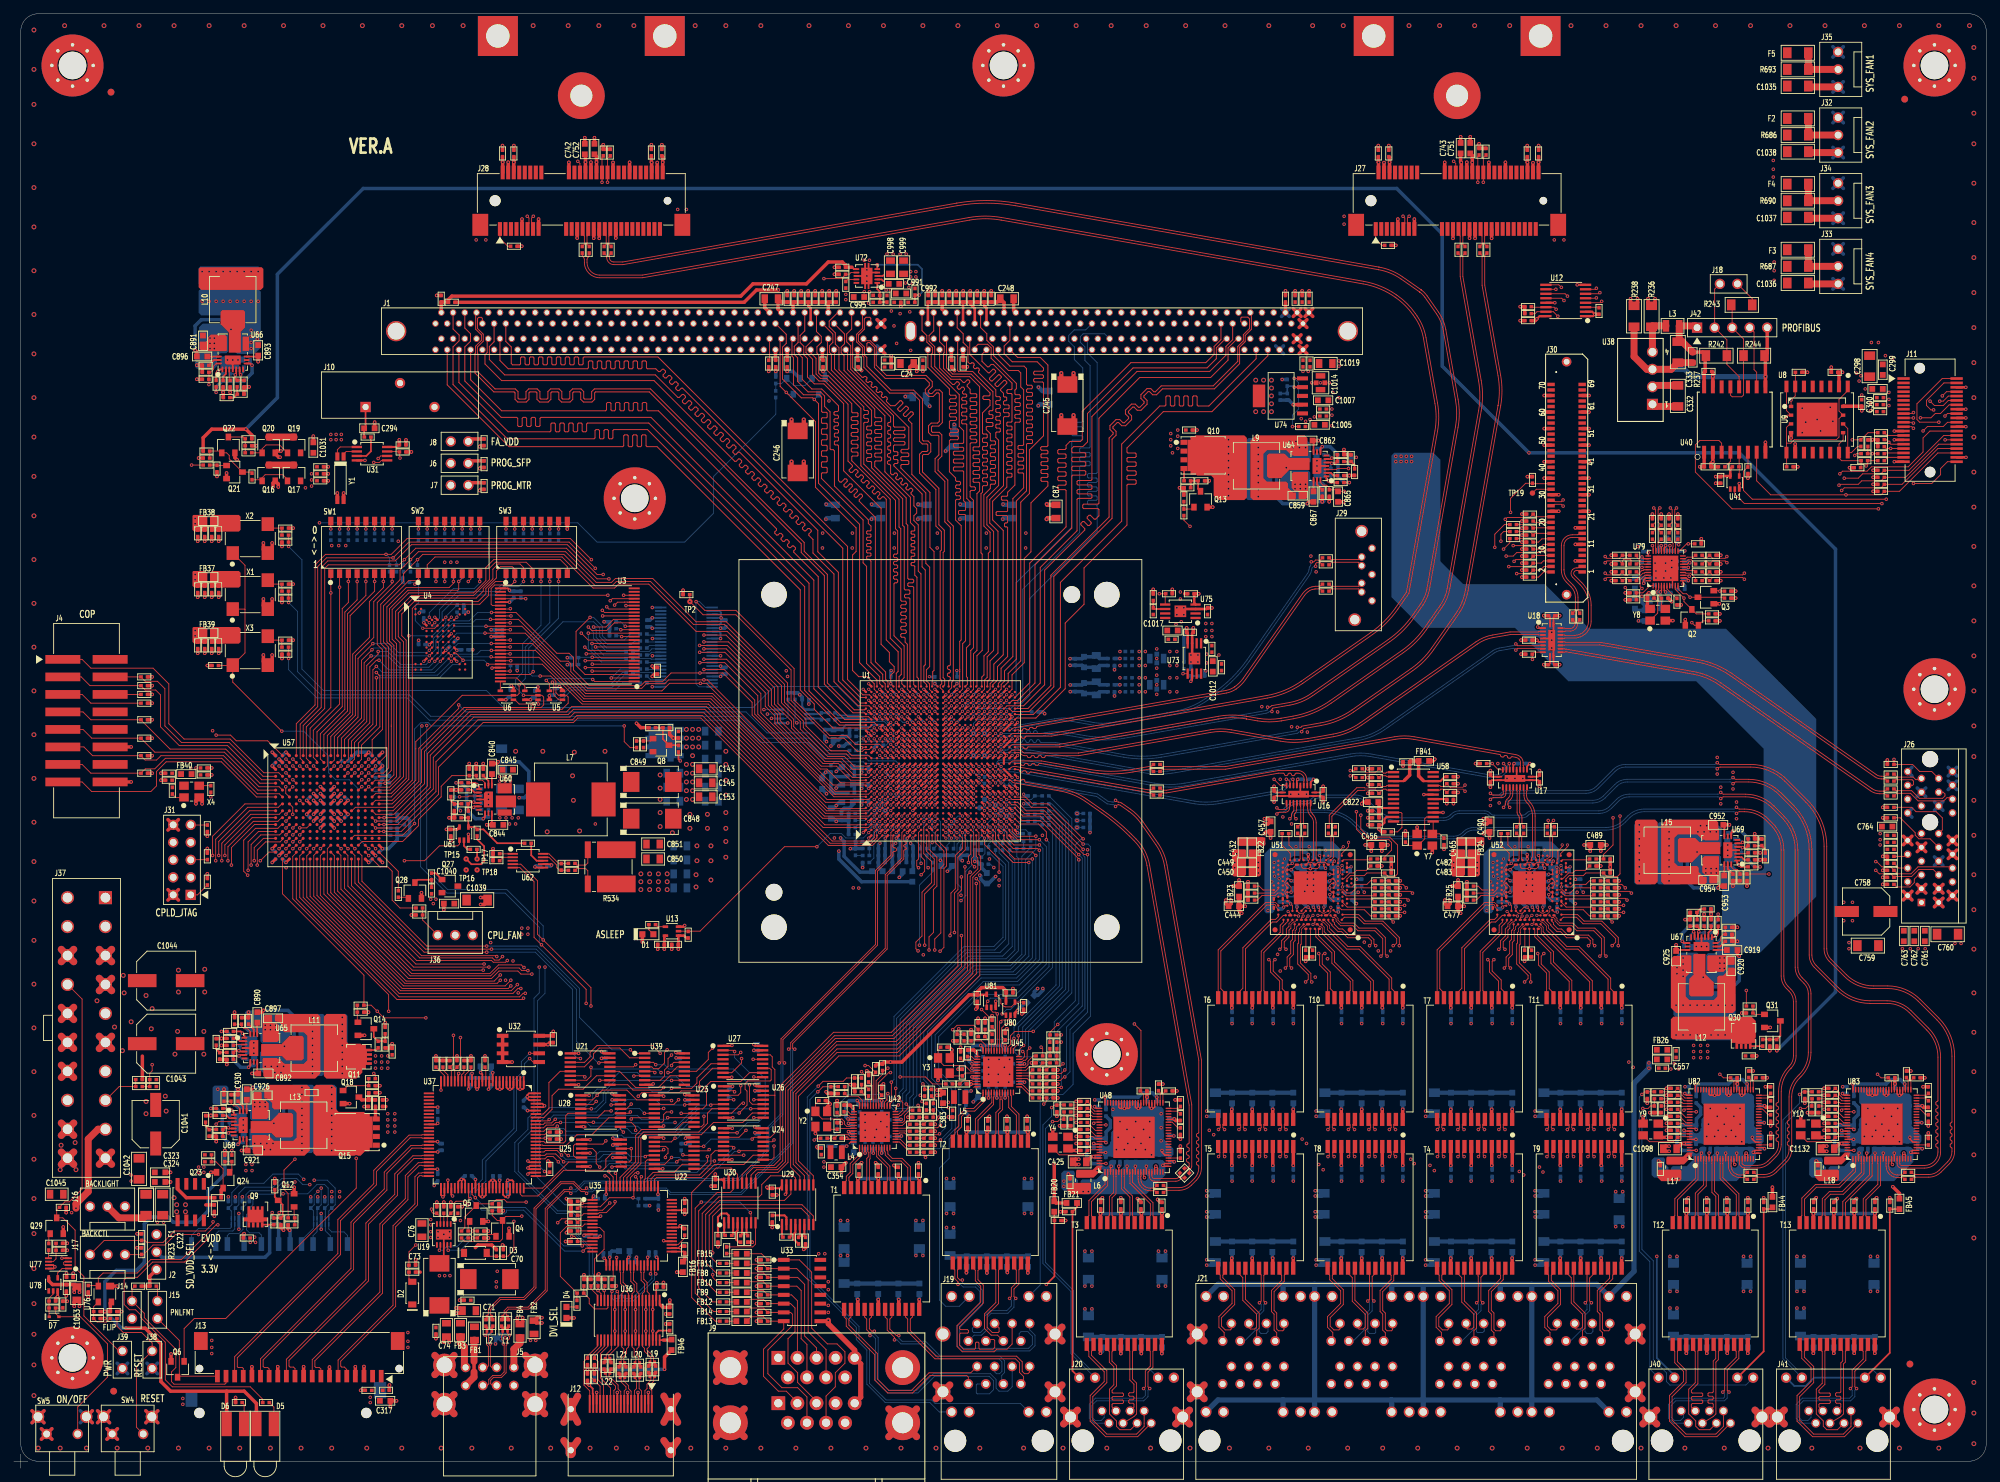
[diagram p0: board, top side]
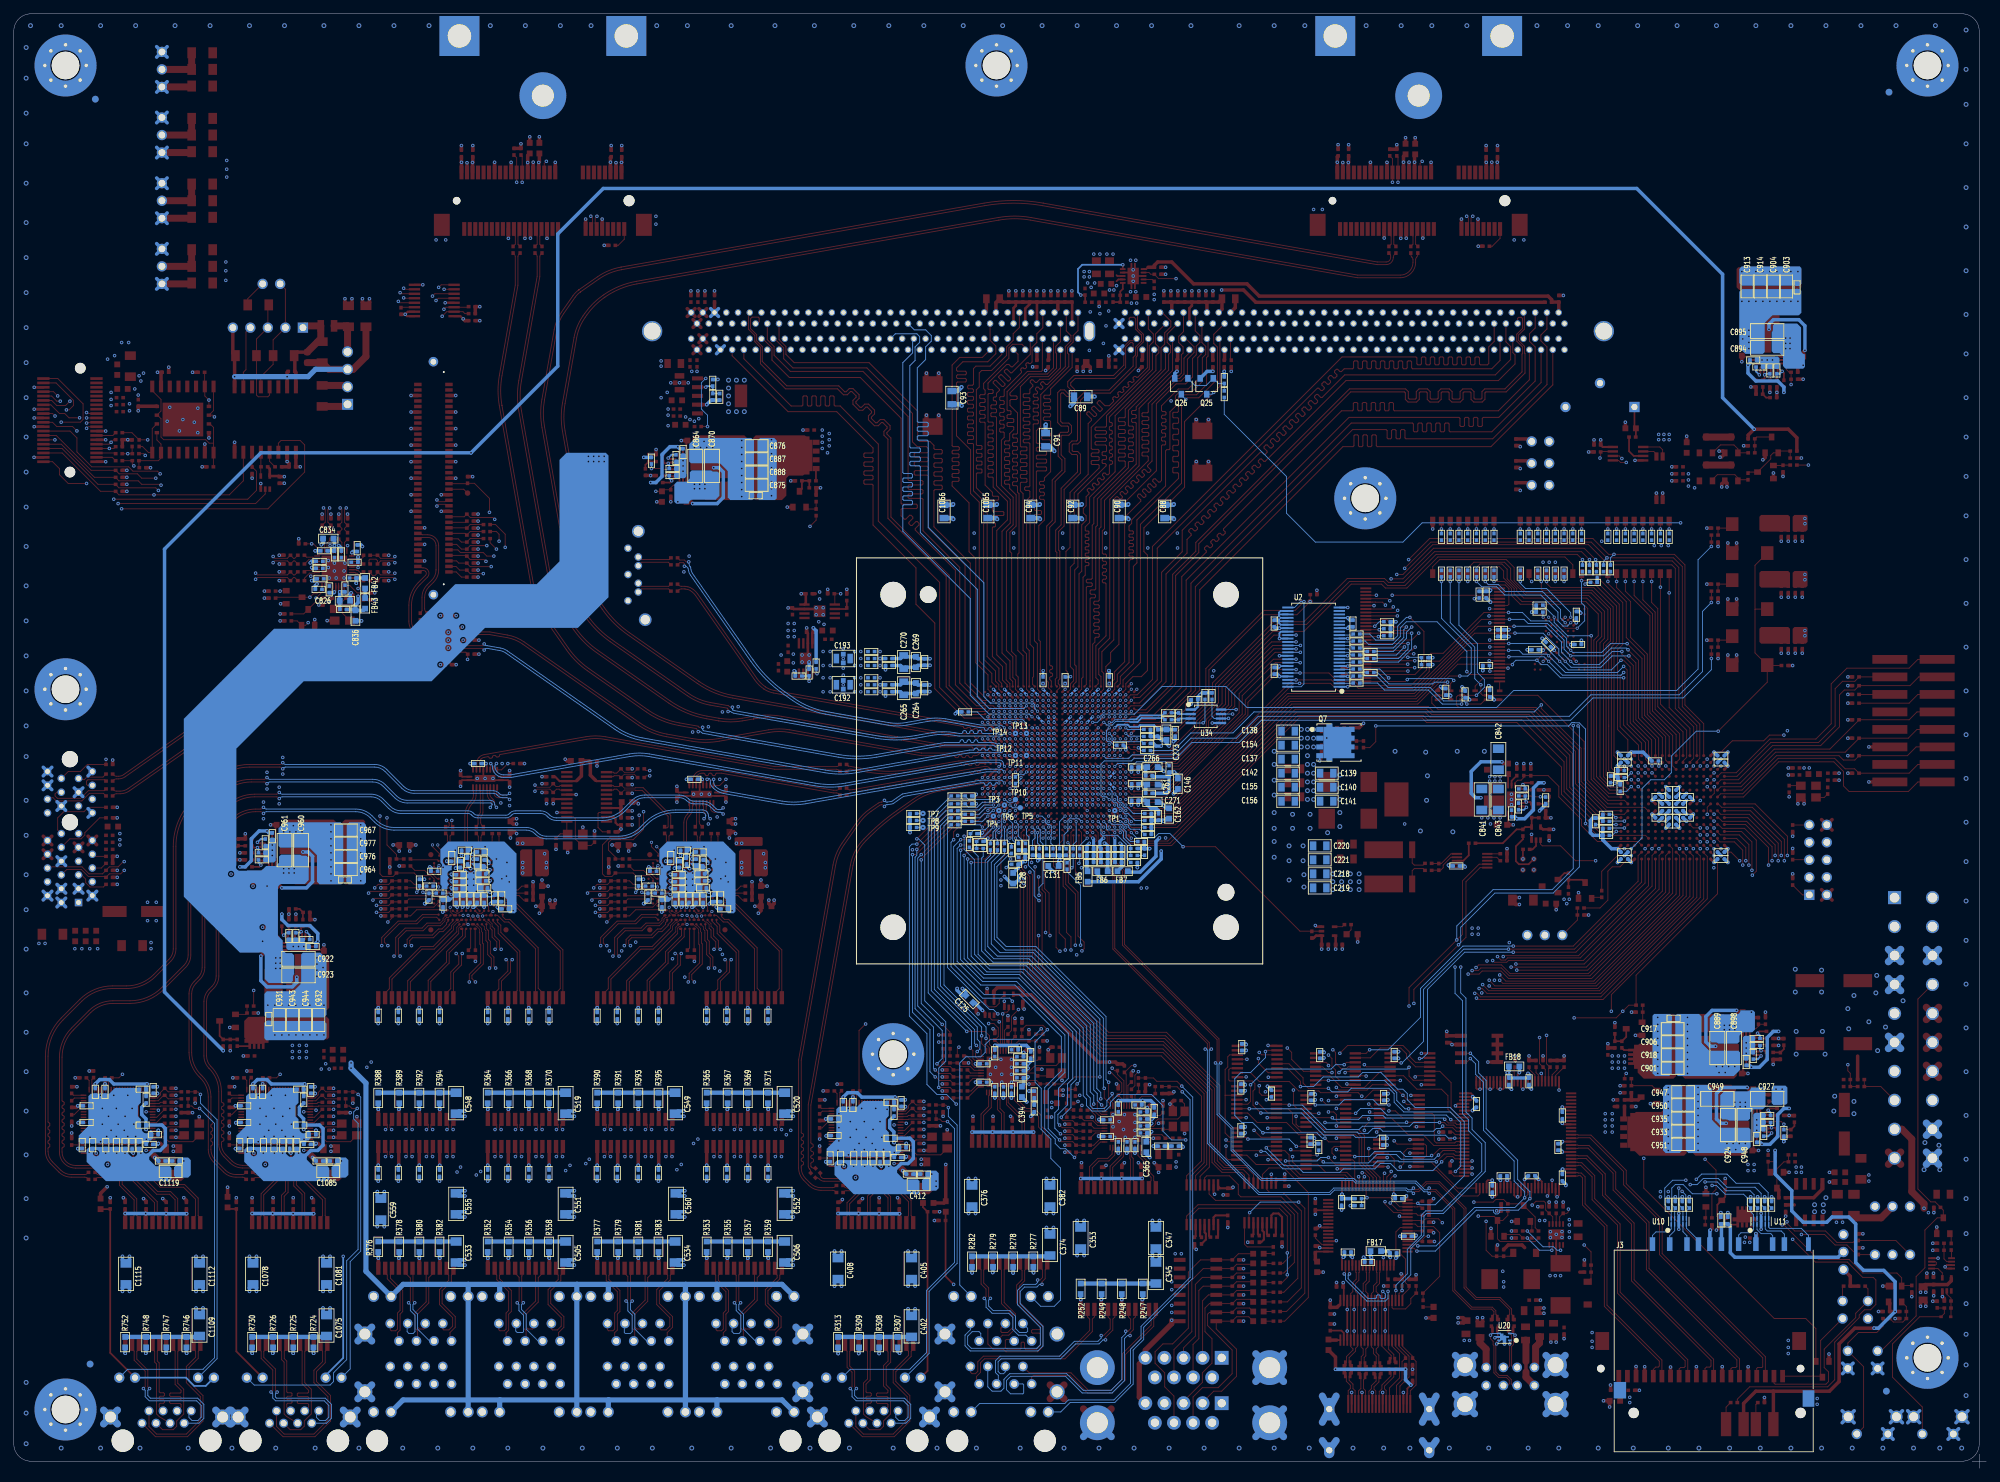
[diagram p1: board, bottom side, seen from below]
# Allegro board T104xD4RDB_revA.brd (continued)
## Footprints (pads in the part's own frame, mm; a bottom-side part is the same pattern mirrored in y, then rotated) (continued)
SO_16L
  rect 1.7x0.6 smd: 1(-4.8,4.445) 2(-4.8,3.175) 3(-4.8,1.905) 4(-4.8,0.635) 5(-4.8,-0.635) 6(-4.8,-1.905) 7(-4.8,-3.175) 8(-4.8,-4.445) 9(4.8,-4.445) 10(4.8,-3.175) 11(4.8,-1.905) 12(4.8,-0.635) 13(4.8,0.635) 14(4.8,1.905) 15(4.8,3.175) 16(4.8,4.445)
SOD123
  rect 0.9x1.2 smd: 1(-1.65,0) 2(1.65,0)
SOD523
  rect 0.5x0.4 smd: 1(-0.7,0) 2(0.7,0)
SOIC16_1P27_7P6X10P5
  rect 1.88x0.584 smd: 1(-4.738,4.445) 2(-4.738,3.175) 3(-4.738,1.905) 4(-4.738,0.635) 5(-4.738,-0.635) 6(-4.738,-1.905) 7(-4.738,-3.175) 8(-4.738,-4.445) 9(4.738,-4.445) 10(4.738,-3.175) 11(4.738,-1.905) 12(4.738,-0.635) 13(4.738,0.635) 14(4.738,1.905) 15(4.738,3.175) 16(4.738,4.445)
SOT23
  rect 0.8x1 smd: 1(-0.95,-1.15) 2(0.95,-1.15) 3(0,1.15)
SOT143
  rect 1.2x1 smd: 1(-0.75,-1.15)
  rect 0.8x1 smd: 2(0.95,-1.15) 3(0.95,1.15) 4(-0.95,1.15)
SOT223_5
  rect 0.6x1.6 smd: 1(-2.54,-3.1) 2(-1.27,-3.1) 3(0,-3.1) 4(1.27,-3.1) 5(2.54,-3.1)
  rect 3.3x1.8 smd: 6(0,3.2)
TP
  round 0.8 smd: 1(0,0)
TSOP1_56
  rect 1.6x0.28 smd: 1(-9.7,6.75) 2(-9.7,6.25) 3(-9.7,5.75) 4(-9.7,5.25) 5(-9.7,4.75) 6(-9.7,4.25) 7(-9.7,3.75) 8(-9.7,3.25) 9(-9.7,2.75) 10(-9.7,2.25) 11(-9.7,1.75) 12(-9.7,1.25) 13(-9.7,0.75) 14(-9.7,0.25) 15(-9.7,-0.25) 16(-9.7,-0.75) 17(-9.7,-1.25) 18(-9.7,-1.75) 19(-9.7,-2.25) 20(-9.7,-2.75) 21(-9.7,-3.25) 22(-9.7,-3.75) 23(-9.7,-4.25) 24(-9.7,-4.75) 25(-9.7,-5.25) 26(-9.7,-5.75) 27(-9.7,-6.25) 28(-9.7,-6.75) 29(9.7,-6.75) 30(9.7,-6.25) 31(9.7,-5.75) 32(9.7,-5.25) 33(9.7,-4.75) 34(9.7,-4.25) 35(9.7,-3.75) 36(9.7,-3.25) 37(9.7,-2.75) 38(9.7,-2.25) 39(9.7,-1.75) 40(9.7,-1.25) 41(9.7,-0.75) 42(9.7,-0.25) 43(9.7,0.25) 44(9.7,0.75) 45(9.7,1.25) 46(9.7,1.75) 47(9.7,2.25) 48(9.7,2.75) 49(9.7,3.25) 50(9.7,3.75) 51(9.7,4.25) 52(9.7,4.75) 53(9.7,5.25) 54(9.7,5.75) 55(9.7,6.25) 56(9.7,6.75)
TSSOP_14
  rect 1.65x0.35 smd: 1(-2.875,1.95) 2(-2.875,1.3) 3(-2.875,0.65) 4(-2.875,0) 5(-2.875,-0.65) 6(-2.875,-1.3) 7(-2.875,-1.95) 8(2.875,-1.95) 9(2.875,-1.3) 10(2.875,-0.65) 11(2.875,0) 12(2.875,0.65) 13(2.875,1.3) 14(2.875,1.95)
TSSOP_16
  rect 1.65x0.35 smd: 1(-2.875,2.275) 2(-2.875,1.625) 3(-2.875,0.975) 4(-2.875,0.325) 5(-2.875,-0.325) 6(-2.875,-0.975) 7(-2.875,-1.625) 8(-2.875,-2.275) 9(2.875,-2.275) 10(2.875,-1.625) 11(2.875,-0.975) 12(2.875,-0.325) 13(2.875,0.325) 14(2.875,0.975) 15(2.875,1.625) 16(2.875,2.275)
TSSOP_24
  rect 1.65x0.35 smd: 1(-2.875,3.575) 2(-2.875,2.925) 3(-2.875,2.275) 4(-2.875,1.625) 5(-2.875,0.975) 6(-2.875,0.325) 7(-2.875,-0.325) 8(-2.875,-0.975) 9(-2.875,-1.625) 10(-2.875,-2.275) 11(-2.875,-2.925) 12(-2.875,-3.575) 13(2.875,-3.575) 14(2.875,-2.925) 15(2.875,-2.275) 16(2.875,-1.625) 17(2.875,-0.975) 18(2.875,-0.325) 19(2.875,0.325) 20(2.875,0.975) 21(2.875,1.625) 22(2.875,2.275) 23(2.875,2.925) 24(2.875,3.575)
TSSOP_38
  rect 1.65x0.28 smd: 1(-2.875,4.5) 2(-2.875,4) 3(-2.875,3.5) 4(-2.875,3) 5(-2.875,2.5) 6(-2.875,2) 7(-2.875,1.5) 8(-2.875,1) 9(-2.875,0.5) 10(-2.875,0) 11(-2.875,-0.5) 12(-2.875,-1) 13(-2.875,-1.5) 14(-2.875,-2) 15(-2.875,-2.5) 16(-2.875,-3) 17(-2.875,-3.5) 18(-2.875,-4) 19(-2.875,-4.5) 20(2.875,-4.5) 21(2.875,-4) 22(2.875,-3.5) 23(2.875,-3) 24(2.875,-2.5) 25(2.875,-2) 26(2.875,-1.5) 27(2.875,-1) 28(2.875,-0.5) 29(2.875,0) 30(2.875,0.5) 31(2.875,1) 32(2.875,1.5) 33(2.875,2) 34(2.875,2.5) 35(2.875,3) 36(2.875,3.5) 37(2.875,4) 38(2.875,4.5)
TSSOP_48W
  rect 1.65x0.28 smd: 1(-3.725,5.75) 2(-3.725,5.25) 3(-3.725,4.75) 4(-3.725,4.25) 5(-3.725,3.75) 6(-3.725,3.25) 7(-3.725,2.75) 8(-3.725,2.25) 9(-3.725,1.75) 10(-3.725,1.25) 11(-3.725,0.75) 12(-3.725,0.25) 13(-3.725,-0.25) 14(-3.725,-0.75) 15(-3.725,-1.25) 16(-3.725,-1.75) 17(-3.725,-2.25) 18(-3.725,-2.75) 19(-3.725,-3.25) 20(-3.725,-3.75) 21(-3.725,-4.25) 22(-3.725,-4.75) 23(-3.725,-5.25) 24(-3.725,-5.75) 25(3.725,-5.75) 26(3.725,-5.25) 27(3.725,-4.75) 28(3.725,-4.25) 29(3.725,-3.75) 30(3.725,-3.25) 31(3.725,-2.75) 32(3.725,-2.25) 33(3.725,-1.75) 34(3.725,-1.25) 35(3.725,-0.75) 36(3.725,-0.25) 37(3.725,0.25) 38(3.725,0.75) 39(3.725,1.25) 40(3.725,1.75) 41(3.725,2.25) 42(3.725,2.75) 43(3.725,3.25) 44(3.725,3.75) 45(3.725,4.25) 46(3.725,4.75) 47(3.725,5.25) 48(3.725,5.75)
TVS_LLP75_6L
  rect 0.55x0.25 smd: 1(-0.775,0.5) 3(-0.775,-0.5) 4(0.775,-0.5) 5(0.775,0) 6(0.775,0.5)
  custom 0.25x0.25 smd: 2(0,0)
TVS_SLP2710P8
  rect 0.2x0.675 smd: 1(-1.1,-0.438) 2(-0.6,-0.438) 3(0.6,-0.438) 4(1.1,-0.438) 5(1.1,0.438) 6(0.6,0.438) 7(-0.6,0.438) 8(-1.1,0.438)
  rect 0.4x1.55 smd: 9(0,0)
U8
  rect 1x0.28 smd: 1(-1.45,0.75) 2(-1.45,0.25) 3(-1.45,-0.25) 4(-1.45,-0.75) 5(1.45,-0.75) 6(1.45,-0.25) 7(1.45,0.25) 8(1.45,0.75)
U8_FL
  rect 0.4x0.76 smd: 1(-0.975,-1.52) 2(-0.325,-1.52) 3(0.325,-1.52) 4(0.975,-1.52)
  custom 0.588x0.588 smd: 5(0,0)
unnamed
  round 3.71 hole 3.71 unplated: (-24.13,24.13) (-24.13,-24.13) (24.13,24.13) (24.13,-24.13)
  round 2.44 hole 2.44 unplated: (-19.05,24.13) (24.13,-19.05)
WSON_8
  rect 0.65x0.5 smd: 1(-3.775,1.905) 2(-3.775,0.635) 3(-3.775,-0.635) 4(-3.775,-1.905) 5(3.775,-1.905) 6(3.775,-0.635) 7(3.775,0.635) 8(3.775,1.905)
  rect 5.9x4.9 smd: 9(0,0)

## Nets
1V0: C449.1 C450.1 C451.1 C452.1 C453.1 C454.1 C455.1 C482.1 C483.1 C484.1 C485.1 C486.1 C487.1 C488.1 C964.1 C966.1 C967.1 C968.1 C976.1 C977.1 FB22.1 FB24.1 L15.2 R619.2 U51.E5(VDD1#E5) U51.E7(VDD1#E7) U51.E10(VDD1#E10) U51.E13(VDD1#E13) U51.E15(VDD1#E15) U51.E17(VDD1#E17) U51.E19(VDD1#E19) U51.E21(VDD1#E21) U51.E23(VDD1#E23) U51.E25(VDD1#E25) U52.E5(VDD1#E5) U52.E7(VDD1#E7) U52.E10(VDD1#E10) U52.E13(VDD1#E13) U52.E15(VDD1#E15) U52.E17(VDD1#E17) U52.E19(VDD1#E19) U52.E21(VDD1#E21) U52.E23(VDD1#E23) U52.E25(VDD1#E25)
1V0_FA_VL: C174.1 J8.1 R173.2 U1.G18(FA_VL)
1V0_USB_SVDD: C95.1 C96.1 C97.1 C98.1 C1138.1 FB5.1 U1.K9(USB_SVDD1) U1.K10(USB_SVDD2)
1V0A_QSG1: C432.1 C433.1 C435.1 C436.1 C437.1 C438.1 C439.1 C440.1 C441.1 FB22.2 U51.E1(VDD1A#E1) U51.E11(VDD1A#E11) U51.E14(VDD1A#E14) U51.E16(VDD1A#E16) U51.E28(VDD1A#E28) U51.E30(VDD1A#E30) U51.E32(VDD1A#E32) U51.E34(VDD1A#E34) U51.E36(VDD1A#E36)
1V0A_QSG2: C465.1 C466.1 C467.1 C468.1 C469.1 C471.1 C472.1 C473.1 C474.1 FB24.2 U52.E1(VDD1A#E1) U52.E11(VDD1A#E11) U52.E14(VDD1A#E14) U52.E16(VDD1A#E16) U52.E28(VDD1A#E28) U52.E30(VDD1A#E30) U52.E32(VDD1A#E32) U52.E34(VDD1A#E34) U52.E36(VDD1A#E36)
1V0S: C192.2 C1012.1 C1013.1 R643.2 U73.7(OUT#7) U73.8(OUT#8)
1V2: C1.1 C2.1 C5.1 C6.1 C7.1 C8.1 C9.1 C10.1 C14.1 C15.1 C17.1 C18.1 C87.1 C88.1 C89.1 C90.1 C91.1 C92.1 C93.1 C94.1 C99.1 C100.1 C101.1 C102.1 C103.1 C104.1 C109.1 C110.1 C111.1 C112.1 C113.1 C114.1 C115.1 C116.1 C117.1 C119.1 C1065.1 C1066.1 Q10.1 Q10.2 Q10.3 R1.1 R3.1 R653.2 U1.AA27(G1VDD17) U1.AD27(G1VDD18) U1.AF27(G1VDD19) U1.D27(G1VDD01) U1.F27(G1VDD02) U1.H27(G1VDD03) U1.K21(G1VDD04) U1.K27(G1VDD05) U1.L21(G1VDD06) U1.M21(G1VDD07) U1.M27(G1VDD08) U1.N21(G1VDD09) U1.P21(G1VDD10) U1.P27(G1VDD11) U1.R21(G1VDD12) U1.T21(G1VDD13) U1.U21(G1VDD14) U1.U27(G1VDD15) U1.W27(G1VDD16)
1V2_SLP: C1.2 C2.2 C5.2 C6.2 C7.2 C8.2 C9.2 C10.2 C14.2 C15.2 C17.2 C18.2 C21.1 C245.1 C246.1 C247.1 C248.1 C249.1 C250.1 C251.1 C252.1 C253.1 C254.1 C255.1 C256.1 C257.1 C258.1 C259.1 C260.1 C871.1 C875.1 C876.1 C878.1 C887.1 C888.1 C991.1 C992.1 J1.59(VDD0) J1.61(VDD1) J1.64(VDD2) J1.67(VDD3) J1.70(VDD4) J1.73(VDD5) J1.76(VDD6) J1.80(VDD7) J1.83(VDD8) J1.85(VDD9) J1.88(VDD10) J1.90(VDD11) J1.92(VDD12) J1.204(VDD13) J1.206(VDD25) J1.209(VDD14) J1.212(VDD15) J1.215(VDD16) J1.217(VDD17) J1.220(VDD18) J1.223(VDD19) J1.226(VDD20) J1.229(VDD21) J1.231(VDD22) J1.233(VDD23) J1.236(VDD24) L9.2 Q10.5 R5.1 R567.2 R636.2 U72.2(VLDOIN)
1V5: C751.1 C752.1 C753.1 C754.1 C755.1 C756.1 C902.1 C903.1 C904.1 C905.1 C913.1 C914.1 J27.6(1.5V#6) J27.28(1.5V#28) J27.48(1.5V#48) J28.6(1.5V#6) J28.28(1.5V#28) J28.48(1.5V#48) L10.2 R582.2
1V05_EC1_AVDD: C354.1 C355.1 C362.1 C363.1 C364.1 L4.2 R267.2 U42.3(AVDD10#3) U42.9(AVDD10#9) U42.40(AVDD10#40)
1V05_EC1_DVDD: C358.1 C359.1 R267.1 U42.28(DVDD10#28) U42.36(DVDD10#36)
1V05_EC2_AVDD: C383.1 C384.1 C391.1 C392.1 C393.1 L5.2 R297.2 U45.3(AVDD10#3) U45.9(AVDD10#9) U45.40(AVDD10#40)
1V05_EC2_DVDD: C387.1 C388.1 R297.1 U45.28(DVDD10#28) U45.36(DVDD10#36)
1V05_SG1_AVDD: C1085.1 C1086.1 C1092.1 C1093.1 C1094.1 C1095.1 C1096.1 C1097.1 L17.2 R745.2 U82.3(AVDD10#3) U82.9(AVDD10#9) U82.12(AVDD10#12) U82.16(AVDD10#16) U82.23(AVDD10#23) U82.24(REGV15) U82.79(AVDD10#79)
1V05_SG1_DVDD: C1087.1 C1088.1 R745.1 U82.47(DVDD10#47) U82.66(DVDD10#66)
1V05_SG2_AVDD: C1119.1 C1120.1 C1126.1 C1127.1 C1128.1 C1129.1 C1130.1 C1131.1 L18.2 R767.2 U83.3(AVDD10#3) U83.9(AVDD10#9) U83.12(AVDD10#12) U83.16(AVDD10#16) U83.23(AVDD10#23) U83.24(REGV15) U83.79(AVDD10#79)
1V05_SG2_DVDD: C1121.1 C1122.1 R767.1 U83.47(DVDD10#47) U83.66(DVDD10#66)
1V05_SG_AVDD: C412.1 C413.1 C419.1 C420.1 C421.1 C422.1 C423.1 C424.1 L6.2 R329.2 U48.3(AVDD10#3) U48.9(AVDD10#9) U48.12(AVDD10#12) U48.16(AVDD10#16) U48.23(AVDD10#23) U48.24(REGV15) U48.79(AVDD10#79)
1V05_SG_DVDD: C414.1 C415.1 R329.1 U48.47(DVDD10#47) U48.66(DVDD10#66)
1V8: C29.1 C30.1 C31.1 C32.1 C33.1 C34.1 C35.1 C36.1 C38.1 C39.1 C40.1 C43.1 C146.1 C147.1 C148.1 C149.1 C150.1 C151.1 C152.1 C183.1 C803.1 C804.1 FB38.1 Q11.1 Q11.2 Q11.3 Q16.2(S) R6.1 R7.1 R8.1 R9.2 R10.2 R11.2 R12.2 R13.1 R14.2 R15.2 R16.1 R17.2 R18.2 R19.2 R20.2 R50.2 R51.2 R52.2 R53.2 R54.2 R55.2 R56.2 R91.2 R111.2 R174.1 R177.1 R181.1 R476.1 R478.1 R480.1 R482.1 R654.2 U1.G9(TH_VDD) U1.J14(OVDD1) U1.J15(OVDD2) U1.J16(OVDD3) U1.J17(OVDD4) U1.J18(OVDD5) U1.J19(OVDD6) U2.7(VCC#7) U2.18(VCC#18) U2.31(VCC#31) U2.42(VCC#42) U3.29(VIO) U4.D3(VCC#D3) U4.G4(VCC#G4) U4.H8(VCC#H8) U4.J6(VCC#J6) U5.5(VCC) U6.5(VCC) U7.5(VCC)
1V8_0641_VDD: C836.1 C837.1 C838.1 FB43.2 R532.1 R533.1 U79.16(VDD1.8#16) U79.31(VDD1.8#31)
1V8_0641_VDDA: C834.1 C835.1 R533.2 U79.26(VDDA1.8)
1V8_0641_VDDIO: C828.1 C829.1 C830.1 C831.1 C832.1 C833.1 FB42.1 U79.5(VDDREF1.8) U79.12(VDDIO#12) U79.17(VDDIO#17) U79.27(VDDIO#27) U79.32(VDDIO#32) U79.39(VDDIO#39)
1V8_0641_VDDXTAL: C826.1 C827.1 R532.2 U79.4(VDDXTAL1.8)
1V8_MTR: C161.1 J7.1 R172.2 U1.F11(PROG_MTR)
1V8_OSC_DDR: C805.1 C806.1 FB38.2 X2.4(VDD)
1V8_OSC_SYS: C800.1 C801.1 FB37.2 X1.4(VDD)
1V8_OSC_USB: C810.1 C811.1 FB39.2 X3.4(VDD)
1V8_SFP: C144.1 J6.1 R171.2 U1.F12(PROG_SFP)
1V8_SLP: C49.1 C162.1 C163.1 C164.1 C170.1 C777.1 C778.1 C779.1 C780.1 C789.1 C790.1 C791.1 C792.1 C793.1 C794.1 C795.1 C796.1 C798.1 C799.1 C808.1 C809.1 C839.1 C901.1 C906.1 C907.1 C908.1 C917.1 C918.1 C1009.1 C1015.1 FB7.2 FB37.1 FB39.1 FB42.2 FB43.1 J6.2 J7.2 L11.2 Q11.5 R78.2 R79.2 R80.2 R81.2 R82.2 R83.2 R90.2 R92.2 R93.2 R94.2 R95.2 R104.1 R105.1 R106.1 R110.2 R180.1 R508.1 R523.1 R525.1 R586.2 U1.J11(O1VDD1) U1.J12(O1VDD2) U1.J13(O1VDD3) U13.1(VCC1) U57.A3(VCCIO2#A3) U57.A14(VCCIO2#A14) U57.C16(VCCIO2#C16) U57.F8(VCCIO2#F8) U57.F9(VCCIO2#F9) U57.H8(VCCINT#H8) U57.H10(VCCINT#H10) U57.H11(VCCIO2#H11) U57.J7(VCCINT#J7) U57.J9(VCCINT#J9) U57.J11(VCCIO2#J11) U57.P16(VCCIO2#P16) U73.1(IN#1) U73.2(IN#2) U75.1(IN#1) U75.2(IN#2) U79.11(VDDDIG1.8)
1V8_USB_OVDD: C120.1 C121.1 C122.1 C123.1 C124.1 FB7.1 U1.J9(USB_OVDD1) U1.J10(USB_OVDD2)
1V35X: C193.1 C1017.1 C1018.1 R175.2 R178.2 R649.2 U75.7(OUT#7) U75.8(OUT#8)
2V5: C125.1 C126.1 C127.1 C385.1 C386.1 C429.1 C430.1 C456.1 C457.1 C458.1 C459.1 C460.1 C461.1 C462.1 C489.1 C490.1 C491.1 C492.1 C493.1 C494.1 C495.1 C556.1 C1102.1 C1103.1 C1136.1 C1137.1 FB23.2 FB25.2 FB26.1 Q30.1 Q30.2 Q30.3 R300.2 R301.2 R302.2 R303.2 R311.1 R312.1 R314.1 R330.2 R333.2 R334.2 R335.2 R336.1 R341.2 R344.2 R345.2 R346.2 R347.1 R718.2 R719.2 R728.1 R729.1 R731.1 R750.1 R751.1 R753.1 U1.V8(LVDD1) U1.W8(LVDD2) U45.15(DVDD33#15) U45.21(DVDD33#21) U48.34(DVDD33#34) U48.40(DVDD33#40) U51.E3(VDD25#E3) U51.E4(VDD25#E4) U51.E6(VDD25#E6) U51.E8(VDD25#E8) U51.E9(VDDMDIO) U51.E12(VDD25#E12) U51.E18(VDD25#E18) U51.E20(VDD25#E20) U51.E22(VDD25#E22) U51.E24(VDD25#E24) U51.E26(VDD25#E26) U52.E3(VDD25#E3) U52.E4(VDD25#E4) U52.E6(VDD25#E6) U52.E8(VDD25#E8) U52.E9(VDDMDIO) U52.E12(VDD25#E12) U52.E18(VDD25#E18) U52.E20(VDD25#E20) U52.E22(VDD25#E22) U52.E24(VDD25#E24) U52.E26(VDD25#E26) U82.34(DVDD33#34) U82.40(DVDD33#40) U83.34(DVDD33#34) U83.40(DVDD33#40)
2V5_LED: C557.1 C558.1 FB26.2 J21.A9 J21.A11 J21.B9 J21.B11 J21.C9 J21.C11 J21.D9 J21.D11 J21.E9 J21.E11 J21.F9 J21.F11 J21.G9 J21.G11 J21.H9(G9) J21.H11(G11)
2V5_SLP: C128.1 C129.1 C130.1 C356.1 C357.1 C931.1 C932.1 C934.1 C937.1 C943.1 C944.1 C1067.1 C1068.1 L12.2 Q30.5 R84.2 R85.2 R86.2 R87.2 R139.1 R140.1 R270.2 R271.2 R272.2 R273.2 R602.2 U1.T8(L1VDD1) U1.U8(L1VDD2) U42.15(DVDD33#15) U42.21(DVDD33#21) U80.5(VCC) U81.5(VCC)
2V5_VPP: C1007.1 C1008.1 C1011.2 C1014.1 R644.2 U74.2(OUT)
2V5A_QSG1: C444.1 C445.1 C446.1 C447.1 C448.1 FB23.1 U51.E27(VDD25A#E27) U51.E29(VDD25A#E29) U51.E31(VDD25A#E31) U51.E33(VDD25A#E33) U51.E35(VDD25A#E35) U51.E37(VDD25A#E37)
2V5A_QSG2: C477.1 C478.1 C479.1 C480.1 C481.1 FB25.1 U52.E27(VDD25A#E27) U52.E29(VDD25A#E29) U52.E31(VDD25A#E31) U52.E33(VDD25A#E33) U52.E35(VDD25A#E35) U52.E37(VDD25A#E37)
3V3: C41.1 C42.1 C44.1 C45.1 C48.1 C61.1 C62.1 C63.1 C64.1 C65.1 C66.1 C67.1 C68.1 C69.1 C79.1 C80.1 C81.1 C82.1 C83.1 C84.1 C85.1 C86.1 C131.1 C132.1 C133.1 C134.1 C135.1 C276.1 C285.1 C293.1 C300.1 C301.1 C302.1 C303.1 C307.1 C309.1 C310.1 C311.1 C312.1 C313.1 C314.1 C317.1 C318.1 C319.1 C325.1 C326.1 C327.1 C328.1 C329.1 C330.1 C331.1 C336.1 C337.1 C338.1 C389.1 C390.1 C394.1 C395.1 C396.1 C416.1 C417.1 C418.1 C425.1 C426.1 C427.1 C428.1 C742.1 C743.1 C744.1 C745.1 C746.1 C747.1 C764.1 C765.1 C766.1 C767.1 C818.1 C819.1 C1089.1 C1090.1 C1091.1 C1098.1 C1099.1 C1100.1 C1101.1 C1123.1 C1124.1 C1125.1 C1132.1 C1133.1 C1134.1 C1135.1 FB16.1 FB17.1 FB18.1 FB20.1 FB21.1 FB41.1 FB44.1 FB45.1 J2.1 J11.10 J11.12 J11.14 J11.16 J13.1 J13.2 J26.A9(+3V3#A9) J26.A10(+3V3#A10) J26.B8(+3V3#B8) J26.B10(+3V3AUX) J27.2(3.3V#2) J27.24(3.3VAUX) J27.52(3.3V#52) J28.2(3.3V#2) J28.24(3.3VAUX) J28.52(3.3V#52) Q2.1(G) Q3.1(G) Q15.1 Q15.2 Q15.3 Q20.2(S) R57.2 R58.2 R59.2 R60.2 R62.2 R63.2 R74.2 R75.2 R88.2 R89.2 R98.2 R99.2 R100.2 R101.1 R102.2 R103.1 R107.1 R108.1 R109.1 R196.1 R197.1 R198.1 R199.1 R205.2 R206.2 R207.2 R208.2 R214.1 R216.1 R217.1 R221.2 R222.2 R224.1 R226.1 R227.2 R228.1 R229.1 R230.1 R231.1 R232.1 R241.2 R246.2 R293.1 R295.1 R304.2 R306.2 R318.2 R321.1 R324.1 R325.1 R442.2 R443.2 R445.2 R446.2 R448.2 R449.2 R450.2 R451.2 R452.2 R453.2 R454.2 R455.2 R493.1 R498.1 R667.2 R735.2 R736.1 R740.1 R741.1 R757.2 R758.1 R760.1 R762.1 R763.1 U1.M8(CVDD1) U1.N8(DVDD1) U1.P8(DVDD2) U1.R8(DVDD3) U3.43(VCC) U8.2(VCC) U9.8(VCC) U12.1(A0) U12.2(A1) U12.13(A2) U12.16(VDD) U16.1(VDD#1) U16.6(VDD#6) U16.10(VDD#10) U17.1(VDD#1) U17.6(VDD#6) U17.10(VDD#10) U18.1(VDD#1) U18.6(VDD#6) U18.10(VDD#10) U21.16(VCC) U22.16(VCC) U23.16(VCC) U24.16(VCC) U25.14(VCC) U26.16(VCC) U27.16(VCC) U28.16(VCC) U29.16(VCC) U30.16(VCC) U32.8(VCC) U35.1(DVDD#1) U35.12(DVDD#12) U35.23(TVDD#23) U35.29(TVDD#29) U35.45(DVDDV) U35.49(DVDD#49) U36.2(LV_SUPPLY) U37.13(PLLSEL) U37.30(LVDSVCC#30) U37.40(LVDSVCC#40) U37.48(LVDSVCC#48) U37.53(VCC) U37.61(I2CSEL) U37.68(I2CVCC) U37.70(VCC3V#70) U37.72(TST1) U37.78(VREF) U37.79(VCC3V#79) U37.95(VCC3V#95) U39.16(VCC) U40.1(VCC1) U41.5(VCC) U45.6(AVDD33#6) U45.37(DVDD33#37) U45.41(AVDD33#41) U45.44(VDDREG#44) U45.45(VDDREG#45) U48.6(AVDD33#6) U48.25(AVDD33#25) U48.51(DVDD33#51) U48.67(DVDD33#67) U48.80(AVDD33#80) U48.84(VDDREG#84) U48.85(VDDREG#85) U58.11(VCC#11) U58.18(VCC#18) U82.6(AVDD33#6) U82.25(AVDD33#25) U82.51(DVDD33#51) U82.67(DVDD33#67) U82.80(AVDD33#80) U82.84(VDDREG#84) U82.85(VDDREG#85) U83.6(AVDD33#6) U83.25(AVDD33#25) U83.51(DVDD33#51) U83.67(DVDD33#67) U83.80(AVDD33#80) U83.84(VDDREG#84) U83.85(VDDREG#85)
3V3_DFP_PLLVCC: C320.1 C321.1 FB18.2 U37.10(PLLVCC#10) U37.16(PLLVCC#16)
3V3_DVI_AVDD: C316.1 FB17.2 U35.18(AVDD)
3V3_DVI_VDD: C315.1 FB16.2 U35.33(VDD)
3V3_OSC_CPLD: C814.1 C815.1 FB40.2 R491.1 X4.4(VDD)
3V3_PGOOD: R604.2 U57.L1(IO_B1_L1) U68.3(PGOOD)
3V3_SLP: C23.1 C50.1 C295.1 C297.1 C360.1 C361.1 C365.1 C366.1 C367.1 C781.1 C782.1 C783.1 C784.1 C785.1 C786.1 C787.1 C788.1 C812.1 C813.1 C856.1 C858.1 C933.1 C935.1 C936.1 C938.1 C947.1 C950.1 C951.1 C995.1 C1005.1 C1006.1 C1010.1 C1016.1 C1047.1 D5.2 D6.2 FB6.2 FB40.1 J1.139(SA0) J1.284(VDDSPD) J31.4 L13.2 Q15.5 R96.2 R97.2 R116.2 R117.2 R118.1 R119.1 R120.1 R121.1 R122.1 R123.1 R149.2 R150.2 R152.2 R153.2 R190.2 R192.2 R195.2 R263.1 R265.1 R276.2 R456.2 R457.2 R458.2 R459.2 R460.2 R461.2 R462.2 R463.2 R464.2 R465.2 R466.2 R471.1 R472.1 R538.1 R539.1 R565.1 R568.1 R600.2 R604.1 R641.2 R642.2 R645.2 R648.2 R650.2 R682.1 R695.2 R697.2 U13.5(VCC) U31.8(VCC) U34.1(VDD) U42.6(AVDD33#6) U42.37(DVDD33#37) U42.41(AVDD33#41) U42.44(VDDREG#44) U42.45(VDDREG#45) U57.C1(VCCIO1#C1) U57.H6(VCCIO1#H6) U57.J6(VCCIO1#J6) U57.L8(VCCIO1#L8) U57.L9(VCCIO1#L9) U57.P1(VCCIO1#P1) U57.T3(VCCIO1#T3) U57.T14(VCCIO1#T14) U61.5(VCC) U62.6(VS) U72.10(VIN) U73.4(BIAS) U74.1(IN) U75.4(BIAS) U76.4(VCC)
3V3_USB_HVDD: C105.1 C106.1 C107.1 C108.1 C118.1 FB6.1 U1.J8(USB_HVDD1) U1.K8(USB_HVDD2)
3V3A_843004: C822.1 C823.1 R498.2 U58.9(VCCA)
3V3O_843004: C820.1 C821.1 FB41.2 U58.3(VCCO#3) U58.22(VCCO#22)
5V0: C308.1 C332.1 Q9.1 Q9.2 Q9.3 R236.1 R652.2 U36.1(5V_SUPPLY) U38.2(+VIN)
5V0_HDMI: C305.1 FB46.2 J12.18(+5V) R203.2 R204.2
5V0_SB: C1051.1 C1052.1 C1053.1 J37.9(+5VSB) R702.2 R703.2 R707.1 U77.7(P\R\E\) U77.8(VCC) U78.5(VCC)
5V0_SLP: C76.1 C77.1 C841.1 C842.1 C843.1 C844.1 C845.1 C859.2 C862.2 C864.1 C870.1 C889.1 C891.2 C892.2 C893.2 C894.1 C895.1 C897.2 C898.1 C920.2 C921.2 C922.1 C923.1 C924.1 C925.2 C926.2 C927.1 C948.1 C949.1 C952.2 C954.2 C960.1 C961.1 C1043.1 C1044.1 C1045.1 J37.4(+5VDC#4) J37.6(+5VDC#6) J37.19(+5VDC#19) J37.20(+5VDC#20) Q9.5 R535.1 R558.1 R575.1 R576.1 R579.1 R581.1 R583.1 R585.1 R593.1 R594.1 R596.1 R598.1 R601.1 R611.1 R615.1 R618.1 R698.2 U19.1(INA) U19.5(INB) U20.5 U60.10(VCC) U60.13(VIN) U64.10(VCC) U64.13(VIN) U65.10(VCC) U65.13(VIN) U66.10(VCC) U66.13(VIN) U67.10(VCC) U67.13(VIN) U68.10(VCC) U68.13(VIN) U69.10(VCC) U69.13(VIN)
5V0_USB1: C70.1 C71.1 C72.1 D3.1 FB1.2 R158.2 U19.10(OUTA)
5V0_USB2: C73.1 C74.1 C75.1 D2.1 FB3.2 R154.2 U19.6(OUTB)
12V: C298.1 C299.1 C322.1 C323.1 C324.1 C758.1 C759.1 C760.1 C761.1 C762.1 C763.1 C1035.1 C1036.1 C1037.1 C1038.1 F1.1 F2.1 F3.1 F4.1 F5.1 J11.2 J11.4 J11.6 J26.A2(+12V#A2) J26.A3(+12V#A3) J26.B1(+12V#B1) J26.B2(+12V#B2) J26.B3(+12V#B3) Q23.5 Q23.6 Q23.7 Q23.8 R233.1 R679.2 R686.1 R687.1 R690.1 R693.1
12V_SLP: C1034.1 C1041.1 C1042.1 J37.10(+12VDC) Q23.1 Q23.2 Q23.3 Q27.2(S) R549.2 R658.1 R659.1 R660.1 R669.1 R675.1 R676.2 R681.1 R691.2 R721.1
-5VDC: J37.18(-5VDC)
-12VDC: J37.12(-12VDC)
AGND_SD1_PLL1: C263.2 C264.2 C265.2 R176.1 U1.AA16(AGND_SD1_PLL1)
AGND_SD1_PLL2: C268.2 C269.2 C270.2 R179.1 U1.AA20(AGND_SD1_PLL2)
AVDD_CGA1: C261.1 C262.1 R174.2 U1.G11(AVDD_CGA1)
AVDD_CGA2: C266.1 C267.1 R177.2 U1.G12(AVDD_CGA2)
AVDD_DDR1: C273.1 C274.1 R181.2 U1.E20(AVDD_D1)
AVDD_PLAT: C271.1 C272.1 R180.2 U1.G10(AVDD_PLAT)
AVDD_SD1_PLL1: C263.1 C264.1 C265.1 R175.1 U1.AB16(AVDD_SD1_PLL1)
AVDD_SD1_PLL2: C268.1 C269.1 C270.1 R178.1 U1.AB20(AVDD_SD1_PLL2)
GND: C22.2 C23.2 C24.2 C25.2 C26.2 C27.2 C28.2 C29.2 C30.2 C31.2 C32.2 C33.2 C34.2 C35.2 C36.2 C38.2 C39.2 C40.2 C41.2 C42.2 C43.2 C44.2 C45.2 C46.2 C47.2 C48.2 C49.2 C50.2 C51.1 C52.2 C61.2 C62.2 C63.2 C64.2 C65.2 C66.2 C67.2 C68.2 C69.2 C70.2 C71.2 C72.2 C73.2 C74.2 C75.2 C76.2 C77.2 C79.2 C80.2 C81.2 C82.2 C83.2 C84.2 C85.2 C86.2 C87.2 C88.2 C89.2 C90.2 C91.2 C92.2 C93.2 C94.2 C95.2 C96.2 C97.2 C98.2 C99.2 C100.2 C101.2 C102.2 C103.2 C104.2 C105.2 C106.2 C107.2 C108.2 C109.2 C110.2 C111.2 C112.2 C113.2 C114.2 C115.2 C116.2 C117.2 C118.2 C119.2 C120.2 C121.2 C122.2 C123.2 C124.2 C125.2 C126.2 C127.2 C128.2 C129.2 C130.2 C131.2 C132.2 C133.2 C134.2 C135.2 C136.2 C137.2 C138.2 C139.2 C140.2 C141.2 C142.2 C143.2 C144.2 C145.2 C146.2 C147.2 C148.2 C149.2 C150.2 C151.2 C152.2 C153.2 C154.2 C155.2 C156.2 C161.2 C162.2 C163.2 C164.2 C165.2 C166.2 C167.2 C168.2 C169.2 C170.2 C171.2 C172.2 C173.2 C174.2 C175.2 C176.2 C177.2 C178.2 C179.2 C180.2 C181.2 C182.2 C183.2 C184.2 C185.2 C186.2 C187.2 C188.2 C189.2 C190.2 C191.2 C192.3 C192.4 C193.3 C193.4 C194.2 C195.2 C196.2 C197.2 C198.2 C199.2 C200.2 C201.2 C202.2 C203.2 C204.2 C205.2 C206.2 C207.2 C208.2 C210.2 C211.2 C212.2 C213.2 C214.2 C215.2 C216.2 C217.2 C218.2 C219.2 C220.2 C221.2 C226.2 C227.2 C228.2 C229.2 C230.2 C231.2 C232.2 C233.2 C234.2 C237.2 C238.2 C239.2 C240.2 C241.2 C242.2 C243.2 C244.2 C245.2 C246.2 C247.2 C248.2 C249.2 C250.2 C251.2 C252.2 C253.2 C254.2 C255.2 C256.2 C257.2 C258.2 C259.2 C260.2 C261.2 C262.2 C266.2 C267.2 C271.2 C272.2 C273.2 C274.2 C276.2 C277.2 C279.2 C280.2 C281.2 C282.2 C283.2 C285.2 C287.2 C288.2 C289.2 C290.2 C291.2 C292.2 C293.2 C294.2 C295.2 C297.2 C298.2 C299.2 C300.2 C301.2 C302.2 C303.2 C304.2 C305.2 C306.1 C307.2 C308.2 C309.2 C310.2 C311.2 C312.2 C313.2 C314.2 C315.2 C316.2 C317.2 C318.2 C319.2 C320.2 C321.2 C322.2 C323.2 C324.2 C325.2 C326.2 C327.2 C328.2 C329.2 C330.2 C331.2 C332.2 C336.2 C337.2 C338.2 C339.1 C341.1 C342.1 C343.1 C344.1 C346.2 C347.1 C348.2 C349.2 C350.2 C351.2 C352.2 C353.1 C354.2 C355.2 C356.2 C357.2 C358.2 C359.2 C360.2 C361.2 C362.2 C363.2 C364.2 C365.2 C366.2 C367.2 C368.1 C369.2 C370.1 C371.1 C372.1 C373.1 C375.2 C376.1 C377.2 C378.2 C379.2 C380.2 C381.2 C382.1 C383.2 C384.2 C385.2 C386.2 C387.2 C388.2 C389.2 C390.2 C391.2 C392.2 C393.2 C394.2 C395.2 C396.2 C397.1 C398.2 C399.1 C400.1 C401.1 C405.1 C406.2 C407.2 C408.1 C409.2 C410.2 C411.2 C412.2 C413.2 C414.2 C415.2 C416.2 C417.2 C418.2 C419.2 C420.2 C421.2 C422.2 C423.2 C424.2 C425.2 C426.2 C427.2 C428.2 C429.2 C430.2 C432.2 C433.2 C435.2 C436.2 C437.2 C438.2 C439.2 C440.2 C441.2 C444.2 C445.2 C446.2 C447.2 C448.2 C449.2 C450.2 C451.2 C452.2 C453.2 C454.2 C455.2 C456.2 C457.2 C458.2 C459.2 C460.2 C461.2 C462.2 C463.2 C465.2 C466.2 C467.2 C468.2 C469.2 C471.2 C472.2 C473.2 C474.2 C477.2 C478.2 C479.2 C480.2 C481.2 C482.2 C483.2 C484.2 C485.2 C486.2 C487.2 C488.2 C489.2 C490.2 C491.2 C492.2 C493.2 C494.2 C495.2 C496.2 C497.1 C498.1 C499.1 C500.1 C501.1 C502.1 C503.1 C504.1 C507.1 C508.1 C509.1 C510.1 C511.1 C512.1 C513.1 C514.1 C515.1 C516.1 C517.1 C518.1 C521.1 C522.1 C523.1 C524.1 C525.1 C526.1 C527.1 C528.1 C529.1 C530.1 C531.1 C532.1 C535.1 C536.1 C537.1 C538.1 C539.1 C540.1 C541.1 C542.1 C543.1 C544.1 C545.1 C546.1 C547.1 C550.1 C551.1 C552.1 C553.1 C554.1 C555.1 C556.2 C557.2 C558.2 C559.1 C560.1 C742.2 C743.2 C744.2 C745.2 C746.2 C747.2 C751.2 C752.2 C753.2 C754.2 C755.2 C756.2 C758.2 C759.2 C760.2 C761.2 C762.2 C763.2 C764.2 C765.2 C766.2 C767.2 C777.2 C778.2 C779.2 C780.2 C781.2 C782.2 C783.2 C784.2 C785.2 C786.2 C787.2 C788.2 C789.2 C790.2 C791.2 C792.2 C793.2 C794.2 C795.2 C796.2 C797.2 C798.2 C799.2 C800.2 C801.2 C802.2 C803.2 C804.2 C805.2 C806.2 C807.2 C808.2 C809.2 C810.2 C811.2 C812.2 C813.2 C814.2 C815.2 C816.2 C817.2 C818.2 C819.2 C820.2 C821.2 C822.2 C823.2 C824.2 C825.2 C826.2 C827.2 C828.2 C829.2 C830.2 C831.2 C832.2 C833.2 C834.2 C835.2 C836.2 C837.2 C838.2 C839.2 C841.2 C842.2 C843.2 C844.2 C845.2 C846.1 C848.2 C849.2 C850.2 C851.2 C854.2 C855.2 C856.2 C857.2 C858.2 C859.1 C862.1 C864.2 C865.1 C870.2 C871.2 C875.2 C876.2 C885.2 C886.2 C887.2 C888.2 C889.2 C891.1 C892.1 C893.1 C894.2 C895.2 C897.1 C898.2 C899.1 C900.1 C901.2 C903.2 C904.2 C905.2 C906.2 C907.2 C911.2 C912.2 C913.2 C914.2 C915.2 C916.2 C917.2 C918.2 C920.1 C921.1 C922.2 C923.2 C924.2 C925.1 C926.1 C927.2 C928.1 C929.1 C931.2 C932.2 C933.2 C934.2 C935.2 C936.2 C941.2 C942.2 C943.2 C944.2 C945.2 C946.2 C947.2 C948.2 C949.2 C950.2 C951.2 C952.1 C954.1 C957.1 C960.2 C961.2 C964.2 C967.2 C968.2 C974.2 C975.2 C976.2 C977.2 C991.2 C992.2 C995.2 C996.2 C997.2 C998.2 C999.2 C1004.2 C1005.2 C1006.2 C1007.2 C1008.2 C1009.2 C1010.2 C1012.2 C1013.2 C1014.3 C1014.4 C1015.2 C1016.2 C1017.2 C1018.2 C1019.2 C1020.2 C1021.2 C1022.2 C1023.2 C1024.2 C1025.1 C1026.1 C1027.1 C1028.1 C1029.1 C1030.2 C1031.2 C1032.2 C1033.2 C1035.2 C1036.2 C1037.2 C1038.2 C1039.2 C1040.2 C1041.2 C1042.2 C1043.2 C1044.2 C1045.2 C1046.2 C1047.2 C1048.2 C1049.2 C1050.2 C1051.2 C1052.2 C1053.2 C1065.2 C1066.2 C1067.2 C1068.2 C1069.1 C1070.1 C1071.2 C1072.1 C1073.1 C1074.1 C1078.1 C1079.2 C1080.2 C1081.1 C1082.2 C1083.2 C1084.2 C1085.2 C1086.2 C1087.2 C1088.2 C1089.2 C1090.2 C1091.2 C1092.2 C1093.2 C1094.2 C1095.2 C1096.2 C1097.2 C1098.2 C1099.2 C1100.2 C1101.2 C1102.2 C1103.2 C1104.1 C1105.2 C1106.1 C1107.1 C1108.1 C1112.1 C1113.2 C1114.2 C1115.1 C1116.2 C1117.2 C1118.2 C1119.2 C1120.2 C1121.2 C1122.2 C1123.2 C1124.2 C1125.2 C1126.2 C1127.2 C1128.2 C1129.2 C1130.2 C1131.2 C1132.2 C1133.2 C1134.2 C1135.2 C1136.2 C1137.2 C1138.2 D1.1 D4.1 FB2.2 FB4.2 J1.2(GND1) J1.4(GND2) J1.6(GND3) J1.9(GND4) J1.11(GND5) J1.13(GND6) J1.15(GND7) J1.17(GND8) J1.20(GND9) J1.22(GND10) J1.24(GND11) J1.26(GND12) J1.28(GND13) J1.31(GND14) J1.33(GND15) J1.35(GND16) J1.37(GND17) J1.39(GND18) J1.42(GND19) J1.44(GND20) J1.46(GND21) J1.48(GND22) J1.50(GND23) J1.53(GND24) J1.55(GND25) J1.57(GND26) J1.94(GND27) J1.96(GND0) J1.98(GND28) J1.101(GND29) J1.103(GND30) J1.105(GND31) J1.107(GND32) J1.109(GND33) J1.112(GND34) J1.114(GND35) J1.116(GND36) J1.118(GND37) J1.120(GND38) J1.123(GND39) J1.125(GND40) J1.127(GND41) J1.129(GND42) J1.131(GND43) J1.134(GND44) J1.136(GND45) J1.138(GND46) J1.140(SA1) J1.147(GND47) J1.149(GND48) J1.151(GND49) J1.154(GND50) J1.156(GND51) J1.158(GND52) J1.160(GND53) J1.162(GND54) J1.165(GND55) J1.167(GND56) J1.169(GND57) J1.171(GND58) J1.173(GND59) J1.176(GND60) J1.178(GND61) J1.180(GND62) J1.182(GND63) J1.184(GND64) J1.187(GND65) J1.189(GND66) J1.191(GND67) J1.193(GND68) J1.195(GND69) J1.198(GND70) J1.200(GND71) J1.202(GND72) J1.238(SA2) J1.239(GND73) J1.241(GND74) J1.243(GND75) J1.246(GND76) J1.248(GND77) J1.250(GND78) J1.252(GND79) J1.254(GND80) J1.257(GND81) J1.259(GND82) J1.261(GND83) J1.263(GND84) J1.265(GND85) J1.268(GND86) J1.270(GND87) J1.272(GND88) J1.274(GND89) J1.276(GND90) J1.279(GND91) J1.281(GND92) J1.283(GND93) J3.3(VSS#3) J3.6(VSS#6) J3.12(COM1) J3.13(COM2) J4.12 J4.16 J9.5 J9.15 J10.2 J11.5 J11.15 J11.19 J11.23 J11.26 J11.30 J11.37 J11.40 J12.2(D2 SHIELD) J12.5(D1 SHIELD) J12.8(D0 SHIELD) J12.11(CK SHIELD) J12.17(GND) J13.3 J13.4 J13.7 J13.10 J13.13 J13.16 J13.21 J13.22 J14.2 J16.1 J16.3 J17.2 J19.A12 J19.B10 J19.B12 J20.12 J26.A1(P\R\S\N\T\1\) J26.A4(GND#A4) J26.A12(GND#A12) J26.A15(GND#A15) J26.A18(GND#A18) J26.B4(GND#B4) J26.B7(GND#B7) J26.B13(GND#B13) J26.B16(GND#B16) J26.B18(GND#B18) J27.4(GND#4) J27.9(GND#9) J27.15(GND#15) J27.18(GND#18) J27.21(GND#21) J27.26(GND#26) J27.27(GND#27) J27.29(GND#29) J27.34(GND#34) J27.35(GND#35) J27.40(GND#40) J27.50(GND#50) J27.53(MS1) J27.54(MS2) J28.4(GND#4) J28.9(GND#9) J28.15(GND#15) J28.18(GND#18) J28.21(GND#21) J28.26(GND#26) J28.27(GND#27) J28.29(GND#29) J28.34(GND#34) J28.35(GND#35) J28.40(GND#40) J28.50(GND#50) J28.53(MS1) J28.54(MS2) J29.1(GND#1) J29.4(GND#4) J29.7(GND#7) J29.8(MH1) J29.9(MH2) J30.5(GND1) J30.11(GND2) J30.17(GND3) J30.23(GND4) J30.24(GND5) J30.29(GND6) J30.30(GND7) J30.35(GND8) J30.36(GND9) J30.41(GND10) J30.42(GND11) J30.47(GND12) J30.48(GND13) J30.53(GND14) J30.54(GND15) J30.59(GND16) J30.60(GND17) J30.65(GND18) J30.66(GND19) J30.G1(GND20) J30.G2(GND21) J31.2 J31.10 J32.1 J32.3 J33.1 J33.3 J34.1 J34.3 J35.1 J35.3 J36.3 J37.3(COM#3) J37.5(COM#5) J37.7(COM#7) J37.13(COM#13) J37.15(COM#15) J37.16(COM#16) J37.17(COM#17) J38.2 J39.2 J40.10 M2.1 M3.1 M4.1 M5.1 Q4.2(S) Q5.2(S) Q6.2(S) Q8.2(S) Q12.2(S) Q13.2(S) Q14.2(S) Q18.2(S) Q21.2(S) Q22.2(S) Q24.2(S) Q25.2(S) Q26.2(S) Q28.2(S) Q29.2(E) Q31.2(S) R2.1 R4.1 R22.1 R31.2 R33.2 R35.2 R37.2 R38.2 R39.2 R40.2 R41.2 R42.2 R43.2 R44.2 R45.2 R46.2 R47.2 R48.2 R49.2 R113.1 R114.1 R115.1 R131.1 R134.2 R142.1 R143.1 R144.1 R147.1 R148.1 R156.1 R157.1 R159.1 R160.1 R161.1 R166.1 R167.1 R168.1 R169.1 R171.1 R172.1 R173.1 R176.2 R179.2 R209.1 R211.1 R212.2 R213.2 R215.1 R218.1 R219.1 R223.1 R225.1 R234.1 R235.1 R238.1 R239.1 R240.1 R245.1 R268.1 R269.2 R274.2 R275.2 R298.1 R299.2 R305.2 R310.1 R315.1 R319.1 R320.2 R327.1 R328.1 R337.1 R339.1 R340.1 R348.1 R350.1 R351.1 R444.2 R447.2 R470.1 R473.2 R474.2 R475.2 R477.2 R479.2 R481.2 R483.2 R485.1 R486.1 R488.1 R490.1 R494.1 R495.1 R496.1 R497.1 R499.2 R502.2 R503.1 R505.2 R509.1 R512.1 R513.2 R516.2 R517.1 R520.2 R521.1 R527.1 R528.1 R540.1 R545.1 R546.1 R553.1 R554.1 R555.1 R572.1 R574.1 R589.1 R590.1 R591.1 R592.1 R607.1 R608.1 R609.1 R610.1 R625.1 R627.1 R640.1 R646.1 R647.1 R651.1 R652.1 R653.1 R654.1 R664.1 R665.1 R666.1 R667.1 R671.1 R672.1 R678.1 R679.1 R685.1 R689.1 R700.1 R704.1 R708.1 R709.1 R719.1 R723.1 R727.1 R732.1 R737.2 R738.1 R743.1 R744.1 R749.1 R754.1 R759.2 R765.1 R766.1 SW3.9 SW4.1 SW4.3 SW4.4 SW5.1 SW5.3 SW5.4 U1.A2(GND001) U1.A20(GND002) U1.A27(GND003) U1.AA11(GND148) U1.AA13(S1GND05) U1.AA15(S1GND06) U1.AA17(S1GND07) U1.AA19(S1GND08) U1.AA21(S1GND09) U1.AA24(GND149) U1.AB2(GND150) U1.AB5(GND151) U1.AB7(GND152) U1.AB13(S1GND10) U1.AB17(S1GND11) U1.AB21(S1GND12) U1.AB22(GND153) U1.AB26(GND154) U1.AC1(EC1_COL) U1.AC2(EC1_RX_ER) U1.AC10(X1GND01) U1.AC11(X1GND02) U1.AC13(X1GND03) U1.AC14(X1GND04) U1.AC16(X1GND05) U1.AC17(X1GND06) U1.AC19(X1GND07) U1.AC20(X1GND08) U1.AC24(GND155) U1.AC26(GND156) U1.AD4(GND157) U1.AD6(GND158) U1.AD9(X1GND09) U1.AD12(X1GND10) U1.AD15(X1GND11) U1.AD18(X1GND12) U1.AD21(X1GND13) U1.AD22(GND159) U1.AE2(GND160) U1.AE9(X1GND14) U1.AE12(X1GND15) U1.AE15(X1GND16) U1.AE18(X1GND17) U1.AE21(X1GND18) U1.AE24(GND161) U1.AE26(GND162) U1.AF9(GND163) U1.AF10(S1GND13) U1.AF11(S1GND14) U1.AF12(S1GND15) U1.AF13(S1GND16) U1.AF14(S1GND17) U1.AF15(S1GND18) U1.AF16(S1GND19) U1.AF17(S1GND20) U1.AF18(S1GND21) U1.AF19(S1GND22) U1.AF20(S1GND23) U1.AF21(GND164) U1.AG1(GND165) U1.AG4(GND166) U1.AG6(GND167) U1.AG9(S1GND24) U1.AG10(SD1_RX0_N) U1.AG12(S1GND25) U1.AG15(S1GND26) U1.AG18(S1GND27) U1.AG21(S1GND28) U1.AG22(GND168) U1.AG23(GND169) U1.AG26(GND170) U1.AH2(GND171) U1.AH9(S1GND29) U1.AH10(SD1_RX0_P) U1.AH12(S1GND30) U1.AH15(S1GND31) U1.AH18(S1GND32) U1.AH21(S1GND33) U1.B1(GND004) U1.B4(GND005) U1.B7(GND006) U1.B10(GND007) U1.B13(GND008) U1.B16(GND009) U1.B19(GND010) U1.B23(GND011) U1.B25(GND012) U1.B28(GND013) U1.C22(GND014) U1.C26(GND015) U1.D2(GND016) U1.D20(GND017) U1.D21(GND018) U1.D24(GND019) U1.E1(USB_AGND01) U1.E2(USB_AGND02) U1.E3(USB_AGND03) U1.E5(GND020) U1.E7(GND021) U1.E10(GND022) U1.E13(GND023) U1.E16(GND024) U1.E19(GND025) U1.E22(GND026) U1.E26(GND027) U1.F3(USB_AGND04) U1.F15(GND028) U1.F24(GND029) U1.G1(USB_AGND05) U1.G2(USB_AGND06) U1.G3(USB_AGND07) U1.G5(USB_AGND08) U1.G7(GND030) U1.G13(GND031) U1.G16(GND032) U1.G22(GND033) U1.G26(GND034) U1.H3(USB_AGND09) U1.H7(GND035) U1.H8(GND036) U1.H9(GND037) U1.H10(GND038) U1.H11(GND039) U1.H12(GND040) U1.H13(GND041) U1.H14(GND042) U1.H15(GND043) U1.H16(GND044) U1.H17(GND045) U1.H18(GND046) U1.H19(GND047) U1.H20(GND048) U1.H24(GND049) U1.J1(USB_AGND10) U1.J2(USB_AGND11) U1.J3(USB_AGND12) U1.J7(GND050) U1.J22(GND051) U1.J26(GND052) U1.K2(GND053) U1.K5(GND054) U1.K6(GND055) U1.K7(GND056) U1.K12(GND057) U1.K14(GND058) U1.K16(GND059) U1.K18(GND060) U1.K20(GND061) U1.K24(GND062) U1.L7(GND063) U1.L9(GND064) U1.L11(GND065) U1.L13(GND066) U1.L15(GND067) U1.L17(GND068) U1.L19(GND069) U1.L22(GND070) U1.L26(GND071) U1.M7(GND072) U1.M10(GND073) U1.M12(GND074) U1.M14(GND075) U1.M16(GND076) U1.M18(GND077) U1.M20(GND078) U1.M24(GND079) U1.N2(GND080) U1.N5(GND081) U1.N7(GND082) U1.N9(GND083) U1.N11(GND084) U1.N13(GND085) U1.N15(GND086) U1.N17(GND087) U1.N19(GND088) U1.N22(GND089) U1.N26(GND090) U1.P7(GND091) U1.P10(GND092) U1.P12(GND093) U1.P14(GND094) U1.P16(GND095) U1.P18(GND096) U1.P20(GND097) U1.P24(GND098) U1.R7(GND099) U1.R9(GND100) U1.R11(GND101) U1.R13(GND102) U1.R15(GND103) U1.R17(GND104) U1.R19(GND105) U1.R22(GND106) U1.R26(GND107) U1.T2(GND108) U1.T5(GND109) U1.T7(GND110) U1.T10(GND111) U1.T12(GND112) U1.T14(GND113) U1.T16(GND114) U1.T18(GND115) U1.T20(GND116) U1.T22(GND117) U1.T26(GND118) U1.U7(GND119) U1.U9(GND120) U1.U11(GND121) U1.U13(GND122) U1.U15(GND123) U1.U17(GND124) U1.U19(GND125) U1.U24(GND126) U1.V7(GND127) U1.V10(GND128) U1.V12(GND129) U1.V14(GND130) U1.V16(GND131) U1.V18(GND132) U1.V20(GND133) U1.V22(GND134) U1.V26(GND135) U1.W2(GND136) U1.W5(GND137) U1.W7(GND138) U1.W9(GND139) U1.W11(GND140) U1.W13(GND141) U1.W24(GND142) U1.Y7(GND143) U1.Y10(GND144) U1.Y12(GND145) U1.Y14(S1GND01) U1.Y16(S1GND02) U1.Y17(S1GND03) U1.Y18(S1GND04) U1.Y22(GND146) U1.Y26(GND147) U2.1(O\E\1\) U2.4(GND#4) U2.10(GND#10) U2.15(GND#15) U2.21(GND#21) U2.24(O\E\2\) U2.26(2D8) U2.27(2D7) U2.28(GND#28) U2.29(2D6) U2.30(2D5) U2.32(2D4) U2.34(GND#34) U2.39(GND#39) U2.45(GND#45) U3.33(GND#33) U3.52(GND#52) U4.C5(VSS#C5) U4.F7(VSS#F7) U4.K3(VSS#K3) U4.K8(VSS#K8) U5.3(GND) U6.3(GND) U7.3(GND) U8.10(GND) U9.4(GND) U9.9(EPAD) U10.9 U11.9 U12.8(VSS) U13.3(GND) U16.2(PD) U16.5(GND#5) U16.11(GND#11) U16.20(GND#20) U16.21(EPAD) U17.2(PD) U17.5(GND#5) U17.11(GND#11) U17.20(GND#20) U17.21(EPAD) U18.2(PD) U18.5(GND#5) U18.11(GND#11) U18.20(GND#20) U18.21(EPAD) U19.8(GND) U19.11(EPAD) U20.2 U21.1(1O\E\) U21.8(GND) U21.15(2O\E\) U22.1(1O\E\) U22.8(GND) U22.15(2O\E\) U23.1(1O\E\) U23.8(GND) U23.15(2O\E\) U24.1(1O\E\) U24.8(GND) U24.15(2O\E\) U25.1(1\O\E\) U25.4(2\O\E\) U25.7(GND) U25.10(3\O\E\) U25.13(4\O\E\) U26.1(1O\E\) U26.8(GND) U26.15(2O\E\) U27.1(1O\E\) U27.8(GND) U27.15(2O\E\) U28.1(1O\E\) U28.8(GND) U28.15(2O\E\) U29.15(GND) U30.15(GND) U31.4(GND) U32.1(A0) U32.2(A1) U32.3(A2) U32.4(GND) U32.7(WP) U33.9 U33.10 U33.11 U33.12 U33.13 U33.14 U33.15 U33.16 U34.5(GND) U35.6(DGND#6) U35.11(DGND#11) U35.17(AGND) U35.20(TGND#20) U35.26(TGND#26) U35.32(TGND#32) U35.34(GND#34) U35.36(TEST) U35.40(GND#40) U35.64(DGND#64) U36.3(GND#3) U36.5(TMDS_GND#5) U36.8(TMDS_GND#8) U36.11(TMDS_GND#11) U36.14(TMDS_GND#14) U36.25(TMDS_GND#25) U36.28(TMDS_GND#28) U36.31(TMDS_GND#31) U36.34(TMDS_GND#34) U36.36(GND#36) U37.1(D19) U37.2(D18) U37.3(D17) U37.4(D16) U37.5(D15) U37.6(D14) U37.7(D13) U37.8(D12) U37.9(GND#9) U37.11(GND#11) U37.14(PLLGND#14) U37.15(PLLGND#15) U37.17(PLLGND#17) U37.20(RSVD1) U37.25(LVDSGND#25) U37.35(LVDSGND#35) U37.43(LVDSGND#43) U37.51(LVDSGND#51) U37.52(GND#52) U37.54(RSVD2) U37.56(RSVD4) U37.57(RSVD5) U37.58(RSVD6) U37.62(RSVD7) U37.63(A0) U37.64(A1) U37.65(A2) U37.66(RSVD8) U37.67(RSVD9) U37.69(SGND) U37.71(GND3V#71) U37.77(GND#77) U37.80(GND3V#80) U37.96(GND3V#96) U37.97(D23) U37.98(D22) U37.99(D21) U37.100(D20) U38.1(-VIN) U39.8(GND) U39.15(O\E\) U40.2(GND1_1) U40.8(GND1_2) U41.3(GND) U42.47(GND) U42.49(EPAD) U45.47(GND) U45.49(EPAD) U48.15(AGND#15) U48.19(AGND#19) U48.20(AGND#20) U48.27(AGND#27) U48.48(GTX_CLK) U48.49(TXEN/TXCTL) U48.50(TXD0) U48.53(TXD1) U48.54(TXD2) U48.55(TXD3) U48.57(TXD4) U48.58(TXD5) U48.59(TXD6) U48.60(TXD7) U48.61(TXER) U48.83(GND#83) U48.87(GND#87) U48.89(EPAD) U51.139(VSS_CASE) U51.B7(REFCLK_SEL1) U51.B8(REFCLK_SEL0) U51.D9(VSS/EFUSE) U52.139(VSS_CASE) U52.B7(REFCLK_SEL1) U52.B8(REFCLK_SEL0) U52.D9(VSS/EFUSE) U57.A1(GNDIO#A1) U57.A16(GNDIO#A16) U57.B2(GNDIO#B2) U57.B15(GNDIO#B15) U57.G7(GNDIO#G7) U57.G8(GNDIO#G8) U57.G9(GNDIO#G9) U57.G10(GNDIO#G10) U57.H7(GNDINT#H7) U57.H9(GNDINT#H9) U57.J8(GNDINT#J8) U57.J10(GNDINT#J10) U57.K7(GNDIO#K7) U57.K8(GNDIO#K8) U57.K9(GNDIO#K9) U57.K10(GNDIO#K10) U57.R2(GNDIO#R2) U57.R15(GNDIO#R15) U57.T1(GNDIO#T1) U57.T16(GNDIO#T16) U58.15(GND#15) U58.19(GND#19) U60.4(GND#4) U60.11(PGND) U60.17(GND#17) U61.3(GND) U62.7(GND) U64.4(GND#4) U64.11(PGND) U64.17(GND#17) U65.4(GND#4) U65.11(PGND) U65.17(GND#17) U66.4(GND#4) U66.11(PGND) U66.17(GND#17) U67.4(GND#4) U67.11(PGND) U67.17(GND#17) U68.4(GND#4) U68.11(PGND) U68.17(GND#17) U69.4(GND#4) U69.11(PGND) U69.17(GND#17) U72.4(PGND) U72.8(GND) U72.11(PAD) U73.3(GND) U73.9(EPAD) U74.3(GND) U74.6(GND(TAB)) U75.3(GND) U75.9(EPAD) U76.1(GND) U77.4(GND) U78.3(GND) U79.8(GNDDIG) U79.41(EPAD) U80.3(GND) U81.3(GND) U82.15(AGND#15) U82.19(AGND#19) U82.20(AGND#20) U82.27(AGND#27) U82.48(GTX_CLK) U82.49(TXEN/TXCTL) U82.50(TXD0) U82.53(TXD1) U82.54(TXD2) U82.55(TXD3) U82.57(TXD4) U82.58(TXD5) U82.59(TXD6) U82.60(TXD7) U82.61(TXER) U82.83(GND#83) U82.87(GND#87) U82.89(EPAD) U83.15(AGND#15) U83.19(AGND#19) U83.20(AGND#20) U83.27(AGND#27) U83.48(GTX_CLK) U83.49(TXEN/TXCTL) U83.50(TXD0) U83.53(TXD1) U83.54(TXD2) U83.55(TXD3) U83.57(TXD4) U83.58(TXD5) U83.59(TXD6) U83.60(TXD7) U83.61(TXER) U83.83(GND#83) U83.87(GND#87) U83.89(EPAD) X1.2(GND) X2.2(GND) X3.2(GND) X4.2(GND) Y1.2 Y1.3 Y2.2 Y2.4 Y3.2 Y3.4 Y4.2 Y4.4 Y7.2 Y7.4 Y8.2 Y8.4 Y9.2 Y9.4 Y10.2 Y10.4 Z9.1 Z9.2 Z9.3 Z9.4 Z9.5 Z9.6 Z9.7 Z9.8 Z10.1 Z10.2 Z10.3 Z10.4 Z10.5 Z10.6 Z10.7 Z10.8 Z11.1 Z11.2 Z11.3 Z11.4 Z11.5 Z11.6 Z11.7 Z11.8 Z12.1 Z12.2 Z12.3 Z12.4 Z12.5 Z12.6 Z12.7 Z12.8 Z13.1 Z13.2 Z13.3 Z13.4 Z13.5 Z13.6 Z13.7 Z13.8 Z14.1 Z14.2 Z14.3 Z14.4 Z14.5 Z14.6 Z14.7 Z14.8 Z15.1 Z15.2 Z15.3 Z15.4 Z15.5 Z15.6 Z15.7 Z15.8 Z17.1 Z18.1
GND_PROFI: C333.2 C334.2 J42.5 R237.1 R238.2 R244.1 U38.3(-VOUT) U40.9(GND2_1) U40.15(GND2_2)
SVDD: C192.1 C210.1 C211.1 C212.1 C213.1 C214.1 C215.1 C216.1 C217.1 R145.1 U1.W15(S1VDD1) U1.W16(S1VDD2) U1.W17(S1VDD3) U1.W18(S1VDD4) U1.W19(S1VDD5) U1.W20(S1VDD6) U1.Y13(S1VDD7)
SVDD_EN: R645.1 U57.T12(IO_B1_T12) U73.5(EN)
VCC_PROFI: C333.1 C334.1 J42.1 L3.2 R237.2 R242.2 U40.16(VCC2)
VDD_EN_N: R552.1 U57.N12(IO_B1_N12)
VDD_LP: U1.P6(VDD_LP)
VDD_SD: C46.1 C47.1 J2.2 J3.4(VDD)
ASLEEP: R110.1 U1.B2(ASLEEP) U13.2(A)
AURORA_CLKOUT: J30.20(I/O_3) R462.1
AURORA_EVTI_N: R468.1 U57.R8(IO_B1_R8)
AURORA_EVTO_N: R469.1 U57.T8(IO_B1_T8)
AURORA_HALT_N: R467.1 U57.T7(IO_B1_T7)
AURORA_HRST_N: J30.34(I/O_5) R461.1 U57.P9(IO_B1_P9)
AURORA_PORST_N: J30.22(RESET) R460.1 U57.T9(IO_B1_T9)
AURORA_RDY_N: J30.32(I/O_4) TP19.1(TP)
AURORA_REFCLK_N: J30.28(CLK_N) R504.2 R512.2
AURORA_REFCLK_P: J30.26(CLK_P) R503.2 R511.2
AURORA_RX_N: C776.2 U18.19(B0+)
AURORA_RX_P: C775.2 U18.18(B0-)
AURORA_TCK: J30.4(TCK) R459.1 U57.R5(IO_B1_R5)
AURORA_TDI: J30.8(TDI) R457.1 U57.T5(IO_B1_T5)
AURORA_TDO: J30.10(TDO) U57.R7(IO_B1_R7)
AURORA_TMS: J30.6(TMS) R458.1 U57.T6(IO_B1_T6)
AURORA_TRST_N: J30.12(TRST) R456.1 U57.R6(IO_B1_R6)
AURORA_TX_N: J30.3(TX0_N) U18.17(B1+)
AURORA_TX_P: J30.1(TX0_P) U18.16(B1-)
BOOT_FLASH_SEL: R476.2 SW3.4 U57.F15(IO_B2_F15)
CFG_VBANK0: R478.2 SW3.5 U7.2(I1) U57.J16(IO_B2_J16)
CFG_VBANK1: R480.2 SW3.6 U6.2(I1) U57.H16(IO_B2_H16)
CFG_VBANK2: R482.2 SW3.7 U5.2(I1) U57.J15(IO_B2_J15)
CK_N: J12.12(CK-) L22.2 R775.2
CK_P: J12.10(CK+) L22.3 R774.2
CKE_ISO_EN: R684.1 U57.G3(IO_B1_G3)
CKSTP_OUT_N: R111.1 U1.F18(CKSTP_OUT_B) U57.C9(IO_B2_C9)
COP_CKSTP_OUT_N: J4.15 U57.G1(IO_B1_G1)
COP_HRESET_N: J4.13 R123.2 U57.G2(IO_B1_G2)
COP_SRESET_N: J4.11 R122.2 U57.F1(IO_B1_F1)
COP_TCK: J4.7 R120.2 U57.E1(IO_B1_E1)
COP_TDI: J4.3 R118.2 U57.E2(IO_B1_E2)
COP_TDO: J4.1 U57.D2(IO_B1_D2)
COP_TMS: J4.9 R121.2 U57.F2(IO_B1_F2)
COP_TRST_N: J4.4 R117.1 U57.D1(IO_B1_D1)
CPLD_INT1_N: R78.1 U1.F7(IRQ00) U57.C15(IO_B2_C15)
CPLD_INT2_N: R79.1 U1.D3(IRQ01) U57.D14(IO_B2_D14)
CPLD_REFCLK: R492.2 U57.H5(GCLK0P)
CPLD_TCK: J31.1 R470.2 U57.P3(TCK)
CPLD_TDI: J31.9 R472.2 U57.L6(TDI)
CPLD_TDO: J31.3 U57.M5(TDO)
CPLD_TMS: J31.5 R471.2 U57.N4(TMS)
D0_N: J12.9(D0-) L21.2 R773.2
D0_P: J12.7(D0+) L21.3 R772.2
D1_N: J12.6(D1-) L20.2 R771.2
D1_P: J12.4(D1+) L20.3 R770.2
D2_N: J12.3(D2-) L19.2 R769.2
D2_P: J12.1(D2+) L19.3 R768.2
DDR_DQ0: J1.5(DQ0) U1.C21(D1_MDQ00)
DDR_DQ1: J1.150(DQ1) U1.A22(D1_MDQ01)
DDR_DQ2: J1.12(DQ2) U1.A26(D1_MDQ02)
DDR_DQ3: J1.157(DQ3) U1.B26(D1_MDQ03)
DDR_DQ4: J1.3(DQ4) U1.B21(D1_MDQ04)
DDR_DQ5: J1.148(DQ5) U1.A21(D1_MDQ05)
DDR_DQ6: J1.10(DQ6) U1.B24(D1_MDQ06)
DDR_DQ7: J1.155(DQ7) U1.A25(D1_MDQ07)
DDR_DQ8: J1.16(DQ8) U1.C23(D1_MDQ08)
DDR_DQ9: J1.161(DQ9) U1.C24(D1_MDQ09)
DDR_DQ10: J1.23(DQ10) U1.F25(D1_MDQ10)
DDR_DQ11: J1.168(DQ11) U1.F26(D1_MDQ11)
DDR_DQ12: J1.14(DQ12) U1.D22(D1_MDQ12)
DDR_DQ13: J1.159(DQ13) U1.D23(D1_MDQ13)
DDR_DQ14: J1.21(DQ14) U1.B27(D1_MDQ14)
DDR_DQ15: J1.166(DQ15) U1.E25(D1_MDQ15)
DDR_DQ16: J1.27(DQ16) U1.E23(D1_MDQ16)
DDR_DQ17: J1.172(DQ17) U1.E24(D1_MDQ17)
DDR_DQ18: J1.34(DQ18) U1.J23(D1_MDQ18)
DDR_DQ19: J1.179(DQ19) U1.K23(D1_MDQ19)
DDR_DQ20: J1.25(DQ20) U1.F22(D1_MDQ20)
DDR_DQ21: J1.170(DQ21) U1.H22(D1_MDQ21)
DDR_DQ22: J1.32(DQ22) U1.H23(D1_MDQ22)
DDR_DQ23: J1.177(DQ23) U1.J24(D1_MDQ23)
DDR_DQ24: J1.38(DQ24) U1.H26(D1_MDQ24)
DDR_DQ25: J1.183(DQ25) U1.J25(D1_MDQ25)
DDR_DQ26: J1.45(DQ26) U1.P26(D1_MDQ26)
DDR_DQ27: J1.190(DQ27) U1.N25(D1_MDQ27)
DDR_DQ28: J1.36(DQ28) U1.G25(D1_MDQ28)
DDR_DQ29: J1.181(DQ29) U1.H25(D1_MDQ29)
DDR_DQ30: J1.43(DQ30) U1.M26(D1_MDQ30)
DDR_DQ31: J1.188(DQ31) U1.M25(D1_MDQ31)
DDR_DQ32: J1.97(DQ32) U1.T25(D1_MDQ32)
DDR_DQ33: J1.242(DQ33) U1.U25(D1_MDQ33)
DDR_DQ34: J1.104(DQ34) U1.AA26(D1_MDQ34)
DDR_DQ35: J1.249(DQ35) U1.AA25(D1_MDQ35)
DDR_DQ36: J1.95(DQ36) U1.P25(D1_MDQ36)
DDR_DQ37: J1.240(DQ37) U1.R25(D1_MDQ37)
DDR_DQ38: J1.102(DQ38) U1.W26(D1_MDQ38)
DDR_DQ39: J1.247(DQ39) U1.Y25(D1_MDQ39)
DDR_DQ40: J1.108(DQ40) U1.V24(D1_MDQ40)
DDR_DQ41: J1.253(DQ41) U1.W23(D1_MDQ41)
DDR_DQ42: J1.115(DQ42) U1.AA22(D1_MDQ42)
DDR_DQ43: J1.260(DQ43) U1.AC22(D1_MDQ43)
DDR_DQ44: J1.106(DQ44) U1.W22(D1_MDQ44)
DDR_DQ45: J1.251(DQ45) U1.V23(D1_MDQ45)
DDR_DQ46: J1.113(DQ46) U1.AB24(D1_MDQ46)
DDR_DQ47: J1.258(DQ47) U1.AB23(D1_MDQ47)
DDR_DQ48: J1.119(DQ48) U1.AD26(D1_MDQ48)
DDR_DQ49: J1.264(DQ49) U1.AD25(D1_MDQ49)
DDR_DQ50: J1.126(DQ50) U1.AD23(D1_MDQ50)
DDR_DQ51: J1.271(DQ51) U1.AE22(D1_MDQ51)
DDR_DQ52: J1.117(DQ52) U1.AB25(D1_MDQ52)
DDR_DQ53: J1.262(DQ53) U1.AC25(D1_MDQ53)
DDR_DQ54: J1.124(DQ54) U1.AC23(D1_MDQ54)
DDR_DQ55: J1.269(DQ55) U1.AE23(D1_MDQ55)
DDR_DQ56: J1.130(DQ56) U1.AG25(D1_MDQ56)
DDR_DQ57: J1.275(DQ57) U1.AH25(D1_MDQ57)
DDR_DQ58: J1.137(DQ58) U1.AH22(D1_MDQ58)
DDR_DQ59: J1.282(DQ59) U1.AF22(D1_MDQ59)
DDR_DQ60: J1.128(DQ60) U1.AF26(D1_MDQ60)
DDR_DQ61: J1.273(DQ61) U1.AH26(D1_MDQ61)
DDR_DQ62: J1.135(DQ62) U1.AH23(D1_MDQ62)
DDR_DQ63: J1.280(DQ63) U1.AF23(D1_MDQ63)
DDR_ECC0: J1.49(CB0) U1.L24(D1_MECC0)
DDR_ECC1: J1.194(CB1/NC15) U1.N23(D1_MECC1)
DDR_ECC2: J1.56(CB2) U1.T23(D1_MECC2)
DDR_ECC3: J1.201(CB3/NC17) U1.U23(D1_MECC3)
DDR_ECC4: J1.47(CB4) U1.L23(D1_MECC4)
DDR_ECC5: J1.192(CB5/NC14) U1.M23(D1_MECC5)
DDR_ECC6: J1.54(CB6) U1.R24(D1_MECC6)
DDR_ECC7: J1.199(CB7/NC16) U1.T24(D1_MECC7)
DDR_MA0: J1.79(A0) U1.V28(D1_MA00)
DDR_MA1: J1.72(A1) U1.N28(D1_MA01)
DDR_MA2: J1.216(A2) U1.N27(D1_MA02)
DDR_MA3: J1.71(A3) U1.M28(D1_MA03)
DDR_MA4: J1.214(A4) U1.L27(D1_MA04)
DDR_MA5: J1.213(A5) U1.L28(D1_MA05)
DDR_MA6: J1.69(A6) U1.K28(D1_MA06)
DDR_MA7: J1.211(A7) U1.J28(D1_MA07)
DDR_MA8: J1.68(A8) U1.J27(D1_MA08)
DDR_MA9: J1.66(A9) U1.G27(D1_MA09)
DDR_MA10: J1.225(A10/AP) U1.Y27(D1_MA10)
DDR_MA11: J1.210(A11) U1.H28(D1_MA11)
DDR_MA12: J1.65(A12/B\C\) U1.G28(D1_MA12)
DDR_MA13: J1.232(A13) U1.AE28(D1_MA13)
DDR_MA14: J1.207(BG1) U1.E27(D1_MA14)
DDR_MA15: J1.62(A\C\T\) U1.D28(D1_MA15)
DDR_MAPAR_ERR: J1.208(A\L\E\R\T\) R3.2 U1.F28(D1_MAPAR_ERR_B)
DDR_MAPAR_OUT: J1.222(PARITY) U1.V27(D1_MAPAR_OUT)
DDR_MBA0: J1.81(BA0) U1.Y28(D1_MBA0)
DDR_MBA1: J1.224(BA1) U1.W28(D1_MBA1)
DDR_MBA2: J1.63(BG0) U1.E28(D1_MBA2)
DDR_MCAS_N: J1.86(C\A\S\/A15) U1.AC28(D1_MCAS_B)
DDR_MCK0_N: J1.75(CK0_N) U1.T28(D1_MCK0_B)
DDR_MCK0_P: J1.74(CK0_P) U1.T27(D1_MCK0)
DDR_MCK1_N: J1.219(CK1_N) U1.R28(D1_MCK1_B)
DDR_MCK1_P: J1.218(CK1_P) U1.R27(D1_MCK1)
DDR_MCKE0: J1.60(CKE0) Q25.3(D) U1.C27(D1_MCKE0)
DDR_MCKE1: J1.203(CKE1/NC18) Q26.3(D) U1.C28(D1_MCKE1)
DDR_MCS0_N: J1.84(S\0\) U1.AB28(D1_MCS0_B)
DDR_MCS1_N: J1.89(C\S\1\/NC7) U1.AC27(D1_MCS1_B)
DDR_MCS2_N: J1.93(C\S\2\/NC8) U1.AG27(D1_MCS2_B)
DDR_MCS3_N: J1.237(C\S\3\/C1/NC22) U1.AF28(D1_MCS3_B)
DDR_MDM0: J1.7(DQS9_P/DM0) U1.B22(D1_MDM0)
DDR_MDM1: J1.18(DQS10_P/DM1) U1.C25(D1_MDM1)
DDR_MDM2: J1.29(DQS11_P/DM2) U1.F23(D1_MDM2)
DDR_MDM3: J1.40(DQS12_P/DM3) U1.K26(D1_MDM3)
DDR_MDM4: J1.99(DQS13_P/DM4) U1.U26(D1_MDM4)
DDR_MDM5: J1.110(DQS14_P/DM5) U1.Y24(D1_MDM5)
DDR_MDM6: J1.121(DQS15_P/DM6) U1.AD24(D1_MDM6)
DDR_MDM7: J1.132(DQS16_P/DM7) U1.AF24(D1_MDM7)
DDR_MDM8: J1.51(DQS17_P/DM8) U1.N24(D1_MDM8)
DDR_MDQS0_N: J1.152(DQS0_N) U1.A23(D1_MDQS0_B)
DDR_MDQS0_P: J1.153(DQS0_P) U1.A24(D1_MDQS0)
DDR_MDQS1_N: J1.163(DQS1_N) U1.D25(D1_MDQS1_B)
DDR_MDQS1_P: J1.164(DQS1_P) U1.D26(D1_MDQS1)
DDR_MDQS2_N: J1.174(DQS2_N) U1.G23(D1_MDQS2_B)
DDR_MDQS2_P: J1.175(DQS2_P) U1.G24(D1_MDQS2)
DDR_MDQS3_N: J1.185(DQS3_N) U1.K25(D1_MDQS3_B)
DDR_MDQS3_P: J1.186(DQS3_P) U1.L25(D1_MDQS3)
DDR_MDQS4_N: J1.244(DQS4_N) U1.V25(D1_MDQS4_B)
DDR_MDQS4_P: J1.245(DQS4_P) U1.W25(D1_MDQS4)
DDR_MDQS5_N: J1.255(DQS5_N) U1.Y23(D1_MDQS5_B)
DDR_MDQS5_P: J1.256(DQS5_P) U1.AA23(D1_MDQS5)
DDR_MDQS6_N: J1.266(DQS6_N) U1.AF25(D1_MDQS6_B)
DDR_MDQS6_P: J1.267(DQS6_P) U1.AE25(D1_MDQS6)
DDR_MDQS7_N: J1.277(DQS7_N) U1.AH24(D1_MDQS7_B)
DDR_MDQS7_P: J1.278(DQS7_P) U1.AG24(D1_MDQS7)
DDR_MDQS8_N: J1.196(DQS8_N) U1.P23(D1_MDQS8_B)
DDR_MDQS8_P: J1.197(DQS8_P) U1.R23(D1_MDQS8)
DDR_MODT0: J1.87(ODT0) U1.AD28(D1_MODT0)
DDR_MODT1: J1.91(ODT1) U1.AE27(D1_MODT1)
DDR_MRAS_N: J1.82(R\A\S\/A16) U1.AA28(D1_MRAS_B)
DDR_MWE_N: J1.228(W\E\/A14) U1.AB27(D1_MWE_B)
DDR_PGOOD: R568.2 U57.T10(IO_B1_T10) U64.3(PGOOD)
DDR_REFCLK: R487.2 R488.2 U1.J21(DDRCLK)
DDR_RST_N: J1.58(R\E\S\E\T\) R5.2 U57.A2(IO_B2_A2)
DDRPWR_EN: C865.2 R565.2 U57.R9(IO_B1_R9) U64.16(EN)
DFP_BACKLIGHT: J17.1 R235.2 U57.J1(IO_B1_J1)
DFP_BL_PWM: J17.3 R234.2 U57.K1(IO_B1_K1)
DFP_D0: U21.5(1B2) U37.94(D0)
DFP_D1: U21.11(2B2) U37.93(D1)
DFP_D2: U23.5(1B2) U37.92(D2)
DFP_D3: U23.11(2B2) U37.91(D3)
DFP_D4: U26.5(1B2) U37.90(D4)
DFP_D5: U26.11(2B2) U37.89(D5)
DFP_D6: U28.5(1B2) U37.86(D6)
DFP_D7: U28.11(2B2) U37.85(D7)
DFP_D8: U22.5(1B2) U37.84(D8)
DFP_D9: U22.11(2B2) U37.83(D9)
DFP_D10: U24.5(1B2) U37.82(D10)
DFP_D11: U24.11(2B2) U37.81(D11)
DFP_DCLK: R225.2 U27.11(2B2) U37.87(CLKIN_P)
DFP_DE: R223.2 U27.5(1B2) U37.76(DE)
DFP_HSYNC: U25.6(2Y) U37.75(HSYNC)
DFP_INT_N: R221.1 U37.21(MSEN) U57.P6(IO_B1_P6)
DFP_MODE: Q6.1(G) U57.R4(IO_B1_R4)
DFP_RST_N: R222.1 U37.22(P\D\) U57.N5(IO_B1_N5)
DFP_VSYNC: U25.11(4Y) U37.74(VSYNC)
DIU_HSYNC: U1.AA3(IIC4_SCL) U25.2(1A) U25.5(2A)
DIU_VSYNC: U1.AB3(IIC4_SDA) U25.9(3A) U25.12(4A)
DVI_D0: U21.6(1B1) U35.63(D0)
DVI_D1: U21.10(2B1) U35.62(D1)
DVI_D2: U23.6(1B1) U35.61(D2)
DVI_D3: U23.10(2B1) U35.60(D3)
DVI_D4: U26.6(1B1) U35.59(D4)
DVI_D5: U26.10(2B1) U35.58(D5)
DVI_D6: U28.6(1B1) U35.55(D6)
DVI_D7: U28.10(2B1) U35.54(D7)
DVI_D8: U22.6(1B1) U35.53(D8)
DVI_D9: U22.10(2B1) U35.52(D9)
DVI_D10: U24.6(1B1) U35.51(D10)
DVI_D11: U24.10(2B1) U35.50(D11)
DVI_DCLK: U27.10(2B1) U35.57(XCLK+)
DVI_DE: R209.2 U27.6(1B1) U35.2(DE)
DVI_HSYNC: U25.3(1Y) U35.4(H)
DVI_INT_N: R216.2 U35.7(GPIO1/HPINT) U57.L2(IO_B1_L2)
DVI_RST_N: R217.2 U35.13(R\E\S\E\T\) U57.M1(IO_B1_M1)
DVI_TDC0_N: L21.1 R773.1 U35.21(TDC0-) U36.12(TMDS_D0-) U36.27(TMDSO_D0-)
DVI_TDC0_P: L21.4 R772.1 U35.22(TDC0+) U36.10(TMDS_D0+) U36.29(TMDSO_D0+)
DVI_TDC1_N: L20.1 R771.1 U35.24(TDC1-) U36.9(TMDS_D1-) U36.30(TMDSO_D1-)
DVI_TDC1_P: L20.4 R770.1 U35.25(TDC1+) U36.7(TMDS_D1+) U36.32(TMDSO_D1+)
DVI_TDC2_N: L19.1 R769.1 U35.27(TDC2-) U36.6(TMDS_D2-) U36.33(TMDSO_D2-)
DVI_TDC2_P: L19.4 R768.1 U35.28(TDC2+) U36.4(TMDS_D2+) U36.35(TMDSO_D2+)
DVI_TLC_N: L22.1 R775.1 U35.31(TLC-) U36.15(TMDS_CK-) U36.24(TMDSO_CK-)
DVI_TLC_P: L22.4 R774.1 U35.30(TLC+) U36.13(TMDS_CK+) U36.26(TMDSO_CK+)
DVI_VSYNC: R211.2 U25.8(3Y) U35.5(V)
EARTH: C345.2 C347.2 C353.2 C374.2 C376.2 C382.2 C402.2 C405.2 C408.2 C505.1 C506.1 C519.1 C520.1 C533.1 C534.1 C548.1 C549.1 C551.2 C552.2 C555.2 C559.2 C560.2 C1075.2 C1078.2 C1081.2 C1109.2 C1112.2 C1115.2 J5.9 J5.10 J5.11 J5.12 J9.10 J9.20 J9.21 J9.22 J12.20(MH1) J12.21(MH2) J12.22(MH3) J12.23(MH4) J19.25 J19.26 J19.27 J19.28 J20.13 J20.14 J21.97 J21.98 J21.99 J21.100 J40.13 J40.14 J41.13 J41.14 Z16.1 Z16.2 Z16.3 Z16.4 Z16.5 Z16.6 Z16.7 Z16.8
EC1_GTXCLK: R132.1 U42.22(TXC)
EC1_INT_N: R84.1 R262.2 U1.AB4(IRQ06)
EC1_LED0: R259.1 R274.1 U42.34(LED0/PHY_AD0)
EC1_LED1: R260.1 R275.1 U42.35(LED1/PHY_AD1)
EC1_MDI0_N: T1.11 U42.2(MDI-[0])
EC1_MDI0_P: T1.12 U42.1(MDI+[0])
EC1_MDI1_N: T1.8 U42.5(MDI-[1])
EC1_MDI1_P: T1.9 U42.4(MDI+[1])
EC1_MDI2_N: T1.5 U42.8(MDI-[2])
EC1_MDI2_P: T1.6 U42.7(MDI+[2])
EC1_MDI3_N: T1.2 U42.11(MDI-[3])
EC1_MDI3_P: T1.3 U42.10(MDI+[3])
EC1_MDX0_N: J19.B2 T1.14
EC1_MDX0_P: J19.B1 T1.13
EC1_MDX1_N: J19.B6 T1.17
EC1_MDX1_P: J19.B3 T1.16
EC1_MDX2_N: J19.B5 T1.20
EC1_MDX2_P: J19.B4 T1.19
EC1_MDX3_N: J19.B8 T1.23
EC1_MDX3_P: J19.B7 T1.22
EC1_PME_N: R85.1 R264.2 U1.AD5(IRQ07)
EC1_REFCLK: R258.2 U1.AG3(EC1_GTX_CLK125)
EC1_RST_N: R265.2 U42.29(P\H\Y\R\S\T\) U57.M2(IO_B1_M2)
EC1_RXCLK: R250.1 R710.1 R714.1
EC1_RXCTL: R256.1 R273.1 U1.AG2(EC1_RX_CTL)
EC1_RXD0: R251.1 R269.1 U1.AF2(EC1_RXD0)
EC1_RXD1: R253.1 R270.1 U1.AF1(EC1_RXD1)
EC1_RXD2: R254.1 R271.1 U1.AE1(EC1_RXD2)
EC1_RXD3: R255.1 R272.1 U1.AD2(EC1_RXD3)
EC1_RXDLY: R276.1 U42.32(LED2/RXDLY)
EC1_TXCTL: R135.1 U42.27(TXCTL)
EC1_TXD0: R133.1 U42.23(TXD0)
EC1_TXD1: R125.1 U42.24(TXD1)
EC1_TXD2: R127.1 U42.25(TXD2)
EC1_TXD3: R129.1 U42.26(TXD3)
EC2_GTXCLK: R137.2 U45.22(TXC)
EC2_INT_N: R82.1 R292.2 U1.D4(IRQ04)
EC2_LED0: R289.1 R304.1 U45.34(LED0/PHY_AD0)
EC2_LED1: R290.1 R305.1 U45.35(LED1/PHY_AD1)
EC2_MDI0_N: T2.11 U45.2(MDI-[0])
EC2_MDI0_P: T2.12 U45.1(MDI+[0])
EC2_MDI1_N: T2.8 U45.5(MDI-[1])
EC2_MDI1_P: T2.9 U45.4(MDI+[1])
EC2_MDI2_N: T2.5 U45.8(MDI-[2])
EC2_MDI2_P: T2.6 U45.7(MDI+[2])
EC2_MDI3_N: T2.2 U45.11(MDI-[3])
EC2_MDI3_P: T2.3 U45.10(MDI+[3])
EC2_MDX0_N: J19.A2 T2.14
EC2_MDX0_P: J19.A1 T2.13
EC2_MDX1_N: J19.A6 T2.17
EC2_MDX1_P: J19.A3 T2.16
EC2_MDX2_N: J19.A5 T2.20
EC2_MDX2_P: J19.A4 T2.19
EC2_MDX3_N: J19.A8 T2.23
EC2_MDX3_P: J19.A7 T2.22
EC2_PME_N: R83.1 R294.2 U1.D5(IRQ05)
EC2_REFCLK: R288.2 U1.AC6(EC2_GTX_CLK125)
EC2_RST_N: R295.2 U45.29(P\H\Y\R\S\T\) U57.N1(IO_B1_N1)
EC2_RXCLK: R281.1 R713.2 R717.2
EC2_RXCTL: R286.1 R303.1 U1.AG8(EC2_RX_CTL)
EC2_RXD0: R280.1 R299.1 U1.AH8(EC2_RXD0)
EC2_RXD1: R283.1 R300.1 U1.AG7(EC2_RXD1)
EC2_RXD2: R284.1 R301.1 U1.AH7(EC2_RXD2)
EC2_RXD3: R285.1 R302.1 U1.AH6(EC2_RXD3)
EC2_RXDLY: R306.1 U45.32(LED2/RXDLY)
EC2_TXCTL: R136.2 U45.27(TXCTL)
EC2_TXD0: R124.2 U45.23(TXD0)
EC2_TXD1: R126.2 U45.24(TXD1)
EC2_TXD2: R128.2 U45.25(TXD2)
EC2_TXD3: R130.2 U45.26(TXD3)
EMI1_MDC: U45.30(MDC) U48.72(MDC) U51.C11(MDC) U52.C11(MDC) U80.2(B) U82.72(MDC) U83.72(MDC)
EMI1_MDC_SLP: R138.1 R140.2 U42.30(MDC) U80.1(A)
EMI1_MDIO: U45.31(MDIO) U48.73(MDIO) U51.D10(MDIO) U52.D10(MDIO) U81.2(B) U82.73(MDIO) U83.73(MDIO)
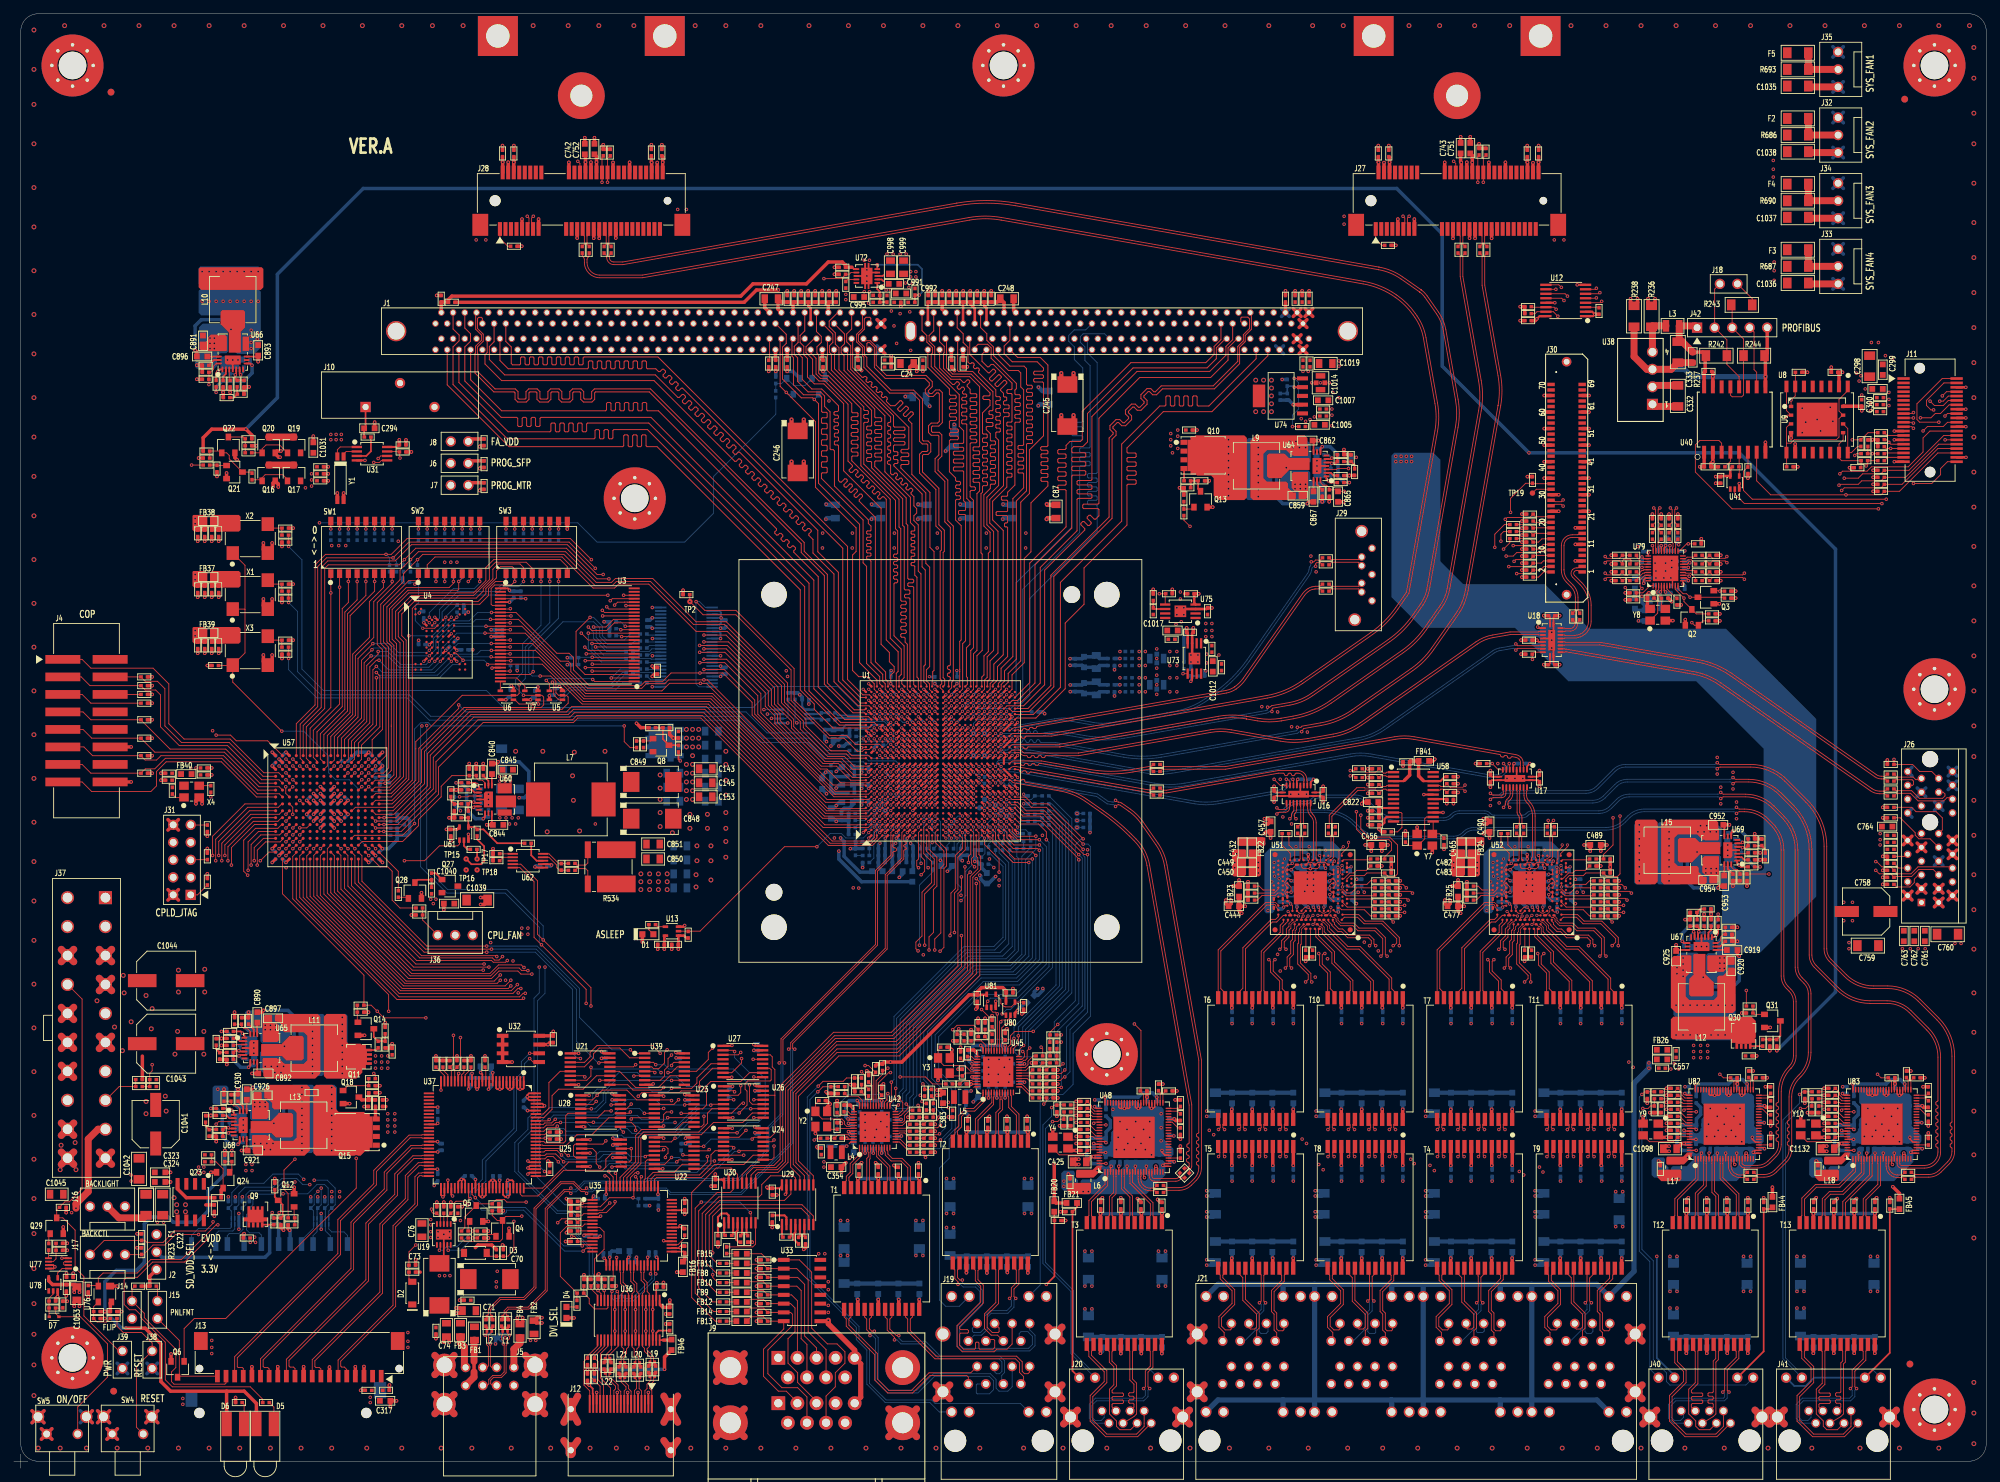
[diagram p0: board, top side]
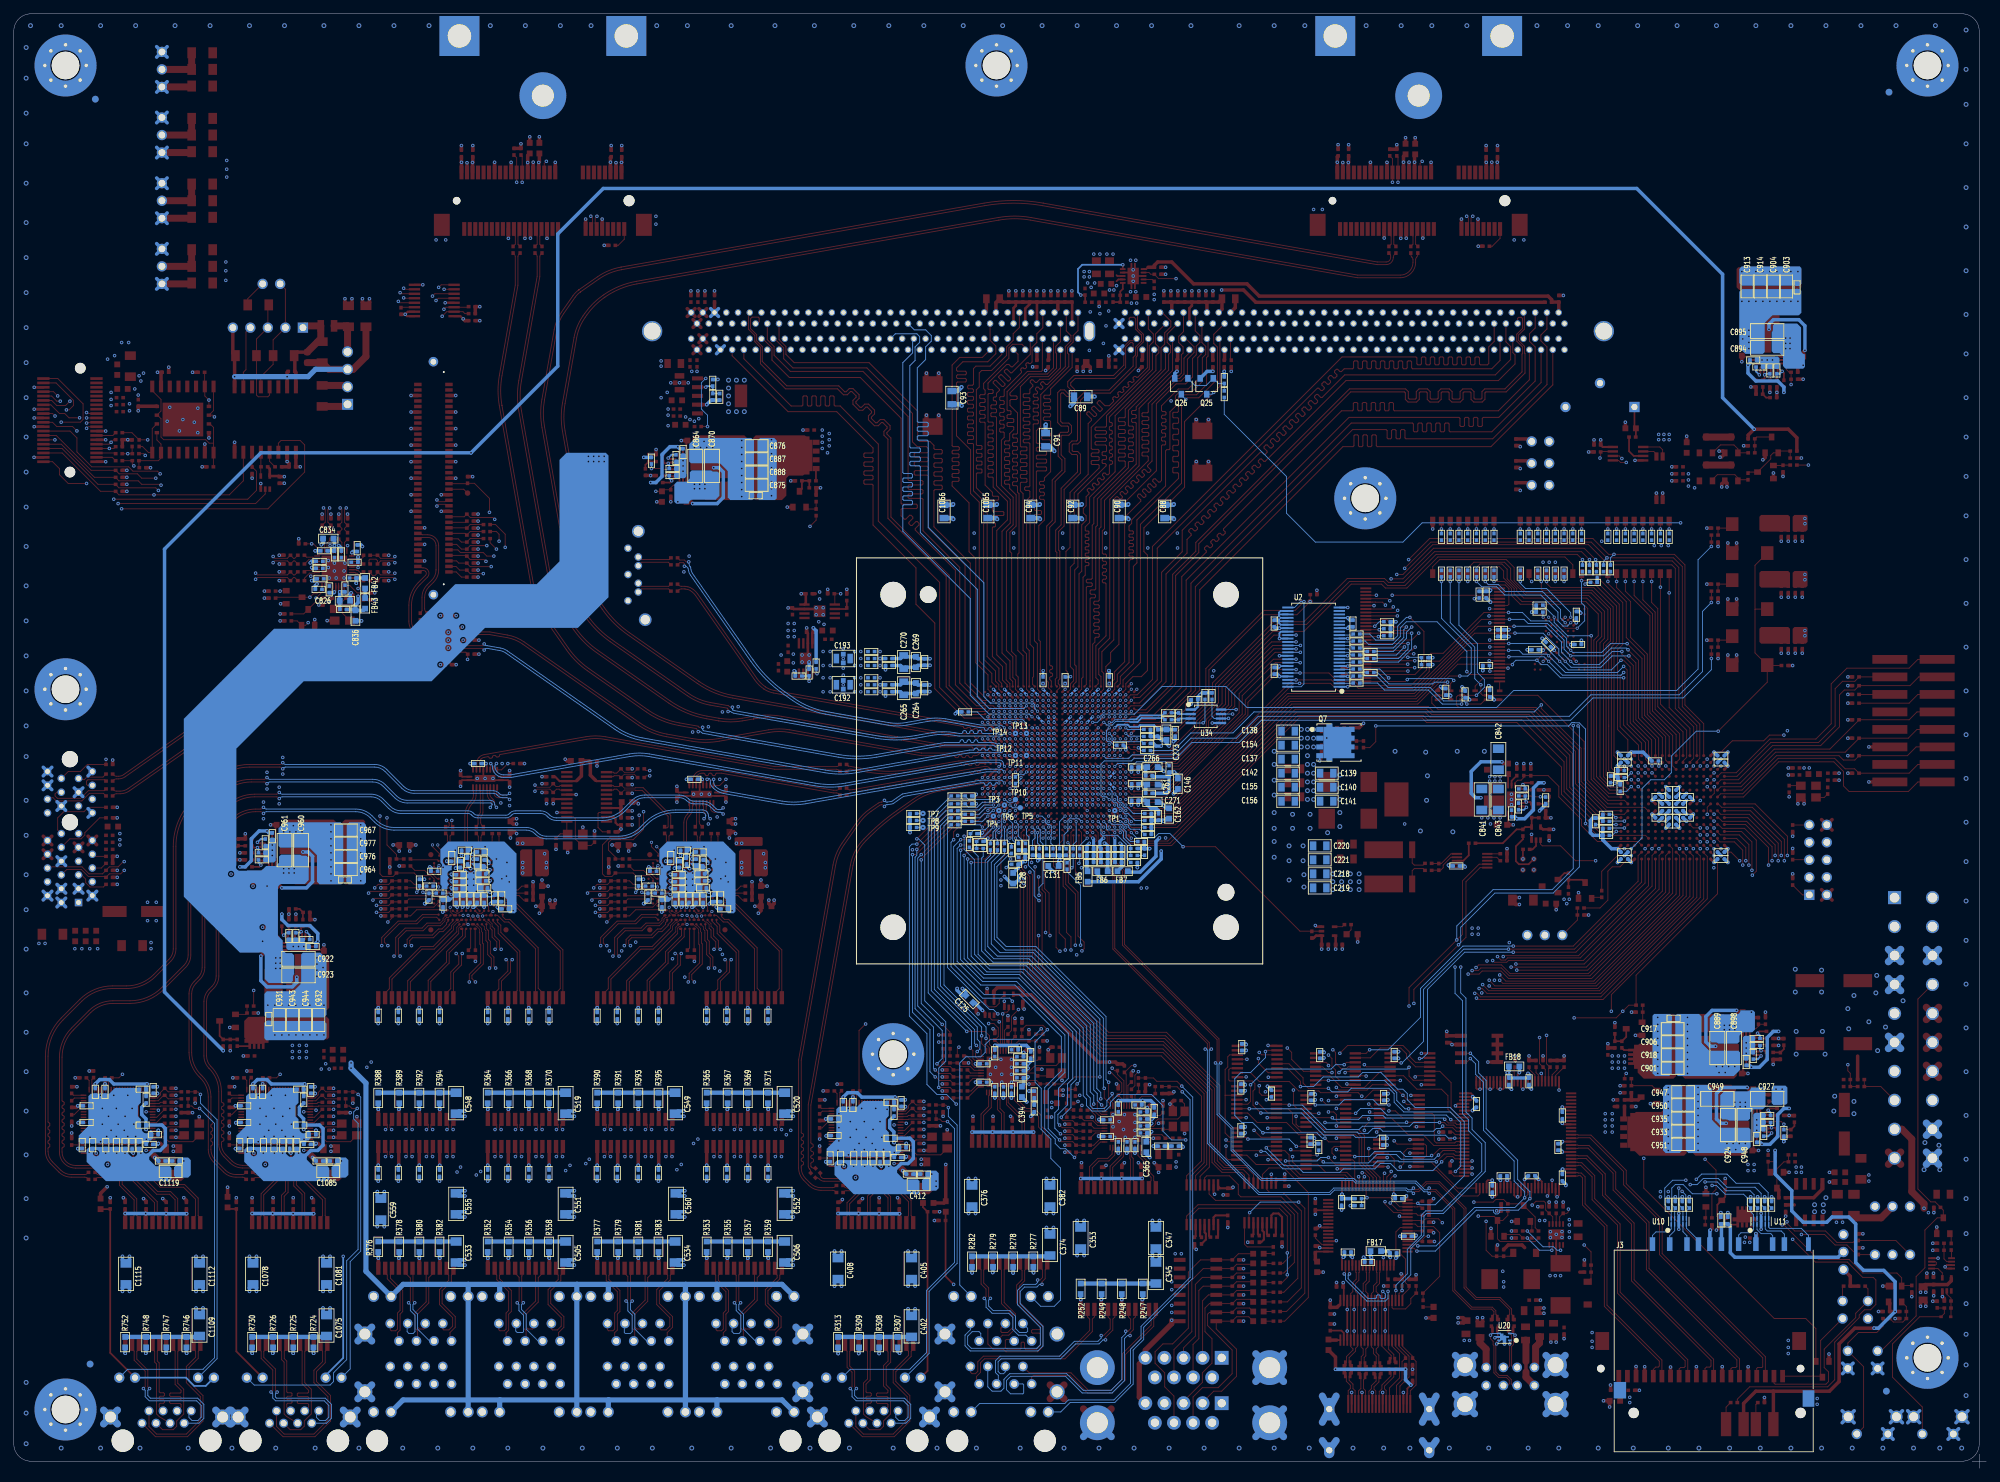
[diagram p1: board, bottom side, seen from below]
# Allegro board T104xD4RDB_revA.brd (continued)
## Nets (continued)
EMI1_MDIO_SLP: R139.2 U1.AH4(EMI1_MDIO) U42.31(MDIO) U81.1(A)
EVDD: C136.1 C1031.1 C1032.1 C1033.1 J2.3 Q17.2(S) Q19.2(S) R68.2 R69.2 R70.2 R71.2 R72.2 R73.2 R672.2 U1.L8(EVDD1)
EVDD_SEL: R677.1 U57.C2(IO_B1_C2)
EVT0_N: U1.D6(EVT0_B) U57.E13(IO_B2_E13)
EVT1_N: U1.C4(EVT1_B) U57.F13(IO_B2_F13)
EVT4_N: U1.C3(EVT4_B) U57.B14(IO_B2_B14)
EVT_BRD_ISO: R90.1 U1.A3(IRQ_OUT_B) U57.K16(IO_B2_K16)
EVT_PWR_EN: R94.1 U1.C1(EVT2_B) U57.L15(IO_B2_L15)
EVT_PWR_OK: R95.1 U1.C2(EVT3_B) U57.L16(IO_B2_L16)
FAN_PWM: R694.1 U57.R16(IO_B1_R16)
FAN_TACH: R696.1 U57.T15(IO_B1_T15)
GPIO_CKE_ISO: R87.1 U1.AC5(IRQ09) U57.P7(IO_B1_P7)
GVDD_EN_N: R662.1 U57.T11(IO_B1_T11)
HRESET_N: R105.2 U1.E8(HRESET_B) U57.F14(IO_B2_F14)
I2C1_SCL: Q2.2(S) R99.1 U1.W1(IIC1_SCL) U32.6(SCL) U35.15(SPC) U37.59(I2CCLK/DDREN)
I2C1_SCL_SLP: J1.141(SCL) Q2.3(D) R97.1 U31.6(SCL) U34.8(SCLK) U62.5(SCL) U79.9(SCLK_3.3)
I2C1_SDA: Q3.2(S) R98.1 U1.V1(IIC1_SDA) U32.5(SDA) U35.14(SPD) U37.60(I2CDAT/DSEL)
I2C1_SDA_SLP: J1.285(SDA) Q3.3(D) R96.1 U31.5(SDA) U34.7(SDATA) U62.4(SDA) U79.10(SDATA_3.3)
I2C2_HDMI_SCL: R205.1 U12.10(SC2) U36.17(DDC_CLK_IN)
I2C2_HDMI_SDA: R208.1 U12.9(SD2) U36.18(DDC_DAT_IN)
I2C2_MPEX1_SCL: J27.30(SMB_CLK) R442.1 U12.5(SC0)
I2C2_MPEX1_SDA: J27.32(SMB_DATA) R443.1 U12.4(SD0)
I2C2_MPEX2_SCL: J28.30(SMB_CLK) R453.1 U12.7(SC1)
I2C2_MPEX2_SDA: J28.32(SMB_DATA) R454.1 U12.6(SD1)
I2C2_PEX_SCL: J26.B5(SMCLK) R450.1 U12.12(SC3)
I2C2_PEX_SDA: J26.B6(SMDAT) R451.1 U12.11(SD3)
IFC_A5: R23.2 U7.1(I0)
IFC_A6: R24.2 U6.1(I0)
IFC_A7: R25.2 U5.1(I0)
IFC_A8: R26.2 U3.2(A22)
IFC_A9: R27.2 U3.15(A21)
IFC_A10: R28.2 U3.12(A20)
IFC_A11: R29.2 U3.11(A19)
IFC_A12: R30.2 U3.18(A18)
IFC_A13: R32.2 U3.19(A17)
IFC_A14: R34.2 U3.54(A16)
IFC_A15: R36.2 U3.3(A15)
IFC_A16: R6.2 SW2.5 U1.C5(IFC_A16) U3.4(A14) U57.D16(IO_B2_D16)
IFC_A17: R7.2 SW2.6 U1.C6(IFC_A17) U3.5(A13) U57.E15(IO_B2_E15)
IFC_A18: R8.2 SW2.3 U1.D7(IFC_A18) U3.6(A12)
IFC_A19: R13.2 SW2.4 U1.C7(IFC_A19) U3.7(A11)
IFC_A20: R16.2 R22.2 U1.D8(IFC_A20) U3.8(A10)
IFC_A21: SW2.7 U1.C8(IFC_A21) U3.9(A9)
IFC_A22: U1.D9(IFC_A22) U3.10(A8)
IFC_A23: U1.C9(IFC_A23) U3.20(A7)
IFC_A24: U1.D10(IFC_A24) U3.21(A6)
IFC_A25: U1.C10(IFC_A25) U3.22(A5)
IFC_A26: U1.E11(IFC_A26) U3.23(A4)
IFC_A27: U1.C11(IFC_A27) U3.24(A3) U57.C13(IO_B2_C13)
IFC_A28: U1.D11(IFC_A28) U3.25(A2) U57.C12(IO_B2_C12)
IFC_A29: U1.C12(IFC_A29) U3.26(A1) U57.C11(IO_B2_C11)
IFC_A30: U1.D12(IFC_A30) U3.31(A0) U57.D12(IO_B2_D12)
IFC_A31: U1.E12(IFC_A31) U57.A5(IO_B2_A5)
IFC_AD0: U1.A4(IFC_AD00) U3.51(DQ15/A-1) U4.J8(I/O7) U57.A13(IO_B2_A13)
IFC_AD1: U1.B5(IFC_AD01) U3.49(DQ14) U4.K7(I/O6) U57.B13(IO_B2_B13)
IFC_AD2: U1.A5(IFC_AD02) U3.47(DQ13) U4.J7(I/O5) U57.B12(IO_B2_B12)
IFC_AD3: U1.B6(IFC_AD03) U3.45(DQ12) U4.K6(I/O4) U57.A12(IO_B2_A12)
IFC_AD4: U1.A6(IFC_AD04) U3.42(DQ11) U4.K5(I/O3) U57.A11(IO_B2_A11)
IFC_AD5: U1.A7(IFC_AD05) U2.47(1D1) U3.40(DQ10) U4.K4(I/O2) U57.B11(IO_B2_B11)
IFC_AD6: U1.B8(IFC_AD06) U2.46(1D2) U3.38(DQ9) U4.J4(I/O1) U57.B10(IO_B2_B10)
IFC_AD7: U1.A8(IFC_AD07) U2.44(1D3) U3.36(DQ8) U4.H4(I/O0) U57.A10(IO_B2_A10)
IFC_AD8: SW1.1 U1.B9(IFC_AD08) U2.43(1D4) U3.50(DQ7) U57.A6(IO_B2_A6)
IFC_AD9: SW1.2 U1.A9(IFC_AD09) U2.41(1D5) U3.48(DQ6) U57.B7(IO_B2_B7)
IFC_AD10: SW1.3 U1.A10(IFC_AD10) U2.40(1D6) U3.46(DQ5) U57.A7(IO_B2_A7)
IFC_AD11: SW1.4 U1.B11(IFC_AD11) U2.38(1D7) U3.44(DQ4) U57.B8(IO_B2_B8)
IFC_AD12: SW1.5 U1.A11(IFC_AD12) U2.37(1D8) U3.41(DQ3) U57.A8(IO_B2_A8)
IFC_AD13: SW1.6 U1.B12(IFC_AD13) U2.36(2D1) U3.39(DQ2) U57.C8(IO_B2_C8)
IFC_AD14: SW1.7 U1.A12(IFC_AD14) U2.35(2D2) U3.37(DQ1) U57.A9(IO_B2_A9)
IFC_AD15: SW1.8 U1.A13(IFC_AD15) U2.33(2D3) U3.35(DQ0) U57.B9(IO_B2_B9)
IFC_AVD: R17.1 SW2.8 U1.D17(IFC_AVD) U2.25(LE2) U2.48(LE1) U4.C4(ALE)
IFC_CLE: SW2.1 U1.F16(IFC_CLE) U4.D5(CLE) U57.D15(IO_B2_D15)
IFC_CLK: R21.2 U57.J12(GCLK2P)
IFC_CS0_N: R12.1 U1.C13(IFC_CS0_B) U57.B6(IO_B2_B6)
IFC_CS1_N: R15.1 U1.E15(IFC_CS1_B) U57.B5(IO_B2_B5)
IFC_CS2_N: R11.1 U1.D16(IFC_CS2_B) U57.A4(IO_B2_A4)
IFC_NDWE_N: U1.D14(IFC_NDDDR_CLK) U4.C7(W\E\)
IFC_OE_N: R19.1 SW3.2 U1.D15(IFC_OE_B) U3.34(O\E\) U4.D4(R\E\) U57.G15(IO_B2_G15)
IFC_RB0_N: R10.1 U1.B15(IFC_RB0_B) U57.A15(IO_B2_A15)
IFC_RB1_N: R9.1 U1.A15(IFC_RB1_B) U57.B16(IO_B2_B16)
IFC_TE: SW2.2 U1.B14(IFC_TE)
IFC_VA5: U3.55(A25) U7.4(O)
IFC_VA6: U3.56(A24) U6.4(O)
IFC_VA7: U3.1(A23) U5.4(O)
IFC_WE_N: R20.1 SW3.1 U1.D13(IFC_WE0_B) U3.13(W\E\) U57.H15(IO_B2_H15)
IFC_WP_N: R18.1 SW3.3 U1.F17(IFC_WP0_B) U4.C3(W\P\) U57.F16(IO_B2_F16)
INA_VCORE_N: C853.2 R542.1 U62.9(VIN-)
INA_VCORE_P: C853.1 R541.1 U62.10(VIN+)
IO_B1: U57.B1(IO_B2_B1)
IO_B3: U57.B3(IO_B2_B3)
IO_D4: U57.D4(IO_B2_D4)
IO_D5: U57.D5(IO_B2_D5)
IO_G14: U57.G14(IO_B2_G14)
IO_H14: U57.H14(IO_B2_H14)
IO_J14: U57.J14(IO_B2_J14)
IO_K14: U57.K14(IO_B2_K14)
IO_L13: U57.L13(IO_B2_L13)
IO_L14: U57.L14(IO_B2_L14)
IO_M13: U57.M13(IO_B2_M13)
IO_M14: U57.M14(IO_B2_M14)
IO_M15: U57.M15(IO_B2_M15)
IO_N13: U57.N13(IO_B2_N13)
IO_N14: U57.N14(IO_B2_N14)
IO_N15: U57.N15(IO_B2_N15)
IO_N16: U57.N16(IO_B2_N16)
IOPWR_EN: C899.2 C957.2 R579.2 R615.2 R683.1 U57.K2(IO_B1_K2) U66.16(EN) U69.16(EN)
IOPWR_EN_N: R661.1 R663.1 R670.1 R722.1 U57.T2(IO_B1_T2)
ISO_DE: J42.4 U40.10(ISODE)
ISO_RXD_TXD_N: J42.3 R243.1 R244.2 U40.13(B)
ISO_RXD_TXD_P: J18.2 J42.2 R242.1 U40.12(A)
JTAG_TCK: U1.E18(TCK) U57.B4(IO_B2_B4)
JTAG_TDI: U1.A18(TDI) U57.C4(IO_B2_C4)
JTAG_TDO: U1.C18(TDO) U57.C6(IO_B2_C6)
JTAG_TMS: U1.B18(TMS) U57.C5(IO_B2_C5)
JTAG_TRST_N: U1.D19(TRST_B) U57.C7(IO_B2_C7)
LED_STATUS: R688.1 U57.H2(IO_B1_H2)
LVDS0_N: J13.5 U37.50(A0M)
LVDS0_P: J13.6 U37.49(A0P)
LVDS1_N: J13.8 U37.47(A1M)
LVDS1_P: J13.9 U37.46(A1P)
LVDS2_N: J13.11 U37.45(A2M)
LVDS2_P: J13.12 U37.44(A2P)
LVDS3_N: J13.17 U37.39(A3M)
LVDS3_P: J13.18 U37.38(A3P)
LVDS_CLK_N: J13.14 U37.42(CLK1M)
LVDS_CLK_P: J13.15 U37.41(CLK1P)
MPEX1_REFCLK_N: J27.13(REFCLK+) R507.2 R513.1
MPEX1_REFCLK_P: J27.11(REFCLK-) R505.1 R506.2
MPEX1_RST_N: J27.22(P\E\R\S\T\) U57.E4(IO_B1_E4)
MPEX1_RX_N: C738.2 U1.AG17(SD1_RX5_N)
MPEX1_RX_P: C737.2 U1.AH17(SD1_RX5_P)
MPEX1_TX_N: C740.2 U1.AE17(SD1_TX5_N)
MPEX1_TX_P: C739.2 U1.AD17(SD1_TX5_P)
MPEX2_REFCLK_N: J28.13(REFCLK+) R515.2 R517.2
MPEX2_REFCLK_P: J28.11(REFCLK-) R509.2 R514.2
MPEX2_RST_N: J28.22(P\E\R\S\T\) U57.E3(IO_B1_E3)
MPEX2_RX_N: C768.2 U1.AG19(SD1_RX6_N)
MPEX2_RX_P: C757.2 U1.AH19(SD1_RX6_P)
MPEX2_TX_N: C770.2 U1.AE19(SD1_TX6_N)
MPEX2_TX_P: C769.2 U1.AD19(SD1_TX6_P)
MVREF: C21.2 C22.1 C996.1 J1.146(VREFCA) U72.6(REFOUT)
NAND_CS_N: R53.1 U4.C6(C\E\) U57.G16(IO_B2_G16)
NAND_RB_N: R56.1 U4.C8(R/B\) U57.D11(IO_B2_D11)
NC1_12V: J1.1(NC1_12V)
NC13_12V: J1.145(NC13_12V)
NOR_CS_N: R50.1 U3.32(C\E\) U57.D13(IO_B2_D13)
NOR_RB_N: R54.1 U3.17(RDY/B\U\S\Y\) U57.E14(IO_B2_E14)
NOR_RST_N: R55.1 U3.14(R\E\S\E\T\) U57.C14(IO_B2_C14)
PEX_PRS_N: J26.B17(P\R\S\N\T\2\_X1) R449.1 U57.P5(IO_B1_P5)
PEX_REFCLK_N: J26.A14(REFCLK-) R501.2 R502.1
PEX_REFCLK_P: J26.A13(REFCLK+) R499.1 R500.2
PEX_RST_N: J26.A11(P\E\R\S\T\) U57.M4(IO_B1_M4)
PEX_RX_N: C748.2 U18.15(C0+)
PEX_RX_P: C741.2 U18.14(C0-)
PEX_SEL: R148.2 U18.9(SEL) U57.T4(IO_B1_T4)
PEX_TX_N: C750.2 U18.13(C1+)
PEX_TX_P: C749.2 U18.12(C1-)
PORESET_N: R104.2 U1.F13(PORESET_B) U57.C10(IO_B2_C10)
PROFI_MUX_CFG: U39.1(S) U57.R13(IO_B1_R13)
PROFI_PWR_OUT: L3.1 R236.2 U38.4(+VOUT)
PWR_EN_N: J37.14(P\S\_\O\N\) J39.1 Q29.3(C) R702.1
PWR_GOOD: C1048.1 R701.1 R704.2 U57.H1(IO_B1_H1)
PWR_RST_N: R700.2 U57.J2(IO_B1_J2) U76.2(R\E\S\E\T\)
QE_MUX_CFG0: U21.14(S0) U22.14(S0) U23.14(S0) U24.14(S0) U26.14(S0) U27.14(S0) U28.14(S0) U57.T13(IO_B1_T13)
QE_MUX_CFG1: U21.2(S1) U22.2(S1) U23.2(S1) U24.2(S1) U26.2(S1) U27.2(S1) U28.2(S1) U57.R12(IO_B1_R12)
QED_D0: U1.U2(TDMA_RXD) U21.7(1A)
QED_D1: U1.U1(TDMA_RSYNC) U21.9(2A)
QED_D2: U1.T1(TDMA_TXD) U23.7(1A)
QED_D3: U1.R1(TDMA_TSYNC) U23.9(2A)
QED_D4: U1.R2(TDMA_RQ) U26.7(1A)
QED_D5: U1.U4(TDMB_RXD) U26.9(2A)
QED_D6: U1.T3(TDMB_RSYNC) U28.7(1A)
QED_D7: U1.T4(TDMB_TXD) U28.9(2A)
QED_D8: U1.R3(TDMB_TSYNC) U22.7(1A)
QED_D9: U1.R4(TDMB_RQ) U22.9(2A)
QED_D10: U1.P4(CLK09) U24.7(1A)
QED_D11: U1.P3(CLK10) U24.9(2A)
QED_D12: U1.N4(CLK11) U27.7(1A)
QED_D13: R170.2 U27.9(2A)
QSG1_INT_N: R330.1 R331.2 U57.K3(IO_B1_K3)
QSG1_LED0: R361.1 U51.C3(LED0_PHY1)
QSG1_LED1: R363.1 U51.B2(LED1_PHY1)
QSG1_MDI0_N: T5.3 U51.B17(P1_D0N)
QSG1_MDI0_P: T5.2 U51.B18(P1_D0P)
QSG1_MDI1_N: T5.6 U51.C28(P1_D1N)
QSG1_MDI1_P: T5.5 U51.C29(P1_D1P)
QSG1_MDI2_N: T5.9 U51.B15(P1_D2N)
QSG1_MDI2_P: T5.8 U51.B16(P1_D2P)
QSG1_MDI3_N: T5.12 U51.C26(P1_D3N)
QSG1_MDI3_P: T5.11 U51.C27(P1_D3P)
QSG1_MDX0_N: J21.A2 T5.22
QSG1_MDX0_P: J21.A1 T5.23
QSG1_MDX1_N: J21.A6 T5.19
QSG1_MDX1_P: J21.A3 T5.20
QSG1_MDX2_N: J21.A5 T5.16
QSG1_MDX2_P: J21.A4 T5.17
QSG1_MDX3_N: J21.A8 T5.13
QSG1_MDX3_P: J21.A7 T5.14
QSG1_REFCLK_N: C443.1 R497.2 U58.4(Q0)
QSG1_REFCLK_P: C442.1 R496.2 U58.5(Q\0\)
QSG1_RST_N: R336.2 U51.B5(R\E\S\E\T\) U57.R1(IO_B1_R1)
QSG2_INT_N: R341.1 R342.2 U57.L3(IO_B1_L3)
QSG2_LED0: R373.1 U51.E2(LED0_PHY0)
QSG2_LED1: R375.1 U51.D1(LED1_PHY0)
QSG2_MDI0_N: T6.3 U51.D30(P0_D0N)
QSG2_MDI0_P: T6.2 U51.D31(P0_D0P)
QSG2_MDI1_N: T6.6 U51.C24(P0_D1N)
QSG2_MDI1_P: T6.5 U51.C25(P0_D1P)
QSG2_MDI2_N: T6.9 U51.C23(P0_D2N)
QSG2_MDI2_P: T6.8 U51.D29(P0_D2P)
QSG2_MDI3_N: T6.12 U51.C21(P0_D3N)
QSG2_MDI3_P: T6.11 U51.C22(P0_D3P)
QSG2_MDX0_N: J21.B2 T6.22
QSG2_MDX0_P: J21.B1 T6.23
QSG2_MDX1_N: J21.B6 T6.19
QSG2_MDX1_P: J21.B3 T6.20
QSG2_MDX2_N: J21.B5 T6.16
QSG2_MDX2_P: J21.B4 T6.17
QSG2_MDX3_N: J21.B8 T6.13
QSG2_MDX3_P: J21.B7 T6.14
QSG2_REFCLK_N: C476.1 R709.2 U58.21(Q3)
QSG2_REFCLK_P: C475.1 R708.2 U58.20(Q\3\)
QSG2_RST_N: R347.2 U52.B5(R\E\S\E\T\) U57.M3(IO_B1_M3)
QSG3_LED0: R385.1 U51.B4(LED0_PHY3)
QSG3_LED1: R387.1 U51.C6(LED1_PHY3)
QSG3_MDI0_N: T8.3 U51.C36(P3_D0N)
QSG3_MDI0_P: T8.2 U51.C1(P3_D0P)
QSG3_MDI1_N: T8.6 U51.D34(P3_D1N)
QSG3_MDI1_P: T8.5 U51.D35(P3_D1P)
QSG3_MDI2_N: T8.9 U51.C34(P3_D2N)
QSG3_MDI2_P: T8.8 U51.C35(P3_D2P)
QSG3_MDI3_N: T8.12 U51.D32(P3_D3N)
QSG3_MDI3_P: T8.11 U51.D33(P3_D3P)
QSG3_MDX0_N: J21.C2 T8.22
QSG3_MDX0_P: J21.C1 T8.23
QSG3_MDX1_N: J21.C6 T8.19
QSG3_MDX1_P: J21.C3 T8.20
QSG3_MDX2_N: J21.C5 T8.16
QSG3_MDX2_P: J21.C4 T8.17
QSG3_MDX3_N: J21.C8 T8.13
QSG3_MDX3_P: J21.C7 T8.14
QSG4_LED0: R396.1 U51.C5(LED0_PHY2)
QSG4_LED1: R397.1 U51.D5(LED1_PHY2)
QSG4_MDI0_N: T10.3 U51.C32(P2_D0N)
QSG4_MDI0_P: T10.2 U51.C33(P2_D0P)
QSG4_MDI1_N: T10.6 U51.B19(P2_D1N)
QSG4_MDI1_P: T10.5 U51.B20(P2_D1P)
QSG4_MDI2_N: T10.9 U51.A9(P2_D2N)
QSG4_MDI2_P: T10.8 U51.A10(P2_D2P)
QSG4_MDI3_N: T10.12 U51.C30(P2_D3N)
QSG4_MDI3_P: T10.11 U51.C31(P2_D3P)
QSG4_MDX0_N: J21.D2 T10.22
QSG4_MDX0_P: J21.D1 T10.23
QSG4_MDX1_N: J21.D6 T10.19
QSG4_MDX1_P: J21.D3 T10.20
QSG4_MDX2_N: J21.D5 T10.16
QSG4_MDX2_P: J21.D4 T10.17
QSG4_MDX3_N: J21.D8 T10.13
QSG4_MDX3_P: J21.D7 T10.14
QSG5_LED0: R360.1 U52.C3(LED0_PHY1)
QSG5_LED1: R362.1 U52.B2(LED1_PHY1)
QSG5_MDI0_N: T4.3 U52.B17(P1_D0N)
QSG5_MDI0_P: T4.2 U52.B18(P1_D0P)
QSG5_MDI1_N: T4.6 U52.C28(P1_D1N)
QSG5_MDI1_P: T4.5 U52.C29(P1_D1P)
QSG5_MDI2_N: T4.9 U52.B15(P1_D2N)
QSG5_MDI2_P: T4.8 U52.B16(P1_D2P)
QSG5_MDI3_N: T4.12 U52.C26(P1_D3N)
QSG5_MDI3_P: T4.11 U52.C27(P1_D3P)
QSG5_MDX0_N: J21.E2 T4.22
QSG5_MDX0_P: J21.E1 T4.23
QSG5_MDX1_N: J21.E6 T4.19
QSG5_MDX1_P: J21.E3 T4.20
QSG5_MDX2_N: J21.E5 T4.16
QSG5_MDX2_P: J21.E4 T4.17
QSG5_MDX3_N: J21.E8 T4.13
QSG5_MDX3_P: J21.E7 T4.14
QSG6_LED0: R372.1 U52.E2(LED0_PHY0)
QSG6_LED1: R374.1 U52.D1(LED1_PHY0)
QSG6_MDI0_N: T7.3 U52.D30(P0_D0N)
QSG6_MDI0_P: T7.2 U52.D31(P0_D0P)
QSG6_MDI1_N: T7.6 U52.C24(P0_D1N)
QSG6_MDI1_P: T7.5 U52.C25(P0_D1P)
QSG6_MDI2_N: T7.9 U52.C23(P0_D2N)
QSG6_MDI2_P: T7.8 U52.D29(P0_D2P)
QSG6_MDI3_N: T7.12 U52.C21(P0_D3N)
QSG6_MDI3_P: T7.11 U52.C22(P0_D3P)
QSG6_MDX0_N: J21.F2 T7.22
QSG6_MDX0_P: J21.F1 T7.23
QSG6_MDX1_N: J21.F6 T7.19
QSG6_MDX1_P: J21.F3 T7.20
QSG6_MDX2_N: J21.F5 T7.16
QSG6_MDX2_P: J21.F4 T7.17
QSG6_MDX3_N: J21.F8 T7.13
QSG6_MDX3_P: J21.F7 T7.14
QSG7_LED0: R384.1 U52.B4(LED0_PHY3)
QSG7_LED1: R386.1 U52.C6(LED1_PHY3)
QSG7_MDI0_N: T9.3 U52.C36(P3_D0N)
QSG7_MDI0_P: T9.2 U52.C1(P3_D0P)
QSG7_MDI1_N: T9.6 U52.D34(P3_D1N)
QSG7_MDI1_P: T9.5 U52.D35(P3_D1P)
QSG7_MDI2_N: T9.9 U52.C34(P3_D2N)
QSG7_MDI2_P: T9.8 U52.C35(P3_D2P)
QSG7_MDI3_N: T9.12 U52.D32(P3_D3N)
QSG7_MDI3_P: T9.11 U52.D33(P3_D3P)
QSG7_MDX0_N: J21.G2 T9.22
QSG7_MDX0_P: J21.G1 T9.23
QSG7_MDX1_N: J21.G6 T9.19
QSG7_MDX1_P: J21.G3 T9.20
QSG7_MDX2_N: J21.G5 T9.16
QSG7_MDX2_P: J21.G4 T9.17
QSG7_MDX3_N: J21.G8 T9.13
QSG7_MDX3_P: J21.G7 T9.14
QSG8_LED0: R398.1 U52.C5(LED0_PHY2)
QSG8_LED1: R399.1 U52.D5(LED1_PHY2)
QSG8_MDI0_N: T11.3 U52.C32(P2_D0N)
QSG8_MDI0_P: T11.2 U52.C33(P2_D0P)
QSG8_MDI1_N: T11.6 U52.B19(P2_D1N)
QSG8_MDI1_P: T11.5 U52.B20(P2_D1P)
QSG8_MDI2_N: T11.9 U52.A9(P2_D2N)
QSG8_MDI2_P: T11.8 U52.A10(P2_D2P)
QSG8_MDI3_N: T11.12 U52.C30(P2_D3N)
QSG8_MDI3_P: T11.11 U52.C31(P2_D3P)
QSG8_MDX0_N: J21.H2(G2) T11.22
QSG8_MDX0_P: J21.H1(G1) T11.23
QSG8_MDX1_N: J21.H6(G6) T11.19
QSG8_MDX1_P: J21.H3(G3) T11.20
QSG8_MDX2_N: J21.H5(G5) T11.16
QSG8_MDX2_P: J21.H4(G4) T11.17
QSG8_MDX3_N: J21.H8(G8) T11.13
QSG8_MDX3_P: J21.H7(G7) T11.14
QSG_SEL_N: R147.2 U16.9(SEL) U17.9(SEL) U57.L4(IO_B1_L4)
QSGMII1_RX_N: U16.19(B0+) U51.D13(QSGMII0_RXN)
QSGMII1_RX_P: U16.18(B0-) U51.D14(QSGMII0_RXP)
QSGMII1_TX_N: C434.1 U16.17(B1+)
QSGMII1_TX_P: C431.1 U16.16(B1-)
QSGMII2_RX_N: U17.19(B0+) U52.D13(QSGMII0_RXN)
QSGMII2_RX_P: U17.18(B0-) U52.D14(QSGMII0_RXP)
QSGMII2_TX_N: C470.1 U17.17(B1+)
QSGMII2_TX_P: C464.1 U17.16(B1-)
RESET_REQ_N: R106.2 U1.B3(RESET_REQ_B) U57.K15(IO_B2_K15)
RS232_CTS1: C280.1 FB11.2 J9.8 U33.2
RS232_CTS2: C289.1 FB15.2 J9.18 U33.1
RS232_RTS1: C281.1 FB10.2 J9.7 U33.4
RS232_RTS2: C290.1 FB14.2 J9.17 U33.7
RS232_RXD1: C282.1 FB9.2 J9.2 U33.5
RS232_RXD2: C291.1 FB13.2 J9.12 U33.8
RS232_TXD1: C283.1 FB8.2 J9.3 U33.3
RS232_TXD2: C292.1 FB12.2 J9.13 U33.6
RTC_INT_N: R80.1 R190.1 U1.E9(IRQ02) U31.7(SQW\I\N\T\)
SATA_RX_N: C773.1 U1.AG20(SD1_RX7_N)
SATA_RX_P: C774.1 U1.AH20(SD1_RX7_P)
SATA_TX_N: C772.1 U1.AE20(SD1_TX7_N)
SATA_TX_P: C771.1 U1.AD20(SD1_TX7_P)
SD_REFCLK1_N: R519.2 R520.1 U1.AA14(SD1_REF_CLK1_N)
SD_REFCLK1_P: R516.1 R518.2 U1.AB14(SD1_REF_CLK1_P)
SD_REFCLK2_N: C1055.2 R494.2 U58.1(Q\1\)
SD_REFCLK2_P: C1054.2 R495.2 U58.2(Q1)
SD_REFCLK_EN_N: R508.2 U57.P15(IO_B2_P15) U79.13(O\E\0\) U79.21(O\E\1\) U79.24(O\E\2\) U79.30(O\E\3\) U79.35(O\E\4\)
SD_RX2_N: C55.1 U16.3(A0+)
SD_RX2_P: C58.1 U16.4(A0-)
SD_RX3_N: C60.1 U17.3(A0+)
SD_RX3_P: C59.1 U17.4(A0-)
SD_RX4_N: U1.AG16(SD1_RX4_N) U18.3(A0+)
SD_RX4_P: U1.AH16(SD1_RX4_P) U18.4(A0-)
SD_TX2_N: U1.AE13(SD1_TX2_N) U16.7(A1+)
SD_TX2_P: U1.AD13(SD1_TX2_P) U16.8(A1-)
SD_TX3_N: U1.AE14(SD1_TX3_N) U17.7(A1+)
SD_TX3_P: U1.AD14(SD1_TX3_P) U17.8(A1-)
SD_TX4_N: U1.AE16(SD1_TX4_N) U18.7(A1+)
SD_TX4_P: U1.AD16(SD1_TX4_P) U18.8(A1-)
SDHC_CD_N: J3.10(I\N\S\E\R\T\) R74.1 U1.L5(SDHC_CD_B) U10.4 U10.5
SDHC_CLK: J3.5(CLK/SCLK) R67.2 R72.1 U11.1 U11.8
SDHC_CMD: J3.2(CMD/DIN) R73.1 U1.K3(SDHC_CMD) U10.3 U10.6
SDHC_DAT0: J3.7(D0/DOUT) R69.1 U1.L2(SDHC_DAT0) U11.2 U11.7
SDHC_DAT1: J3.8(D1/RSV) R68.1 U1.K4(SDHC_DAT1) U11.3 U11.6
SDHC_DAT2: J3.9(D2/RSV) R70.1 U1.L3(SDHC_DAT2) U10.1 U10.8
SDHC_DAT3: J3.1(D3/C\S\) R71.1 U1.L1(SDHC_DAT3) U10.2 U10.7
SDHC_VS: R81.1 U1.D1(IRQ03) U57.M16(IO_B2_M16)
SDHC_WP: J3.11(P\R\O\T\E\C\T\) R75.1 U1.M5(SDHC_WP) U11.4 U11.5
SENSEGND: TP18.1(TP) U1.G20(SENSEGND)
SENSEGNDC: TP16.1(TP) U1.AB10(SENSEGNDC)
SENSEVDD: R551.1 TP17.1(TP) U1.G19(SENSEVDD)
SENSEVDD_EN_N: U57.H3(IO_B1_H3) U61.1(O\E\)
SENSEVDDC: R550.1 TP15.1(TP) U1.AB9(SENSEVDDC)
SG1_INT_N: R739.2 U57.P2(IO_B1_P2)
SG1_LED0: R733.1 R738.2 U82.68(LED0/PHY_AD0)
SG1_LED1: R734.1 R736.2 U82.69(LED1/PHY_AD1)
SG1_MDI0_N: T12.11 U82.2(MDIN0)
SG1_MDI0_P: T12.12 U82.1(MDIP0)
SG1_MDI1_N: T12.8 U82.5(MDIN1)
SG1_MDI1_P: T12.9 U82.4(MDIP1)
SG1_MDI2_N: T12.5 U82.8(MDIN2)
SG1_MDI2_P: T12.6 U82.7(MDIP2)
SG1_MDI3_N: T12.2 U82.11(MDIN3)
SG1_MDI3_P: T12.3 U82.10(MDIP3)
SG1_MDX0_N: J40.2 T12.14
SG1_MDX0_P: J40.1 T12.13
SG1_MDX1_N: J40.6 T12.17
SG1_MDX1_P: J40.3 T12.16
SG1_MDX2_N: J40.5 T12.20
SG1_MDX2_P: J40.4 T12.19
SG1_MDX3_N: J40.8 T12.23
SG1_MDX3_P: J40.7 T12.22
SG1_RST_N: R740.2 U57.R3(IO_B1_R3) U82.52(P\H\Y\R\S\T\)
SG2_INT_N: R761.2 U57.N3(IO_B1_N3)
SG2_LED0: R755.1 R760.2 U83.68(LED0/PHY_AD0)
SG2_LED1: R756.1 R758.2 U83.69(LED1/PHY_AD1)
SG2_MDI0_N: T13.11 U83.2(MDIN0)
SG2_MDI0_P: T13.12 U83.1(MDIP0)
SG2_MDI1_N: T13.8 U83.5(MDIN1)
SG2_MDI1_P: T13.9 U83.4(MDIP1)
SG2_MDI2_N: T13.5 U83.8(MDIN2)
SG2_MDI2_P: T13.6 U83.7(MDIP2)
SG2_MDI3_N: T13.2 U83.11(MDIN3)
SG2_MDI3_P: T13.3 U83.10(MDIP3)
SG2_MDX0_N: J41.2 T13.14
SG2_MDX0_P: J41.1 T13.13
SG2_MDX1_N: J41.6 T13.17
SG2_MDX1_P: J41.3 T13.16
SG2_MDX2_N: J41.5 T13.20
SG2_MDX2_P: J41.4 T13.19
SG2_MDX3_N: J41.8 T13.23
SG2_MDX3_P: J41.7 T13.22
SG2_RST_N: R763.2 U57.P4(IO_B1_P4) U83.52(P\H\Y\R\S\T\)
SG_INT_N: R86.1 R323.2 U1.AB1(IRQ08)
SG_LED0: R316.1 R321.2 U48.68(LED0/PHY_AD0)
SG_LED1: R317.1 R319.2 U48.69(LED1/PHY_AD1)
SG_MDI0_N: T3.11 U48.2(MDIN0)
SG_MDI0_P: T3.12 U48.1(MDIP0)
SG_MDI1_N: T3.8 U48.5(MDIN1)
SG_MDI1_P: T3.9 U48.4(MDIP1)
SG_MDI2_N: T3.5 U48.8(MDIN2)
SG_MDI2_P: T3.6 U48.7(MDIP2)
SG_MDI3_N: T3.2 U48.11(MDIN3)
SG_MDI3_P: T3.3 U48.10(MDIP3)
SG_MDX0_N: J20.2 T3.14
SG_MDX0_P: J20.1 T3.13
SG_MDX1_N: J20.6 T3.17
SG_MDX1_P: J20.3 T3.16
SG_MDX2_N: J20.5 T3.20
SG_MDX2_P: J20.4 T3.19
SG_MDX3_N: J20.8 T3.23
SG_MDX3_P: J20.7 T3.22
SG_RST_N: R325.2 U48.52(P\H\Y\R\S\T\) U57.N2(IO_B1_N2)
SGMII1_RX_N: U16.15(C0+) U82.18(HSON)
SGMII1_RX_P: U16.14(C0-) U82.17(HSOP)
SGMII1_TX_N: C1077.2 U16.13(C1+)
SGMII1_TX_P: C1076.2 U16.12(C1-)
SGMII2_RX_N: U17.15(C0+) U83.18(HSON)
SGMII2_RX_P: U17.14(C0-) U83.17(HSOP)
SGMII2_TX_N: C1111.2 U17.13(C1+)
SGMII2_TX_P: C1110.2 U17.12(C1-)
SGMII_RX_N: C57.1 U48.18(HSON)
SGMII_RX_P: C56.1 U48.17(HSOP)
SGMII_TX_N: C404.2 U1.AE11(SD1_TX1_N)
SGMII_TX_P: C403.2 U1.AD11(SD1_TX1_P)
SINGLE_CLK_EN_N: R485.2 U57.P14(IO_B2_P14) U79.38(O\E\5\) X1.1(OE) X2.1(OE) X3.1(OE)
SPI_CLK: R65.2 R66.1 R200.2
SPI_CS0_N: R60.1 U1.M1(SPI_CS0_B) U8.7(C\S\) U9.1(C\S\)
SPI_MISO: R58.1 R61.1 R201.2 U1.P1(SPI_MISO)
SPI_MOSI: R64.1 R202.2 U1.P2(SPI_MOSI)
SYS_REFCLK: R484.2 R486.2 U1.G15(SYSCLK)
SYS_REFCLK_N: R524.2 R527.2 U1.F14(DIFF_SYSCLK_B)
SYS_REFCLK_P: R521.2 R522.2 U1.G14(DIFF_SYSCLK)
TDMA_RCK_CLK8_12: J11.21 U27.13(2B4)
TDMA_RQ: J11.3 U26.3(1B4)
TDMA_RSYNC: J11.11 U21.13(2B4)
TDMA_RXD: J11.13 U21.3(1B4)
TDMA_TCK_CLK9: J11.17 U24.3(1B4)
TDMA_TSYNC: J11.9 U23.13(2B4)
TDMA_TXD: J11.7 U23.3(1B4)
TDMB_RCK_CLK10: J11.29 U24.13(2B4)
TDMB_RQ: J11.24 U22.13(2B4)
TDMB_RSYNC: J11.18 U28.3(1B4)
TDMB_RXD: J11.1 U26.13(2B4)
TDMB_TCK_CLK11: J11.39 U27.3(1B4)
TDMB_TSYNC: J11.22 U22.3(1B4)
TDMB_TXD: J11.20 U28.13(2B4)
TDMR1_INT_N: J11.31 R197.2 U57.P11(IO_B1_P11)
TDMR2_INT_N: J11.33 R198.2 U57.P10(IO_B1_P10)
TDMR_PRS_N: J11.27 R196.2 U57.P12(IO_B1_P12)
TDMR_RST_N: J11.35 R199.2 U40.7(PV) U57.P8(IO_B1_P8)
TDMR_SLP_N: J11.25 U57.R14(IO_B1_R14)
TDMR_SPI_CS0_N: J11.32 R63.1 U1.M2(SPI_CS1_B)
TDMR_SPI_CS1_N: J11.34 R62.1 U1.M3(SPI_CS2_B)
TEMP_DIODE_N: R194.1 U1.G21(TD1_CATHODE)
TEMP_DIODE_P: R193.1 U1.E21(TD1_ANODE)
TEST_SEL_N: R92.1 SW3.8 U1.G8(TEST_SEL_B) U57.E16(IO_B2_E16)
THERM_ALERT_N: R192.1 U34.6(A\L\E\R\T\/T\H\E\R\M\2\) U57.C3(IO_B1_C3)
THERM_FAULT_N: R195.1 U34.4(T\H\E\R\M\) U57.F3(IO_B1_F3)
UART1_CTS_N: U1.Y2(UART1_CTS_B) U29.9(R2-OUT)
UART1_RTS_N: U1.Y1(UART1_RTS_B) U29.10(T2-IN)
UART1_RXD: U1.AA1(UART1_SIN) U29.12(R1-OUT)
UART1_TXD: U1.AA2(UART1_SOUT) U29.11(T1-IN)
UART2_CTS_N: U1.Y4(UART2_CTS_B) U30.9(R2-OUT)
UART2_RTS_N: U1.V4(UART2_RTS_B) U30.10(T2-IN)
UART2_RXD: U1.W4(UART2_SIN) U30.12(R1-OUT)
UART2_TXD: U1.AA4(UART2_SOUT) U30.11(T1-IN)
UC1_CDBRXER: R240.2 U26.4(1B3)
UC1_CTS_N: U21.12(2B3) U39.11(3B1)
UC1_RTS_N: U23.12(2B3) U39.14(4B1)
UC1_RXD: U21.4(1B3) U39.2(1B1)
UC1_TXD: U23.4(1B3) U39.5(2B1)
UC3_CDBRXER: R239.2 U22.12(2B3)
UC3_CTS_N: U28.4(1B3) U39.10(3B2)
UC3_RTS_N: U22.4(1B3) U39.13(4B2)
UC3_RXD: U26.12(2B3) U39.3(1B2)
UC3_TXD: U28.12(2B3) U39.6(2B2)
USB1_DM: J5.6 L1.2 R163.2 U20.6
USB1_DP: J5.7 L1.3 R162.2 U20.4
USB1_FLG_N: Q4.1(G) R151.2 R153.1 U19.9(F\L\T\A\)
USB1_PWREN: R157.2 U1.F6(USB1_DRVVBUS) U19.2(ONA)
USB1_VBUS: FB1.1 J5.5
USB1_VBUSCLMP: D3.2 R158.1 R161.2 U1.E4(USB1_VBUSCLMP)
USB2_DM: J5.2 L2.2 R165.2 U20.3
USB2_DP: J5.3 L2.3 R164.2 U20.1
USB2_FLG_N: Q5.1(G) R152.1 R155.2 U19.7(F\L\T\B\)
USB2_PWREN: R156.2 U1.J5(USB2_DRVVBUS) U19.4(ONB)
USB2_VBUS: FB3.1 J5.1
USB2_VBUSCLMP: D2.2 R154.1 R160.2 U1.J4(USB2_VBUSCLMP)
USB_REFCLK: R489.2 R490.2 U1.F8(USBCLK)
VCORE: C137.1 C138.1 C139.1 C140.1 C141.1 C142.1 C143.1 C145.1 C153.1 C154.1 C155.1 C156.1 C165.1 C166.1 C167.1 C168.1 C169.1 C171.1 C172.1 C173.1 C175.1 C176.1 C177.1 C178.1 C179.1 C180.1 C181.1 C182.1 C184.1 C185.1 C186.1 C187.1 C188.1 C189.1 C190.1 C191.1 C194.1 C195.1 C196.1 C197.1 C198.1 C199.1 C200.1 C201.1 C202.1 C203.1 C204.1 C205.1 C206.1 C207.1 C208.1 J8.2 Q7.1 Q7.2 Q7.3 R540.2 U1.K15(VDD01) U1.K17(VDD02) U1.K19(VDD03) U1.L12(VDD04) U1.L14(VDD05) U1.L16(VDD06) U1.L18(VDD07) U1.L20(VDD08) U1.M9(VDD09) U1.M13(VDD10) U1.M15(VDD11) U1.M17(VDD12) U1.M19(VDD13) U1.N12(VDD14) U1.N14(VDD15) U1.N16(VDD16) U1.N18(VDD17) U1.N20(VDD18) U1.P9(VDD19) U1.P11(VDD20) U1.P13(VDD21) U1.P15(VDD22) U1.P17(VDD23) U1.P19(VDD24) U1.R12(VDD25) U1.R14(VDD26) U1.R16(VDD27) U1.R18(VDD28) U1.R20(VDD29) U1.T9(VDD30) U1.T13(VDD31) U1.T15(VDD32) U1.T17(VDD33) U1.T19(VDD34) U1.U14(VDD35) U1.U16(VDD36) U1.U18(VDD37) U1.U20(VDD38) U1.V9(VDD39) U1.V13(VDD40) U1.V15(VDD41) U1.V17(VDD42) U1.V19(VDD43) U1.W14(VDD44) U1.Y8(VDD45) U1.Y9(VDD46) U1.Y11(VDD47)
VCORE_EN: C846.2 R538.2 U57.P13(IO_B1_P13) U60.16(EN)
VCORE_PGOOD: R539.2 U57.J3(IO_B1_J3) U60.3(PGOOD)
VCORE_SLP: C218.1 C219.1 C220.1 C221.1 C226.1 C227.1 C228.1 C229.1 C230.1 C231.1 C232.1 C233.1 C234.1 FB5.2 Q7.5 R534.4 U1.K11(VDDC01) U1.K13(VDDC02) U1.L10(VDDC03) U1.M11(VDDC04) U1.N10(VDDC05) U1.R10(VDDC06) U1.T11(VDDC07) U1.U10(VDDC08) U1.U12(VDDC09) U1.V11(VDDC10) U1.W10(VDDC11) U1.W12(VDDC12)
VPP: C1014.2 C1019.1 C1020.1 C1021.1 C1022.1 C1023.1 C1024.1 J1.142(VPP1) J1.143(VPP2) J1.286(VPP3) J1.287(VPP4) J1.288(VPP5)
VPP_EN: R648.1 U57.R10(IO_B1_R10) U74.5(EN)
VTT: C24.1 C25.1 C26.1 C27.1 C28.1 C998.1 C999.1 J1.77(VTT1) J1.221(VTT2) R631.2 U72.3(VO)
VTT_EN: R642.1 U57.D3(IO_B1_D3) U72.7(EN)
XVDD: C193.2 C237.1 C238.1 C239.1 C240.1 C241.1 C242.1 C243.1 C244.1 R146.1 U1.AC9(X1VDD1) U1.AC12(X1VDD2) U1.AC15(X1VDD3) U1.AC18(X1VDD4) U1.AC21(X1VDD5)
XVDD_EN: R650.1 U57.R11(IO_B1_R11) U75.5(EN)
N16747459: R1.2 U1.U28(D1_MDIC1)
N16747463: R2.2 U1.P28(D1_MDIC0)
N16770065: R4.2 U1.F20(D1_MVREF)
N16800565: R52.1 U3.53(B\Y\T\E\)
N16800570: R51.1 U3.16(W\P\/ACC)
N16821274: R21.1 U1.A17(IFC_CLK0)
N16821816: R14.1 U1.E14(IFC_PERR_B)
N16870296: C345.1 R247.2 R248.2 R249.2 R252.2
N16870380: C339.2 C341.2 C342.2 C344.2 T1.1 T1.4 T1.7 T1.10
N16870836: C349.1 J19.B9 R259.2
N16870842: C348.1 J19.B11 R260.2
N16891950: R307.1 T3.15
N16891952: C402.1 R307.2 R308.2 R309.2 R313.2
N16891962: R308.1 T3.18
N16891966: R309.1 T3.21
N16891978: R313.1 T3.24
N16892036: C397.2 C399.2 C400.2 C401.2 T3.1 T3.4 T3.7 T3.10
N16892171: C398.1 FB21.2 J20.9
N16892215: C407.1 J20.10 R316.2
N16892219: C406.1 J20.11 R317.2
N16892768: R311.2 U48.43(RXD7/AN0)
N16892846: R312.2 U48.44(RXER/AN1)
N16894213: R314.2 U48.46(CRS/MII1)
N16894217: R315.2 U48.45(COL/MII0)
N16894418: R323.1 U48.75(I\N\T\)
N16899326: C403.1 U48.13(HSIP)
N16899338: C404.1 U48.14(HSIN)
N16900249: R318.1 U48.70(LED2/MDI0)
N16900569: R320.1 U48.71(LED3/MDI1)
N16900702: C409.1 U48.81(CKXTAL1) Y4.1
N16900720: C410.1 U48.82(CKXTAL2) Y4.3
N16902304: R324.2 U48.77(ENSWREG)
N16902556: R328.2 U48.26(REXT)
N16903120: R327.2 U48.78(RSET)
N16909680: L6.1 R326.1 U48.88(REG_OUT)
N16909742: C411.1 R326.2
N16927443: R310.2 U48.39(RXD4/SELRGV)
N16974225: R277.1 T2.15
N16974227: C374.1 R277.2 R278.2 R279.2 R282.2
N16974244: R278.1 T2.18
N16974248: R279.1 T2.21
N16974260: R282.1 T2.24
N16974504: C369.1 FB20.2 J19.A9
N16974534: C378.1 J19.A10 R289.2
N16974536: C377.1 J19.A11 R290.2
N16984231: C739.1 J27.33(PETP0)
N16984233: C740.1 J27.31(PETN0)
N16984263: C737.1 J27.25(PERP0)
N16984265: C738.1 J27.23(PERN0)
N16985354: C769.1 J28.33(PETP0)
N16985356: C770.1 J28.31(PETN0)
N16985386: C757.1 J28.25(PERP0)
N16985388: C768.1 J28.23(PERN0)
N17055310: C277.1 U29.2(V+)
N17055339: C279.1 U29.6(V-)
N17055373: C275.2 U29.1(C1+)
N17055376: C275.1 U29.3(C1-)
N17055394: C278.2 U29.4(C2+)
N17055396: C278.1 U29.5(C2-)
N17055419: R182.1 U29.14(T1-OUT)
N17055422: R183.1 U29.13(R1-IN)
N17055459: R185.1 U29.8(R2-IN)
N17055461: R184.1 U29.7(T2-OUT)
N17055495: FB8.1 R182.2
N17055507: FB9.1 R183.2
N17055527: FB10.1 R184.2
N17055529: FB11.1 R185.2
N17056698: C287.1 U30.2(V+)
N17056714: C288.1 U30.6(V-)
N17056740: C284.2 U30.1(C1+)
N17056750: C284.1 U30.3(C1-)
N17056764: C286.2 U30.4(C2+)
N17056766: C286.1 U30.5(C2-)
N17056776: R186.1 U30.14(T1-OUT)
N17056778: R187.1 U30.13(R1-IN)
N17056796: R189.1 U30.8(R2-IN)
N17056798: R188.1 U30.7(T2-OUT)
N17056816: FB12.1 R186.2
N17056834: FB13.1 R187.2
N17056844: FB14.1 R188.2
N17056846: FB15.1 R189.2
N17059126: R124.1 U1.AE7(EC2_TXD0)
N17059132: R126.1 U1.AF7(EC2_TXD1)
N17059135: R128.1 U1.AF6(EC2_TXD2)
N17059138: R130.1 U1.AG5(EC2_TXD3)
N17059149: R134.1 R136.1 U1.AF8(EC2_TX_CTL)
N17059152: C52.1 R137.1 U1.AE8(EC2_GTX_CLK)
N17059732: R129.2 U1.AC3(EC1_TXD3)
N17059733: R125.2 U1.AE4(EC1_TXD1)
N17059734: R127.2 U1.AD3(EC1_TXD2)
N17059735: R133.2 U1.AE3(EC1_TXD0)
N17059985: R131.2 R135.2 U1.AF4(EC1_TX_CTL)
N17060054: C51.2 R132.2 U1.AF3(EC1_GTX_CLK)
N17060498: R138.2 U1.AH3(EMI1_MDC)
N17072443: R115.2 TP2.1(TP) U1.B17(RTC)
N17081955: C56.2 U1.AH11(SD1_RX1_P)
N17081957: C57.2 U1.AG11(SD1_RX1_N)
N17082045: C55.2 U1.AG13(SD1_RX2_N)
N17082047: C58.2 U1.AH13(SD1_RX2_P)
N17082121: C59.2 U1.AH14(SD1_RX3_P)
N17082123: C60.2 U1.AG14(SD1_RX3_N)
N17082287: C1054.1 U1.AB18(SD1_REF_CLK2_P)
N17082300: C1055.1 U1.AA18(SD1_REF_CLK2_N)
N17082319: R146.2 U1.Y20(SD1_IMP_CAL_TX)
N17082346: R145.2 U1.AA12(SD1_IMP_CAL_RX)
N17093364: R144.2 TP9.1(TP) U1.AE5(TSEC_1588_TRIG_IN2)
N17093369: R143.2 TP8.1(TP) U1.AB6(TSEC_1588_TRIG_IN1)
N17093378: R142.2 TP7.1(TP) U1.AC8(TSEC_1588_CLK_IN)
N17111815: J27.1(W\A\K\E\) R446.1
N17112169: J28.1(W\A\K\E\) R455.1
N17113140: R100.1 U1.V2(IIC3_SCL)
N17113141: R102.1 U1.W3(IIC3_SDA)
N17113153: R101.2 U1.V3(IIC2_SCL) U12.14(SCL)
N17113154: R103.2 U1.Y3(IIC2_SDA) U12.15(SDA)
N17113208: R107.2 U12.3(R\E\S\E\T\)
N17113211: R113.2 U1.C20(FA_ANALOG_G_V)
N17113215: R114.2 U1.B20(FA_ANALOG_PIN)
N17113217: R93.1 U1.F9(SCAN_MODE_B)
N17170143: C797.1 R484.1 X1.3(OUT)
N17200088: R59.1 U8.1(H\O\L\D\) U8.9(W\P\) U9.3(W\P\) U9.7(H\O\L\D\)
N17200106: R66.2 U8.16(SCK) U9.6(SCK)
N17200115: R61.2 U8.8(SO) U9.2(SO)
N17200136: R65.1 U1.N1(SPI_CLK)
N17200150: R67.1 U1.K1(SDHC_CLK)
N17200329: R57.1 R64.2 U8.15(SI) U9.5(SI)
N17208058: R108.2 U1.P5(DMA1_DREQ0_B)
N17208122: R109.2 U1.V5(DMA2_DREQ0_B)
N17232338: C802.1 R487.1 X2.3(OUT)
N17246054: Q4.3(D) R150.1 R151.1 U1.F5(USB1_PWRFAULT)
N17246089: Q5.3(D) R149.1 R155.1 U1.H5(USB2_PWRFAULT)
N17246488: R159.2 U19.3(ISET)
N17246514: L1.4 R162.1 U1.F1(USB1_UDP)
N17246518: L1.1 R163.1 U1.F2(USB1_UDM)
N17246522: L2.4 R164.1 U1.H1(USB2_UDP)
N17246524: L2.1 R165.1 U1.H2(USB2_UDM)
N17246685: R168.2 U1.F4(USB1_UID)
N17246689: R167.2 U1.H4(USB2_UID)
N17246719: C78.1 R166.2 U1.G4(USB_IBIAS_REXT)
N17246771: C78.2 R169.2
N17246861: FB4.1 J5.4
N17246863: FB2.1 J5.8
N17249127: C748.1 J26.A17(PERN0)
N17249129: C741.1 J26.A16(PERP0)
N17249144: J26.B11(W\A\K\E\) R452.1
N17249162: J26.A8(JTAG5_TMS) R445.1
N17249180: J26.B9(JTAG1_T\R\S\T\) R444.1
N17249182: J26.A5(JTAG2_TCK) R447.1
N17249192: J26.A6(JTAG3_TDI) R448.1
N17249250: C750.1 J26.B15(PETN0)
N17249252: C749.1 J26.B14(PETP0)
N17251651: C867.2 L9.1 R564.2 R566.1 U64.12(PHASE)
N17251653: C878.2 C880.2 R566.2
N17251663: C880.1 R567.1 R574.2 U64.5(FB)
N17251677: C885.1 R570.1 U64.8(3VCBP)
N17251680: R570.2 R572.2 U64.1(FCCM)
N17251691: C886.1 U64.6(SS)
N17251709: R558.2 U64.15(FF)
N17251715: C867.1 U64.14(BOOT)
N17251719: R564.1 U64.2(ISET)
N17251739: C890.2 L11.1 R578.2 R584.1 U65.12(PHASE)
N17251740: C908.2 C910.2 R584.2
N17251749: C910.1 R586.1 R592.2 U65.5(FB)
N17251753: R578.1 U65.2(ISET)
N17251755: R585.2 U65.3(PGOOD)
N17251758: C900.2 R583.2 U65.16(EN)
N17251765: C915.1 R588.1 U65.8(3VCBP)
N17251768: R588.2 R590.2 U65.1(FCCM)
N17251782: C916.1 U65.6(SS)
N17251797: R576.2 U65.15(FF)
N17251803: C890.1 U65.14(BOOT)
N17251826: C930.2 L13.1 R599.1 R603.2 U68.12(PHASE)
N17251827: C938.2 C940.2 R599.2
N17251836: C940.1 R600.1 R610.2 U68.5(FB)
N17251840: R603.1 U68.2(ISET)
N17251850: C929.2 R598.2 U68.16(EN)
N17251857: C945.1 R606.1 U68.8(3VCBP)
N17251860: R606.2 R608.2 U68.1(FCCM)
N17251871: C946.1 U68.6(SS)
N17251886: R594.2 U68.15(FF)
N17251892: C930.1 U68.14(BOOT)
N17251915: C919.2 L12.1 R595.2 R597.1 U67.12(PHASE)
N17251916: C937.2 C939.2 R597.2
N17251925: C939.1 R602.1 R609.2 U67.5(FB)
N17251929: R595.1 U67.2(ISET)
N17251934: R601.2 U67.3(PGOOD)
N17251937: C928.2 R596.2 U67.16(EN)
N17251944: C941.1 R605.1 U67.8(3VCBP)
N17251947: R605.2 R607.2 U67.1(FCCM)
N17251958: C942.1 U67.6(SS)
N17251973: R593.2 U67.15(FF)
N17251979: C919.1 U67.14(BOOT)
N17252002: C896.2 L10.1 R577.2 R580.1 U66.12(PHASE)
N17252003: C902.2 C909.2 R580.2
N17252012: C909.1 R582.1 R591.2 U66.5(FB)
N17252016: R577.1 U66.2(ISET)
N17252018: R581.2 U66.3(PGOOD)
N17252028: C911.1 R587.1 U66.8(3VCBP)
N17252031: R587.2 R589.2 U66.1(FCCM)
N17252042: C912.1 U66.6(SS)
N17252057: R575.2 U66.15(FF)
N17252063: C896.1 U66.14(BOOT)
N17271621: R88.1 U1.L4(IRQ10)
N17271626: R89.1 U1.U3(IRQ11)
N17271631: R91.1 U1.F19(TMP_DETECT_B)
N17321001: R112.1 U13.4(O)
N17321019: D1.2 R112.2
N17399246: C1046.1 R697.1 R699.2 U76.3(M\R\)
N17399288: J38.1 R699.1 SW4.2
N17400346: D7.2 R703.1 R706.1 SW5.2
N17401317: U77.1(CLK) U78.4(O)
N17401544: C1049.1 D7.1 R706.2 U78.2(I)
N17423481: J4.5 R119.2
N17423546: J4.6 R116.1
N17424508: C294.1 J10.1 R191.1
N17424523: R191.2 U31.3(VBACKUP)
N17424557: U31.2(X2) Y1.4
N17424571: U31.1(X1) Y1.1
N17424740: C296.2 R193.2 U34.2(D+)
N17424742: C296.1 R194.2 U34.3(D-)
N17433404: R226.2 U37.88(CLKIN_N)
N17437095: R210.1 R220.1 U35.8(GPIO0)
N17437909: D4.2 R220.2
N17484067: J12.13(CE REMOTE) U36.23(CE_REMOTE_OUT)
N17484070: J12.15(DDC CLK) R204.1 U36.22(DDC_CLK_OUT)
N17484079: J12.16(DDC DATA) R203.1 U36.21(DDC_DAT_OUT)
N17484088: J12.19(HP DET) R215.2 U36.20(HOTPLUG_DET_OUT)
N17484885: C304.1 U36.37(ESD_BYP)
N17497489: R207.1 R210.2 U36.16(CE_REMOTE_IN)
N17497523: R206.1 U35.9(HPDET) U36.19(HOTPLUG_DET_IN)
N17498064: R212.1 U35.35(ISET)
N17498075: R213.1 U35.19(VSWING)
N17500984: R219.2 U35.10(AS)
N17501134: C306.2 R214.2 R218.2 U35.3(VREF) U35.56(XCLK-)
N17523688: U77.2(D) U77.3(Q\)
N17523697: R705.1 U77.5(Q)
N17523706: C1050.1 R707.2 U77.6(C\L\R\)
N17525004: Q28.3(D) R691.1 R692.1
N17526494: R535.2 U60.15(FF)
N17526498: C854.1 R543.1 U60.8(3VCBP)
N17526502: R543.2 R545.2 U60.1(FCCM)
N17526505: C840.2 L7.1 R536.2 R537.1 U60.12(PHASE)
N17526509: C847.1 C852.1 R537.2
N17526513: C847.2 C848.1 C849.1 C850.1 C851.1 L7.2 R534.1 R548.2
N17526517: C852.2 R546.2 R547.2 U60.5(FB)
N17526563: C855.1 U60.6(SS)
N17526565: C840.1 U60.14(BOOT)
N17526568: R536.1 U60.2(ISET)
N17526574: R551.2 U61.2(A)
N17526575: R547.1 R548.1 R550.2 R556.2 U61.4(B)
N17551792: J18.1 R243.2
N17554945: U39.4(1A) U40.3(R)
N17554954: R241.1 U39.7(2A) U40.6(D)
N17555031: R245.2 U40.4(R\E\)
N17555276: U39.12(4A) U41.2(I)
N17555960: R246.1 U40.5(DE) U41.4(O)
N17557626: C775.1 J30.13(RX0_P)
N17557628: C776.1 J30.15(RX0_N)
N17558733: J30.14(I/O_0) R465.1 R467.2
N17558754: J30.16(I/O_1) R464.1 R468.2
N17558775: J30.18(I/O_2) R463.1 R469.2
N17559329: J30.2(VIO) R466.1
N17582904: R353.1 T5.24
N17582906: C506.2 R353.2 R355.2 R357.2 R359.2
N17582916: R355.1 T5.21
N17582920: R357.1 T5.18
N17582932: R359.1 T5.15
N17584782: C498.2 T5.1
N17584786: C500.2 T5.4
N17584789: C502.2 T5.7
N17584792: C504.2 T5.10
N17584836: C512.2 T6.1
N17584840: C514.2 T6.4
N17584844: C516.2 T6.7
N17584847: C518.2 T6.10
N17584869: R331.1 U51.C10(MDINT)
N17584889: C528.2 T8.4
N17584893: C526.2 T8.1
N17584896: C530.2 T8.7
N17584902: C532.2 T8.10
N17584942: C542.2 T10.4
N17584944: C541.2 T10.1
N17584949: C544.2 T10.7
N17584952: C546.2 T10.10
N17584987: C508.2 J21.A12 R363.2
N17584990: C510.2 J21.A10 R361.2
N17585015: C522.2 J21.B12 R375.2
N17585018: C524.2 J21.B10 R373.2
N17585035: C536.2 J21.C12 R387.2
N17585038: C538.2 J21.C10 R385.2
N17585055: C547.2 J21.D12 R397.2
N17585058: C550.2 J21.D10 R396.2
N17585063: C553.2 J21.H12(G12) R399.2
N17585067: C554.2 J21.H10(G10) R398.2
N17585093: C497.2 T4.1
N17585097: C499.2 T4.4
N17585100: C501.2 T4.7
N17585103: C503.2 T4.10
N17585145: C511.2 T7.1
N17585149: C513.2 T7.4
N17585152: C515.2 T7.7
N17585155: C517.2 T7.10
N17585198: C527.2 T9.4
N17585202: C525.2 T9.1
N17585205: C529.2 T9.7
N17585209: C531.2 T9.10
N17585248: C540.2 T11.4
N17585251: C539.2 T11.1
N17585256: C543.2 T11.7
N17585259: C545.2 T11.10
N17585292: C507.2 J21.E12 R362.2
N17585295: C509.2 J21.E10 R360.2
N17585312: C521.2 J21.F12 R374.2
N17585315: C523.2 J21.F10 R372.2
N17585332: C535.2 J21.G12 R386.2
N17585335: C537.2 J21.G10 R384.2
N17588753: C343.2 R250.2 U42.19(RXC)
N17588764: R251.2 U42.14(RXD0/SELRGV)
N17588767: R253.2 U42.16(RXD1/TXDLY)
N17588769: R254.2 U42.17(RXD2/AN0)
N17588771: R255.2 U42.18(RXD3/AN1)
N17588772: R256.2 U42.13(RXCTL/PHY_AD2)
N17588858: R262.1 U42.20(I\N\T\)
N17588875: C350.1 U42.42(CKXTAL1) Y2.1
N17588878: C351.1 U42.43(CKXTAL2) Y2.3
N17588897: C346.1 R258.1 U42.46(CLK125)
N17588905: R264.1 U42.33(P\M\E\)
N17588927: L4.1 R266.1 U42.48(REG_OUT)
N17588950: C352.1 R266.2
N17589014: R268.2 U42.39(RSET)
N17590523: L5.1 R296.1 U45.48(REG_OUT)
N17590546: C381.1 R296.2
N17590598: C372.2 R281.2 U45.19(RXC)
N17590603: R280.2 U45.14(RXD0/SELRGV)
N17590606: R283.2 U45.16(RXD1/TXDLY)
N17590608: R284.2 U45.17(RXD2/AN0)
N17590610: R285.2 U45.18(RXD3/AN1)
N17590611: R286.2 U45.13(RXCTL/PHY_AD2)
N17590657: C368.2 C370.2 C371.2 C373.2 T2.1 T2.4 T2.7 T2.10
N17590707: R292.1 U45.20(I\N\T\)
N17590732: C379.1 U45.42(CKXTAL1) Y3.1
N17590735: C380.1 U45.43(CKXTAL2) Y3.3
N17590767: C375.1 R288.1 U45.46(CLK125)
N17590774: R294.1 U45.33(P\M\E\)
N17590779: R298.2 U45.39(RSET)
N17593781: R247.1 T1.15
N17593783: R248.1 T1.18
N17593791: R249.1 T1.21
N17593793: R252.1 T1.24
N17596169: Q27.1(G) R692.2
N17596715: C1039.1 C1040.1 J36.2 Q27.3(D)
N17597092: J36.1 R695.1 R696.2
N17598342: Q28.1(G) R694.2
N17604579: R339.2 U51.C7(J\T\A\G\_\T\R\S\T\)
N17609926: R643.1 R646.2 U73.6(FB/ADJ)
N17609966: C1004.1 R636.1 R640.2 U72.1(REFIN)
N17609980: C997.1 R631.1 U72.5(VOSNS)
N17610004: R641.1 U72.9(PGOOD)
N17612202: R649.1 R651.2 U75.6(FB/ADJ)
N17629033: R334.1 U51.B12(PHYADD3)
N17629034: R335.1 U51.D26(PHYADD4)
N17629035: R333.1 U51.C19(PHYADD2)
N17629454: R337.2 U51.D8(COMA_MODE)
N17629729: C463.1 U51.A7(REF_FILT)
N17629871: R340.2 U51.A8(REF_REXT)
N17632317: R365.1 T6.24
N17632319: C520.2 R365.2 R367.2 R369.2 R371.2
N17632321: R367.1 T6.21
N17632325: R369.1 T6.18
N17632337: R371.1 T6.15
N17632726: C534.2 R377.2 R379.2 R381.2 R383.2
N17632728: R377.1 T8.24
N17632740: R381.1 T8.18
N17632744: R379.1 T8.21
N17632760: R383.1 T8.15
N17633242: R390.1 T10.24
N17633244: C549.2 R390.2 R391.2 R393.2 R395.2
N17633254: R391.1 T10.21
N17633258: R393.1 T10.18
N17633270: R395.1 T10.15
N17639917: C496.1 U52.A7(REF_FILT)
N17639934: R351.2 U52.A8(REF_REXT)
N17639958: R349.2 U52.D18(SEDES_REXT_1)
N17639964: R349.1 U52.D17(SEDES_REXT_0)
N17639984: R350.2 U52.C7(J\T\A\G\_\T\R\S\T\)
N17640717: R342.1 U52.C10(MDINT)
N17650951: R345.1 U52.B12(PHYADD3)
N17650952: R346.1 U52.D26(PHYADD4)
N17650953: R344.1 U52.C19(PHYADD2)
N17650962: R348.2 U52.D8(COMA_MODE)
N17692970: C816.1 U58.14(XTAL_IN) Y7.1
N17692982: C817.1 U58.13(XTAL_OUT) Y7.3
N17693054: R493.2 U58.10(F_SEL0)
N17696036: Q12.1(G) R661.2 R664.2
N17696038: C1025.2 Q12.3(D) R655.2 R658.2
N17696060: Q9.4 R655.1
N17697384: C807.1 R489.1 X3.3(OUT)
N17708927: R492.1 X4.3(OUT)
N17708947: R491.2 X4.1(OE)
N17736577: R31.1 SW1.16
N17736598: R33.1 SW1.15
N17736619: R35.1 SW1.14
N17736629: R37.1 SW1.13
N17736659: R38.1 SW1.12
N17736669: R39.1 SW1.11
N17736681: R40.1 SW1.10
N17736695: R41.1 SW1.9
N17736739: R42.1 SW2.16
N17736751: R43.1 SW2.15
N17736763: R44.1 SW2.14
N17736781: R45.1 SW2.13
N17736801: R48.1 SW2.11
N17736803: R46.1 SW2.12
N17736817: R47.1 SW2.10
N17736835: R49.1 SW2.9
N17742094: C1034.2 Q24.3(D) R680.2 R681.2
N17743915: C1011.1 R644.1 R647.2 U74.4(NR/FB)
N17748293: J13.19 J14.1 R224.2
N17749501: J15.1 R227.1
N17749602: J13.20 J15.2 Q6.3(D)
N17792541: C505.2 R352.2 R354.2 R356.2 R358.2
N17792543: C519.2 R364.2 R366.2 R368.2 R370.2
N17792545: C533.2 R376.2 R378.2 R380.2 R382.2
N17792547: C548.2 R388.2 R389.2 R392.2 R394.2
N17792549: R352.1 T4.24
N17792551: R354.1 T4.21
N17792553: R356.1 T4.18
N17792555: R358.1 T4.15
N17792589: R364.1 T7.24
N17792591: R366.1 T7.21
N17792593: R368.1 T7.18
N17792595: R370.1 T7.15
N17792630: R378.1 T9.21
N17792632: R376.1 T9.24
N17792634: R382.1 T9.15
N17792636: R380.1 T9.18
N17792669: R388.1 T11.24
N17792671: R389.1 T11.21
N17792673: R392.1 T11.18
N17792675: R394.1 T11.15
N17823659: C443.2 U51.D12(REFCLK_N)
N17823662: C442.2 U51.D11(REFCLK_P)
N17824163: C476.2 U52.D12(REFCLK_N)
N17824166: C475.2 U52.D11(REFCLK_P)
N17947254: R525.2 U79.6(SADR/REF1.8)
N17947282: R523.2 R528.2 U79.1(SS_EN_TRI)
N17947998: C824.1 U79.2(X1_25) Y8.1
N17948004: C825.1 U79.3(X2) Y8.3
N17952438: R500.1 U79.14(DIF0)
N17952440: R501.1 U79.15(D\I\F\0\)
N17952563: R506.1 U79.22(DIF2)
N17952565: R507.1 U79.23(D\I\F\2\)
N17952567: R514.1 U79.28(DIF3)
N17952569: R515.1 U79.29(D\I\F\3\)
N17952583: R518.1 U79.33(DIF4)
N17952585: R519.1 U79.34(D\I\F\4\)
N17952595: R524.1 U79.37(D\I\F\5\)
N17952601: R522.1 U79.36(DIF5)
N17952605: R504.1 U79.19(D\I\F\1\)
N17952607: R511.1 U79.18(DIF1)
N17979212: R711.2 R715.2 U1.AD1(EC1_RX_CLK)
N17979230: R714.2 R715.1
N17979244: R710.2 R711.1
N17979345: R716.2 R717.1
N17979374: R712.1 R716.1 U1.AH5(EC2_RX_CLK)
N17979380: R712.2 R713.1
N18177051: C1069.2 Q31.3(D) R720.2 R721.2
N18177053: Q31.1(G) R722.2 R723.2
N18177080: Q30.4 R720.1
N18178202: R718.1 U80.4(C) U81.4(C)
N18200115: R724.1 T12.15
N18200130: R726.1 T12.21
N18200132: C1075.1 R724.2 R725.2 R726.2 R730.2
N18200134: R725.1 T12.18
N18200140: R730.1 T12.24
N18200177: C1070.2 C1072.2 C1073.2 C1074.2 T12.1 T12.4 T12.7 T12.10
N18200226: C1071.1 FB44.2 J40.11
N18200230: C1079.1 J40.12 R734.2
N18200232: C1080.1 J40.9 R733.2
N18200292: R728.2 U82.43(RXD7/AN0)
N18200294: R729.2 U82.44(RXER/AN1)
N18200344: R732.2 U82.45(COL/MII0)
N18200346: R731.2 U82.46(CRS/MII1)
N18200354: R739.1 U82.75(I\N\T\)
N18200448: L17.1 R742.1 U82.88(REG_OUT)
N18200458: C1084.1 R742.2
N18200620: C1076.1 U82.13(HSIP)
N18200622: C1077.1 U82.14(HSIN)
N18200686: R735.1 U82.70(LED2/MDI0)
N18200704: R737.1 U82.71(LED3/MDI1)
N18200722: C1082.1 U82.81(CKXTAL1) Y9.1
N18200732: C1083.1 U82.82(CKXTAL2) Y9.3
N18200786: R727.2 U82.39(RXD4/SELRGV)
N18200821: R741.2 U82.77(ENSWREG)
N18200841: R744.2 U82.26(REXT)
N18201157: R743.2 U82.78(RSET)
N18205066: R746.1 T13.15
N18205081: R748.1 T13.21
N18205083: C1109.1 R746.2 R747.2 R748.2 R752.2
N18205085: R747.1 T13.18
N18205091: R752.1 T13.24
N18205128: C1104.2 C1106.2 C1107.2 C1108.2 T13.1 T13.4 T13.7 T13.10
N18205177: C1105.1 FB45.2 J41.9 J41.11
N18205181: C1113.1 J41.12 R756.2
N18205183: C1114.1 J41.10 R755.2
N18205243: R750.2 U83.43(RXD7/AN0)
N18205245: R751.2 U83.44(RXER/AN1)
N18205295: R754.2 U83.45(COL/MII0)
N18205297: R753.2 U83.46(CRS/MII1)
N18205305: R761.1 U83.75(I\N\T\)
N18205399: L18.1 R764.1 U83.88(REG_OUT)
N18205409: C1118.1 R764.2
N18205571: C1110.1 U83.13(HSIP)
N18205573: C1111.1 U83.14(HSIN)
N18205637: R757.1 U83.70(LED2/MDI0)
N18205655: R759.1 U83.71(LED3/MDI1)
N18205673: C1116.1 U83.81(CKXTAL1) Y10.1
N18205683: C1117.1 U83.82(CKXTAL2) Y10.3
N18205737: R749.2 U83.39(RXD4/SELRGV)
N18205772: R762.2 U83.77(ENSWREG)
N18205792: R766.2 U83.26(REXT)
N18206108: R765.2 U83.78(RSET)
N18257321: FB46.1 U36.38(5V_OUT)
N18275528: Q14.1(G) R663.2 R666.2
N18275529: C1027.2 Q14.3(D) R657.2 R660.2
N18275540: Q11.4 R657.1
N18275558: Q18.1(G) R670.2 R671.2
N18275559: C1028.2 Q18.3(D) R668.2 R669.2
N18275570: Q15.4 R668.1
N18275588: Q24.1(G) R682.2 R683.2
N18275595: Q23.4 R680.1
N18280039: C966.2 C972.2 R616.2
N18280045: C953.2 L15.1 R613.2 R616.1 U69.12(PHASE)
N18280055: R618.2 U69.3(PGOOD)
N18280059: R613.1 U69.2(ISET)
N18280061: C972.1 R619.1 R627.2 U69.5(FB)
N18280085: C974.1 R623.1 U69.8(3VCBP)
N18280087: R623.2 R625.2 U69.1(FCCM)
N18280133: C975.1 U69.6(SS)
N18280157: C953.1 U69.14(BOOT)
N18280169: R611.2 U69.15(FF)
N18382428: R473.1 SW3.16
N18394326: R474.1 SW3.15
N18394329: R475.1 SW3.14
N18394330: R477.1 SW3.13
N18394334: R481.1 SW3.11
N18394336: R483.1 SW3.10
N18551266: R263.2 U42.38(ENSWREG)
N18552106: R293.2 U45.38(ENSWREG)
N18569886: Q29.1(B) R705.2
N18569887: J37.8(PWR_OK) R698.1 R701.2
N18629376: C434.2 U51.D15(QSGMII0_TXN)
N18629379: C431.2 U51.D16(QSGMII0_TXP)
N18629428: C470.2 U52.D15(QSGMII0_TXN)
N18629431: C464.2 U52.D16(QSGMII0_TXP)
N18629823: C772.2 J29.3(TX_N)
N18629826: C771.2 J29.2(TX_P)
N18629885: C773.2 J29.5(RX_N)
N18629888: C774.2 J29.6(RX_P)
N18720737: R170.1 U1.M4(CLK12)
N18753359: R229.2 U37.18(R_FB)
N18753377: R230.2 U37.19(R_FDE)
N18753428: R232.2 U37.24(BAL)
N18753501: R231.2 U37.23(DUAL)
N18753516: R228.2 U37.12(PRE)
N19119205: F1.2 J16.2 R233.2
N19126530: R479.1 SW3.12
N19623883: C1026.2 Q13.3(D) R656.2 R659.2
N19623885: Q13.1(G) R662.2 R665.2
N19623968: Q10.4 R656.1
N19675149: R338.2 U51.D18(SEDES_REXT_1)
N19675151: R338.1 U51.D17(SEDES_REXT_0)
N20516568: TP1.1(TP) U1.E6(CLK_OUT)
N20517420: TP3.1(TP) U1.AD7(TSEC_1588_CLK_OUT)
N20517422: TP4.1(TP) U1.AF5(TSEC_1588_ALARM_OUT1)
N20517434: TP5.1(TP) U1.AC7(TSEC_1588_ALARM_OUT2)
N20517436: TP6.1(TP) U1.AE6(TSEC_1588_PULSE_OUT1)
N20517448: TP10.1(TP) U1.AD8(TSEC_1588_PULSE_OUT2)
N20553507: Q25.1(G) Q26.1(G) R684.2 R685.2
N20559490: Q21.1(G) R677.2 R678.2
N20559492: C1029.2 Q21.3(D) Q22.1(G) R673.2 R675.2
N20559589: Q16.1(G) Q17.1(G) R673.1
N20559634: Q16.3(D) Q17.3(D)
N20559669: C1030.1 Q22.3(D) R674.1 R676.1
N20559724: Q19.1(G) Q20.1(G) R674.2
N20562248: TP11.1(TP) U1.Y15(SD1_PLL1_TPA)
N20562257: TP12.1(TP) U1.AB15(SD1_PLL1_TPD)
N20562271: TP13.1(TP) U1.Y19(SD1_PLL2_TPA)
N20562273: TP14.1(TP) U1.AB19(SD1_PLL2_TPD)
N21227087: J37.1(+3.3VDC#1)
N21227093: J37.2(+3.3VDC#2)
N21227121: J37.11(+3.3VDC#11)
N21754633: J11.28 R200.1
N21754692: J11.36 R201.1
N21754708: J11.38 R202.1
N22257590: R23.1 U2.2(1Q1)
N22257592: R24.1 U2.3(1Q2)
N22257594: R25.1 U2.5(1Q3)
N22258098: R27.1 U2.8(1Q5)
N22258100: R28.1 U2.9(1Q6)
N22258102: R29.1 U2.11(1Q7)
N22258104: R30.1 U2.12(1Q8)
N22258216: R26.1 U2.6(1Q4)
N22258634: R32.1 U2.13(2Q1)
N22258636: R34.1 U2.14(2Q2)
N22258638: R36.1 U2.16(2Q3)
N22360230: F2.2 J32.2 R686.2
N22360382: F3.2 J33.2 R687.2
N22360534: F4.2 J34.2 R690.2
N22361017: F5.2 J35.2 R693.2
N22361656: D5.1 R688.2
N22361689: D6.1 R689.2
N22440478: Q19.3(D) Q20.3(D)
N23926306: Q7.4 R544.2
N23926329: C857.1 Q8.3(D) R544.1 R549.1
N23926341: Q8.1(G) R552.2 R553.2
N23927707: R534.2 R541.2
N23927714: R534.3 R542.2
N23928633: R554.2 U62.2(A0)
N23928636: R555.2 U62.1(A1)
N23929117: R556.1 U62.8(VBUS)

Pads without a net: J1 8 19 30 41 52 78 100 111 122 133 144 205 227 230 234 235; J4 2 8 10 14; J9 1 4 6 9 11 14 16 19; J11 8; J12 14; J26 A7 B12; J27 3 5 7 8 10 12 14 16 17 19 20 36 37 38 39 41 42 43 44 45 46 47 49 51; J28 3 5 7 8 10 12 14 16 17 19 20 36 37 38 39 41 42 43 44 45 46 47 49 51; J30 7 9 19 21 25 27 31 33 37 38 39 40 43 44 45 46 49 50 51 52 55 56 57 58 61 62 63 64 67 68 69 70; J31 6 7 8; U1 A14 A16 A19 AA5 AA6 AA7 AA8 AA9 AA10 AB8 AB11 AB12 AC4 AD10 AE10 AG28 AH27 C14 C15 C16 C17 C19 D18 E17 F10 F21 G6 G17 H6 H21 J6 J20 K22 L6 M6 M22 N3 N6 P22 R5 R6 T6 U5 U6 U22 V6 V21 W6 W21 Y5 Y6 Y21; U2 17 19 20 22 23; U3 27 28 30; U4 A1 A2 A9 A10 B1 B9 B10 D6 D7 D8 E3 E4 E5 E6 E7 E8 F3 F4 F5 F6 F8 G3 G5 G6 G7 G8 H3 H5 H6 H7 J3 J5 L1 L2 L9 L10 M1 M2 M9 M10; U8 3 4 5 6 11 12 13 14; U24 4 12; U27 4 12; U35 16 37 38 39 41 42 43 44 46 47 48; U37 26 27 28 29 31 32 33 34 36 37 55 73; U39 9; U40 11 14; U41 1; U42 12; U45 12; U48 21 22 28 29 30 31 32 33 35 36 37 38 41 42 56 62 63 64 65 74 76 86; U51 A1 A2 A3 A4 A5 A6 B1 B3 B6 B9 B10 B11 B13 B14 C2 C4 C8 C9 C12 C13 C14 C15 C16 C17 C18 C20 D2 D3 D4 D6 D7 D19 D20 D21 D22 D23 D24 D25 D27 D28; U52 A1 A2 A3 A4 A5 A6 B1 B3 B6 B9 B10 B11 B13 B14 C2 C4 C8 C9 C12 C13 C14 C15 C16 C17 C18 C20 D2 D3 D4 D6 D7 D19 D20 D21 D22 D23 D24 D25 D27 D28; U57 D6 D7 D8 D9 D10 E5 E6 E7 E8 E9 E10 E11 E12 F4 F5 F6 F7 F10 F11 F12 G4 G5 G6 G11 G12 G13 H4 H12 H13 J4 J5 J13 K4 K5 K6 K11 K12 K13 L5 L7 L10 L11 L12 M6 M7 M8 M9 M10 M11 M12 N6 N7 N8 N9 N10 N11; U58 6 7 8 12 16 17 23 24; U60 7 9; U62 3; U64 7 9; U65 7 9; U66 7 9; U67 7 9; U68 7 9; U69 7 9; U78 1; U79 7 20 25 40; U82 21 22 28 29 30 31 32 33 35 36 37 38 41 42 56 62 63 64 65 74 76 86; U83 21 22 28 29 30 31 32 33 35 36 37 38 41 42 56 62 63 64 65 74 76 86; Z1 1; Z2 1; Z3 1; Z4 1; Z5 1; Z6 1; Z7 1; Z8 1

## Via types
v1: diameter 0.508, hole 0.254, TOP to BOTTOM, 2835 vias
v2: diameter 0.457, hole 0.254, TOP to BOTTOM, 726 vias
v3: diameter 0.711, hole 0.406, TOP to BOTTOM, 278 vias

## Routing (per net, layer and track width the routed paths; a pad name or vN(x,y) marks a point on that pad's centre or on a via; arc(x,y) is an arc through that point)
1V0: length 51
  TOP w0.102: U52.E21 216.11,86.61 216.09,86.69 216.08,86.79 216.1,87.1 U52.E19 ; U51.E19 184.35,87.1 184.33,86.79 184.34,86.69 184.36,86.61 U51.E21
  TOP w0.127: v1(219.76,87) 220.8,87 221.07,87.26 U52.E13 ; v1(219.76,87) 219.77,87 U52.E15 ; v1(219.76,87) 218.72,87 218.47,87.25 U52.E17 ; v2(217.14,87.76) 216.96,87.57 U52.E19 ; U51.E10 191.27,87.86 v2(191.49,88.09) ; v2(190.83,85.22) 191.13,85.52 U51.E7 191.71,85.03 191.71,84.7 U51.E5 ; v2(185.39,87.76) 185.21,87.57 U51.E19 ; U51.E13 189.32,87.26 189.05,87 v1(188.01,87) ; v2(223.24,88.09) 223.02,87.86 U52.E10 ; v2(222.58,85.22) 222.88,85.52 U52.E7 223.46,85.03 223.46,84.7 U52.E5 ; U51.E15 188.02,87 v1(188.01,87) ; U52.E23 216.97,84.31 v2(216.97,83.57) U52.E25 ; U51.E25 v2(185.22,83.57) 185.22,84.31 U51.E23 ; v1(188.01,87) 186.97,87 186.72,87.25 U51.E17
  TOP w0.508: v1(252.44,92.04) R619.2 253.47,91.31 C966.1
  L3SIG w0.508: v1(235.7,93.34) 236.47,94.11 240.92,94.11 243.59,91.44 249.68,91.44 250.28,92.04 v1(252.44,92.04)
  BOTTOM w0.508: v2(222.58,85.22) 222.45,85.09 C484.1 ; v2(185.39,87.76) 185.39,87.94 185.7,88.24 C452.1 ; v2(217.14,87.76) 217.14,87.94 217.45,88.24 C485.1 ; C488.1 220.22,87.45 v1(219.76,87) ; C486.1 217.32,83.92 v2(216.97,83.57) ; C455.1 191.44,88.04 v2(191.49,88.09) ; v2(185.22,83.57) 185.57,83.92 C454.1 ; v2(190.83,85.22) 190.7,85.09 C451.1 ; C487.1 223.19,88.04 v2(223.24,88.09) ; v1(188.01,87) 188.47,87.45 C453.1
  vias: v1(180.47,87.88) v1(180.47,87.12) v1(180.47,86.36) v1(212.22,87.88) v1(212.22,87.12) v1(212.22,86.36) v1(235.7,92.33) v1(235.7,91.31) v1(235.7,90.3) v1(235.7,89.28) v1(235.7,88.27) v1(235.7,87.25) v1(235.7,86.23) v1(235.7,85.22)
1V0_FA_VL: length 84.4
  TOP w0.305: U1.G18 v2(127.97,105.02)
  TOP w0.508: J8.1 66.27,149.33 R173.2
  L3SIG w0.508: J8.1 74.04,148.97 87.5,135.51 95,135.51 107.95,122.56 110.24,122.56 115.82,116.97 115.82,114.81 122.56,108.08 122.56,105.6 122.92,105.23 126.51,105.23
1V0_USB_SVDD: length 5.4
  TOP w0.305: U1.K9 v2(130.37,97.82) ; U1.K10 v2(130.37,98.62)
  BOTTOM w0.457: C1138.1 130.4,90.32 v2(130.05,90.68)
  BOTTOM w0.508: C1138.1 C97.1 C98.1 130.4,86.72 FB5.1
1V0A_QSG1: length 16.6
  TOP w0.127: v2(189.36,88.9) 189.48,88.77 189.48,87.91 ; 189.48,87.91 189.15,87.91 U51.E14 188.19,87.91 187.71,87.91 ; 189.48,87.91 190.14,87.91 U51.E11 ; v2(187.71,88.39) 187.71,87.91 ; 187.71,87.91 187.37,87.57 U51.E16 ; U51.E28 184.36,81.62 v2(184.15,81.41) ; U51.E36 189.97,81.38 v2(189.97,81.41) ; U51.E32 187.02,80.52 186.41,80.52 U51.E30 v2(186.07,81.42) ; v2(192.07,80.7) 191.64,80.7 U51.E1 ; v2(188.44,81.41) 188.67,81.18 U51.E34
  TOP w0.381: v2(187.71,88.39) v2(187.71,89.03)
  BOTTOM w0.508: v2(187.71,89.03) 187.33,89.41 C433.1 ; C435.1 188.44,81.71 v2(188.44,81.41) ; v2(187.71,88.39) 187.68,88.37 C437.1 ; C438.1 190.12,81.56 v2(189.97,81.41) ; C436.1 192.02,80.75 v2(192.07,80.7) ; v2(184.15,81.41) 183.9,81.15 C439.1 ; C440.1 189.33,88.93 v2(189.36,88.9) ; C441.1 186.06,81.43 v2(186.07,81.42)
  vias: v1(180.47,90.68) v1(181.23,90.68)
1V0A_QSG2: length 16.6
  TOP w0.127: 221.23,87.91 221.89,87.91 U52.E11 ; 221.23,87.91 221.23,88.77 v2(221.11,88.9) ; 221.23,87.91 220.9,87.91 U52.E14 219.94,87.91 219.46,87.91 ; U52.E34 220.42,81.18 v2(220.19,81.41) ; U52.E28 216.11,81.62 v2(215.9,81.41) ; U52.E32 218.77,80.52 218.16,80.52 U52.E30 v2(217.82,81.42) ; v2(221.72,81.41) 221.72,81.38 U52.E36 ; U52.E16 219.12,87.57 219.46,87.91 ; 219.46,87.91 v2(219.46,88.39) ; v2(223.82,80.7) 223.39,80.7 U52.E1
  TOP w0.381: v2(219.46,88.39) v2(219.46,89.03)
  BOTTOM w0.508: C472.1 221.87,81.56 v2(221.72,81.41) ; C466.1 219.08,89.41 v2(219.46,89.03) ; v2(219.46,88.39) 219.43,88.37 C469.1 ; C471.1 217.81,81.43 v2(217.82,81.42) ; C473.1 220.19,81.71 v2(220.19,81.41) ; C468.1 221.08,88.93 v2(221.11,88.9) ; C474.1 223.77,80.75 v2(223.82,80.7) ; v2(215.9,81.41) 215.65,81.15 C467.1
  vias: v1(212.22,90.68) v1(212.98,90.68)
1V0S: length 0.8
  BOTTOM w0.508: R643.2 172.69,115.54 v1(172.85,115.7)
  vias: v1(167.64,114.68) v1(167.64,112.65) v1(168.66,114.68) v1(168.66,112.65)
1V2: length 39.1
  TOP w0.305: U1.U21 v2(136.77,108.22) ; U1.AA27 v2(139.97,113.02) ; U1.AD27 v2(142.37,113.02) ; U1.AF27 v2(143.97,113.02) ; U1.L21 v2(131.17,108.22) ; U1.P21 v2(133.57,108.22) ; U1.W27 v2(138.37,113.02) ; U1.F27 v2(127.17,113.02) ; U1.P27 v2(133.57,113.02) ; U1.H27 v2(128.77,113.02) ; U1.D27 v2(125.57,113.02) ; U1.N21 v2(132.77,108.22) ; U1.U27 v2(136.77,113.02) ; U1.K21 v2(130.37,108.22) ; U1.K27 v2(130.37,113.02) ; U1.M27 v2(131.97,113.02) ; U1.T21 v2(135.97,108.22) ; U1.M21 v2(131.97,108.22) ; U1.R21 v2(135.17,108.22)
  TOP w0.508: C14.1 v1(119.25,170.81) ; C18.1 v1(139.7,170.81) ; C6.1 v1(136.65,170.81) ; C9.1 v1(113.16,170.81) ; C7.1 v1(141.73,170.81) ; C2.1 v1(135.64,170.81) ; C5.1 v1(137.67,170.81) ; C15.1 v1(117.22,170.81) ; C17.1 v1(112.14,170.81) ; C8.1 v1(133.6,170.81) ; C10.1 v1(114.17,170.81) ; C1.1 v1(116.21,170.81)
  TOP w0.635: C87.1 149.92,137.85 v1(149.78,137.7)
  BOTTOM w0.305: C119.1 138.16,112.81 v2(138.37,113.02) ; v2(128.77,113.02) 128.97,112.81 C102.1 ; v2(136.77,113.02) 136.56,112.81 C115.1 ; C112.1 127.37,112.81 v2(127.17,113.02) ; C103.1 v2(143.97,113.02) ; v2(130.37,113.02) 130.57,112.81 C111.1 ; v2(130.37,108.22) 130.15,108.43 C104.1 ; v2(139.97,113.02) 139.76,112.81 C110.1 ; v2(131.97,113.02) 132.17,112.81 C99.1 ; v2(135.97,108.22) 135.97,108.22 C116.1 ; C113.1 136.98,108.43 v2(136.77,108.22) ; C101.1 133.36,108.43 v2(133.57,108.22) ; v2(131.97,108.22) 131.75,108.43 C117.1 ; C109.1 142.16,112.81 v2(142.37,113.02) ; C114.1 v2(135.17,108.22) ; C100.1 v2(125.57,113.02)
  BOTTOM w0.381: R1.1 136.77,115.71 v2(136.74,115.73)
  BOTTOM w0.508: v2(127.22,115.73) 127.16,115.67 R3.1
  BOTTOM w0.635: v1(143.43,137.7) 143.57,137.85 C1065.1 ; C93.1 148.76,154.36 v1(148.56,154.15) ; C91.1 136.4,151.39 v1(136.36,151.42) ; v1(149.78,137.7) 149.92,137.85 C87.1 ; v1(132.81,154.09) 132.28,154.61 C89.1 ; v1(131.11,137.7) 131.25,137.85 C92.1 ; C90.1 124.52,137.85 v1(124.38,137.7) ; C88.1 117.91,137.85 v1(117.77,137.7) ; C94.1 137.34,137.85 v1(137.2,137.7)
  vias: v1(167.77,150.11) v1(167.77,149.22) v1(167.77,148.34) v1(168.02,147.32) v1(168.78,150.62) v1(168.78,149.73) v1(168.78,148.84) v1(168.78,147.95)
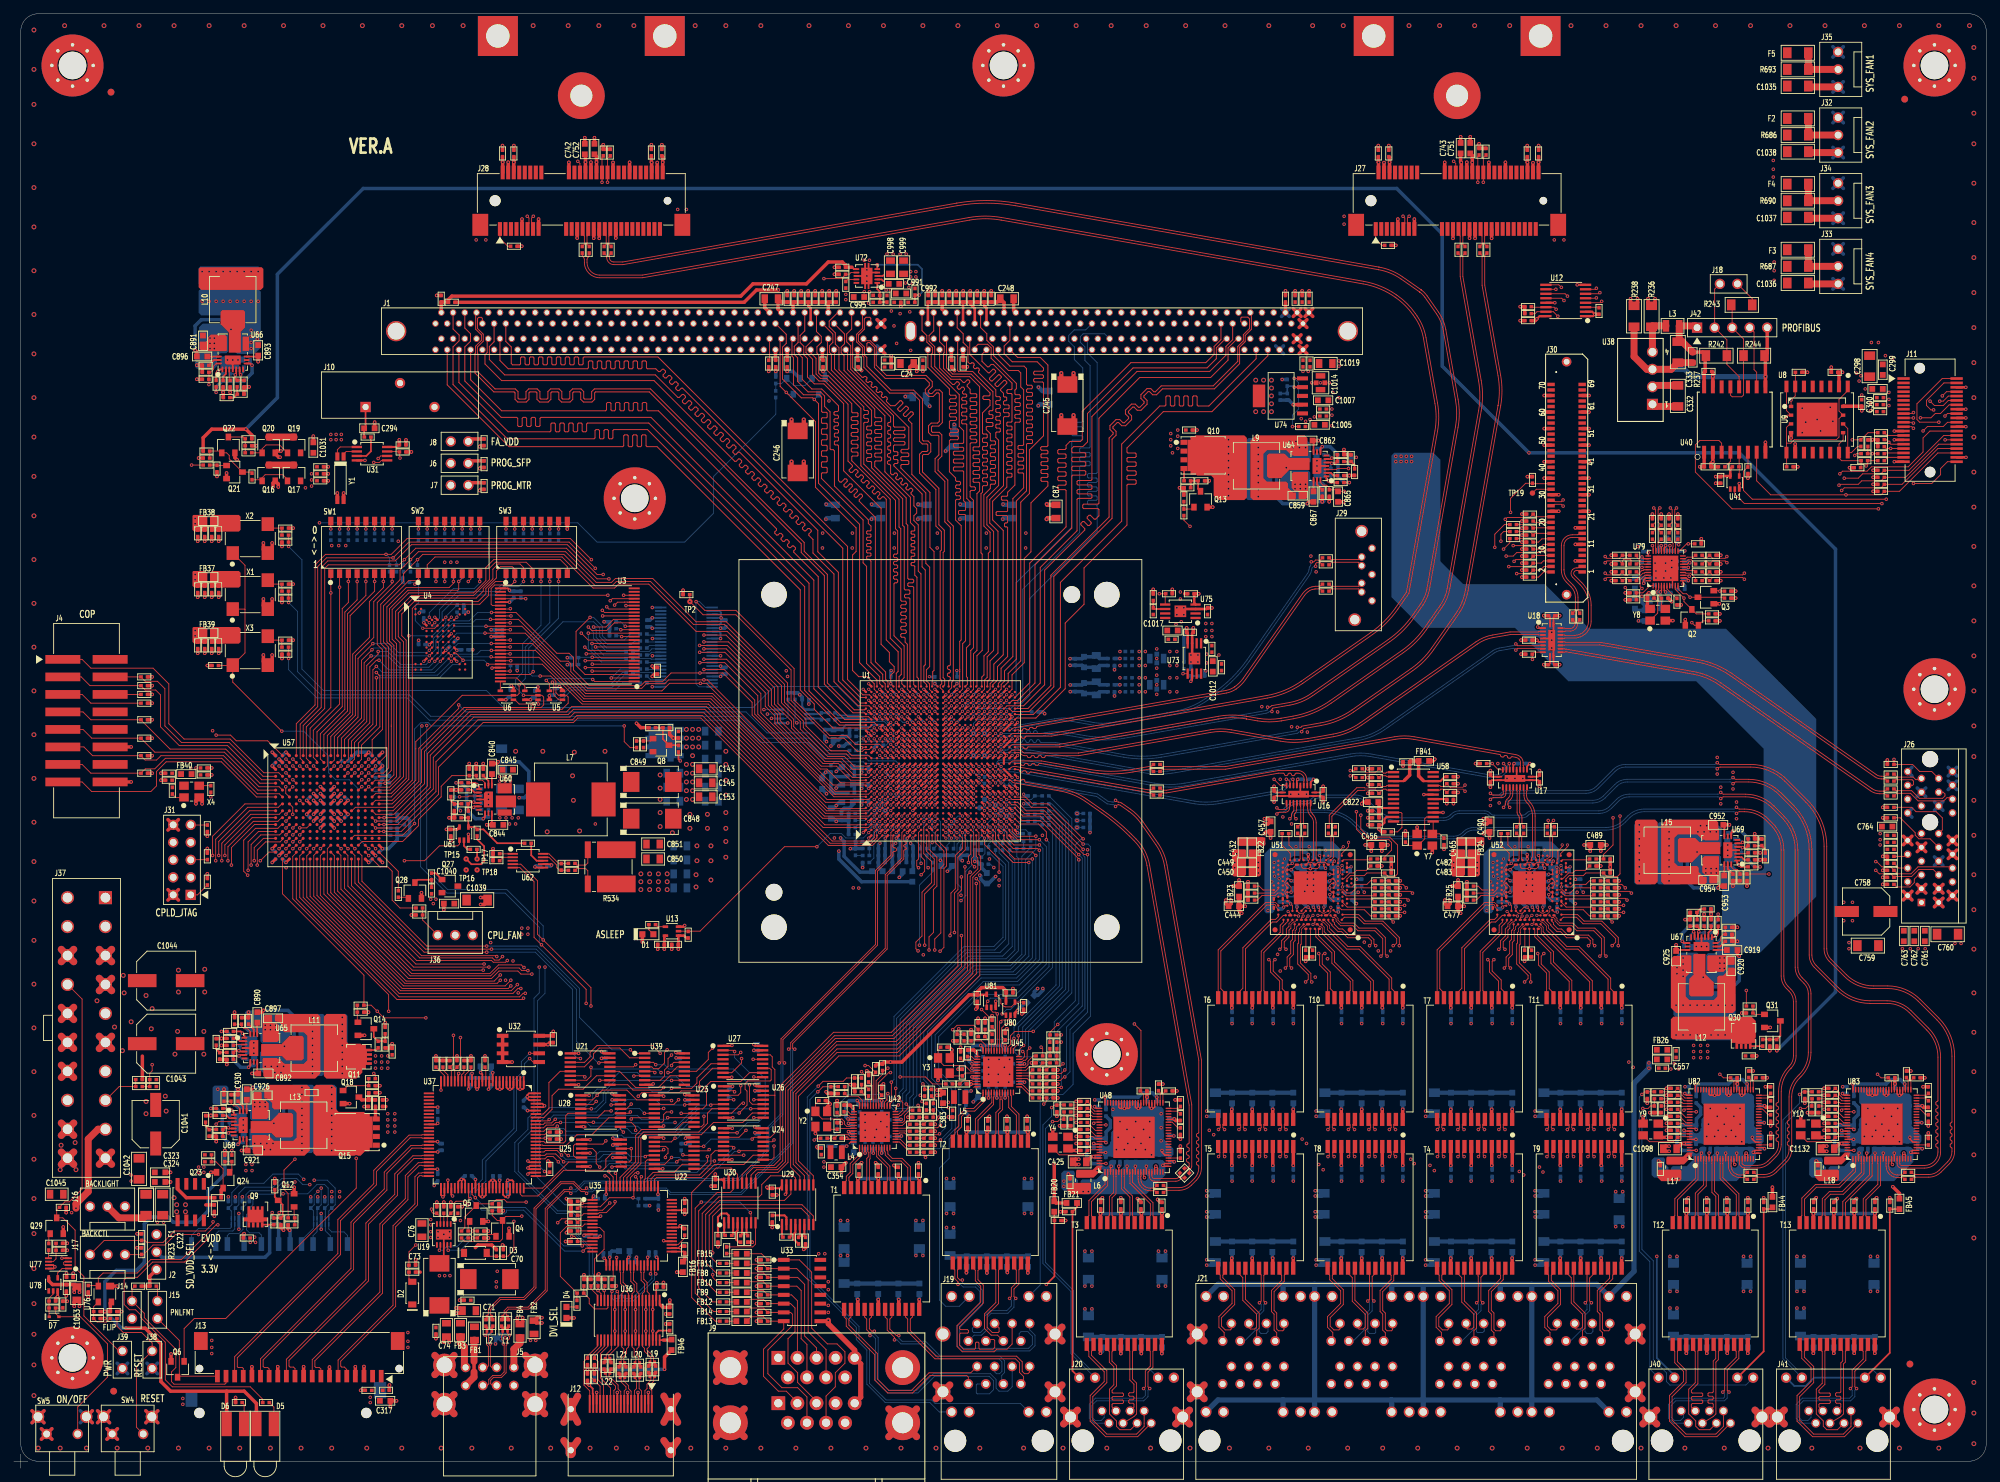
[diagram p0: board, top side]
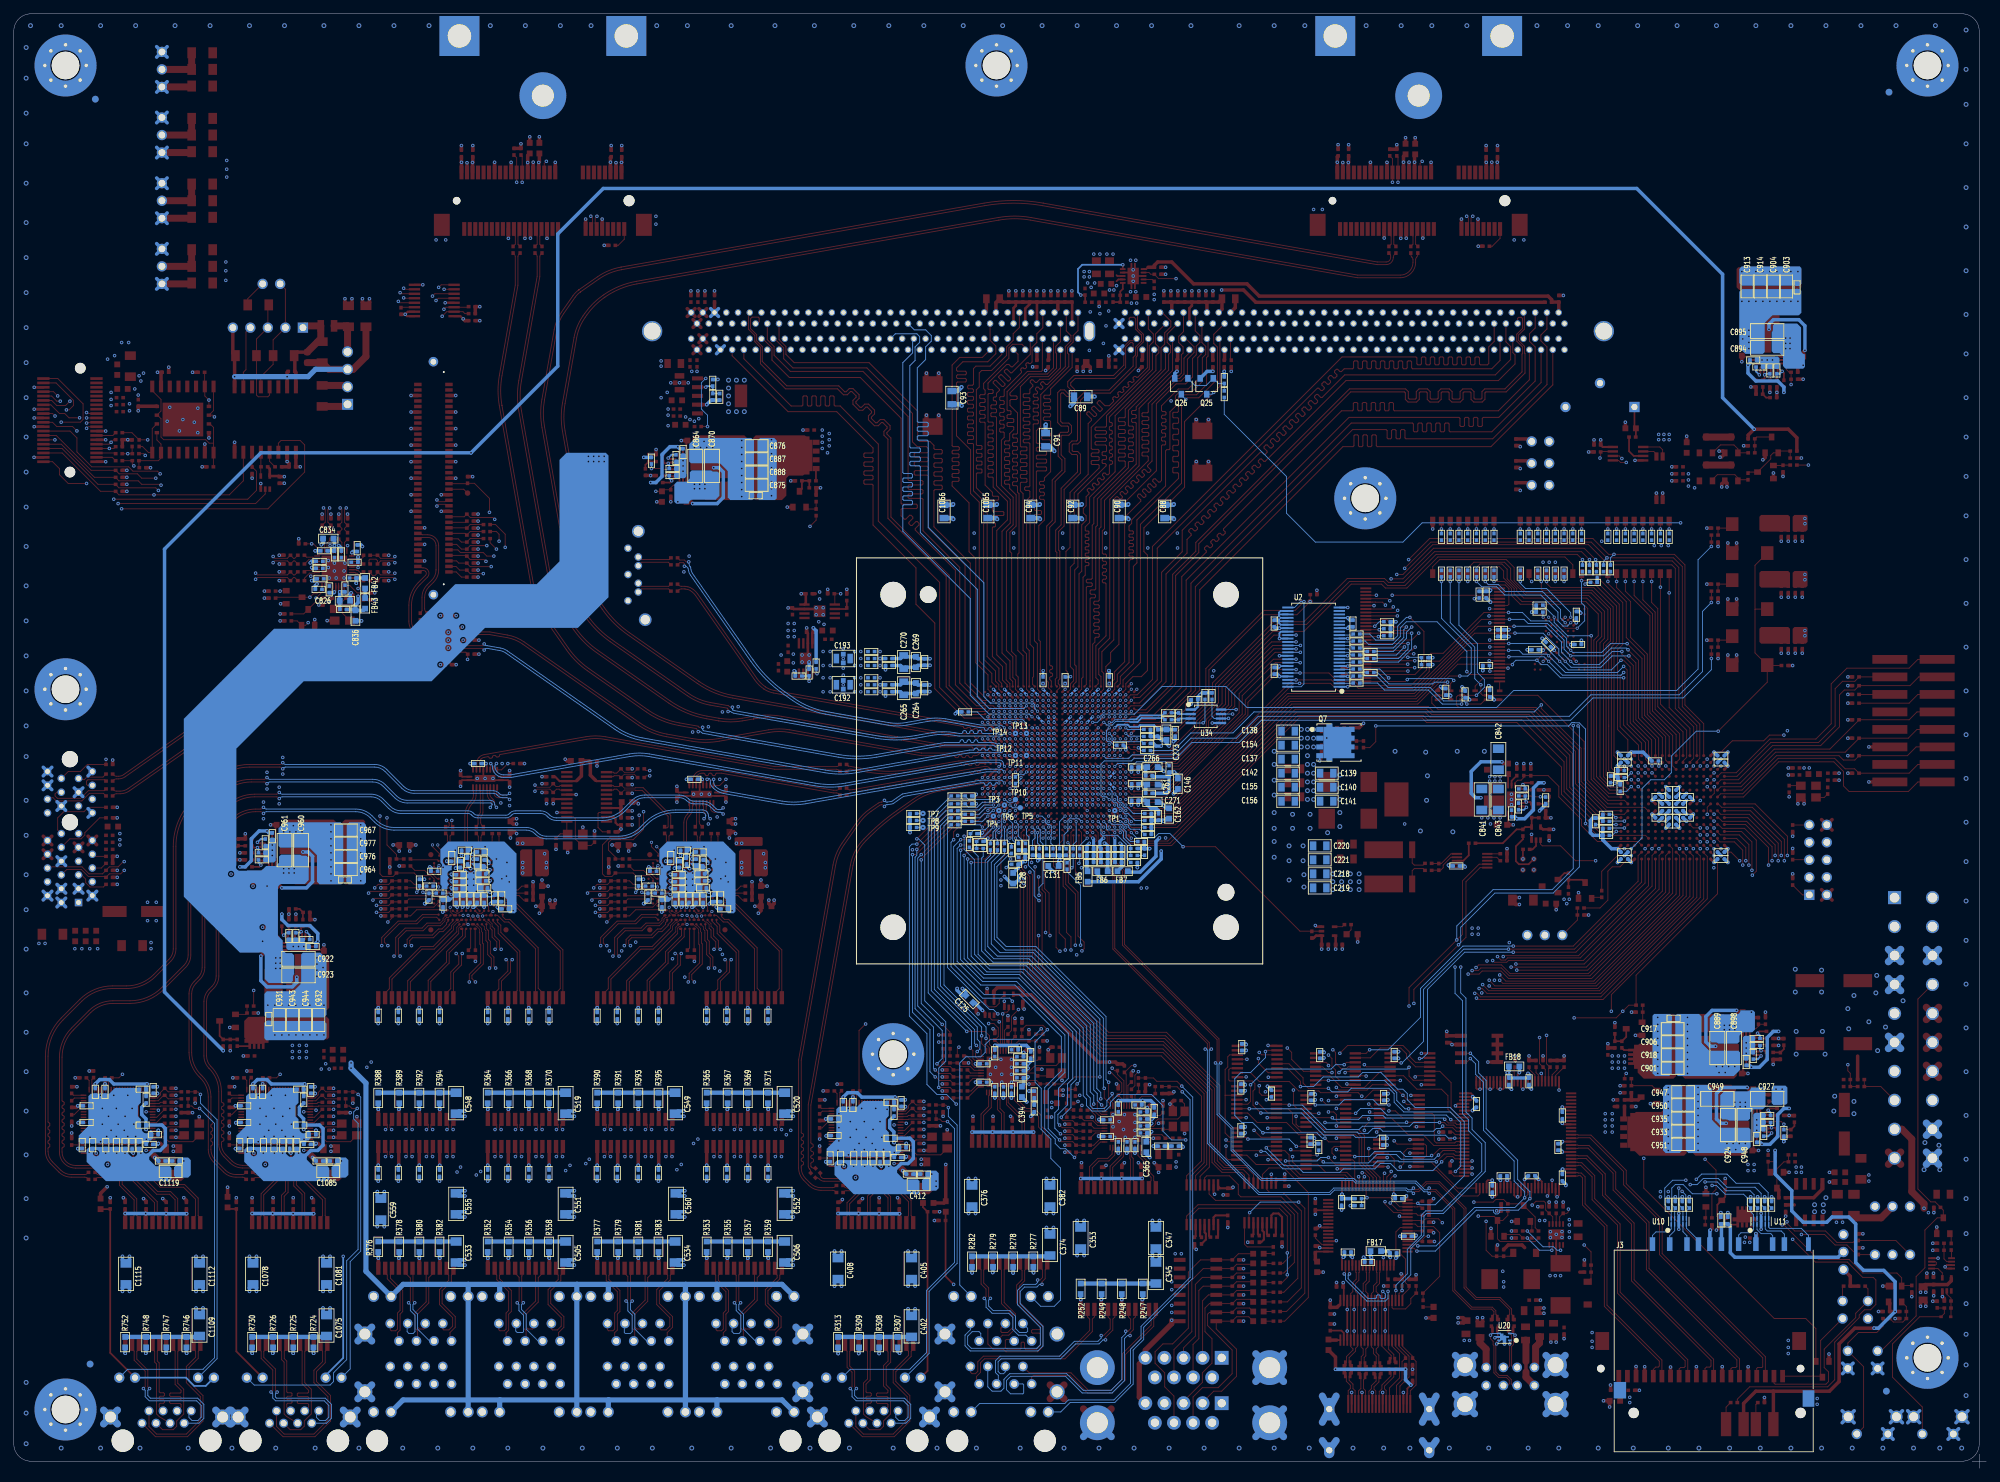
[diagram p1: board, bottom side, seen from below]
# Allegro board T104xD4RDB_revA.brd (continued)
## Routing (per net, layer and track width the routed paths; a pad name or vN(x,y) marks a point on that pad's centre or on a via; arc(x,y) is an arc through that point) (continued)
1V2_SLP: length 215.6
  TOP w0.254: U72.2 125.85,172.47 126.11,172.21
  TOP w0.381: J1.231 139.35,168.25 138.68,168.91 C256.1 ; C253.1 132.55,169.15 J1.223 ; C258.1 115.19,168.66 115.55,168.3 J1.209 ; J1.229 137.65,169.17 C5.2 ; J1.233 141.05,168.32 140.72,168.66 C254.1
  TOP w0.508: C249.1 C2.2 C6.2 C5.2 C256.1 C18.2 C254.1 C7.2 142.57,169.19 C248.1 143.6,169.13 J1.236 ; C249.1 134.62,168.15 J1.226 ; C249.1 C8.2 C253.1 ; R5.1 v1(109.47,159.13) ; C255.1 135.95,160.83 J1.83 ; C257.1 137.65,160.78 J1.85 ; C878.1 193.9,147.07 R567.2 v1(192.88,147.8) ; J1.206 113,169.03 C9.2 ; J1.61 112.15,160.76 C250.1 ; C252.1 C15.2 C1.2 C258.1 C10.2 C9.2 ; C252.1 118.1,169.05 J1.212 ; C252.1 C14.2 ; C21.1 105.92,169.16 107.7,170.94 v1(110.87,170.94) ; J1.59 110.45,160.8 C259.1 ; J1.204 110.82,168.15 C247.1 111.3,169.19 C17.2 C9.2 ; J1.73 122.35,160.84 C260.1 ; C251.1 117.25,160.86 J1.67
  TOP w0.635: v1(151.89,158.88) 151.89,157.86 152.53,157.23 C245.1 153.04,157.23 153.67,157.86 v1(153.67,158.88) ; v1(112.78,152.15) 112.78,151.13 113.41,150.5 C246.1 113.92,150.5 114.55,151.13 v1(114.55,152.15)
  L3SIG w0.508: v1(192.88,147.8) 190.98,147.8 190.37,147.19 184.15,147.19 181.36,149.99 176.9,149.99 v1(176.14,149.22)
  L4PWR w0.508: J1.76 125.46,164.44 ; J1.76 124.33,163.31 ; J1.76 125.46,163.31 ; J1.76 124.33,164.44 ; J1.70 120.36,164.44 ; J1.70 119.23,163.31 ; J1.70 119.23,164.44 ; J1.70 120.36,163.31 ; J1.223 133.11,165.51 ; J1.223 131.98,166.64 ; J1.223 131.98,165.51 ; J1.223 133.11,166.64 ; J1.233 141.61,165.51 ; J1.233 141.61,166.64 ; J1.233 140.48,166.64 ; J1.233 140.48,165.51 ; J1.88 140.76,163.31 ; J1.88 139.63,164.44 ; J1.88 140.76,164.44 ; J1.88 139.63,163.31 ; 143.03,167.11 J1.236 ; J1.236 144.16,167.11 ; J1.236 143.03,168.24 ; J1.236 144.16,168.24 ; 124.33,168.24 J1.220 ; J1.220 125.46,168.24 ; J1.220 125.46,167.11 ; J1.220 124.33,167.11 ; 114.98,166.64 J1.209 ; J1.209 114.98,165.51 ; J1.209 116.11,166.64 ; J1.209 116.11,165.51 ; 137.08,162.84 J1.85 ; J1.85 138.21,161.71 ; J1.85 137.08,161.71 ; J1.85 138.21,162.84 ; 141.33,163.31 J1.90 ; J1.90 142.46,164.44 ; J1.90 142.46,163.31 ; J1.90 141.33,164.44 ; 121.78,166.64 J1.217 ; J1.217 122.91,165.51 ; J1.217 121.78,165.51 ; J1.217 122.91,166.64 ; J1.229 138.21,165.51 ; J1.229 137.08,166.64 ; J1.229 138.21,166.64 ; J1.229 137.08,165.51 ; J1.206 113.56,168.24 ; J1.206 112.43,167.11 ; J1.206 112.43,168.24 ; J1.206 113.56,167.11 ; J1.215 121.21,165.51 ; J1.215 120.08,165.51 ; J1.215 120.08,166.64 ; J1.215 121.21,166.64 ; 132.83,164.44 J1.80 ; J1.80 133.96,163.31 ; J1.80 132.83,163.31 ; J1.80 133.96,164.44 ; J1.67 117.81,161.71 ; J1.67 116.68,161.71 ; J1.67 117.81,162.84 ; J1.67 116.68,162.84 ; 138.78,165.51 J1.231 ; J1.231 139.91,166.64 ; J1.231 138.78,166.64 ; J1.231 139.91,165.51 ; J1.61 112.71,162.84 ; J1.61 112.71,161.71 ; J1.61 111.58,162.84 ; J1.61 111.58,161.71 ; J1.204 111.86,167.11 ; J1.204 110.73,167.11 ; J1.204 111.86,168.24 ; J1.204 110.73,168.24 ; 114.13,164.44 J1.64 ; J1.64 115.26,164.44 ; J1.64 114.13,163.31 ; J1.64 115.26,163.31 ; 117.53,168.24 J1.212 ; J1.212 118.66,168.24 ; J1.212 118.66,167.11 ; J1.212 117.53,167.11 ; J1.73 122.91,162.84 ; J1.73 121.78,162.84 ; J1.73 121.78,161.71 ; J1.73 122.91,161.71 ; 143.03,163.31 J1.92 ; J1.92 143.03,164.44 ; J1.92 144.16,164.44 ; J1.92 144.16,163.31 ; J1.59 111.01,161.71 ; J1.59 109.88,161.71 ; J1.59 109.88,162.84 ; J1.59 111.01,162.84 ; J1.83 136.51,162.84 ; J1.83 135.38,162.84 ; J1.83 136.51,161.71 ; J1.83 135.38,161.71 ; J1.226 135.66,168.24 ; J1.226 134.53,168.24 ; J1.226 134.53,167.11 ; J1.226 135.66,167.11
  vias: v1(126.11,171.58) v1(126.49,170.94) v1(127.13,170.94) v1(176.14,148.21) v1(176.14,147.19) v1(176.14,146.18) v1(176.14,145.16) v1(176.14,144.15) v1(176.14,143.13) v1(176.14,142.11) v1(176.14,141.1)
1V5: length 35.2
  TOP w0.508: J27.6 v1(199.5,189.48) 199.5,190.17 C753.1 ; J27.48 v1(219.5,189.44) 219.46,189.48 C754.1 ; J27.28 v1(211.5,189.44) 211.5,190.46 C751.1 ; J28.28 v1(84.5,189.48) 84.5,190.33 C752.1 ; J28.48 v1(92.5,189.44) 92.46,189.48 C756.1 ; C902.1 33.38,156.85 R582.2 v1(34.13,156.88) ; C755.1 72.52,189.48 v1(72.5,189.46) J28.6
  L3SIG w0.508: v1(34.13,156.88) 34.13,159.04 33.53,159.64 33.53,165.74 36.32,168.53 36.32,172.73 v1(35.43,173.62)
  vias: v1(27.31,173.62) v1(28.32,173.62) v1(29.34,173.62) v1(30.35,173.62) v1(31.37,173.62) v1(32.39,173.62) v1(33.4,173.62) v1(34.42,173.62)
1V05_EC1_AVDD: length 5.4
  TOP w0.203: U42.3 v1(123.44,45.72) ; v1(120.97,50.67) 121.11,50.53 U42.40 ; U42.9 v1(125.84,45.74)
  BOTTOM w0.508: C363.1 123.44,45.73 v1(123.44,45.72) ; R267.2 120.65,50.99 v1(120.97,50.67) C362.1 ; C364.1 125.86,45.75 v1(125.84,45.74)
  vias: v1(117.48,44.45) v1(117.48,43.69)
1V05_EC1_DVDD: length 9
  TOP w0.203: U42.28 v1(125.84,53.32) ; v1(122.3,53.34) 122.64,53 U42.36
  BOTTOM w0.508: R267.1 120.65,52.83 121.16,53.34 v1(122.3,53.34) ; v1(122.3,53.34) 122.45,53.19 C358.1 ; v1(122.3,53.34) 125.82,53.34 v1(125.84,53.32) 125.86,53.31 C359.1
1V05_EC2_AVDD: length 5.4
  TOP w0.203: U45.3 v1(141.35,53.72) ; v1(138.94,58.67) 139.08,58.53 U45.40 ; U45.9 v1(143.75,53.74)
  BOTTOM w0.508: C393.1 141.35,53.73 v1(141.35,53.72) ; v1(143.75,53.74) 143.76,53.75 C392.1 ; R297.2 138.56,59.05 v1(138.94,58.67) C391.1
  vias: v1(135.51,53.09) v1(135.51,52.32)
1V05_EC2_DVDD: length 8.8
  TOP w0.203: U45.28 v1(143.75,61.32) ; U45.36 140.55,61 v1(140.21,61.34)
  BOTTOM w0.508: v1(140.21,61.34) 140.36,61.19 C388.1 ; v1(140.21,61.34) 143.73,61.34 v1(143.75,61.32) 143.76,61.31 C387.1 ; v1(140.21,61.34) 139.19,61.34 138.56,60.71 R297.1
1V05_SG1_AVDD: length 19
  TOP w0.203: v1(243.97,49.15) 243.8,49.31 U82.79 ; U82.12 v1(248.23,45.72) ; U82.23 252.36,45.71 v1(252.22,45.85) 252.49,46.11 U82.24 ; U82.3 244.63,45.62 v1(244.73,45.72) ; U82.9 v1(247.03,45.72) ; U82.16 v1(249.83,45.72)
  BOTTOM w0.508: C1095.1 241.68,49.78 241.17,49.28 241.17,46.86 241.94,46.1 242.95,46.1 243.71,45.34 ; C1095.1 243.99,49.17 v1(243.97,49.15) ; C1095.1 243.99,50.7 244.6,51.31 244.6,52.35 R745.2
  vias: v1(240.67,42.04) v1(241.43,42.04)
1V05_SG1_DVDD: length 12.3
  TOP w0.203: U82.66 v1(243.83,55.74) ; U82.47 251.43,55.65 v1(251.33,55.75)
  BOTTOM w0.508: R745.1 243.97,54.97 C1088.1 243.99,55.58 v1(243.83,55.74) 248.66,55.74 249.3,56.39 250.7,56.39 v1(251.33,55.75) C1087.1
1V05_SG2_AVDD: length 19
  TOP w0.203: U83.3 267.49,45.62 v1(267.59,45.72) ; U83.79 266.66,49.31 v1(266.83,49.15) ; U83.12 v1(271.09,45.72) ; U83.16 v1(272.69,45.72) ; U83.23 275.22,45.71 v1(275.08,45.85) 275.35,46.11 U83.24 ; U83.9 v1(269.89,45.72)
  BOTTOM w0.508: C1126.1 264.54,49.78 264.03,49.28 264.03,46.86 264.8,46.1 265.81,46.1 266.57,45.34 ; C1126.1 266.85,50.7 267.46,51.31 267.46,52.35 R767.2 ; C1126.1 266.85,49.17 v1(266.83,49.15)
  vias: v1(263.52,42.04) v1(264.29,42.04)
1V05_SG2_DVDD: length 12.3
  TOP w0.203: U83.66 v1(266.69,55.74) ; U83.47 274.29,55.65 v1(274.19,55.75)
  BOTTOM w0.508: C1121.1 v1(274.19,55.75) 273.56,56.39 272.16,56.39 271.52,55.74 v1(266.69,55.74) 266.85,55.58 C1122.1 266.83,54.97 R767.1
1V05_SG_AVDD: length 19
  TOP w0.203: v1(159.13,43.81) 159.03,43.72 U48.3 ; U48.79 158.21,47.41 v1(158.37,47.24) ; U48.9 v1(161.43,43.81) ; U48.24 166.89,44.21 v1(166.62,43.94) 166.76,43.81 U48.23 ; U48.12 v1(162.63,43.81) ; U48.16 v1(164.23,43.81)
  BOTTOM w0.508: v1(158.37,47.24) 158.39,47.27 C424.1 ; C424.1 158.39,48.79 159,49.4 159,50.44 R329.2 ; C424.1 156.08,47.88 155.58,47.37 155.58,44.96 156.34,44.2 157.35,44.2 158.12,43.43
  vias: v1(155.07,40.13) v1(155.83,40.13)
1V05_SG_DVDD: length 12.3
  TOP w0.203: U48.47 165.83,53.75 v1(165.74,53.85) ; U48.66 v1(158.23,53.84)
  BOTTOM w0.508: R329.1 158.37,53.06 C415.1 158.39,53.68 v1(158.23,53.84) 163.06,53.84 163.7,54.48 165.1,54.48 v1(165.74,53.85) C414.1
1V8: length 45.9
  TOP w0.254: U3.29 71.63,127.65 71.88,127.4 v1(71.88,127.38)
  TOP w0.305: U1.G9 v2(127.97,97.82) ; U4.G4 v2(60.25,119.47) ; U1.J18 v2(129.57,105.82) ; U1.J15 v2(129.57,103.42) ; U1.J19 v2(129.57,106.62) ; U1.J14 v2(129.57,101.82) ; U1.J16 v2(129.57,104.22) ; U4.J6 v2(62.65,118.67) ; U1.J17 v2(129.57,105.02) ; U4.H8 v2(64.25,118.67) ; U4.D3 v2(59.45,122.67)
  TOP w0.381: U5.5 v1(77.66,112.07) ; U6.5 v1(71.36,111.49) ; U7.5 v1(74.92,111.49)
  TOP w0.508: v1(92.58,116.38) 92.78,116.18 C29.1 ; v1(37.59,142.37) 37.59,142.93 Q16.2 38.35,142.8 v1(38.35,142.37)
  BOTTOM w0.254: U2.42 v1(102.49,116.38) ; U2.7 v1(92.58,116.38) ; U2.31 v1(102.49,121.88) ; U2.18 v1(92.58,121.88)
  BOTTOM w0.508: R53.2 R56.2 v1(65.91,124.21) ; 118.49,100.33 118.49,98.3 118.87,97.92 R174.1 ; 118.49,100.33 120.8,100.33 R177.1 ; 118.49,100.33 R14.2 v1(117.73,100.99) 117.22,100.48 C146.1 ; v1(119.63,104.78) 120.4,104.78 120.78,105.16 R91.2 ; v2(59.45,122.67) 59.44,122.68 C36.1 ; C35.1 63.15,119.17 v2(62.65,118.67) ; v1(117.86,105.41) 117.6,105.66 R181.1 ; R55.2 R51.2 R54.2 v1(85.6,122.81) ; C43.1 71.78,111.91 v1(71.36,111.49) ; C30.1 103.05,121.88 v1(102.49,121.88) ; R52.2 v1(73,115.72) ; C33.1 60.21,119.51 v2(60.25,119.47) ; C39.1 75.21,111.79 v1(74.92,111.49) ; R111.2 56.41,129.26 ; C40.1 77.75,112.17 v1(77.66,112.07) ; C31.1 102.69,116.18 v1(102.49,116.38) ; v2(64.25,118.67) 64.32,118.75 C34.1 ; R50.2 C38.1 72.03,127.23 v1(71.88,127.38) ; v1(92.58,121.88) 92.39,122.07 C32.1 ; R16.1 v1(80.26,117.6)
  vias: v1(26.29,137.8) v1(26.29,137.03) v1(52.45,59.82) v1(52.45,58.93) v1(52.45,58.04) v1(53.34,59.82) v1(53.34,58.93) v1(53.34,58.04) v1(54.23,59.82) v1(54.23,58.93) v1(54.23,58.04) v1(62.48,131.44) v1(63.37,131.44) v1(64.26,131.44) v1(119,91.44)
1V8_0641_VDD: length 8.7
  TOP w0.203: U79.16 242.75,130.76 v1(242.82,130.68) ; U79.31 237.02,132.77 236.98,132.81 v1(236.98,132.84)
  BOTTOM w0.508: C837.1 242.7,130.56 v1(242.82,130.68) ; FB43.2 235.33,124.46 C836.1 ; v1(236.09,126.49) 236.09,125.6 236.47,125.22 C836.1 ; v1(236.98,132.84) 236.83,132.99 C838.1 ; R532.1 236.6,124.59 C836.1 ; R533.1 v1(242.32,133.1)
1V8_0641_VDDA: length 3.8
  TOP w0.203: v1(239.52,133.86) 239.52,133.73 239.32,133.53 U79.26
  BOTTOM w0.508: R533.2 239.55,133.1 C835.1 v1(239.52,133.86) 239.52,134.75 C834.1
1V8_0641_VDDIO: length 12.7
  TOP w0.203: U79.39 236.6,129.16 236.35,128.91 v1(236.35,128.39) ; v1(243.03,131.36) 242.86,131.36 242.66,131.16 U79.17 ; v1(239.52,127.13) 239.32,127.33 U79.5 ; v1(238.89,133.86) 238.92,133.82 U79.27 ; v1(236.09,132.21) 236.34,131.96 U79.32 ; U79.12 242.53,129.16 242.82,128.86 v1(242.82,128.78)
  BOTTOM w0.508: v1(236.09,132.21) 236.12,132.18 C828.1 ; C833.1 242.32,129.03 242.57,128.78 v1(242.82,128.78) ; v1(243.03,131.36) 242.81,131.57 C832.1 ; v1(238.89,133.86) 238.51,133.48 C831.1 ; FB42.1 C830.1 236.37,128.42 v1(236.35,128.39) ; C829.1 239.62,127.03 v1(239.52,127.13)
1V8_0641_VDDXTAL: length 4.3
  TOP w0.203: v1(238.76,127.13) 238.92,127.29 U79.4
  BOTTOM w0.508: R532.2 238.73,125.83 C826.1 v1(238.76,127.13) 238.73,127.15 C827.1
1V8_MTR: length 82.1
  TOP w0.305: U1.F11 v2(127.17,99.42)
  TOP w0.508: J7.1 66.27,142.98 R172.2
  L3SIG w0.508: J7.1 76.84,142.62 86.49,132.97 94.11,132.97 106.81,120.27 108.65,120.27 113.16,115.76 113.16,114.05 120.27,106.93 120.27,104.14 122.3,102.11 122.3,100.58 123.19,99.69 123.44,99.69
  BOTTOM w0.305: v2(127.17,99.42) 126.95,99.2 C161.1
1V8_SFP: length 82.2
  TOP w0.305: U1.F12 v2(127.17,100.22)
  TOP w0.508: R171.2 66.27,146.15 J6.1
  L3SIG w0.508: J6.1 74.93,145.8 86.87,133.86 94.36,133.86 107.19,121.03 109.16,121.03 114.05,116.14 114.05,114.3 121.03,107.31 121.03,104.39 123.57,101.85 123.57,101.6
  BOTTOM w0.305: v2(127.17,100.22) 126.96,100.42 C144.1
1V8_SLP: length 88
  TOP w0.203: U79.11 242.02,128.31 v1(242.06,128.27)
  TOP w0.305: U1.J11 v2(129.57,99.42) ; U1.J13 v2(129.57,101.02) ; U1.J12 v2(129.57,100.22)
  TOP w0.381: U57.F9 v1(46.47,98.88) ; U57.A3 v1(39.47,103.88) ; U57.C16 v1(53.47,101.88) ; C49.1 96.37,77.24 U13.1 97.17,77.26 97.51,76.92 R110.2 ; U57.A14 v1(51.47,103.88) ; U57.H8 v1(44.47,96.88) ; U57.P16 v1(53.47,89.89) ; U57.H10 v1(47.47,96.88) ; U57.J11 v1(48.47,94.89) ; U57.H11 v1(48.47,96.88) ; U57.J7 v1(43.47,94.89) ; U57.J9 v1(46.47,94.89) ; U57.F8 v1(44.47,98.88)
  TOP w0.508: R508.1 v1(244.7,134.85) ; C49.1 v1(96.37,75.31) ; R525.1 v1(241.78,125.25) ; R523.1 v1(233.68,127) ; C908.1 29.87,59.31 R586.2 v1(30.89,58.58)
  L3SIG w0.508: 63.37,142.62 64.13,143.38 ; 63.37,142.62 64.13,141.86 ; 63.37,142.62 62.61,143.38 ; 63.37,142.62 62.61,141.86 ; 62.61,145.03 63.37,145.8 ; 63.37,145.8 64.13,146.56 ; 63.37,145.8 64.13,145.03 ; 63.37,145.8 62.61,146.56 ; v1(30.89,58.58) 32.93,58.58 33.4,59.05 39.5,59.05 42.04,56.52 46.87,56.52 v1(47.63,57.28)
  BOTTOM w0.508: v1(48.47,94.89) 47.97,94.39 C780.1 ; C794.1 51.96,103.39 v1(51.47,103.88) 49.76,103.88 R104.1 ; C795.1 47.97,97.38 v1(48.47,96.88) ; U57.F9 45.97,98.39 v1(46.47,98.88) ; C792.1 38.97,103.39 v1(39.47,103.88) ; U57.F8 44.96,98.39 v1(44.47,98.88) ; R92.2 53.67,100.43 R79.2 ; R105.1 53.09,99.57 53.44,99.92 R79.2 ; C793.1 52.97,102.38 v1(53.47,101.88) 53.44,101.86 R78.2 R79.2 ; v1(242.06,128.27) 242.29,128.04 C839.1 ; FB42.2 FB43.1 ; 55.6,94.36 55.63,94.34 R95.2 57.05,94.34 57.41,93.98 57.41,92.21 57.02,91.82 R81.2 ; 55.6,94.36 R90.2 ; 55.6,94.36 R106.1 ; R81.2 R94.2 ; R81.2 55.6,91.16 54.33,89.89 v1(53.47,89.89) 52.97,89.39 C791.1 ; R82.2 R83.2 R93.2 ; R93.2 R80.2 ; R93.2 120.04,93.98 R180.1 119.41,94.01 v1(119.25,93.85) 118.87,94.23 C162.1 ; U57.J7 v1(43.47,94.89) ; U57.J9 v1(46.47,94.89) ; U57.H10 v1(47.47,96.88) ; FB7.2 124.33,86.49 122.68,86.49 120.4,88.77 120.4,90.93 v1(119.89,91.44) ; U57.H8 v1(44.47,96.88)
  vias: v1(26.29,129.67) v1(26.29,128.91) v1(26.29,121.54) v1(26.29,120.78) v1(47.63,65.41) v1(47.63,64.39) v1(47.63,63.37) v1(47.63,62.36) v1(47.63,61.34) v1(47.63,60.33) v1(47.63,59.31) v1(47.63,58.29) v1(172.85,122.56) v1(172.85,121.54) v1(172.85,120.65) v1(173.74,122.56) v1(173.74,121.54) v1(173.74,120.65) v1(233.68,127.76)
1V8_USB_OVDD: length 5.5
  TOP w0.305: U1.J9 v2(129.57,97.82) ; U1.J10 v2(129.57,98.62)
  BOTTOM w0.457: v2(125.6,90.68) 125.37,90.45 C122.1
  BOTTOM w0.508: FB7.1 125.37,87.22 C124.1 C123.1 C122.1
1V35X: length 1.2
  BOTTOM w0.508: R178.2 v1(159.61,115.85) ; R175.2 v1(159.61,112.04)
  vias: v1(167.64,118.49) v1(167.64,116.46) v1(168.66,118.49) v1(168.66,116.46)
2V5: length 75
  TOP w0.127: U52.E12 221.72,87.3 v2(221.97,87.05) ; U51.E26 184.33,83.43 184.33,83.71 U51.E24 184.33,84.73 184.33,85.01 U51.E22 184.94,85.52 v2(185.22,85.24) ; v2(190.22,87.05) 189.97,87.3 U51.E12 ; U52.E26 216.08,83.43 216.08,83.71 U52.E24 216.08,84.73 216.08,85.01 U52.E22 216.69,85.52 v2(216.97,85.24) ; U51.E20 185.22,86.82 v1(185.22,86.82) 185.97,87.57 U51.E18 ; U52.E18 217.72,87.57 v1(216.97,86.82) 216.97,86.82 U52.E20 ; U51.E9 U51.E8 190.85,86.17 v2(190.83,86.18) ; U52.E6 222.86,84.87 222.58,84.58 v2(222.58,84.2) 222.58,83.85 222.86,83.57 U52.E4 U52.E3 ; v2(222.58,86.18) 222.6,86.17 U52.E8 U52.E9 ; U51.E6 191.11,84.87 190.83,84.58 v2(190.83,84.2) 190.83,83.85 191.11,83.57 U51.E4 U51.E3
  TOP w0.203: U45.21 146.41,58.53 v1(146.56,58.67) ; v1(253.87,52.58) 253.81,52.51 U82.40 ; v1(168.28,50.67) 168.21,50.61 U48.40 ; U83.34 v1(276.68,50.11) ; U45.15 146.43,56.13 v1(146.56,56.01) ; U83.40 276.67,52.51 v1(276.73,52.58) ; U48.34 v1(168.22,48.21) ; U82.34 v1(253.82,50.11)
  TOP w0.305: U1.W8 v2(138.37,97.02) ; U1.V8 v2(137.57,97.02)
  TOP w0.508: R312.1 v1(168.4,53.44) ; v1(182.25,91.44) C457.1 181.61,92.33 v1(181.36,92.08) ; R728.1 254.1,52.35 v1(253.87,52.58) ; v1(178.97,85.09) R334.2 R333.2 R335.2 ; R718.2 146.43,66.17 v1(146.18,65.91) ; R302.2 v1(151.38,57.78) ; v1(210.72,85.09) R345.2 R344.2 R346.2 ; R311.1 168.5,50.44 v1(168.28,50.67) ; R336.1 v1(199.75,87.22) R330.2 ; R731.1 v1(252.22,57.63) ; R314.1 v1(166.62,55.73) ; R729.1 v1(254,55.35) ; v1(276.73,52.58) 276.96,52.35 R750.1 ; R303.2 v1(151.38,53.72) ; v1(208.53,84.45) FB25.2 v1(209.42,85.34) ; v1(228.6,89.53) C489.1 v1(227.71,90.42) ; v1(214,91.44) C490.1 213.36,92.33 v1(213.11,92.08) ; R347.1 v1(231.5,87.22) R341.2 ; R753.1 v1(275.08,57.63) ; v1(195.96,90.42) C456.1 v1(196.85,89.53) ; R751.1 v1(276.86,55.35) ; v1(176.78,84.45) FB23.2 v1(177.67,85.34) ; R300.2 v1(151.38,55.75) ; R301.2 v1(151.38,56.77)
  BOTTOM w0.508: v1(168.22,48.21) 168.17,48.26 C430.1 ; v2(190.22,87.05) 190.12,87.15 C460.1 ; v2(190.83,86.18) 190.75,86.11 C458.1 ; v2(221.97,87.05) 221.87,87.15 C494.1 ; C462.1 185.24,85.22 v2(185.22,85.24) ; v2(190.83,84.2) 190.7,84.07 C461.1 ; v1(185.22,86.82) 185.81,86.23 C459.1 ; C1136.1 276.62,50.16 v1(276.68,50.11) ; C385.1 v1(146.56,56.01) ; C491.1 222.5,86.11 v2(222.58,86.18) ; C492.1 217.56,86.23 v1(216.97,86.82) ; C1137.1 v1(276.73,52.58) ; v2(216.97,85.24) 216.99,85.22 C493.1 ; C1102.1 v1(253.87,52.58) ; C495.1 222.45,84.07 v2(222.58,84.2) ; v1(148.46,69.6) 147.99,69.12 C125.1 148.49,68.61 149.23,69.34 v1(149.23,69.6) ; C1103.1 253.76,50.16 v1(253.82,50.11) ; C386.1 v1(146.56,58.67) ; C429.1 v1(168.28,50.67)
  vias: v1(243.59,61.34) v1(243.59,60.45) v1(243.59,59.56) v1(244.6,61.34) v1(244.6,60.45) v1(244.6,59.56) v1(245.62,61.34) v1(245.62,60.45) v1(245.62,59.56)
2V5_LED: length 222.3
  BOTTOM w0.762: J21.B9 174.62,9.91 184.02,9.91 ; J21.A9 174.62,26.67 184.02,26.67 ; J21.C11 199.81,26.63 199.77,26.67 ; 204.34,26.67 204.38,26.64 J21.E9 204.38,9.94 204.34,9.91 ; 204.34,26.67 215.52,26.67 ; 204.34,26.67 199.77,26.67 ; J21.D9 188.63,9.81 188.72,9.91 ; 188.6,26.67 199.77,26.67 ; 188.6,26.67 184.02,26.67 ; 188.6,26.67 188.63,26.64 J21.C9 188.63,10 188.72,9.91 ; 199.77,9.91 199.81,9.87 J21.D11 ; 199.77,9.91 188.72,9.91 ; 199.77,9.91 204.34,9.91 ; 220.09,26.67 220.13,26.63 J21.G9 220.13,9.94 220.09,9.91 ; 220.09,26.67 215.52,26.67 ; 220.09,26.67 229.56,26.67 J21.G11 234.95,28.57 234.95,55.88 v1(237.11,58.04) v1(237.11,58.8) ; 204.34,9.91 215.52,9.91 ; 204.34,9.91 204.38,9.87 J21.F9 ; 215.52,9.91 215.56,9.87 J21.F11 ; 215.52,9.91 220.09,9.91 ; 184.02,26.67 184.06,26.64 J21.A11 ; J21.H9 220.13,9.87 220.09,9.91 ; 188.72,9.91 184.02,9.91 ; 220.09,9.91 229.57,9.91 J21.H11 ; 184.02,9.91 184.06,9.87 J21.B11 ; 215.52,26.67 215.56,26.63 J21.E11
2V5_SLP: length 59.8
  TOP w0.203: v1(128.71,48.2) 128.65,48.13 U42.15 ; v1(128.65,50.61) 128.57,50.53 U42.21
  TOP w0.305: U1.U8 v2(136.77,97.02) ; U1.T8 v2(135.97,97.02)
  TOP w0.381: U81.5 141,68.68 C1068.1 ; C1067.1 143.88,68.92 U80.5
  TOP w0.508: R271.2 v1(133.6,48.9) ; R273.2 v1(133.6,45.85) ; R139.1 125.22,58.65 R140.1 126.26,58.93 v1(127.13,58.93) 128.78,58.93 138.53,68.68 C1068.1 139.7,69.09 140.34,69.72 143.41,69.72 143.92,69.22 C1067.1 ; v1(242.35,79.6) R602.2 243.08,80.62 C937.1 ; R272.2 v1(133.6,49.91) ; R270.2 v1(133.6,47.88)
  L3SIG w0.508: v1(241.05,62.86) 240.16,63.75 240.16,68.58 242.31,70.73 242.33,70.73 242.7,71.1 242.7,71.12 242.95,71.37 242.95,77.09 242.35,77.69 v1(242.35,79.6)
  BOTTOM w0.508: C356.1 128.59,50.55 v1(128.65,50.61) ; C128.1 140.36,87.1 R87.2 140.08,87.63 139.67,88.04 v1(139.34,88.04) R85.2 139.34,89.66 R84.2 R86.2 ; v1(128.71,48.2) 128.65,48.13 C357.1
  vias: v1(141.48,88.39) v1(242.06,62.86) v1(243.08,62.87) v1(244.09,62.87) v1(245.11,62.86) v1(246.13,62.86) v1(247.14,62.86) v1(248.16,62.86)
2V5_VPP: length 3.5
  TOP w0.508: U74.2 v1(185.55,154.31)
  BOTTOM w0.508: C1011.2 R644.2 184.89,154.97 v1(185.55,154.31)
2V5A_QSG1: length 12.6
  TOP w0.102: U51.E37 190.07,80.54 189.98,80.54 189.83,80.54 U51.E35
  TOP w0.127: v2(189.2,81.41) 189.32,81.3 U51.E35 ; U51.E33 188.02,81.07 v2(187.68,81.41) 187.26,81.41 U51.E31 ; U51.E27 184.76,82.27 v2(185.17,81.86) 185.42,81.61 U51.E29
  TOP w0.508: v1(178.05,80.52) 177.67,80.9 C444.1 v1(178.56,81.53)
  TOP w0.635: FB23.1 C444.1
  BOTTOM w0.508: C445.1 C448.1 184.84,82.19 v2(185.17,81.86) ; v2(187.68,81.41) 187.58,81.41 187.07,81.91 C447.1 ; v2(189.2,81.41) 189.1,81.51 C446.1
2V5A_QSG2: length 12.6
  TOP w0.102: U52.E37 221.82,80.54 221.73,80.54 221.58,80.54 U52.E35
  TOP w0.127: U52.E33 219.77,81.07 v2(219.43,81.41) 219.01,81.41 U52.E31 ; U52.E29 217.17,81.61 v2(216.92,81.86) 216.51,82.27 U52.E27 ; U52.E35 221.07,81.3 v2(220.95,81.41)
  TOP w0.508: v1(210.31,81.53) C477.1 209.42,80.9 v1(209.8,80.52)
  TOP w0.635: FB25.1 C477.1
  BOTTOM w0.508: C481.1 218.82,81.91 219.33,81.41 v2(219.43,81.41) ; C480.1 220.85,81.51 v2(220.95,81.41) ; v2(216.92,81.86) 216.59,82.19 C479.1 C478.1
3V3: length 277.5
  TOP w0.203: U83.85 265.25,46.91 v1(265.05,47.12) 265.24,47.31 U83.84 ; U82.67 242.56,54.11 v1(242.32,54.36) ; U45.41 139.03,58.13 v1(138.94,58.04) ; v1(164.34,53.85) 164.23,53.74 U48.51 ; U83.51 272.69,55.65 v1(272.8,55.75) ; U45.37 139.75,60.15 v1(139.57,60.33) ; U48.67 156.96,52.21 v1(156.72,52.45) ; U82.80 242.3,48.91 v1(242.19,49.02) ; v1(156.59,47.12) 156.7,47.01 U48.80 ; U48.6 v1(160.23,43.81) ; U48.25 168.12,44.61 v1(168.28,44.45) ; U82.6 v1(245.83,45.72) ; v1(253.87,46.35) 253.72,46.51 U82.25 ; U45.6 v1(142.55,53.72) ; U45.44 139.1,56.93 v1(138.94,56.77) 139.18,56.53 U45.45 ; v1(265.05,49.02) 265.16,48.91 U83.80 ; U83.6 v1(268.69,45.72) ; v1(265.18,54.36) 265.42,54.11 U83.67 ; U83.25 276.58,46.51 v1(276.73,46.35) ; U48.84 156.79,45.41 v1(156.59,45.21) 156.8,45.01 U48.85 ; U82.51 249.83,55.65 v1(249.94,55.75) ; U82.85 242.39,46.91 v1(242.19,47.12) 242.38,47.31 U82.84
  TOP w0.254: U18.1 222.76,123.47 C69.1 ; U35.1 83.91,39.33 v1(84.07,39.5) ; v1(217.55,102.23) 217.43,102.11 U17.6 ; U17.1 221,100.33 C65.1 ; U37.95 v1(74.49,51.89) ; U3.43 v1(69.22,120.65) ; U37.30 v1(61.47,52.39) ; U35.23 88.91,30.36 v1(89.15,30.61) ; U37.61 v1(66.95,41.89) ; U35.45 97.22,37.43 C312.1 ; C63.1 189.63,98.04 U16.1 ; U16.10 182.99,98.04 C62.1 ; U37.68 v1(70.45,41.78) ; U35.12 84.8,33.43 v1(85.03,33.66) ; U37.13 67.95,57.15 v1(67.69,57.4) ; U17.10 214.35,100.33 C66.1 ; v1(186.18,99.95) 186.06,99.83 U16.6 ; U37.78 74.72,43.39 v1(74.55,43.56) 74.87,43.89 U37.79 ; U37.53 v1(62.95,41.78) ; U35.49 v1(93.41,39.75) ; U37.70 71.45,41.6 v1(71.63,41.78) 72.26,41.78 72.45,41.6 U37.72 ; U37.48 v1(61.42,43.39) ; C67.1 222.76,116.82 U18.10 ; C307.1 93.15,26.2 U36.2 ; U37.40 v1(61.45,47.39) ; v1(220.85,120.14) 221.1,119.89 U18.6 ; U35.29 v1(91.91,30.61)
  TOP w0.305: U1.R8 v2(135.17,97.02) ; v1(97.41,47.88) 97.53,48 U22.16 ; C818.1 198.45,93.34 198.75,93.65 198.75,94.18 199.06,94.49 200.07,94.49 U58.11 ; U1.P8 v2(133.57,97.02) ; v1(220.85,166.75) 221.24,167.14 U12.16 ; v1(107.32,61.47) 107.5,61.28 U27.16 ; U39.16 96.15,60.19 v1(96.01,60.33) ; C819.1 207.74,97.08 U58.18 ; U12.2 228.88,167.79 v1(229.26,167.41) 228.99,167.14 U12.1 ; U28.16 87.01,54.09 v1(86.74,54.36) ; U26.16 107.66,55.41 v1(107.44,55.63) ; U21.16 85.48,60.19 v1(85.22,60.45) ; v1(107.44,49.53) 107.66,49.32 U24.16 ; U30.16 103.01,41.58 102.7,41.88 C285.1 ; U29.16 111.39,40.92 111.09,40.61 C276.1 ; U1.M8 v2(131.97,97.02) ; U12.13 v1(223.46,169.09) ; U1.N8 v2(132.77,97.02) ; U23.16 97.42,54.09 v1(97.28,54.23)
  TOP w0.381: C337.1 247.61,143.95 U41.5 248.91,144.99 R246.2 ; U25.14 87.08,47.67 v1(86.87,47.88)
  TOP w0.508: U32.8 78.21,62.74 C293.1 v1(78.23,63.37) ; C312.1 v1(97.28,36.83) ; v1(218.44,168.53) R101.1 R103.1 ; v1(164.34,53.85) 164.31,53.87 R325.1 ; 274.01,90.46 J26.A10 ; J26.A10 274.01,91.7 ; J26.A10 275.25,91.7 ; J26.A10 275.25,90.46 ; J27.24 v1(209.9,189.45) 209.8,189.54 C743.1 ; C425.1 156.29,45.21 v1(156.59,45.21) ; v1(84.84,28.19) 84.71,28.07 R208.2 R205.2 ; R450.2 v1(271.02,85.72) ; FB41.1 205.8,102.62 v1(206.06,102.87) ; 280.51,89.7 J26.B8 ; J26.B8 281.75,89.7 ; J26.B8 280.51,88.46 ; J26.B8 281.75,88.46 ; R455.2 v1(73.66,177.29) ; C65.1 v1(221.23,101.22) ; C67.1 v1(221.87,116.59) ; R446.2 v1(200.41,177.42) ; v1(272.8,55.75) 272.77,55.78 R763.1 ; C818.1 v1(197.97,92.74) 198.37,92.33 R493.1 ; R758.1 v1(262.51,54.1) ; C48.1 220.6,166.5 v1(220.85,166.75) ; R224.1 R227.2 19.71,27.84 J2.1 ; C68.1 v1(220.85,120.14) ; FB44.1 v1(255.02,40.77) ; R324.1 v1(154.05,49.15) ; C285.1 v1(101.73,42.67) ; R741.1 v1(239.65,51.05) ; R667.2 53.95,52.48 ; v1(82.68,28.07) R207.2 R206.2 ; v1(265.05,47.12) 264.74,47.12 C1132.1 ; C744.1 221.11,189.48 v1(221.1,189.47) J27.52 ; R306.2 v1(141.86,65.66) ; C276.1 109.37,40.61 v1(109.22,40.77) ; R221.2 v1(64.26,59.82) ; C337.1 v1(246.79,143.87) ; v1(66.29,59.82) R229.1 R230.1 ; J26.B10 281.75,90.46 ; J26.B10 280.51,91.7 ; J26.B10 281.75,91.7 ; J26.B10 280.51,90.46 ; J27.2 v1(197.9,189.45) 197.87,189.48 C745.1 ; v1(38.61,146.69) 38.41,146.69 37.91,147.19 Q20.2 38.17,147.57 v1(38.74,147.57) ; R57.2 v1(266.19,145.16) ; C69.1 v1(221.87,123.7) ; R448.2 R445.2 v1(271.02,88.77) ; R217.1 v1(80.01,32.89) ; R228.1 v1(68.33,59.82) ; R226.1 v1(79.38,48.77) ; J28.24 v1(82.9,189.48) 82.9,190.54 C742.1 ; J26.A9 277.25,89.46 ; J26.A9 277.25,90.7 ; J26.A9 276.01,90.7 ; J26.A9 276.01,89.46 ; v1(85.47,192.02) R453.2 R454.2 ; R762.1 v1(262.51,51.05) ; R107.1 v1(229.26,167.41) ; v1(139.57,60.33) 139.22,60.68 R293.1 ; R58.2 269.47,149.2 v1(269.49,149.22) R63.2 R62.2 ; C1098.1 241.88,47.12 v1(242.19,47.12) ; R449.2 v1(271.68,102.74) ; R321.1 v1(154.05,53.21) ; R222.2 R231.1 R232.1 v1(61.21,59.82) ; FB16.1 v1(96.14,28.45) ; J28.2 v1(70.9,189.48) 70.87,189.51 C746.1 ; R443.2 R442.2 v1(212.47,192.15) ; R99.2 v1(247.4,122.94) ; R740.1 249.91,55.78 v1(249.94,55.75) ; R736.1 v1(239.65,54.1) ; v1(150.88,44.07) FB20.1 151.13,38.48 FB21.1 ; R498.1 v1(196.34,94.36) ; R295.1 143.76,63.5 v1(144.02,63.75) ; C66.1 v1(214.12,101.22) ; R60.2 v1(260.1,159) ; U8.2 264.67,158.85 C45.1 v1(265.18,159) ; C63.1 v1(189.87,98.93) ; C747.1 94.1,190.28 v1(94.1,189.47) J28.52 ; C307.1 v1(93.24,26.92) ; v1(267.97,153.42) C44.1 265.29,154.08 U9.8 ; R241.2 v1(251.46,143.64) ; R760.1 v1(262.51,55.12) ; C62.1 v1(182.75,98.93) ; C819.1 v1(207.8,96.42) ; U40.1 245.11,145.31 C338.1 v1(244.48,145.29) ; R451.2 v1(271.02,86.74) ; R196.1 v1(269.62,144.78) ; R198.1 v1(269.62,142.75) ; FB45.1 273.43,39.88 v1(272.48,40.83) ; R216.1 v1(80.14,35.69) ; R197.1 v1(269.62,143.76) ; R318.2 v1(154.05,51.18) ; R98.2 v1(249.68,127.25) ; Q2.1 v1(242.38,123.13) ; R735.2 v1(239.65,53.09) ; Q3.1 v1(247.33,125.42) ; R304.2 v1(140.84,65.28) ; R757.2 v1(262.51,53.09) ; R452.2 v1(271.02,95.89) ; R199.1 v1(269.62,141.73) ; R59.2 v1(258.7,145.29)
  L4PWR w0.508: 19.94,29.59 J2.1 ; J2.1 21.46,28.07 ; J2.1 19.94,28.07 ; J2.1 21.46,29.59 ; 276.01,89.46 J26.A9 ; J26.A9 277.25,90.7 ; J26.A9 277.25,89.46 ; J26.A9 276.01,90.7 ; J26.B10 281.75,90.46 ; J26.B10 280.51,91.7 ; J26.B10 280.51,90.46 ; J26.B10 281.75,91.7 ; 274.01,90.46 J26.A10 ; J26.A10 275.25,91.7 ; J26.A10 275.25,90.46 ; J26.A10 274.01,91.7 ; 280.51,89.7 J26.B8 ; J26.B8 281.75,88.46 ; J26.B8 281.75,89.7 ; J26.B8 280.51,88.46
  BOTTOM w0.508: C61.1 v1(186.18,99.95) ; v1(156.72,52.45) 156.74,52.48 C426.1 ; C1124.1 276.71,46.38 v1(276.73,46.35) ; v1(156.59,47.12) 156.62,47.09 C416.1 ; C85.1 107.47,49.5 v1(107.44,49.53) ; v1(85.22,60.45) 85.24,60.43 C82.1 ; C336.1 97.38,54.33 v1(97.28,54.23) ; C80.1 107.42,61.57 v1(107.32,61.47) ; C1099.1 242.32,46.99 v1(242.19,47.12) ; R75.2 v1(31.12,39.37) ; C427.1 v1(164.34,53.85) ; R89.2 R109.1 R108.1 ; v1(96.01,60.33) 96.11,60.43 C81.1 ; v1(265.05,49.02) 265.07,49 C1133.1 ; v1(86.74,54.36) 86.77,54.33 C84.1 ; FB17.1 89.28,30.73 v1(89.15,30.61) 89.18,30.58 C311.1 ; v1(265.05,47.12) 265.18,46.99 C1134.1 ; R108.1 v1(134.37,88.2) 134.49,88.07 C131.1 ; R108.1 R88.2 ; C389.1 139.6,60.3 v1(139.57,60.33) ; R74.2 v1(43.05,39.37) ; v1(61.42,43.39) 61.47,43.34 C326.1 ; v1(265.18,54.36) 265.2,54.38 C1123.1 ; C428.1 156.72,45.09 v1(156.59,45.21) ; C1100.1 246,45.89 v1(245.83,45.72) ; C325.1 61.75,47.09 v1(61.45,47.39) ; C86.1 97.51,47.98 v1(97.41,47.88) ; v1(66.95,41.89) 66.42,42.42 C330.1 ; C328.1 70.46,41.8 v1(70.45,41.78) ; C418.1 168.25,44.48 v1(168.28,44.45) ; v1(137.54,88.14) 137.29,88.39 R100.2 R102.2 ; v1(91.91,30.61) 92.1,30.8 C310.1 ; v1(138.94,56.77) 139.07,56.64 C390.1 139.6,55.6 C394.1 ; v1(93.41,39.75) 93.47,39.69 C313.1 93.45,39.12 R214.1 ; v1(69.22,120.65) 69.24,120.68 C41.1 C42.1 ; C331.1 v1(71.63,41.78) ; C1089.1 242.21,49 v1(242.19,49.02) ; v1(253.87,46.35) 253.85,46.38 C1090.1 ; C329.1 74.03,52.35 v1(74.49,51.89) ; v1(86.87,47.88) 86.89,47.85 C83.1 ; C64.1 v1(217.55,102.23) ; v1(242.32,54.36) 242.34,54.38 C1101.1 ; C314.1 v1(85.03,33.66) ; v1(268.69,45.72) 268.86,45.89 C1135.1 ; C396.1 142.49,53.78 v1(142.55,53.72) ; v1(160.23,43.81) 160.4,43.98 C417.1 ; v1(138.94,58.04) 139.32,57.66 C395.1 ; C79.1 107.54,55.73 v1(107.44,55.63) ; C1091.1 v1(249.94,55.75) ; C327.1 v1(61.47,52.39) ; C309.1 84.46,39.12 v1(84.07,39.5) ; FB18.1 v1(67.69,57.4) ; C1125.1 v1(272.8,55.75)
  vias: v1(51.69,10.29) v1(51.69,9.53) v1(54.23,51.44) v1(54.23,50.55) v1(54.23,49.66) v1(54.23,48.77) v1(55.25,51.44) v1(55.25,50.55) v1(55.25,49.66) v1(55.25,48.77) v1(271.91,156.08) v1(271.91,155.07) v1(271.91,154.18)
3V3_DFP_PLLVCC: length 7.9
  TOP w0.254: U37.10 v1(69.45,57.38) ; U37.16 v1(66.44,57.28)
  BOTTOM w0.508: v1(66.44,57.28) 66.29,57.13 C320.1 C321.1 69.22,57.15 v1(69.45,57.38) 69.22,57.61 FB18.2
3V3_DVI_AVDD: length 3.2
  TOP w0.254: U35.18 v1(86.41,30.61)
  BOTTOM w0.508: v1(86.41,30.61) 86.46,30.66 C316.1 86.72,31.5 FB17.2
3V3_DVI_VDD: length 3.3
  TOP w0.254: C315.1 97.12,31.43 U35.33
  TOP w0.508: C315.1 97.28,30.23 FB16.2
3V3_PGOOD: length 55.1
  TOP w0.127: v1(31.56,87.5) 31.56,90.04 34.9,93.38 U57.L1 ; U68.3 29.71,50.28 v1(29.34,49.91)
  L3SIG w0.102: v1(31.56,87.5) 31.56,77.41 26.92,72.77 26.92,51.05 28.07,49.91 v1(29.34,49.91)
  BOTTOM w0.127: R604.2 v1(29.34,49.91)
3V3_SLP: length 183.9
  TOP w0.203: v1(121.67,52.32) 121.84,52.15 U42.37 ; U42.6 v1(124.64,45.72) ; U42.41 121.12,50.13 v1(121.03,50.04) ; U42.45 121.4,48.53 121.09,48.83 v1(121.03,48.83) 121.13,48.93 U42.44
  TOP w0.254: v1(75.57,87.25) 75.68,87.14 U62.6
  TOP w0.305: U31.8 55.61,148.17 C295.1
  TOP w0.381: U57.H6 v1(42.47,96.88) ; U57.L9 v1(46.47,92.89) ; U57.T3 v1(39.47,87.89) ; U57.C1 v1(37.47,101.88) ; U75.4 171.17,125.5 C1016.1 ; U57.P1 v1(37.47,89.89) ; U61.5 64.29,92.68 C856.1 ; C1010.1 170.22,121.14 U73.4 ; U13.5 94.34,77.11 C50.1 ; U57.L8 v1(44.47,92.89) ; U57.T14 v1(51.47,87.89) ; U57.J6 v1(42.47,94.89)
  TOP w0.508: R460.2 v1(218.69,138.43) ; R263.1 121.31,52.68 v1(121.67,52.32) ; C938.1 R604.1 R600.2 v1(29.36,47.4) ; R565.1 v1(190.75,140.22) ; R118.1 v1(20.07,113.54) ; R465.2 v1(218.69,134.37) ; R96.2 v1(249.68,126.24) ; U76.4 14,23.96 C1047.1 v1(13.21,22.73) R697.2 ; C50.1 v1(94.34,75.31) ; R97.2 v1(247.4,123.95) ; R149.2 R150.2 v1(70.99,37.34) ; R642.2 v1(119,173.23) ; D6.2 30.86,11.18 ; 30.86,11.18 33.4,11.18 35.18,9.4 D5.2 ; 30.86,11.18 22.73,11.18 21.34,12.57 21.34,18.03 19.05,20.32 v1(16.26,20.32) ; R123.1 v1(20.07,100.84) ; R117.2 v1(20.07,114.81) ; R461.2 v1(219.48,143.87) ; R458.2 v1(218.69,131.32) ; J1.284 184.4,167.68 C23.1 ; v1(123.7,57.66) 123.95,57.4 R276.2 ; R153.2 v1(68.83,33.4) ; C1010.1 v1(170.08,121.92) ; R122.1 v1(20.07,103.38) ; R190.2 v1(57.66,147.45) ; R464.2 v1(218.69,135.38) ; C856.1 v1(62.74,92.68) ; R471.1 v1(28.07,89.92) ; R538.1 v1(67.06,102.23) ; R466.2 v1(218.69,129.29) ; R120.1 v1(20.07,108.58) ; R462.2 v1(218.69,137.41) ; C295.1 v1(55.91,149.2) ; R116.2 v1(20.07,112.27) ; R456.2 v1(218.69,133.35) ; R695.2 v1(57.66,80.26) ; R152.2 v1(68.83,34.42) ; R650.2 v1(168,127.51) ; R682.1 v1(30.61,46.1) ; R265.1 125.86,55.5 v1(126.11,55.75) ; R472.1 v1(28.07,91.69) ; R119.1 v1(20.07,111) ; R463.2 v1(218.69,136.4) ; R459.2 v1(218.69,130.3) ; R457.2 v1(218.69,132.33) ; C1016.1 v1(171.83,126.87) ; R121.1 v1(20.07,105.92)
  L3SIG w0.508: v1(29.36,47.4) 31.39,47.4 32,48.01 38.86,48.01 41.53,45.34 45.34,45.34 v1(46.1,46.1)
  L4PWR w0.508: J31.4 23.88,86.49 ; J31.4 22.35,86.49 ; J31.4 23.88,84.96 ; J31.4 22.35,84.96
  BOTTOM w0.305: U34.1 114.72,110.07 114.33,110.46 C297.1
  BOTTOM w0.508: C361.1 121.41,49.66 v1(121.03,50.04) ; v1(170.08,121.92) 169.67,121.51 R645.2 ; v1(121.03,48.83) 121.22,48.64 C360.1 121.69,47.47 C365.1 ; J1.284 184.96,167.11 ; J1.284 183.83,167.11 ; J1.284 184.96,168.24 ; J1.284 183.83,168.24 ; v1(29.36,47.4) 29.34,47.42 R604.1 ; v1(37.47,101.88) 37.96,102.38 C787.1 ; v1(128.4,85.72) 128.91,86.23 FB6.2 ; v1(39.47,87.89) 38.97,88.38 C784.1 ; 182.98,162.84 J1.139 ; J1.139 184.11,162.84 ; J1.139 184.11,161.71 ; R192.2 R195.2 113.69,112.5 v1(113.98,112.2) 114.33,111.86 C297.1 ; v1(44.47,92.89) 44.96,93.38 U57.L8 ; v1(30.61,46.1) 30.61,42.67 28.19,40.26 28.19,37.34 26.54,35.69 23.11,35.69 22.35,36.45 19.94,36.45 18.92,35.43 18.92,29.84 17.78,28.7 14.86,28.7 13.21,27.05 v1(13.21,22.73) 15.62,20.32 v1(16.26,20.32) ; C366.1 121.69,52.3 v1(121.67,52.32) ; v1(46.47,92.89) 45.97,93.38 U57.L9 ; C786.1 51.96,88.38 v1(51.47,87.89) ; R568.1 v1(194.67,146.66) ; C858.1 75.69,87.38 v1(75.57,87.25) ; C367.1 124.59,45.77 v1(124.64,45.72) ; C783.1 42.96,94.39 v1(42.47,94.89) ; R539.1 63.88,96.27 v1(64.77,95.38) ; C785.1 37.96,89.39 v1(37.47,89.89) ; v1(42.47,96.88) 42.96,97.38 C782.1
  vias: v1(25.65,101.6) v1(26.42,101.6) v1(45.97,149.99) v1(45.97,149.22) v1(46.1,55.24) v1(46.1,54.23) v1(46.1,53.21) v1(46.1,52.2) v1(46.1,51.18) v1(46.1,50.16) v1(46.1,49.15) v1(46.1,48.13) v1(46.1,47.12) v1(46.74,149.99) v1(46.74,149.22) v1(47.5,149.99) v1(47.5,149.22) v1(120.65,170.31) v1(120.65,169.55) v1(186.69,152.27) v1(187.33,151.89) v1(187.96,152.15) v1(188.6,152.53)
3V3_USB_HVDD: length 5.5
  TOP w0.305: U1.J8 v2(129.57,97.02) ; U1.K8 v2(130.37,97.02)
  BOTTOM w0.457: v2(127.89,90.68) 127.76,90.68 127.41,90.32 C107.1
  BOTTOM w0.508: C107.1 C118.1 C108.1 127.41,86.64 FB6.1
3V3A_843004: length 4.4
  TOP w0.305: U58.9 197.99,95.78 197.97,95.76
  TOP w0.508: C822.1 197.97,96.55 C823.1 R498.2
3V3O_843004: length 12.8
  TOP w0.305: U58.3 201.54,99.68 201.68,99.82 ; 204.37,99.77 204.46,99.68 U58.22 206.87,99.68 207.52,100.33 C821.1
  TOP w0.508: 204.37,99.77 203.71,100.43 FB41.2 202.54,102.62 C820.1 202.41,100.56 201.68,99.82
5V0: length 14
  TOP w0.254: 93.85,23.62 93.65,23.82 U36.1
  TOP w0.508: v1(95.12,24.38) C308.1 94.13,23.34 93.85,23.62 ; v1(238,169.67) 238,169.16 R236.1 236.98,169.16 v1(236.98,169.67)
  TOP w1.016: U38.2 237.82,157.1 C332.1
  L3SIG w0.508: 236.82,156.1 U38.2 ; U38.2 238.41,156.1 ; U38.2 236.82,157.69 ; U38.2 238.41,157.69
  vias: v1(34.29,32.77) v1(34.93,33.53) v1(35.05,32.77)
5V0_HDMI: length 21
  TOP w0.254: v1(83.44,12.06) 83.95,11.56 83.95,10.79 84.02,10.73 J12.18
  TOP w0.508: v1(83.44,12.06) 83.19,12.32 C305.1 ; FB46.2 94.36,16.13 v1(94.36,14.35) ; R203.2 v1(84.2,14.35) R204.2
  BOTTOM w0.508: v1(83.44,12.06) 84.2,12.83 v1(84.2,14.35) v1(94.36,14.35)
5V0_SB: length 25.5
  TOP w0.254: U77.7 5.72,29.47 5.97,29.21 v1(5.97,29.21) 5.73,28.97 U77.8
  TOP w0.508: U78.5 5.07,27.19 5.61,26.64 C1051.1 8.86,26.64 C1053.1 ; R707.1 v1(7.75,31.62) ; R703.2 v1(7.75,24.23) ; C1053.1 8.76,25.98 v1(8.76,25.53) ; C1053.1 9.53,25.98 v1(9.53,25.53) ; R702.2 v1(7.59,37.08) ; C1052.1 v1(7.65,28.3)
  TOP w1.016: v1(9.02,37.72) 9.02,38.35 10.8,40.13 10.8,47.75 12.22,49.18 J37.9
  vias: v1(8.38,37.08)
5V0_SLP: length 107.7
  TOP w0.254: U69.10 248.04,93.2 C952.2 ; C893.2 35.29,161.28 U66.10 ; U64.10 188.48,148.96 C862.2 ; C844.1 69.33,93.49 U60.10 ; C892.2 35.3,57.42 U65.10 ; U68.10 33.77,46.24 C921.2 ; C925.2 241.19,75.19 U67.10
  TOP w0.508: R558.1 v1(189.73,140.21) ; R698.2 18.64,59.79 ; C893.2 v1(35.43,160.54) ; R615.1 R611.1 v1(249.29,84.45) ; R583.1 R576.1 v1(34.04,66.17) ; C925.2 v1(241.05,75.94) ; R585.1 v1(30.1,61.34) ; R601.1 v1(245.11,80.39) ; C892.2 v1(34.55,57.28) ; C844.1 v1(68.58,93.34) ; C862.2 v1(189.22,149.1) ; v1(32.51,54.99) R594.1 R598.1 ; R596.1 R593.1 v1(249.94,76.45) ; R618.1 v1(253.24,89.28) ; R581.1 v1(31.37,156.08) ; R535.1 v1(68.07,102.23) ; R579.1 R575.1 v1(26.54,160.03) ; C952.2 v1(248.79,93.34) ; C921.2 v1(33.02,46.1)
  TOP w1.016: 12.39,60.88 J37.6 ; J37.6 14.19,60.88 ; J37.6 12.39,62.68 ; J37.6 14.19,62.68 ; 12.39,71.08 J37.4 ; J37.4 12.39,69.28 ; J37.4 14.19,69.28 ; J37.4 14.19,71.08 ; 6.89,44.08 J37.20 ; J37.20 6.89,45.88 ; J37.20 8.69,44.08 ; J37.20 8.69,45.88 ; 6.89,50.08 J37.19 ; J37.19 6.89,48.28 ; J37.19 8.69,50.08 ; J37.19 8.69,48.28
  L5PWR w1.016: 12.39,71.08 J37.4 ; J37.4 14.19,71.08 ; J37.4 14.19,69.28 ; J37.4 12.39,69.28 ; J37.6 14.19,60.88 ; J37.6 14.19,62.68 ; J37.6 12.39,60.88 ; J37.6 12.39,62.68
  L6SIG w1.016: J37.6 14.19,60.88 ; J37.6 12.39,60.88 ; J37.6 14.19,62.68 ; J37.6 12.39,62.68 ; J37.20 8.69,45.88 ; J37.20 8.69,44.08 ; J37.20 6.89,44.08 ; J37.20 6.89,45.88 ; 6.89,48.28 J37.19 ; J37.19 8.69,48.28 ; J37.19 6.89,50.08 ; J37.19 8.69,50.08 ; J37.4 14.19,69.28 ; J37.4 12.39,69.28 ; J37.4 12.39,71.08 ; J37.4 14.19,71.08
  BOTTOM w0.254: U20.5 71.12,19.05 v1(71.25,18.92)
  BOTTOM w1.016: J37.20 8.69,45.88 ; J37.20 8.69,44.08 ; J37.20 6.89,44.08 ; J37.20 6.89,45.88 ; J37.19 8.69,50.08 ; J37.19 6.89,50.08 ; J37.19 8.69,48.28 ; J37.19 6.89,48.28 ; J37.6 14.19,62.68 ; J37.6 12.39,60.88 ; J37.6 14.19,60.88 ; J37.6 12.39,62.68 ; 12.39,69.28 J37.4 ; J37.4 14.19,69.28 ; J37.4 12.39,71.08 ; J37.4 14.19,71.08
  vias: v1(28.45,163.96) v1(28.45,163.2) v1(28.45,162.44) v1(29.08,163.96) v1(29.08,163.2) v1(29.08,162.44) v1(33.66,44.07) v1(33.66,43.18) v1(34.54,44.07) v1(34.54,43.18) v1(34.93,53.09) v1(34.93,52.45) v1(35.69,53.09) v1(35.69,52.45) v1(36.46,64.26) v1(36.46,63.63) v1(36.45,53.09) v1(36.45,52.45) v1(37.22,64.26) v1(37.22,63.63) v1(37.98,64.26) v1(37.98,63.63) v1(60.45,36.07) v1(60.45,35.31) v1(64.01,35.94) v1(64.77,35.94) v1(70.49,100.33) v1(70.49,99.69) v1(71.25,100.33) v1(71.25,99.69) v1(72.01,100.33) v1(72.01,99.69) v1(185.79,142.75) v1(185.79,142.11) v1(186.56,142.75) v1(186.56,142.11) v1(187.32,142.75) v1(187.32,142.11) v1(200.41,146.81) v1(200.41,146.05) v1(201.17,146.81) v1(201.17,146.05) v1(201.93,146.81) v1(201.93,146.05) v1(202.69,146.81) v1(202.69,146.05) v1(245.36,87) v1(245.36,86.36) v1(246.12,87) v1(246.12,86.36) v1(246.88,87) v1(246.88,86.36) v1(247.4,74.03) v1(247.4,73.27) v1(247.4,72.51) v1(248.03,74.03) v1(248.03,73.27) v1(248.03,72.51) v3(6.73,43.31) v3(6.86,46.86) v3(8.89,47.24) v3(9.02,43.31) v3(12.07,67.82) v3(14.61,64.01) v3(15.75,60.58) v3(15.88,71.5) v3(16,68.96) v3(17.02,64.77) v3(19.18,68.58) v3(19.94,63.75) v3(20.07,66.67)
5V0_USB1: length 3.5
  TOP w0.508: 66.93,32 67.31,32.39 69.32,32.39 R158.2
5V0_USB2: length 0.7
  TOP w0.508: R154.2 58.93,28.45
12V: length 36.3
  TOP w0.508: 274.01,82.46 J26.A2 ; J26.A2 274.01,83.7 ; J26.A2 275.25,83.7 ; J26.A2 275.25,82.46 ; 278.51,81.46 J26.B1 ; J26.B1 279.75,82.7 ; J26.B1 278.51,82.7 ; J26.B1 279.75,81.46 ; 280.51,82.46 J26.B2 ; J26.B2 281.75,82.46 ; J26.B2 280.51,83.7 ; J26.B2 281.75,83.7 ; J26.B3 279.75,83.46 ; J26.B3 278.51,83.46 ; J26.B3 278.51,84.7 ; J26.B3 279.75,84.7 ; J26.A3 277.25,84.7 ; J26.A3 276.01,83.46 ; J26.A3 277.25,83.46 ; J26.A3 276.01,84.7 ; R679.2 27.84,38.2
  BOTTOM w0.508: 280.51,83.7 J26.B2 ; J26.B2 281.75,83.7 ; J26.B2 281.75,82.46 ; J26.B2 280.51,82.46 ; 278.51,81.46 J26.B1 ; J26.B1 279.75,81.46 ; J26.B1 278.51,82.7 ; J26.B1 279.75,82.7 ; J26.A2 275.25,82.46 ; J26.A2 275.25,83.7 ; J26.A2 274.01,83.7 ; J26.A2 274.01,82.46 ; 278.51,83.46 J26.B3 ; J26.B3 279.75,84.7 ; J26.B3 278.51,84.7 ; J26.B3 279.75,83.46 ; J26.A3 277.25,84.7 ; J26.A3 277.25,83.46 ; J26.A3 276.01,83.46 ; J26.A3 276.01,84.7
  vias: v1(255.14,189.74) v1(255.14,188.47) v1(255.14,187.32) v1(255.27,175.01) v1(255.27,173.74) v1(255.27,172.34) v1(267.21,158.88) v1(267.59,157.73) v1(267.84,158.5) v3(23.24,39.24) v3(23.62,38.23) v3(23.62,37.21) v3(24.89,38.23) v3(24.89,37.21)
12V_SLP: length 599.7
  TOP w0.508: R676.2 34.52,149.89 v1(33.66,150.75) 28.7,150.75 27.46,149.5 R675.1 ; R658.1 v1(37.85,42.04) ; R669.1 v1(53.09,54.48) ; R659.1 v1(173.36,143.26) ; R721.1 v1(255.65,60.58) ; R660.1 v1(53.85,64.64) ; R549.2 90.93,107.44 v1(90.3,108.08)
  TOP w1.016: 12.39,44.08 J37.10 ; J37.10 14.19,44.08 ; J37.10 14.19,45.88 ; J37.10 12.39,45.88
  L3SIG w0.508: v1(173.36,143.26) 173.36,141.99 176.28,139.06 211.46,139.06 v1(219.71,147.32)
  L6SIG w0.508: 88.52,106.3 64.9,106.3 56.39,97.79 50.17,97.79 48.01,99.95 42.93,99.95 41.02,98.04 37.59,98.04 30.48,105.16 30.48,141.6 33.66,144.78 v1(33.66,150.75) ; 88.52,106.3 88.52,94.23 85.22,90.93 66.04,90.93 61.21,86.11 v1(61.21,82.55) ; 88.52,106.3 v1(90.3,108.08)
  BOTTOM w0.508: v1(33.66,150.75) 38.23,155.32 38.23,173.23 50.67,185.67 200.53,185.67 207.14,179.07 207.14,159.89 v1(219.71,147.32) 250.19,147.32 264.16,133.35 264.16,69.09 v1(255.65,60.58)
  vias: v1(26.8,43.69) v1(26.8,42.93) v1(27.56,43.69) v1(27.56,42.93) v1(60.45,82.55) v1(60.83,81.91)
AGND_SD1_PLL1: length 6.4
  TOP w0.305: U1.AA16 v2(139.97,104.22)
  BOTTOM w0.508: R176.1 157.43,113.66 C265.2 156.77,113.92 C264.2 154.91,113.64 C263.2 v1(153.19,113.64)
AGND_SD1_PLL2: length 6.4
  TOP w0.305: U1.AA20 v2(139.97,107.42)
  BOTTOM w0.508: v1(153.16,117.45) C268.2 154.91,117.45 155.19,117.73 156.77,117.73 C270.2 157.43,117.47 R179.1
AVDD_CGA1: length 4
  TOP w0.305: U1.G11 v2(127.97,99.42)
  BOTTOM w0.508: v2(122.96,98.61) C262.1 121.79,99.31 C261.1 121.89,98.96 R174.2
AVDD_CGA2: length 4
  TOP w0.305: U1.G12 v2(127.97,100.22)
  BOTTOM w0.508: v2(122.96,100.99) C267.1 121.67,101.73 121.89,101.5 R177.2
AVDD_DDR1: length 10.1
  TOP w0.305: U1.E20 v2(126.37,107.42)
  BOTTOM w0.254: C274.1 120.14,107.31 120.65,107.82 122.68,107.82 122.94,107.57 124.21,107.57 124.51,107.87 125.91,107.87 v2(126.37,107.42)
  BOTTOM w0.508: R181.2 118.85,107.16 C273.1 120.12,107.19 C274.1
AVDD_PLAT: length 5.5
  TOP w0.305: U1.G10 v2(127.97,98.62)
  BOTTOM w0.508: v2(122.96,96.22) C272.1 121.92,96.9 C271.1 121.67,96.27 121.16,95.76 120.4,95.76 120.02,95.38 R180.2
AVDD_SD1_PLL1: length 6.4
  TOP w0.305: U1.AB16 v2(140.77,104.22)
  BOTTOM w0.508: R175.1 157.43,112.65 C265.1 156.77,112.39 C264.1 154.91,112.67 C263.1 v1(153.19,112.67)
AVDD_SD1_PLL2: length 6.4
  TOP w0.305: U1.AB20 v2(140.77,107.42)
  BOTTOM w0.508: R178.1 157.43,116.46 C270.1 156.77,116.2 C269.1 154.91,116.48 C268.1 v1(153.16,116.48)
GND: length 2660.2
  TOP w0.127: U52.B8 U52.B7 225.57,87.14 v2(225.68,87.25) ; U52.D9 v2(223.77,87.18) ; U51.D9 v2(192.02,87.18) ; v2(193.93,87.25) 193.82,87.14 U51.B7 U51.B8
  TOP w0.203: v1(273.43,54.1) 273.69,54.1 273.89,54.31 U83.48 ; v1(273.43,54.1) 273.49,54.16 U83.49 ; v1(273.43,54.1) 273.29,54.1 273.09,54.31 U83.50 ; v1(249.56,44.07) 249.43,44.19 U82.15 ; v1(163.07,52.2) 163.29,52.2 163.43,52.34 U48.53 ; v1(163.07,52.2) 163.03,52.23 U48.54 ; v1(163.07,52.2) 162.81,52.2 162.63,52.38 U48.55 ; U48.57 161.83,52.36 161.67,52.2 161.42,52.2 ; v1(163.96,42.16) 163.83,42.29 U48.15 ; U48.20 165.83,43.59 v1(165.61,43.81) 165.43,43.64 U48.19 ; U79.41 240.52,129.56 U79.8 ; v1(166.5,46.1) 166.5,45.85 166.94,45.41 U48.27 ; 161.42,52.2 161.43,52.21 U48.58 ; 161.42,52.2 161.04,52.2 v1(161.03,52.2) ; v1(120.78,47.88) 120.93,47.73 U42.47 ; U82.53 249.03,54.25 248.89,54.1 v1(248.67,54.1) ; v1(271.53,54.1) 271.27,54.1 271.09,54.28 U83.55 ; v1(271.53,54.1) 271.75,54.1 271.89,54.25 U83.53 ; v1(271.53,54.1) 271.49,54.14 U83.54 ; U82.83 v1(243.93,47.71) ; U82.49 250.63,54.16 v1(250.57,54.1) ; 160.66,52.2 160.4,52.2 160.23,52.36 U48.61 ; 160.66,52.2 161.03,52.2 v1(161.03,52.2) ; 160.66,52.2 160.63,52.22 U48.60 ; 269.88,54.1 270.13,54.1 270.29,54.26 U83.57 ; 269.88,54.1 269.89,54.12 U83.58 ; 269.88,54.1 269.49,54.1 v1(269.49,54.11) ; U82.48 251.03,54.31 250.83,54.1 v1(250.57,54.1) ; U48.87 v1(158.37,44.21) ; U82.19 251.03,45.54 v1(251.21,45.72) 251.43,45.49 U82.20 ; 247.02,54.1 247.27,54.1 247.43,54.26 U82.57 ; 247.02,54.1 246.63,54.1 v1(246.63,54.11) ; 247.02,54.1 247.03,54.12 U82.58 ; U83.59 v1(269.49,54.11) ; v1(269.49,54.11) 269.49,54.1 269.11,54.1 ; U48.59 v1(161.03,52.2) ; 269.11,54.1 269.09,54.12 U83.60 ; 269.11,54.1 268.86,54.1 268.69,54.27 U83.61 ; v1(246.63,54.11) 246.63,54.1 246.25,54.1 ; v1(246.63,54.11) U82.59 ; v1(250.57,54.1) 250.43,54.1 250.23,54.31 U82.50 ; U83.15 272.29,44.19 v1(272.42,44.07) ; U82.87 v1(243.97,46.11) ; 246.25,54.1 246.23,54.12 U82.60 ; 246.25,54.1 246,54.1 245.83,54.27 U82.61 ; v1(248.67,54.1) 248.41,54.1 248.23,54.28 U82.55 ; v1(248.67,54.1) 248.63,54.14 U82.54 ; U48.50 164.63,52.4 164.84,52.2 v1(164.97,52.2) ; U83.87 v1(266.83,46.11) ; U83.19 273.89,45.54 v1(274.07,45.72) 274.29,45.49 U83.20 ; v1(252.1,48.01) 252.1,47.75 252.54,47.31 U82.27 ; v1(164.97,52.2) 165.23,52.2 165.43,52.4 U48.48 ; v1(164.97,52.2) 165.03,52.26 U48.49 ; U83.83 v1(266.79,47.71) ; U83.27 275.4,47.31 274.96,47.75 v1(274.96,48.01) ; U45.47 v1(138.81,55.73) ; U48.83 v1(158.33,45.81)
  TOP w0.254: v1(74.46,53.89) 74.46,54.14 74.71,54.39 U37.100 ; v1(74.46,53.89) U37.99 ; v1(74.46,53.89) 74.46,53.68 74.76,53.39 U37.98 ; v1(223.01,121.28) 223.26,121.53 U18.20 223.26,123.47 C69.2 ; v1(218.82,100.08) 219.07,99.83 U17.20 221,99.83 C65.2 ; U69.4 U69.17 ; v1(73.41,54.99) 73.45,55.03 U37.2 ; v1(73.41,54.99) 73.79,54.99 73.94,55.15 U37.1 ; v1(73.41,54.99) 73.15,54.99 72.94,55.2 U37.3 ; U36.25 v1(87.15,19.9) v1(87.15,23.03) U36.14 ; v1(219.84,102.23) 219.43,101.83 U17.2 ; U35.20 v1(87.41,30.57) ; U35.11 82.82,33.93 v1(82.68,33.78) ; U37.63 v1(67.95,39.37) ; v1(67.95,39.37) 67.7,39.37 67.44,39.62 U37.62 ; v1(67.95,39.37) 68.2,39.37 68.45,39.62 U37.64 ; U37.69 70.94,39.67 71.25,39.37 v1(71.63,39.37) 71.94,39.69 U37.71 ; U77.4 v1(6.99,30.47) ; U36.34 v1(91.65,19.9) v1(91.65,23.03) U36.5 ; v1(74.55,44.58) 74.74,44.39 U37.80 ; v1(64.9,41.91) 64.77,41.91 64.44,41.58 U37.56 ; v1(64.9,41.91) 65.28,41.91 65.44,41.74 U37.58 ; v1(64.9,41.91) 64.95,41.86 U37.57 ; U36.3 v1(92.65,23.03) v1(92.65,19.9) U36.36 ; U37.35 61.32,49.89 v1(61.47,50.04) ; U64.4 U64.17 ; U66.4 U66.17 ; U17.5 217.93,100.33 v1(217.68,100.08) ; v1(69.34,116.08) 69.42,116.15 U3.52 ; U37.25 v1(61.95,54.86) ; U68.4 U68.17 ; J12.2 v1(92.02,10.99) ; v1(63.63,39.5) 63.44,39.68 U37.54 ; U37.11 68.94,55.1 v1(68.83,54.99) ; v1(70.49,54.99) 70.45,55.03 U37.8 ; v1(70.49,54.99) 70.1,54.99 69.94,55.15 U37.9 ; v1(70.49,54.99) 70.77,54.99 70.94,55.17 U37.7 ; U37.14 67.44,55.25 v1(67.18,54.99) 66.95,55.23 U37.15 ; C66.2 214.35,99.83 U17.11 216.29,99.83 v1(216.54,100.08) ; U3.33 v1(71.88,125.65) ; U37.17 v1(65.95,55.02) ; v1(71.95,54.99) 71.7,54.99 71.45,55.24 U37.6 ; v1(71.95,54.99) 71.95,55.05 71.94,55.06 U37.5 ; v1(71.95,54.99) 72.19,54.99 72.45,55.24 U37.4 ; U37.51 61.95,39.65 v1(62.23,39.37) 62.44,39.58 U37.52 ; v1(94.23,33.02) 94.32,32.93 U35.36 ; v1(69.47,41.78) 69.72,41.78 69.94,41.56 U37.67 ; v1(69.47,41.78) 69.45,41.76 U37.66 ; v1(69.47,41.78) 69.2,41.78 68.94,41.53 U37.65 ; J12.5 v1(90.52,10.99) ; C67.2 223.26,116.82 U18.11 223.26,118.75 v1(223.01,119) ; v1(186.31,97.79) 186.56,98.04 U16.5 ; v1(220.98,122.05) 221.13,121.89 U18.2 ; U36.28 v1(88.65,19.9) v1(88.65,23.03) U36.11 ; U19.11 U19.8 62.36,30.36 C73.2 ; J12.11 v1(87.52,10.99) ; U72.4 124.2,173.47 v1(123.7,172.97) U72.8 ; U35.34 96.57,31.93 v1(96.65,32) ; U35.26 90.41,30.49 v1(90.3,30.61) ; U35.6 84.94,36.43 v1(85.09,36.58) ; U60.4 U60.17 ; U37.77 74.76,42.89 v1(74.55,42.67) ; v1(85.6,30.48) 85.91,30.17 U35.17 ; J12.17 v1(84.52,10.99) ; U37.43 v1(61.47,45.89) ; U37.97 76.65,52.89 v1(76.96,52.58) 76.77,52.39 U37.96 ; U35.64 v1(85.91,39.75) ; U37.20 64.44,57.21 v1(64.52,57.28) ; J12.8 v1(89.02,10.99) ; C62.2 182.99,97.54 U16.11 184.92,97.54 v1(185.17,97.79) ; v1(93.22,30.61) 93.41,30.41 U35.32 ; U36.8 v1(90.15,23.03) v1(90.15,19.9) U36.31 ; v1(77.98,87.5) 77.84,87.64 U62.7 ; U35.40 96.4,34.93 v1(96.65,35.18) ; v1(188.47,99.95) 188.06,99.54 U16.2 ; v1(187.45,97.79) 187.7,97.54 U16.20 189.63,97.54 C63.2 ; U18.5 222.76,120.39 v1(223.01,120.14) ; U65.4 U65.17 ; U67.4 U67.17
  TOP w0.305: U1.Y18 v2(139.17,105.82) ; U1.AC2 v2(141.57,92.22) ; U1.AH12 v2(145.57,100.22) ; U1.P10 v2(133.57,98.62) ; U1.AF11 v2(143.97,100.22) U1.AF12 ; U1.AB17 v2(140.77,105.02) ; U1.B1 v2(123.97,91.42) ; U1.AD12 v2(142.37,100.22) ; U1.U9 v2(136.77,97.82) ; U1.L13 v2(131.17,101.02) ; U1.G3 v2(127.97,93.02) ; U1.W7 v2(138.37,96.22) ; U1.Y17 v2(139.17,105.02) ; U1.C26 v2(124.77,112.22) ; U1.T7 v2(135.97,96.22) ; U1.H14 v2(128.77,101.82) ; U1.N15 v2(132.77,103.42) ; U1.H7 v2(128.77,96.22) ; U1.AG9 v2(144.77,97.82) ; U26.1 v1(104.23,55.41) ; U39.8 92.59,55.64 v1(92.71,55.75) ; U1.H20 v2(128.77,107.42) ; U1.H12 v2(128.77,100.22) ; U1.AC1 v2(141.57,91.42) ; U26.8 v1(104.27,50.86) ; U1.G1 v2(127.97,91.42) ; U1.E3 v2(126.37,93.02) ; U1.AE21 v2(143.17,108.22) ; U1.T12 v2(135.97,100.22) ; U1.AH10 v2(145.57,98.62) ; U1.M18 v2(131.97,105.82) ; U1.G22 v2(127.97,109.02) ; U1.K2 v2(130.37,92.22) ; U1.E26 v2(126.37,112.22) ; U1.J7 v2(129.57,96.22) ; U1.AE24 v2(143.17,110.62) ; U1.Y12 v2(138.37,101.02) U1.W13 ; U1.G5 v2(127.97,94.62) ; U1.AG15 v2(144.77,103.42) ; U1.H8 v2(128.77,97.02) ; U1.AB2 v2(140.77,92.22) ; U1.M16 v2(131.97,104.22) ; U1.AA13 v2(139.97,101.02) ; U1.AA24 v2(139.97,110.62) ; U1.M7 v2(131.97,96.22) ; U4.K3 v2(59.45,117.07) ; U1.AC14 v2(141.57,101.82) ; v1(94.23,47.88) 94.12,48 U22.1 ; U1.E16 v2(126.37,104.22) ; U1.AH15 v2(145.57,103.42) ; U1.B13 v2(123.97,101.02) ; U1.H15 v2(128.77,103.42) ; U1.N7 v2(132.77,96.22) ; U21.15 85.29,59.54 v1(85.22,59.46) ; U1.A20 v2(123.97,106.62) U1.B19 ; U1.K16 v2(130.37,104.22) ; U58.19 v1(204.47,97.73) ; U1.AF14 U1.AF15 v2(143.97,103.42) U1.AF16 ; U1.N9 v2(132.77,97.82) ; U1.G7 v2(127.97,96.22) ; U1.AF21 v2(143.97,108.22) ; U1.H19 v2(128.77,106.62) ; U1.R17 v2(135.17,105.02) ; U1.AF10 v2(143.97,98.62) ; U1.B4 v2(123.97,93.82) ; U1.V7 v2(137.57,96.22) ; U1.U17 v2(136.77,105.02) ; v1(97.41,47.12) 97.64,47.35 U22.15 ; U1.AC10 v2(141.57,98.62) ; U1.AF17 U1.AG18 v2(144.77,105.82) ; U1.AE2 v2(143.17,92.22) ; U1.E22 v2(126.37,109.02) ; U1.M24 v2(131.97,110.62) ; U1.AG23 v2(144.77,109.02) U1.AG22 ; U1.A27 v2(123.17,113.02) ; U1.K6 v2(130.37,95.42) ; U1.AA15 v2(139.97,103.42) ; U4.F7 v2(63.45,121.07) ; U1.D20 v2(125.57,107.42) U1.D21 ; U1.T18 v2(135.97,105.82) ; U1.V18 v2(137.57,105.82) ; U1.U15 v2(136.77,103.42) ; U1.V14 v2(137.57,101.82) ; v2(145.54,92.2) 145.17,92.58 U1.AH2 ; U1.AC26 v2(141.57,112.22) ; U1.AC16 v2(141.57,104.22) ; U1.Y22 v2(139.17,109.02) ; U1.AH9 v2(145.57,97.82) ; U1.W24 v2(138.37,110.62) ; U1.AF20 U1.AG21 v2(144.77,108.22) ; U1.V20 v2(137.57,107.42) ; U1.F15 v2(127.17,103.42) ; U1.N11 v2(132.77,99.42) ; U23.1 94.12,54.09 v1(94.23,53.98) ; U1.AF18 v2(143.97,105.82) U1.AF19 ; U1.E1 v2(126.37,91.42) ; U1.L22 v2(131.17,109.02) ; U1.Y14 v2(139.17,101.82) ; U1.H24 v2(128.77,110.62) ; U1.G16 v2(127.97,104.22) ; U1.AC11 v2(141.57,99.42) ; U1.R11 v2(135.17,99.42) ; U1.H18 v2(128.77,105.82) ; U1.U24 v2(136.77,110.62) ; U1.K5 v2(130.37,94.62) ; U1.AE18 v2(143.17,105.82) ; U1.AG6 v2(144.77,95.42) ; U1.L7 v2(131.17,96.22) ; U1.AA19 v2(139.97,106.62) ; U30.15 v1(103.66,42.65) ; U1.P14 v2(133.57,101.82) ; U1.Y7 v2(139.17,96.22) ; U1.P12 v2(133.57,100.22) ; U1.W11 v2(138.37,99.42) ; U1.AF13 U1.AG12 v2(144.77,100.22) ; U1.T26 v2(135.97,112.22) ; U1.AD9 v2(142.37,97.82) ; U1.K20 v2(130.37,107.42) ; U1.N19 v2(132.77,106.62) ; U1.K18 v2(130.37,105.82) ; U21.1 v1(81.9,60.19) ; U1.AD21 v2(142.37,108.22) ; U1.E7 v2(126.37,96.22) ; U28.15 v1(86.77,53.44) ; U1.P18 v2(133.57,105.82) ; U1.U13 v2(136.77,101.02) ; U1.J26 v2(129.57,112.22) ; U1.R22 v2(135.17,109.02) ; U1.P24 v2(133.57,110.62) ; U1.H3 v2(128.77,93.02) ; U1.AE26 v2(143.17,112.22) ; U1.AC13 v2(141.57,101.02) ; U1.AA11 v2(139.97,99.42) ; U1.H10 v2(128.77,98.62) ; U1.F3 v2(127.17,93.02) ; U1.N17 v2(132.77,105.02) ; U1.Y10 v2(139.17,98.62) ; U1.W9 v2(138.37,97.82) ; U1.B7 v2(123.97,96.22) ; U1.A2 v2(123.17,92.22) ; U1.AB26 v2(140.77,112.22) ; U58.15 v1(207.25,95.13) ; U1.AD15 v2(142.37,103.42) ; U1.E19 v2(126.37,106.62) ; U1.W5 v2(138.37,94.62) ; U1.L19 v2(131.17,106.62) ; U1.R9 v2(135.17,97.82) ; U1.U7 v2(136.77,96.22) ; U1.L26 v2(131.17,112.22) ; U1.G26 v2(127.97,112.22) ; U21.8 v1(81.9,55.64) ; U1.T22 v2(135.97,109.02) ; U1.U11 v2(136.77,99.42) ; U24.1 v1(104.18,49.32) ; U1.AG1 v2(144.77,91.42) ; U1.R15 v2(135.17,103.42) ; U1.E5 v2(126.37,94.62) ; U23.15 v1(97.31,53.44) ; U1.H11 v2(128.77,99.42) ; U1.AG26 v2(144.77,112.22) ; U1.AB7 v2(140.77,96.22) ; U27.1 104.08,61.28 v1(104.14,61.34) ; U22.8 v1(94.11,43.44) ; U4.C5 v2(61.05,123.47) ; U1.J22 v2(129.57,109.02) ; U1.V26 v2(137.57,112.22) ; U1.B28 v2(123.97,113.82) ; U1.L15 v2(131.17,103.42) ; U1.AH18 v2(145.57,105.82) ; U1.AC20 v2(141.57,107.42) ; U1.P16 v2(133.57,104.22) ; U1.T14 v2(135.97,101.82) ; U1.T5 v2(135.97,94.62) ; U1.L11 v2(131.17,99.42) ; U1.V22 v2(137.57,109.02) ; U1.P20 v2(133.57,107.42) ; U1.AA17 v2(139.97,105.02) ; U1.U19 v2(136.77,106.62) ; U1.L17 v2(131.17,105.02) ; U1.R13 v2(135.17,101.02) ; U1.M10 v2(131.97,98.62) ; U1.J1 v2(129.57,91.42) ; U1.J2 v2(129.57,92.22) ; U1.H16 v2(128.77,104.22) ; U1.R7 v2(135.17,96.22) ; U1.B25 v2(123.97,111.42) ; U28.1 v1(83.43,54.09) ; U27.15 v1(107.32,60.63) ; U1.B23 v2(123.97,109.82) ; U1.Y26 v2(139.17,112.22) ; U1.H17 v2(128.77,105.02) ; v1(94.23,49.66) 94.12,49.54 U23.8 ; v2(142.37,105.82) U1.AD18 ; U1.M20 v2(131.97,107.42) ; U1.AH21 v2(145.57,108.22) ; U1.V16 v2(137.57,104.22) ; U1.B16 v2(124.77,104.22) ; U26.15 v1(107.47,54.76) ; U1.T10 v2(135.97,98.62) ; U1.AB5 v2(140.77,94.62) ; U31.4 v1(50.93,146.22) ; U1.L9 v2(131.17,97.82) ; U1.K12 v2(130.37,100.22) ; U1.C22 v2(124.77,109.02) ; U1.D24 v2(125.57,110.62) ; U1.W2 v2(138.37,92.22) ; U1.G13 v2(127.97,101.02) ; U27.8 v1(104.1,56.73) ; U1.T16 v2(135.97,104.22) ; U24.8 v1(104.14,44.77) ; U1.AG4 v2(144.77,93.82) ; U1.AA21 v2(139.97,108.22) ; v1(111.89,39.75) 112.04,39.9 U29.15 ; U1.AB22 v2(140.77,109.02) ; U1.P7 v2(133.57,96.22) ; U1.F24 v2(127.17,110.62) ; U1.AB13 v2(140.77,101.02) ; U1.K24 v2(130.37,110.62) ; U1.G2 v2(127.97,92.22) ; U1.AC19 v2(141.57,106.62) ; U1.N13 v2(132.77,101.02) ; U1.AF9 v2(143.97,97.82) ; U1.M14 v2(131.97,101.82) ; U1.N22 v2(132.77,109.02) ; U1.J3 v2(129.57,93.02) ; U1.R26 v2(135.17,112.22) ; U1.E10 v2(126.37,98.62) ; U4.K8 v2(64.25,117.07) ; U1.E13 v2(126.37,101.02) ; U12.8 v1(226.71,171.69) ; U1.AB21 v2(140.77,108.22) ; U1.AE12 v2(143.17,100.22) ; U1.N2 v2(132.77,93.02) ; U1.Y16 v2(139.17,104.22) ; U1.AC17 v2(141.57,105.02) ; U1.H9 v2(128.77,97.82) ; U1.AD4 v2(142.37,93.82) ; U1.D2 v2(125.57,92.22) ; U1.T2 v2(135.97,92.22) ; U1.AD6 v2(142.37,95.42) ; U1.N5 v2(132.77,94.62) ; U1.N26 v2(132.77,112.22) ; U1.K7 v2(130.37,96.22) ; U1.R19 v2(135.17,106.62) ; U1.AC24 v2(141.57,110.62) ; U1.AE9 v2(143.17,97.82) ; U1.T20 v2(135.97,107.42) ; U39.15 v1(96.04,59.54) ; U1.E2 v2(126.37,92.22) ; U1.AG10 v2(144.77,98.62) ; U1.AE15 v2(143.17,103.42) ; U1.H13 v2(128.77,101.02) ; U24.15 v1(107.47,48.67) ; U1.M12 v2(131.97,100.22) ; U1.V12 v2(137.57,100.22) ; U1.B10 v2(123.97,98.62) ; U1.AD22 v2(142.37,109.02) ; U1.V10 v2(137.57,98.62) ; U1.K14 v2(130.37,101.82)
  TOP w0.381: U25.13 87,47.02 v1(86.87,46.89) ; U57.G9 v1(46.47,97.88) ; U25.1 v1(83.57,47.67) ; U57.K10 v1(47.47,93.89) ; U57.G10 v1(47.47,97.88) ; U57.J10 v1(47.47,94.89) ; U57.A16 v1(53.47,103.88) ; U57.J8 v1(44.47,94.89) ; U57.T1 v1(37.47,87.89) ; U5.3 79.56,112.97 v1(79.12,113.41) ; U73.9 170.87,117.8 U73.3 170.87,121.11 C1010.2 ; U57.K8 v1(44.47,93.89) ; U57.H7 v1(43.47,96.88) ; U57.H9 v1(46.47,96.88) ; U28.8 v1(82.61,49.54) ; U57.K9 v1(46.47,93.89) ; J11.5 v1(283.06,156.82) ; U57.R2 v1(38.47,88.89) ; U7.3 v1(76.01,113.35) ; v1(145.54,66.42) 145.18,66.05 U80.3 ; U25.4 v1(83.57,45.72) ; v1(6.35,24.89) 6.36,24.91 U78.3 ; U57.R15 v1(52.47,88.89) ; U57.K7 v1(43.47,93.89) ; U13.3 97.11,78.56 v1(97.28,78.74) ; U57.A1 v1(37.47,103.88) ; J11.19 v1(283.06,152.38) ; v1(72.14,113.54) 72.45,113.22 U6.3 ; U25.10 v1(86.87,45.07) ; J11.15 v1(283.06,153.65) ; U57.B15 v1(52.47,102.88) ; J11.23 v1(283.06,151.11) ; U25.7 v1(83.57,43.77) ; U57.T16 v1(53.47,87.89) ; J11.40 v1(272.69,146.03) ; C1015.2 172.94,124.66 U75.3 169.49,124.66 U75.9 ; U57.G7 v1(43.47,97.88) ; U61.3 v1(65.93,91.96) ; U41.3 v1(250.2,142.86) ; U57.B2 v1(38.47,102.88) ; U57.G8 v1(44.47,97.88) ; J11.37 v1(283.08,146.66) ; J11.26 v1(272.69,150.47) ; J11.30 v1(272.69,149.2) ; U81.3 v1(142.38,67.75)
  TOP w0.508: v1(67.56,148.21) 67.72,148.36 R173.1 ; R719.1 v1(252.73,59.82) ; v1(240.03,46.74) 239.57,46.74 C1098.2 239.57,45.97 v1(240.03,45.97) ; R298.1 v1(137.29,61.09) ; R156.1 v1(61.34,38.61) ; C1068.2 139.7,66.8 v1(139.51,66.61) ; SW5.3 4.38,6.6 ; SW5.3 2.65,6.6 ; SW5.3 2.65,8.33 ; SW5.3 4.38,8.33 ; R727.1 v1(254.76,49.66) ; Q22.2 32.06,146.62 v1(32.39,146.3) ; C282.2 v1(107.7,25.15) ; C1051.2 v1(7.62,25.02) ; v1(36.2,126.11) 36.2,125.15 36.7,124.65 X1.2 36.96,124.65 37.47,125.15 v1(37.47,126.11) ; C50.2 v1(93.37,75.31) ; C293.2 77.75,61.75 v1(77.47,61.47) U32.7 ; C547.1 v1(201.04,84.2) ; R666.1 v1(51.44,66.17) ; C350.2 117.86,53.34 v1(118.36,52.83) 117.94,52.41 Y2.4 ; R444.2 v1(271.02,94.36) ; v1(64.14,22.48) 64.69,22.48 C71.2 64.69,23.24 v1(64.14,23.24) ; C928.1 v1(249.94,78.48) ; SW5.1 5.53,5.73 ; SW5.1 5.53,4.2 ; SW5.1 4,4.2 ; SW5.1 4,5.73 ; C801.2 v1(29.72,126.36) ; 22.35,94.11 J31.10 ; J31.10 23.88,94.11 ; J31.10 23.88,92.58 ; J31.10 22.35,92.58 ; v1(267.21,39.12) 266.83,38.73 C1104.1 ; Y10.4 261.62,48.01 v1(262.51,48.01) C1117.2 ; R211.1 C306.1 R209.1 80.52,38.73 v1(80.14,39.12) ; C1016.2 169.8,126.87 ; C1107.1 260.99,38.86 v1(261.37,39.24) ; C846.1 v1(66.04,102.23) ; C752.2 v1(84.2,193.04) ; C755.2 v1(72.52,191.9) ; v1(175.77,82.42) 175.77,81.91 C444.2 176.53,81.91 v1(176.53,82.42) ; R672.1 v1(45.59,145.29) ; C900.1 v1(32.01,66.17) ; J31.2 23.88,82.42 ; J31.2 23.88,83.95 ; J31.2 22.35,83.95 ; J31.2 22.35,82.42 ; R215.1 v1(83.19,14.35) C305.2 ; v1(237.24,51.59) C1079.2 R737.2 ; v1(130.94,159.13) 130.94,159.84 C24.2 130.43,160.27 129.92,159.77 v1(129.92,159.13) ; R486.1 v1(38.89,125.6) ; v1(114.55,31.75) 114.81,32 C279.2 ; R652.1 33.3,33.94 v1(33.4,34.04) ; C821.2 v1(209.42,100.33) ; R521.1 v1(231.65,130.05) ; C319.2 v1(50.29,11.3) ; v1(67.56,141.86) 67.72,142.01 R172.1 ; J27.9 v1(200.7,181.23) ; U76.1 v1(14.99,26.42) ; J30.17 v1(226.44,136.44) ; C289.2 v1(107.7,30.23) ; C1023.2 v1(186.82,170.81) ; J28.35 v1(87.3,178.48) ; C62.2 v1(182.75,96.65) ; J30.30 v1(224.03,141.24) ; J30.47 v1(228.41,148.44) ; C1069.1 v1(254.64,60.58) ; R275.2 118.52,54.36 C348.2 118.02,54.38 v1(117.79,54.61) ; v1(219.08,73.53) C496.2 R351.1 ; C398.2 v1(151.77,37.21) ; Q28.2 v1(59.12,83.51) ; J27.4 v1(198.7,189.43) ; C341.1 122.56,43.94 v1(122.94,44.32) ; v1(262.89,45.97) 262.43,45.97 C1132.2 262.43,46.74 v1(262.89,46.74) ; C280.2 v1(107.7,28.96) ; C522.1 v1(201.04,80.14) ; C1106.1 269.88,38.99 v1(270.13,39.24) ; C253.2 v1(132.59,170.81) ; C807.2 v1(40.51,120.14) ; Q29.2 v1(7.17,34.99) ; C369.2 v1(152.53,35.94) ; J30.53 v1(228.41,150.84) ; J28.50 v1(93.3,189.43) ; C69.2 v1(224.16,123.7) ; C808.2 v1(27.69,118.24) ; R350.1 v1(230.12,87.38) ; R528.1 v1(233.68,125.98) ; SW3.9 v1(80.26,136.27) ; C66.2 v1(214.12,98.81) ; J30.36 v1(221.93,143.64) ; C410.2 v1(154.05,46.1) 153.16,46.1 Y4.4 ; R299.2 v1(151.38,54.74) ; Y9.4 238.76,48.01 v1(239.65,48.01) C1083.2 ; C1031.2 v1(43.43,149.73) ; C250.2 v1(112.14,159.13) ; v1(120.65,44.32) C354.2 v1(120.02,42.93) ; v1(37.47,117.98) 37.47,117.03 36.96,116.52 X3.2 36.7,116.52 36.2,117.03 v1(36.2,117.98) ; U9.4 v1(257.72,149.48) ; R147.1 v1(211.96,102.23) ; R749.1 v1(277.62,49.66) ; Q18.2 v1(48.7,52.9) ; 13.5,4.2 SW4.1 ; SW4.1 13.5,5.73 ; SW4.1 15.03,5.73 ; SW4.1 15.03,4.2 ; R212.2 97.05,34.77 v1(96.65,35.18) ; v1(238.51,44.58) 238.76,44.32 C1086.2 ; C816.2 v1(201.8,92.46) ; C27.2 v1(131.83,159.13) ; Q13.2 v1(173.86,139.44) ; R223.1 77.72,44.32 v1(77.47,44.58) ; v1(154.43,44.07) 153.97,44.07 C425.2 153.97,44.83 v1(154.43,44.83) ; C77.2 v1(65.02,37.95) ; R667.1 v1(54.08,53.44) ; Y9.2 v1(236.26,51.01) ; J13.7 v1(45.78,14.68) ; C899.1 v1(26.54,158) ; v1(141.48,51.05) 141.22,50.8 C368.1 ; Q21.2 v1(30.85,144.39) ; C29.2 92.92,115.21 v1(92.58,114.88) ; Y7.2 v1(205.7,89.32) ; R520.2 v1(231.65,131.19) ; R653.1 v1(171.58,150.62) ; J28.4 v1(71.7,189.48) ; C25.2 C28.2 v1(127.23,161.39) ; R494.1 v1(196.34,101.47) ; Q24.2 v1(28.58,42.93) ; v1(237.11,127) 236.88,126.77 C824.2 236.88,125.07 Y8.4 ; C307.2 v1(94.21,26.95) ; C339.1 125.35,43.94 v1(124.97,44.32) ; Y3.4 136.02,59.81 v1(136.02,60.71) 135.64,61.09 C379.2 ; J28.29 v1(84.9,178.44) ; C742.2 v1(82.8,193.04) ; v1(208.28,82.42) 208.28,81.91 C477.2 207.52,81.91 v1(207.52,82.42) ; C508.1 v1(201.04,82.17) ; J27.15 v1(203.1,181.23) ; C318.2 54.46,12.04 v1(54.48,12.06) ; v1(116.46,46.61) 116.61,46.46 C355.2 ; R505.2 v1(241.3,138.43) ; v1(8.76,23.5) 8.76,24.05 C1053.2 9.53,24.05 v1(9.53,23.5) ; C45.2 v1(263.55,159.74) ; v1(235.46,169.67) 235.46,169.16 R238.1 234.44,169.16 v1(234.44,169.67) ; C1105.2 v1(272.03,39.24) ; R499.2 v1(247.52,128.78) ; R738.1 v1(239.65,55.12) ; R268.1 v1(119.38,53.34) ; 12.15,8.33 SW4.3 ; SW4.3 13.88,6.6 ; SW4.3 12.15,6.6 ; SW4.3 13.88,8.33 ; C1020.2 v1(185.8,170.81) ; R503.1 v1(247.52,131.19) ; C372.1 v1(147.57,58.8) ; C803.2 v1(27.69,134.49) ; Y1.3 v1(47.82,141.48) ; C288.2 v1(107.09,32.79) ; C856.2 v1(63.37,91.06) ; C802.2 v1(40.51,136.4) ; D4.1 v1(81.24,21.81) ; R671.1 v1(53.09,55.5) ; C371.1 138.3,50.8 v1(138.56,51.05) ; C1030.2 v1(35.18,148.34) ; R709.1 v1(209.42,99.31) ; v1(80.14,34.16) 80.39,34.42 R219.1 ; C370.1 v1(146.94,51.05) ; v1(67.56,145.03) 67.72,145.19 R171.1 ; Q31.2 v1(254.7,63.95) ; Q6.2 v1(22.8,16.57) ; R766.1 v1(277.62,48.64) ; R213.2 v1(87.38,26.44) ; J30.24 v1(224.03,138.84) ; R490.1 v1(38.89,117.47) ; J4.12 v1(17.02,104.65) ; R509.1 v1(238.89,138.43) ; v1(261.37,44.58) 261.62,44.32 C1128.2 ; C375.2 138.79,55.75 v1(138.81,55.73) ; R319.1 v1(154.05,52.2) ; R328.1 v1(169.16,46.74) ; C258.2 v1(115.19,170.81) ; C554.1 v1(232.79,83.19) ; C1074.1 v1(245.49,39.24) ; C798.2 v1(27.69,126.36) ; C72.2 v1(64.64,24.38) ; v1(67.69,81.79) 68.2,81.79 68.71,82.3 C1039.2 68.33,82.8 v1(67.69,82.8) ; R327.1 v1(154.05,48.13) ; R310.1 v1(169.16,47.75) ; J27.29 v1(211.9,178.44) ; J28.18 v1(80.5,189.46) ; v1(231.01,90.42) C489.2 v1(230.12,89.53) ; Y8.2 v1(240.58,122.98) ; v1(122.94,159.26) 122.43,159.77 C260.2 ; J30.60 v1(221.93,153.24) ; C346.2 v1(120.78,47.88) ; C384.2 v1(135.53,50.95) ; v1(62.36,18.29) 62.36,18.72 C74.2 63.12,18.72 v1(63.12,18.29) ; R512.1 v1(247.52,132.46) ; C857.2 95.1,106.45 95.61,105.94 v1(95.63,105.94) R540.1 ; J30.11 v1(226.44,134.04) ; C814.2 v1(21.34,100.84) ; R160.1 v1(58.27,30.23) ; J30.35 v1(228.41,143.64) ; C65.2 v1(221.23,98.93) ; C277.2 v1(109.98,34.92) ; J28.34 v1(86.9,189.46) ; C996.2 v1(119,174.24) ; Q5.2 v1(68.83,35.81) ; v1(73.79,21.84) 73.79,21.29 FB4.2 73.03,21.29 v1(73.03,21.84) ; C553.1 v1(232.79,84.2) ; U32.1 U32.2 U32.3 U32.4 v1(72.26,58.93) ; C800.2 v1(28.7,126.36) ; v1(264.41,39.12) 263.91,38.61 C1108.1 ; C1010.2 v1(171.04,121.92) ; J30.54 v1(221.93,150.84) ; U40.8 v1(254,148.84) ; C818.2 v1(196.34,93.34) ; v1(240.41,125.73) 239.9,126.24 C825.2 ; v1(6.35,24.89) 6.07,24.61 C1049.2 ; R527.1 v1(231.65,128.78) ; v1(76.58,21.84) 75.87,21.84 FB2.2 75.77,21.08 v1(76.58,21.08) ; C1027.1 54.81,60.99 R654.1 v1(54.86,61.59) ; C315.2 96.88,32.23 v1(96.65,32) ; C63.2 v1(189.87,96.65) ; C743.2 v1(209.8,193.17) ; C822.2 195.71,96.65 v1(195.45,96.39) ; J28.40 v1(89.3,189.47) ; v1(133.86,54.1) 134.37,54.1 134.75,54.48 134.37,54.86 v1(133.86,54.86) ; C806.2 v1(29.72,134.49) ; R315.1 v1(168.66,54.74) ; C254.2 v1(140.72,170.81) ; Q14.2 v1(50.87,62.8) ; C323.2 v1(22.73,42.93) ; J27.50 v1(220.3,189.41) ; J28.9 v1(73.7,181.23) ; U40.2 v1(246.38,146.05) 246.1,145.77 C338.2 R245.1 ; v1(162.94,39.12) 163.45,38.61 C397.1 ; v1(181.36,93.47) 181.86,93.47 C457.2 181.86,94.23 v1(181.36,94.23) ; SW4.4 20.88,6.6 ; SW4.4 19.15,8.33 ; SW4.4 20.88,8.33 ; SW4.4 19.15,6.6 ; C256.2 v1(138.68,170.81) ; R651.1 v1(165.23,127.51) ; C747.2 v1(93.98,192.02) ; C1028.1 v1(50.8,52.48) ; R115.1 v1(97.05,127.38) ; C804.2 v1(26.67,134.49) ; R665.1 169.67,142.21 C1026.1 v1(169.04,142.24) ; C1050.2 v1(7.75,32.64) ; R159.1 v1(62.36,38.61) ; R447.2 v1(271.02,84.71) ; C68.2 v1(218.57,120.14) ; C337.2 v1(246.79,142.9) ; C324.2 v1(22.73,41.53) ; R732.1 v1(254.25,56.64) ; v1(127.64,43.94) 127.91,43.66 C344.1 ; C1015.2 v1(173.74,124.82) ; C510.1 v1(201.04,81.15) ; C1070.1 242.57,38.99 v1(242.82,39.24) ; C23.2 v1(184.4,170.81) ; J30.66 v1(221.93,155.64) ; v1(70.87,32.39) 70.99,32.26 R161.1 ; J30.65 v1(228.41,155.64) ; R470.1 v1(28.07,86.23) ; Q12.2 v1(40.65,40.76) ; C249.2 v1(134.62,170.81) ; C378.2 v1(139.83,65.28) ; C1114.2 v1(259.72,52.96) ; C754.2 v1(219.46,191.9) ; C1029.1 v1(26.8,146.56) ; v1(187.33,73.53) C463.2 R340.1 ; R320.2 C406.2 v1(151.64,49.68) ; v1(39.12,34.54) 38.74,34.92 C1025.1 ; R485.1 v1(28.07,116.46) ; C805.2 v1(28.7,134.49) ; C746.2 v1(70.87,191.9) ; R743.1 v1(239.65,50.04) ; J30.42 v1(221.93,146.04) ; J27.40 v1(216.3,189.47) ; C550.1 v1(201.04,83.19) ; Y7.4 v1(203.5,93.01) ; C312.2 v1(97.28,39.12) ; C377.2 v1(136.17,62) ; J4.16 v1(17.02,99.57) ; J13.16 v1(34.53,14.71) ; J1.238 144.98,167.99 C248.2 ; R225.1 v1(79.38,47.75) ; R148.1 v1(218.57,118.11) ; R234.1 v1(17.88,34.01) ; J1.202 108.89,168.38 C247.2 ; C1067.2 v1(144.88,69.6) ; R517.1 v1(237.62,138.43) ; R554.1 R555.1 v1(69.49,89.89) ; 11.38,6.6 SW5.4 11.38,8.33 ; J27.21 v1(208.7,178.44) ; C399.1 166.27,38.58 v1(165.86,38.99) ; C49.2 v1(95.4,75.31) ; C811.2 v1(29.72,118.24) ; C751.2 v1(211.2,193.17) ; J27.27 v1(211.1,178.46) ; R339.1 v1(198.37,87.38) ; v1(213.11,94.23) 213.61,94.23 C490.2 213.61,93.47 v1(213.11,93.47) ; R689.1 v1(32.16,10.26) ; C817.2 v1(207.39,89.79) ; R754.1 v1(277.11,56.64) ; Y3.2 v1(134.02,56.26) ; C1080.2 v1(236.86,52.96) ; Y1.2 v1(46.92,141.48) ; C401.1 v1(160.53,39.24) ; C291.2 v1(107.7,21.34) ; J27.26 v1(210.7,189.48) ; C257.2 v1(138.28,159.79) ; C292.2 v1(107.7,23.88) ; C537.1 v1(232.79,85.22) ; C295.2 v1(56.87,149.2) ; C1021.2 v1(187.83,170.81) ; J13.4 v1(49.53,14.73) ; v1(120.02,50.04) 119.91,50.14 C351.2 ; R488.1 v1(38.89,133.73) ; Q4.2 v1(71.82,34.8) ; R708.1 v1(209.42,98.04) ; Y2.2 v1(116.24,48.55) ; v1(40.01,34.54) 39.78,34.77 R664.1 ; C281.2 v1(107.7,26.42) ; C1071.2 v1(253.75,39.24) ; C521.1 v1(232.79,80.14) ; R700.1 v1(10.8,24.89) ; Y10.2 v1(259.12,51.01) ; v1(27.31,96.39) 27.31,96.9 X4.2 26.42,96.86 v1(26.42,96.39) ; C813.2 v1(28.7,100.58) ; C413.2 153.16,42.42 v1(152.91,42.67) ; C276.2 v1(110.64,39.65) ; v1(37.47,134.24) 37.47,133.28 36.96,132.77 X2.2 36.7,132.77 36.2,133.28 v1(36.2,134.24) ; C507.1 v1(232.79,82.17) ; R157.1 v1(63.37,38.61) ; v1(157.86,39.24) 157.61,38.99 C400.1 ; C285.2 v1(101.12,40.92) ; C815.2 v1(21.34,99.82) ; R269.2 v1(133.6,46.86) ; J30.23 v1(228.41,138.84) ; C409.2 v1(154.05,47.12) ; J27.34 v1(213.9,189.46) ; R497.1 v1(196.34,99.19) ; C809.2 v1(26.67,118.24) ; C255.2 136.02,159.64 v1(136.4,159.26) ; R235.1 v1(17.88,31.98) ; C865.1 v1(192.79,140.21) ; C1033.2 v1(45.59,144.27) ; C259.2 v1(110.49,159.13) ; J27.35 v1(214.3,178.44) ; C957.1 v1(251.33,84.45) ; J28.26 v1(83.7,189.48) ; J13.13 v1(38.28,14.73) ; v1(260.1,51.59) C1113.2 R759.2 ; J27.18 v1(207.5,189.46) ; C823.2 v1(196.34,95.38) ; C799.2 v1(26.67,126.36) ; C753.2 v1(199.39,191.9) ; C1116.2 v1(262.51,49.02) ; R495.1 v1(196.34,100.2) ; v1(54.61,8.89) C317.2 v1(55.5,9.78) ; C308.2 v1(94.51,22.38) ; 201.45,102.49 v1(201.45,101.88) ; J30.59 v1(228.41,153.24) ; C380.2 v1(136.93,57.89) ; C251.2 v1(117.35,159.13) ; J28.15 v1(76.1,181.23) ; v1(199.26,90.42) C456.2 v1(198.37,89.53) ; C48.2 v1(218.44,166.5) ; C1072.1 v1(251.46,39.24) ; v1(144.02,51.05) C373.1 ; C407.2 v1(151.26,51.05) ; R274.2 121.92,54.64 C349.2 v1(121.31,55.65) ; C1040.2 v1(62.36,81.03) ; R496.1 v1(196.34,97.92) ; C252.2 v1(118.24,170.81) ; C287.2 v1(102.11,32.13) ; R678.1 v1(29.46,143.89) ; R516.2 v1(231.65,132.46) ; C1073.1 v1(248.41,39.24) ; R765.1 v1(262.51,50.04) ; J30.48 v1(221.93,148.44) ; C1032.2 v1(45.59,143.26) ; R744.1 v1(254.76,48.64) ; C1047.2 v1(15.62,22.73) ; U8.10 v1(258.32,148.59) ; C75.2 v1(61.21,18.8) ; C342.1 v1(131.19,44.32) ; C294.2 v1(52.32,151.76) ; R513.2 v1(240.03,138.43) ; J30.41 v1(228.41,146.04) ; J30.29 v1(228.41,141.24) ; R305.2 v1(138.81,63.63) ; C283.2 v1(107.7,27.69) ; C290.2 v1(107.7,22.61) ; R502.2 v1(247.52,130.05) ; C797.2 v1(40.51,128.27) ; C812.2 v1(28.7,101.6) ; C929.1 v1(30.48,54.99) ; Y4.2 v1(150.66,49.11) ; R679.1 v1(29.08,36.58) ; C343.1 v1(129.67,50.93) ; R723.1 v1(250.57,66.04) ; C304.2 v1(94.51,20.93) ; C1052.2 v1(8.61,28.3) ; C744.2 v1(221.11,191.9) ; C67.2 v1(224.16,116.59) ; J28.21 v1(81.7,178.47) ; C745.2 v1(197.87,191.9) ; C756.2 v1(92.46,192.02) ; C26.2 v1(128.63,168.55) ; C22.2 v1(61.32,170.15) ; J30.5 v1(226.44,131.64) ; C819.2 v1(208.76,96.42) ; J28.27 v1(84.1,178.46) ; C538.1 v1(201.04,85.22) ; C509.1 v1(232.79,81.15) ; C1046.2 v1(13.21,21.72) ; C1082.2 v1(239.65,49.02) ; D1.1 v1(91.15,76.35) ; J13.10 v1(42.03,14.73) ; C810.2 v1(28.7,118.24) ; J13.3 v1(50.78,14.76)
  TOP w0.635: v1(114.55,146.05) 114.55,145.03 113.92,144.4 C246.2 113.41,144.4 112.78,145.03 v1(112.78,146.05) ; v1(149.8,139.86) 149.89,139.78 C87.2 ; v1(151.89,152.78) 151.89,151.76 152.53,151.13 C245.2 153.04,151.13 153.67,151.76 v1(153.67,152.78)
  TOP w0.762: v1(118.11,21.46) 118.11,20.95 121.94,17.13 J9.5 122.81,15.14 122.81,10.31 J9.15
  TOP w1.016: J37.17 8.69,58.48 ; J37.17 8.69,56.68 ; J37.17 6.89,58.48 ; J37.17 6.89,56.68 ; J37.15 8.69,65.08 ; J37.15 6.89,65.08 ; J37.15 8.69,66.88 ; J37.15 6.89,66.88 ; 6.89,62.68 J37.16 ; J37.16 8.69,62.68 ; J37.16 8.69,60.88 ; J37.16 6.89,60.88 ; J35.3 260.35,200.41 C1035.2 ; J37.13 8.69,75.28 ; J37.13 6.89,75.28 ; J37.13 8.69,73.48 ; J37.13 6.89,73.48 ; C332.2 237.92,154.05 U38.1 ; 12.39,75.28 J37.3 ; J37.3 12.39,73.48 ; J37.3 14.19,73.48 ; J37.3 14.19,75.28 ; C1036.2 260.35,171.83 264.54,171.83 ; J32.3 260.35,190.88 C1038.2 ; C1037.2 260.35,181.36 J34.3
  L2GND w0.508: 12.83,30.23 J17.2 ; J17.2 14.35,30.23 ; J17.2 14.35,31.75 ; J17.2 12.83,31.75 ; J16.3 11.81,37.21 ; J16.3 10.29,38.73 ; J16.3 11.81,38.73 ; J16.3 10.29,37.21 ; 274.01,94.46 J26.A12 ; J26.A12 274.01,95.7 ; J26.A12 275.25,95.7 ; J26.A12 275.25,94.46 ; 75.03,167.11 J1.162 ; J1.162 75.03,168.24 ; J1.162 76.16,167.11 ; J1.162 76.16,168.24 ; J1.283 184.11,166.64 ; J1.283 182.98,165.51 ; J1.283 184.11,165.51 ; J1.283 182.98,166.64 ; 263.78,176.15 J33.1 ; J33.1 265.3,176.15 ; J33.1 263.78,177.67 ; J33.1 265.3,177.67 ; SW5.3 4.38,6.6 ; SW5.3 2.65,6.6 ; SW5.3 4.38,8.33 ; SW5.3 2.65,8.33 ; 151.53,167.11 J1.246 ; J1.246 151.53,168.24 ; J1.246 152.66,168.24 ; J1.246 152.66,167.11 ; J1.140 184.96,163.31 ; J1.140 184.96,164.44 ; J1.140 183.83,163.31 ; J1.140 183.83,164.44 ; J1.274 176.46,168.24 ; J1.274 176.46,167.11 ; J1.274 175.33,167.11 ; J1.274 175.33,168.24 ; 164.28,166.64 J1.261 ; J1.261 165.41,165.51 ; J1.261 165.41,166.64 ; J1.261 164.28,165.51 ; 173.63,168.24 J1.272 ; J1.272 174.76,167.11 ; J1.272 174.76,168.24 ; J1.272 173.63,167.11 ; J1.248 154.36,168.24 ; J1.248 154.36,167.11 ; J1.248 153.23,167.11 ; J1.248 153.23,168.24 ; 146.43,163.31 J1.96 ; J1.96 147.56,164.44 ; J1.96 147.56,163.31 ; J1.96 146.43,164.44 ; 144.73,167.11 J1.238 ; J1.238 144.73,168.24 ; J1.238 145.86,168.24 ; J1.238 145.86,167.11 ; J34.3 265.3,180.59 ; J34.3 265.3,182.12 ; J34.3 263.78,182.12 ; J34.3 263.78,180.59 ; J29.7 197.57,126.48 ; J29.7 196.33,125.24 ; J29.7 197.57,125.24 ; J29.7 196.33,126.48 ; J1.15 73.61,162.84 ; J1.15 72.48,161.71 ; J1.15 73.61,161.71 ; J1.15 72.48,162.84 ; 169.38,162.84 J1.123 ; J1.123 170.51,162.84 ; J1.123 170.51,161.71 ; J1.123 169.38,161.71 ; 280.51,101.7 J26.B18 ; J26.B18 281.75,101.7 ; J26.B18 280.51,100.46 ; J26.B18 281.75,100.46 ; J1.24 81.26,163.31 ; J1.24 80.13,164.44 ; J1.24 81.26,164.44 ; J1.24 80.13,163.31 ; J1.268 171.36,168.24 ; J1.268 170.23,167.11 ; J1.268 170.23,168.24 ; J1.268 171.36,167.11 ; 179.58,165.51 J1.279 ; J1.279 179.58,166.64 ; J1.279 180.71,166.64 ; J1.279 180.71,165.51 ; 194.57,135.05 J29.8 ; J29.8 196.34,135.05 ; J29.8 194.57,136.82 ; J29.8 196.34,136.82 ; 155.78,161.71 J1.107 ; J1.107 156.91,161.71 ; J1.107 156.91,162.84 ; J1.107 155.78,162.84 ; 144.73,164.44 J1.94 ; J1.94 145.86,164.44 ; J1.94 145.86,163.31 ; J1.94 144.73,163.31 ; 102.23,164.44 J1.50 ; J1.50 103.36,164.44 ; J1.50 103.36,163.31 ; J1.50 102.23,163.31 ; 77.58,165.51 J1.165 ; J1.165 78.71,166.64 ; J1.165 77.58,166.64 ; J1.165 78.71,165.51 ; 64.83,164.44 J1.6 ; J1.6 65.96,164.44 ; J1.6 64.83,163.31 ; J1.6 65.96,163.31 ; 86.93,168.24 J1.176 ; J1.176 88.06,167.11 ; J1.176 88.06,168.24 ; J1.176 86.93,167.11 ; 97.13,164.44 J1.44 ; J1.44 98.26,163.31 ; J1.44 98.26,164.44 ; J1.44 97.13,163.31 ; J1.116 164.56,163.31 ; J1.116 164.56,164.44 ; J1.116 163.43,163.31 ; J1.116 163.43,164.44 ; 104.78,162.84 J1.53 ; J1.53 105.91,162.84 ; J1.53 104.78,161.71 ; J1.53 105.91,161.71 ; J35.3 265.3,201.17 ; J35.3 263.78,199.64 ; J35.3 265.3,199.64 ; J35.3 263.78,201.17 ; J1.243 150.11,165.51 ; J1.243 150.11,166.64 ; J1.243 148.98,166.64 ; J1.243 148.98,165.51 ; J26.B13 279.75,95.46 ; J26.B13 278.51,96.7 ; J26.B13 278.51,95.46 ; J26.B13 279.75,96.7 ; 14.99,13.72 J39.2 ; J39.2 16.51,15.24 ; J39.2 14.99,15.24 ; J39.2 16.51,13.72 ; J1.189 99.11,166.64 ; J1.189 97.98,165.51 ; J1.189 97.98,166.64 ; J1.189 99.11,165.51 ; J1.37 92.31,161.71 ; J1.37 91.18,162.84 ; J1.37 92.31,162.84 ; J1.37 91.18,161.71 ; 121,15.08 J9.5 ; J9.5 121,16.96 ; J9.5 122.88,16.96 ; J9.5 122.88,15.08 ; 165.98,165.51 J1.263 ; J1.263 165.98,166.64 ; J1.263 167.11,165.51 ; J1.263 167.11,166.64 ; 178.73,164.44 J1.134 ; J1.134 179.86,163.31 ; J1.134 179.86,164.44 ; J1.134 178.73,163.31 ; 65.79,78.1 J36.3 ; J36.3 65.79,76.58 ; J36.3 67.31,78.1 ; J36.3 67.31,76.58 ; J1.118 166.26,164.44 ; J1.118 166.26,163.31 ; J1.118 165.13,163.31 ; J1.118 165.13,164.44 ; J26.A18 275.25,101.7 ; J26.A18 274.01,100.46 ; J26.A18 274.01,101.7 ; J26.A18 275.25,100.46 ; 148.13,163.31 J1.98 ; J1.98 149.26,163.31 ; J1.98 148.13,164.44 ; J1.98 149.26,164.44 ; J1.48 101.66,163.31 ; J1.48 100.53,163.31 ; J1.48 101.66,164.44 ; J1.48 100.53,164.44 ; 70.78,161.71 J1.13 ; J1.13 71.91,162.84 ; J1.13 71.91,161.71 ; J1.13 70.78,162.84 ; J1.147 63.41,166.64 ; J1.147 62.28,165.51 ; J1.147 63.41,165.51 ; J1.147 62.28,166.64 ; J9.15 122.88,10.38 ; J9.15 121,10.38 ; J9.15 122.88,8.49 ; J9.15 121,8.49 ; 98.83,163.31 J1.46 ; J1.46 99.96,163.31 ; J1.46 99.96,164.44 ; J1.46 98.83,164.44 ; 154.08,162.84 J1.105 ; J1.105 154.08,161.71 ; J1.105 155.21,162.84 ; J1.105 155.21,161.71 ; 67.38,162.84 J1.9 ; J1.9 68.51,161.71 ; J1.9 68.51,162.84 ; J1.9 67.38,161.71 ; J1.202 110.16,168.24 ; J1.202 109.03,167.11 ; J1.202 109.03,168.24 ; J1.202 110.16,167.11 ; 157.48,161.71 J1.109 ; J1.109 157.48,162.84 ; J1.109 158.61,162.84 ; J1.109 158.61,161.71 ; J1.259 163.71,165.51 ; J1.259 162.58,166.64 ; J1.259 163.71,166.64 ; J1.259 162.58,165.51 ; J1.180 91.46,167.11 ; J1.180 90.33,167.11 ; J1.180 91.46,168.24 ; J1.180 90.33,168.24 ; J1.241 148.41,166.64 ; J1.241 148.41,165.51 ; J1.241 147.28,165.51 ; J1.241 147.28,166.64 ; 275.82,81.27 J26.A1 ; J26.A1 275.82,82.88 ; J26.A1 277.43,81.27 ; J26.A1 277.43,82.88 ; J1.178 89.76,167.11 ; J1.178 89.76,168.24 ; J1.178 88.63,168.24 ; J1.178 88.63,167.11 ; 107.33,167.11 J1.200 ; J1.200 108.46,167.11 ; J1.200 107.33,168.24 ; J1.200 108.46,168.24 ; 15.37,38.73 J16.1 ; J16.1 16.89,38.73 ; J16.1 16.89,37.21 ; J16.1 15.37,37.21 ; J1.131 177.31,162.84 ; J1.131 176.18,162.84 ; J1.131 177.31,161.71 ; J1.131 176.18,161.71 ; 76.73,164.44 J1.20 ; J1.20 76.73,163.31 ; J1.20 77.86,164.44 ; J1.20 77.86,163.31 ; J1.129 175.61,162.84 ; J1.129 174.48,161.71 ; J1.129 174.48,162.84 ; J1.129 175.61,161.71 ; 84.38,165.51 J1.173 ; J1.173 84.38,166.64 ; J1.173 85.51,165.51 ; J1.173 85.51,166.64 ; 63.98,165.51 J1.149 ; J1.149 63.98,166.64 ; J1.149 65.11,165.51 ; J1.149 65.11,166.64 ; J1.136 181.56,164.44 ; J1.136 180.43,164.44 ; J1.136 181.56,163.31 ; J1.136 180.43,163.31 ; J1.31 87.21,161.71 ; J1.31 86.08,161.71 ; J1.31 87.21,162.84 ; J1.31 86.08,162.84 ; 95.43,164.44 J1.42 ; J1.42 96.56,164.44 ; J1.42 96.56,163.31 ; J1.42 95.43,163.31 ; J1.101 151.81,162.84 ; J1.101 150.68,161.71 ; J1.101 151.81,161.71 ; J1.101 150.68,162.84 ; 278.51,88.7 J26.B7 ; J26.B7 279.75,88.7 ; J26.B7 279.75,87.46 ; J26.B7 278.51,87.46 ; J31.10 23.88,94.11 ; J31.10 22.35,94.11 ; J31.10 22.35,92.58 ; J31.10 23.88,92.58 ; 71.63,167.11 J1.158 ; J1.158 71.63,168.24 ; J1.158 72.76,168.24 ; J1.158 72.76,167.11 ; J1.252 157.76,168.24 ; J1.252 157.76,167.11 ; J1.252 156.63,168.24 ; J1.252 156.63,167.11 ; 264.54,195.96 265.3,195.2 ; 264.54,195.96 265.3,196.72 ; 264.54,195.96 263.78,195.2 ; 264.54,195.96 263.78,196.72 ; 22.35,83.95 J31.2 ; J31.2 23.88,82.42 ; J31.2 23.88,83.95 ; J31.2 22.35,82.42 ; 276.01,98.7 J26.A15 ; J26.A15 277.25,98.7 ; J26.A15 276.01,97.46 ; J26.A15 277.25,97.46 ; J1.127 173.91,162.84 ; J1.127 173.91,161.71 ; J1.127 172.78,162.84 ; J1.127 172.78,161.71 ; 61.43,163.31 J1.2 ; J1.2 62.56,164.44 ; J1.2 62.56,163.31 ; J1.2 61.43,164.44 ; J14.2 17.91,20.96 ; J14.2 16.38,22.48 ; J14.2 16.38,20.96 ; J14.2 17.91,22.48 ; J1.17 75.31,161.71 ; J1.17 74.18,161.71 ; J1.17 75.31,162.84 ; J1.17 74.18,162.84 ; J1.239 146.71,165.51 ; J1.239 146.71,166.64 ; J1.239 145.58,165.51 ; J1.239 145.58,166.64 ; 106.48,162.84 J1.55 ; J1.55 107.61,162.84 ; J1.55 107.61,161.71 ; J1.55 106.48,161.71 ; J26.B4 281.75,85.7 ; J26.B4 280.51,84.46 ; J26.B4 280.51,85.7 ; J26.B4 281.75,84.46 ; J1.184 94.86,167.11 ; J1.184 94.86,168.24 ; J1.184 93.73,167.11 ; J1.184 93.73,168.24 ; J1.171 83.81,165.51 ; J1.171 82.68,165.51 ; J1.171 83.81,166.64 ; J1.171 82.68,166.64 ; J1.151 66.81,166.64 ; J1.151 65.68,165.51 ; J1.151 65.68,166.64 ; J1.151 66.81,165.51 ; J29.9 195.34,123.99 ; J29.9 195.34,122.22 ; J29.9 193.57,123.99 ; J29.9 193.57,122.22 ; 167.68,165.51 J1.265 ; J1.265 168.81,166.64 ; J1.265 168.81,165.51 ; J1.265 167.68,166.64 ; 73.33,168.24 J1.160 ; J1.160 74.46,168.24 ; J1.160 73.33,167.11 ; J1.160 74.46,167.11 ; J1.39 94.01,161.71 ; J1.39 94.01,162.84 ; J1.39 92.88,162.84 ; J1.39 92.88,161.71 ; J1.154 69.36,167.11 ; J1.154 68.23,167.11 ; J1.154 69.36,168.24 ; J1.154 68.23,168.24 ; 19.15,6.6 SW4.4 ; SW4.4 20.88,8.33 ; SW4.4 19.15,8.33 ; SW4.4 20.88,6.6 ; 264.54,171.83 265.3,171.07 ; 264.54,171.83 263.78,171.07 ; 264.54,171.83 265.3,172.59 ; 264.54,171.83 263.78,172.59 ; J1.112 161.16,163.31 ; J1.112 161.16,164.44 ; J1.112 160.03,163.31 ; J1.112 160.03,164.44 ; 160.88,166.64 J1.257 ; J1.257 162.01,166.64 ; J1.257 162.01,165.51 ; J1.257 160.88,165.51 ; J1.114 162.86,164.44 ; J1.114 162.86,163.31 ; J1.114 161.73,164.44 ; J1.114 161.73,163.31 ; J1.281 182.41,166.64 ; J1.281 181.28,166.64 ; J1.281 181.28,165.51 ; J1.281 182.41,165.51 ; 19.3,13.72 J38.2 ; J38.2 19.3,15.24 ; J38.2 20.83,15.24 ; J38.2 20.83,13.72 ; 79.28,166.64 J1.167 ; J1.167 79.28,165.51 ; J1.167 80.41,166.64 ; J1.167 80.41,165.51 ; J1.270 173.06,168.24 ; J1.270 173.06,167.11 ; J1.270 171.93,168.24 ; J1.270 171.93,167.11 ; 263.78,206.25 J35.1 ; J35.1 263.78,204.72 ; J35.1 265.3,204.72 ; J35.1 265.3,206.25 ; 280.51,98.46 J26.B16 ; J26.B16 281.75,99.7 ; J26.B16 281.75,98.46 ; J26.B16 280.51,99.7 ; J1.276 178.16,168.24 ; J1.276 177.03,168.24 ; J1.276 178.16,167.11 ; J1.276 177.03,167.11 ; J1.138 183.26,163.31 ; J1.138 183.26,164.44 ; J1.138 182.13,163.31 ; J1.138 182.13,164.44 ; SW4.3 13.88,6.6 ; SW4.3 13.88,8.33 ; SW4.3 12.15,6.6 ; SW4.3 12.15,8.33 ; 274.01,84.46 J26.A4 ; J26.A4 275.25,85.7 ; J26.A4 274.01,85.7 ; J26.A4 275.25,84.46 ; J1.254 159.46,167.11 ; J1.254 158.33,168.24 ; J1.254 158.33,167.11 ; J1.254 159.46,168.24 ; 81.83,163.31 J1.26 ; J1.26 82.96,164.44 ; J1.26 82.96,163.31 ; J1.26 81.83,164.44 ; J30.G2 225.9,159.81 ; J30.G2 225.9,161.26 ; J30.G2 224.45,161.26 ; 55.25,156.68 J10.2 ; J10.2 56.77,156.68 ; J10.2 55.25,158.2 ; J10.2 56.77,158.2 ; J1.193 102.51,166.64 ; J1.193 101.38,166.64 ; J1.193 102.51,165.51 ; J1.193 101.38,165.51 ; U38.1 238.41,153.56 ; U38.1 238.41,155.15 ; U38.1 236.82,155.15 ; U38.1 236.82,153.56 ; 83.53,164.44 J1.28 ; J1.28 84.66,164.44 ; J1.28 84.66,163.31 ; J1.28 83.53,163.31 ; J1.22 79.56,163.31 ; J1.22 78.43,164.44 ; J1.22 78.43,163.31 ; J1.22 79.56,164.44 ; 63.13,164.44 J1.4 ; J1.4 64.26,164.44 ; J1.4 63.13,163.31 ; J1.4 64.26,163.31 ; 154.93,167.11 J1.250 ; J1.250 154.93,168.24 ; J1.250 156.06,168.24 ; J1.250 156.06,167.11 ; 13.5,5.73 SW4.1 ; SW4.1 13.5,4.2 ; SW4.1 15.03,5.73 ; SW4.1 15.03,4.2 ; J1.57 109.31,161.71 ; J1.57 108.18,162.84 ; J1.57 108.18,161.71 ; J1.57 109.31,162.84 ; 171.08,162.84 J1.125 ; J1.125 172.21,161.71 ; J1.125 172.21,162.84 ; J1.125 171.08,161.71 ; J1.33 88.91,161.71 ; J1.33 87.78,162.84 ; J1.33 88.91,162.84 ; J1.33 87.78,161.71 ; 263.78,190.12 J32.3 ; J32.3 263.78,191.64 ; J32.3 265.3,191.64 ; J32.3 265.3,190.12 ; 89.48,161.71 J1.35 ; J1.35 90.61,161.71 ; J1.35 89.48,162.84 ; J1.35 90.61,162.84 ; J1.195 104.21,166.64 ; J1.195 103.08,165.51 ; J1.195 104.21,165.51 ; J1.195 103.08,166.64 ; 69.08,161.71 J1.11 ; J1.11 70.21,162.84 ; J1.11 69.08,162.84 ; J1.11 70.21,161.71 ; J1.191 100.81,165.51 ; J1.191 100.81,166.64 ; J1.191 99.68,166.64 ; J1.191 99.68,165.51 ; 4,4.2 SW5.1 ; SW5.1 5.53,4.2 ; SW5.1 5.53,5.73 ; SW5.1 4,5.73 ; J1.120 167.96,163.31 ; J1.120 167.96,164.44 ; J1.120 166.83,164.44 ; J1.120 166.83,163.31 ; J29.1 197.57,134.1 ; J29.1 196.33,134.1 ; J29.1 196.33,132.86 ; J29.1 197.57,132.86 ; 9.65,8.33 SW5.4 ; SW5.4 11.38,6.6 ; SW5.4 9.65,6.6 ; SW5.4 11.38,8.33 ; J1.169 82.11,165.51 ; J1.169 80.98,165.51 ; J1.169 80.98,166.64 ; J1.169 82.11,166.64 ; J1.198 106.76,168.24 ; J1.198 105.63,167.11 ; J1.198 105.63,168.24 ; J1.198 106.76,167.11 ; 196.33,129.05 J29.4 ; J29.4 197.57,130.29 ; J29.4 197.57,129.05 ; J29.4 196.33,130.29 ; 69.93,167.11 J1.156 ; J1.156 71.06,167.11 ; J1.156 71.06,168.24 ; J1.156 69.93,168.24 ; 152.38,162.84 J1.103 ; J1.103 153.51,161.71 ; J1.103 152.38,161.71 ; J1.103 153.51,162.84 ; 92.03,168.24 J1.182 ; J1.182 93.16,167.11 ; J1.182 93.16,168.24 ; J1.182 92.03,167.11 ; J1.187 97.41,166.64 ; J1.187 96.28,165.51 ; J1.187 97.41,165.51 ; J1.187 96.28,166.64 ; J34.1 265.3,185.67 ; J34.1 265.3,187.2 ; J34.1 263.78,187.2 ; J34.1 263.78,185.67 ; J30.G1 225.9,127.46 ; J30.G1 225.9,126.01 ; J30.G1 224.45,126.01
  L2GND w1.016: J37.15 8.69,66.88 ; J37.15 6.89,66.88 ; J37.15 8.69,65.08 ; J37.15 6.89,65.08 ; J37.5 14.19,66.88 ; J37.5 12.39,65.08 ; J37.5 14.19,65.08 ; J37.13 8.69,73.48 ; J37.13 6.89,73.48 ; J37.13 8.69,75.28 ; J37.13 6.89,75.28 ; 6.89,58.48 J37.17 ; J37.17 8.69,56.68 ; J37.17 8.69,58.48 ; J37.17 6.89,56.68 ; J37.16 8.69,62.68 ; J37.16 6.89,62.68 ; J37.16 6.89,60.88 ; J37.16 8.69,60.88 ; J37.7 14.19,56.68 ; J37.7 14.19,58.48 ; J37.7 12.39,58.48 ; J37.7 12.39,56.68 ; 12.39,73.48 J37.3 ; J37.3 12.39,75.28 ; J37.3 14.19,73.48 ; J37.3 14.19,75.28
  L3SIG w0.508: 136.91,22.61 136.91,9.8 J19.B10 140.15,9.78 148.11,9.78 J19.B12 150.91,8.17 152.91,10.16 165.25,10.16 J20.12 ; 136.91,22.61 v1(118.11,22.61) ; 136.91,22.61 147.4,22.61 J19.A12
  L4PWR w0.508: 15.37,37.21 J16.1 ; J16.1 16.89,37.21 ; J16.1 16.89,38.73 ; J16.1 15.37,38.73 ; SW5.3 4.38,8.33 ; SW5.3 2.65,6.6 ; SW5.3 2.65,8.33 ; SW5.3 4.38,6.6 ; 263.78,201.17 J35.3 ; J35.3 265.3,199.64 ; J35.3 265.3,201.17 ; J35.1 265.3,204.72 ; J35.1 263.78,204.72 ; J35.1 265.3,206.25 ; J35.1 263.78,206.25 ; SW4.3 13.88,8.33 ; SW4.3 12.15,8.33 ; SW4.3 12.15,6.6 ; SW4.3 13.88,6.6 ; SW5.4 11.38,6.6 ; SW5.4 9.65,6.6 ; SW5.4 11.38,8.33 ; SW5.4 9.65,8.33 ; J16.3 11.81,38.73 ; J16.3 11.81,37.21 ; J16.3 10.29,37.21 ; J16.3 10.29,38.73 ; 19.15,8.33 SW4.4 ; SW4.4 19.15,6.6 ; SW4.4 20.88,8.33 ; SW4.4 20.88,6.6 ; J9.5 122.88,16.96 ; J9.5 121,16.96 ; J9.5 122.88,15.08 ; J9.5 121,15.08 ; SW4.1 15.03,5.73 ; SW4.1 13.5,5.73 ; SW4.1 13.5,4.2 ; SW4.1 15.03,4.2 ; 16.38,22.48 J14.2 ; J14.2 17.91,22.48 ; J14.2 16.38,20.96 ; J14.2 17.91,20.96 ; 121,8.49 J9.15 ; J9.15 122.88,10.38 ; J9.15 122.88,8.49 ; J9.15 121,10.38 ; J17.2 14.35,30.23 ; J17.2 14.35,31.75 ; J17.2 12.83,30.23 ; J17.2 12.83,31.75 ; SW5.1 5.53,4.2 ; SW5.1 4,4.2 ; SW5.1 4,5.73 ; SW5.1 5.53,5.73 ; J39.2 16.51,13.72 ; J39.2 14.99,13.72 ; J39.2 14.99,15.24 ; J39.2 16.51,15.24
  L4PWR w1.016: J37.7 14.19,56.68 ; J37.7 14.19,58.48 ; J37.7 12.39,58.48 ; J37.7 12.39,56.68 ; 6.89,62.68 J37.16 ; J37.16 6.89,60.88 ; J37.16 8.69,62.68 ; J37.16 8.69,60.88 ; J37.5 14.19,65.08 ; J37.5 12.39,65.08 ; J37.5 14.19,66.88 ; J37.13 8.69,73.48 ; J37.13 6.89,73.48 ; J37.13 8.69,75.28 ; J37.13 6.89,75.28 ; J37.15 8.69,65.08 ; J37.15 6.89,66.88 ; J37.15 6.89,65.08 ; J37.15 8.69,66.88 ; 6.89,58.48 J37.17 ; J37.17 8.69,56.68 ; J37.17 8.69,58.48 ; J37.17 6.89,56.68 ; J37.3 14.19,73.48 ; J37.3 12.39,75.28 ; J37.3 12.39,73.48 ; J37.3 14.19,75.28
  L5PWR w0.508: 13.5,4.2 SW4.1 ; SW4.1 13.5,5.73 ; SW4.1 15.03,5.73 ; SW4.1 15.03,4.2 ; J9.15 122.88,10.38 ; J9.15 122.88,8.49 ; J9.15 121,8.49 ; J9.15 121,10.38 ; 4,4.2 SW5.1 ; SW5.1 4,5.73 ; SW5.1 5.53,4.2 ; SW5.1 5.53,5.73 ; J34.3 265.3,180.59 ; J34.3 263.78,182.12 ; J34.3 265.3,182.12 ; J34.3 263.78,180.59 ; 264.54,195.96 265.3,195.2 ; 264.54,195.96 263.78,196.72 ; 264.54,195.96 263.78,195.2 ; 264.54,195.96 265.3,196.72 ; J34.1 265.3,185.67 ; J34.1 263.78,185.67 ; J34.1 265.3,187.2 ; J34.1 263.78,187.2 ; J26.B13 279.75,95.46 ; J26.B13 278.51,96.7 ; J26.B13 279.75,96.7 ; J26.B13 278.51,95.46 ; 274.01,85.7 J26.A4 ; J26.A4 274.01,84.46 ; J26.A4 275.25,85.7 ; J26.A4 275.25,84.46 ; 263.78,172.59 264.54,171.83 ; 264.54,171.83 263.78,171.07 ; 264.54,171.83 265.3,171.07 ; 264.54,171.83 265.3,172.59 ; 14.99,13.72 J39.2 ; J39.2 16.51,13.72 ; J39.2 14.99,15.24 ; J39.2 16.51,15.24 ; 12.83,30.23 J17.2 ; J17.2 14.35,30.23 ; J17.2 12.83,31.75 ; J17.2 14.35,31.75 ; 280.51,101.7 J26.B18 ; J26.B18 280.51,100.46 ; J26.B18 281.75,101.7 ; J26.B18 281.75,100.46 ; 9.65,8.33 SW5.4 ; SW5.4 11.38,8.33 ; SW5.4 9.65,6.6 ; SW5.4 11.38,6.6 ; J35.3 265.3,199.64 ; J35.3 263.78,199.64 ; J35.3 265.3,201.17 ; J35.3 263.78,201.17 ; 263.78,191.64 J32.3 ; J32.3 265.3,190.12 ; J32.3 265.3,191.64 ; J32.3 263.78,190.12 ; 275.82,81.27 J26.A1 ; J26.A1 275.82,82.88 ; J26.A1 277.43,81.27 ; J26.A1 277.43,82.88 ; 19.3,13.72 J38.2 ; J38.2 20.83,15.24 ; J38.2 20.83,13.72 ; J38.2 19.3,15.24 ; J26.B4 281.75,85.7 ; J26.B4 280.51,84.46 ; J26.B4 281.75,84.46 ; J26.B4 280.51,85.7 ; 10.29,37.21 J16.3 ; J16.3 11.81,38.73 ; J16.3 11.81,37.21 ; J16.3 10.29,38.73 ; J14.2 17.91,22.48 ; J14.2 16.38,22.48 ; J14.2 16.38,20.96 ; J14.2 17.91,20.96 ; J16.1 16.89,38.73 ; J16.1 15.37,38.73 ; J16.1 15.37,37.21 ; J16.1 16.89,37.21 ; 280.51,99.7 J26.B16 ; J26.B16 280.51,98.46 ; J26.B16 281.75,99.7 ; J26.B16 281.75,98.46 ; 2.65,8.33 SW5.3 ; SW5.3 4.38,8.33 ; SW5.3 2.65,6.6 ; SW5.3 4.38,6.6 ; J26.A12 275.25,94.46 ; J26.A12 274.01,95.7 ; J26.A12 275.25,95.7 ; J26.A12 274.01,94.46 ; 263.78,177.67 J33.1 ; J33.1 265.3,176.15 ; J33.1 263.78,176.15 ; J33.1 265.3,177.67 ; J26.A18 275.25,101.7 ; J26.A18 274.01,100.46 ; J26.A18 274.01,101.7 ; J26.A18 275.25,100.46 ; J35.1 265.3,206.25 ; J35.1 265.3,204.72 ; J35.1 263.78,204.72 ; J35.1 263.78,206.25 ; 12.15,8.33 SW4.3 ; SW4.3 13.88,8.33 ; SW4.3 13.88,6.6 ; SW4.3 12.15,6.6 ; SW4.4 20.88,8.33 ; SW4.4 19.15,8.33 ; SW4.4 20.88,6.6 ; SW4.4 19.15,6.6 ; J9.5 122.88,15.08 ; J9.5 121,15.08 ; J9.5 121,16.96 ; J9.5 122.88,16.96 ; 278.51,87.46 J26.B7 ; J26.B7 278.51,88.7 ; J26.B7 279.75,88.7 ; J26.B7 279.75,87.46 ; 276.01,97.46 J26.A15 ; J26.A15 277.25,98.7 ; J26.A15 277.25,97.46 ; J26.A15 276.01,98.7
  L5PWR w1.016: 6.89,56.68 J37.17 ; J37.17 6.89,58.48 ; J37.17 8.69,56.68 ; J37.17 8.69,58.48 ; J37.7 14.19,56.68 ; J37.7 12.39,58.48 ; J37.7 14.19,58.48 ; J37.7 12.39,56.68 ; J37.13 8.69,75.28 ; J37.13 6.89,75.28 ; J37.13 6.89,73.48 ; J37.13 8.69,73.48 ; 6.89,60.88 J37.16 ; J37.16 8.69,62.68 ; J37.16 6.89,62.68 ; J37.16 8.69,60.88 ; 6.89,65.08 J37.15 ; J37.15 8.69,66.88 ; J37.15 8.69,65.08 ; J37.15 6.89,66.88
  L7GND w0.508: J1.171 83.81,166.64 ; J1.171 82.68,165.51 ; J1.171 82.68,166.64 ; J1.171 83.81,165.51 ; 16.38,22.48 J14.2 ; J14.2 17.91,20.96 ; J14.2 16.38,20.96 ; J14.2 17.91,22.48 ; 165.13,163.31 J1.118 ; J1.118 165.13,164.44 ; J1.118 166.26,164.44 ; J1.118 166.26,163.31 ; 87.78,162.84 J1.33 ; J1.33 87.78,161.71 ; J1.33 88.91,162.84 ; J1.33 88.91,161.71 ; J1.239 146.71,166.64 ; J1.239 145.58,165.51 ; J1.239 145.58,166.64 ; J1.239 146.71,165.51 ; 196.33,130.29 J29.4 ; J29.4 197.57,129.05 ; J29.4 197.57,130.29 ; J29.4 196.33,129.05 ; 151.53,168.24 J1.246 ; J1.246 151.53,167.11 ; J1.246 152.66,167.11 ; J1.246 152.66,168.24 ; J31.10 23.88,92.58 ; J31.10 23.88,94.11 ; J31.10 22.35,92.58 ; J31.10 22.35,94.11 ; J1.101 151.81,162.84 ; J1.101 150.68,161.71 ; J1.101 150.68,162.84 ; J1.101 151.81,161.71 ; J1.281 182.41,166.64 ; J1.281 181.28,165.51 ; J1.281 182.41,165.51 ; J1.281 181.28,166.64 ; 155.78,161.71 J1.107 ; J1.107 155.78,162.84 ; J1.107 156.91,162.84 ; J1.107 156.91,161.71 ; 98.83,163.31 J1.46 ; J1.46 99.96,164.44 ; J1.46 98.83,164.44 ; J1.46 99.96,163.31 ; 274.01,101.7 J26.A18 ; J26.A18 275.25,101.7 ; J26.A18 275.25,100.46 ; J26.A18 274.01,100.46 ; J33.1 265.3,177.67 ; J33.1 263.78,177.67 ; J33.1 263.78,176.15 ; J33.1 265.3,176.15 ; 99.68,166.64 J1.191 ; J1.191 99.68,165.51 ; J1.191 100.81,166.64 ; J1.191 100.81,165.51 ; J1.109 158.61,162.84 ; J1.109 157.48,161.71 ; J1.109 158.61,161.71 ; J1.109 157.48,162.84 ; J1.241 148.41,166.64 ; J1.241 147.28,165.51 ; J1.241 148.41,165.51 ; J1.241 147.28,166.64 ; 69.08,162.84 J1.11 ; J1.11 70.21,162.84 ; J1.11 69.08,161.71 ; J1.11 70.21,161.71 ; 13.5,5.73 SW4.1 ; SW4.1 13.5,4.2 ; SW4.1 15.03,5.73 ; SW4.1 15.03,4.2 ; J1.2 62.56,163.31 ; J1.2 62.56,164.44 ; J1.2 61.43,164.44 ; J1.2 61.43,163.31 ; 10.29,37.21 J16.3 ; J16.3 10.29,38.73 ; J16.3 11.81,37.21 ; J16.3 11.81,38.73 ; J26.B13 279.75,95.46 ; J26.B13 279.75,96.7 ; J26.B13 278.51,96.7 ; J26.B13 278.51,95.46 ; J29.8 196.34,136.82 ; J29.8 194.57,135.05 ; J29.8 196.34,135.05 ; J29.8 194.57,136.82 ; J1.112 161.16,164.44 ; J1.112 161.16,163.31 ; J1.112 160.03,163.31 ; J1.112 160.03,164.44 ; J1.98 149.26,163.31 ; J1.98 148.13,163.31 ; J1.98 149.26,164.44 ; J1.98 148.13,164.44 ; 179.58,165.51 J1.279 ; J1.279 179.58,166.64 ; J1.279 180.71,165.51 ; J1.279 180.71,166.64 ; 12.83,30.23 J17.2 ; J17.2 14.35,30.23 ; J17.2 12.83,31.75 ; J17.2 14.35,31.75 ; 263.78,172.59 264.54,171.83 ; 264.54,171.83 263.78,171.07 ; 264.54,171.83 265.3,171.07 ; 264.54,171.83 265.3,172.59 ; J10.2 56.77,158.2 ; J10.2 55.25,158.2 ; J10.2 56.77,156.68 ; J10.2 55.25,156.68 ; 161.73,164.44 J1.114 ; J1.114 162.86,163.31 ; J1.114 161.73,163.31 ; J1.114 162.86,164.44 ; 19.15,8.33 SW4.4 ; SW4.4 19.15,6.6 ; SW4.4 20.88,6.6 ; SW4.4 20.88,8.33 ; J26.A15 277.25,98.7 ; J26.A15 276.01,98.7 ; J26.A15 277.25,97.46 ; J26.A15 276.01,97.46 ; U38.1 238.41,153.56 ; U38.1 238.41,155.15 ; U38.1 236.82,155.15 ; U38.1 236.82,153.56 ; 73.33,168.24 J1.160 ; J1.160 74.46,167.11 ; J1.160 74.46,168.24 ; J1.160 73.33,167.11 ; 263.78,206.25 J35.1 ; J35.1 263.78,204.72 ; J35.1 265.3,206.25 ; J35.1 265.3,204.72 ; 166.83,163.31 J1.120 ; J1.120 167.96,164.44 ; J1.120 166.83,164.44 ; J1.120 167.96,163.31 ; 15.37,38.73 J16.1 ; J16.1 16.89,38.73 ; J16.1 16.89,37.21 ; J16.1 15.37,37.21 ; J1.283 184.11,165.51 ; J1.283 182.98,165.51 ; J1.283 182.98,166.64 ; J1.283 184.11,166.64 ; J1.198 106.76,168.24 ; J1.198 106.76,167.11 ; J1.198 105.63,167.11 ; J1.198 105.63,168.24 ; 92.88,162.84 J1.39 ; J1.39 92.88,161.71 ; J1.39 94.01,161.71 ; J1.39 94.01,162.84 ; 164.28,166.64 J1.261 ; J1.261 164.28,165.51 ; J1.261 165.41,165.51 ; J1.261 165.41,166.64 ; J1.48 101.66,163.31 ; J1.48 100.53,163.31 ; J1.48 100.53,164.44 ; J1.48 101.66,164.44 ; J1.94 145.86,164.44 ; J1.94 144.73,163.31 ; J1.94 144.73,164.44 ; J1.94 145.86,163.31 ; J26.B7 279.75,87.46 ; J26.B7 278.51,88.7 ; J26.B7 278.51,87.46 ; J26.B7 279.75,88.7 ; J26.A12 275.25,94.46 ; J26.A12 275.25,95.7 ; J26.A12 274.01,95.7 ; J26.A12 274.01,94.46 ; J38.2 20.83,15.24 ; J38.2 19.3,15.24 ; J38.2 19.3,13.72 ; J38.2 20.83,13.72 ; J1.31 87.21,161.71 ; J1.31 86.08,162.84 ; J1.31 86.08,161.71 ; J1.31 87.21,162.84 ; J1.4 64.26,164.44 ; J1.4 63.13,163.31 ; J1.4 64.26,163.31 ; J1.4 63.13,164.44 ; J1.238 145.86,168.24 ; J1.238 145.86,167.11 ; J1.238 144.73,167.11 ; J1.238 144.73,168.24 ; 106.48,162.84 J1.55 ; J1.55 107.61,162.84 ; J1.55 106.48,161.71 ; J1.55 107.61,161.71 ; 280.51,98.46 J26.B16 ; J26.B16 280.51,99.7 ; J26.B16 281.75,98.46 ; J26.B16 281.75,99.7 ; 71.63,167.11 J1.158 ; J1.158 71.63,168.24 ; J1.158 72.76,167.11 ; J1.158 72.76,168.24 ; J36.3 67.31,76.58 ; J36.3 65.79,76.58 ; J36.3 67.31,78.1 ; J36.3 65.79,78.1 ; 165.98,166.64 J1.263 ; J1.263 167.11,165.51 ; J1.263 165.98,165.51 ; J1.263 167.11,166.64 ; J1.28 84.66,163.31 ; J1.28 83.53,164.44 ; J1.28 83.53,163.31 ; J1.28 84.66,164.44 ; J29.1 197.57,132.86 ; J29.1 196.33,134.1 ; J29.1 196.33,132.86 ; J29.1 197.57,134.1 ; 156.63,168.24 J1.252 ; J1.252 157.76,167.11 ; J1.252 156.63,167.11 ; J1.252 157.76,168.24 ; J32.3 265.3,190.12 ; J32.3 263.78,190.12 ; J32.3 263.78,191.64 ; J32.3 265.3,191.64 ; J1.165 78.71,165.51 ; J1.165 78.71,166.64 ; J1.165 77.58,165.51 ; J1.165 77.58,166.64 ; 93.73,167.11 J1.184 ; J1.184 94.86,168.24 ; J1.184 94.86,167.11 ; J1.184 93.73,168.24 ; 22.35,82.42 J31.2 ; J31.2 23.88,82.42 ; J31.2 23.88,83.95 ; J31.2 22.35,83.95 ; J1.154 69.36,167.11 ; J1.154 68.23,168.24 ; J1.154 69.36,168.24 ; J1.154 68.23,167.11 ; 76.73,163.31 J1.20 ; J1.20 76.73,164.44 ; J1.20 77.86,164.44 ; J1.20 77.86,163.31 ; J1.169 82.11,165.51 ; J1.169 80.98,166.64 ; J1.169 82.11,166.64 ; J1.169 80.98,165.51 ; J1.254 159.46,167.11 ; J1.254 158.33,167.11 ; J1.254 158.33,168.24 ; J1.254 159.46,168.24 ; J1.248 154.36,167.11 ; J1.248 153.23,167.11 ; J1.248 153.23,168.24 ; J1.248 154.36,168.24 ; J1.274 176.46,168.24 ; J1.274 175.33,167.11 ; J1.274 175.33,168.24 ; J1.274 176.46,167.11 ; 176.18,161.71 J1.131 ; J1.131 176.18,162.84 ; J1.131 177.31,161.71 ; J1.131 177.31,162.84 ; 170.23,168.24 J1.268 ; J1.268 171.36,167.11 ; J1.268 171.36,168.24 ; J1.268 170.23,167.11 ; 121,15.08 J9.5 ; J9.5 121,16.96 ; J9.5 122.88,16.96 ; J9.5 122.88,15.08 ; J1.13 71.91,161.71 ; J1.13 71.91,162.84 ; J1.13 70.78,161.71 ; J1.13 70.78,162.84 ; J1.37 92.31,162.84 ; J1.37 91.18,161.71 ; J1.37 91.18,162.84 ; J1.37 92.31,161.71 ; J1.202 110.16,167.11 ; J1.202 109.03,167.11 ; J1.202 109.03,168.24 ; J1.202 110.16,168.24 ; J34.3 265.3,180.59 ; J34.3 263.78,182.12 ; J34.3 265.3,182.12 ; J34.3 263.78,180.59 ; J1.149 65.11,166.64 ; J1.149 65.11,165.51 ; J1.149 63.98,166.64 ; J1.149 63.98,165.51 ; 79.28,165.51 J1.167 ; J1.167 79.28,166.64 ; J1.167 80.41,165.51 ; J1.167 80.41,166.64 ; 69.93,167.11 J1.156 ; J1.156 69.93,168.24 ; J1.156 71.06,168.24 ; J1.156 71.06,167.11 ; J1.182 93.16,167.11 ; J1.182 92.03,167.11 ; J1.182 93.16,168.24 ; J1.182 92.03,168.24 ; J1.123 170.51,161.71 ; J1.123 169.38,162.84 ; J1.123 169.38,161.71 ; J1.123 170.51,162.84 ; 274.01,84.46 J26.A4 ; J26.A4 275.25,85.7 ; J26.A4 275.25,84.46 ; J26.A4 274.01,85.7 ; J1.189 99.11,165.51 ; J1.189 97.98,166.64 ; J1.189 99.11,166.64 ; J1.189 97.98,165.51 ; 172.78,162.84 J1.127 ; J1.127 172.78,161.71 ; J1.127 173.91,162.84 ; J1.127 173.91,161.71 ; 224.45,126.01 J30.G1 ; J30.G1 225.9,126.01 ; J30.G1 225.9,127.46 ; 62.28,165.51 J1.147 ; J1.147 63.41,165.51 ; J1.147 62.28,166.64 ; J1.147 63.41,166.64 ; J1.270 173.06,167.11 ; J1.270 171.93,167.11 ; J1.270 173.06,168.24 ; J1.270 171.93,168.24 ; 12.15,6.6 SW4.3 ; SW4.3 13.88,6.6 ; SW4.3 12.15,8.33 ; SW4.3 13.88,8.33 ; J1.243 150.11,166.64 ; J1.243 150.11,165.51 ; J1.243 148.98,165.51 ; J1.243 148.98,166.64 ; 104.78,161.71 J1.53 ; J1.53 105.91,162.84 ; J1.53 105.91,161.71 ; J1.53 104.78,162.84 ; J1.96 147.56,164.44 ; J1.96 146.43,164.44 ; J1.96 146.43,163.31 ; J1.96 147.56,163.31 ; 81.83,164.44 J1.26 ; J1.26 82.96,164.44 ; J1.26 81.83,163.31 ; J1.26 82.96,163.31 ; J1.195 104.21,166.64 ; J1.195 104.21,165.51 ; J1.195 103.08,165.51 ; J1.195 103.08,166.64 ; 182.13,164.44 J1.138 ; J1.138 182.13,163.31 ; J1.138 183.26,163.31 ; J1.138 183.26,164.44 ; SW5.4 11.38,6.6 ; SW5.4 11.38,8.33 ; SW5.4 9.65,8.33 ; SW5.4 9.65,6.6 ; J1.259 163.71,166.64 ; J1.259 162.58,166.64 ; J1.259 163.71,165.51 ; J1.259 162.58,165.51 ; 72.48,161.71 J1.15 ; J1.15 73.61,161.71 ; J1.15 73.61,162.84 ; J1.15 72.48,162.84 ; J1.250 156.06,167.11 ; J1.250 156.06,168.24 ; J1.250 154.93,167.11 ; J1.250 154.93,168.24 ; 280.51,101.7 J26.B18 ; J26.B18 281.75,100.46 ; J26.B18 280.51,100.46 ; J26.B18 281.75,101.7 ; 121,8.49 J9.15 ; J9.15 122.88,10.38 ; J9.15 122.88,8.49 ; J9.15 121,10.38 ; 86.93,167.11 J1.176 ; J1.176 86.93,168.24 ; J1.176 88.06,167.11 ; J1.176 88.06,168.24 ; 167.68,166.64 J1.265 ; J1.265 167.68,165.51 ; J1.265 168.81,165.51 ; J1.265 168.81,166.64 ; J1.105 155.21,161.71 ; J1.105 154.08,161.71 ; J1.105 154.08,162.84 ; J1.105 155.21,162.84 ; J1.42 96.56,164.44 ; J1.42 95.43,164.44 ; J1.42 96.56,163.31 ; J1.42 95.43,163.31 ; J34.1 265.3,187.2 ; J34.1 263.78,185.67 ; J34.1 263.78,187.2 ; J34.1 265.3,185.67 ; SW5.3 4.38,6.6 ; SW5.3 2.65,6.6 ; SW5.3 4.38,8.33 ; SW5.3 2.65,8.33 ; J29.9 195.34,123.99 ; J29.9 195.34,122.22 ; J29.9 193.57,123.99 ; J29.9 193.57,122.22 ; 97.13,163.31 J1.44 ; J1.44 97.13,164.44 ; J1.44 98.26,164.44 ; J1.44 98.26,163.31 ; 173.63,167.11 J1.272 ; J1.272 174.76,168.24 ; J1.272 173.63,168.24 ; J1.272 174.76,167.11 ; J26.A1 277.43,82.88 ; J26.A1 275.82,81.27 ; J26.A1 275.82,82.88 ; J26.A1 277.43,81.27 ; 160.88,165.51 J1.257 ; J1.257 160.88,166.64 ; J1.257 162.01,165.51 ; J1.257 162.01,166.64 ; 102.23,163.31 J1.50 ; J1.50 103.36,164.44 ; J1.50 103.36,163.31 ; J1.50 102.23,164.44 ; J1.173 85.51,166.64 ; J1.173 84.38,165.51 ; J1.173 85.51,165.51 ; J1.173 84.38,166.64 ; 196.33,125.24 J29.7 ; J29.7 197.57,126.48 ; J29.7 196.33,126.48 ; J29.7 197.57,125.24 ; 78.43,163.31 J1.22 ; J1.22 79.56,164.44 ; J1.22 79.56,163.31 ; J1.22 78.43,164.44 ; 96.28,166.64 J1.187 ; J1.187 96.28,165.51 ; J1.187 97.41,166.64 ; J1.187 97.41,165.51 ; 163.43,164.44 J1.116 ; J1.116 163.43,163.31 ; J1.116 164.56,163.31 ; J1.116 164.56,164.44 ; 90.33,167.11 J1.180 ; J1.180 91.46,167.11 ; J1.180 91.46,168.24 ; J1.180 90.33,168.24 ; 108.18,161.71 J1.57 ; J1.57 109.31,161.71 ; J1.57 108.18,162.84 ; J1.57 109.31,162.84 ; 14.99,13.72 J39.2 ; J39.2 16.51,15.24 ; J39.2 14.99,15.24 ; J39.2 16.51,13.72 ; 107.33,167.11 J1.200 ; J1.200 108.46,168.24 ; J1.200 108.46,167.11 ; J1.200 107.33,168.24 ; 75.03,168.24 J1.162 ; J1.162 76.16,167.11 ; J1.162 76.16,168.24 ; J1.162 75.03,167.11 ; J26.B4 281.75,85.7 ; J26.B4 280.51,84.46 ; J26.B4 281.75,84.46 ; J26.B4 280.51,85.7 ; J30.G2 225.9,161.26 ; J30.G2 224.45,161.26 ; J30.G2 225.9,159.81 ; 67.38,161.71 J1.9 ; J1.9 68.51,162.84 ; J1.9 67.38,162.84 ; J1.9 68.51,161.71 ; J1.35 90.61,161.71 ; J1.35 89.48,161.71 ; J1.35 89.48,162.84 ; J1.35 90.61,162.84 ; 180.43,164.44 J1.136 ; J1.136 180.43,163.31 ; J1.136 181.56,164.44 ; J1.136 181.56,163.31 ; J1.151 66.81,166.64 ; J1.151 65.68,165.51 ; J1.151 66.81,165.51 ; J1.151 65.68,166.64 ; 171.08,162.84 J1.125 ; J1.125 172.21,162.84 ; J1.125 172.21,161.71 ; J1.125 171.08,161.71 ; 80.13,164.44 J1.24 ; J1.24 81.26,163.31 ; J1.24 81.26,164.44 ; J1.24 80.13,163.31 ; J1.17 75.31,161.71 ; J1.17 75.31,162.84 ; J1.17 74.18,161.71 ; J1.17 74.18,162.84 ; J1.134 179.86,163.31 ; J1.134 178.73,163.31 ; J1.134 179.86,164.44 ; J1.134 178.73,164.44 ; J1.276 178.16,168.24 ; J1.276 177.03,167.11 ; J1.276 177.03,168.24 ; J1.276 178.16,167.11 ; J1.178 89.76,167.11 ; J1.178 89.76,168.24 ; J1.178 88.63,168.24 ; J1.178 88.63,167.11 ; J35.3 265.3,199.64 ; J35.3 263.78,199.64 ; J35.3 263.78,201.17 ; J35.3 265.3,201.17 ; 4,5.73 SW5.1 ; SW5.1 5.53,5.73 ; SW5.1 4,4.2 ; SW5.1 5.53,4.2 ; J1.193 102.51,166.64 ; J1.193 101.38,165.51 ; J1.193 101.38,166.64 ; J1.193 102.51,165.51 ; J1.103 153.51,161.71 ; J1.103 153.51,162.84 ; J1.103 152.38,161.71 ; J1.103 152.38,162.84 ; 264.54,195.96 265.3,195.2 ; 264.54,195.96 265.3,196.72 ; 264.54,195.96 263.78,196.72 ; 264.54,195.96 263.78,195.2 ; 183.83,163.31 J1.140 ; J1.140 184.96,164.44 ; J1.140 184.96,163.31 ; J1.140 183.83,164.44 ; 64.83,164.44 J1.6 ; J1.6 65.96,163.31 ; J1.6 64.83,163.31 ; J1.6 65.96,164.44 ; J1.129 175.61,161.71 ; J1.129 174.48,162.84 ; J1.129 174.48,161.71 ; J1.129 175.61,162.84
  L7GND w1.016: J37.13 8.69,75.28 ; J37.13 6.89,75.28 ; J37.13 8.69,73.48 ; J37.13 6.89,73.48 ; J37.17 8.69,56.68 ; J37.17 8.69,58.48 ; J37.17 6.89,56.68 ; J37.17 6.89,58.48 ; J37.5 14.19,66.88 ; J37.5 12.39,65.08 ; J37.5 14.19,65.08 ; J37.16 8.69,60.88 ; J37.16 6.89,60.88 ; J37.16 6.89,62.68 ; J37.16 8.69,62.68 ; 6.89,65.08 J37.15 ; J37.15 6.89,66.88 ; J37.15 8.69,66.88 ; J37.15 8.69,65.08 ; J37.3 14.19,75.28 ; J37.3 12.39,73.48 ; J37.3 12.39,75.28 ; J37.3 14.19,73.48 ; J37.7 14.19,58.48 ; J37.7 12.39,56.68 ; J37.7 12.39,58.48 ; J37.7 14.19,56.68
  BOTTOM w0.254: U2.28 v1(102.56,123.38) ; v1(102.56,123.38) 102.56,122.94 ; v1(102.56,123.38) 102.56,123.83 ; 102.56,123.83 102.51,123.88 U2.27 ; 102.56,123.83 102.56,124.14 102.32,124.38 U2.26 ; U2.1 v1(92.58,113.38) ; U2.39 v1(102.49,117.88) ; U2.32 102.27,121.38 102.49,121.16 v1(102.49,120.38) U2.34 ; 102.56,122.94 102.5,122.88 U2.29 ; 102.56,122.94 102.56,122.62 102.31,122.38 U2.30 ; U2.24 v1(92.58,124.88) ; v1(238.25,30.73) 238.25,16 240.79,13.46 J40.10 ; U2.10 v1(92.6,117.88) ; U2.21 v1(92.58,123.38) ; U2.15 v1(92.6,120.38) ; U2.4 v1(92.58,114.88) ; U2.45 v1(102.49,114.88)
  BOTTOM w0.305: v2(126.37,101.02) 126.57,100.81 C144.2 ; C99.2 132.56,112.43 v2(132.77,112.22) ; v2(135.97,109.02) 135.97,109.01 C116.2 ; v2(129.57,109.02) 129.77,108.81 C104.2 ; v2(141.57,112.22) 141.78,112.43 C109.2 ; U34.5 v1(112.23,108.12) ; v2(129.57,112.22) 129.35,112.43 129.35,112.43 ; C119.2 137.78,112.43 v2(137.57,112.22) ; C117.2 131.37,108.81 v2(131.17,109.02) ; v2(132.77,109.02) 132.97,108.81 C101.2 ; C115.2 136.18,112.43 v2(135.97,112.22) ; v2(126.37,98.62) 126.57,98.82 C161.2 ; v2(131.17,112.22) 130.95,112.43 C111.2 ; 139.38,112.43 139.38,112.43 v2(139.17,112.22) ; C103.2 v2(143.17,112.22) ; C100.2 v2(126.37,112.22) ; v2(127.97,112.22) 127.75,112.43 C112.2 ; C114.2 v2(135.17,109.02) ; v2(137.57,109.02) 137.36,108.81 C113.2
  BOTTOM w0.381: v2(132.77,114.84) 132.8,114.81 R2.1 ; v1(32.64,34.67) U11.9 v1(32.64,36.96) ; v1(44.58,36.96) U10.9 v1(44.58,34.67)
  BOTTOM w0.457: C52.2 v2(146.43,96.39) ; v2(129.57,91.42) 129.44,91.29 C1138.2 ; C107.2 128.52,90.07 128.52,90.96 128.07,91.42 v2(127.97,91.42) ; R4.1 124.77,104.55 v2(124.77,104.22) ; C51.1 145.25,90.93 v2(144.77,91.42) ; v2(126.37,91.42) 126.37,89.94 C122.2 ; v2(146.43,97.79) 146.69,97.54 R134.2 ; v2(145.54,92.2) 145.67,92.08 R131.1
  BOTTOM w0.508: C313.2 v1(93.47,37.47) ; v1(71.88,125.65) 72.49,126.26 C38.2 ; J26.B16 281.75,99.7 ; J26.B16 281.75,98.46 ; J26.B16 280.51,98.46 ; J26.B16 280.51,99.7 ; v1(107.47,48.67) 107.59,48.54 C85.2 ; C321.2 69.22,55.37 v1(68.83,54.99) ; v1(77.98,87.5) 77.85,87.38 C858.2 ; R167.1 v1(123.09,87.15) ; 4,5.73 SW5.1 ; SW5.1 5.53,4.2 ; SW5.1 4,4.2 ; SW5.1 5.53,5.73 ; R142.1 R143.1 R144.1 v1(156.06,92.23) ; v1(130.81,35.94) 130.81,35.43 C353.1 131.83,35.43 v1(131.83,35.94) ; C791.2 v1(52.47,88.89) ; 263.78,199.64 J35.3 ; J35.3 265.3,199.64 ; J35.3 263.78,201.17 ; J35.3 265.3,201.17 ; v1(40.01,34.54) 40.07,34.48 J3.3 ; C516.1 v1(179.58,64.52) ; v1(147.57,42.04) 147.57,41.53 C376.1 146.56,41.53 v1(146.56,42.04) ; C428.2 158.34,45.79 v1(158.33,45.81) ; C504.1 v1(176.66,41.66) ; C1123.2 v1(265.2,55.35) ; v1(117.86,97.85) 117.22,98.49 C146.2 ; C532.1 v1(192.53,41.66) ; v1(112.14,159.13) 112.97,159.13 Q25.2 ; C124.2 C123.2 C122.2 ; v1(142.37,85.85) 141.35,84.84 C128.2 140.84,84.84 140.21,85.47 140.21,85.92 v1(140.08,86.04) ; C792.2 v1(37.47,103.88) ; v1(233.3,40.13) 233.3,39.62 C559.1 232.28,39.62 v1(232.28,40.13) ; SW4.3 13.88,6.6 ; SW4.3 12.15,6.6 ; SW4.3 12.15,8.33 ; SW4.3 13.88,8.33 ; C539.1 v1(233.17,64.52) ; C81.2 96.11,59.46 v1(96.04,59.54) ; C271.2 119.76,96.65 v1(119.25,96.14) 118.87,95.76 C162.2 ; v1(46.47,93.89) 45.97,94.38 U57.K9 ; C545.1 v1(224.28,64.52) ; v1(44.47,97.88) 44.96,97.39 U57.G8 ; J34.1 265.3,187.2 ; J34.1 265.3,185.67 ; J34.1 263.78,187.2 ; J34.1 263.78,185.67 ; v1(194.69,81.91) 194.59,81.91 C524.1 ; Q26.2 117.66,158.82 v1(117.35,159.13) ; C536.1 v1(194.72,85.45) ; v1(167.01,31.5) 167.01,30.99 C408.1 165.99,30.99 v1(165.99,31.5) ; C330.2 65.41,42.42 v1(64.9,41.91) ; C40.2 78.84,113.13 v1(79.12,113.41) ; 263.78,180.59 J34.3 ; J34.3 265.3,182.12 ; J34.3 265.3,180.59 ; J34.3 263.78,182.12 ; C42.2 C41.2 69.24,121.64 v1(69.22,121.67) ; R176.2 v1(160.4,113.66) ; 2.65,6.6 SW5.3 ; SW5.3 4.38,6.6 ; SW5.3 2.65,8.33 ; SW5.3 4.38,8.33 ; U57.J10 v1(47.47,94.89) ; J35.1 265.3,206.25 ; J35.1 263.78,204.72 ; J35.1 265.3,204.72 ; J35.1 263.78,206.25 ; 9.65,6.6 SW5.4 ; SW5.4 9.65,8.33 ; SW5.4 11.38,6.6 ; SW5.4 11.38,8.33 ; C46.2 v1(38.48,37.08) ; C540.1 v1(230.25,64.52) ; R22.1 v1(80.26,116.59) ; C786.2 v1(53.47,87.89) ; C34.2 v1(66.55,118.75) ; v1(82.68,33.78) 82.8,33.66 C314.2 ; v1(119.89,35.94) 119.89,35.43 C347.1 120.9,35.43 v1(120.9,35.94) ; C327.2 v1(61.47,50.04) ; C426.2 v1(156.74,53.44) ; C107.2 C118.2 C108.2 ; v2(225.68,87.25) 225.53,87.1 R348.1 ; C512.1 v1(185.55,64.52) ; C1138.2 C97.2 C98.2 ; C32.2 92.24,123.04 v1(92.58,123.38) ; 19.15,6.6 SW4.4 ; SW4.4 20.88,8.33 ; SW4.4 19.15,8.33 ; SW4.4 20.88,6.6 ; U57.J8 v1(44.47,94.89) ; U20.2 v1(69.85,18.03) ; 278.51,87.46 J26.B7 ; J26.B7 279.75,88.7 ; J26.B7 279.75,87.46 ; J26.B7 278.51,88.7 ; v1(85.6,30.48) 85.5,30.58 C316.2 ; C826.2 237.24,126.87 v1(237.11,127) ; J39.2 16.51,13.72 ; J39.2 14.99,15.24 ; J39.2 16.51,15.24 ; J39.2 14.99,13.72 ; v1(251.84,30.73) 251.84,30.23 C1078.1 250.83,30.23 v1(250.83,30.73) ; C365.2 121.79,45.59 v1(121.29,45.09) ; v1(69.47,41.78) 69.49,41.81 C328.2 ; C499.1 v1(214.38,41.66) ; C785.2 v1(38.47,88.89) ; C331.2 v1(71.63,39.37) ; v1(86.77,53.44) 86.84,53.37 C84.2 ; 263.78,172.59 264.54,171.83 ; 264.54,171.83 265.3,172.59 ; 264.54,171.83 265.3,171.07 ; 264.54,171.83 263.78,171.07 ; C33.2 v1(58.7,120.12) ; v1(135.38,86.61) 136.02,87.25 C131.2 ; C795.2 v1(47.47,97.88) ; C86.2 97.51,47.02 v1(97.41,47.12) 97.38,47.09 R239.1 ; 264.54,195.96 265.3,195.2 ; 264.54,195.96 263.78,196.72 ; 264.54,195.96 263.78,195.2 ; 264.54,195.96 265.3,196.72 ; v1(138.56,51.05) 138.05,51.56 C381.2 ; C43.2 72.01,113.41 v1(72.14,113.54) ; v1(188.72,39.5) 189.61,39.5 C560.1 189.61,40.26 v1(188.72,40.26) ; v1(102.49,114.88) 102.83,115.21 C31.2 ; v1(220.6,40.26) 221.49,40.26 C555.1 221.49,39.5 v1(220.6,39.5) ; v1(58.8,124.08) 59.03,124.31 C36.2 ; C394.2 v1(139.13,53.15) ; U57.G9 45.97,97.39 v1(46.47,97.88) ; 275.25,101.7 J26.A18 275.25,100.46 ; C502.1 v1(179.58,41.66) ; v1(107.47,54.76) 107.47,54.76 C79.2 ; v1(172.97,40.26) 173.86,40.26 C552.1 173.86,39.5 v1(172.97,39.5) ; C544.1 v1(195.45,64.52) ; v1(241.43,133.99) 241.17,134.24 C834.2 ; R685.1 v1(110.49,159.13) ; C783.2 v1(43.47,93.89) ; v1(204.72,39.5) 205.61,39.5 C551.1 205.61,40.26 v1(204.72,40.26) ; 243.94,47.7 C1099.2 ; C529.1 v1(227.2,41.66) ; v1(107.32,60.63) 107.34,60.6 C80.2 ; 275.25,94.46 J26.A12 275.25,95.7 ; J33.1 265.3,176.15 ; J33.1 265.3,177.67 ; J33.1 263.78,176.15 ; J33.1 263.78,177.67 ; v1(65.95,55.02) 66.29,55.37 C320.2 ; J32.3 265.3,190.12 ; J32.3 263.78,191.64 ; J32.3 263.78,190.12 ; J32.3 265.3,191.64 ; C518.1 v1(176.66,64.52) ; C35.2 v1(64.39,120.4) ; C526.1 v1(201.42,41.66) ; R240.1 103.65,54.84 v1(104.23,55.41) ; C530.1 v1(195.45,41.66) ; SW4.1 15.03,5.73 ; SW4.1 15.03,4.2 ; SW4.1 13.5,4.2 ; SW4.1 13.5,5.73 ; 276.01,98.7 J26.A15 ; J26.A15 276.01,97.46 ; J26.A15 277.25,97.46 ; J26.A15 277.25,98.7 ; R647.1 v1(183.92,157.96) ; v1(240.16,30.73) 240.16,30.23 C1081.1 241.17,30.23 v1(241.17,30.73) ; v1(156.34,31.5) 156.34,30.99 C405.1 155.32,30.99 v1(155.32,31.5) ; R166.1 122.07,89.92 ; 122.07,89.92 R169.1 v1(121.31,89.89) ; 122.07,89.92 R168.1 ; U57.K8 44.96,94.38 v1(44.47,93.89) ; v1(269.24,30.73) 269.24,30.23 C1115.1 270.26,30.23 v1(270.26,30.73) ; C64.2 v1(219.84,102.23) ; J26.B18 281.75,100.46 ; J26.B18 280.51,101.7 ; J26.B18 280.51,100.46 ; J26.B18 281.75,101.7 ; C500.1 v1(182.63,41.66) ; v1(61.47,45.89) 61.71,46.13 C325.2 ; 19.3,15.24 J38.2 ; J38.2 20.83,15.24 ; J38.2 20.83,13.72 ; J38.2 19.3,13.72 ; J26.B13 279.75,96.7 ; J26.B13 278.51,96.7 ; J26.B13 278.51,95.46 ; J26.B13 279.75,95.46 ; v1(60.96,41.02) 60.96,41.17 C326.2 ; C297.2 v1(115.29,110.87) ; C787.2 v1(38.47,102.88) ; C525.1 v1(233.17,41.66) ; v1(235.46,133.73) 235.69,133.96 C838.2 ; v1(74.46,53.89) 73.91,53.34 C329.2 ; C503.1 v1(208.41,41.66) ; C501.1 v1(211.33,41.66) ; C311.2 90.14,30.45 v1(90.3,30.61) ; C262.2 123.93,98.66 v2(123.97,98.62) ; C793.2 v1(52.47,102.88) ; v1(119.25,101.09) 119.89,101.73 C266.2 ; C309.2 85.7,39.54 v1(85.91,39.75) ; C83.2 v1(86.87,46.89) ; v1(76.01,113.35) 75.57,112.91 C39.2 ; C527.1 v1(230.25,41.66) ; C836.2 v1(235.59,122.94) ; C498.1 v1(185.55,41.66) ; R337.1 193.78,87.1 v2(193.93,87.25) ; v1(93.22,30.61) 93.07,30.76 C310.2 ; C542.1 v1(198.5,64.52) ; C514.1 v1(182.63,64.52) ; C272.2 123.93,96.26 v2(123.97,96.22) ; C535.1 v1(226.47,85.45) ; C82.2 v1(85.22,59.46) ; C61.2 v1(188.47,99.95) ; R113.1 R114.1 120.17,106.17 C274.2 119.61,105.66 C273.2 118.87,105.16 v1(118.49,104.78) ; v1(258.57,30.73) 258.57,30.23 C1112.1 259.59,30.23 v1(259.59,30.73) ; C352.2 116.59,46.74 v1(116.46,46.61) ; C267.2 123.93,101.06 v2(123.97,101.02) ; v1(136.27,42.04) 136.27,41.53 C382.1 135.26,41.53 v1(135.26,42.04) ; C523.1 226.34,81.91 v1(226.44,81.91) ; v1(102.56,123.38) 102.9,123.04 C30.2 ; C125.2 146.65,67.53 v1(145.54,66.42) ; C261.2 119.76,99.19 v1(119.25,98.68) ; U57.H7 v1(43.47,96.88) ; C513.1 v1(214.38,64.52) ; C794.2 v1(53.47,103.88) ; C528.1 v1(198.5,41.66) ; v1(97.31,53.44) 97.38,53.37 C336.2 ; U57.H9 v1(46.47,96.88) ; C531.1 v1(224.28,41.66) ; C511.1 v1(217.3,64.52) ; J3.6 v1(33.4,34.04) ; C1101.2 v1(242.34,55.35) ; C782.2 v1(43.47,97.88) ; C543.1 v1(227.2,64.52) ; C517.1 v1(208.41,64.52) ; C784.2 v1(37.47,87.89) ; R218.1 v1(92.2,38.1) ; 266.8,47.7 C1134.2 ; R179.2 v1(160.4,117.47) ; C541.1 v1(201.42,64.52) ; C515.1 v1(211.33,64.52) ; C780.2 v1(47.47,93.89) ; C497.1 v1(217.3,41.66) ; C47.2 v1(37.47,37.08) ; C546.1 v1(192.53,64.52) ; R646.1 v1(170.69,116.97)
  BOTTOM w0.635: C89.2 130.32,155.48 v1(129.29,155.48) ; v1(124.4,139.86) 124.49,139.78 C90.2 ; C87.2 149.89,139.78 v1(149.8,139.86) ; v1(148.59,156.84) 149.15,156.29 C93.2 ; C1065.2 143.54,139.78 v1(143.45,139.86) ; v1(117.8,139.86) 117.88,139.78 C88.2 ; C92.2 131.22,139.78 v1(131.13,139.86) ; v1(135.13,147.57) 135.81,148.26 C91.2 ; v1(137.23,139.86) 137.31,139.78 C94.2
  BOTTOM w1.016: 12.39,73.48 J37.3 ; J37.3 14.19,73.48 ; J37.3 12.39,75.28 ; J37.3 14.19,75.28 ; 6.89,73.48 J37.13 ; J37.13 8.69,73.48 ; J37.13 8.69,75.28 ; J37.13 6.89,75.28
  vias: v1(17.02,42.55) v1(17.02,41.66) v1(20.83,35.69) v1(21.72,35.69) v1(24.51,10.12) v1(24.51,9.27) v1(27.31,169.3) v1(28.32,169.3) v1(28.7,18.54) v1(28.7,17.53) v1(28.7,16.64) v1(29.34,169.3) v1(29.59,54.99) v1(30.35,169.3) v1(30.99,160.79) v1(31.37,169.3) v1(31.75,160.79) v1(32.39,169.3) v1(32.51,160.79) v1(33.27,50.55) v1(33.27,49.78) v1(33.27,49.02) v1(33.4,169.3) v1(34.42,169.3) v1(34.42,165.11) v1(34.42,164.22) v1(34.42,163.33) v1(34.42,162.44) v1(34.81,61.72) v1(34.81,60.96) v1(34.81,60.2) v1(34.93,47.12) v1(35.31,164.73) v1(35.31,163.84) v1(35.43,169.3) v1(35.81,47.12) v1(36.32,46.23) v1(36.46,58.29) v1(36.7,47.12) v1(37.21,46.23) v1(37.35,58.29) v1(37.59,47.12) v1(37.85,57.4) v1(38.23,58.29) v1(38.74,57.4) v1(39.12,58.29) v1(41.78,55.24) v1(41.78,54.23) v1(41.78,53.21) v1(41.78,52.2) v1(41.78,51.18) v1(41.78,50.16) v1(41.78,49.15) v1(41.78,48.13) v1(41.78,47.12) v1(41.78,46.1) v1(43.31,65.41) v1(43.31,64.39) v1(43.31,63.37) v1(43.31,62.36) v1(43.31,61.34) v1(43.31,60.33) v1(43.31,59.31) v1(43.31,58.29) v1(43.31,57.28) v1(46.1,133.86) v1(47.12,133.86) v1(48.13,133.86) v1(55.75,134.49) v1(57.15,19.69) v1(57.15,18.42) v1(57.15,17.53) v1(60.45,34.32) v1(60.45,33.48) v1(61.52,34.32) v1(61.52,33.48) v1(61.72,27.94) v1(62.36,33.93) v1(62.48,27.94) v1(63.2,34.32) v1(63.2,33.48) v1(63.25,27.94) v1(67.05,178.21) v1(68.45,178.21) v1(68.83,97.79) v1(68.83,97.03) v1(68.83,96.27) v1(69.15,76.26) v1(69.98,27.05) v1(69.98,26.29) v1(70.1,28.58) v1(70.49,94.36) v1(71.31,70.8) v1(71.37,94.36) v1(71.88,93.47) v1(72.26,94.36) v1(72.39,73.6) v1(72.77,93.47) v1(73.15,94.36) v1(73.15,68.96) v1(96.27,182.63) v1(97.54,182.63) v1(116.71,31.11) v1(117.29,135.67) v1(117.26,133.51) v1(117.6,31.11) v1(118.11,27.05) v1(118.11,25.91) v1(118.11,23.62) v1(118.2,154.85) v1(121.61,135.67) v1(121.58,133.51) v1(123.19,169.04) v1(123.32,175.26) v1(123.32,170.69) v1(123.44,51.31) v1(123.44,50.16) v1(123.44,49.02) v1(123.44,48.01) v1(123.7,173.86) v1(123.7,172.21) v1(123.95,169.04) v1(124.08,175.26) v1(124.08,170.69) v1(124.84,48.01) v1(124.97,51.31) v1(125.1,49.15) v1(125.73,50.29) v1(126.37,48.01) v1(126.62,176.15) v1(126.62,51.31) v1(126.62,49.53) v1(127.51,176.15) v1(127.7,135.67) v1(127.68,133.51) v1(128.52,176.15) v1(129.29,171.96) v1(129.41,176.15) v1(129.79,171.32) v1(130.3,171.96) v1(133.9,133.51) v1(133.93,135.67) v1(141.01,133.51) v1(141.04,135.67) v1(141.35,59.31) v1(141.35,58.17) v1(141.35,57.15) v1(141.35,56.01) v1(142.75,57.15) v1(142.75,56.01) v1(142.88,59.31) v1(143.64,58.17) v1(144.27,56.01) v1(144.4,59.31) v1(144.4,57.15) v1(146.75,135.67) v1(146.73,133.51) v1(149.16,91.82) v1(152.27,41.66) v1(152.27,40.89) v1(155.7,89.73) v1(159.39,52.07) v1(159.89,46.23) v1(160.15,48.01) v1(160.4,118.49) v1(160.4,116.46) v1(160.4,114.68) v1(160.4,112.65) v1(160.4,50.29) v1(161.04,46.23) v1(161.42,49.15) v1(161.54,47.12) v1(162.43,48.01) v1(162.69,50.29) v1(162.69,46.23) v1(163.45,47.12) v1(163.83,49.15) v1(164.08,46.23) v1(164.72,50.29) v1(164.72,48.01) v1(164.97,45.47) v1(165.74,118.87) v1(165.74,117.47) v1(165.74,116.08) v1(165.74,115.06) v1(165.74,113.66) v1(165.74,112.27) v1(166.37,51.44) v1(166.37,49.4) v1(166.37,47.5) v1(168.53,122.43) v1(168.66,124.84) v1(168.66,123.83) v1(169.16,127.13) v1(169.16,126.11) v1(169.29,122.81) v1(169.67,124.84) v1(169.67,123.83) v1(170.69,117.98) v1(171.7,117.98) v1(171.7,116.97) v1(172.97,118.11) v1(172.97,116.84) v1(174.75,117.98) v1(177.04,87.88) v1(177.04,87.12) v1(177.29,89.15) v1(180.46,149.1) v1(180.46,148.08) v1(180.46,147.07) v1(180.46,146.05) v1(180.46,145.03) v1(180.46,144.02) v1(180.46,143) v1(180.46,141.99) v1(180.46,140.97) v1(180.98,110.49) v1(183.26,109.73) v1(183.26,74.55) v1(183.64,99.95) v1(183.64,72.14) v1(184.02,94.49) v1(184.65,148.08) v1(185.03,148.97) v1(185.29,107.57) v1(185.29,93.47) v1(185.54,148.08) v1(185.92,148.97) v1(186.43,148.08) v1(186.94,159.13) v1(187.32,148.08) v1(187.58,106.81) v1(187.71,159.13) v1(188.09,132.33) v1(188.21,157.48) v1(188.72,71.25) v1(188.85,130.05) v1(188.97,146.18) v1(188.97,145.41) v1(188.97,144.65) v1(189.48,157.48) v1(190.5,73.91) v1(190.75,157.48) v1(191.14,153.67) v1(191.14,152.78) v1(191.14,151.26) v1(191.26,156.08) v1(192.15,160.66) v1(192.15,159.89) v1(192.15,155.32) v1(192.91,181.64) v1(192.91,180.49) v1(195.83,76.33) v1(197.87,75.06) v1(199.64,75.06) v1(208.79,87.88) v1(208.79,87.12) v1(209.04,89.15) v1(214.12,96.14) v1(215.2,102.23) v1(215.39,96.52) v1(223.39,178.21) v1(224.78,178.21) v1(238,131.32) v1(238.12,130.18) v1(238.12,129.16) v1(239.27,129.16) v1(239.52,131.32) v1(239.52,130.18) v1(240.02,93.34) v1(240.02,92.33) v1(240.02,91.31) v1(240.02,90.3) v1(240.02,89.28) v1(240.02,88.27) v1(240.02,87.25) v1(240.02,86.23) v1(240.02,85.22) v1(240.28,129.16) v1(240.28,57.91) v1(240.41,131.7) v1(240.41,130.68) v1(240.79,58.67) v1(241.05,67.18) v1(241.17,72.64) v1(241.17,71.75) v1(241.43,57.91) v1(242.06,74.03) v1(242.06,73.14) v1(242.06,72.26) v1(242.06,71.37) v1(242.06,67.18) v1(243.08,67.18) v1(243.97,75.68) v1(244.09,67.18) v1(244.21,92.33) v1(244.59,93.22) v1(244.73,75.68) v1(245.1,92.33) v1(245.11,67.18) v1(245.48,93.22) v1(245.49,75.68) v1(245.49,48.13) v1(245.75,49.91) v1(245.99,92.33) v1(246,52.2) v1(246.13,67.18) v1(246.63,48.13) v1(246.88,92.33) v1(247.02,103.12) v1(247.02,100.71) v1(247.02,51.05) v1(247.14,67.18) v1(247.14,49.02) v1(247.52,98.81) v1(247.52,96.39) v1(248.03,49.91) v1(248.16,67.18) v1(248.29,52.2) v1(248.29,48.13) v1(248.53,90.42) v1(248.53,89.66) v1(248.53,88.9) v1(249.05,49.02) v1(249.17,67.18) v1(249.3,100.97) v1(249.3,98.55) v1(249.43,51.05) v1(249.68,48.13) v1(249.81,96.65) v1(249.81,94.23) v1(250.32,52.2) v1(250.32,49.91) v1(250.57,47.37) v1(259.33,153.8) v1(259.33,150.24) v1(259.84,151.76) v1(261.49,152.15) v1(262,150.5) v1(263.4,153.92) v1(263.78,151.89) v1(265.35,82.11) v1(265.35,79.44) v1(266.12,76.26) v1(266.12,75.38) v1(266.62,82.11) v1(266.62,79.44) v1(267.97,155.7) v1(268.35,48.13) v1(268.48,156.59) v1(268.61,49.91) v1(268.86,52.2) v1(269.24,154.43) v1(269.24,153.42) v1(269.37,163.32) v1(269.49,48.13) v1(269.88,51.05) v1(270,49.02) v1(270.38,163.32) v1(270.64,92.08) v1(270.64,91.19) v1(270.64,90.42) v1(270.89,49.91) v1(271.14,52.2) v1(271.14,48.13) v1(271.4,161.42) v1(271.91,49.02) v1(272.29,51.05) v1(272.42,160.91) v1(272.54,48.13) v1(273.18,52.2) v1(273.18,49.91) v1(273.43,47.37) v1(273.86,75.38) v1(275.01,75.38) v1(276.15,75.38) v1(277.16,75.38) v1(281.48,76.14) v1(282.37,76.14) v2(127.17,97.82) v2(131.17,98.62) v2(181.86,80.9) v2(182.42,85.06) v2(182.75,87.88) v2(182.83,85.9) v2(183.49,85.52) v2(184.28,88.39) v2(185.93,90.17) v2(187.2,83.69) v2(187.58,86.36) v2(187.58,85.47) v2(187.58,84.58) v2(187.83,90.17) v2(188.47,86.36) v2(188.47,85.47) v2(188.47,84.58) v2(188.47,83.69) v2(190.25,89.66) v2(213.61,80.9) v2(214.17,85.06) v2(214.5,87.88) v2(214.58,85.9) v2(215.24,85.52) v2(216.03,88.39) v2(217.68,90.17) v2(218.95,83.69) v2(219.33,86.36) v2(219.33,85.47) v2(219.33,84.58) v2(219.58,90.17) v2(220.22,86.36) v2(220.22,85.47) v2(220.22,84.58) v2(220.22,83.69) v2(222,89.66) v3(2.92,208.66) v3(2.92,202.95) v3(2.92,197.87) v3(2.92,192.15) v3(2.92,185.8) v3(2.92,180.09) v3(2.92,173.74) v3(2.92,167.39) v3(2.92,161.67) v3(2.92,155.32) v3(2.92,149.61) v3(2.92,143.89) v3(2.92,138.18) v3(2.92,131.83) v3(2.92,125.48) v3(2.92,119.13) v3(2.92,112.78) v3(2.92,106.43) v3(2.92,100.08) v3(2.92,93.73) v3(2.92,88.01) v3(2.92,82.3) v3(2.92,76.58) v3(2.92,70.23) v3(2.92,63.88) v3(2.92,57.53) v3(2.92,51.18) v3(2.92,44.83) v3(2.92,39.12) v3(2.92,34.04) v3(2.92,28.96) v3(2.92,23.88) v3(2.92,19.43) v3(2.92,14.99) v3(2.92,10.54) v3(3.56,2.92) v3(6.73,2.92) v3(7.37,209.3) v3(10.54,2.92) v3(13.08,209.3) v3(14.99,2.92) v3(18.16,209.3) v3(19.18,53.21) v3(19.18,51.44) v3(19.43,2.92) v3(21.97,53.98) v3(22.1,51.82) v3(23.24,209.3) v3(23.37,60.07) v3(23.75,63.37) v3(23.88,72.26) v3(23.88,69.09) v3(23.88,2.92) v3(27.56,63.37) v3(27.56,60.07) v3(27.69,72.39) v3(27.69,69.09) v3(28.32,209.3) v3(28.32,2.92) v3(32.77,2.92) v3(33.4,209.3) v3(37.21,2.92) v3(39.12,209.3) v3(41.66,2.92) v3(44.83,209.3) v3(46.1,2.92) v3(50.55,209.3) v3(51.18,2.92) v3(56.26,209.3) v3(56.26,2.92) v3(60.71,209.3) v3(65.15,209.3) v3(72.77,104.01) v3(75.31,209.3) v3(76.71,104.01) v3(77.34,92.33) v3(80.39,209.3) v3(81.03,100.46) v3(81.15,96.9) v3(81.28,103.89) v3(82.04,92.46) v3(84.84,209.3) v3(85.73,104.01) v3(89.92,209.3) v3(93.73,100.58) v3(93.73,98.68) v3(93.73,97.03) v3(93.73,95.12) v3(93.73,93.09) v3(95.5,92.2) v3(98.04,94.87) v3(98.04,92.84) v3(98.81,209.3) v3(98.93,86.11) v3(98.93,84.33) v3(99.06,90.3) v3(99.06,88.14) v3(100.58,94.87) v3(100.58,92.84) v3(101.09,90.3) v3(101.09,88.14) v3(101.09,85.34) v3(103.25,209.3) v3(103.25,104.01) v3(103.25,102.11) v3(103.25,99.82) v3(103.25,97.66) v3(103.25,95.12) v3(103.25,92.84) v3(103.25,90.93) v3(103.25,88.65) v3(108.33,209.3) v3(115.32,209.3) v3(121.03,209.3) v3(126.11,209.3) v3(131.83,209.3) v3(136.91,209.3) v3(142.62,209.3) v3(148.34,209.3) v3(154.05,209.3) v3(159.13,209.3) v3(164.21,209.3) v3(169.93,209.3) v3(175.64,209.3) v3(180.09,157.86) v3(180.09,153.29) v3(181.23,157.86) v3(181.23,153.29) v3(181.99,209.3) v3(182.37,157.86) v3(182.37,156.72) v3(182.37,155.57) v3(182.37,154.43) v3(182.37,153.29) v3(188.34,209.3) v3(192.79,209.3) v3(202.31,209.3) v3(206.76,209.3) v3(211.84,209.3) v3(216.92,209.3) v3(225.81,209.3) v3(230.89,209.3) v3(235.97,209.3) v3(241.05,209.3) v3(246.76,209.3) v3(251.84,209.3) v3(257.56,209.3) v3(262.64,209.3) v3(268.35,209.3) v3(273.43,209.3) v3(279.15,209.3) v3(283.59,209.3) v3(284.23,206.12) v3(284.23,201.68) v3(284.23,196.6) v3(284.23,192.15) v3(284.23,186.44) v3(284.23,180.72) v3(284.23,175.64) v3(284.23,170.56) v3(284.23,165.48) v3(284.23,160.4) v3(284.23,155.32) v3(284.23,149.61) v3(284.23,144.53) v3(284.23,139.45) v3(284.23,133.73) v3(284.23,128.02) v3(284.23,122.94) v3(284.23,117.86) v3(284.23,112.78) v3(284.23,107.7) v3(284.23,103.25) v3(284.23,96.9) v3(284.23,91.82) v3(284.23,86.11) v3(284.23,81.03) v3(284.23,75.31) v3(284.23,68.96) v3(284.23,63.25) v3(284.23,57.53) v3(284.23,51.82) v3(284.23,45.47) v3(284.23,39.12) v3(284.23,33.4)
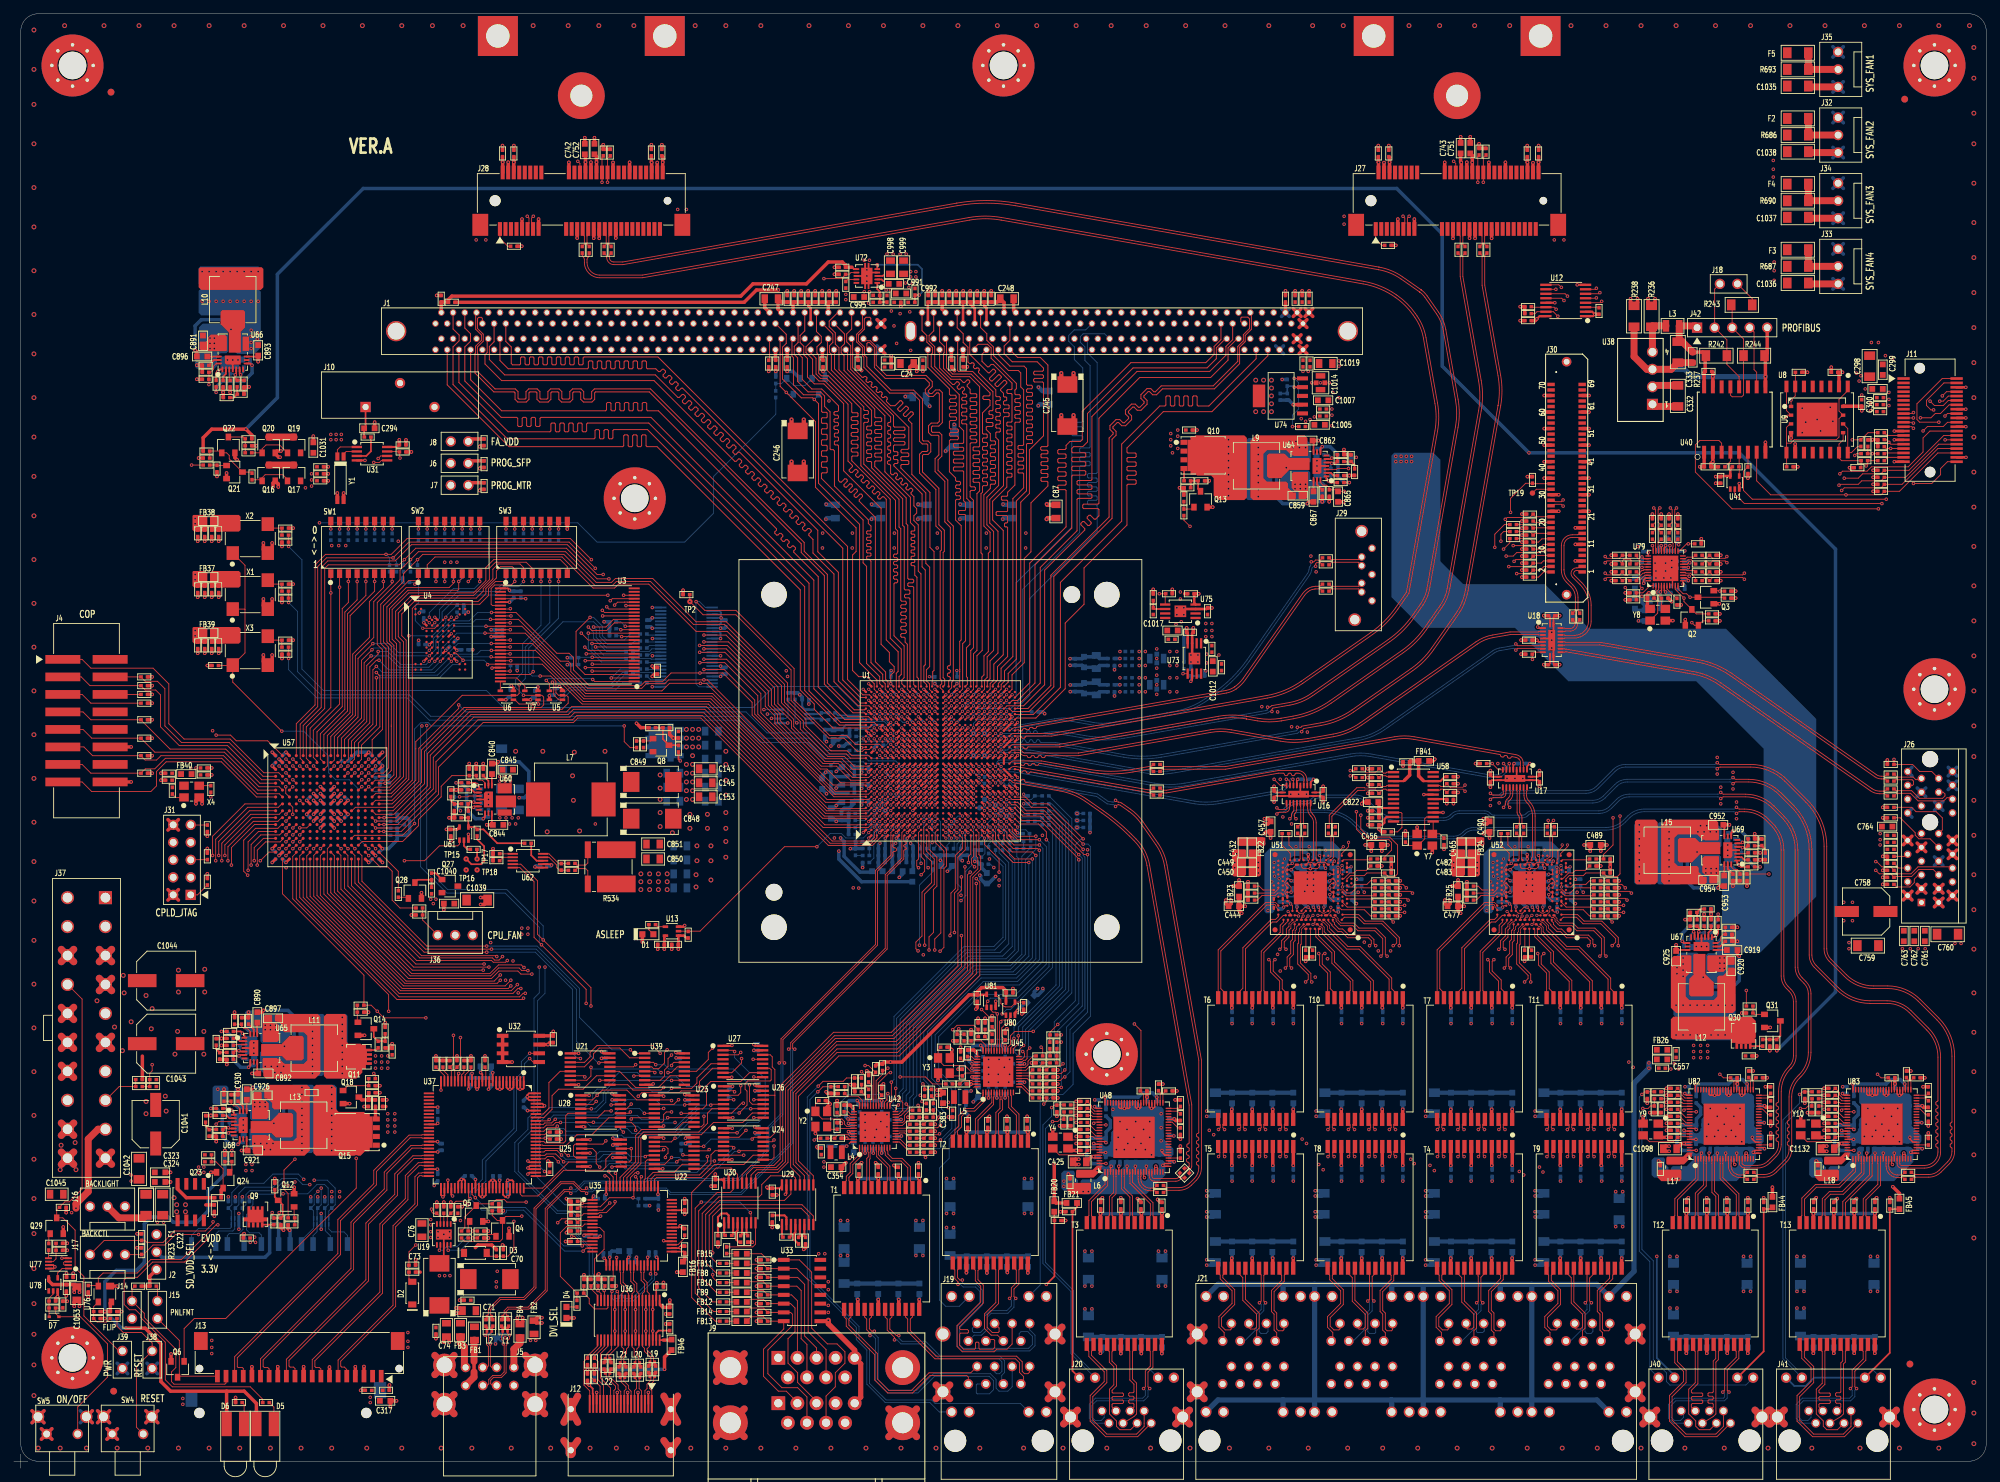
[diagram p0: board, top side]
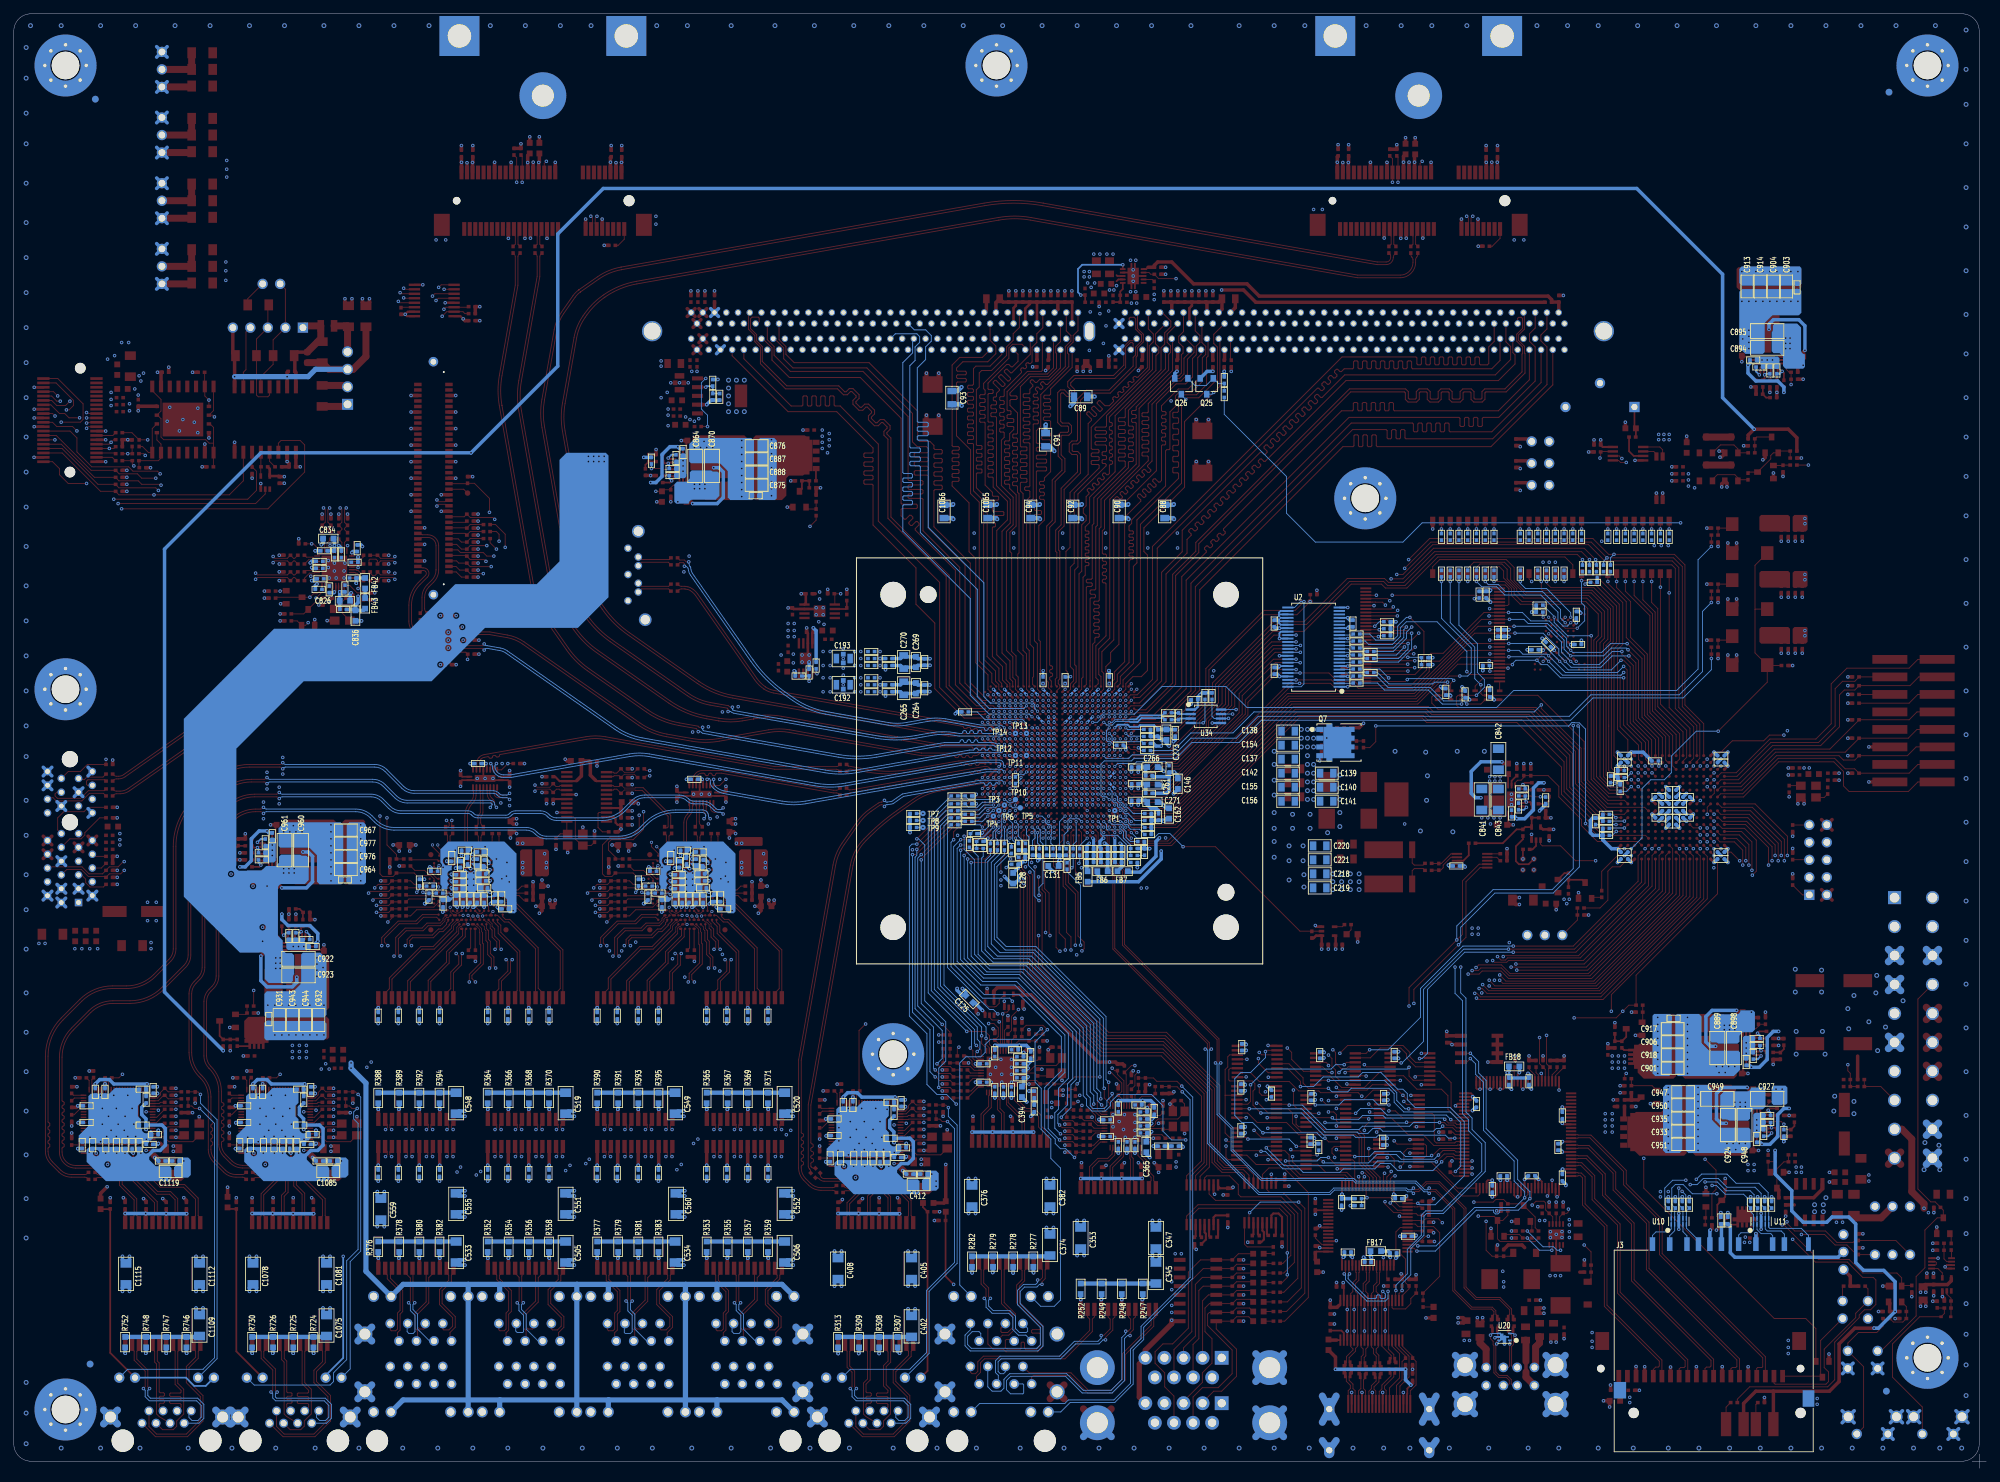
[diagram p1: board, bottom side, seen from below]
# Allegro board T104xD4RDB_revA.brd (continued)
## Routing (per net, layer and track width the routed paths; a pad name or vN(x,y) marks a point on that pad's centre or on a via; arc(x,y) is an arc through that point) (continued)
GND_PROFI: length 41.9
  TOP w0.508: J42.5 254.25,161.8 R244.1 254,161.29 v1(254,158.37) U40.9 ; U40.15 v1(246.38,158.37) 246.38,158.98 C334.2
  TOP w1.016: R238.2 234.95,161.29 236.8,159.44 U38.3 240.33,159.44 C333.2 R237.1
  BOTTOM w0.762: v1(254,158.37) v1(246.38,158.37) 243.33,158.37 242.27,159.44 U38.3
SVDD: length 5.9
  TOP w0.305: U1.W20 v2(138.37,107.42) ; U1.Y13 v2(139.17,101.02) ; U1.W15 v2(138.37,103.42) ; U1.W18 v2(138.37,105.82) ; U1.W17 v2(138.37,105.02) ; U1.W19 v2(138.37,106.62) ; U1.W16 v2(138.37,104.22)
  BOTTOM w0.127: R145.1 140.45,100.61 139.57,100.61 v2(139.17,101.02)
  vias: v1(163.2,114.68) v1(163.2,113.66) v1(163.2,112.65) v1(164.08,114.68) v1(164.08,112.65)
SVDD_EN: length 155.8
  TOP w0.127: v1(70.04,74.23) 69.91,74.36 59.12,74.36 48.97,84.51 U57.T12 ; U73.5 v1(169.55,115.28)
  L6SIG w0.102: v1(169.55,115.28) 169.55,112.14 156.64,99.24 156.64,88.95 155.46,87.77 148.79,87.77 144.91,83.88 139.13,83.88 138.18,84.84 129.36,84.84 127.9,83.38 120.33,83.38 111.7,74.74 70.55,74.74 v1(70.04,74.23)
  BOTTOM w0.127: v1(169.55,115.28) 169.67,115.4 R645.1
VCC_PROFI: length 14.6
  TOP w0.508: R237.2 244.86,161.93 R242.2 245.26,161.32 C334.1 245.11,158.98 U40.16
  TOP w1.016: J42.1 243.84,165.74 L3.2 241.5,163.65 C333.1 241.94,163.45 R237.2
VDD_EN_N: length 59.2
  TOP w0.127: U57.N12 49.4,91.82 56.39,91.82 v1(58.1,93.54) ; v1(88.52,107.7) 88.52,105.41 89.38,104.55 R552.1
  BOTTOM w0.127: v1(58.1,93.54) 58.1,107.25 59,108.14 59.63,108.14 59.7,108.2 60.06,108.2 60.33,107.94 60.33,107.88 60.55,107.66 60.58,107.7 v1(88.52,107.7)
VDD_SD: length 25.3
  BOTTOM w0.508: J3.4 38.4,35.37 C46.1 C47.1 37.11,35.1 37.11,31.26 36.45,30.61 21.46,30.61 J2.2
ASLEEP: length 34.6
  TOP w0.127: v1(116.46,90.17) 111.76,90.17 99.5,77.91 97.76,77.91 ; 97.76,77.91 R110.1 ; 97.76,77.91 U13.2 ; U1.B2 v2(123.97,92.22)
  BOTTOM w0.127: v2(123.97,92.22) 123.19,91.44 120.65,91.44 120.02,92.08 118.36,92.08 v1(116.46,90.17)
AURORA_CLKOUT: length 2.7
  TOP w0.127: J30.20 220.5,137.24 R462.1
AURORA_EVTI_N: length 223.7
  TOP w0.127: v1(70.55,71.56) 69.66,70.68 56.9,70.68 44.45,83.12 44.45,88.87 U57.R8 ; v1(215.65,134.49) 215.65,135.51 216.03,135.89 R468.1
  L6SIG w0.102: v1(215.65,134.49) 215.39,134.24 215.39,132.97 215.14,132.72 215.14,124.08 210.38,119.32 182.5,119.32 161.54,98.36 161.54,94.47 160.53,93.45 160.53,87.88 157.18,84.53 150.51,84.53 146.66,80.68 122.83,80.68 122.83,80.69 121.96,80.69 112.27,70.99 74.99,70.99 74.23,71.75 70.74,71.75 v1(70.55,71.56)
AURORA_EVTO_N: length 222.2
  TOP w0.127: v1(214.76,133.6) 214.76,135.51 216.15,136.91 R469.1 ; v1(75.12,71.69) 73.53,71.69 73.09,72.14 70.36,72.14 69.28,71.06 57.21,71.06 44.97,83.3 U57.T8
  L6SIG w0.102: v1(75.12,71.69) 75.5,71.31 112.2,71.31 121.81,80.91 122.92,80.91 122.92,80.91 146.51,80.91 150.36,84.76 157.02,84.76 160.27,88.01 160.27,93.79 161.23,94.74 161.23,98.49 182.37,119.63 210.06,119.63 214.76,124.33 v1(214.76,133.6)
AURORA_HALT_N: length 221.9
  TOP w0.127: v1(70.55,70.8) 70.1,70.36 56.71,70.36 43.97,83.1 U57.T7 ; R467.1 216.94,134.26 v1(216.03,133.35)
  L6SIG w0.102: v1(216.03,133.35) 216.03,132.84 215.77,132.59 215.77,124.21 210.57,119 182.63,119 161.86,98.23 161.86,94.46 160.78,93.38 160.78,87.73 157.35,84.3 150.66,84.3 146.81,80.46 122.73,80.46 122.18,80.46 112.33,70.61 74.87,70.61 74.17,71.31 71.06,71.31 v1(70.55,70.8)
AURORA_HRST_N: length 233.9
  TOP w0.127: v1(217.04,138.68) 217.04,140.72 219.23,142.9 R461.1 220.28,142.84 J30.34 ; U57.P9 45.47,89.88 45.47,83.44 57.47,71.44 69.15,71.44 70.29,72.58 73.28,72.58 73.66,72.2 v1(74.55,72.2)
  L6SIG w0.102: v1(217.04,138.68) 217.04,136.4 216.15,135.51 215.65,135.51 214.12,133.99 214.12,124.21 209.87,119.95 182.25,119.95 160.91,98.62 160.91,94.87 159.98,93.94 159.98,88.1 156.87,84.99 150.2,84.99 146.36,81.14 123.02,81.14 121.66,81.14 112.14,71.63 76.14,71.63 75.57,72.2 v1(74.55,72.2)
AURORA_PORST_N: length 227.4
  TOP w0.127: v1(216.28,137.67) 216.54,137.92 219.81,137.92 R460.1 220.71,138.04 J30.22 ; U57.T9 45.97,83.49 57.71,71.75 69.02,71.75 70.29,73.03 73.6,73.03 v1(73.98,72.64)
  L6SIG w0.102: v1(73.98,72.64) 75.57,72.64 76.26,71.95 112.08,71.95 121.5,81.37 123.11,81.37 146.2,81.37 150.05,85.22 156.72,85.22 159.64,88.14 159.64,94.04 160.59,95 160.59,98.74 182.12,120.27 209.8,120.27 213.8,124.28 213.8,134.18 216.28,136.65 v1(216.28,137.67)
AURORA_RDY_N: length 2.9
  TOP w0.127: TP19.1 220.78,142.04 J30.32
AURORA_REFCLK_N: length 35.1
  TOP w0.127: R504.2 245.27,132.02 245.45,132.02 R512.2 246.34,132.02 248.15,132.02 v1(248.41,132.27) ; J30.28 223.29,140.44 223.5,140.23 224.41,140.23 v1(224.66,140.48)
  L3SIG w0.102: v1(248.41,132.27) 248.15,132.01 246.7,132.01 246.13,132.58 246.13,135.25 245.01,136.37 235.1,136.37 231.26,140.21 224.93,140.21 v1(224.66,140.48)
AURORA_REFCLK_P: length 35.1
  TOP w0.127: v1(248.41,131.39) 248.16,131.64 246.34,131.64 R503.2 245.45,131.63 245.27,131.63 R511.2 ; J30.26 223.2,139.64 223.41,139.85 224.41,139.85 v1(224.66,139.59)
  L3SIG w0.102: v1(248.41,131.39) 248.15,131.65 246.55,131.65 245.77,132.44 245.77,135.11 244.86,136.02 234.96,136.02 231.11,139.86 224.93,139.86 v1(224.66,139.59)
AURORA_RX_N: length 3.2
  TOP w0.127: C776.2 226.23,122.92 arc(226.34,122.75) 226.38,122.56 226.38,122.52 arc(226.18,122.03) 225.69,121.83 224.94,121.83 224.88,121.89 U18.19
AURORA_RX_P: length 3.8
  TOP w0.127: U18.18 224.88,121.39 224.94,121.45 225.69,121.45 arc(226.44,121.77) 226.76,122.52 226.76,122.56 arc(226.8,122.75) 226.91,122.92 C775.2
AURORA_TCK: length 228.9
  TOP w0.127: v1(74.17,68.9) 73.85,68.9 73.34,68.39 55.88,68.39 41.47,82.8 41.47,88.84 41.97,89.34 U57.R5 ; v1(217.93,129.79) 219.84,129.79 220.32,130.28 R459.1 221.36,130.3 221.9,130.84 J30.4
  L6SIG w0.102: v1(74.17,68.9) 74.3,69.02 112.78,69.02 123.06,79.31 147.58,79.31 151.42,83.16 157.95,83.16 158.16,83.37 158.16,83.37 162.05,87.26 162.05,93.03 163.45,94.43 163.45,97.92 183.01,117.47 211.46,117.47 217.93,123.95 v1(217.93,129.79)
AURORA_TDI: length 228.7
  TOP w0.127: J30.8 220.42,132.44 R457.1 220.32,132.31 219.84,131.83 217.81,131.83 v1(217.55,131.57) ; v1(73.53,69.6) 73.09,69.6 72.39,68.9 55.88,68.9 41.97,82.81 U57.T5
  L6SIG w0.102: v1(217.55,131.57) 217.55,130.56 217.42,130.43 217.42,123.89 211.3,117.77 183.17,117.77 183.11,117.7 182.85,117.7 163.13,97.99 163.13,94.44 161.8,93.1 161.8,87.33 157.86,83.39 151.27,83.39 147.42,79.54 122.85,79.54 112.65,69.34 74.42,69.34 74.17,69.6 v1(73.53,69.6)
AURORA_TDO: length 228.4
  TOP w0.127: v1(216.41,132.33) 217.42,132.33 217.93,132.84 221.23,132.84 221.63,133.24 J30.10 ; v1(72.07,70.8) 71.25,69.98 56.52,69.98 43.5,82.99 43.5,88.92 U57.R7
  L6SIG w0.102: v1(72.07,70.8) 72.26,70.99 74.04,70.99 74.74,70.29 112.46,70.29 122.39,80.23 146.97,80.23 150.82,84.07 157.54,84.07 161.04,87.57 161.04,93.31 162.18,94.45 162.18,98.17 182.69,118.68 210.69,118.68 216.28,124.27 216.28,132.21 v1(216.41,132.33)
AURORA_TMS: length 226.6
  TOP w0.127: U57.T6 42.97,82.95 56.32,69.6 71.69,69.6 v1(72.07,69.98) ; v1(216.79,130.81) 219.84,130.81 220.32,131.29 R458.1 221.49,131.32 221.81,131.64 J30.6
  L6SIG w0.102: v1(216.79,130.81) 216.79,124.27 210.88,118.36 182.75,118.36 162.5,98.11 162.5,94.45 161.29,93.24 161.29,87.47 157.67,83.85 150.97,83.85 147.12,80 122.54,80 112.52,69.98 74.61,69.98 73.91,70.68 72.77,70.68 v1(72.07,69.98)
AURORA_TRST_N: length 231.7
  TOP w0.127: J30.12 221.79,134.04 221.11,133.35 R456.1 220.32,133.38 219.84,133.86 v1(217.42,133.86) ; v1(73.03,70.17) 72.14,69.28 56.07,69.28 42.48,82.87 42.48,88.84 42.97,89.32 U57.R6
  L6SIG w0.102: v1(73.03,70.17) 74.04,70.17 74.55,69.66 112.59,69.66 122.7,79.77 147.27,79.77 151.12,83.62 157.76,83.62 161.54,87.4 161.54,93.17 162.81,94.44 162.81,98.02 182.84,118.05 211.07,118.05 217.11,124.08 217.11,130.49 217.3,130.68 217.3,131.06 217.04,131.32 217.04,131.83 217.42,132.21 v1(217.42,133.86)
AURORA_TX_N: length 15.2
  TOP w0.127: J30.3 227.24,130.84 arc(227.11,130.81) 227.01,130.74 226.99,130.72 arc(226.88,130.65) 226.76,130.63 226.61,130.63 arc(226.31,130.57) 226.05,130.39 226.04,130.39 arc(225.81,129.83) 226.04,129.27 227.11,128.21 arc(228.02,126.84) 228.35,125.22 228.35,122.9 arc(227.74,121.44) 226.28,120.83 224.94,120.83 224.88,120.89 U18.17
AURORA_TX_P: length 15.2
  TOP w0.127: J30.1 227.22,130.04 arc(227.1,130.06) 226.99,130.13 226.97,130.15 arc(226.87,130.22) 226.74,130.25 226.61,130.25 arc(226.45,130.21) 226.32,130.12 226.31,130.12 arc(226.19,129.83) 226.31,129.54 227.38,128.48 arc(228.38,126.98) 228.73,125.22 228.73,122.9 arc(228.01,121.17) 226.28,120.45 224.94,120.45 224.88,120.39 U18.16
BOOT_FLASH_SEL: length 55.8
  TOP w0.127: U57.F15 52.39,98.81 54.48,98.81 56.01,100.33 56.01,119.76 55.37,120.4 55.37,124.33 57.66,126.62 66.68,126.62 68.96,128.91 68.96,130.56 69.85,131.44 74.3,131.44 75.18,130.56 SW3.4 v1(75.18,128.65)
  BOTTOM w0.127: R476.2 v1(75.18,128.65)
CFG_VBANK0: length 57.5
  TOP w0.127: v1(73.91,112.14) U7.2 76.58,112.14 76.84,111.89 76.84,110.74 76.45,110.36 65.28,110.36 59.12,104.2 59.12,99.5 55,95.38 U57.J16 ; SW3.5 v1(76.45,128.65)
  BOTTOM w0.127: R478.2 v1(76.45,128.65) 76.45,122.3 73.79,119.63 73.79,115.44 72.77,114.43 72.77,113.28 v1(73.91,112.14)
CFG_VBANK1: length 50.1
  TOP w0.127: v1(73.28,113.66) 73.28,112.39 73.03,112.14 U6.2 65.02,112.14 58.29,105.41 58.29,104.37 58.29,104.37 58.29,99.82 54.86,96.39 U57.H16 ; SW3.6 v1(77.72,128.65)
  BOTTOM w0.127: R480.2 v1(77.72,128.65) 77.72,122.68 74.17,119.13 74.17,114.55 v1(73.28,113.66)
CFG_VBANK2: length 63.9
  TOP w0.127: U57.J15 52.48,94.87 55.12,94.87 59.56,99.31 59.56,104.01 65.66,110.11 79.5,110.11 80.39,111 80.39,111.89 80.14,112.14 U5.2 78.99,112.14 78.61,112.52 78.61,114.17 77.85,114.94 v1(76.33,114.94) ; SW3.7 v1(78.99,128.65)
  BOTTOM w0.127: R482.2 v1(78.99,128.65) 78.99,123.32 74.68,119 74.68,115.44 75.18,114.94 v1(76.33,114.94)
CK_N: length 5.8
  TOP w0.127: R775.2 85.6,14.17 L22.2 85.9,13.86 85.9,13.25 87.25,11.91 87.25,11.51 87.02,11.27 J12.12
CK_P: length 5.9
  TOP w0.127: R774.2 86.61,14.17 L22.3 86.31,13.86 86.31,13.39 87.63,12.06 87.63,11.51 88.02,11.12 J12.10
CKE_ISO_EN: length 123.8
  TOP w0.127: U57.G3 39.43,97.92 v1(39.43,98.87)
  L6SIG w0.102: v1(39.43,98.87) 38.86,99.44 38.86,100.65 37.97,101.54 37.97,103.89 42.93,108.84 42.93,128.46 44.32,129.86 v1(44.32,137.16)
  BOTTOM w0.127: v1(44.32,137.16) 81.79,137.16 84.58,134.37 97.28,134.37 101.47,138.56 101.47,143.89 110.49,152.91 R684.1
CKSTP_OUT_N: length 119.9
  TOP w0.127: U1.F18 v2(127.17,105.82) ; U57.C9 v1(46.47,101.88)
  L6SIG w0.102: v2(127.17,105.82) 126.32,104.97 124.52,104.97 123.67,104.11 121.06,104.11 119.89,105.28 118.81,105.28 107.44,116.65 107.44,120.9 95.38,132.97 62.23,132.97 58.17,128.91 v1(58.17,128.27) 58.17,125.41 55.63,122.87 55.63,111.7 46.99,103.06 46.99,102.41 v1(46.47,101.88)
  BOTTOM w0.127: v1(58.17,128.27) 57.91,128.52 R111.1
COP_CKSTP_OUT_N: length 36.6
  TOP w0.127: J4.15 9.91,99.57 11.3,98.17 19.88,98.17 20.7,99 20.7,101.09 22.1,102.49 30.1,102.49 35.2,97.39 U57.G1
COP_HRESET_N: length 35.6
  TOP w0.127: U57.G2 38.5,97.85 35.31,97.85 30.16,103 21.97,103 20.45,101.47 19.08,101.47 R123.2 11.18,100.84 9.91,102.11 J4.13
COP_SRESET_N: length 34
  TOP w0.127: U57.F1 35.41,98.39 30.42,103.38 21.34,103.38 20.7,102.74 19.05,102.74 18.44,103.35 R122.2 11.43,103.38 10.16,104.65 J4.11
COP_TCK: length 35.2
  TOP w0.127: U57.E1 35.68,99.39 30.73,104.33 22.67,104.33 18.44,108.56 R120.2 11.18,108.58 10.03,109.73 J4.7
COP_TDI: length 41
  TOP w0.127: U57.E2 38.47,99.89 35.94,99.89 30.99,104.84 24,104.84 21.27,107.57 21.27,112.2 20.57,112.9 19.05,112.9 18.44,113.51 R118.2 11.05,113.54 9.78,114.81 J4.3
COP_TDO: length 42.3
  TOP w0.127: J4.1 9.91,117.35 11.18,116.08 20.19,116.08 22.48,113.79 22.48,108.01 24.7,105.79 31.37,105.79 36.26,100.9 38.42,100.9 38.93,100.39 U57.D2
COP_TMS: length 35.5
  TOP w0.127: U57.F2 38.48,98.87 35.56,98.87 30.54,103.89 20.45,103.89 18.44,105.89 R121.2 11.3,105.92 10.03,107.19 J4.9
COP_TRST_N: length 33.1
  TOP w0.127: U57.D1 36.14,100.39 31.24,105.28 24.32,105.28 21.91,107.7 21.91,113.09 20.83,114.17 19.05,114.17 18.44,114.78 R117.1 J4.4
CPLD_INT1_N: length 91.3
  TOP w0.127: U1.F7 v2(127.17,96.22) ; U57.C15 v1(52.47,101.88)
  L6SIG w0.102: v1(52.47,101.88) 52.47,102.12 52.96,102.62 52.96,104.27 53.47,104.78 59.56,104.78 63.56,108.78 77.03,108.78 77.6,109.35 100.08,109.35 117.03,92.39 120.71,92.39 121.29,91.82 124.21,91.82 125.19,92.8 125.19,93.17 125.41,93.4 125.78,93.4 125.98,93.6 125.98,93.98 126.24,94.23 126.62,94.23 126.75,94.36 126.75,94.46 126.75,94.46 126.75,94.77 126.75,94.78 126.75,95.26 126.75,95.26 126.75,95.57 126.75,95.58 126.75,95.89 127.08,96.22 v2(127.17,96.22)
  BOTTOM w0.127: R78.1 52.48,101.87 v1(52.47,101.88)
CPLD_INT2_N: length 89.2
  TOP w0.127: U1.D3 v2(125.57,93.02) ; U57.D14 v1(51.47,100.88)
  L6SIG w0.102: v2(125.57,93.02) 125.57,92.8 125.16,92.39 125.16,91.73 124.36,90.93 118.49,90.93 117.48,91.95 117.03,91.95 100.01,108.97 77.72,108.97 77.15,108.39 63.69,108.39 59.69,104.39 55.28,104.39 52.96,102.07 52.96,101.41 52.43,100.88 v1(51.47,100.88)
  BOTTOM w0.127: R79.1 52.15,100.2 v1(51.47,100.88)
CPLD_REFCLK: length 14.5
  TOP w0.127: U57.H5 v1(41.47,96.88) ; R492.2 v1(28.58,97.41)
  L3SIG w0.102: v1(28.58,97.41) 29.1,96.88 v1(41.47,96.88)
CPLD_TCK: length 22.5
  TOP w0.127: U57.P3 v1(39.47,89.89) ; R470.2 26.64,83.19 J31.1
  L3SIG w0.102: v1(39.47,89.89) 38.99,89.41 28.19,89.41 26.92,88.14 26.92,84.45 J31.1
CPLD_TDI: length 20.6
  TOP w0.127: R472.2 25.68,93.32 J31.9 ; v1(41.47,92.9) 42.48,92.9 U57.L6
  L3SIG w0.102: v1(41.47,92.9) 40.89,92.33 26.67,92.33 J31.9
CPLD_TDO: length 22.5
  TOP w0.127: U57.M5 v1(41.47,91.89)
  L3SIG w0.102: J31.3 24.51,86.87 24.51,88.77 25.27,89.53 26.42,89.53 27.69,90.81 38.42,90.81 39.05,91.44 41.02,91.44 v1(41.47,91.89)
CPLD_TMS: length 19
  TOP w0.127: R471.2 25.68,88.29 J31.5 ; U57.N4 v1(40.47,90.89)
  L3SIG w0.102: v1(40.47,90.89) 39.94,90.36 27.75,90.36 J31.5
D0_N: length 4.9
  TOP w0.127: J12.9 88.52,11.2 88.77,11.46 88.77,11.81 88.06,12.52 88.06,13.23 L21.2 87.76,13.53 R773.2
D0_P: length 5
  TOP w0.127: R772.2 88.77,13.53 L21.3 88.47,13.23 88.47,12.65 89.15,11.97 89.15,11.53 89.52,11.17 J12.7
D1_N: length 4.7
  TOP w0.127: J12.6 90.02,11.28 90.3,11.56 90.3,12.83 90.07,13.05 L20.2 89.92,13.53 R771.2
D1_P: length 4.7
  TOP w0.127: R770.2 90.93,13.53 L20.3 90.68,13.28 90.68,11.56 91.02,11.22 J12.4
D2_N: length 5
  TOP w0.127: J12.3 91.52,11.25 91.83,11.56 91.83,12.2 92.38,12.75 92.38,13.35 L19.2 92.08,13.66 R769.2
D2_P: length 5
  TOP w0.127: J12.1 92.52,11.24 92.21,11.55 92.21,12.04 92.79,12.62 92.79,13.35 L19.3 93.09,13.66 R768.2
DDR_DQ0: length 105.6
  TOP w0.14: U1.C21 125.15,107.82 124.76,108.2 119.89,108.2 115.32,112.78 115.32,128.4 92.08,151.64 83.2,151.64 83.07,151.5 83.07,150.51 82.93,150.37 82.56,150.37 82.42,150.51 82.42,151.5 82.28,151.64 81.91,151.64 81.77,151.5 81.77,150.51 81.63,150.37 81.26,150.37 81.12,150.51 81.12,151.5 80.98,151.64 80.61,151.64 80.47,151.5 80.47,150.51 80.33,150.37 79.97,150.37 79.83,150.51 79.83,151.5 79.69,151.64 79.32,151.64 79.18,151.5 79.18,150.51 79.04,150.37 78.67,150.37 78.53,150.51 78.53,151.5 78.39,151.64 78.02,151.64 77.88,151.5 77.88,150.51 77.74,150.37 71.69,150.37 64.55,157.51 J1.5
DDR_DQ1: length 105.4
  TOP w0.14: J1.150 65.4,165.42 66.23,164.59 66.23,163.51 65.41,162.69 65.41,157.73 70.68,152.46 72.93,152.46 73.07,152.32 73.07,151.27 73.21,151.13 73.58,151.13 73.72,151.27 73.72,152.32 73.86,152.46 74.23,152.46 74.37,152.32 74.37,151.27 74.51,151.13 74.88,151.13 75.01,151.27 75.01,152.32 75.15,152.46 75.52,152.46 75.66,152.32 75.66,151.27 75.8,151.13 76.17,151.13 76.31,151.27 76.31,152.32 76.45,152.46 92.39,152.46 116.01,128.84 116.01,113.09 120.49,108.62 U1.A22
DDR_DQ2: length 105.3
  TOP w0.14: J1.12 70.5,160.71 71.69,159.51 83.18,159.51 83.32,159.65 83.32,160.52 83.46,160.66 83.82,160.66 83.96,160.52 83.96,159.65 84.1,159.51 84.47,159.51 84.61,159.65 84.61,160.52 84.75,160.66 85.12,160.66 85.26,160.52 85.26,159.65 85.4,159.51 85.77,159.51 85.91,159.65 85.91,160.52 86.05,160.66 86.42,160.66 86.56,160.52 86.56,159.65 86.7,159.51 87.06,159.51 87.2,159.65 87.2,160.52 87.34,160.66 87.71,160.66 87.85,160.52 87.85,159.65 87.99,159.51 88.36,159.51 88.5,159.65 88.5,160.52 88.64,160.66 89.01,160.66 89.15,160.52 89.15,159.65 89.29,159.51 89.65,159.51 89.79,159.65 89.79,160.52 89.93,160.66 90.3,160.66 90.44,160.52 90.44,159.65 90.58,159.51 90.95,159.51 91.09,159.65 91.09,160.52 91.23,160.66 91.6,160.66 91.74,160.52 91.74,159.65 91.88,159.51 93.09,159.51 93.5,159.1 93.7,159.1 94.04,159.44 94.24,159.44 94.5,159.18 94.5,158.98 94.16,158.64 94.16,158.45 94.42,158.18 94.62,158.18 94.96,158.53 95.16,158.53 95.42,158.27 95.42,158.07 95.07,157.73 95.07,157.53 95.33,157.27 95.53,157.27 95.87,157.61 96.07,157.61 96.33,157.35 96.33,157.15 95.99,156.81 95.99,156.61 96.25,156.35 96.45,156.35 96.79,156.69 96.99,156.69 120.21,133.48 120.21,114.36 122.75,111.82 U1.A26
DDR_DQ3: length 105
  TOP w0.14: U1.B26 124.37,111.92 124.08,112.2 123.13,112.2 120.9,114.43 120.9,133.73 93.41,161.23 82.69,161.23 82.56,161.09 82.56,160.22 82.42,160.08 82.05,160.08 81.91,160.22 81.91,161.09 81.77,161.23 81.4,161.23 81.26,161.09 81.26,160.22 81.12,160.08 80.75,160.08 80.61,160.22 80.61,161.09 80.47,161.23 80.1,161.23 79.96,161.09 79.96,160.22 79.82,160.08 79.46,160.08 79.32,160.22 79.32,161.09 79.18,161.23 78.81,161.23 78.67,161.09 78.67,160.22 78.53,160.08 78.16,160.08 78.02,160.22 78.02,161.09 77.88,161.23 77.51,161.23 77.37,161.09 77.37,160.22 77.23,160.08 76.87,160.08 76.73,160.22 76.73,161.09 76.59,161.23 76.22,161.23 76.08,161.09 76.08,160.22 75.94,160.08 75.57,160.08 75.43,160.22 75.43,161.09 75.29,161.23 74.92,161.23 74.78,161.09 74.78,160.22 74.64,160.08 74.27,160.08 74.13,160.22 74.13,161.09 74,161.23 73.63,161.23 73.49,161.09 73.49,160.22 73.35,160.08 72.33,160.08 72.14,160.27 72.14,162.69 71.35,163.47 J1.157
DDR_DQ4: length 105.7
  TOP w0.14: J1.3 62.85,157.18 71.82,148.21 88.3,148.21 88.44,148.35 88.44,149.78 88.58,149.92 88.95,149.92 89.09,149.78 89.09,148.35 89.23,148.21 89.6,148.21 89.74,148.35 89.74,149.78 89.88,149.92 90.25,149.92 90.39,149.78 90.39,148.35 90.53,148.21 90.89,148.21 91.03,148.35 91.03,149.78 91.17,149.92 91.54,149.92 91.68,149.78 91.68,148.35 91.82,148.21 93.28,148.21 114.05,127.44 114.05,112.9 116.08,110.87 116.08,110.11 118.8,107.39 123.95,107.39 124.37,107.81 U1.B21
DDR_DQ5: length 106.7
  TOP w0.14: U1.A21 119.7,107.82 114.68,112.84 114.68,127.89 91.88,150.69 87.01,150.69 86.87,150.55 86.87,149.49 86.73,149.35 86.37,149.35 86.23,149.49 86.23,150.55 86.09,150.69 85.72,150.69 85.58,150.55 85.58,149.49 85.44,149.35 85.07,149.35 84.93,149.49 84.93,150.55 84.79,150.69 84.42,150.69 84.28,150.55 84.28,149.49 84.14,149.35 71.56,149.35 63.69,157.23 63.69,162.69 64.58,163.58 64.58,164.4 63.7,165.28 J1.148
DDR_DQ6: length 105.3
  TOP w0.14: U1.B24 124.37,110.27 124.02,110.62 122.43,110.62 118.94,114.11 118.94,129.73 115.89,132.78 115.89,134.75 115.29,135.35 115.29,135.55 115.63,135.89 115.63,136.09 115.37,136.35 115.17,136.35 114.83,136 114.63,136 114.37,136.26 114.37,136.46 114.71,136.8 114.71,137 114.45,137.26 114.25,137.26 113.91,136.92 113.71,136.92 113.45,137.18 113.45,137.38 113.8,137.72 113.8,137.92 113.54,138.18 113.34,138.18 113,137.84 112.8,137.84 112.54,138.1 112.54,138.29 112.88,138.64 112.88,138.83 112.62,139.1 112.42,139.1 112.08,138.75 111.88,138.75 111.62,139.01 111.62,139.21 111.96,139.55 111.96,139.75 111.7,140.01 111.5,140.01 111.16,139.67 110.96,139.67 110.7,139.93 110.7,140.13 111.05,140.47 111.05,140.67 110.79,140.93 110.59,140.93 110.25,140.59 110.05,140.59 109.79,140.85 109.79,141.04 110.13,141.39 110.13,141.58 109.87,141.84 109.67,141.84 109.33,141.5 109.13,141.5 108.87,141.76 108.87,141.96 109.21,142.3 109.21,142.5 108.95,142.76 108.76,142.76 108.41,142.42 108.22,142.42 107.96,142.68 107.96,142.88 108.3,143.22 108.3,143.42 108.04,143.68 107.84,143.68 107.5,143.34 107.3,143.34 107.04,143.6 107.04,143.79 107.38,144.14 107.38,144.33 107.12,144.59 106.92,144.59 106.58,144.25 106.38,144.25 106.12,144.51 106.12,144.71 106.46,145.05 106.46,145.25 106.2,145.51 106.01,145.51 105.66,145.17 105.47,145.17 105.21,145.43 105.21,145.63 105.55,145.97 105.55,146.17 105.29,146.43 105.09,146.43 104.75,146.08 104.55,146.08 92.84,157.8 70.74,157.8 68.33,160.21 68.33,161.54 68.64,161.86 68.64,163.72 J1.10
DDR_DQ7: length 105.3
  TOP w0.14: J1.155 69.65,163.44 68.96,162.75 68.96,160.85 71.18,158.62 93.03,158.62 96.3,155.35 96.49,155.35 96.93,155.79 97.13,155.79 97.39,155.53 97.39,155.33 96.95,154.9 96.95,154.7 97.21,154.44 97.41,154.44 97.85,154.88 98.05,154.88 98.31,154.61 98.31,154.42 97.87,153.98 97.87,153.78 98.13,153.52 98.33,153.52 98.76,153.96 98.96,153.96 99.22,153.7 99.22,153.5 98.78,153.06 98.78,152.87 99.05,152.6 99.24,152.6 99.68,153.04 99.88,153.04 100.14,152.78 100.14,152.58 99.7,152.15 99.7,151.95 99.96,151.69 100.16,151.69 100.6,152.13 100.79,152.13 101.06,151.87 101.06,151.67 100.62,151.23 100.62,151.03 100.88,150.77 101.08,150.77 101.51,151.21 101.71,151.21 101.97,150.95 101.97,150.75 101.53,150.31 101.53,150.12 101.79,149.86 101.99,149.86 102.43,150.29 102.63,150.29 102.89,150.03 102.89,149.83 102.45,149.4 102.45,149.2 102.71,148.94 102.91,148.94 103.35,149.38 103.54,149.38 103.8,149.12 103.8,148.92 103.37,148.48 103.37,148.28 103.63,148.02 103.83,148.02 104.26,148.46 104.46,148.46 104.72,148.2 104.72,148 104.28,147.56 104.28,147.37 104.54,147.11 104.74,147.11 105.05,147.42 105.25,147.42 116.59,136.08 116.59,132.97 119.57,129.98 119.57,114.24 122.79,111.02 U1.A25
DDR_DQ8: length 93.3
  TOP w0.14: U1.C23 v2(124.77,109.82)
  L3SIG w0.114: v2(124.77,109.82) 124.75,109.82 124.33,110.24 122.87,110.24 119,114.11 119,124.4 111.95,131.44 108.9,131.44 100.96,139.38 100.96,139.54 101.37,139.95 101.37,140.12 101.1,140.39 100.93,140.39 100.52,139.98 100.36,139.98 100.08,140.26 100.08,140.43 100.49,140.84 100.49,141 100.22,141.28 100.05,141.28 99.64,140.87 99.48,140.87 99.2,141.14 99.2,141.31 99.61,141.72 99.61,141.88 99.33,142.16 99.17,142.16 98.76,141.75 98.6,141.75 98.32,142.02 98.32,142.19 98.73,142.6 98.73,142.76 98.45,143.04 98.29,143.04 97.88,142.63 97.72,142.63 97.44,142.9 97.44,143.07 97.85,143.48 97.85,143.64 97.57,143.92 97.41,143.92 97,143.51 96.84,143.51 96.56,143.79 96.56,143.95 96.97,144.36 96.97,144.52 96.69,144.8 96.53,144.8 96.12,144.39 95.96,144.39 95.68,144.67 95.68,144.83 96.09,145.24 96.09,145.4 95.81,145.68 95.65,145.68 95.24,145.27 95.08,145.27 94.04,146.3 84.71,146.3 74.09,156.92 74.09,163.68 J1.16
DDR_DQ9: length 92.6
  TOP w0.14: U1.C24 v2(124.77,110.62)
  L3SIG w0.114: J1.161 74.75,163.5 75.41,162.84 75.41,161.77 74.75,161.11 74.75,157.28 85.09,146.94 95.44,146.94 102.66,139.72 102.66,139.56 102.32,139.21 102.32,139.05 102.59,138.77 102.76,138.77 103.1,139.12 103.26,139.12 103.54,138.84 103.54,138.68 103.2,138.33 103.2,138.17 103.47,137.89 103.64,137.89 103.98,138.24 104.14,138.24 104.42,137.96 104.42,137.8 104.08,137.45 104.08,137.29 104.35,137.01 104.52,137.01 104.86,137.36 105.02,137.36 105.3,137.08 105.3,136.91 104.96,136.57 104.96,136.41 105.24,136.13 105.4,136.13 105.74,136.47 105.9,136.47 106.18,136.2 106.18,136.03 105.84,135.69 105.84,135.53 106.12,135.25 106.28,135.25 106.62,135.59 106.79,135.59 107.06,135.32 107.06,135.15 106.72,134.81 106.72,134.65 107,134.37 107.16,134.37 107.5,134.71 107.67,134.71 110.11,132.27 112.27,132.27 119.76,124.78 119.76,113.92 123.06,110.62 v2(124.77,110.62)
DDR_DQ10: length 92.8
  TOP w0.14: U1.F25 v2(127.17,111.42)
  L3SIG w0.114: v2(127.17,111.42) 126.75,111.83 126.75,112.39 126.37,112.78 126.37,113.66 124.52,115.51 124.52,127.44 100.52,151.45 92.39,151.45 92.13,151.71 92.13,151.88 92.66,152.41 92.66,152.57 92.38,152.85 92.22,152.85 91.69,152.32 91.52,152.32 91.24,152.6 91.24,152.76 91.78,153.29 91.78,153.46 91.5,153.73 91.34,153.73 90.8,153.2 90.64,153.2 90.36,153.48 90.36,153.64 90.9,154.17 90.9,154.34 90.62,154.61 90.46,154.61 89.92,154.08 89.76,154.08 89.48,154.36 89.48,154.52 90.02,155.05 90.02,155.22 89.74,155.49 89.58,155.49 89.04,154.96 88.88,154.96 88.6,155.24 88.6,155.4 89.14,155.93 89.14,156.1 88.86,156.37 88.7,156.37 88.16,155.84 88,155.84 87.72,156.12 87.72,156.28 88.26,156.82 88.26,156.98 87.98,157.26 87.82,157.26 87.28,156.72 87.12,156.72 86.84,157 86.84,157.16 87.38,157.7 87.38,157.86 87.1,158.14 86.94,158.14 86.4,157.6 86.24,157.6 85.96,157.88 85.96,158.04 86.5,158.58 86.5,158.74 86.22,159.02 86.06,159.02 85.52,158.48 85.36,158.48 85.08,158.76 85.08,158.92 85.62,159.46 85.62,159.62 85.34,159.9 85.18,159.9 84.64,159.36 84.48,159.36 84.01,159.83 81.22,159.83 79.85,161.2 J1.23
DDR_DQ11: length 93
  TOP w0.14: U1.F26 v2(127.17,112.22)
  L3SIG w0.114: J1.168 80.7,165.36 81.47,164.59 81.47,163.4 80.7,162.62 80.7,161.43 81.53,160.59 85.66,160.59 94.17,152.08 101.98,152.08 103.36,150.7 103.36,150.54 102.92,150.1 102.92,149.94 103.2,149.66 103.36,149.66 103.8,150.1 103.96,150.1 104.24,149.82 104.24,149.66 103.8,149.22 103.8,149.06 104.08,148.78 104.24,148.78 104.68,149.22 104.85,149.22 105.12,148.94 105.12,148.78 104.68,148.34 104.68,148.17 104.96,147.9 105.12,147.9 105.56,148.34 105.73,148.34 106,148.06 106,147.9 105.56,147.46 105.56,147.29 105.84,147.02 106,147.02 106.44,147.46 106.61,147.46 106.88,147.18 106.88,147.02 106.44,146.58 106.44,146.41 106.72,146.14 106.88,146.14 107.32,146.58 107.49,146.58 107.77,146.3 107.77,146.14 107.32,145.7 107.32,145.53 107.6,145.25 107.76,145.25 108.21,145.7 108.37,145.7 108.65,145.42 108.65,145.26 108.2,144.81 108.2,144.65 108.48,144.37 108.64,144.37 109.09,144.82 109.25,144.82 125.16,128.91 125.16,115.63 126.75,114.05 126.75,112.83 127.17,112.41 v2(127.17,112.22)
DDR_DQ12: length 92.2
  TOP w0.14: U1.D22 v2(125.57,109.02)
  L3SIG w0.114: v2(125.57,109.02) 125.53,109.02 125.1,108.58 123.25,108.58 117.54,114.3 117.54,123.38 111.13,129.79 107.25,129.79 95.93,141.12 95.93,141.28 96.37,141.72 96.37,141.88 96.09,142.16 95.93,142.16 95.49,141.72 95.32,141.72 95.05,142 95.05,142.16 95.49,142.6 95.49,142.76 95.21,143.04 95.05,143.04 94.61,142.6 94.44,142.6 94.17,142.88 94.17,143.04 94.61,143.48 94.61,143.64 94.33,143.92 94.17,143.92 93.73,143.48 93.56,143.48 93.29,143.76 93.29,143.92 93.73,144.36 93.73,144.53 93.45,144.8 93.29,144.8 92.84,144.36 92.68,144.36 92.01,145.03 83.95,145.03 72.2,156.78 J1.14
DDR_DQ13: length 92.7
  TOP w0.14: U1.D23 v2(125.57,109.82)
  L3SIG w0.114: J1.159 73.05,163.43 73.72,162.75 73.72,161.8 73.05,161.12 73.05,156.89 84.26,145.67 93.54,145.67 97.6,141.61 97.6,141.44 97.16,141 97.16,140.84 97.44,140.56 97.6,140.56 98.04,141 98.2,141 98.48,140.73 98.48,140.56 98.04,140.12 98.04,139.96 98.32,139.68 98.48,139.68 98.92,140.12 99.08,140.12 99.36,139.85 99.36,139.68 98.92,139.24 98.92,139.08 99.2,138.8 99.36,138.8 99.8,139.24 99.96,139.24 108.59,130.62 111.57,130.62 118.3,123.89 118.3,114.17 123.06,109.41 125.1,109.41 125.5,109.82 v2(125.57,109.82)
DDR_DQ14: length 92.3
  TOP w0.14: U1.B27 v2(123.97,113.02)
  L3SIG w0.114: J1.21 78.15,160.8 81.52,157.43 81.68,157.43 82.5,158.26 82.66,158.26 82.94,157.98 82.94,157.82 82.12,156.99 82.12,156.83 82.4,156.55 82.56,156.55 83.38,157.38 83.54,157.38 83.82,157.1 83.82,156.94 83,156.11 83,155.95 83.28,155.67 83.44,155.67 84.26,156.5 84.42,156.5 84.7,156.22 84.7,156.06 83.88,155.23 83.88,155.07 84.16,154.79 84.32,154.79 85.14,155.62 85.3,155.62 85.58,155.34 85.58,155.18 84.76,154.35 84.76,154.19 85.04,153.91 85.2,153.91 86.02,154.74 86.18,154.74 86.46,154.46 86.46,154.3 85.64,153.47 85.64,153.31 85.92,153.03 86.08,153.03 86.9,153.85 87.06,153.85 87.34,153.58 87.34,153.41 86.52,152.59 86.52,152.43 86.8,152.15 86.96,152.15 87.78,152.97 87.94,152.97 88.22,152.7 88.22,152.53 87.4,151.71 87.4,151.55 88.77,150.18 98.81,150.18 123.06,125.92 123.06,113.92 v2(123.97,113.02)
DDR_DQ15: length 92.2
  TOP w0.14: U1.E25 v2(126.37,111.42)
  L3SIG w0.114: v2(126.37,111.42) 125.98,111.8 125.98,113.29 123.83,115.44 123.83,126.11 99.12,150.81 91.12,150.81 90.44,151.5 90.44,151.66 90.79,152 90.79,152.17 90.51,152.44 90.35,152.44 90,152.1 89.84,152.1 89.56,152.38 89.56,152.54 89.91,152.88 89.91,153.05 89.63,153.32 89.46,153.32 89.12,152.98 88.96,152.98 88.68,153.26 88.68,153.42 89.02,153.76 89.02,153.93 88.75,154.2 88.58,154.2 88.24,153.86 88.08,153.86 87.8,154.14 87.8,154.3 88.14,154.65 88.14,154.81 87.87,155.09 87.7,155.09 87.36,154.74 87.2,154.74 86.92,155.02 86.92,155.18 87.26,155.53 87.26,155.69 86.99,155.97 86.82,155.97 86.48,155.62 86.32,155.62 86.04,155.9 86.04,156.06 86.38,156.41 86.38,156.57 86.1,156.85 85.94,156.85 85.6,156.5 85.44,156.5 85.16,156.78 85.16,156.94 85.5,157.29 85.5,157.45 85.22,157.73 85.06,157.73 84.72,157.38 84.56,157.38 84.28,157.66 84.28,157.82 84.62,158.17 84.62,158.33 84.34,158.61 84.18,158.61 83.84,158.26 83.67,158.26 82.87,159.07 81.03,159.07 79,161.1 79,162.56 79.82,163.39 79.82,164.53 79,165.35 J1.166
DDR_DQ16: length 90.6
  TOP w0.14: U1.E23 v2(126.37,109.82)
  L6SIG w0.114: v2(126.37,109.82) 125.95,109.4 123.72,109.4 121.73,111.39 121.73,125.29 113.6,133.41 113.6,137.86 112.95,138.51 112.79,138.51 112.22,137.94 112.05,137.94 111.78,138.22 111.78,138.38 112.34,138.95 112.34,139.12 112.07,139.39 111.9,139.39 111.34,138.82 111.17,138.82 110.9,139.1 110.9,139.27 111.46,139.83 111.46,140 111.19,140.27 111.02,140.27 110.46,139.71 110.29,139.71 110.02,139.98 110.02,140.15 110.58,140.71 110.58,140.88 110.31,141.15 110.14,141.15 109.58,140.59 109.41,140.59 109.14,140.86 109.14,141.03 109.7,141.59 109.7,141.76 109.43,142.03 109.26,142.03 108.69,141.47 108.53,141.47 108.25,141.74 108.25,141.91 108.82,142.47 108.82,142.64 108.54,142.92 108.38,142.92 107.81,142.35 107.65,142.35 107.37,142.63 107.37,142.79 107.94,143.36 107.94,143.52 107.66,143.8 107.5,143.8 106.93,143.23 106.77,143.23 106.49,143.51 106.49,143.67 107.06,144.24 107.06,144.4 106.74,144.72 98.17,144.72 83.25,159.64 J1.27
DDR_DQ17: length 90.3
  TOP w0.14: U1.E24 v2(126.37,110.62)
  L6SIG w0.114: v2(126.37,110.62) 126.11,110.62 125.73,111 125.41,111 125.16,111.25 125.16,113.47 123.76,114.87 123.76,125.73 116.65,132.84 116.65,134.75 116.54,134.86 115.11,134.86 115,134.98 115,135.37 115.11,135.49 116.54,135.49 116.65,135.6 116.65,135.99 116.54,136.11 115.11,136.11 115,136.22 115,136.62 115.11,136.73 116.54,136.73 116.65,136.85 116.65,137.24 116.54,137.35 115.11,137.35 115,137.47 115,137.86 115.11,137.98 116.54,137.98 116.65,138.09 116.65,138.43 108.97,146.11 99.19,146.11 85.79,159.51 85.79,162.69 84.96,163.51 84.96,164.42 84.1,165.28 J1.172
DDR_DQ18: length 90
  TOP w0.14: U1.J23 v2(129.57,109.82)
  L6SIG w0.114: J1.34 89.38,163.87 90.71,162.55 90.71,160.82 101.85,149.67 113.73,149.67 122.17,141.22 122.17,140.87 122.06,140.76 121.72,140.76 121.6,140.64 121.6,140.25 121.72,140.13 122.06,140.13 122.17,140.02 122.17,139.62 122.06,139.51 121.72,139.51 121.6,139.4 121.6,139 121.72,138.89 122.06,138.89 122.17,138.77 122.17,138.38 122.06,138.27 121.72,138.27 121.6,138.15 121.6,137.76 121.72,137.64 122.06,137.64 122.17,137.53 122.17,137.14 122.06,137.02 121.72,137.02 121.6,136.91 121.6,136.51 121.72,136.4 122.06,136.4 122.17,136.28 122.17,133.41 128.38,127.21 128.38,126.03 128.26,125.91 127.88,125.91 127.76,125.8 127.76,125.41 127.88,125.29 128.26,125.29 128.38,125.18 128.38,124.78 128.26,124.67 127.88,124.67 127.76,124.55 127.76,124.16 127.88,124.05 128.26,124.05 128.38,123.93 128.38,123.54 128.26,123.42 127.88,123.42 127.76,123.31 127.76,122.92 127.88,122.8 128.26,122.8 128.38,122.69 128.38,122.29 128.26,122.18 127.88,122.18 127.76,122.07 127.76,121.67 127.88,121.56 128.26,121.56 128.38,121.44 128.38,121.05 128.26,120.94 127.88,120.94 127.76,120.82 127.76,120.43 127.88,120.31 128.26,120.31 128.38,120.2 128.38,119.8 128.26,119.69 127.88,119.69 127.76,119.58 127.76,119.18 127.88,119.07 128.26,119.07 128.38,118.95 128.38,118.56 128.26,118.45 127.88,118.45 127.76,118.33 127.76,117.94 127.88,117.82 128.26,117.82 128.38,117.71 128.38,117.32 128.26,117.2 127.88,117.2 127.76,117.09 127.76,116.69 127.88,116.58 128.26,116.58 128.38,116.46 128.38,110.44 128.6,110.23 129.15,110.23 v2(129.57,109.82)
DDR_DQ19: length 89.9
  TOP w0.14: U1.K23 v2(130.37,109.82)
  L6SIG w0.114: J1.179 91.76,164.36 91.76,163.51 92.58,162.69 92.58,161.35 102.62,151.32 114.49,151.32 125.73,140.08 125.73,139.25 125.62,139.13 124.57,139.13 124.46,139.02 124.46,138.62 124.57,138.51 125.62,138.51 125.73,138.39 125.73,137.11 125.62,137 124.51,137 124.4,136.88 124.4,136.49 124.51,136.38 125.62,136.38 125.73,136.26 125.73,135.87 125.62,135.75 124.51,135.75 124.4,135.64 124.4,135.24 124.51,135.13 125.62,135.13 125.73,135.02 125.73,134.62 125.62,134.51 124.51,134.51 124.4,134.39 124.4,134 124.51,133.89 125.62,133.89 125.73,133.77 125.73,132.14 129.98,127.89 129.98,110.2 v2(130.37,109.82)
DDR_DQ20: length 89.5
  TOP w0.14: U1.F22 v2(127.17,109.02)
  L6SIG w0.114: v2(127.17,109.02) 126.92,109.02 126.49,108.58 123.89,108.58 121.16,111.32 121.16,124.84 112.71,133.29 112.71,136.21 111.4,137.52 111.24,137.52 110.8,137.08 110.64,137.08 110.36,137.35 110.36,137.52 110.8,137.96 110.8,138.12 110.52,138.4 110.36,138.4 109.92,137.96 109.76,137.96 109.48,138.23 109.48,138.4 109.92,138.84 109.92,139 109.64,139.28 109.48,139.28 109.04,138.84 108.88,138.84 108.6,139.12 108.6,139.28 109.04,139.72 109.04,139.88 108.76,140.16 108.6,140.16 108.16,139.72 108,139.72 107.72,140 107.72,140.16 108.16,140.6 108.16,140.76 107.88,141.04 107.72,141.04 107.28,140.6 107.12,140.6 106.84,140.88 106.84,141.04 107.28,141.48 107.28,141.64 107,141.92 106.84,141.92 106.4,141.48 106.24,141.48 105.96,141.76 105.96,141.92 106.4,142.36 106.4,142.52 106.12,142.8 105.96,142.8 105.52,142.36 105.36,142.36 105.08,142.64 105.08,142.8 105.52,143.24 105.52,143.4 105.03,143.89 97.85,143.89 81.55,160.2 J1.25
DDR_DQ21: length 90.3
  TOP w0.14: U1.H22 v2(128.77,109.02)
  L6SIG w0.114: v2(128.77,109.02) 128.35,108.6 126.95,108.6 126.24,107.89 123.95,107.89 120.52,111.32 120.52,124.84 111.19,134.17 111.19,134.33 111.7,134.84 111.7,135 111.42,135.28 111.26,135.28 110.75,134.77 110.59,134.77 110.31,135.05 110.31,135.21 110.82,135.72 110.82,135.88 110.54,136.16 110.38,136.16 109.87,135.65 109.71,135.65 102.36,143 97.54,143 80.77,159.77 80.77,162.75 81.53,163.51 81.53,164.72 82.4,165.58 J1.170
DDR_DQ22: length 89.7
  TOP w0.14: U1.H23 v2(128.77,109.82)
  L6SIG w0.114: v2(128.77,109.82) 128.36,109.41 127.76,109.41 127.55,109.62 127.55,109.98 127.3,110.23 126.98,110.23 126.77,110.44 126.77,110.81 126.55,111.03 126.21,111.03 125.98,111.26 125.98,113.67 124.52,115.13 124.52,125.98 118.49,132.02 118.49,137.6 117.98,138.11 116.62,139.47 116.62,139.63 117.03,140.04 117.03,140.2 116.76,140.48 116.59,140.48 116.18,140.07 116.02,140.07 115.74,140.35 115.74,140.51 116.15,140.92 116.15,141.08 115.88,141.36 115.71,141.36 115.3,140.95 115.14,140.95 114.86,141.23 114.86,141.39 115.27,141.8 115.27,141.97 114.99,142.24 114.83,142.24 114.42,141.83 114.26,141.83 113.98,142.11 113.98,142.27 114.39,142.68 114.39,142.85 114.11,143.12 113.95,143.12 113.54,142.71 113.38,142.71 113.1,142.99 113.1,143.15 113.51,143.56 113.51,143.73 113.23,144 113.07,144 112.66,143.59 112.5,143.59 112.22,143.87 112.22,144.03 112.63,144.44 112.63,144.61 112.35,144.88 112.19,144.88 111.78,144.47 111.62,144.47 111.34,144.75 111.34,144.92 111.75,145.33 111.75,145.49 111.47,145.77 111.31,145.77 110.9,145.36 110.74,145.36 110.46,145.63 110.46,145.8 110.87,146.21 110.87,146.37 110.59,146.65 110.43,146.65 110.02,146.24 109.86,146.24 109.16,146.94 99.57,146.94 87.5,159.01 J1.32
DDR_DQ23: length 89.4
  TOP w0.14: U1.J24 v2(129.57,110.62)
  L6SIG w0.114: J1.177 90.04,164.38 90.04,163.7 91.06,162.69 91.06,161.67 102.24,150.5 113.98,150.5 123.83,140.65 123.83,140.28 123.71,140.17 122.86,140.17 122.75,140.05 122.75,139.66 122.86,139.55 123.71,139.55 123.83,139.43 123.83,139.04 123.71,138.92 122.86,138.92 122.75,138.81 122.75,138.42 122.86,138.3 123.71,138.3 123.83,138.19 123.83,137.79 123.71,137.68 122.86,137.68 122.75,137.56 122.75,137.17 122.86,137.06 123.71,137.06 123.83,136.94 123.83,136.55 123.71,136.43 122.86,136.43 122.75,136.32 122.75,135.93 122.86,135.81 123.71,135.81 123.83,135.7 123.83,135.3 123.71,135.19 122.86,135.19 122.75,135.08 122.75,134.68 122.86,134.57 123.71,134.57 123.83,134.45 123.83,132.84 129.16,127.51 129.16,111.02 v2(129.57,110.62)
DDR_DQ24: length 88.8
  TOP w0.14: U1.H26 v2(128.77,112.22)
  L3SIG w0.114: v2(128.77,112.22) 128.77,112.41 128.33,112.84 128.33,116.2 127.83,116.71 127.83,131.76 125.48,134.11 125.48,138.05 122.12,141.41 121.96,141.41 121.45,140.9 121.29,140.9 121.01,141.18 121.01,141.34 121.52,141.85 121.52,142.01 121.24,142.29 121.08,142.29 120.57,141.78 120.41,141.78 120.13,142.06 120.13,142.22 120.64,142.73 120.64,142.89 120.36,143.17 120.19,143.17 119.69,142.66 119.53,142.66 119.25,142.94 119.25,143.1 119.75,143.61 119.75,143.77 119.48,144.05 119.31,144.05 118.81,143.54 118.65,143.54 118.37,143.82 118.37,143.98 118.87,144.49 118.87,144.65 118.6,144.93 118.43,144.93 117.93,144.42 117.77,144.42 117.49,144.7 117.49,144.86 117.99,145.37 117.99,145.53 117.72,145.81 117.55,145.81 117.05,145.3 116.89,145.3 116.61,145.58 116.61,145.74 117.11,146.25 117.11,146.41 116.83,146.69 116.67,146.69 116.17,146.18 116.01,146.18 115.73,146.46 115.73,146.63 116.23,147.13 116.23,147.29 115.95,147.57 115.79,147.57 115.29,147.07 115.13,147.07 114.85,147.34 114.85,147.51 115.35,148.01 115.35,148.17 115.07,148.45 114.91,148.45 114.41,147.95 114.25,147.95 113.97,148.22 113.97,148.39 114.47,148.89 114.47,149.05 109.47,154.05 97.41,154.05 92.77,158.69 92.77,163.7 J1.38
DDR_DQ25: length 88.2
  TOP w0.14: U1.J25 v2(129.57,111.42)
  L3SIG w0.114: J1.183 93.45,163.35 94.11,162.69 94.11,161.86 93.79,161.54 93.79,159.38 98.43,154.75 113.47,154.75 115.7,152.53 115.7,150.5 116.29,149.91 116.45,149.91 117.18,150.63 117.34,150.63 117.62,150.35 117.62,150.19 116.89,149.47 116.89,149.3 117.17,149.03 117.33,149.03 118.06,149.75 118.22,149.75 118.5,149.47 118.5,149.31 117.77,148.59 117.77,148.42 118.05,148.15 118.21,148.15 118.94,148.87 119.1,148.87 119.38,148.59 119.38,148.43 118.65,147.71 118.65,147.54 118.93,147.26 119.09,147.26 119.82,147.99 119.98,147.99 120.26,147.71 120.26,147.55 119.53,146.82 119.53,146.66 126.62,139.57 126.62,135.57 128.59,133.6 128.59,116.9 129.16,116.33 129.16,111.82 v2(129.57,111.42)
DDR_DQ26: length 88.9
  TOP w0.14: U1.P26 v2(133.57,112.22)
  L3SIG w0.114: J1.45 98.55,161.61 100.14,160.02 119.25,160.02 133.29,145.99 133.29,130.02 133.4,129.9 134.19,129.9 134.3,129.79 134.3,129.4 134.19,129.28 133.4,129.28 133.29,129.17 133.29,128.77 133.4,128.66 134.19,128.66 134.3,128.55 134.3,128.15 134.19,128.04 133.4,128.04 133.29,127.92 133.29,127.53 133.4,127.42 134.19,127.42 134.3,127.3 134.3,126.91 134.19,126.79 133.4,126.79 133.29,126.68 133.29,126.29 133.4,126.17 134.19,126.17 134.3,126.06 134.3,125.66 134.19,125.55 133.4,125.55 133.29,125.43 133.29,125.04 133.4,124.93 134.19,124.93 134.3,124.81 134.3,124.42 134.19,124.3 133.4,124.3 133.29,124.19 133.29,123.8 133.4,123.68 134.19,123.68 134.3,123.57 134.3,123.17 134.19,123.06 133.4,123.06 133.29,122.95 133.29,122.55 133.4,122.44 134.19,122.44 134.3,122.32 134.3,121.93 134.19,121.81 133.4,121.81 133.29,121.7 133.29,114.49 133.1,114.3 133.1,112.59 133.47,112.22 v2(133.57,112.22)
DDR_DQ27: length 89
  TOP w0.14: U1.N25 v2(132.77,111.42)
  L3SIG w0.114: J1.190 99.4,165.21 100.2,164.4 100.2,163.51 99.42,162.73 99.42,161.82 100.39,160.85 119.76,160.85 134.94,145.67 134.94,121.37 134.82,121.25 134.23,121.25 134.11,121.14 134.11,120.74 134.23,120.63 134.82,120.63 134.94,120.51 134.94,120.12 134.82,120.01 134.23,120.01 134.11,119.89 134.11,119.5 134.23,119.38 134.82,119.38 134.94,119.27 134.94,118.88 134.82,118.76 134.23,118.76 134.11,118.65 134.11,118.25 134.23,118.14 134.82,118.14 134.94,118.02 134.94,117.6 133.99,116.65 133.99,112.01 133.79,111.82 133.16,111.82 132.77,111.43 v2(132.77,111.42)
DDR_DQ28: length 88.7
  TOP w0.14: U1.G25 v2(127.97,111.42)
  L3SIG w0.114: v2(127.97,111.42) 127.97,111.43 127.57,111.82 127.57,114.17 126.3,115.44 126.3,129.92 120.65,135.57 120.65,136.14 114.92,141.87 114.92,142.03 115.4,142.51 115.4,142.67 115.12,142.95 114.96,142.95 114.48,142.47 114.32,142.47 114.04,142.75 114.04,142.91 114.51,143.39 114.51,143.55 114.24,143.83 114.07,143.83 113.6,143.35 113.44,143.35 113.16,143.63 113.16,143.79 113.63,144.27 113.63,144.43 113.36,144.71 113.19,144.71 112.72,144.23 112.56,144.23 111.05,145.74 111.05,145.91 111.62,146.47 111.62,146.64 111.34,146.91 111.18,146.91 110.61,146.35 110.45,146.35 110.17,146.62 110.17,146.79 110.74,147.35 110.74,147.52 110.46,147.79 110.3,147.79 109.73,147.23 109.57,147.23 109.29,147.5 109.29,147.67 109.86,148.23 109.86,148.4 109.58,148.67 109.42,148.67 108.85,148.11 108.69,148.11 108.41,148.38 108.41,148.55 108.98,149.12 108.98,149.28 108.7,149.56 108.54,149.56 107.97,148.99 107.81,148.99 107.53,149.27 107.53,149.43 108.1,150 108.1,150.16 107.82,150.44 107.66,150.44 107.09,149.87 106.93,149.87 106.65,150.15 106.65,150.31 107.22,150.88 107.22,151.04 106.94,151.32 106.78,151.32 106.21,150.75 106.05,150.75 104.01,152.78 95.57,152.78 90.9,157.45 J1.36
DDR_DQ29: length 88.3
  TOP w0.14: U1.H25 v2(128.77,111.42)
  L3SIG w0.114: J1.181 91.75,163.39 92.46,162.69 92.46,161.93 91.75,161.22 91.75,158.12 96.46,153.42 106.3,153.42 107.23,152.49 107.39,152.49 108.08,153.18 108.25,153.18 108.53,152.9 108.53,152.74 107.83,152.05 107.83,151.89 108.11,151.61 108.27,151.61 108.97,152.3 109.13,152.3 109.41,152.02 109.41,151.86 108.71,151.17 108.71,151.01 108.99,150.73 109.15,150.73 109.85,151.42 110.01,151.42 110.29,151.14 110.29,150.98 109.59,150.29 109.59,150.12 109.87,149.85 110.03,149.85 110.73,150.54 110.89,150.54 111.17,150.26 111.17,150.1 110.47,149.41 110.47,149.24 110.75,148.97 110.91,148.97 111.61,149.66 111.77,149.66 112.05,149.38 112.05,149.22 111.35,148.53 111.35,148.36 114.17,145.54 115.19,145.54 124.4,136.33 124.4,133.92 127,131.32 127,116.65 127.95,115.7 127.95,112.78 128.38,112.35 128.38,111.8 v2(128.77,111.42)
DDR_DQ30: length 88.5
  TOP w0.14: U1.M26 v2(131.97,112.22)
  L3SIG w0.114: J1.43 96.85,160.9 99.76,157.99 117.6,157.99 118.83,156.76 118.99,156.76 119.34,157.11 119.5,157.11 119.78,156.83 119.78,156.67 119.43,156.32 119.43,156.16 119.71,155.88 119.87,155.88 120.22,156.23 120.38,156.23 120.66,155.95 120.66,155.79 120.31,155.44 120.31,155.28 120.59,155 120.75,155 121.1,155.35 121.26,155.35 121.54,155.07 121.54,154.91 121.19,154.56 121.19,154.4 121.47,154.12 121.63,154.12 121.98,154.47 122.14,154.47 122.42,154.19 122.42,154.03 122.07,153.68 122.07,153.52 122.35,153.24 122.51,153.24 122.86,153.59 123.02,153.59 123.3,153.31 123.3,153.15 122.95,152.8 122.95,152.64 123.23,152.36 123.39,152.36 123.74,152.71 123.9,152.71 124.18,152.43 124.18,152.27 123.83,151.92 123.83,151.76 124.11,151.48 124.27,151.48 124.62,151.83 124.78,151.83 125.06,151.55 125.06,151.39 124.71,151.04 124.71,150.88 124.99,150.6 125.15,150.6 125.5,150.95 125.66,150.95 125.94,150.67 125.94,150.51 125.59,150.16 125.59,150 125.87,149.72 126.03,149.72 126.38,150.07 126.54,150.07 126.82,149.79 126.82,149.63 126.47,149.28 126.47,149.12 126.75,148.84 126.91,148.84 127.26,149.19 127.42,149.19 127.7,148.91 127.7,148.75 127.35,148.4 127.35,148.24 127.63,147.96 127.79,147.96 128.14,148.31 128.3,148.31 128.58,148.03 128.58,147.86 128.23,147.52 128.23,147.36 131.57,144.02 131.57,112.84 131.97,112.45 v2(131.97,112.22)
DDR_DQ31: length 88
  TOP w0.14: U1.M25 v2(131.97,111.42)
  L3SIG w0.114: J1.188 97.7,165.32 98.49,164.53 98.49,163.45 97.66,162.62 97.66,161.35 100.39,158.62 101.24,158.62 101.35,158.74 101.35,159.27 101.47,159.38 101.86,159.38 101.97,159.27 101.97,158.74 102.09,158.62 102.48,158.62 102.6,158.74 102.6,159.27 102.71,159.38 103.11,159.38 103.22,159.27 103.22,158.74 103.33,158.62 103.73,158.62 103.84,158.74 103.84,159.27 103.96,159.38 104.35,159.38 104.46,159.27 104.46,158.74 104.58,158.62 104.97,158.62 105.09,158.74 105.09,159.27 105.2,159.38 105.59,159.38 105.71,159.27 105.71,158.74 105.82,158.62 119.13,158.62 132.35,145.4 132.35,113.18 132.35,113.18 132.35,111.8 v2(131.97,111.42)
DDR_DQ32: length 71.2
  TOP w0.14: U1.T25 v2(135.97,111.42)
  L3SIG w0.114: J1.97 147.85,161.18 146.05,159.38 146.05,145.61 145.71,145.26 145.54,145.26 145.04,145.77 144.88,145.77 144.6,145.49 144.6,145.33 145.1,144.82 145.1,144.66 144.83,144.38 144.66,144.38 144.16,144.89 144,144.89 143.72,144.61 143.72,144.45 144.22,143.94 144.22,143.78 143.94,143.5 143.78,143.5 143.28,144.01 143.12,144.01 142.84,143.73 142.84,143.57 143.34,143.06 143.34,142.9 143.06,142.62 142.9,142.62 142.4,143.12 142.24,143.12 141.96,142.85 141.96,142.68 142.46,142.18 142.46,142.02 142.18,141.74 142.02,141.74 141.52,142.24 141.36,142.24 141.08,141.97 141.08,141.8 141.58,141.3 141.58,141.14 141.3,140.86 141.14,140.86 140.64,141.36 140.48,141.36 140.2,141.09 140.2,140.92 140.7,140.42 140.7,140.26 140.42,139.98 140.26,139.98 139.76,140.48 139.6,140.48 139.32,140.21 139.32,140.04 139.82,139.54 139.82,139.38 139.54,139.1 139.38,139.1 138.88,139.6 138.71,139.6 138.44,139.32 138.44,139.16 138.94,138.66 138.94,138.5 138.66,138.22 138.5,138.22 138,138.72 137.83,138.72 137.56,138.44 137.56,138.28 138.06,137.78 138.06,137.62 137.1,136.65 137.1,116.71 135.55,115.17 135.55,111.83 v2(135.97,111.42)
DDR_DQ33: length 71
  TOP w0.14: U1.U25 v2(136.77,111.42)
  L3SIG w0.114: v2(136.77,111.42) 136.38,111.8 136.38,112.35 135.95,112.78 135.95,114.3 137.8,116.14 137.8,136.4 146.62,145.22 146.62,147.73 146.74,147.84 147.08,147.84 147.19,147.96 147.19,148.35 147.08,148.47 146.74,148.47 146.62,148.58 146.62,148.97 146.74,149.09 147.08,149.09 147.19,149.2 147.19,149.6 147.08,149.71 146.74,149.71 146.62,149.82 146.62,150.22 146.74,150.33 147.08,150.33 147.19,150.45 147.19,150.84 147.08,150.96 146.74,150.96 146.62,151.07 146.62,151.46 146.74,151.58 147.08,151.58 147.19,151.69 147.19,152.09 147.08,152.2 146.74,152.2 146.62,152.31 146.62,152.71 146.74,152.82 147.08,152.82 147.19,152.94 147.19,153.33 147.08,153.44 146.74,153.44 146.62,153.56 146.62,153.95 146.74,154.07 147.08,154.07 147.19,154.18 147.19,154.57 147.08,154.69 146.74,154.69 146.62,154.8 146.62,155.2 146.74,155.31 147.08,155.31 147.19,155.43 147.19,155.82 147.08,155.93 146.74,155.93 146.62,156.05 146.62,156.44 146.74,156.56 147.08,156.56 147.19,156.67 147.19,157.06 147.08,157.18 146.74,157.18 146.62,157.29 146.62,157.69 146.74,157.8 147.08,157.8 147.19,157.91 147.19,158.31 147.08,158.42 146.74,158.42 146.62,158.54 146.62,158.94 148.72,161.04 148.72,162.75 149.54,163.58 149.54,164.47 148.7,165.31 J1.242
DDR_DQ34: length 71.4
  TOP w0.14: U1.AA26 v2(139.97,112.22)
  L3SIG w0.114: v2(139.97,112.22) 139.97,112.45 139.58,112.83 139.58,113.18 141.8,115.39 141.8,121.98 145.48,125.67 145.48,136.33 153.42,144.27 153.42,150.73 153.58,150.89 154.44,150.89 154.56,151.01 154.56,151.4 154.44,151.51 153.47,151.51 153.35,151.63 153.35,152.02 153.47,152.14 154.44,152.14 154.56,152.25 154.56,153.53 154.44,153.64 153.47,153.64 153.35,153.75 153.35,154.15 153.47,154.26 154.44,154.26 154.56,154.38 154.56,154.77 154.44,154.88 153.47,154.88 153.35,155 153.35,155.39 153.47,155.51 154.44,155.51 154.56,155.62 154.56,156.02 154.44,156.13 153.47,156.13 153.35,156.24 153.35,156.64 153.47,156.75 154.44,156.75 154.56,156.87 154.56,157.26 154.44,157.37 153.47,157.37 153.35,157.49 153.35,157.88 153.47,158 154.44,158 154.56,158.11 154.56,159.66 154.44,159.77 153.91,159.77 153.8,159.89 153.8,160.28 153.91,160.39 154.44,160.39 154.56,160.51 154.56,160.91 153.8,161.67 J1.104
DDR_DQ35: length 71.3
  TOP w0.14: U1.AA25 v2(139.97,111.42)
  L3SIG w0.114: J1.249 154.65,163.55 155.51,162.69 155.51,150.25 155.4,150.14 154.67,150.14 154.56,150.02 154.56,149.63 154.67,149.52 155.4,149.52 155.51,149.4 155.51,149.01 155.4,148.89 154.23,148.89 154.11,148.78 154.11,148.39 154.23,148.27 155.4,148.27 155.51,148.16 155.51,147.76 155.4,147.65 154.23,147.65 154.11,147.54 154.11,147.14 154.23,147.03 155.4,147.03 155.51,146.91 155.51,146.52 155.4,146.41 154.23,146.41 154.11,146.29 154.11,145.9 154.23,145.78 155.4,145.78 155.51,145.67 155.51,144.91 149.23,138.62 149.23,137.29 146.24,134.3 146.24,125.48 142.49,121.73 142.49,115.32 140.38,113.2 140.38,111.8 139.99,111.42 v2(139.97,111.42)
DDR_DQ36: length 71.3
  TOP w0.14: U1.P25 v2(133.57,111.42)
  L3SIG w0.114: J1.95 144.24,160.37 144.24,159.42 144.13,159.3 143.62,159.3 143.51,159.19 143.51,158.79 143.62,158.68 144.13,158.68 144.24,158.57 144.24,158.17 144.13,158.06 143.62,158.06 143.51,157.94 143.51,157.55 143.62,157.44 144.13,157.44 144.24,157.32 144.24,156.93 144.13,156.81 143.62,156.81 143.51,156.7 143.51,156.31 143.62,156.19 144.13,156.19 144.24,156.08 144.24,155.68 144.13,155.57 143.62,155.57 143.51,155.45 143.51,155.06 143.62,154.95 144.13,154.95 144.24,154.83 144.24,154.44 144.13,154.32 143.62,154.32 143.51,154.21 143.51,153.82 143.62,153.7 144.13,153.7 144.24,153.59 144.24,153.19 144.13,153.08 143.62,153.08 143.51,152.97 143.51,152.57 143.62,152.46 144.13,152.46 144.24,152.34 144.24,151.95 144.13,151.84 143.62,151.84 143.51,151.72 143.51,151.33 143.62,151.21 144.13,151.21 144.24,151.1 144.24,150.7 144.13,150.59 143.62,150.59 143.51,150.48 143.51,150.08 143.62,149.97 144.13,149.97 144.24,149.85 144.24,149.46 144.13,149.35 143.62,149.35 143.51,149.23 143.51,148.84 143.62,148.72 144.13,148.72 144.24,148.61 144.24,148.05 143.62,147.43 143.46,147.43 143.08,147.81 142.92,147.81 142.64,147.53 142.64,147.37 143.02,146.99 143.02,146.83 142.74,146.55 142.58,146.55 142.2,146.93 142.04,146.93 141.76,146.65 141.76,146.49 142.14,146.11 142.14,145.95 141.86,145.67 141.7,145.67 141.32,146.05 141.16,146.05 140.88,145.77 140.88,145.61 141.26,145.23 141.26,145.07 135.7,139.51 135.7,117.16 134.37,115.82 134.37,111.89 133.89,111.42 v2(133.57,111.42)
DDR_DQ37: length 70.9
  TOP w0.14: U1.R25 v2(135.17,111.42)
  L3SIG w0.114: J1.240 147,165.35 146.18,164.53 146.18,163.51 146.94,162.75 146.94,161.42 145.16,159.64 145.16,147 144.23,146.07 144.06,146.07 143.72,146.41 143.56,146.41 143.28,146.14 143.28,145.97 143.62,145.63 143.62,145.47 143.35,145.19 143.18,145.19 142.84,145.53 142.68,145.53 142.4,145.26 142.4,145.09 142.74,144.75 142.74,144.59 142.47,144.31 142.3,144.31 141.96,144.65 141.8,144.65 141.52,144.38 141.52,144.21 141.86,143.87 141.86,143.71 141.59,143.43 141.42,143.43 141.08,143.77 140.92,143.77 140.64,143.49 140.64,143.33 140.98,142.99 140.98,142.83 140.71,142.55 140.54,142.55 140.2,142.89 140.04,142.89 139.76,142.61 139.76,142.45 140.1,142.11 140.1,141.94 139.82,141.67 139.66,141.67 139.32,142.01 139.16,142.01 138.88,141.73 138.88,141.57 139.22,141.23 139.22,141.06 138.94,140.79 138.78,140.79 138.44,141.13 138.27,141.13 138,140.85 138,140.69 138.34,140.35 138.34,140.18 136.4,138.24 136.4,116.97 134.78,115.35 134.78,111.8 v2(135.17,111.42)
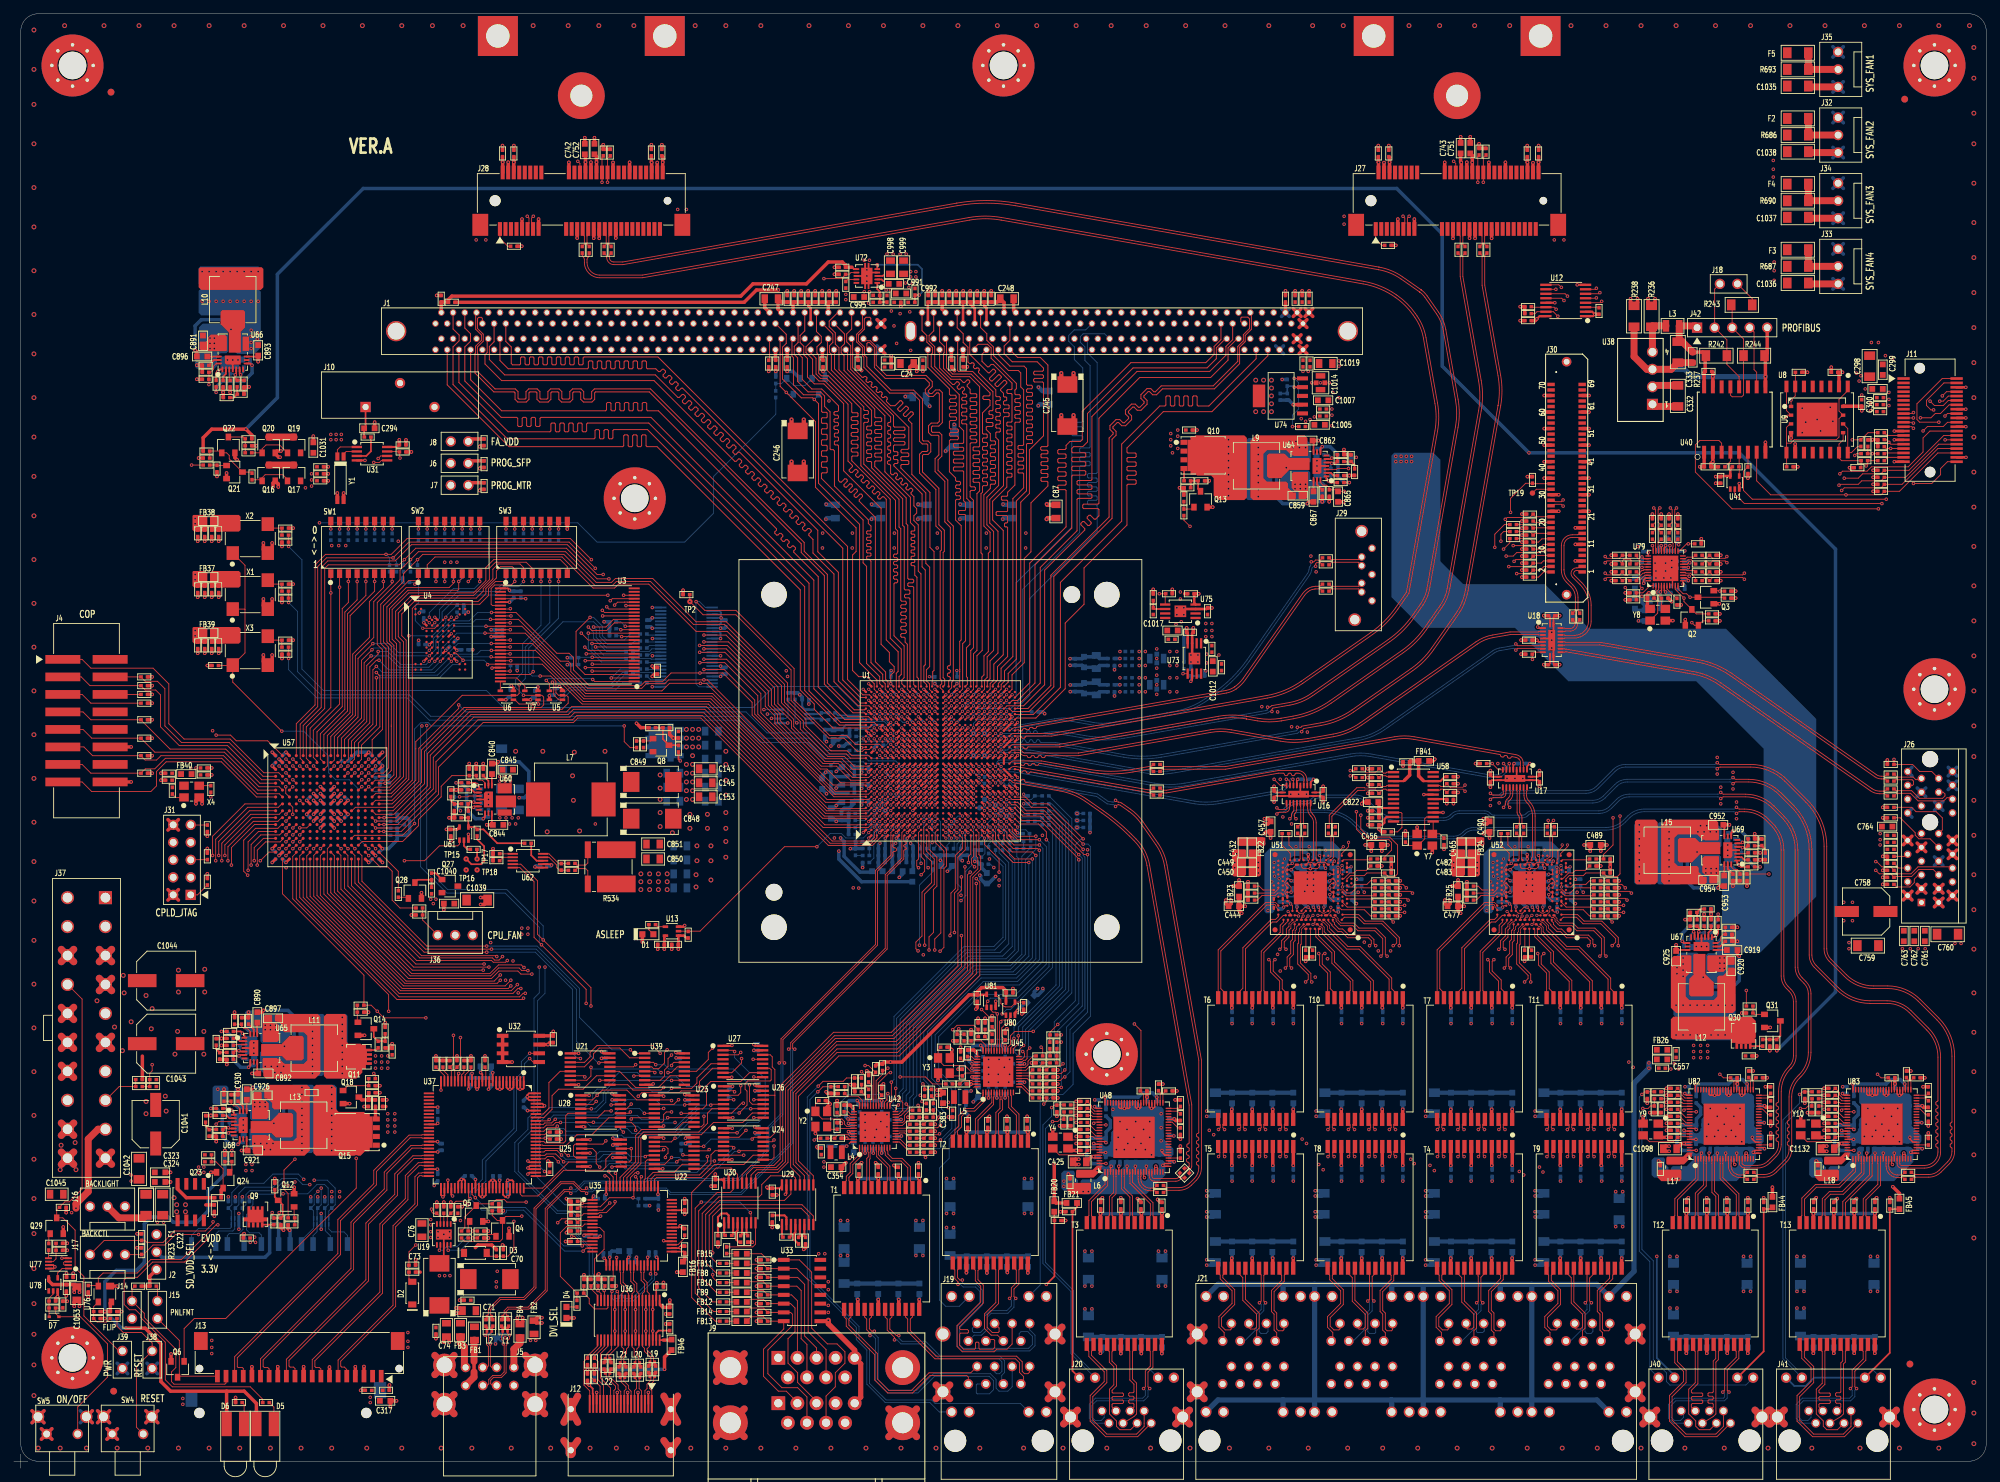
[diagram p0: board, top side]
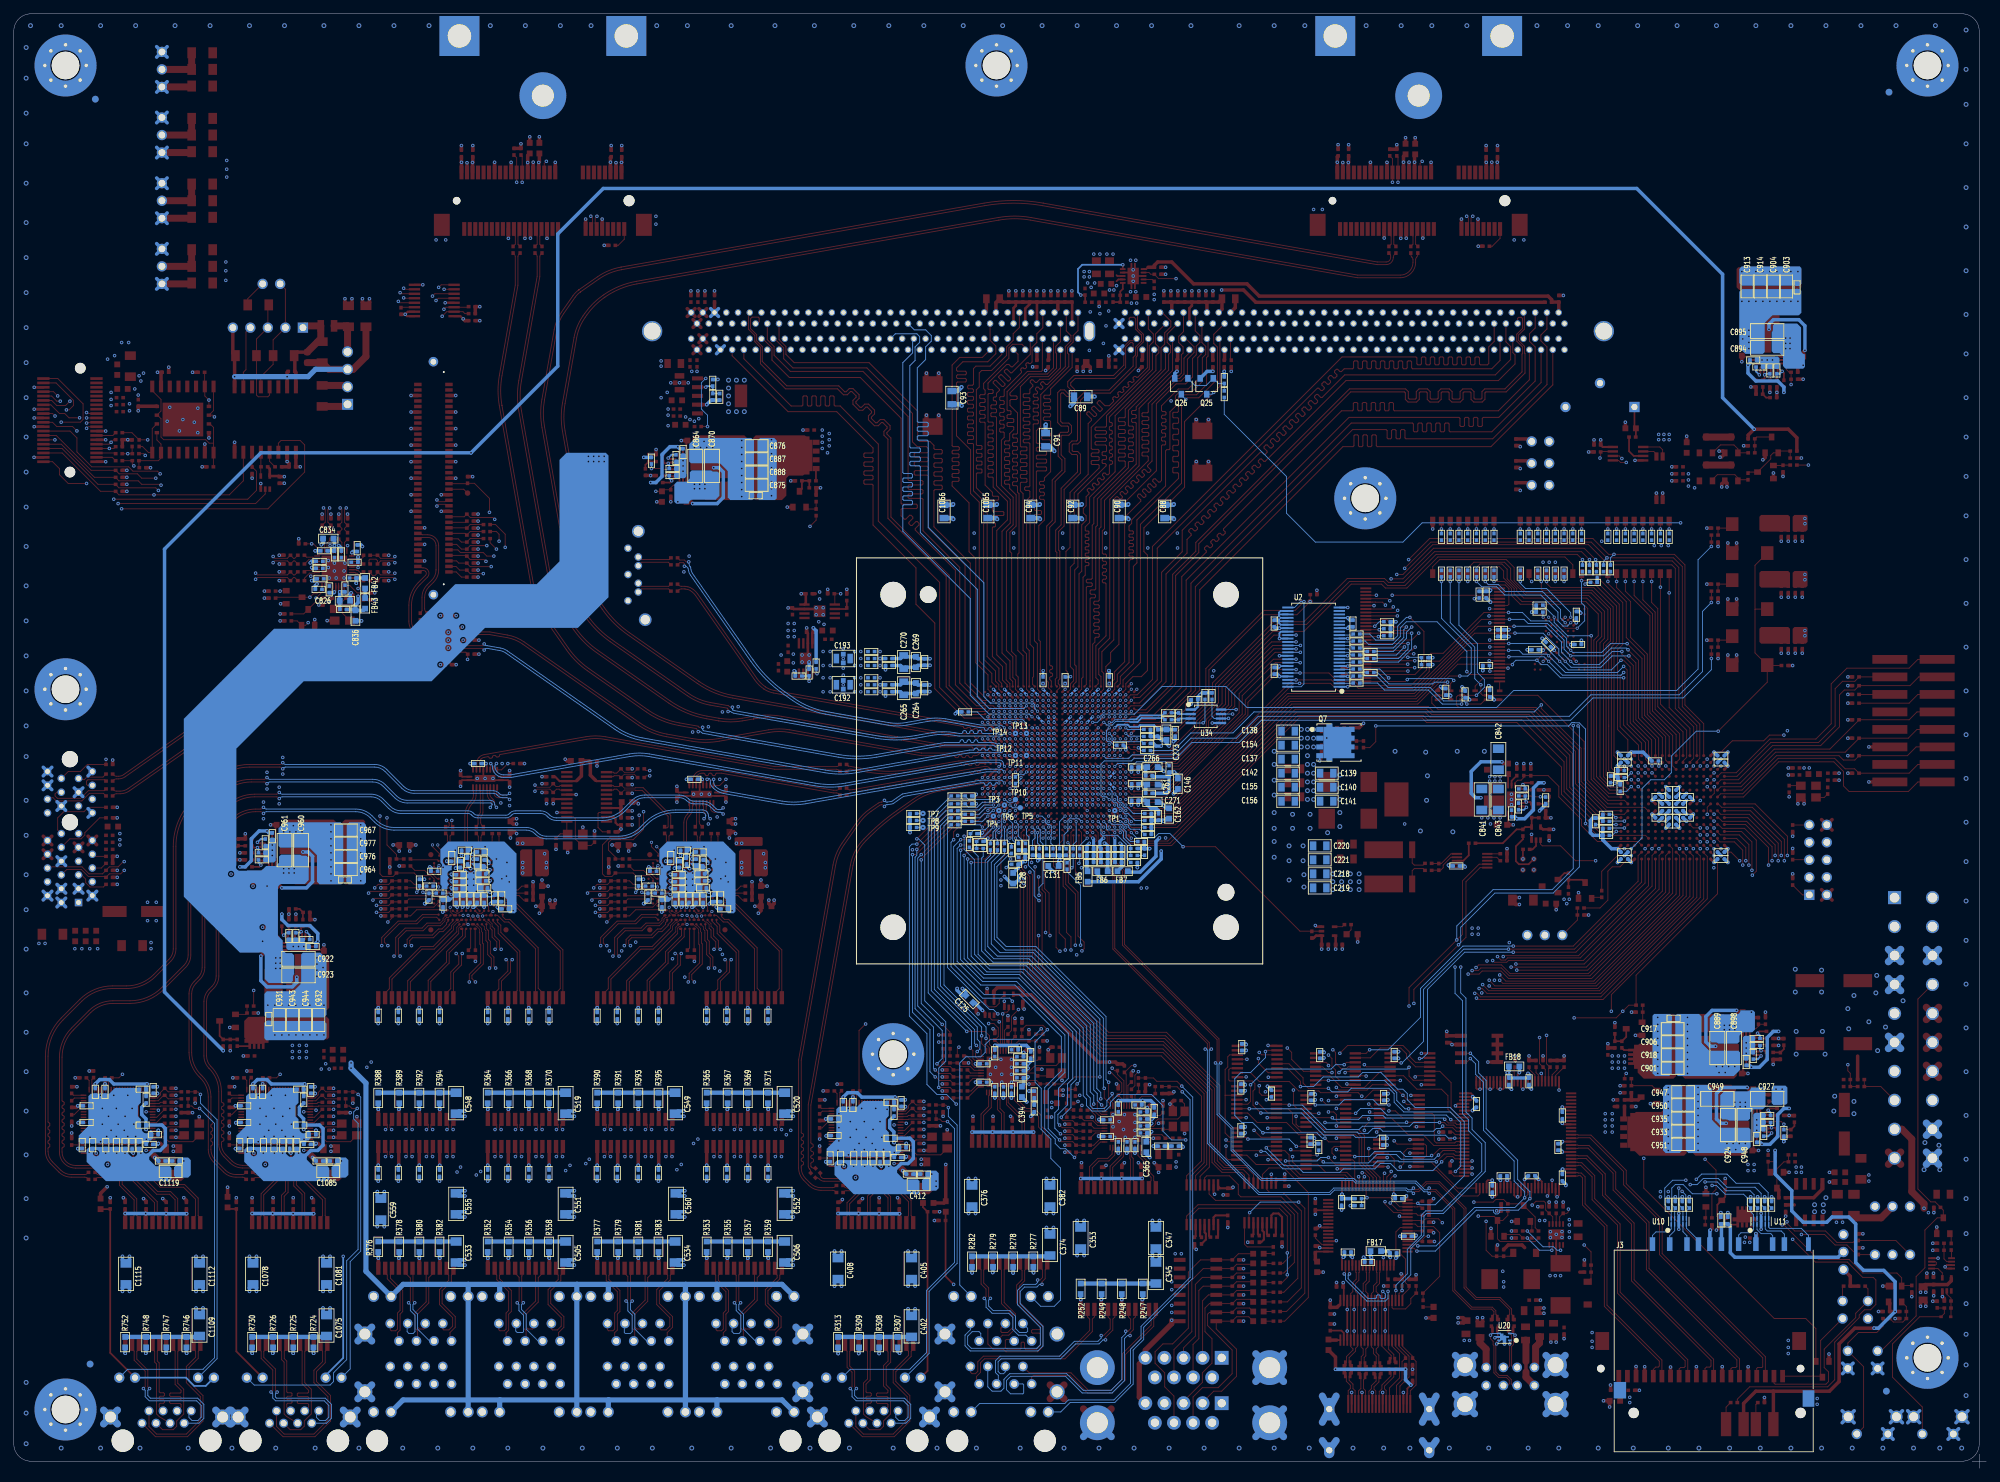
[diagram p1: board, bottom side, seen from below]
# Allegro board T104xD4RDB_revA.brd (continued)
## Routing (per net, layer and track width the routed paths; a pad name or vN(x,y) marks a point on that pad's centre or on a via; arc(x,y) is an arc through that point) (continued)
DDR_DQ38: length 70.8
  TOP w0.14: U1.W26 v2(138.37,112.22)
  L3SIG w0.114: J1.102 151.91,163.68 151.91,161.75 151.32,161.16 151.32,155.49 151.43,155.38 151.65,155.38 151.77,155.26 151.77,154.87 151.65,154.76 151.43,154.76 151.32,154.64 151.32,154.25 151.43,154.13 152.16,154.13 152.27,154.02 152.27,153.63 152.16,153.51 151.43,153.51 151.32,153.4 151.32,151.98 151.43,151.87 152.22,151.87 152.34,151.76 152.34,151.36 152.22,151.25 151.43,151.25 151.32,151.13 151.32,150.74 151.43,150.63 152.22,150.63 152.34,150.51 152.34,150.12 152.22,150 151.43,150 151.32,149.89 151.32,149.5 151.43,149.38 152.22,149.38 152.34,149.27 152.34,148.87 152.22,148.76 151.43,148.76 151.32,148.64 151.32,148.25 151.43,148.14 152.22,148.14 152.34,148.02 152.34,147.63 152.22,147.51 151.43,147.51 151.32,147.4 151.32,147.01 151.43,146.89 152.22,146.89 152.34,146.78 152.34,146.38 152.22,146.27 151.43,146.27 151.32,146.16 151.32,145.76 151.43,145.65 152.22,145.65 152.34,145.53 152.34,145.14 152.22,145.03 151.43,145.03 151.32,144.91 151.32,144.27 143.57,136.53 143.57,125.54 140.46,122.43 140.46,115.25 138.87,113.66 138.87,112.72 v2(138.37,112.22)
DDR_DQ39: length 71.1
  TOP w0.14: U1.Y25 v2(139.17,111.42)
  L3SIG w0.114: v2(139.17,111.42) 139.57,111.82 139.57,112.45 139.26,112.76 139.26,113.35 141.16,115.25 141.16,122.3 144.34,125.48 144.34,128.24 144.45,128.35 144.73,128.35 144.84,128.47 144.84,128.86 144.73,128.97 144.45,128.97 144.34,129.09 144.34,129.48 144.45,129.6 144.73,129.6 144.84,129.71 144.84,130.1 144.73,130.22 144.45,130.22 144.34,130.33 144.34,130.73 144.45,130.84 144.73,130.84 144.84,130.96 144.84,131.35 144.73,131.46 144.45,131.46 144.34,131.58 144.34,131.97 144.45,132.09 144.73,132.09 144.84,132.2 144.84,132.59 144.73,132.71 144.45,132.71 144.34,132.82 144.34,133.22 144.45,133.33 144.73,133.33 144.84,133.44 144.84,133.84 144.73,133.95 144.45,133.95 144.34,134.07 144.34,134.46 144.45,134.57 144.73,134.57 144.84,134.69 144.84,135.08 144.73,135.2 144.45,135.2 144.34,135.31 144.34,136.27 152.78,144.72 152.78,156.23 152.67,156.34 151.94,156.34 151.83,156.46 151.83,156.85 151.94,156.97 152.67,156.97 152.78,157.08 152.78,157.47 152.67,157.59 151.94,157.59 151.83,157.7 151.83,158.1 151.94,158.21 152.67,158.21 152.78,158.32 152.78,160.03 152.67,160.14 151.94,160.14 151.83,160.26 151.83,160.65 151.94,160.77 152.67,160.77 152.78,160.88 152.78,161.23 152.21,161.8 152.21,162.75 152.95,163.49 J1.247
DDR_DQ40: length 77.8
  TOP w0.14: U1.V24 v2(137.57,110.62)
  L6SIG w0.114: v2(137.57,110.62) 137.98,111.03 137.98,115.88 140.21,118.11 140.21,119.41 140.09,119.52 139.69,119.52 139.57,119.64 139.57,120.03 139.69,120.14 140.09,120.14 140.21,120.26 140.21,120.65 140.09,120.77 139.69,120.77 139.57,120.88 139.57,121.27 139.69,121.39 140.09,121.39 140.21,121.5 140.21,121.9 140.09,122.01 139.69,122.01 139.57,122.13 139.57,122.52 139.69,122.63 140.09,122.63 140.21,122.75 140.21,123.14 140.09,123.26 139.69,123.26 139.57,123.37 139.57,123.76 139.69,123.88 140.09,123.88 140.21,123.99 140.21,124.39 140.09,124.5 139.69,124.5 139.57,124.61 139.57,125.01 139.69,125.12 140.09,125.12 140.21,125.24 140.21,125.63 140.09,125.75 139.69,125.75 139.57,125.86 139.57,126.25 139.69,126.37 140.09,126.37 140.21,126.48 140.21,126.88 140.09,126.99 139.69,126.99 139.57,127.1 139.57,127.5 139.69,127.61 140.09,127.61 140.21,127.73 140.21,128.12 140.09,128.23 139.69,128.23 139.57,128.35 139.57,128.74 139.69,128.86 140.09,128.86 140.21,128.97 140.21,129.36 140.09,129.48 139.69,129.48 139.57,129.59 139.57,129.99 139.69,130.1 140.09,130.1 140.21,130.22 140.21,130.61 140.09,130.72 139.69,130.72 139.57,130.84 139.57,131.23 139.69,131.35 140.09,131.35 140.21,131.46 140.21,131.85 140.09,131.97 139.69,131.97 139.57,132.08 139.57,132.48 139.69,132.59 140.09,132.59 140.21,132.7 140.21,133.1 140.09,133.21 139.69,133.21 139.57,133.33 139.57,133.72 139.69,133.84 140.09,133.84 140.21,133.95 140.21,134.34 140.09,134.46 139.69,134.46 139.57,134.57 139.57,134.97 139.69,135.08 140.09,135.08 140.21,135.19 140.21,135.59 140.09,135.7 139.69,135.7 139.57,135.82 139.57,136.21 139.69,136.32 140.09,136.32 140.21,136.44 140.21,136.83 140.09,136.95 139.69,136.95 139.57,137.06 139.57,137.45 139.69,137.57 140.09,137.57 140.21,137.68 140.21,140.21 154.7,154.7 154.86,154.7 155.08,154.48 155.24,154.48 155.52,154.76 155.52,154.92 155.3,155.14 155.3,155.3 157.2,157.2 J1.108
DDR_DQ41: length 77.9
  TOP w0.14: U1.W23 v2(138.37,109.82)
  L6SIG w0.114: v2(138.37,109.82) 138.75,110.2 138.75,115.58 141.61,118.43 141.61,139.32 144.34,142.05 144.34,142.22 143.93,142.63 143.93,142.79 144.21,143.07 144.37,143.07 144.78,142.66 144.94,142.66 145.22,142.94 145.22,143.1 144.81,143.51 144.81,143.67 145.09,143.95 145.25,143.95 145.66,143.54 145.82,143.54 146.1,143.82 146.1,143.98 145.69,144.39 145.69,144.55 145.97,144.83 146.13,144.83 146.54,144.42 146.7,144.42 146.98,144.7 146.98,144.86 146.57,145.27 146.57,145.43 146.85,145.71 147.01,145.71 147.42,145.3 147.58,145.3 147.86,145.58 147.86,145.74 147.45,146.15 147.45,146.31 147.73,146.59 147.89,146.59 148.3,146.18 148.46,146.18 148.74,146.46 148.74,146.62 148.33,147.03 148.33,147.19 148.61,147.47 148.77,147.47 149.18,147.06 149.34,147.06 149.62,147.34 149.62,147.5 149.21,147.91 149.21,148.07 149.49,148.35 149.65,148.35 150.06,147.94 150.22,147.94 150.5,148.22 150.5,148.38 150.09,148.79 150.09,148.95 150.37,149.23 150.53,149.23 150.94,148.82 151.11,148.82 151.38,149.1 151.38,149.26 150.97,149.67 150.97,149.83 151.25,150.11 151.41,150.11 151.82,149.7 151.99,149.7 158.24,155.96 158.24,160.4 158.94,161.1 158.94,162.62 158.05,163.52 J1.253
DDR_DQ42: length 77.8
  TOP w0.14: U1.AA22 v2(139.97,109.02)
  L6SIG w0.114: v2(139.97,109.02) 140.35,109.4 140.96,109.4 141.18,109.62 141.18,109.98 141.41,110.2 141.76,110.2 141.98,110.42 141.98,110.78 142.21,111 142.5,111 142.52,111.03 142.53,111.03 142.75,111.26 142.75,114.05 146.62,117.92 146.62,130.87 155.14,139.4 155.31,139.4 155.84,138.86 156,138.86 156.28,139.14 156.28,139.3 155.75,139.84 155.75,140 156.03,140.28 156.19,140.28 156.72,139.74 156.89,139.74 157.16,140.02 157.16,140.18 156.63,140.72 156.63,140.88 156.91,141.16 157.07,141.16 157.6,140.62 157.77,140.62 158.04,140.9 158.04,141.06 157.51,141.6 157.51,141.76 157.79,142.04 157.95,142.04 158.48,141.5 158.65,141.5 158.92,141.78 158.92,141.94 158.39,142.48 158.39,142.64 158.67,142.92 158.83,142.92 159.36,142.38 159.53,142.38 159.8,142.66 159.8,142.82 159.27,143.36 159.27,143.52 159.55,143.8 159.71,143.8 160.25,143.26 160.41,143.26 160.69,143.54 160.69,143.7 160.15,144.24 160.15,144.4 160.43,144.68 160.59,144.68 161.13,144.14 161.29,144.14 161.57,144.42 161.57,144.58 161.03,145.12 161.03,145.28 161.31,145.56 161.47,145.56 162.01,145.02 162.17,145.02 162.45,145.3 162.45,145.46 161.91,146 161.91,146.16 163.15,147.4 J1.115
DDR_DQ43: length 78.2
  TOP w0.14: U1.AC22 v2(141.57,109.02)
  L6SIG w0.114: v2(141.57,109.02) 141.98,109.43 141.98,109.98 142.21,110.2 142.59,110.2 142.78,110.39 142.78,110.78 143.01,111 143.3,111 143.57,111.28 143.57,113.86 147.64,117.92 147.64,129.03 152.7,134.09 152.7,134.25 152,134.95 152,135.11 152.28,135.39 152.44,135.39 153.14,134.69 153.3,134.69 153.58,134.97 153.58,135.13 152.88,135.83 152.88,135.99 153.16,136.27 153.32,136.27 154.02,135.58 154.18,135.58 154.46,135.85 154.46,136.02 153.76,136.71 153.76,136.87 154.04,137.15 154.2,137.15 154.9,136.46 155.06,136.46 155.34,136.73 155.34,136.9 154.64,137.59 154.64,137.75 154.92,138.03 155.08,138.03 155.78,137.34 155.94,137.34 164,145.39 164,162.66 164.85,163.51 164.85,164.59 164,165.44 J1.260
DDR_DQ44: length 77.1
  TOP w0.14: U1.W22 v2(138.37,109.02)
  BOTTOM w0.14: J1.106 155.68,163.69 155.68,161.82 157.1,160.4 157.1,144.45 156.96,144.32 155.84,144.32 155.7,144.18 155.7,143.81 155.84,143.67 156.96,143.67 157.1,143.53 157.1,143.16 156.96,143.02 155.84,143.02 155.7,142.88 155.7,142.51 155.84,142.37 156.96,142.37 157.1,142.23 157.1,141.86 156.96,141.72 155.84,141.72 155.7,141.58 155.7,141.22 155.84,141.08 156.96,141.08 157.1,140.94 157.1,140.57 156.96,140.43 155.84,140.43 155.7,140.29 155.7,139.92 155.84,139.78 156.96,139.78 157.1,139.64 157.1,135.95 147.32,126.17 147.32,112.14 144.59,109.42 138.77,109.42 v2(138.37,109.02)
DDR_DQ45: length 77.4
  TOP w0.14: U1.V23 v2(137.57,109.82)
  BOTTOM w0.137: 137.97,110.45 137.97,110.78 138.2,111.01 144.42,111.01
  BOTTOM w0.14: 137.97,110.45 137.97,110.22 v2(137.57,109.82) ; J1.251 155.44,165.16 153.8,165.16 152.97,164.34 152.97,163.51 153.8,162.69 153.8,160.85 155,159.64 155,151.88 154.86,151.74 153.56,151.74 153.42,151.61 153.42,151.24 153.56,151.1 154.86,151.1 155,150.96 155,150.59 154.86,150.45 153.56,150.45 153.42,150.31 153.42,149.94 153.56,149.8 154.86,149.8 155,149.66 155,149.29 154.86,149.15 153.56,149.15 153.42,149.01 153.42,136.53 145.35,128.46 145.35,111.95 144.42,111.01
DDR_DQ46: length 78.1
  TOP w0.14: U1.AB24 v2(140.77,110.62)
  L6SIG w0.114: J1.113 161.45,149.76 160.7,149.02 160.54,149.02 160.03,149.52 159.87,149.52 159.59,149.24 159.59,149.08 160.1,148.58 160.1,148.41 159.82,148.14 159.66,148.14 159.15,148.64 158.99,148.64 158.71,148.36 158.71,148.2 159.22,147.7 159.22,147.53 158.94,147.26 158.78,147.26 158.27,147.76 158.11,147.76 157.83,147.48 157.83,147.32 158.34,146.82 158.34,146.65 158.06,146.38 157.9,146.38 157.39,146.88 157.23,146.88 156.95,146.6 156.95,146.44 157.46,145.94 157.46,145.77 157.18,145.5 157.02,145.5 156.51,146 156.35,146 156.07,145.72 156.07,145.56 156.58,145.05 156.58,144.89 156.3,144.61 156.14,144.61 155.63,145.12 155.47,145.12 155.19,144.84 155.19,144.68 155.7,144.17 155.7,144.01 155.42,143.73 155.26,143.73 154.75,144.24 154.59,144.24 154.31,143.96 154.31,143.8 154.82,143.29 154.82,143.13 154.54,142.85 154.38,142.85 153.87,143.36 153.71,143.36 153.43,143.08 153.43,142.92 153.94,142.41 153.94,142.25 153.66,141.97 153.5,141.97 152.99,142.48 152.83,142.48 152.55,142.2 152.55,142.04 153.06,141.53 153.06,141.37 152.78,141.09 152.62,141.09 152.11,141.6 151.95,141.6 151.67,141.32 151.67,141.16 152.18,140.65 152.18,140.49 150.3,138.62 148.34,138.62 144.84,135.13 144.84,118.11 141.16,114.43 141.16,111.26 140.77,110.87 v2(140.77,110.62)
DDR_DQ47: length 77.4
  TOP w0.14: U1.AB23 v2(140.77,109.82)
  L6SIG w0.114: v2(140.77,109.82) 140.77,110.03 141.18,110.44 141.18,110.78 141.41,111 141.73,111 141.98,111.26 141.98,114.29 145.67,117.98 145.67,131.32 147.91,133.56 147.91,133.72 146.9,134.73 146.9,134.9 147.18,135.17 147.34,135.17 148.35,134.16 148.51,134.16 148.79,134.44 148.79,134.6 147.78,135.61 147.78,135.78 148.06,136.06 148.22,136.06 149.23,135.04 149.39,135.04 149.67,135.32 149.67,135.48 148.66,136.5 148.66,136.66 148.94,136.94 149.1,136.94 150.11,135.92 150.27,135.92 162.3,147.95 162.3,162.68 163.13,163.51 163.13,164.34 162.3,165.17 J1.258
DDR_DQ48: length 78.1
  TOP w0.14: U1.AD26 v2(142.37,112.22)
  L3SIG w0.114: v2(142.37,112.22) 142.37,112.39 142.81,112.84 142.81,113.28 144.53,115 144.53,120.78 148.78,125.03 148.78,133.48 161.1,145.8 161.1,146.83 160.99,146.94 159.63,146.94 159.51,147.06 159.51,147.45 159.63,147.57 160.99,147.57 161.1,147.68 161.1,148.07 160.99,148.19 159.63,148.19 159.51,148.3 159.51,148.7 159.63,148.81 160.99,148.81 161.1,148.92 161.1,149.32 160.99,149.43 159.63,149.43 159.51,149.55 159.51,149.94 159.63,150.05 160.99,150.05 161.1,150.17 161.1,150.56 160.99,150.68 159.63,150.68 159.51,150.79 159.51,151.18 159.63,151.3 160.99,151.3 161.1,151.41 161.1,151.81 160.99,151.92 159.63,151.92 159.51,152.04 159.51,152.43 159.63,152.54 160.99,152.54 161.1,152.66 161.1,153.05 160.99,153.17 159.63,153.17 159.51,153.28 159.51,153.67 159.63,153.79 160.99,153.79 161.1,153.9 161.1,154.69 166.55,160.13 J1.119
DDR_DQ49: length 78.4
  TOP w0.14: U1.AD25 v2(142.37,111.42)
  L3SIG w0.114: J1.264 167.4,165.24 166.69,164.53 166.69,163.32 167.39,162.62 167.39,159.45 162.69,154.75 162.69,154.25 162.57,154.13 161.79,154.13 161.67,154.02 161.67,153.63 161.79,153.51 162.57,153.51 162.69,153.4 162.69,153 162.57,152.89 161.79,152.89 161.67,152.78 161.67,152.38 161.79,152.27 162.57,152.27 162.69,152.15 162.69,151.76 162.57,151.65 161.79,151.65 161.67,151.53 161.67,151.14 161.79,151.02 162.57,151.02 162.69,150.91 162.69,150.52 162.57,150.4 161.79,150.4 161.67,150.29 161.67,149.89 161.79,149.78 162.57,149.78 162.69,149.66 162.69,149.27 162.57,149.16 161.79,149.16 161.67,149.04 161.67,148.65 161.79,148.53 162.57,148.53 162.69,148.42 162.69,148.03 162.57,147.91 161.79,147.91 161.67,147.8 161.67,147.4 161.79,147.29 162.57,147.29 162.69,147.17 162.69,146.24 149.42,132.97 149.42,124.78 145.22,120.59 145.22,114.87 142.78,112.43 142.78,111.98 142.37,111.57 v2(142.37,111.42)
DDR_DQ50: length 78.4
  TOP w0.14: U1.AD23 v2(142.37,109.82)
  L3SIG w0.114: v2(142.37,109.82) 142.77,109.41 146.56,109.41 150.37,113.22 150.37,118.62 155.07,123.32 160.08,123.32 162.5,125.73 162.5,134.75 170.5,142.75 170.5,143.03 170.38,143.15 169.6,143.15 169.48,143.26 169.48,143.65 169.6,143.77 170.38,143.77 170.5,143.88 170.5,144.28 170.38,144.39 169.6,144.39 169.48,144.51 169.48,144.9 169.6,145.01 170.38,145.01 170.5,145.13 170.5,145.52 170.38,145.64 169.6,145.64 169.48,145.75 169.48,146.14 169.6,146.26 170.38,146.26 170.5,146.37 170.5,153.8 171.77,155.07 171.77,161.23 172.31,161.77 172.31,163.68 J1.126
DDR_DQ51: length 78.8
  TOP w0.14: U1.AE22 v2(143.17,109.02)
  L3SIG w0.114: v2(143.17,109.02) 143.58,108.6 146.58,108.6 151.32,113.35 151.32,117.92 156.02,122.62 160.46,122.62 163.45,125.6 163.45,134.68 172.66,143.89 172.66,145.38 172.54,145.49 172.2,145.49 172.09,145.6 172.09,146 172.2,146.11 172.54,146.11 172.66,146.23 172.66,146.62 172.54,146.73 172.2,146.73 172.09,146.85 172.09,147.24 172.2,147.36 172.54,147.36 172.66,147.47 172.66,147.87 172.54,147.98 172.2,147.98 172.09,148.09 172.09,148.49 172.2,148.6 172.54,148.6 172.66,148.72 172.66,149.11 172.54,149.22 172.2,149.22 172.09,149.34 172.09,149.73 172.2,149.85 172.54,149.85 172.66,149.96 172.66,162.75 173.35,163.45 J1.271
DDR_DQ52: length 78.5
  TOP w0.14: U1.AB25 v2(140.77,111.42)
  L3SIG w0.114: J1.117 157.92,155.35 157.92,154.62 157.81,154.51 156.64,154.51 156.53,154.39 156.53,154 156.64,153.89 157.81,153.89 157.92,153.77 157.92,153.38 157.81,153.26 156.64,153.26 156.53,153.15 156.53,152.76 156.64,152.64 157.81,152.64 157.92,152.53 157.92,152.13 157.81,152.02 156.64,152.02 156.53,151.9 156.53,151.51 156.64,151.4 157.81,151.4 157.92,151.28 157.92,150.89 157.81,150.77 156.64,150.77 156.53,150.66 156.53,150.27 156.64,150.15 157.81,150.15 157.92,150.04 157.92,149.64 157.81,149.53 156.64,149.53 156.53,149.42 156.53,149.02 156.64,148.91 157.81,148.91 157.92,148.79 157.92,148.4 157.81,148.29 156.64,148.29 156.53,148.17 156.53,147.78 156.64,147.66 157.81,147.66 157.92,147.55 157.92,147.16 157.81,147.04 156.96,147.04 156.85,146.93 156.85,146.53 156.96,146.42 157.81,146.42 157.92,146.3 157.92,144.91 147.32,134.3 147.32,125.48 143.19,121.35 143.19,115.13 141.16,113.09 141.16,111.76 140.82,111.42 v2(140.77,111.42)
DDR_DQ53: length 78.3
  TOP w0.14: U1.AC25 v2(141.57,111.42)
  L3SIG w0.114: J1.262 165.7,165.32 164.85,164.47 164.85,163.51 165.67,162.69 165.67,160.53 165.19,160.05 165.03,160.05 164.46,160.62 164.3,160.62 164.02,160.34 164.02,160.18 164.59,159.61 164.59,159.45 164.31,159.17 164.15,159.17 163.58,159.74 163.42,159.74 163.14,159.46 163.14,159.3 163.71,158.73 163.71,158.57 163.43,158.29 163.27,158.29 162.7,158.86 162.54,158.86 162.26,158.58 162.26,158.42 162.83,157.85 162.83,157.69 162.55,157.41 162.39,157.41 161.82,157.98 161.66,157.98 161.38,157.7 161.38,157.54 161.95,156.97 161.95,156.81 161.67,156.53 161.51,156.53 160.94,157.1 160.78,157.1 160.5,156.82 160.5,156.66 161.07,156.09 161.07,155.93 160.79,155.65 160.63,155.65 160.06,156.22 159.9,156.22 159.62,155.94 159.62,155.78 160.19,155.21 160.19,155.05 158.94,153.8 158.94,144.72 148.15,133.92 148.15,125.29 143.89,121.03 143.89,115.25 141.98,113.34 141.98,111.82 141.58,111.42 v2(141.57,111.42)
DDR_DQ54: length 77.8
  TOP w0.14: U1.AC23 v2(141.57,109.82)
  L3SIG w0.114: J1.124 170.62,163.7 170.62,161.54 170.18,161.1 170.18,156.78 169.89,156.49 169.89,156.33 170.14,156.08 170.14,155.91 169.86,155.64 169.7,155.64 169.45,155.89 169.29,155.89 169.01,155.61 169.01,155.45 169.26,155.2 169.26,155.03 168.98,154.76 168.82,154.76 168.57,155.01 168.41,155.01 167.01,153.61 167.01,153.37 167.12,153.25 168.8,153.25 168.91,153.14 168.91,152.74 168.8,152.63 167.12,152.63 167.01,152.51 167.01,152.12 167.12,152.01 168.8,152.01 168.91,151.89 168.91,151.5 168.8,151.38 167.12,151.38 167.01,151.27 167.01,142.24 155.58,130.81 155.58,126.36 148.65,119.44 148.65,113.09 146.18,110.62 143.76,110.62 143.38,110.23 141.98,110.23 v2(141.57,109.82)
DDR_DQ55: length 78.9
  TOP w0.14: U1.AE23 v2(143.17,109.82)
  L3SIG w0.114: J1.269 171.65,163.46 170.99,162.8 170.99,155.43 169.55,153.99 169.55,147.7 167.86,146.02 167.86,141.83 161.42,135.38 161.42,131.96 161.3,131.84 160.01,131.84 159.89,131.73 159.89,131.33 160.01,131.22 161.3,131.22 161.42,131.11 161.42,130.71 161.3,130.6 160.01,130.6 159.89,130.48 159.89,130.09 160.01,129.97 161.3,129.97 161.42,129.86 161.42,125.73 159.83,124.14 154.75,124.14 149.48,118.87 149.48,113.16 146.56,110.24 143.83,110.24 143.41,109.82 v2(143.17,109.82)
DDR_DQ56: length 84.8
  TOP w0.14: U1.AG25 144.42,111.02 144.78,111.38 145.54,111.38 148.08,113.92 148.08,131.06 153.42,136.4 153.42,143.94 153.56,144.08 155.31,144.08 155.45,144.22 155.45,144.59 155.31,144.73 153.56,144.73 153.42,144.87 153.42,145.24 153.56,145.38 155.31,145.38 155.45,145.52 155.45,145.88 155.31,146.02 153.56,146.02 153.42,146.16 153.42,146.53 153.56,146.67 155.31,146.67 155.45,146.81 155.45,147.18 155.31,147.32 153.56,147.32 153.42,147.46 153.42,147.95 153.67,148.21 155,148.21 155.7,148.91 155.7,153.03 162.31,159.64 173.04,159.64 174.38,160.98 174.38,162.55 175.7,163.87 J1.130
DDR_DQ57: length 83.8
  TOP w0.14: J1.275 176.75,163.73 175.77,162.75 175.77,161.48 173.42,159.13 162.88,159.13 156.34,152.59 156.34,143.44 156.2,143.3 154.32,143.3 154.18,143.16 154.18,142.79 154.32,142.65 156.2,142.65 156.34,142.51 156.34,142.15 156.2,142.01 154.32,142.01 154.18,141.87 154.18,141.5 154.32,141.36 156.2,141.36 156.34,141.22 156.34,140.85 156.2,140.71 154.32,140.71 154.18,140.57 154.18,136.02 148.84,130.68 148.84,113.92 145.94,111.02 U1.AH25
DDR_DQ58: length 84
  TOP w0.14: J1.137 181.85,161.4 173.74,153.29 166.69,153.29 161.42,148.02 161.42,147.43 161.56,147.29 162.61,147.29 162.75,147.15 162.75,146.79 162.61,146.65 161.56,146.65 161.42,146.51 161.42,146.14 161.56,146 162.61,146 162.75,145.86 162.75,145.49 162.61,145.35 161.56,145.35 161.42,145.21 161.42,144.84 161.56,144.7 162.61,144.7 162.75,144.56 162.75,144.2 162.61,144.06 161.56,144.06 161.42,143.92 161.42,143.55 161.56,143.41 162.61,143.41 162.75,143.27 162.75,142.9 162.61,142.76 161.56,142.76 161.42,142.62 161.42,136.84 155.19,130.62 155.19,125.35 152.46,122.62 152.46,113.1 148.21,108.84 145.39,108.84 U1.AH22
DDR_DQ59: length 80.6
  TOP w0.14: U1.AF22 v2(143.97,109.02)
  L6SIG w0.114: v2(143.97,109.02) 144,109.02 145.29,110.3 145.29,112.39 150.81,117.92 150.81,126.94 176.52,152.64 176.52,156 176.63,156.11 177.11,156.11 177.23,156.23 177.23,156.62 177.11,156.73 176.63,156.73 176.52,156.85 176.52,157.24 176.63,157.36 177.11,157.36 177.23,157.47 177.23,157.86 177.11,157.98 176.63,157.98 176.52,158.09 176.52,158.49 176.63,158.6 177.11,158.6 177.23,158.71 177.23,159.11 177.11,159.22 176.63,159.22 176.52,159.34 176.52,159.94 177.23,160.66 180.4,160.66 181.04,161.29 181.04,162.69 181.86,163.51 181.86,164.66 182.7,165.49 J1.282
DDR_DQ60: length 80.9
  TOP w0.14: U1.AF26 v2(143.97,112.22)
  L6SIG w0.114: J1.128 174.2,161.33 174.08,161.22 172.83,161.22 172.72,161.1 172.72,160.71 172.83,160.6 174.08,160.6 174.2,160.48 174.2,160.09 174.08,159.97 172.83,159.97 172.72,159.86 172.72,159.47 172.83,159.35 174.08,159.35 174.2,159.24 174.2,158.84 174.08,158.73 172.83,158.73 172.72,158.62 172.72,158.22 172.83,158.11 174.08,158.11 174.2,157.99 174.2,157.6 174.08,157.48 172.83,157.48 172.72,157.37 172.72,156.98 172.83,156.86 174.08,156.86 174.2,156.75 174.2,156.35 174.08,156.24 172.83,156.24 172.72,156.13 172.72,155.73 172.83,155.62 174.08,155.62 174.2,155.5 174.2,155.11 174.08,155 172.83,155 172.72,154.88 172.72,154.49 172.83,154.37 174.08,154.37 174.2,154.26 174.2,152.35 148.97,127.13 148.97,117.98 144.4,113.41 144.4,112.9 143.97,112.47 v2(143.97,112.22)
DDR_DQ61: length 84.3
  TOP w0.14: J1.273 175.05,163.74 174.05,162.75 174.05,161.61 172.85,160.4 161.99,160.4 154.94,153.35 154.94,149.22 154.69,148.97 153.16,148.97 152.59,148.4 152.59,147.95 152.45,147.81 151.52,147.81 151.38,147.67 151.38,147.3 151.52,147.16 152.45,147.16 152.59,147.02 152.59,146.65 152.45,146.51 151.52,146.51 151.38,146.37 151.38,146 151.52,145.86 152.45,145.86 152.59,145.72 152.59,145.35 152.45,145.22 151.52,145.22 151.38,145.08 151.38,144.71 151.52,144.57 152.45,144.57 152.59,144.43 152.59,144.06 152.45,143.92 151.52,143.92 151.38,143.78 151.38,143.41 151.52,143.27 152.45,143.27 152.59,143.13 152.59,142.76 152.45,142.62 151.52,142.62 151.38,142.48 151.38,142.12 151.52,141.98 152.45,141.98 152.59,141.84 152.59,136.59 147.32,131.32 147.32,113.97 U1.AH26
DDR_DQ62: length 83.5
  TOP w0.14: U1.AH23 145.24,109.35 147.83,109.35 151.77,113.28 151.77,128.52 160.66,137.41 160.66,148.59 166.18,154.11 166.92,154.11 167.06,154.25 167.06,155.44 167.2,155.57 167.57,155.57 167.71,155.44 167.71,154.25 167.85,154.11 168.22,154.11 168.36,154.25 168.36,155.44 168.5,155.57 168.86,155.57 169,155.44 169,154.25 169.14,154.11 169.51,154.11 169.65,154.25 169.65,155.44 169.79,155.57 170.16,155.57 170.3,155.44 170.3,154.25 170.44,154.11 170.81,154.11 170.95,154.25 170.95,155.44 171.09,155.57 171.45,155.57 171.59,155.44 171.59,154.25 171.73,154.11 173.29,154.11 180.15,160.97 J1.135
DDR_DQ63: length 81
  TOP w0.14: U1.AF23 v2(143.97,109.82)
  L6SIG w0.114: v2(143.97,109.82) 143.97,110.5 144.35,110.89 144.35,112.41 149.86,117.92 149.86,127.06 174.94,152.15 174.94,155.78 175.06,155.89 175.59,155.89 175.7,156 175.7,156.4 175.59,156.51 175.06,156.51 174.94,156.63 174.94,157.02 175.06,157.13 175.59,157.13 175.7,157.25 175.7,157.64 175.59,157.76 175.06,157.76 174.94,157.87 174.94,158.26 175.06,158.38 175.59,158.38 175.7,158.49 175.7,158.89 175.59,159 175.06,159 174.94,159.12 174.94,159.51 175.06,159.62 175.59,159.62 175.7,159.74 175.7,160.13 175.59,160.25 175.06,160.25 174.94,160.36 174.94,160.78 175.32,161.16 179.13,161.16 179.32,161.35 179.32,162.75 180.15,163.58 180.15,164.85 181,165.69 J1.280
DDR_ECC0: length 83.3
  TOP w0.14: U1.L24 v2(131.17,110.62)
  L6SIG w0.114: v2(131.17,110.62) 131.19,110.62 131.57,111 131.57,112.65 131.32,112.9 131.32,128.84 128.21,131.95 128.21,134.18 128.09,134.29 127.11,134.29 127,134.41 127,134.8 127.11,134.91 128.09,134.91 128.21,135.03 128.21,137.14 128.09,137.25 127.18,137.25 127.06,137.37 127.06,137.76 127.18,137.87 128.09,137.87 128.21,137.99 128.21,138.38 128.09,138.5 127.18,138.5 127.06,138.61 127.06,139.01 127.18,139.12 128.09,139.12 128.21,139.23 128.21,139.63 128.09,139.74 127.18,139.74 127.06,139.86 127.06,140.25 127.18,140.36 128.09,140.36 128.21,140.48 128.21,140.84 127.92,141.13 127.92,141.29 128.29,141.67 128.29,141.83 128.02,142.11 127.85,142.11 127.48,141.74 127.31,141.74 127.04,142.01 127.04,142.18 127.41,142.55 127.41,142.71 127.14,142.99 126.97,142.99 126.6,142.62 126.43,142.62 126.16,142.89 126.16,143.06 126.53,143.43 126.53,143.6 126.26,143.87 126.09,143.87 125.72,143.5 125.55,143.5 125.28,143.77 125.28,143.94 125.65,144.31 125.65,144.48 125.37,144.75 125.21,144.75 124.83,144.38 124.67,144.38 124.39,144.65 124.39,144.82 124.77,145.19 124.77,145.36 124.49,145.63 124.33,145.63 123.95,145.26 123.79,145.26 115.89,153.16 108.9,153.16 101.95,160.12 J1.49
DDR_ECC1: length 84.2
  TOP w0.14: U1.N23 v2(132.77,109.82)
  L6SIG w0.114: v2(132.77,109.82) 133.18,110.23 133.79,110.23 133.96,110.4 133.96,114.26 133.03,115.19 133.03,130.68 130.56,133.16 130.56,143.32 120.64,153.23 120.48,153.23 120.17,152.92 120.01,152.92 119.73,153.2 119.73,153.36 120.04,153.67 120.04,153.83 119.76,154.11 119.6,154.11 119.29,153.8 119.12,153.8 118.85,154.08 118.85,154.24 119.16,154.55 119.16,154.71 118.24,155.64 115.32,155.64 115.21,155.52 115.21,154.99 115.09,154.88 114.7,154.88 114.58,154.99 114.58,155.52 114.47,155.64 114.08,155.64 113.96,155.52 113.96,154.99 113.85,154.88 113.45,154.88 113.34,154.99 113.34,155.52 113.22,155.64 112.83,155.64 112.72,155.52 112.72,154.99 112.6,154.88 112.21,154.88 112.09,154.99 112.09,155.52 111.98,155.64 111.59,155.64 111.47,155.52 111.47,154.99 111.36,154.88 110.96,154.88 110.85,154.99 110.85,155.52 110.74,155.64 109.92,155.64 104.46,161.1 104.46,162.69 103.63,163.51 103.63,164.59 102.8,165.43 J1.194
DDR_ECC2: length 83.1
  TOP w0.14: U1.T23 v2(135.97,109.82)
  L6SIG w0.114: J1.56 108.08,163.69 108.08,161.67 108.37,161.37 109.07,161.37 111.82,158.62 121.73,158.62 122.64,157.71 122.64,157.55 122.36,157.27 122.36,157.1 122.64,156.83 122.8,156.83 123.08,157.11 123.24,157.11 123.52,156.83 123.52,156.67 123.24,156.39 123.24,156.22 123.52,155.95 123.68,155.95 123.96,156.23 124.12,156.23 124.4,155.95 124.4,155.79 124.12,155.51 124.12,155.34 124.4,155.06 124.56,155.06 124.84,155.35 125,155.35 125.28,155.07 125.28,154.91 125,154.62 125,154.46 125.28,154.18 125.44,154.18 125.72,154.47 125.88,154.47 126.16,154.19 126.16,154.03 125.88,153.74 125.88,153.58 126.16,153.3 126.32,153.3 126.6,153.59 126.77,153.59 127.04,153.31 127.04,153.15 126.76,152.86 126.76,152.7 127.04,152.42 127.2,152.42 127.48,152.71 127.65,152.71 127.92,152.43 127.92,152.27 127.64,151.98 127.64,151.82 127.92,151.54 128.08,151.54 128.36,151.83 128.53,151.83 128.8,151.55 128.8,151.39 128.52,151.1 128.52,150.94 128.8,150.66 128.96,150.66 129.24,150.95 129.41,150.95 129.69,150.67 129.69,150.51 129.4,150.22 129.4,150.06 129.68,149.78 129.84,149.78 130.13,150.07 130.29,150.07 130.57,149.79 130.57,149.63 130.28,149.34 130.28,149.18 130.56,148.9 130.72,148.9 131.01,149.19 131.17,149.19 135.57,144.78 135.57,133.92 136.53,132.97 136.53,118.11 135.57,117.16 135.57,110.21 v2(135.97,109.82)
DDR_ECC3: length 84.1
  TOP w0.14: U1.U23 v2(136.77,109.82)
  L6SIG w0.114: v2(136.77,109.82) 137.16,110.21 137.16,116.27 138.62,117.73 138.62,134.6 138.51,134.71 137.46,134.71 137.35,134.83 137.35,135.22 137.46,135.34 138.51,135.34 138.62,135.45 138.62,135.85 138.51,135.96 137.46,135.96 137.35,136.07 137.35,136.47 137.46,136.58 138.51,136.58 138.62,136.7 138.62,140.87 138.51,140.99 137.78,140.99 137.67,141.1 137.67,141.49 137.78,141.61 138.51,141.61 138.62,141.72 138.62,142.12 138.51,142.23 137.78,142.23 137.67,142.34 137.67,142.74 137.78,142.85 138.51,142.85 138.62,142.97 138.62,144.97 123,160.59 112.2,160.59 111.25,161.54 111.25,162.62 110.43,163.45 110.43,164.39 J1.201
DDR_ECC4: length 84
  TOP w0.14: U1.L23 v2(131.17,109.82)
  L6SIG w0.114: J1.47 100.25,160.61 108.2,152.65 115.19,152.65 115.55,152.3 115.55,152.13 115.2,151.79 115.2,151.63 115.48,151.35 115.64,151.35 115.99,151.69 116.15,151.69 116.43,151.42 116.43,151.25 116.08,150.91 116.08,150.75 116.36,150.47 116.52,150.47 116.87,150.81 117.03,150.81 117.31,150.53 117.31,150.37 116.96,150.03 116.96,149.87 117.24,149.59 117.4,149.59 117.75,149.93 117.91,149.93 118.19,149.65 118.19,149.49 117.84,149.15 117.84,148.98 118.12,148.71 118.28,148.71 118.63,149.05 118.79,149.05 119.07,148.77 119.07,148.61 118.72,148.27 118.72,148.1 119,147.83 119.16,147.83 119.51,148.17 119.67,148.17 119.95,147.89 119.95,147.73 119.6,147.39 119.6,147.22 119.88,146.95 120.04,146.95 120.39,147.29 120.55,147.29 120.83,147.01 120.83,146.85 120.48,146.51 120.48,146.34 120.76,146.07 120.92,146.07 121.27,146.41 121.43,146.41 121.71,146.13 121.71,145.97 121.36,145.63 121.36,145.46 121.64,145.18 121.8,145.18 122.15,145.53 122.31,145.53 122.59,145.25 122.59,145.09 122.24,144.74 122.24,144.58 122.52,144.3 122.68,144.3 123.03,144.65 123.19,144.65 123.47,144.37 123.47,144.21 123.12,143.86 123.12,143.7 123.4,143.42 123.56,143.42 123.91,143.77 124.07,143.77 124.35,143.49 124.35,143.33 124,142.98 124,142.82 124.28,142.54 124.44,142.54 124.79,142.89 124.95,142.89 125.23,142.61 125.23,142.45 124.88,142.1 124.88,141.94 125.16,141.66 125.33,141.66 125.67,142.01 125.83,142.01 126.49,141.35 126.49,132.46 130.75,128.2 130.75,110.23 v2(131.17,109.82)
DDR_ECC5: length 84
  TOP w0.14: U1.M23 v2(131.97,109.82)
  L6SIG w0.114: v2(131.97,109.82) 132.38,110.23 132.38,113.24 131.83,113.79 131.83,129.54 128.97,132.4 128.97,141.92 124.46,146.43 124.3,146.43 124.02,146.15 123.86,146.15 123.58,146.42 123.58,146.59 123.86,146.87 123.86,147.03 123.58,147.31 123.42,147.31 123.14,147.03 122.98,147.03 122.7,147.31 122.7,147.47 122.98,147.75 122.98,147.91 122.7,148.19 122.54,148.19 122.26,147.91 122.1,147.91 121.82,148.19 121.82,148.35 122.1,148.63 122.1,148.79 121.82,149.07 121.66,149.07 121.38,148.79 121.21,148.79 120.94,149.07 120.94,149.23 121.22,149.51 121.22,149.67 120.94,149.95 120.78,149.95 120.5,149.67 120.33,149.67 120.06,149.95 120.06,150.11 120.34,150.39 120.34,150.55 120.06,150.83 119.9,150.83 119.62,150.55 119.45,150.55 119.18,150.83 119.18,150.99 119.46,151.27 119.46,151.43 119.18,151.71 119.02,151.71 118.74,151.43 118.57,151.43 118.3,151.71 118.3,151.87 118.58,152.15 118.58,152.31 118.3,152.59 118.14,152.59 117.85,152.31 117.69,152.31 117.41,152.59 117.41,152.75 117.7,153.03 117.7,153.19 117.16,153.73 109.47,153.73 102.81,160.4 102.81,162.69 101.92,163.58 101.92,164.72 101.1,165.54 J1.192
DDR_ECC6: length 83.6
  TOP w0.14: U1.R24 v2(135.17,110.62)
  L6SIG w0.114: v2(135.17,110.62) 134.75,111.03 134.75,112.46 135.06,112.78 135.06,117.47 135.7,118.11 135.7,132.46 134.49,133.67 134.49,136.54 134.38,136.65 133.91,136.65 133.79,136.77 133.79,137.16 133.91,137.27 134.38,137.27 134.49,137.39 134.49,137.78 134.38,137.9 133.91,137.9 133.79,138.01 133.79,138.4 133.91,138.52 134.38,138.52 134.49,138.63 134.49,139.03 134.38,139.14 133.91,139.14 133.79,139.26 133.79,139.65 133.91,139.76 134.38,139.76 134.49,139.88 134.49,140.27 134.38,140.39 133.91,140.39 133.79,140.5 133.79,140.89 133.91,141.01 134.38,141.01 134.49,141.12 134.49,141.52 134.38,141.63 133.91,141.63 133.79,141.74 133.79,142.14 133.91,142.25 134.38,142.25 134.49,142.37 134.49,142.76 134.38,142.88 133.91,142.88 133.79,142.99 133.79,143.38 133.91,143.5 134.38,143.5 134.49,143.61 134.49,144.08 133.92,144.66 133.92,144.82 134.2,145.1 134.2,145.27 133.92,145.54 133.76,145.54 133.47,145.26 133.31,145.26 133.03,145.54 133.03,145.7 133.32,145.98 133.32,146.15 133.04,146.42 132.88,146.42 132.59,146.14 132.43,146.14 132.15,146.42 132.15,146.58 132.44,146.86 132.44,147.03 132.16,147.3 132,147.3 131.71,147.02 131.55,147.02 131.27,147.3 131.27,147.46 131.56,147.74 131.56,147.91 131.28,148.19 131.12,148.19 130.83,147.9 130.67,147.9 120.59,157.99 110.73,157.99 109.98,158.74 109.98,159.58 109.6,159.96 109.09,159.96 107.76,161.29 107.76,162.62 107.25,163.13 106.94,163.13 J1.54
DDR_ECC7: length 84
  TOP w0.14: U1.T24 v2(135.97,110.62)
  L6SIG w0.114: J1.199 107.23,166.07 108.71,164.59 108.71,163.45 109.6,162.56 109.6,161.61 111.51,159.7 121.6,159.7 123.12,158.18 123.28,158.18 123.82,158.72 123.98,158.72 124.26,158.44 124.26,158.28 123.72,157.74 123.72,157.58 124,157.3 124.16,157.3 124.7,157.84 124.86,157.84 125.14,157.56 125.14,157.4 124.6,156.86 124.6,156.7 124.88,156.42 125.04,156.42 125.58,156.96 125.74,156.96 126.02,156.68 126.02,156.52 125.48,155.98 125.48,155.82 125.76,155.54 125.92,155.54 126.46,156.08 126.62,156.08 126.9,155.8 126.9,155.64 126.37,155.1 126.37,154.94 126.64,154.66 126.81,154.66 127.34,155.2 127.5,155.2 127.78,154.92 127.78,154.76 127.25,154.22 127.25,154.06 136.59,144.72 136.59,134.05 137.6,133.03 137.6,118.17 136.21,116.78 136.21,115.2 136.35,115.06 136.35,111 v2(135.97,110.62)
DDR_MA0: length 65.8
  TOP w0.14: J1.79 132.55,159.72 135.67,156.6 135.67,155.82 135.81,155.68 136.51,155.68 136.65,155.54 136.65,155.3 136.51,155.16 135.81,155.16 135.67,155.02 135.67,154.75 135.81,154.61 136.58,154.61 136.72,154.47 136.72,154.23 136.58,154.09 135.81,154.09 135.67,153.95 135.67,153.71 135.81,153.57 136.58,153.57 136.72,153.43 136.72,153.19 136.58,153.05 135.81,153.05 135.67,152.91 135.67,152.67 135.81,152.53 136.58,152.53 136.72,152.39 136.72,152.15 136.58,152.01 135.81,152.01 135.67,151.87 135.67,150.92 135.81,150.78 136.83,150.78 136.97,150.64 136.97,150.4 136.83,150.26 135.81,150.26 135.67,150.12 135.67,149.88 135.81,149.74 136.83,149.74 136.97,149.6 136.97,149.36 136.83,149.22 135.81,149.22 135.67,149.08 135.67,144.57 136.57,143.68 136.57,143.31 136.71,143.17 137.15,143.17 137.29,143.04 137.29,142.79 137.15,142.65 136.71,142.65 136.57,142.51 136.57,142.27 136.71,142.13 137.15,142.13 137.29,141.99 137.29,141.75 137.15,141.61 136.71,141.61 136.57,141.47 136.57,141.23 136.71,141.09 137.15,141.09 137.29,140.95 137.29,140.71 137.15,140.57 136.71,140.57 136.57,140.43 136.57,137.56 137.38,136.75 137.38,120.18 137.17,119.96 137.17,115.91 137.17,115.91 137.17,115.56 137.17,115.55 U1.V28
DDR_MA1: length 65.3
  TOP w0.14: U1.N28 133.17,114.22 133.25,114.3 133.25,115.56 133.44,115.76 133.44,133 132.85,133.6 132.85,141.57 130.22,144.2 130.22,151.56 129.75,152.03 129.75,152.23 130.43,152.9 130.43,153.1 130.26,153.27 130.06,153.27 129.38,152.59 129.19,152.59 129,152.78 129,152.95 129.72,153.67 129.72,153.83 129.48,154.07 129.32,154.07 128.59,153.35 128.43,153.35 128.19,153.59 128.19,153.75 128.91,154.48 128.91,154.64 128.67,154.88 128.51,154.88 127.79,154.16 127.15,154.16 126.54,154.77 126.54,154.97 126.66,155.09 126.66,155.28 126.49,155.45 126.29,155.45 126.17,155.33 125.97,155.33 125.8,155.5 125.8,155.7 125.92,155.82 125.92,156.02 125.75,156.19 125.55,156.19 125.43,156.07 125.23,156.07 125.06,156.24 125.06,156.44 125.18,156.56 125.18,156.76 125.01,156.93 124.82,156.93 124.7,156.81 124.5,156.81 124.33,156.98 124.33,157.18 124.45,157.3 124.45,157.49 124.28,157.66 124.08,157.66 123.96,157.54 123.76,157.54 123.59,157.71 123.59,157.91 123.71,158.03 123.71,158.23 123.54,158.4 123.34,158.4 123.22,158.28 123.02,158.28 121.64,159.66 121.64,163.73 J1.72
DDR_MA2: length 66.3
  TOP w0.14: J1.216 121.5,165.29 120.78,164.57 120.78,163.42 121.36,162.84 121.36,159.44 129.78,151.02 129.78,147.96 129.64,147.82 128.79,147.82 128.65,147.68 128.65,147.44 128.79,147.3 129.64,147.3 129.78,147.16 129.78,146.88 129.67,146.77 128.75,146.77 128.63,146.65 128.63,146.31 128.75,146.2 129.67,146.2 129.78,146.08 129.78,145.74 129.67,145.63 128.75,145.63 128.63,145.51 128.63,145.11 132.25,141.5 132.25,131.29 132.81,130.73 132.81,116.3 132.33,115.83 132.33,114.25 132.79,113.79 132.79,112.99 U1.N27
DDR_MA3: length 64.8
  TOP w0.14: U1.M28 132.37,113.68 131.97,114.08 131.97,116.37 132.17,116.58 132.17,130.31 131.71,130.77 131.71,141.34 127.62,145.43 127.62,145.63 127.76,145.77 128.09,145.77 128.2,145.88 128.2,146.23 128.09,146.34 127.68,146.34 127.56,146.45 127.56,146.8 127.68,146.91 128.09,146.91 128.2,147.02 128.2,147.37 128.09,147.48 127.68,147.48 127.56,147.6 127.56,148.31 127.7,148.45 129.08,148.45 129.22,148.59 129.22,148.83 129.08,148.97 127.7,148.97 127.56,149.11 127.56,149.36 127.7,149.5 129.08,149.5 129.22,149.63 129.22,149.88 129.08,150.02 127.7,150.02 127.56,150.16 127.56,150.4 127.7,150.54 129.08,150.54 129.22,150.68 129.22,150.92 129.08,151.06 127.7,151.06 127.56,151.2 127.56,152.72 120.9,159.38 120.9,162.02 J1.71
DDR_MA4: length 66.2
  TOP w0.14: U1.L27 131.17,113.02 131.17,114.58 130.97,114.78 130.97,129.26 130.65,129.58 130.65,130.83 130.53,130.95 130.23,130.95 130.12,131.06 130.12,131.29 130.23,131.4 130.53,131.4 130.65,131.52 130.65,131.75 130.53,131.86 130.23,131.86 130.12,131.97 130.12,132.2 130.23,132.32 130.53,132.32 130.65,132.43 130.65,132.66 130.53,132.77 130.23,132.77 130.12,132.89 130.12,133.12 130.23,133.23 130.53,133.23 130.65,133.35 130.65,133.57 130.53,133.69 130.23,133.69 130.12,133.8 130.12,134.03 130.23,134.15 130.53,134.15 130.65,134.26 130.65,134.49 130.53,134.6 130.23,134.6 130.12,134.72 130.12,134.95 130.23,135.06 130.53,135.06 130.65,135.17 130.65,135.4 130.53,135.52 130.23,135.52 130.12,135.63 130.12,135.86 130.23,135.97 130.53,135.97 130.65,136.09 130.65,136.56 130.01,137.2 130.01,140.87 126.32,144.57 126.32,152.7 119.66,159.36 119.66,162.56 119.13,163.09 119.13,164.72 118.24,165.61 118.24,166.42 119.49,167.67 J1.214
DDR_MA5: length 65.7
  TOP w0.14: J1.213 120.47,164.55 120.47,163.14 119.98,162.65 119.98,161.84 120.4,161.42 120.4,159.26 127.15,152.51 127.15,151.84 127.03,151.73 126.85,151.73 126.73,151.61 126.73,151.27 126.85,151.16 127.03,151.16 127.15,151.04 127.15,150.7 127.03,150.59 126.85,150.59 126.73,150.47 126.73,150.13 126.85,150.02 127.03,150.02 127.15,149.9 127.15,149.56 127.03,149.45 126.85,149.45 126.73,149.33 126.73,148.99 126.85,148.88 127.03,148.88 127.15,148.76 127.15,148.42 127.03,148.31 126.85,148.31 126.73,148.19 126.73,147.85 126.85,147.74 127.03,147.74 127.15,147.62 127.15,147.35 127.01,147.21 126.82,147.21 126.68,147.07 126.68,146.83 126.82,146.69 127.01,146.69 127.15,146.55 127.15,146.31 127.01,146.17 126.82,146.17 126.68,146.03 126.68,145.79 126.82,145.65 127.01,145.65 127.15,145.51 127.15,144.33 127.33,144.14 127.53,144.14 127.77,144.38 127.97,144.38 128.14,144.21 128.14,144.01 127.9,143.77 127.9,143.58 128.07,143.41 128.27,143.41 128.51,143.65 128.71,143.65 128.88,143.47 128.88,143.28 128.64,143.04 128.64,142.84 128.81,142.67 129.01,142.67 129.24,142.91 129.44,142.91 129.61,142.74 129.61,142.54 129.37,142.3 129.37,142.1 129.54,141.93 129.74,141.93 129.98,142.17 130.18,142.17 130.35,142 130.35,141.8 130.11,141.56 130.11,141.37 130.52,140.96 130.52,139.63 130.93,139.23 130.93,138.59 130.52,138.19 130.52,137.5 131.16,136.87 131.16,130.15 131.55,129.76 131.55,113.44 U1.L28
DDR_MA6: length 65.9
  TOP w0.14: J1.69 119.02,162.2 119.02,159.49 124.85,153.66 124.85,152.52 124.96,152.41 125.73,152.41 125.85,152.3 125.85,151.95 125.73,151.84 124.96,151.84 124.85,151.73 124.85,151.38 124.96,151.27 125.73,151.27 125.85,151.16 125.85,150.81 125.73,150.7 124.96,150.7 124.85,150.59 124.85,150.24 124.96,150.13 125.73,150.13 125.85,150.02 125.85,149.67 125.73,149.56 124.96,149.56 124.85,149.44 124.85,149.1 124.96,148.99 125.73,148.99 125.85,148.87 125.85,148.53 125.73,148.42 124.96,148.42 124.85,148.3 124.85,147.96 124.96,147.85 125.73,147.85 125.85,147.73 125.85,147.39 125.73,147.28 124.96,147.28 124.85,147.16 124.85,146.82 124.96,146.71 125.73,146.71 125.85,146.59 125.85,146.25 125.73,146.14 124.96,146.14 124.85,146.02 124.85,145.34 129.4,140.78 129.4,137.04 129.63,136.81 129.63,129.12 129.77,128.98 130.35,128.98 130.49,128.84 130.49,128.6 130.35,128.46 129.77,128.46 129.63,128.32 129.63,128.07 129.77,127.93 130.35,127.93 130.49,127.8 130.49,113.69 U1.K28
DDR_MA7: length 65.7
  TOP w0.14: U1.J28 129.97,114.23 129.95,114.25 129.95,126.14 129.81,126.28 129.3,126.28 129.16,126.42 129.16,126.66 129.3,126.8 129.81,126.8 129.95,126.94 129.95,127.29 129.81,127.43 129.26,127.43 129.12,127.57 129.12,136.56 128.9,136.79 128.9,140.64 124.39,145.15 124.39,145.95 124.28,146.06 123.79,146.06 123.67,146.17 123.67,146.52 123.79,146.63 124.28,146.63 124.39,146.74 124.39,147.09 124.28,147.2 123.79,147.2 123.67,147.32 123.67,147.66 123.79,147.77 124.28,147.77 124.39,147.89 124.39,148.23 124.28,148.34 123.79,148.34 123.67,148.46 123.67,148.8 123.79,148.91 124.28,148.91 124.39,149.03 124.39,149.37 124.28,149.48 123.79,149.48 123.67,149.6 123.67,149.94 123.79,150.05 124.28,150.05 124.39,150.17 124.39,150.51 124.28,150.62 123.79,150.62 123.67,150.74 123.67,151.08 123.79,151.19 124.28,151.19 124.39,151.31 124.39,153.49 118.55,159.32 118.55,161.61 118.28,161.89 118.28,162.85 118.77,163.35 118.77,164.55 J1.211
DDR_MA8: length 64.9
  TOP w0.14: J1.68 117.98,163.76 117.98,159.26 123.26,153.99 123.26,153.57 123.37,153.45 123.81,153.45 123.92,153.34 123.92,153 123.81,152.88 123.37,152.88 123.26,152.77 123.26,152.43 123.37,152.31 123.81,152.31 123.92,152.2 123.92,151.86 123.81,151.74 123.37,151.74 123.26,151.63 123.26,145.69 128.36,140.58 128.36,136.56 128.62,136.31 128.62,125.93 128.76,125.79 129.27,125.79 129.41,125.65 129.41,125.41 129.27,125.27 128.76,125.27 128.62,125.13 128.62,124.89 128.76,124.75 129.27,124.75 129.41,124.61 129.41,124.37 129.27,124.23 128.76,124.23 128.62,124.09 128.62,123.85 128.76,123.71 129.27,123.71 129.41,123.57 129.41,123.33 129.27,123.19 128.76,123.19 128.62,123.05 128.62,122.81 128.76,122.67 129.27,122.67 129.41,122.53 129.41,122.29 129.27,122.15 128.76,122.15 128.62,122.01 128.62,121.77 128.76,121.63 129.27,121.63 129.41,121.49 129.41,121.25 129.27,121.11 128.76,121.11 128.62,120.97 128.62,120.7 128.76,120.56 129.11,120.56 129.25,120.42 129.25,119.86 129.57,119.54 129.57,113.02 U1.J27
DDR_MA9: length 65.6
  TOP w0.14: J1.66 116.04,163.87 114.88,162.7 114.88,161.86 115.83,160.9 115.83,158.66 116.76,157.73 117.6,157.73 120.97,154.37 120.97,146.12 121.61,145.48 121.61,145.32 121.14,144.85 121.14,144.69 121.35,144.48 121.57,144.48 122.01,144.92 122.17,144.92 122.41,144.68 122.41,144.51 122.07,144.17 122.07,144.01 122.31,143.77 122.47,143.77 122.82,144.11 122.98,144.11 123.22,143.87 123.22,143.71 122.88,143.37 122.88,143.21 123.12,142.96 123.28,142.96 123.62,143.31 123.78,143.31 124.02,143.06 124.02,142.9 123.68,142.56 123.68,142.4 123.93,142.16 124.09,142.16 124.43,142.5 124.59,142.5 124.83,142.26 124.83,142.1 124.49,141.75 124.49,141.59 124.73,141.35 124.89,141.35 125.23,141.69 125.4,141.69 125.58,141.5 125.58,141.31 125.27,140.99 125.27,140.79 125.44,140.62 125.64,140.62 125.95,140.94 126.15,140.94 126.51,140.57 126.51,120.18 128.24,118.46 128.24,115.61 127.97,115.34 127.97,113.02 U1.G27
DDR_MA10: length 66.2
  TOP w0.14: J1.225 134.25,163.44 134.92,162.77 134.92,161.84 134.81,161.73 134.81,159.58 136.02,158.37 138.6,158.37 140.05,156.92 140.05,148.29 139.94,148.18 139.22,148.18 139.1,148.06 139.1,147.72 139.22,147.61 139.94,147.61 140.05,147.49 140.05,147.15 139.94,147.04 139.22,147.04 139.1,146.92 139.1,146.58 139.22,146.47 139.94,146.47 140.05,146.35 140.05,146.01 139.94,145.9 139.22,145.9 139.1,145.78 139.1,145.44 139.22,145.33 139.94,145.33 140.05,145.21 140.05,144.87 139.94,144.76 139.22,144.76 139.1,144.64 139.1,144.3 139.22,144.19 139.94,144.19 140.05,144.07 140.05,143.73 139.94,143.62 139.22,143.62 139.1,143.5 139.1,143.16 139.22,143.04 139.94,143.04 140.05,142.93 140.05,141.79 139.67,141.4 139.67,118.65 139.17,118.15 139.17,113.02 U1.Y27
DDR_MA11: length 65
  TOP w0.14: J1.210 116.4,164.91 117.09,164.21 117.09,163.32 116.46,162.69 116.46,161.8 116.71,161.54 116.71,158.88 117.09,158.5 118.11,158.5 122.84,153.77 122.84,145.44 127.85,140.42 127.85,136.31 128.17,135.99 128.17,132.77 128.03,132.63 127.71,132.63 127.57,132.49 127.57,132.24 127.71,132.1 128.03,132.1 128.17,131.97 128.17,131.72 128.03,131.58 127.71,131.58 127.57,131.44 127.57,131.2 127.71,131.06 128.03,131.06 128.17,130.92 128.17,130.68 128.03,130.54 127.71,130.54 127.57,130.4 127.57,130.16 127.71,130.02 128.03,130.02 128.17,129.88 128.17,129.64 128.03,129.5 127.71,129.5 127.57,129.36 127.57,129.12 127.71,128.98 128.03,128.98 128.17,128.84 128.17,128.6 128.03,128.46 127.77,128.46 127.64,128.32 127.64,120.78 129.11,119.31 129.11,114.7 128.77,114.36 128.77,113.82 U1.H28
DDR_MA12: length 64.8
  TOP w0.14: J1.65 115.55,161.82 116.33,161.04 116.33,158.75 116.97,158.12 117.86,158.12 121.51,154.46 121.51,153.24 121.62,153.13 122.3,153.13 122.42,153.02 122.42,152.67 122.3,152.56 121.58,152.56 121.44,152.42 121.44,152.13 121.58,151.99 122.3,151.99 122.42,151.87 122.42,151.56 122.28,151.42 121.58,151.42 121.44,151.28 121.44,150.99 121.58,150.85 122.28,150.85 122.42,150.71 122.42,150.39 122.3,150.28 121.57,150.28 121.43,150.14 121.43,149.85 121.57,149.71 122.3,149.71 122.42,149.59 122.42,149.25 122.3,149.14 121.57,149.14 121.43,149 121.43,148.71 121.57,148.57 122.28,148.57 122.42,148.43 122.42,148.11 122.3,148 121.58,148 121.44,147.86 121.44,147.57 121.58,147.43 122.28,147.43 122.42,147.29 122.42,146.97 122.3,146.86 121.62,146.86 121.51,146.74 121.51,146.17 127.09,140.59 127.09,120.43 128.69,118.84 128.69,115.17 128.37,114.85 U1.G28
DDR_MA13: length 64.6
  TOP w0.14: J1.232 140.2,165.49 141.1,164.59 141.1,163.64 142.05,162.69 142.05,161.45 144.25,159.26 145.67,159.26 146.02,158.91 146.02,156.88 146.44,156.46 146.44,148.5 146.32,148.39 145.73,148.39 145.62,148.27 145.62,147.93 145.73,147.82 146.32,147.82 146.44,147.7 146.44,147.36 146.32,147.25 145.73,147.25 145.62,147.13 145.62,146.79 145.73,146.68 146.32,146.68 146.44,146.56 146.44,146.22 146.32,146.11 145.73,146.11 145.62,145.99 145.62,145.65 145.73,145.54 146.32,145.54 146.44,145.42 146.44,145.08 146.32,144.97 145.73,144.97 145.62,144.85 145.62,144.51 145.73,144.4 146.32,144.4 146.44,144.28 146.44,142.24 144.87,140.68 144.87,117.76 143.17,116.06 143.17,114.26 142.77,113.86 U1.AE28
DDR_MA14: length 65.5
  TOP w0.14: U1.E27 126.36,113.02 126.36,113.82 126,114.18 126,115.17 124.3,116.88 124.3,131.61 124.03,131.87 123.78,131.87 123.66,131.99 123.66,132.22 123.78,132.33 124.18,132.33 124.3,132.45 124.3,132.67 124.18,132.79 123.78,132.79 123.66,132.9 123.66,133.13 123.78,133.25 124.18,133.25 124.3,133.36 124.3,133.59 124.18,133.7 123.78,133.7 123.66,133.82 123.66,134.05 123.78,134.16 124.18,134.16 124.3,134.27 124.3,134.5 124.18,134.62 123.78,134.62 123.66,134.73 123.66,134.96 123.78,135.07 124.18,135.07 124.3,135.19 124.3,135.42 124.18,135.53 123.78,135.53 123.66,135.65 123.66,135.87 123.78,135.99 124.18,135.99 124.3,136.1 124.3,136.69 123.92,137.07 123.92,137.59 119,142.51 119,147.6 118.82,147.78 118.48,147.78 118.37,147.89 118.37,153.26 117.58,154.05 117.58,155.56 116.98,156.16 115.18,156.16 113.67,157.67 113.67,161.1 113.18,161.59 113.18,162.77 113.73,163.32 113.73,165.95 J1.207
DDR_MA15: length 65.7
  TOP w0.14: U1.D28 125.57,113.82 125.57,114.85 123.66,116.75 123.66,130.85 123.16,131.35 123.16,137.58 117.11,143.62 117.11,144.3 117.23,144.42 117.83,144.42 117.95,144.53 117.95,145.1 117.83,145.21 117.23,145.21 117.11,145.33 117.11,145.9 117.23,146.01 117.83,146.01 117.95,146.13 117.95,146.7 117.83,146.81 117.23,146.81 117.11,146.93 117.11,147.5 117.23,147.61 117.83,147.61 117.95,147.72 117.95,148.29 117.83,148.41 117.23,148.41 117.11,148.52 117.11,149.09 117.23,149.21 117.83,149.21 117.95,149.32 117.95,149.89 117.83,150 117.23,150 117.11,150.12 117.11,150.69 117.23,150.8 117.83,150.8 117.95,150.92 117.95,151.49 117.83,151.6 117.23,151.6 117.11,151.71 117.11,152.29 117.23,152.4 117.83,152.4 117.95,152.51 117.95,153.08 117.83,153.2 117.26,153.2 117.14,153.31 117.14,155.4 116.81,155.74 114.52,155.74 113.06,157.2 113.06,161.14 112.84,161.35 112.84,163.71 J1.62
DDR_MAPAR_ERR: length 61.4
  TOP w0.14: J1.208 114.7,165.02 114.03,164.34 114.03,163.32 114.55,162.79 114.55,161.54 115.08,161.01 115.08,158.32 116.08,157.32 117.46,157.32 120.33,154.45 120.33,144.72 125.76,139.28 125.76,119.54 126.97,118.34 126.97,117 127.66,116.31 127.66,115.54 127.17,115.05 v2(127.17,113.82) U1.F28
DDR_MAPAR_OUT: length 70.8
  TOP w0.14: U1.V27 137.59,113.04 137.59,119.63 138.01,120.05 138.01,138.26 137.9,138.37 137.1,138.37 136.99,138.49 136.99,138.83 137.1,138.94 137.9,138.94 138.01,139.06 138.01,140.08 137.74,140.36 137.74,144.58 137.62,144.7 136.37,144.7 136.25,144.81 136.25,145.15 136.37,145.27 137.62,145.27 137.74,145.38 137.74,145.72 137.62,145.84 136.37,145.84 136.25,145.95 136.25,146.29 136.37,146.41 137.62,146.41 137.74,146.52 137.74,146.86 137.62,146.98 136.37,146.98 136.25,147.09 136.25,147.43 136.37,147.55 137.62,147.55 137.74,147.66 137.74,148 137.62,148.12 136.37,148.12 136.25,148.23 136.25,148.57 136.37,148.69 137.62,148.69 137.74,148.8 137.74,150.53 137.1,151.17 137.1,155.77 133.03,159.83 133.03,161.61 133.22,161.79 133.22,162.56 132.4,163.39 132.4,164.34 131.7,165.04 J1.222
DDR_MBA0: length 65.7
  TOP w0.14: J1.81 134.25,159.63 135.89,157.99 137.23,157.99 137.68,157.53 137.88,157.53 138.25,157.9 138.45,157.9 138.62,157.73 138.62,157.54 138.25,157.16 138.25,156.97 138.68,156.54 138.68,156 138.79,155.89 139.52,155.89 139.64,155.77 139.64,155.43 139.52,155.32 138.79,155.32 138.68,155.2 138.68,154.86 138.79,154.75 139.52,154.75 139.64,154.63 139.64,154.29 139.52,154.18 138.79,154.18 138.68,154.06 138.68,153.72 138.79,153.61 139.52,153.61 139.64,153.49 139.64,153.15 139.52,153.04 138.79,153.04 138.68,152.92 138.68,152.58 138.79,152.47 139.52,152.47 139.64,152.35 139.64,152.01 139.52,151.9 138.79,151.9 138.68,151.78 138.68,151.51 138.82,151.38 139.5,151.38 139.64,151.24 139.64,150.99 139.5,150.85 138.82,150.85 138.68,150.71 138.68,150.47 138.82,150.33 139.5,150.33 139.64,150.19 139.64,149.95 139.5,149.81 138.82,149.81 138.68,149.67 138.68,149.43 138.82,149.29 139.5,149.29 139.64,149.15 139.64,148.91 139.5,148.77 138.82,148.77 138.68,148.63 138.68,142.52 138.82,142.38 139.3,142.38 139.44,142.24 139.44,142 139.3,141.86 138.82,141.86 138.68,141.72 138.68,140.92 139.16,140.43 139.16,119.03 138.77,118.64 138.77,118.64 U1.Y28
DDR_MBA1: length 64.7
  TOP w0.14: J1.224 133.4,165.01 132.73,164.34 132.73,163.53 133.54,162.71 133.54,159.83 136.14,157.23 136.34,157.23 136.74,157.63 136.9,157.63 137.12,157.41 137.12,157.25 136.81,156.94 136.81,156.74 136.99,156.55 137.19,156.55 137.48,156.85 137.68,156.85 137.86,156.67 137.86,156.47 137.57,156.17 137.57,155.98 137.7,155.85 138.05,155.85 138.18,155.72 138.18,155.52 138.04,155.38 137.61,155.38 137.47,155.24 137.47,155.03 137.62,154.88 138.05,154.88 138.19,154.74 138.19,154.49 138.08,154.37 137.56,154.37 137.45,154.26 137.45,153.92 137.56,153.8 138.08,153.8 138.19,153.69 138.19,153.35 138.08,153.23 137.56,153.23 137.45,153.12 137.45,152.78 137.56,152.66 138.08,152.66 138.19,152.55 138.19,152.21 138.08,152.09 137.56,152.09 137.45,151.98 137.45,151.64 137.56,151.52 138.08,151.52 138.19,151.41 138.19,140.7 138.65,140.24 138.65,119.54 138.14,119.03 138.14,114.84 138.28,114.71 138.28,113.73 U1.W28
DDR_MBA2: length 66
  TOP w0.14: U1.E28 126.77,114.12 126.42,114.46 126.42,115.52 124.93,117 124.93,137.96 122.59,140.3 122.59,140.5 123.06,140.96 123.06,141.16 122.89,141.33 122.69,141.33 122.23,140.86 122.03,140.86 121.86,141.03 121.86,141.23 122.33,141.7 122.33,141.9 122.15,142.07 121.96,142.07 121.49,141.6 121.29,141.6 121.12,141.77 121.12,141.97 121.59,142.44 121.59,142.63 121.42,142.8 121.22,142.8 120.75,142.34 120.56,142.34 120.38,142.51 120.38,142.7 120.85,143.17 120.85,143.37 120.68,143.54 120.48,143.54 120.02,143.07 119.82,143.07 119.58,143.31 119.58,148.35 119.47,148.46 119.1,148.46 118.99,148.58 118.99,148.92 119.1,149.03 119.47,149.03 119.58,149.15 119.58,149.49 119.47,149.6 119.1,149.6 118.99,149.72 118.99,150.06 119.1,150.17 119.47,150.17 119.58,150.29 119.58,150.56 119.44,150.7 119.08,150.7 118.94,150.84 118.94,151.08 119.08,151.22 119.44,151.22 119.58,151.36 119.58,151.6 119.44,151.74 119.08,151.74 118.94,151.88 118.94,152.12 119.08,152.26 119.44,152.26 119.58,152.4 119.58,152.64 119.44,152.78 119.08,152.78 118.94,152.92 118.94,153.16 119.08,153.3 119.44,153.3 119.58,153.44 119.58,154.14 117.15,156.58 115.73,156.58 114.34,157.97 114.34,161.13 113.85,161.62 J1.63
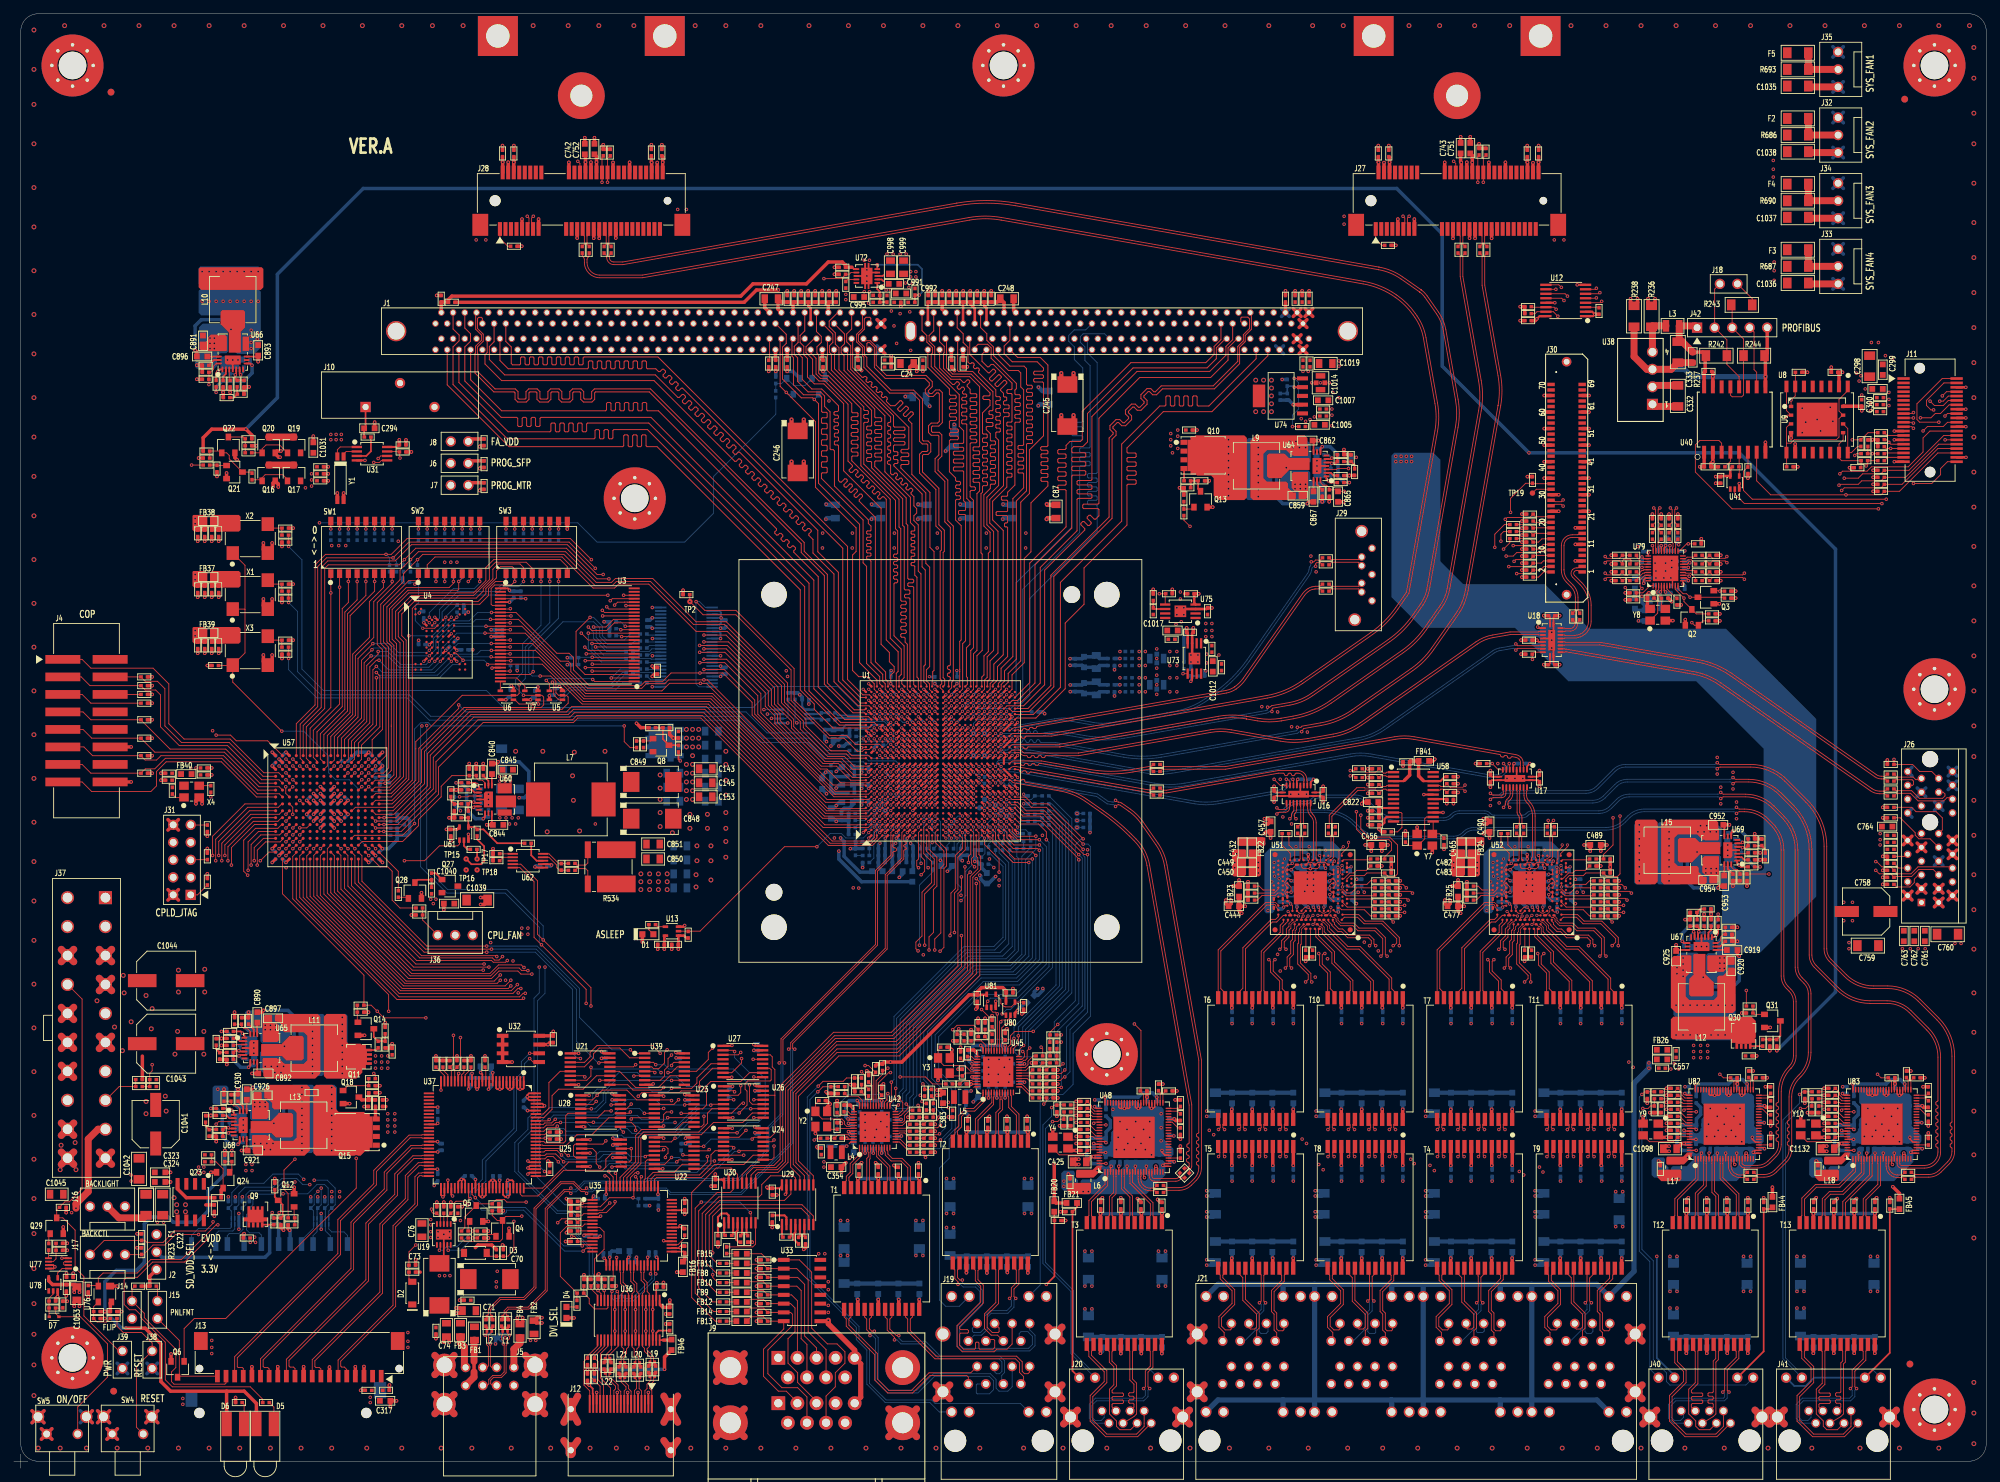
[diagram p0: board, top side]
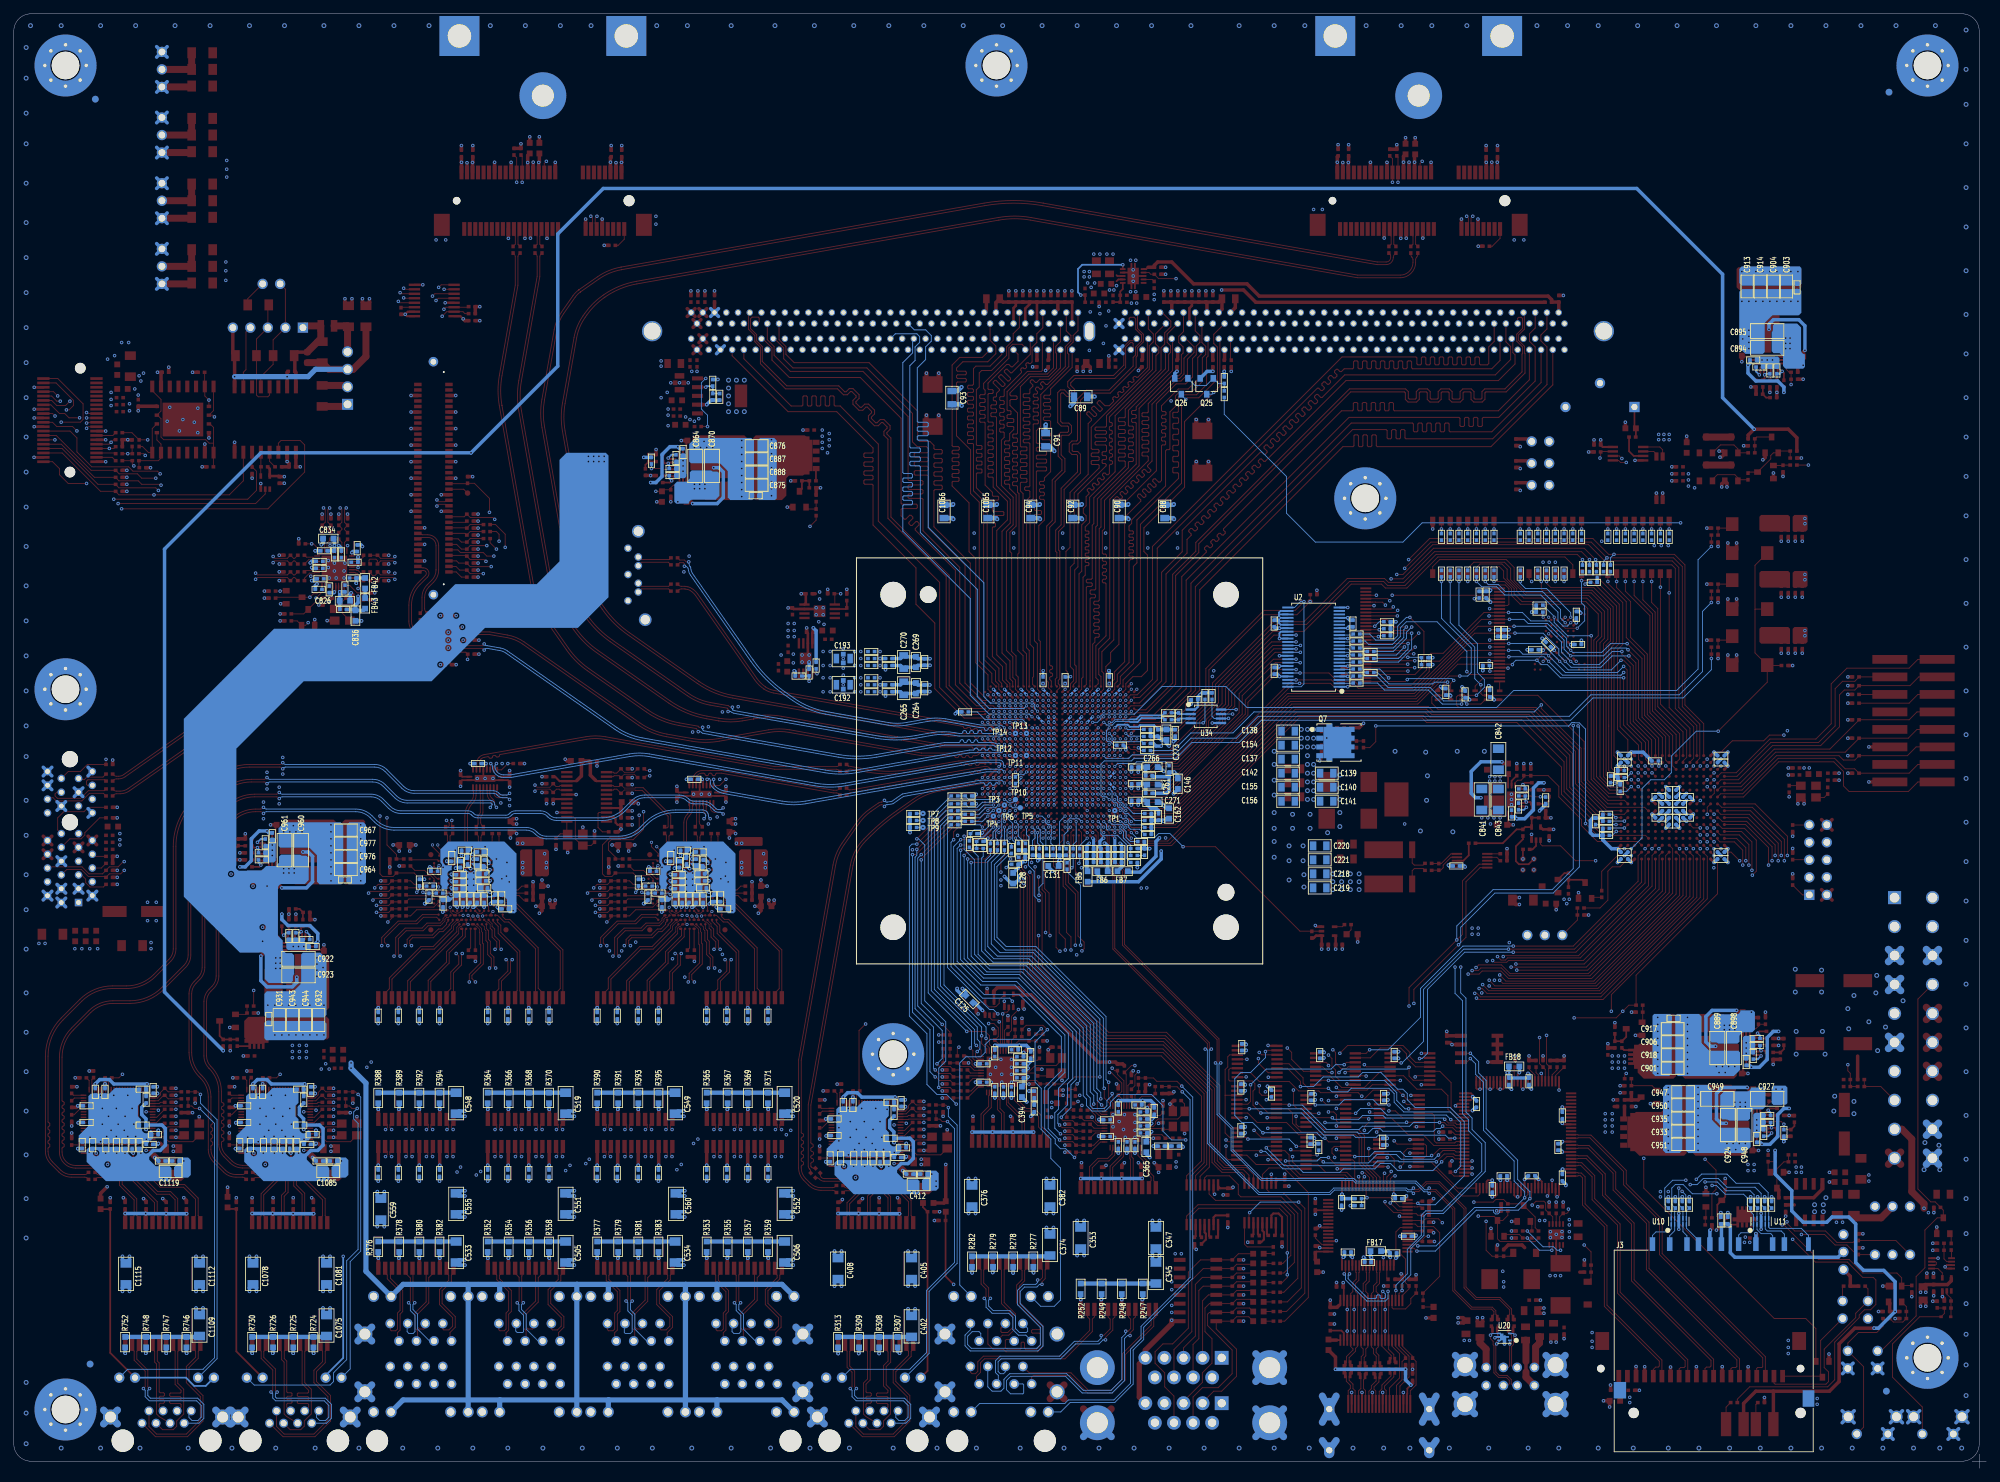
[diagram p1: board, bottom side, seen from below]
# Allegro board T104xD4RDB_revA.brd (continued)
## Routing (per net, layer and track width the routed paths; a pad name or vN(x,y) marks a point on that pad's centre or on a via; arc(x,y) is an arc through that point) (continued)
DDR_MCAS_N: length 65.3
  TOP w0.14: U1.AC28 141.17,114.14 141.57,114.54 141.57,117.12 142.71,118.27 142.71,135.93 141.52,137.13 141.52,140.56 143.52,142.56 143.52,152.45 143.63,152.56 144.22,152.56 144.33,152.68 144.33,153.02 144.22,153.13 143.63,153.13 143.52,153.25 143.52,153.59 143.63,153.71 144.22,153.71 144.33,153.82 144.33,154.16 144.22,154.28 143.63,154.28 143.52,154.39 143.52,154.73 143.66,154.87 143.86,154.87 143.98,154.98 143.98,155.3 143.86,155.42 143.63,155.42 143.52,155.53 143.52,155.95 143.1,156.37 143.1,156.53 143.99,157.43 143.99,157.59 143.75,157.83 143.59,157.83 142.69,156.94 142.53,156.94 142.29,157.18 142.29,157.34 143.19,158.24 143.19,158.4 142.94,158.64 142.78,158.64 141.89,157.74 141.72,157.74 141.48,157.99 141.48,158.15 142.38,159.04 142.38,159.21 142.14,159.45 141.98,159.45 141.46,158.93 141.3,158.93 138.62,161.61 138.62,163.75 J1.86
DDR_MCK0_N: length 65.7
  TOP w0.14: J1.75 123.7,162.62 123.7,163.17 123.84,163.31 124.09,163.31 124.79,162.61 124.79,159.69 126.37,158.12 132.1,158.12 132.75,157.46 132.75,157.09 132.18,156.52 132.18,155.97 132.67,155.48 133.31,155.48 133.84,156.01 134.07,156.01 134.21,155.87 134.21,151.88 133.96,151.63 133.03,151.63 132.64,151.25 132.64,150.25 133.03,149.86 134.02,149.86 134.14,149.74 134.14,147.02 133.6,146.47 133.6,144.59 135.01,143.18 135.01,137.31 135.81,136.51 135.81,116.55 135.67,116.41 135.52,116.41 135.38,116.27 135.38,116.03 135.52,115.89 135.67,115.89 135.81,115.75 135.81,115.51 135.67,115.37 135.52,115.37 135.38,115.23 135.38,114.99 135.52,114.85 135.67,114.85 135.81,114.71 135.81,114.45 135.57,114.21 U1.T28
DDR_MCK0_P: length 65.6
  TOP w0.14: U1.T27 135.57,112.81 136,113.24 136,114.03 136.24,114.27 136.24,136.69 135.44,137.49 135.44,143.36 134.03,144.77 134.03,146.29 134.57,146.84 134.57,149.92 134.2,150.29 133.21,150.29 133.08,150.43 133.08,151.07 133.21,151.2 134.14,151.2 134.64,151.7 134.64,156.05 134.25,156.44 133.66,156.44 133.13,155.92 132.85,155.92 132.61,156.15 132.61,156.34 133.19,156.91 133.19,157.64 132.28,158.55 126.54,158.55 125.06,160.03 125.06,162.73 124.2,163.58 123.49,163.58 J1.74
DDR_MCK1_N: length 64.7
  TOP w0.14: J1.219 124.27,166.29 124.27,166.84 124.13,166.98 123.57,166.98 123.33,166.74 123.33,165.24 122.49,164.41 122.49,163.51 123.36,162.65 123.36,161.5 123.7,161.16 123.7,159.91 127.19,156.42 130.48,156.42 131.77,155.12 131.77,149.17 131.91,149.03 132.58,149.03 132.97,148.64 132.97,147.47 132.58,147.08 131.91,147.08 131.77,146.94 131.77,144.54 134.14,142.17 134.14,136.88 134.94,136.08 134.94,133.03 134.76,132.86 134.76,114.7 134.99,114.48 134.99,113.64 U1.R28
DDR_MCK1_P: length 64.7
  TOP w0.14: J1.218 123.06,167.54 123.06,165.35 122.22,164.52 122.22,163.4 123.09,162.54 123.09,161.39 123.27,161.21 123.27,159.73 127.01,155.98 130.3,155.98 131.34,154.94 131.34,149 131.74,148.6 132.4,148.6 132.54,148.46 132.54,147.65 132.4,147.51 131.73,147.51 131.34,147.12 131.34,144.36 133.71,142 133.71,136.7 134.5,135.9 134.5,133.21 134.33,133.04 134.33,114.52 134.56,114.3 134.56,113.82 134.33,113.6 134.33,113.24 134.77,112.81 U1.R27
DDR_MCKE0: length 59.4
  TOP w0.14: J1.60 111.13,163.7 111.13,156.97 v1(112.01,156.08) 116.25,151.85 116.25,142.33 122.14,136.43 122.14,133 121.63,132.5 121.63,115.73 122.52,114.84 123.74,114.84 124.77,113.82 124.77,113.02 U1.C27
  BOTTOM w0.14: v1(112.01,156.08) 112.28,155.82 Q25.3
DDR_MCKE1: length 61.2
  TOP w0.14: J1.203 112.01,164.51 112.01,163.19 111.48,162.66 111.48,158.02 114.19,155.3 115.84,155.3 v1(116.08,155.07) 116.69,154.45 116.69,142.9 122.65,136.94 122.65,116.87 125.17,114.36 U1.C28
  BOTTOM w0.14: v1(116.08,155.07) 116.71,155.7 Q26.3
DDR_MCS0_N: length 66
  TOP w0.14: J1.84 136.87,163.8 136.87,159.27 137.01,159.13 139.03,159.13 141.98,156.18 141.98,153.54 141.87,153.43 141.53,153.43 141.41,153.31 141.41,152.97 141.53,152.86 141.87,152.86 141.98,152.74 141.98,152.4 141.87,152.29 141.13,152.29 141.01,152.17 141.01,151.83 141.13,151.72 141.87,151.72 141.98,151.6 141.98,151.26 141.87,151.15 141.13,151.15 141.01,151.03 141.01,150.69 141.61,150.1 141.61,149.16 141.72,149.04 142.23,149.04 142.35,148.93 142.35,148.59 142.23,148.47 141.72,148.47 141.61,148.36 141.61,148.02 141.72,147.9 142.23,147.9 142.35,147.79 142.35,147.45 142.23,147.33 141.72,147.33 141.61,147.22 141.61,146.88 141.72,146.76 142.23,146.76 142.35,146.65 142.35,146.31 142.23,146.19 141.72,146.19 141.61,146.08 141.61,145.74 141.72,145.62 142.23,145.62 142.35,145.51 142.35,145.17 142.23,145.05 141.72,145.05 141.61,144.94 141.61,144.6 141.72,144.48 142.23,144.48 142.35,144.37 142.35,144.03 142.23,143.91 141.72,143.91 141.61,143.8 141.61,143.46 141.72,143.34 142.23,143.34 142.35,143.23 142.35,142.89 142.23,142.77 141.72,142.77 141.61,142.66 141.61,142.16 140.67,141.22 140.67,136.7 141.57,135.8 141.57,133 141.32,132.75 141.32,118.48 140.68,117.85 140.68,115.1 140.37,114.78 U1.AB28
DDR_MCS1_N: length 65.6
  TOP w0.14: U1.AC27 141.58,113.03 141.58,113.84 142.11,114.38 142.11,116.66 143.48,118.02 143.48,136.05 141.94,137.59 141.94,140.29 144,142.35 144,143.67 144.11,143.79 144.63,143.79 144.75,143.9 144.75,144.24 144.63,144.36 144.11,144.36 144,144.47 144,144.81 144.11,144.93 144.63,144.93 144.75,145.04 144.75,145.38 144.63,145.5 144.11,145.5 144,145.61 144,145.95 144.11,146.07 144.63,146.07 144.75,146.18 144.75,146.52 144.63,146.64 144.11,146.64 144,146.75 144,147.09 144.11,147.21 144.63,147.21 144.75,147.32 144.75,147.66 144.63,147.78 144.11,147.78 144,147.89 144,148.23 144.11,148.35 144.63,148.35 144.75,148.46 144.75,148.8 144.63,148.92 144.11,148.92 144,149.03 144,149.38 144.11,149.49 144.63,149.49 144.75,149.6 144.75,149.95 144.63,150.06 144.11,150.06 144,150.17 144,150.52 144.11,150.63 144.63,150.63 144.75,150.74 144.75,151.09 144.63,151.2 144.11,151.2 144,151.31 144,151.66 144.11,151.77 144.63,151.77 144.75,151.88 144.75,155.81 144.63,155.92 144.12,155.92 144.01,156.04 144.01,156.38 144.12,156.49 144.63,156.49 144.75,156.61 144.75,157.43 142.04,160.14 141.73,160.14 141.39,159.8 141.19,159.8 140.4,160.59 140.4,161.62 J1.89
DDR_MCS2_N: length 64.9
  TOP w0.14: U1.AG27 144.75,113 144.75,115.11 146.52,116.88 146.52,131.99 147.5,132.96 147.5,140.06 149.95,142.51 149.95,143.07 149.84,143.18 149.07,143.18 148.95,143.3 148.95,143.64 149.07,143.75 149.84,143.75 149.95,143.87 149.95,144.21 149.84,144.32 149.07,144.32 148.95,144.44 148.95,144.78 149.07,144.89 149.84,144.89 149.95,145.01 149.95,145.35 149.84,145.46 149.07,145.46 148.95,145.58 148.95,145.92 149.07,146.03 149.84,146.03 149.95,146.15 149.95,146.49 149.84,146.6 149.07,146.6 148.95,146.72 148.95,147.06 149.07,147.17 149.84,147.17 149.95,147.29 149.95,147.55 149.81,147.69 149.05,147.69 148.91,147.83 148.91,148.08 149.05,148.21 149.81,148.21 149.95,148.35 149.95,160.05 148.84,161.16 145.56,161.16 J1.93
DDR_MCS3_N: length 64.9
  TOP w0.14: J1.237 144.45,163.65 143.61,162.81 143.61,161.7 144.78,160.53 148.4,160.53 149.32,159.61 149.32,159.3 149.18,159.16 148.03,159.16 147.89,159.02 147.89,158.78 148.03,158.64 149.18,158.64 149.32,158.5 149.32,158.26 149.18,158.12 148.03,158.12 147.89,157.98 147.89,157.74 148.03,157.6 149.18,157.6 149.32,157.46 149.32,149.79 147.27,147.75 147.27,141.41 146.02,140.15 146.02,117.13 144.2,115.31 144.2,114.05 U1.AF28
DDR_MDM0: length 106.2
  TOP w0.14: U1.B22 123.95,109.03 120.97,109.03 116.65,113.35 116.65,129.35 113.1,132.9 113.1,133.1 113.34,133.35 113.34,133.54 113.08,133.8 112.89,133.8 112.64,133.56 112.44,133.56 112.18,133.82 112.18,134.01 112.43,134.26 112.43,134.46 112.17,134.72 111.97,134.72 111.72,134.47 111.53,134.47 111.27,134.73 111.27,134.93 111.51,135.18 111.51,135.38 111.25,135.64 111.05,135.64 110.81,135.39 110.61,135.39 110.35,135.65 110.35,135.85 110.6,136.09 110.6,136.29 93.47,153.42 91.92,153.42 91.78,153.56 91.78,154.48 91.64,154.62 91.27,154.62 91.13,154.48 91.13,153.56 90.99,153.42 90.62,153.42 90.48,153.56 90.48,154.48 90.34,154.62 89.97,154.62 89.83,154.48 89.83,153.56 89.69,153.42 89.32,153.42 89.19,153.56 89.19,154.48 89.05,154.62 88.68,154.62 88.54,154.48 88.54,153.56 88.4,153.42 88.03,153.42 87.89,153.56 87.89,154.48 87.75,154.62 87.38,154.62 87.24,154.48 87.24,153.56 87.1,153.42 86.73,153.42 86.59,153.56 86.59,154.48 86.45,154.62 86.09,154.62 85.95,154.48 85.95,153.56 85.81,153.42 70.74,153.42 66.25,157.91 J1.7
DDR_MDM1: length 92.3
  TOP w0.14: U1.C25 v2(124.77,111.42)
  L3SIG w0.114: v2(124.77,111.42) 124.35,111 123.25,111 120.46,113.79 120.46,125.29 112.71,133.03 111.63,133.03 103.57,141.1 103.41,141.1 103.06,140.75 102.9,140.75 102.62,141.03 102.62,141.19 102.97,141.54 102.97,141.7 102.66,142.01 102.49,142.01 102.05,141.57 101.89,141.57 101.61,141.85 101.61,142.01 102.05,142.45 102.05,142.61 101.78,142.89 101.61,142.89 101.17,142.45 101.01,142.45 100.73,142.73 100.73,142.89 101.17,143.33 101.17,143.49 100.9,143.77 100.73,143.77 100.29,143.33 100.13,143.33 99.85,143.61 99.85,143.77 100.29,144.21 100.29,144.37 100.02,144.65 99.85,144.65 99.41,144.21 99.25,144.21 98.97,144.49 98.97,144.65 99.41,145.09 99.41,145.25 99.13,145.53 98.97,145.53 98.53,145.09 98.37,145.09 98.09,145.37 98.09,145.53 98.53,145.97 98.53,146.13 98.25,146.41 98.09,146.41 97.65,145.97 97.49,145.97 97.21,146.25 97.21,146.41 97.65,146.85 97.65,147.01 97.37,147.29 97.21,147.29 96.77,146.85 96.61,146.85 95.89,147.57 85.73,147.57 75.76,157.54 75.76,163.72 J1.18
DDR_MDM2: length 89.6
  TOP w0.14: U1.F23 v2(127.17,109.82)
  L6SIG w0.114: J1.29 84.95,159.08 98.68,145.35 108.52,145.35 108.76,145.11 108.76,144.95 108.13,144.32 108.13,144.16 108.4,143.88 108.57,143.88 109.2,144.51 109.36,144.51 109.64,144.23 109.64,144.07 109.01,143.44 109.01,143.28 109.29,143 109.45,143 110.08,143.63 110.24,143.63 110.52,143.35 110.52,143.19 109.89,142.56 109.89,142.4 110.17,142.12 110.33,142.12 110.96,142.75 111.12,142.75 111.4,142.47 111.4,142.31 110.77,141.68 110.77,141.52 111.05,141.24 111.21,141.24 111.84,141.87 112,141.87 112.28,141.59 112.28,141.43 111.65,140.8 111.65,140.64 111.93,140.36 112.09,140.36 112.72,140.99 112.88,140.99 113.16,140.71 113.16,140.55 112.53,139.92 112.53,139.76 112.81,139.48 112.97,139.48 113.6,140.11 113.76,140.11 114.43,139.45 114.43,133.54 122.68,125.29 122.68,111.82 124.28,110.23 126.5,110.23 126.91,109.82 v2(127.17,109.82)
DDR_MDM3: length 87.4
  TOP w0.14: U1.K26 v2(130.37,112.22)
  L3SIG w0.114: J1.40 94.49,163.68 94.49,159.83 98.87,155.45 114.74,155.45 125.58,144.61 125.58,144.45 124.47,143.34 124.47,143.18 124.75,142.9 124.91,142.9 126.02,144.01 126.18,144.01 126.46,143.73 126.46,143.57 125.35,142.46 125.35,142.3 125.63,142.02 125.79,142.02 126.9,143.13 127.06,143.13 127.34,142.85 127.34,142.69 126.23,141.58 126.23,141.42 126.51,141.14 126.67,141.14 127.78,142.25 127.94,142.25 128.22,141.97 128.22,141.81 127.11,140.7 127.11,140.54 127.95,139.7 127.95,136.84 129.41,135.38 129.41,116.9 129.79,116.52 129.79,112.84 130.37,112.27 v2(130.37,112.22)
DDR_MDM4: length 70.8
  TOP w0.14: U1.U26 v2(136.77,112.22)
  L3SIG w0.114: v2(136.77,112.22) 136.77,112.41 136.33,112.84 136.33,114.05 138.37,116.08 138.37,134.62 138.48,134.73 140.03,134.73 140.14,134.85 140.14,135.24 140.03,135.36 138.48,135.36 138.37,135.47 138.37,136.02 148.02,145.67 148.02,146.1 148.13,146.21 148.73,146.21 148.84,146.32 148.84,146.72 148.73,146.83 148.13,146.83 148.02,146.95 148.02,147.34 148.13,147.46 148.73,147.46 148.84,147.57 148.84,147.96 148.73,148.08 148.13,148.08 148.02,148.19 148.02,148.59 148.13,148.7 148.73,148.7 148.84,148.81 148.84,149.21 148.73,149.32 148.13,149.32 148.02,149.44 148.02,149.83 148.13,149.94 148.73,149.94 148.84,150.06 148.84,150.45 148.73,150.57 148.13,150.57 148.02,150.68 148.02,151.07 148.13,151.19 148.73,151.19 148.84,151.3 148.84,151.7 148.73,151.81 148.13,151.81 148.02,151.93 148.02,152.32 148.13,152.43 148.73,152.43 148.84,152.55 148.84,152.94 148.73,153.06 148.13,153.06 148.02,153.17 148.02,155.45 148.13,155.56 148.79,155.56 148.91,155.68 148.91,156.07 148.79,156.19 148.13,156.19 148.02,156.3 148.02,157.94 148.13,158.05 148.73,158.05 148.84,158.17 148.84,158.56 148.73,158.68 148.13,158.68 148.02,158.79 148.02,159.19 149.55,160.72 J1.99
DDR_MDM5: length 76.3
  TOP w0.14: U1.Y24 v2(139.17,110.62)
  BOTTOM w0.137: 143.51,110.22 139.56,110.22
  BOTTOM w0.14: 139.56,110.22 v2(139.17,110.62) ; 143.51,110.22 144.57,110.22 146.3,111.95 146.3,127.51 154.56,135.76 154.56,145.3 154.7,145.44 155.94,145.44 156.08,145.58 156.08,145.95 155.94,146.09 154.7,146.09 154.56,146.23 154.56,146.59 154.7,146.73 155.94,146.73 156.08,146.87 156.08,147.24 155.94,147.38 154.7,147.38 154.56,147.52 154.56,147.89 154.7,148.03 155.94,148.03 156.08,148.17 156.08,159.96 155.32,160.72 155.32,162.67 154.66,163.33 154.66,164.19 155.07,164.59 158.18,164.59 J1.110
DDR_MDM6: length 77.9
  TOP w0.14: U1.AD24 v2(142.37,110.62)
  L3SIG w0.114: J1.121 168.25,158.79 163.64,154.18 163.64,145.8 155.2,137.36 155.2,137.2 156.15,136.25 156.15,136.09 155.87,135.81 155.71,135.81 154.76,136.76 154.6,136.76 154.32,136.48 154.32,136.32 155.27,135.37 155.27,135.21 154.99,134.93 154.83,134.93 153.88,135.88 153.72,135.88 153.44,135.6 153.44,135.44 154.39,134.49 154.39,134.33 154.11,134.05 153.95,134.05 153,135 152.84,135 152.56,134.72 152.56,134.56 153.51,133.61 153.51,133.45 153.23,133.17 153.07,133.17 152.12,134.12 151.96,134.12 151.68,133.84 151.68,133.68 152.63,132.73 152.63,132.57 152.35,132.29 152.19,132.29 151.24,133.24 151.08,133.24 150.11,132.27 150.11,124.71 145.99,120.59 145.99,114.24 144.35,112.6 143.72,112.6 143.55,112.44 143.55,111.99 143.36,111.8 143.01,111.8 142.75,111.55 142.75,111 v2(142.37,110.62)
DDR_MDM7: length 83.4
  TOP w0.14: J1.132 177.4,163.87 176.08,162.55 176.08,160.77 173.55,158.24 163.26,158.24 157.35,152.34 157.35,140.01 157.21,139.87 155.14,139.87 155,139.73 155,139.36 155.14,139.22 157.21,139.22 157.35,139.08 157.35,138.18 156.87,137.7 156.68,137.7 156.11,138.26 155.91,138.26 155.65,138 155.65,137.8 156.22,137.24 156.22,137.04 155.96,136.78 155.76,136.78 155.19,137.34 155,137.34 154.74,137.08 154.74,136.89 155.3,136.32 155.3,136.12 149.48,130.3 149.48,113.66 146.43,110.62 144.02,110.62 143.62,110.22 U1.AF24
DDR_MDM8: length 83.9
  TOP w0.14: U1.N24 v2(132.77,110.62)
  L6SIG w0.114: v2(132.77,110.62) 133.15,111 133.15,113.23 132.33,114.05 132.33,130.18 129.73,132.78 129.73,142.24 129.37,142.61 129.37,142.77 129.78,143.18 129.78,143.34 129.5,143.62 129.34,143.62 128.93,143.21 128.76,143.21 128.48,143.49 128.48,143.65 128.89,144.06 128.89,144.22 128.62,144.5 128.45,144.5 128.04,144.09 127.88,144.09 127.6,144.37 127.6,144.53 128.01,144.94 128.01,145.1 127.74,145.38 127.57,145.38 127.16,144.97 127,144.97 126.72,145.25 126.72,145.41 127.13,145.82 127.13,145.98 126.86,146.26 126.69,146.26 126.28,145.85 126.12,145.85 125.84,146.13 125.84,146.29 126.25,146.7 126.25,146.86 125.98,147.14 125.81,147.14 125.4,146.73 125.24,146.73 124.96,147.01 124.96,147.17 125.37,147.58 125.37,147.74 125.09,148.02 124.93,148.02 124.52,147.61 124.36,147.61 124.08,147.89 124.08,148.05 124.49,148.46 124.49,148.62 124.21,148.9 124.05,148.9 123.64,148.49 123.48,148.49 123.2,148.77 123.2,148.93 123.61,149.34 123.61,149.5 123.33,149.78 123.17,149.78 122.76,149.37 122.6,149.37 122.32,149.65 122.32,149.81 122.73,150.22 122.73,150.38 122.45,150.66 122.29,150.66 121.88,150.25 121.72,150.25 121.44,150.53 121.44,150.69 121.85,151.1 121.85,151.26 121.57,151.54 121.41,151.54 121,151.13 120.84,151.13 120.56,151.41 120.56,151.57 120.97,151.98 120.97,152.14 120.69,152.42 120.53,152.42 120.12,152.01 119.96,152.01 117.6,154.37 109.92,154.37 103.65,160.64 J1.51
DDR_MDQS0_N: length 106
  TOP w0.14: J1.152 66.98,167.55 66.98,165.24 67.81,164.42 67.81,163.62 66.96,162.78 66.96,161.81 66.88,161.73 66.88,158.89 69.61,156.16 72.55,156.16 72.69,156.02 72.69,155.08 73.08,154.69 74.31,154.69 74.71,155.08 74.71,156.02 74.84,156.16 75.72,156.16 75.86,156.02 75.86,155.08 76.25,154.69 77.49,154.69 77.88,155.08 77.88,156.02 78.02,156.16 78.9,156.16 79.04,156.02 79.04,155.08 79.43,154.69 80.66,154.69 81.06,155.08 81.06,156.02 81.19,156.16 82.07,156.16 82.21,156.02 82.21,155.08 82.6,154.69 83.84,154.69 84.23,155.08 84.23,156.02 84.37,156.16 92.15,156.16 114.19,134.12 114.19,132.85 117.54,129.5 117.54,113.75 121.69,109.6 123.38,109.6 U1.A23
DDR_MDQS0_P: length 106
  TOP w0.14: U1.A24 123.38,110.03 121.87,110.03 117.97,113.93 117.97,129.68 114.62,133.03 114.62,134.3 92.33,156.59 84.19,156.59 83.8,156.2 83.8,155.26 83.66,155.12 82.78,155.12 82.64,155.26 82.64,156.2 82.25,156.59 81.02,156.59 80.62,156.2 80.62,155.26 80.48,155.12 79.61,155.12 79.47,155.26 79.47,156.2 79.08,156.59 77.84,156.59 77.45,156.2 77.45,155.26 77.31,155.12 76.43,155.12 76.29,155.26 76.29,156.2 75.9,156.59 74.67,156.59 74.27,156.2 74.27,155.26 74.13,155.12 73.26,155.12 73.12,155.26 73.12,156.2 72.73,156.59 69.79,156.59 67.31,159.07 67.31,161.65 67.23,161.73 67.23,162.67 68.07,163.51 68.07,164.53 67.25,165.35 67.25,166.81 67.4,166.97 67.81,166.97 67.95,166.83 J1.153
DDR_MDQS1_N: length 92.4
  TOP w0.14: U1.D25 v2(125.57,111.42)
  L3SIG w0.114: v2(125.57,111.42) 125.16,111.82 123.19,111.82 121.54,113.47 121.54,125.41 98.32,148.63 86.32,148.63 84.18,150.77 84.18,151.27 84.86,151.96 84.86,152.12 84.22,152.76 84.06,152.76 83.38,152.07 82.88,152.07 82,152.95 82,153.45 82.69,154.13 82.69,154.29 82.05,154.93 81.89,154.93 81.2,154.25 80.7,154.25 79.83,155.12 79.83,155.62 80.51,156.3 80.51,156.47 79.87,157.1 79.71,157.1 79.03,156.42 78.53,156.42 77.06,157.89 77.06,161.98 77.15,162.06 77.15,162.63 76.33,163.45 76.33,164.74 77.22,165.63 77.22,166.31 77.09,166.43 76.81,166.43 J1.163
DDR_MDQS1_P: length 92.4
  TOP w0.14: U1.D26 v2(125.57,112.22)
  L3SIG w0.114: v2(125.57,112.22) 125.13,112.65 124.59,112.65 124.17,112.23 123.36,112.23 121.95,113.64 121.95,125.58 98.49,149.03 86.49,149.03 84.58,150.94 84.58,151.1 85.27,151.79 85.27,152.29 84.39,153.16 83.89,153.16 83.21,152.48 83.05,152.48 82.41,153.12 82.41,153.28 83.09,153.96 83.09,154.46 82.22,155.34 81.72,155.34 81.03,154.65 80.87,154.65 80.23,155.29 80.23,155.45 80.92,156.14 80.92,156.63 80.04,157.51 79.54,157.51 78.86,156.83 78.7,156.83 77.47,158.05 77.47,161.74 77.4,161.81 77.4,161.97 77.39,161.98 77.39,162.73 76.57,163.55 76.57,164.64 77.46,165.53 77.46,167.51 J1.164
DDR_MDQS2_N: length 90
  TOP w0.14: U1.G23 v2(127.97,109.82)
  L6SIG w0.114: v2(127.97,109.82) 127.97,110.04 127.56,110.45 127.56,110.77 127.3,111.03 127.01,111.03 126.78,111.26 126.78,114.27 125.9,115.15 125.9,127.09 120.12,132.86 120.12,138.83 117.96,140.99 117.96,141.49 118.87,142.4 118.87,142.56 118.23,143.2 118.07,143.2 117.16,142.29 116.66,142.29 115.79,143.16 115.79,143.66 116.69,144.57 116.69,144.73 116.06,145.37 115.89,145.37 114.99,144.46 114.49,144.46 113.45,145.5 113.45,146.96 112.33,148.08 100.52,148.08 89,159.6 89,161.7 89.08,161.79 89.08,162.54 88.21,163.41 88.21,164.43 87.78,164.86 86.2,164.86 85.67,165.38 85.67,167.55 J1.174
DDR_MDQS2_P: length 89.9
  TOP w0.14: U1.G24 v2(127.97,110.62)
  L6SIG w0.114: v2(127.97,110.62) 127.97,110.87 127.81,111.03 127.67,111.16 127.58,111.26 127.58,114.04 126.3,115.32 126.3,127.25 120.52,133.03 120.52,139 118.37,141.16 118.37,141.32 119.27,142.23 119.27,142.73 118.4,143.6 117.9,143.6 116.99,142.69 116.83,142.69 116.19,143.33 116.19,143.49 117.1,144.4 117.1,144.9 116.22,145.78 115.73,145.78 114.82,144.87 114.66,144.87 113.86,145.67 113.86,147.13 112.5,148.49 100.69,148.49 89.41,159.77 89.41,161.7 89.33,161.79 89.33,162.64 88.46,163.51 88.46,164.53 87.88,165.1 86.3,165.1 85.92,165.48 85.92,166.83 86.09,167 86.68,167 86.87,166.81 86.87,166.29 J1.175
DDR_MDQS3_N: length 88.2
  TOP w0.14: U1.K25 v2(130.37,111.42)
  L3SIG w0.114: v2(130.37,111.42) 130.75,111.8 130.75,113.66 130.37,114.05 130.37,136.39 129.45,137.31 129.45,144.42 125.34,148.53 125.18,148.53 124.69,148.03 124.19,148.03 123.31,148.91 123.31,149.41 123.81,149.9 123.81,150.06 123.17,150.7 123.01,150.7 122.51,150.21 122.02,150.21 121.14,151.08 121.14,151.58 121.63,152.08 121.63,152.24 121,152.88 120.83,152.88 120.34,152.38 119.84,152.38 118.97,153.26 118.97,153.76 119.46,154.25 119.46,154.41 117.22,156.65 99.17,156.65 95.82,160.01 95.82,161.73 95.88,161.79 95.88,162.7 96.72,163.55 96.72,164.43 95.9,165.25 95.9,166.51 95.78,166.62 95.26,166.62 95.15,166.51 J1.185
DDR_MDQS3_P: length 88.3
  TOP w0.14: U1.L25 v2(131.17,111.42)
  L3SIG w0.114: J1.186 96.14,167.53 96.14,165.35 96.96,164.53 96.96,163.45 96.12,162.6 96.12,161.82 96.2,161.73 96.2,160.2 99.34,157.06 117.39,157.06 119.87,154.58 119.87,154.08 119.37,153.59 119.37,153.43 120.01,152.79 120.17,152.79 120.67,153.28 121.16,153.28 122.04,152.41 122.04,151.91 121.55,151.41 121.55,151.25 122.18,150.61 122.35,150.61 122.84,151.11 123.34,151.11 124.21,150.23 124.21,149.73 123.72,149.24 123.72,149.08 124.36,148.44 124.52,148.44 125.01,148.93 125.51,148.93 129.86,144.59 129.86,137.48 130.77,136.56 130.77,114.21 131.16,113.83 131.16,112.77 131.55,112.38 131.55,111.8 v2(131.17,111.42)
DDR_MDQS4_N: length 70.4
  TOP w0.14: U1.V25 v2(137.57,111.42)
  L3SIG w0.114: J1.244 150.32,167.59 150.32,165.25 151.14,164.43 151.14,163.55 150.3,162.7 150.3,161.85 150.22,161.77 150.22,160.19 149.83,159.8 149.83,145.46 141.73,137.35 141.73,132.71 141.62,132.6 139.99,132.6 139.64,132.24 139.64,131.01 139.99,130.65 141.62,130.65 141.73,130.54 141.73,129.64 141.62,129.52 139.99,129.52 139.64,129.17 139.64,127.93 139.99,127.58 141.62,127.58 141.73,127.47 141.73,126.81 139.26,124.34 139.26,115.7 137.32,113.77 137.32,112.69 137.18,112.54 137.18,111.8 v2(137.57,111.42)
DDR_MDQS4_P: length 70.4
  TOP w0.14: U1.W25 v2(138.37,111.42)
  L3SIG w0.114: v2(138.37,111.42) 137.95,111.83 137.95,112.49 137.73,112.71 137.73,113.6 139.66,115.53 139.66,124.17 142.14,126.64 142.14,127.63 141.79,127.99 140.16,127.99 140.04,128.1 140.04,129 140.16,129.12 141.79,129.12 142.14,129.47 142.14,130.71 141.79,131.06 140.16,131.06 140.04,131.17 140.04,132.08 140.16,132.19 141.79,132.19 142.14,132.54 142.14,137.19 150.24,145.29 150.24,159.64 150.62,160.02 150.62,161.73 150.54,161.82 150.54,162.6 151.38,163.45 151.38,164.53 150.56,165.35 150.56,166.51 150.67,166.62 151,166.62 151.25,166.38 J1.245
DDR_MDQS5_N: length 77.7
  TOP w0.14: U1.Y23 v2(139.17,109.82)
  L6SIG w0.114: v2(139.17,109.82) 139.58,110.23 139.58,113.29 139.74,113.45 139.74,115.17 142.98,118.41 142.98,136.06 151.44,144.52 151.44,144.68 150.44,145.68 150.44,146.18 151.31,147.06 151.81,147.06 152.81,146.06 152.97,146.06 153.61,146.69 153.61,146.86 152.61,147.86 152.61,148.36 153.49,149.23 153.99,149.23 154.99,148.23 155.15,148.23 155.79,148.87 155.79,149.03 154.78,150.03 154.78,150.53 155.66,151.41 156.16,151.41 157.16,150.4 157.32,150.4 159.58,152.66 159.58,159.83 160.46,160.72 160.46,162.62 159.65,163.44 159.65,164.48 160.46,165.29 160.46,166.51 160.35,166.62 159.86,166.62 159.75,166.51 J1.255
DDR_MDQS5_P: length 77.7
  TOP w0.14: U1.AA23 v2(139.97,109.82)
  L6SIG w0.114: v2(139.97,109.82) 140.38,110.23 140.38,113.24 140.14,113.47 140.14,115 143.38,118.24 143.38,135.89 151.85,144.35 151.85,144.85 150.84,145.85 150.84,146.01 151.48,146.65 151.64,146.65 152.64,145.65 153.14,145.65 154.02,146.53 154.02,147.02 153.02,148.03 153.02,148.19 153.66,148.83 153.82,148.83 154.82,147.82 155.32,147.82 156.19,148.7 156.19,149.2 155.19,150.2 155.19,150.36 155.83,151 155.99,151 156.99,150 157.49,150 159.98,152.49 159.98,159.66 160.85,160.52 160.85,161.8 160.78,161.86 160.71,161.94 160.71,162.72 159.89,163.54 159.89,164.38 160.71,165.19 160.71,167.57 J1.256
DDR_MDQS6_N: length 78.3
  TOP w0.14: U1.AF25 v2(143.97,111.42)
  L3SIG w0.114: J1.266 169.1,165.82 168.16,164.88 168.16,163.41 168.97,162.61 168.97,161.86 168.88,161.77 168.88,157.71 164.97,153.8 164.97,143.01 163.7,141.73 163.54,141.73 162.6,142.67 162.1,142.67 161.22,141.79 161.22,141.29 162.16,140.36 162.16,140.19 161.52,139.56 161.36,139.56 160.42,140.49 159.93,140.49 159.05,139.62 159.05,139.12 159.99,138.18 159.99,138.02 159.35,137.38 159.19,137.38 158.25,138.32 157.75,138.32 156.87,137.44 156.87,136.95 157.81,136.01 157.81,135.85 151,129.04 151,123.96 147.04,119.99 147.04,113.13 145.31,111.4 144.94,111.4 144.84,111.51 144.84,111.65 144.73,111.76 144.58,111.76 144.47,111.65 144.47,111.51 144.36,111.4 143.95,111.4 v2(143.97,111.42)
DDR_MDQS6_P: length 78.3
  TOP w0.14: U1.AE25 v2(143.17,111.42)
  L3SIG w0.114: J1.267 169.95,166.08 169.7,166.08 168.4,164.78 168.4,163.51 169.21,162.71 169.21,161.88 169.29,161.8 169.29,157.54 165.38,153.63 165.38,142.84 163.87,141.32 163.37,141.32 162.43,142.26 162.27,142.26 161.63,141.62 161.63,141.46 162.57,140.52 162.57,140.03 161.69,139.15 161.19,139.15 160.26,140.09 160.09,140.09 159.46,139.45 159.46,139.29 160.39,138.35 160.39,137.85 159.52,136.98 159.02,136.98 158.08,137.91 157.92,137.91 157.28,137.28 157.28,137.11 158.22,136.18 158.22,135.68 151.41,128.87 151.41,123.79 147.45,119.82 147.45,112.96 145.48,111 143.58,111 v2(143.17,111.42)
DDR_MDQS7_N: length 84
  TOP w0.14: U1.AH24 147.05,110.22 150.38,113.55 150.38,129.55 158.83,138 158.83,149.47 159.41,150.05 159.41,150.25 158.95,150.71 158.95,151.27 159.82,152.14 160.38,152.14 160.84,151.68 161.04,151.68 161.66,152.3 161.66,152.5 161.2,152.96 161.2,153.51 162.07,154.39 162.62,154.39 163.09,153.93 163.28,153.93 163.9,154.55 163.9,154.74 163.44,155.2 163.44,155.76 164.32,156.63 164.87,156.63 165.33,156.17 165.53,156.17 166.39,157.04 173.93,157.04 177.48,160.59 177.48,162.75 178.3,163.56 178.3,164.45 179.2,165.35 179.2,166.75 178.95,167 178.07,167 177.93,166.87 177.93,166.34 178.19,166.07 J1.277
DDR_MDQS7_P: length 84
  TOP w0.14: J1.278 179.46,167.51 179.46,165.24 178.56,164.34 178.56,163.45 177.75,162.64 177.75,160.25 174.11,156.6 166.57,156.6 165.71,155.74 165.15,155.74 164.69,156.2 164.5,156.2 163.87,155.58 163.87,155.38 164.34,154.92 164.34,154.37 163.46,153.49 162.91,153.49 162.45,153.95 162.25,153.95 161.63,153.33 161.63,153.14 162.09,152.68 162.09,152.12 161.22,151.25 160.66,151.25 160.2,151.71 160,151.71 159.38,151.09 159.38,150.89 159.84,150.43 159.84,149.87 159.26,149.29 159.26,137.82 150.81,129.37 150.81,113.37 147.23,109.78 144.8,109.78 U1.AG24
DDR_MDQS8_N: length 83.9
  TOP w0.14: U1.P23 v2(133.57,109.82)
  L6SIG w0.114: v2(133.57,109.82) 134.13,109.82 134.25,109.93 134.25,114.48 134.16,114.57 134.16,131.58 132.27,133.48 132.27,144.46 128.88,147.85 128.72,147.85 128.29,147.41 127.79,147.41 126.92,148.29 126.92,148.79 127.35,149.22 127.35,149.38 126.71,150.02 126.55,150.02 126.12,149.59 125.62,149.59 124.74,150.47 124.74,150.96 125.17,151.39 125.17,151.56 124.54,152.19 124.37,152.19 123.94,151.76 123.45,151.76 122.57,152.64 122.57,153.14 123,153.57 123,153.73 122.36,154.37 122.2,154.37 121.77,153.94 121.27,153.94 120.4,154.81 120.4,155.31 120.83,155.74 120.83,155.9 120.01,156.72 109.86,156.72 105.98,160.59 105.98,161.58 106.06,161.66 106.06,162.6 105.22,163.45 105.22,164.4 104.39,165.23 104.39,167.57 J1.196
DDR_MDQS8_P: length 83.8
  TOP w0.14: U1.R23 v2(135.17,109.82)
  L6SIG w0.114: v2(135.17,109.82) 134.6,109.82 134.49,109.93 134.49,114.55 134.57,114.63 134.57,131.75 132.68,133.65 132.68,144.63 129.05,148.25 128.55,148.25 128.12,147.82 127.96,147.82 127.32,148.46 127.32,148.62 127.75,149.05 127.75,149.55 126.88,150.43 126.38,150.43 125.95,150 125.79,150 125.15,150.63 125.15,150.79 125.58,151.23 125.58,151.72 124.7,152.6 124.21,152.6 123.78,152.17 123.61,152.17 122.98,152.81 122.98,152.97 123.41,153.4 123.41,153.9 122.53,154.77 122.03,154.77 121.6,154.34 121.44,154.34 120.8,154.98 120.8,155.14 121.23,155.57 121.23,156.07 120.18,157.12 110.02,157.12 106.39,160.76 106.39,161.58 106.31,161.66 106.31,162.7 105.46,163.55 105.46,164.5 104.64,165.33 104.64,166.51 104.75,166.62 105.09,166.62 105.35,166.37 J1.197
DDR_MODT0: length 65.6
  TOP w0.14: J1.87 139.35,162.59 139.83,163.07 141.2,163.07 141.72,162.55 141.72,161.05 145.38,157.39 145.38,156.63 145.17,156.41 145.17,155.87 145.28,155.75 145.84,155.75 145.95,155.64 145.95,155.29 145.84,155.18 145.28,155.18 145.17,155.07 145.17,154.72 145.28,154.61 145.84,154.61 145.95,154.5 145.95,154.15 145.84,154.04 145.28,154.04 145.17,153.93 145.17,153.58 145.28,153.47 145.84,153.47 145.95,153.36 145.95,153.01 145.84,152.9 145.28,152.9 145.17,152.79 145.17,152.44 145.28,152.33 145.84,152.33 145.95,152.22 145.95,151.87 145.84,151.76 145.28,151.76 145.17,151.65 145.17,142.65 144.11,141.59 144.11,141.13 144,141.02 143.32,141.02 143.21,140.9 143.21,140.56 143.32,140.45 144,140.45 144.11,140.33 144.11,138.9 144,138.79 142.56,138.79 142.45,138.67 142.45,138.33 142.56,138.22 144,138.22 144.11,138.1 144.11,137.26 144,137.14 143.77,137.14 143.66,137.03 143.66,136.69 143.77,136.57 144,136.57 144.11,136.46 144.11,117.76 142.65,116.3 142.65,114.35 141.97,113.67 U1.AD28
DDR_MODT1: length 65.9
  TOP w0.14: J1.91 142.75,161.59 144.45,159.89 146.49,159.89 146.85,159.53 146.85,157.26 146.99,157.13 147.56,157.13 147.7,156.99 147.7,156.74 147.56,156.6 146.99,156.6 146.85,156.46 146.85,156.2 146.97,156.08 147.61,156.08 147.72,155.97 147.72,155.63 147.61,155.51 146.97,155.51 146.85,155.4 146.85,155.06 146.97,154.94 147.61,154.94 147.72,154.83 147.72,154.49 147.61,154.37 146.97,154.37 146.85,154.26 146.85,153.92 146.97,153.8 147.61,153.8 147.72,153.69 147.72,153.35 147.61,153.23 146.97,153.23 146.85,153.12 146.85,152.78 146.97,152.66 147.61,152.66 147.72,152.55 147.72,152.21 147.61,152.09 146.97,152.09 146.85,151.98 146.85,151.64 146.97,151.52 147.61,151.52 147.72,151.41 147.72,151.07 147.61,150.95 146.97,150.95 146.85,150.84 146.85,150.5 146.97,150.38 147.61,150.38 147.72,150.27 147.72,149.93 147.61,149.81 146.97,149.81 146.85,149.7 146.85,149.36 146.97,149.24 147.61,149.24 147.72,149.13 147.72,148.79 147.61,148.67 146.97,148.67 146.85,148.56 146.85,141.81 145.38,140.34 145.38,117.38 143.66,115.67 143.66,114.2 143.18,113.72 143.18,113.03 U1.AE27
DDR_MRAS_N: length 65.5
  TOP w0.14: U1.AA28 139.67,113.52 139.67,117.89 140.43,118.65 140.43,132.62 140.25,132.8 140.25,141.39 140.47,141.61 140.47,142.44 140.59,142.55 141.07,142.55 141.19,142.67 141.19,143.01 141.07,143.12 140.59,143.12 140.47,143.24 140.47,143.58 140.59,143.69 141.07,143.69 141.19,143.81 141.19,144.15 141.07,144.26 140.59,144.26 140.47,144.38 140.47,144.72 140.59,144.84 141.07,144.84 141.19,144.95 141.19,145.29 141.07,145.41 140.59,145.41 140.47,145.52 140.47,145.86 140.59,145.98 141.07,145.98 141.19,146.09 141.19,146.43 141.07,146.55 140.59,146.55 140.47,146.66 140.47,147 140.59,147.12 141.07,147.12 141.19,147.23 141.19,147.57 141.07,147.69 140.59,147.69 140.47,147.8 140.47,148.14 140.59,148.26 141.07,148.26 141.19,148.37 141.19,148.71 141.07,148.83 140.59,148.83 140.47,148.94 140.47,149.36 140.59,149.47 141.04,149.47 141.16,149.59 141.16,149.93 141.04,150.04 140.59,150.04 140.47,150.16 140.47,153.11 141.56,154.2 141.56,154.92 141.42,155.06 140.67,155.06 140.53,155.2 140.53,155.44 140.67,155.58 141.42,155.58 141.56,155.72 141.56,156 138.81,158.75 136.14,158.75 135.26,159.64 135.26,163.72 J1.82
DDR_MWE_N: length 65.6
  TOP w0.14: U1.AB27 140.77,113.02 140.77,114.35 141.15,114.73 141.15,117.72 142.08,118.65 142.08,135.9 141.1,136.88 141.1,140.87 142.81,142.58 142.81,149.15 142.4,149.56 142.4,150.22 142.51,150.33 142.94,150.33 143.05,150.45 143.05,150.79 142.94,150.9 142.51,150.9 142.4,151.02 142.4,151.36 142.51,151.47 142.94,151.47 143.05,151.59 143.05,151.93 142.94,152.04 142.51,152.04 142.4,152.16 142.4,152.5 142.51,152.61 142.94,152.61 143.05,152.73 143.05,153.07 142.94,153.18 142.51,153.18 142.4,153.3 142.4,153.64 142.51,153.75 142.94,153.75 143.05,153.87 143.05,154.21 142.94,154.32 142.51,154.32 142.4,154.44 142.4,154.78 142.51,154.89 142.94,154.89 143.05,155.01 143.05,155.35 142.94,155.46 142.51,155.46 142.4,155.58 142.4,156.46 139.89,158.97 139.89,159.17 140,159.27 140,159.47 139.83,159.64 139.63,159.64 139.52,159.53 139.32,159.53 139.15,159.7 139.15,159.9 139.26,160.01 139.26,160.21 139.09,160.38 138.89,160.38 138.79,160.27 138.59,160.27 138.35,160.5 138.35,162.64 137.67,163.32 137.67,164.59 136.8,165.46 J1.228
DDR_PGOOD: length 206.3
  TOP w0.127: v1(193.55,145.03) 191.92,145.03 191.8,144.91 U64.3 ; U57.T10 46.97,83.72 57.98,72.71 v1(68.9,72.71)
  L6SIG w0.102: v1(193.55,145.03) 191.52,143 191.52,126.11 189.23,123.83 183.01,123.83 157.72,98.54 157.72,88.5 155.96,86.74 149.29,86.74 145.41,82.87 138.62,82.87 137.67,83.82 129.87,83.82 128.41,82.36 120.9,82.36 112.01,73.47 73.47,73.47 72.71,72.71 v1(68.9,72.71)
  BOTTOM w0.127: R568.2 v1(193.55,145.03)
DDR_REFCLK: length 114.6
  TOP w0.127: v1(39.85,133.73) R488.2 R487.2
  TOP w0.14: U1.J21 v2(129.57,108.22)
  BOTTOM w0.127: v2(129.57,108.22) 128.89,108.22 128.37,108.74 128.37,109.18 128.14,109.41 123.51,109.41 119.51,113.41 110.24,113.41 107.19,110.36 70.99,110.36 68.52,112.84 44.89,112.84 41.78,115.95 41.78,131.8 v1(39.85,133.73)
DDR_RST_N: length 182.5
  TOP w0.127: J1.58 109.6,160.88 R5.2 ; v1(29.34,106.36) 31.43,106.36 32.26,105.54 36.81,105.54 U57.A2
  L3SIG w0.102: J1.58 107.95,165.52 107.95,166.37 107.06,167.26 107.06,171.96 106.17,172.85 44.32,172.85 39.62,177.55 25.65,177.55 23.24,175.13 23.24,110.87 27.75,106.36 v1(29.34,106.36)
DDRPWR_EN: length 205.8
  TOP w0.127: U57.R9 46.48,88.87 46.48,83.57 57.79,72.26 v1(68.07,72.26) ; U64.16 189.48,143 189.86,142.62 190.37,142.62 190.75,142.24 R565.2 191.8,141.96 C865.2 v1(192.91,141.73)
  L6SIG w0.102: v1(68.07,72.26) 72.77,72.26 73.66,73.15 112.14,73.15 121.09,82.11 128.54,82.11 130,83.57 137.54,83.57 138.49,82.61 145.54,82.61 149.42,86.49 156.08,86.49 157.99,88.39 157.99,98.36 183.01,123.38 189.36,123.38 191.9,125.92 191.9,140.72 v1(192.91,141.73)
DFP_BACKLIGHT: length 81.4
  TOP w0.127: v1(26.8,33.91) 23.43,33.91 21.91,32.39 20.19,32.39 18.82,31.01 R235.2 18.52,30.99 J17.1 ; U57.J1 34.17,95.38 29.72,90.93 v1(29.72,88.9)
  L3SIG w0.102: v1(29.72,88.9) 29.72,77.6 25.4,73.28 25.4,39.37 26.04,38.73 26.04,34.67 v1(26.8,33.91)
DFP_BL_PWM: length 86.8
  TOP w0.127: U57.K1 34.57,94.38 30.61,90.42 v1(30.61,88.9) ; v1(28.89,35.75) 28.89,35.54 27.77,34.42 23.3,34.42 21.65,32.77 19.3,32.77 19.02,33.05 R234.2 13.11,33.05 J17.3
  L3SIG w0.102: v1(28.89,35.75) 26.67,37.97 26.67,39.12 26.16,39.62 26.16,73.03 30.61,77.47 v1(30.61,88.9)
DFP_D0: length 9.8
  TOP w0.127: U37.94 76.76,51.39 77.6,52.22 77.6,55.96 79.23,57.59 U21.5
DFP_D1: length 14.4
  TOP w0.127: U21.11 84.5,56.94 82.55,54.99 78.99,54.99 78.05,54.05 78.05,52.07 76.87,50.89 U37.93
DFP_D2: length 18.2
  TOP w0.127: U23.5 v1(91.44,51.49) ; v1(77.64,50.58) 77.44,50.39 U37.92
  BOTTOM w0.127: v1(77.64,50.58) 78.28,51.23 86.87,51.23 87.83,52.2 90.73,52.2 v1(91.44,51.49)
DFP_D3: length 23.8
  TOP w0.127: U23.11 98.62,50.85 v1(94.82,50.85) ; v1(78.51,50.62) 77.98,50.09 76.99,50.09 76.79,49.89 U37.91
  BOTTOM w0.127: v1(78.51,50.62) 78.69,50.8 87.1,50.8 87.48,51.18 90.42,51.18 90.98,50.62 94.59,50.62 v1(94.82,50.85)
DFP_D4: length 29.5
  TOP w0.127: U37.90 76.82,49.39 77.22,49.78 78.21,49.78 78.59,50.16 v1(79.27,50.16) ; v1(101.07,52.68) 101.2,52.81 U26.5
  BOTTOM w0.127: v1(79.27,50.16) 83.06,50.16 83.6,49.62 90.46,49.62 90.93,49.15 95.63,49.15 99.16,52.68 v1(101.07,52.68)
DFP_D5: length 35.5
  TOP w0.127: U37.89 76.85,48.89 77.37,49.4 78.59,49.4 v1(78.82,49.63) ; U26.11 106.87,52.16 v1(106.86,52.15)
  BOTTOM w0.127: v1(106.86,52.15) 99.26,52.15 95.89,48.77 91.19,48.77 91,48.58 89.66,48.58 88.96,49.28 87.88,49.28 87.5,48.9 80.14,48.9 79.76,49.28 79.17,49.28 v1(78.82,49.63)
DFP_D6: length 10.5
  TOP w0.127: U28.5 80.37,51.49 80.04,51.16 80.04,47.5 79.73,47.19 77.06,47.19 76.87,47.39 U37.86
DFP_D7: length 14
  TOP w0.127: U37.85 76.68,46.89 76.76,46.81 80.09,46.81 81.66,48.39 83.82,48.39 86.27,50.84 U28.11
DFP_D8: length 18.4
  TOP w0.127: U37.84 79.24,46.39 80.26,45.36 v1(80.42,45.36) ; v1(91.57,45.21) 91.75,45.39 U22.5
  BOTTOM w0.127: v1(80.42,45.36) 80.57,45.21 84.2,45.21 84.96,45.97 88.65,45.97 89.41,45.21 v1(91.57,45.21)
DFP_D9: length 24.5
  TOP w0.127: v1(79.43,45.44) 78.77,46.1 77.09,46.1 76.87,45.89 U37.83 ; U22.11 96.43,44.74 v1(96.14,44.45)
  BOTTOM w0.127: v1(96.14,44.45) 95.99,44.3 89.56,44.3 88.34,45.51 85.52,45.51 84.84,44.83 80.04,44.83 v1(79.43,45.44)
DFP_D10: length 32.2
  TOP w0.127: v1(79.73,44.45) 78.59,45.59 77.22,45.59 77.01,45.39 U37.82 ; U24.5 104.16,46.72 v1(104.39,46.48)
  BOTTOM w0.127: v1(79.73,44.45) 85.12,44.45 85.25,44.58 88.26,44.58 88.95,43.89 101.8,43.89 v1(104.39,46.48)
DFP_D11: length 36.2
  TOP w0.127: U37.81 77.02,44.89 77.34,45.21 78.21,45.21 v1(78.97,44.45) ; v1(105.16,45.97) 105.25,46.07 U24.11
  BOTTOM w0.127: v1(78.97,44.45) 80.24,43.18 85.34,43.18 86.36,44.2 87.88,44.2 88.65,43.43 93.22,43.43 93.73,42.93 99.06,42.93 99.57,43.43 101.98,43.43 104.52,45.97 v1(105.16,45.97)
DFP_DCLK: length 43.7
  TOP w0.127: U27.11 109.61,58.03 109.83,57.81 109.83,56.34 109.68,56.18 106.43,56.18 106.05,55.8 106.05,54.99 106.32,54.71 106.32,52.68 v1(105.18,51.54) ; R225.2 77.61,47.89 v1(77.06,47.89) U37.87
  BOTTOM w0.127: v1(105.18,51.54) 99.29,51.54 96.08,48.32 91.76,48.32 91.44,48.01 88.46,48.01 88.14,48.32 79.19,48.32 78.42,48.32 77.99,47.89 v1(77.06,47.89)
DFP_DE: length 42.3
  TOP w0.127: U27.5 101.1,58.68 99.06,56.64 99.06,55.88 98.3,55.12 v1(95.38,55.12) ; U37.76 77.16,42.39 R223.2 77.06,42.95 v1(76.96,43.05)
  BOTTOM w0.127: v1(95.38,55.12) 94.87,54.61 92.58,54.61 92.08,55.12 86.61,55.12 85.85,54.36 85.85,53.09 84.46,51.69 77.72,51.69 76.2,50.16 76.2,43.81 v1(76.96,43.05)
DFP_HSYNC: length 10
  TOP w0.127: U37.75 76.68,40.64 80.46,44.42 U25.6
DFP_INT_N: length 44
  TOP w0.127: U37.21 63.95,57.87 R221.1 64.77,58.7 v1(64.77,62.48) ; U57.P6 v1(42.47,89.89)
  L6SIG w0.102: v1(42.47,89.89) 42.47,87.39 64.77,65.09 v1(64.77,62.48)
DFP_MODE: length 96
  TOP w0.127: v1(54.36,66.29) 54.36,68.71 40.45,82.61 40.45,88.77 40.97,89.29 U57.R4 ; v1(49.66,44.96) 49.66,40.64 30.73,21.72 26.16,21.72 24.7,20.25 Q6.1
  L3SIG w0.102: v1(49.66,44.96) 49.66,46.1 52.2,48.64 52.2,55.24 54.74,57.78 54.74,60.33 53.34,61.72 53.34,65.28 v1(54.36,66.29)
DFP_RST_N: length 45
  TOP w0.127: U37.22 63.44,57.99 R222.1 63.27,58.19 63.75,58.67 v1(63.75,62.8) ; U57.N5 v1(41.47,90.89)
  L6SIG w0.102: v1(63.75,62.8) 63.75,65.66 41.97,87.44 41.97,90.38 v1(41.47,90.89)
DFP_VSYNC: length 18.9
  TOP w0.127: U37.74 73.45,39.76 73.71,39.5 76,39.5 79.73,43.23 85.39,43.23 85.85,43.69 85.85,44.83 86.74,45.72 U25.11
DIU_HSYNC: length 102.4
  TOP w0.127: v1(85.85,47.5) 85.85,47.45 85.42,47.02 U25.2 81.41,47.02 81.15,46.77 81.15,45.37 81.45,45.07 U25.5 ; U1.AA3 v2(139.97,93.02)
  L3SIG w0.102: v2(139.97,93.02) 139.97,89.51 140.21,89.27 140.21,86.87 129.54,76.19 129.54,69.47 114.94,54.86 114.94,44.45 111.32,40.83 110.3,40.83 109.73,40.26 105.03,40.26 104.39,39.62 99,39.62 95.83,42.8 93.73,42.8 92.33,44.2 92.33,45.34 90.3,47.37 85.98,47.37 v1(85.85,47.5)
DIU_VSYNC: length 99.9
  TOP w0.127: U25.12 v1(89.54,46.37) 89.54,44.7 89.25,44.42 U25.9 ; U1.AB3 v2(140.77,93.02)
  L3SIG w0.102: v1(89.54,46.37) 93.49,42.42 95.63,42.42 98.81,39.24 104.65,39.24 105.28,39.88 109.86,39.88 110.36,40.39 111.51,40.39 115.32,44.2 115.32,54.71 129.86,69.25 129.86,75.95 130.68,76.77 137.8,76.77 140.84,79.82 140.84,88.65 141.18,88.99 141.18,92.37 140.77,92.79 v2(140.77,93.02)
DVI_D0: length 20
  TOP w0.127: U21.6 82.64,56.94 v1(82.8,56.77) ; U35.63 86.41,41.98 85.98,42.42 v1(85.73,42.42)
  L6SIG w0.102: v1(82.8,56.77) 83.95,55.63 84.46,55.63 85.37,54.71 85.37,44.42 85.73,44.07 v1(85.73,42.42)
DVI_D1: length 17.6
  TOP w0.127: U21.10 84.99,56.29 v1(84.96,56.26) ; v1(86.28,43.05) 86.28,42.88 86.91,42.25 U35.62
  L6SIG w0.102: v1(86.28,43.05) 86.28,50.75 85.73,51.31 85.73,55.5 v1(84.96,56.26)
DVI_D2: length 14.2
  TOP w0.127: v1(87.25,42.8) 87.41,42.64 U35.61 ; v1(89.54,50.67) 89.7,50.84 U23.6
  L6SIG w0.102: v1(87.25,42.8) 87.88,43.43 87.88,49.02 v1(89.54,50.67)
DVI_D3: length 17.5
  TOP w0.127: U35.60 87.91,42.19 90.17,44.45 90.17,48.26 91.06,49.15 96.01,49.15 97.05,50.19 U23.10
DVI_D4: length 22.9
  TOP w0.127: U26.6 101.23,52.16 100.58,51.51 100.58,50.04 99.31,48.77 91.31,48.77 90.55,48.01 90.55,44.32 88.41,42.18 U35.59
DVI_D5: length 27
  TOP w0.127: U35.58 88.91,42.18 90.93,44.2 90.93,47.85 91.47,48.39 99.69,48.39 101.47,50.16 105.71,50.16 107.09,51.54 108.64,51.54 U26.10
DVI_D6: length 19.9
  TOP w0.127: U28.6 84.67,50.84 85.67,51.84 v1(86.61,51.84) ; U35.55 90.41,42.04 v1(90.16,42.28)
  L6SIG w0.102: v1(90.16,42.28) 88.65,43.8 88.65,47.88 89.18,48.41 89.18,49.3 90.04,50.16 90.04,50.93 89.79,51.18 89.08,51.18 88.42,51.84 v1(86.61,51.84)
DVI_D7: length 11.8
  TOP w0.127: v1(90.17,49.02) 90.17,49.56 89.53,50.19 U28.10 ; v1(91.01,42.29) 90.91,42.19 U35.54
  L6SIG w0.102: v1(91.01,42.29) 91.01,48.72 90.7,49.02 v1(90.17,49.02)
DVI_D8: length 5
  TOP w0.127: U22.6 91.86,44.74 91.57,44.45 91.57,42.04 91.41,41.88 U35.53
DVI_D9: length 8.7
  TOP w0.127: U35.52 91.91,42.13 92.71,42.93 95.76,42.93 96.93,44.09 U22.10
DVI_D10: length 14
  TOP w0.127: U35.51 92.41,41.99 92.96,42.55 99.44,42.55 101.09,44.2 101.09,45.47 101.69,46.07 U24.6
DVI_D11: length 18.2
  TOP w0.127: U24.10 107.21,45.42 105.87,44.07 101.6,44.07 99.7,42.16 93.19,42.16 92.91,41.88 U35.50
DVI_DCLK: length 34.4
  TOP w0.127: U27.10 106.68,57.38 105.41,56.11 101.07,56.11 99.7,54.74 96.77,54.74 96.52,54.48 91.06,54.48 v1(90.55,53.98) ; v1(90.49,42.86) 90.11,42.86 89.41,42.17 U35.57
  L6SIG w0.102: v1(90.49,42.86) 89.03,44.32 89.03,47.62 89.56,48.16 89.56,49.17 90.55,50.16 v1(90.55,53.98)
DVI_DE: length 51.7
  TOP w0.127: U27.6 101.34,58.03 99.44,56.13 v1(99.44,55.37) ; U35.2 v1(82.42,38.43) 82.12,38.73 R209.2
  BOTTOM w0.127: v1(82.42,38.43) 82.22,38.23 79.88,38.23 75.69,42.42 75.69,50.29 77.72,52.32 82.8,52.32 83.95,53.47 83.95,54.36 84.58,54.99 85.34,54.99 86.61,56.26 87.76,57.4 90.42,57.4 91.06,56.77 96.14,56.77 97.54,55.37 v1(99.44,55.37)
DVI_HSYNC: length 13.5
  TOP w0.127: v1(86.42,38.48) 85.37,37.43 U35.4 ; v1(84.96,43.69) 84.46,44.2 84.46,45.85 83.93,46.37 U25.3
  L6SIG w0.102: v1(84.96,43.69) 84.96,42.29 86.36,40.89 86.36,38.54 v1(86.42,38.48)
DVI_INT_N: length 92.4
  TOP w0.127: v1(33.91,86.04) 33.34,86.61 33.34,91.12 35.05,92.84 38.29,92.84 38.84,93.38 U57.L2 ; U35.7 82,35.93 R216.2 81.76,35.71 81.28,36.19 79.44,36.19 v1(78.87,35.62)
  L6SIG w0.102: v1(78.87,35.62) 72.64,41.85 72.64,44.96 68.96,48.64 60.83,48.64 55.37,54.1 55.37,66.48 39.12,82.74 37.21,82.74 v1(33.91,86.04)
DVI_RST_N: length 90.5
  TOP w0.127: U35.13 81.8,32.93 R217.2 81.76,33.17 81.28,33.66 v1(80.9,33.66) ; U57.M1 35.49,92.38 33.97,90.87 33.97,86.75 v1(33.98,86.75)
  L6SIG w0.102: v1(33.98,86.75) 37.67,83.06 39.24,83.06 55.69,66.61 55.69,54.23 60.96,48.96 69.09,48.96 72.96,45.09 72.96,42.17 80.9,34.23 v1(80.9,33.66)
DVI_TDC0_N: length 15.5
  TOP w0.127: R773.1 87.91,14.86 L21.1 88.07,15.23 88.07,16.4 88.46,16.78 88.46,17.3 88.15,17.61 U36.27 U36.12 88.15,25.32 88.46,25.63 88.46,26.31 87.97,26.81 87.97,28.39 87.91,28.45 U35.21
DVI_TDC0_P: length 15.5
  TOP w0.127: R772.1 88.62,14.86 L21.4 88.46,15.23 88.46,16.24 88.84,16.63 88.84,17.3 89.15,17.61 U36.29 U36.10 89.15,25.32 88.84,25.63 88.84,26.47 88.35,26.96 88.35,28.39 88.41,28.45 U35.22
DVI_TDC1_N: length 15.4
  TOP w0.127: U35.24 89.41,28.45 89.47,28.39 89.47,27.11 89.96,26.62 89.96,25.63 89.65,25.32 U36.9 U36.30 89.65,17.61 89.96,17.3 89.96,16.3 90.2,16.07 90.2,15.2 L20.1 89.92,14.92 R771.1
DVI_TDC1_P: length 15.4
  TOP w0.127: U35.25 89.91,28.45 89.85,28.39 89.85,27.27 90.34,26.78 90.34,25.63 90.65,25.32 U36.7 U36.32 90.65,17.61 90.34,17.3 90.34,16.46 90.63,16.18 90.63,15.22 L20.4 90.93,14.92 R770.1
DVI_TDC2_N: length 15.6
  TOP w0.127: R769.1 92.08,15.04 L19.1 92.38,15.35 92.38,16.05 91.44,16.98 91.44,17.4 91.15,17.68 U36.33 U36.6 91.15,25.32 91.46,25.63 91.46,26.77 90.97,27.27 90.97,28.39 90.91,28.45 U35.27
DVI_TDC2_P: length 15.6
  TOP w0.127: R768.1 93.09,15.04 L19.4 92.77,15.36 92.77,16.19 91.82,17.14 91.82,17.32 92.15,17.65 U36.35 U36.4 92.15,25.32 91.84,25.63 91.84,26.93 91.35,27.42 91.35,28.39 91.41,28.45 U35.28
DVI_TLC_N: length 21.6
  TOP w0.127: U35.31 92.91,28.37 v1(93.09,28.19) ; R775.1 85.6,15.55 L22.1 85.9,15.86 85.9,16.51 86.65,17.26 U36.24 U36.15 86.65,25.57 v1(86.74,25.65)
  BOTTOM w0.127: v1(86.74,25.65) 86.74,24.64 87.12,24.26 87.66,24.26 89.82,24.26 92.9,27.34 92.9,28 v1(93.09,28.19)
DVI_TLC_P: length 21.5
  TOP w0.127: v1(92.33,28.19) 92.41,28.28 U35.30 ; v1(87.5,25.65) 87.65,25.5 U36.13 U36.26 87.65,17.72 86.28,16.35 86.28,15.88 L22.4 86.61,15.55 R774.1
  BOTTOM w0.127: v1(87.5,25.65) 87.12,25.27 87.12,24.8 87.28,24.64 87.5,24.64 87.76,24.64 87.88,24.77 87.88,25.02 88.01,25.15 88.26,25.15 88.39,25.02 88.39,24.77 88.52,24.64 89.66,24.64 92.52,27.5 92.52,28 v1(92.33,28.19)
DVI_VSYNC: length 13
  TOP w0.127: v1(87.19,38.67) 87.19,38.35 85.92,37.08 84.9,37.08 84.74,36.93 U35.5 82.65,36.93 82.42,36.7 R211.2 ; v1(86.74,43.69) 86.82,43.77 U25.8
  L6SIG w0.102: v1(87.19,38.67) 86.74,39.12 v1(86.74,43.69)
EARTH: length 1115.6
  TOP w1.016: 133.72,12.09 J19.25 ; J19.25 133.72,10.08 ; J19.25 135.74,12.09 ; J19.25 135.74,10.08 ; 61.05,13.58 J5.11 ; J5.11 63.84,13.58 ; J5.11 63.84,16.37 ; J5.11 61.05,16.37 ; J9.22 105.92,16.61 ; J9.22 105.92,12.58 ; J9.22 101.89,12.58 ; J9.22 101.89,16.61 ; 252.48,8.43 J40.14 ; J40.14 254.5,6.42 ; J40.14 252.48,6.42 ; J40.14 254.5,8.43 ; 234.11,20.47 J21.100 ; J21.100 236.12,20.47 ; J21.100 236.12,18.46 ; J21.100 234.11,18.46 ; 168.48,8.43 J20.14 ; J20.14 170.5,8.43 ; J20.14 168.48,6.42 ; J20.14 170.5,6.42 ; J5.10 76.98,10.69 ; J5.10 74.19,10.69 ; J5.10 76.98,7.9 ; J5.10 74.19,7.9 ; J5.9 63.84,10.69 ; J5.9 63.84,7.9 ; J5.9 61.05,10.69 ; J5.9 61.05,7.9 ; J21.98 236.12,10.08 ; J21.98 236.12,12.09 ; J21.98 234.11,12.09 ; J21.98 234.11,10.08 ; 94.26,6.66 J12.21 ; J12.21 96.27,6.66 ; J12.21 96.27,10.47 ; J12.21 94.26,10.47 ; 74.19,16.37 J5.12 ; J5.12 76.98,13.58 ; J5.12 74.19,13.58 ; J5.12 76.98,16.37 ; 152.22,6.42 J20.13 ; J20.13 154.24,6.42 ; J20.13 154.24,8.43 ; J20.13 152.22,8.43 ; J9.20 130.91,4.58 ; J9.20 126.87,4.58 ; J9.20 126.87,8.61 ; J9.20 130.91,8.61 ; J9.21 105.92,8.61 ; J9.21 101.89,4.58 ; J9.21 101.89,8.61 ; J9.21 105.92,4.58 ; 79.76,4.01 J12.22 81.77,4.01 ; 270.98,6.42 J41.14 ; J41.14 270.98,8.43 ; J41.14 273,8.43 ; J41.14 273,6.42 ; 170.6,10.08 J21.97 ; J21.97 172.61,10.08 ; J21.97 172.61,12.09 ; J21.97 170.6,12.09 ; J40.13 238.24,6.42 ; J40.13 236.22,6.42 ; J40.13 238.24,8.43 ; J40.13 236.22,8.43 ; J19.28 152,18.46 ; J19.28 149.98,18.46 ; J19.28 149.98,20.47 ; J19.28 152,20.47 ; 94.26,4.01 J12.23 96.27,4.01 ; 79.76,10.47 J12.20 ; J12.20 81.77,10.47 ; J12.20 79.76,6.66 ; J12.20 81.77,6.66 ; 149.98,10.08 J19.26 ; J19.26 149.98,12.09 ; J19.26 152,12.09 ; J19.26 152,10.08 ; J21.99 172.61,20.47 ; J21.99 170.6,20.47 ; J21.99 170.6,18.46 ; J21.99 172.61,18.46 ; J41.13 256.74,8.43 ; J41.13 254.72,8.43 ; J41.13 256.74,6.42 ; J41.13 254.72,6.42
  L2GND w1.016: 133.72,10.08 J19.25 ; J19.25 135.74,12.09 ; J19.25 135.74,10.08 ; J19.25 133.72,12.09 ; 101.89,4.58 J9.21 ; J9.21 105.92,8.61 ; J9.21 101.89,8.61 ; J9.21 105.92,4.58 ; 126.87,12.58 J9.10 ; J9.10 130.91,16.61 ; J9.10 126.87,16.61 ; J9.10 130.91,12.58 ; J41.14 273,6.42 ; J41.14 270.98,8.43 ; J41.14 273,8.43 ; J41.14 270.98,6.42 ; 252.48,8.43 J40.14 ; J40.14 254.5,8.43 ; J40.14 252.48,6.42 ; J40.14 254.5,6.42 ; 101.89,12.58 J9.22 ; J9.22 101.89,16.61 ; J9.22 105.92,12.58 ; J9.22 105.92,16.61 ; J5.12 76.98,13.58 ; J5.12 76.98,16.37 ; J5.12 74.19,16.37 ; J5.12 74.19,13.58 ; 170.6,20.47 J21.99 ; J21.99 170.6,18.46 ; J21.99 172.61,18.46 ; J21.99 172.61,20.47 ; 133.72,18.46 J19.27 ; J19.27 135.74,20.47 ; J19.27 135.74,18.46 ; J19.27 133.72,20.47 ; 74.19,10.69 J5.10 ; J5.10 76.98,7.9 ; J5.10 76.98,10.69 ; J5.10 74.19,7.9 ; 170.6,12.09 J21.97 ; J21.97 172.61,10.08 ; J21.97 172.61,12.09 ; J21.97 170.6,10.08 ; J5.9 63.84,7.9 ; J5.9 61.05,10.69 ; J5.9 63.84,10.69 ; J5.9 61.05,7.9 ; 149.98,18.46 J19.28 ; J19.28 149.98,20.47 ; J19.28 152,18.46 ; J19.28 152,20.47 ; J20.14 170.5,8.43 ; J20.14 170.5,6.42 ; J20.14 168.48,8.43 ; J20.14 168.48,6.42 ; J19.26 152,12.09 ; J19.26 152,10.08 ; J19.26 149.98,12.09 ; J19.26 149.98,10.08 ; 94.26,4.01 J12.23 96.27,4.01 ; 81.77,4.01 J12.22 79.76,4.01 ; 236.22,8.43 J40.13 ; J40.13 238.24,6.42 ; J40.13 236.22,6.42 ; J40.13 238.24,8.43 ; J9.20 130.91,8.61 ; J9.20 126.87,4.58 ; J9.20 130.91,4.58 ; J9.20 126.87,8.61 ; 61.05,13.58 J5.11 ; J5.11 63.84,13.58 ; J5.11 61.05,16.37 ; J5.11 63.84,16.37 ; J12.20 81.77,6.66 ; J12.20 81.77,10.47 ; J12.20 79.76,10.47 ; J12.20 79.76,6.66 ; J12.21 96.27,10.47 ; J12.21 94.26,6.66 ; J12.21 96.27,6.66 ; J12.21 94.26,10.47 ; 152.22,8.43 J20.13 ; J20.13 152.22,6.42 ; J20.13 154.24,6.42 ; J20.13 154.24,8.43 ; J41.13 256.74,6.42 ; J41.13 256.74,8.43 ; J41.13 254.72,8.43 ; J41.13 254.72,6.42 ; J21.98 236.12,12.09 ; J21.98 234.11,12.09 ; J21.98 234.11,10.08 ; J21.98 236.12,10.08 ; 234.11,20.47 J21.100 ; J21.100 234.11,18.46 ; J21.100 236.12,20.47 ; J21.100 236.12,18.46
  L4PWR w1.016: 79.76,6.66 J12.20 ; J12.20 81.77,10.47 ; J12.20 81.77,6.66 ; J12.20 79.76,10.47 ; J21.99 172.61,20.47 ; J21.99 170.6,20.47 ; J21.99 172.61,18.46 ; J21.99 170.6,18.46 ; 236.22,6.42 J40.13 ; J40.13 238.24,8.43 ; J40.13 238.24,6.42 ; J40.13 236.22,8.43 ; 126.87,16.61 J9.10 ; J9.10 130.91,16.61 ; J9.10 130.91,12.58 ; J9.10 126.87,12.58 ; J19.25 135.74,12.09 ; J19.25 133.72,10.08 ; J19.25 135.74,10.08 ; J19.25 133.72,12.09 ; J41.13 256.74,8.43 ; J41.13 254.72,6.42 ; J41.13 254.72,8.43 ; J41.13 256.74,6.42 ; 101.89,8.61 J9.21 ; J9.21 105.92,8.61 ; J9.21 101.89,4.58 ; J9.21 105.92,4.58 ; J9.20 130.91,4.58 ; J9.20 130.91,8.61 ; J9.20 126.87,8.61 ; J9.20 126.87,4.58 ; J19.26 152,12.09 ; J19.26 149.98,10.08 ; J19.26 152,10.08 ; J19.26 149.98,12.09 ; J19.27 135.74,18.46 ; J19.27 133.72,20.47 ; J19.27 133.72,18.46 ; J19.27 135.74,20.47 ; J5.11 63.84,16.37 ; J5.11 63.84,13.58 ; J5.11 61.05,13.58 ; J5.11 61.05,16.37 ; 170.6,12.09 J21.97 ; J21.97 172.61,12.09 ; J21.97 172.61,10.08 ; J21.97 170.6,10.08 ; J20.14 170.5,6.42 ; J20.14 168.48,8.43 ; J20.14 168.48,6.42 ; J20.14 170.5,8.43 ; J9.22 105.92,16.61 ; J9.22 101.89,12.58 ; J9.22 101.89,16.61 ; J9.22 105.92,12.58 ; J12.21 96.27,10.47 ; J12.21 96.27,6.66 ; J12.21 94.26,6.66 ; J12.21 94.26,10.47 ; J20.13 154.24,6.42 ; J20.13 152.22,8.43 ; J20.13 154.24,8.43 ; J20.13 152.22,6.42 ; 61.05,10.69 J5.9 ; J5.9 63.84,7.9 ; J5.9 61.05,7.9 ; J5.9 63.84,10.69 ; 149.98,18.46 J19.28 ; J19.28 152,20.47 ; J19.28 149.98,20.47 ; J19.28 152,18.46 ; 252.48,6.42 J40.14 ; J40.14 254.5,8.43 ; J40.14 252.48,8.43 ; J40.14 254.5,6.42 ; 74.19,16.37 J5.12 ; J5.12 76.98,13.58 ; J5.12 74.19,13.58 ; J5.12 76.98,16.37 ; 81.77,4.01 J12.22 79.76,4.01 ; J5.10 76.98,7.9 ; J5.10 76.98,10.69 ; J5.10 74.19,10.69 ; J5.10 74.19,7.9 ; J41.14 273,8.43 ; J41.14 270.98,6.42 ; J41.14 273,6.42 ; J41.14 270.98,8.43 ; 234.11,18.46 J21.100 ; J21.100 234.11,20.47 ; J21.100 236.12,20.47 ; J21.100 236.12,18.46 ; 234.11,12.09 J21.98 ; J21.98 234.11,10.08 ; J21.98 236.12,12.09 ; J21.98 236.12,10.08 ; 94.26,4.01 J12.23 96.27,4.01
  L5PWR w1.016: 170.6,18.46 J21.99 ; J21.99 172.61,20.47 ; J21.99 172.61,18.46 ; J21.99 170.6,20.47 ; 133.72,20.47 J19.27 ; J19.27 133.72,18.46 ; J19.27 135.74,20.47 ; J19.27 135.74,18.46 ; J9.21 105.92,8.61 ; J9.21 101.89,8.61 ; J9.21 101.89,4.58 ; J9.21 105.92,4.58 ; J5.12 76.98,16.37 ; J5.12 76.98,13.58 ; J5.12 74.19,16.37 ; J5.12 74.19,13.58 ; J5.10 76.98,7.9 ; J5.10 74.19,7.9 ; J5.10 74.19,10.69 ; J5.10 76.98,10.69 ; J12.21 96.27,10.47 ; J12.21 94.26,10.47 ; J12.21 94.26,6.66 ; J12.21 96.27,6.66 ; J5.9 63.84,7.9 ; J5.9 61.05,10.69 ; J5.9 63.84,10.69 ; J5.9 61.05,7.9 ; 126.87,16.61 J9.10 ; J9.10 130.91,12.58 ; J9.10 130.91,16.61 ; J9.10 126.87,12.58 ; 270.98,6.42 J41.14 ; J41.14 273,6.42 ; J41.14 270.98,8.43 ; J41.14 273,8.43 ; J5.11 63.84,16.37 ; J5.11 63.84,13.58 ; J5.11 61.05,13.58 ; J5.11 61.05,16.37 ; J21.97 172.61,10.08 ; J21.97 172.61,12.09 ; J21.97 170.6,10.08 ; J21.97 170.6,12.09 ; J20.13 154.24,6.42 ; J20.13 154.24,8.43 ; J20.13 152.22,8.43 ; J20.13 152.22,6.42 ; J19.28 152,20.47 ; J19.28 149.98,18.46 ; J19.28 152,18.46 ; J19.28 149.98,20.47 ; 79.76,4.01 J12.22 81.77,4.01 ; 94.26,4.01 J12.23 96.27,4.01 ; J40.14 254.5,6.42 ; J40.14 252.48,6.42 ; J40.14 254.5,8.43 ; J40.14 252.48,8.43 ; 126.87,4.58 J9.20 ; J9.20 130.91,4.58 ; J9.20 126.87,8.61 ; J9.20 130.91,8.61 ; J12.20 81.77,10.47 ; J12.20 79.76,10.47 ; J12.20 81.77,6.66 ; J12.20 79.76,6.66 ; 234.11,20.47 J21.100 ; J21.100 234.11,18.46 ; J21.100 236.12,20.47 ; J21.100 236.12,18.46 ; 254.72,6.42 J41.13 ; J41.13 256.74,8.43 ; J41.13 254.72,8.43 ; J41.13 256.74,6.42 ; 149.98,12.09 J19.26 ; J19.26 149.98,10.08 ; J19.26 152,10.08 ; J19.26 152,12.09 ; J9.22 105.92,16.61 ; J9.22 101.89,16.61 ; J9.22 105.92,12.58 ; J9.22 101.89,12.58 ; 168.48,8.43 J20.14 ; J20.14 170.5,6.42 ; J20.14 170.5,8.43 ; J20.14 168.48,6.42 ; J19.25 135.74,12.09 ; J19.25 133.72,12.09 ; J19.25 135.74,10.08 ; J19.25 133.72,10.08 ; 236.22,8.43 J40.13 ; J40.13 238.24,8.43 ; J40.13 236.22,6.42 ; J40.13 238.24,6.42 ; 234.11,12.09 J21.98 ; J21.98 236.12,12.09 ; J21.98 236.12,10.08 ; J21.98 234.11,10.08
  L7GND w1.016: 270.98,8.43 J41.14 ; J41.14 273,6.42 ; J41.14 273,8.43 ; J41.14 270.98,6.42 ; J21.98 236.12,12.09 ; J21.98 234.11,12.09 ; J21.98 234.11,10.08 ; J21.98 236.12,10.08 ; J19.26 152,12.09 ; J19.26 152,10.08 ; J19.26 149.98,12.09 ; J19.26 149.98,10.08 ; J19.28 152,20.47 ; J19.28 152,18.46 ; J19.28 149.98,20.47 ; J19.28 149.98,18.46 ; J5.9 63.84,10.69 ; J5.9 63.84,7.9 ; J5.9 61.05,7.9 ; J5.9 61.05,10.69 ; 170.6,10.08 J21.97 ; J21.97 172.61,10.08 ; J21.97 170.6,12.09 ; J21.97 172.61,12.09 ; 133.72,12.09 J19.25 ; J19.25 135.74,10.08 ; J19.25 133.72,10.08 ; J19.25 135.74,12.09 ; J12.20 81.77,6.66 ; J12.20 81.77,10.47 ; J12.20 79.76,6.66 ; J12.20 79.76,10.47 ; 168.48,8.43 J20.14 ; J20.14 170.5,8.43 ; J20.14 168.48,6.42 ; J20.14 170.5,6.42 ; 61.05,13.58 J5.11 ; J5.11 63.84,13.58 ; J5.11 61.05,16.37 ; J5.11 63.84,16.37 ; J40.13 238.24,8.43 ; J40.13 236.22,6.42 ; J40.13 238.24,6.42 ; J40.13 236.22,8.43 ; 96.27,4.01 J12.23 94.26,4.01 ; J5.12 76.98,13.58 ; J5.12 76.98,16.37 ; J5.12 74.19,13.58 ; J5.12 74.19,16.37 ; J12.21 96.27,6.66 ; J12.21 94.26,6.66 ; J12.21 96.27,10.47 ; J12.21 94.26,10.47 ; 252.48,6.42 J40.14 ; J40.14 254.5,8.43 ; J40.14 254.5,6.42 ; J40.14 252.48,8.43 ; J9.22 105.92,12.58 ; J9.22 105.92,16.61 ; J9.22 101.89,12.58 ; J9.22 101.89,16.61 ; 126.87,8.61 J9.20 ; J9.20 130.91,8.61 ; J9.20 126.87,4.58 ; J9.20 130.91,4.58 ; J21.99 172.61,20.47 ; J21.99 170.6,18.46 ; J21.99 170.6,20.47 ; J21.99 172.61,18.46 ; J19.27 135.74,18.46 ; J19.27 133.72,18.46 ; J19.27 133.72,20.47 ; J19.27 135.74,20.47 ; J5.10 76.98,7.9 ; J5.10 74.19,10.69 ; J5.10 76.98,10.69 ; J5.10 74.19,7.9 ; J41.13 256.74,6.42 ; J41.13 254.72,8.43 ; J41.13 256.74,8.43 ; J41.13 254.72,6.42 ; 234.11,18.46 J21.100 ; J21.100 236.12,20.47 ; J21.100 234.11,20.47 ; J21.100 236.12,18.46 ; 101.89,4.58 J9.21 ; J9.21 105.92,4.58 ; J9.21 101.89,8.61 ; J9.21 105.92,8.61 ; 81.77,4.01 J12.22 79.76,4.01 ; 126.87,12.58 J9.10 ; J9.10 130.91,16.61 ; J9.10 126.87,16.61 ; J9.10 130.91,12.58 ; J20.13 154.24,6.42 ; J20.13 152.22,6.42 ; J20.13 152.22,8.43 ; J20.13 154.24,8.43
  BOTTOM w0.508: v1(220.6,36.45) 221.49,36.45 C555.2 221.49,37.21 v1(220.6,37.21) ; v1(172.97,51.82) 173.86,51.82 C520.1 173.86,51.05 v1(172.97,51.05) ; v1(204.72,30.23) 205.61,30.23 C505.1 205.61,29.46 v1(204.72,29.46) ; v1(232.28,35.05) 232.28,35.56 C559.2 233.3,35.56 v1(233.3,35.05) ; v1(188.85,29.46) 189.74,29.46 C534.1 189.74,30.23 v1(188.85,30.23) ; v1(241.17,23.24) 241.17,22.73 C1075.2 240.16,22.73 v1(240.16,23.24) ; v1(155.32,23.11) 155.32,22.61 C402.2 156.34,22.61 v1(156.34,23.11) ; v1(147.57,36.96) 147.57,37.47 C376.2 146.56,37.47 v1(146.56,36.96) ; v1(220.6,29.46) 221.49,29.46 C533.1 221.49,30.23 v1(220.6,30.23) ; v1(188.85,51.05) 189.74,51.05 C549.1 189.74,51.82 v1(188.85,51.82) ; v1(130.81,30.86) 130.81,31.37 C353.2 131.83,31.37 v1(131.83,30.86) ; v1(204.72,37.21) 205.61,37.21 C551.2 205.61,36.45 v1(204.72,36.45) ; v1(204.72,51.82) 205.61,51.82 C519.1 205.61,51.05 v1(204.72,51.05) ; v1(135.26,36.96) 135.26,37.47 C382.2 136.27,37.47 v1(136.27,36.96) ; v1(220.6,51.05) 221.49,51.05 C548.1 221.49,51.82 v1(220.6,51.82) ; v1(241.17,25.65) 241.17,26.16 C1081.2 240.16,26.16 v1(240.16,25.65) ; v1(188.72,36.45) 189.61,36.45 C560.2 189.61,37.21 v1(188.72,37.21) ; v1(172.97,29.46) 173.86,29.46 C506.1 173.86,30.23 v1(172.97,30.23) ; v1(165.99,26.42) 165.99,26.92 C408.2 167.01,26.92 v1(167.01,26.42) ; v1(156.34,26.42) 156.34,26.92 C405.2 155.32,26.92 v1(155.32,26.42) ; v1(259.59,25.65) 259.59,26.16 C1112.2 258.57,26.16 v1(258.57,25.65) ; v1(172.97,37.21) 173.86,37.21 C552.2 173.86,36.45 v1(172.97,36.45) ; v1(269.24,25.65) 269.24,26.16 C1115.2 270.26,26.16 v1(270.26,25.65) ; v1(136.27,34.92) 136.27,34.42 C374.2 135.26,34.42 v1(135.26,34.92) ; v1(251.84,25.65) 251.84,26.16 C1078.2 250.83,26.16 v1(250.83,25.65) ; v1(259.59,23.24) 259.59,22.73 C1109.2 258.57,22.73 v1(258.57,23.24) ; C347.2 119.89,31.37 v1(119.89,30.86) 119.89,30.35 C345.2 120.9,30.35 v1(120.9,30.86) 120.9,31.37 C347.2
  BOTTOM w1.016: J19.28 152,20.47 ; J19.28 152,18.46 ; J19.28 149.98,20.47 ; J19.28 149.98,18.46 ; J21.97 172.61,12.09 ; J21.97 170.6,12.09 ; J21.97 170.6,10.08 ; J21.97 172.61,10.08 ; J5.11 63.84,13.58 ; J5.11 61.05,13.58 ; J5.11 61.05,16.37 ; J5.11 63.84,16.37 ; J41.14 273,6.42 ; J41.14 270.98,6.42 ; J41.14 270.98,8.43 ; J41.14 273,8.43 ; J41.13 256.74,8.43 ; J41.13 256.74,6.42 ; J41.13 254.72,6.42 ; J41.13 254.72,8.43 ; 170.6,20.47 J21.99 ; J21.99 170.6,18.46 ; J21.99 172.61,20.47 ; J21.99 172.61,18.46 ; 234.11,12.09 J21.98 ; J21.98 236.12,12.09 ; J21.98 236.12,10.08 ; J21.98 234.11,10.08 ; 74.19,13.58 J5.12 ; J5.12 74.19,16.37 ; J5.12 76.98,13.58 ; J5.12 76.98,16.37 ; J20.13 154.24,8.43 ; J20.13 152.22,6.42 ; J20.13 152.22,8.43 ; J20.13 154.24,6.42 ; J12.20 81.77,6.66 ; J12.20 79.76,6.66 ; J12.20 81.77,10.47 ; J12.20 79.76,10.47 ; 74.19,7.9 J5.10 ; J5.10 76.98,10.69 ; J5.10 76.98,7.9 ; J5.10 74.19,10.69 ; J19.26 152,10.08 ; J19.26 152,12.09 ; J19.26 149.98,12.09 ; J19.26 149.98,10.08 ; 61.05,10.69 J5.9 ; J5.9 63.84,10.69 ; J5.9 61.05,7.9 ; J5.9 63.84,7.9 ; 130.91,4.58 J9.20 126.87,4.58 ; J40.14 254.5,8.43 ; J40.14 252.48,8.43 ; J40.14 252.48,6.42 ; J40.14 254.5,6.42 ; 101.89,4.58 J9.21 ; J9.21 105.92,8.61 ; J9.21 101.89,8.61 ; J9.21 105.92,4.58 ; 234.11,20.47 J21.100 ; J21.100 234.11,18.46 ; J21.100 236.12,20.47 ; J21.100 236.12,18.46 ; J40.13 238.24,8.43 ; J40.13 236.22,8.43 ; J40.13 236.22,6.42 ; J40.13 238.24,6.42 ; 168.48,8.43 J20.14 ; J20.14 170.5,6.42 ; J20.14 168.48,6.42 ; J20.14 170.5,8.43 ; 94.26,10.47 J12.21 ; J12.21 94.26,6.66 ; J12.21 96.27,10.47 ; J12.21 96.27,6.66 ; 101.89,16.61 J9.22 ; J9.22 105.92,16.61 ; J9.22 101.89,12.58 ; J9.22 105.92,12.58 ; 81.77,4.01 J12.22 79.76,4.01 ; 94.26,4.01 J12.23 96.27,4.01
  vias: v3(61.98,2.92) v3(66.42,2.92) v3(72.14,2.92) v3(77.85,2.92) v3(83.57,2.92) v3(87.38,2.92) v3(91.82,2.92) v3(98.17,2.92) v3(103.25,2.92) v3(108.33,2.92) v3(113.41,2.92) v3(118.49,2.92) v3(123.57,2.92) v3(128.65,2.92) v3(133.73,2.92) v3(140.08,2.92) v3(146.43,2.92) v3(152.15,2.92) v3(158.5,2.92) v3(164.85,2.92) v3(170.56,2.92) v3(176.28,2.92) v3(181.99,2.92) v3(187.71,2.92) v3(193.42,2.92) v3(198.5,2.92) v3(203.58,2.92) v3(209.3,2.92) v3(214.38,2.92) v3(219.46,2.92) v3(224.54,2.92) v3(229.62,2.92) v3(235.97,2.92) v3(242.32,2.92) v3(248.03,2.92) v3(254.38,2.92) v3(260.73,2.92) v3(267.72,2.92) v3(273.43,2.92) v3(279.15,2.92) v3(284.23,12.45) v3(284.23,8) v3(284.23,3.56)
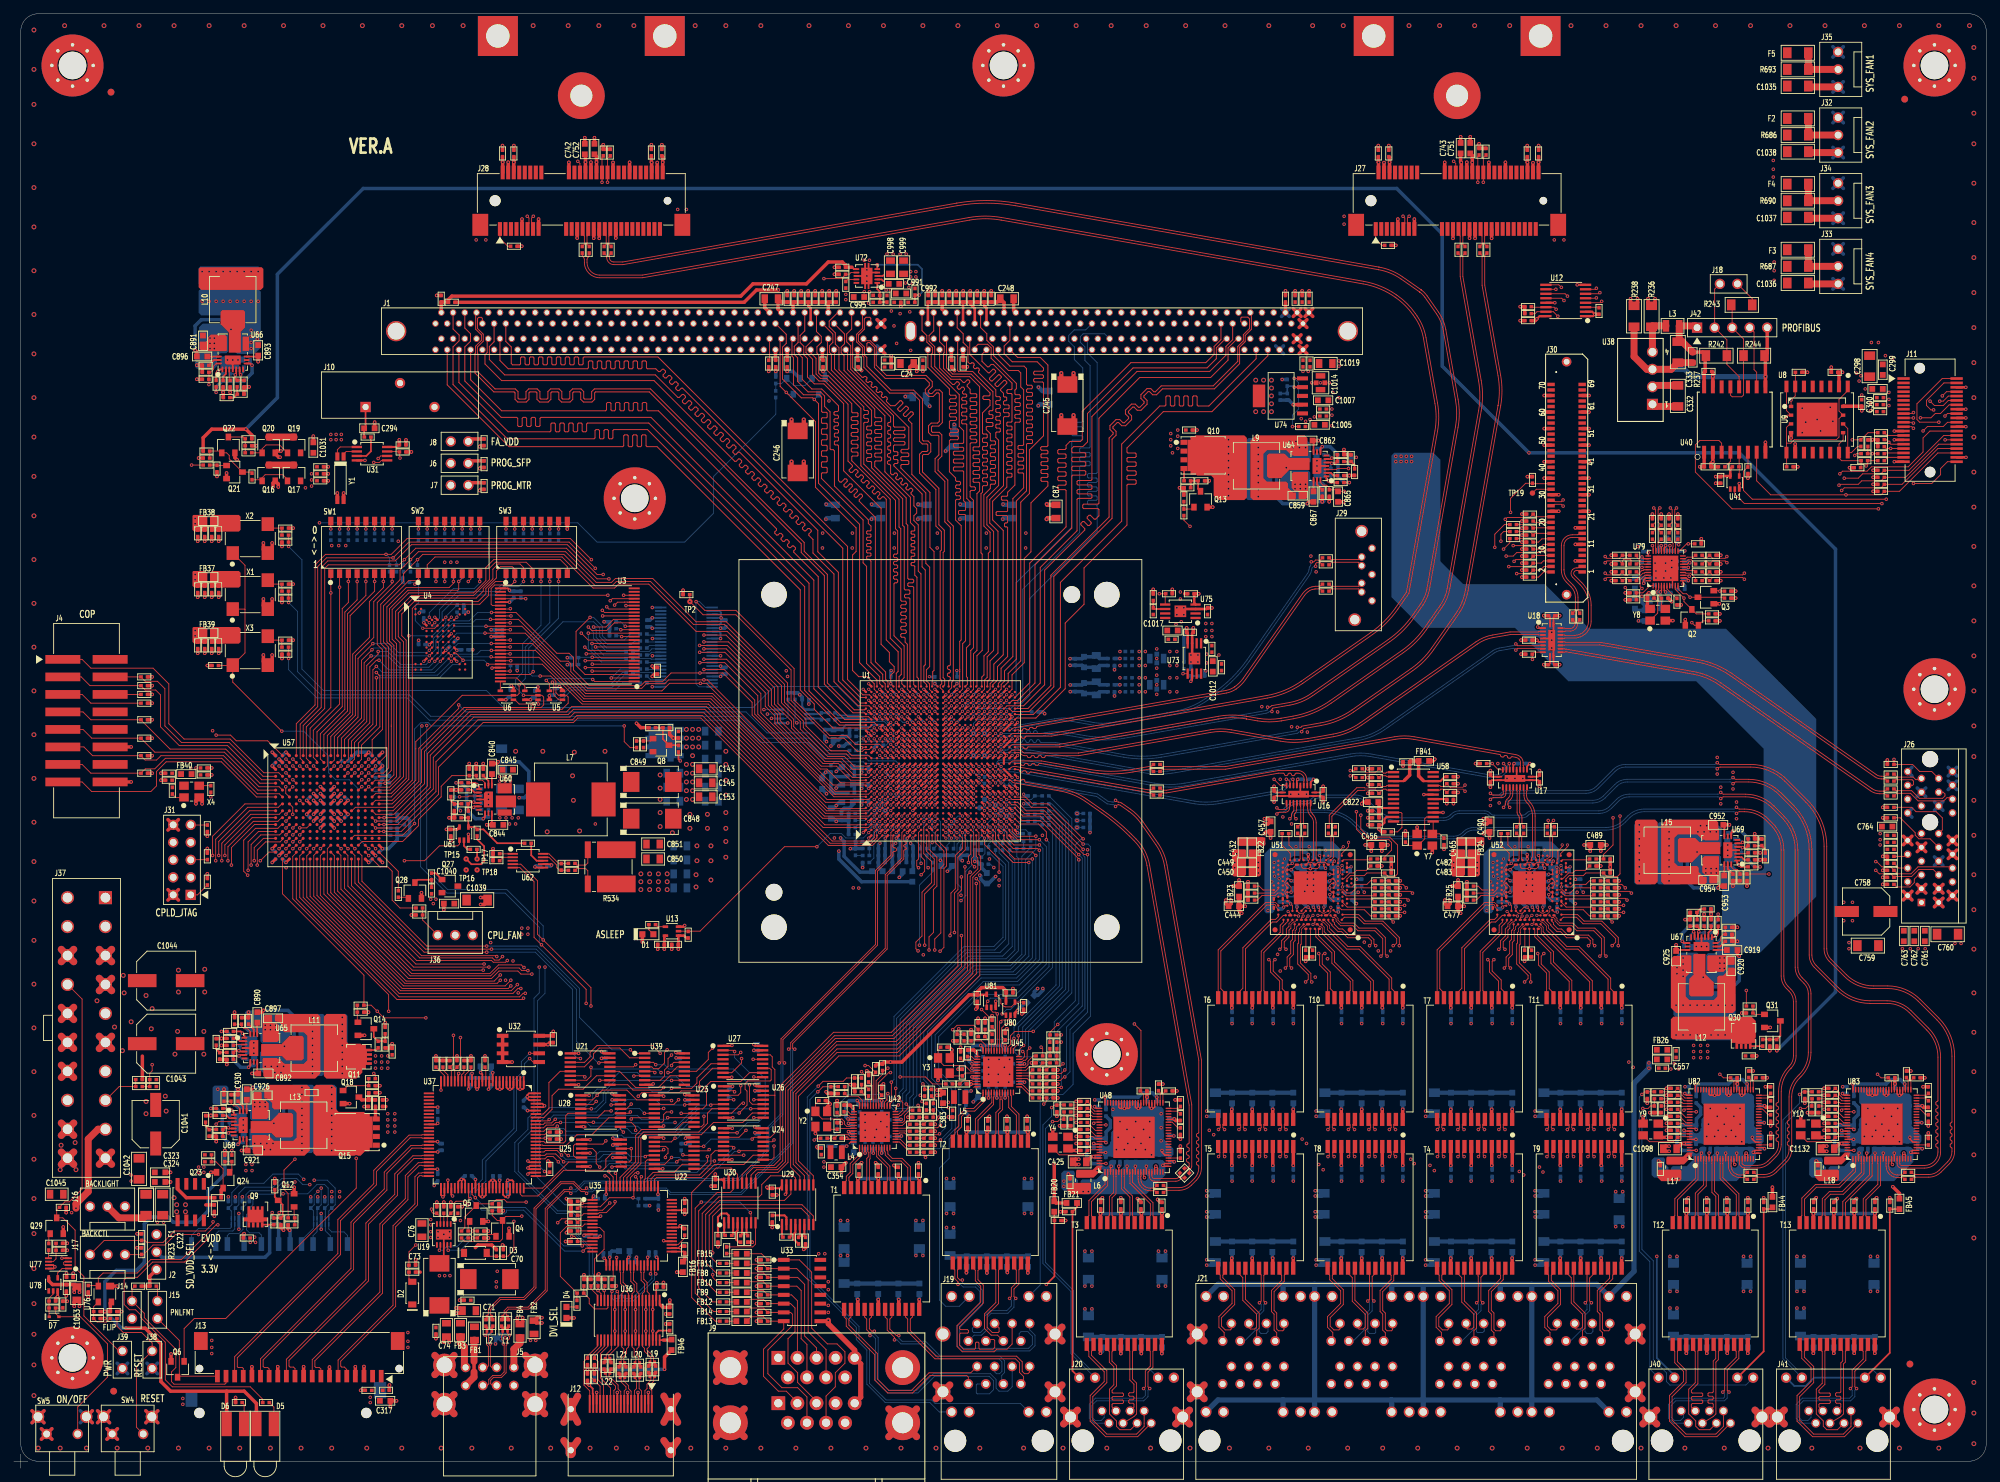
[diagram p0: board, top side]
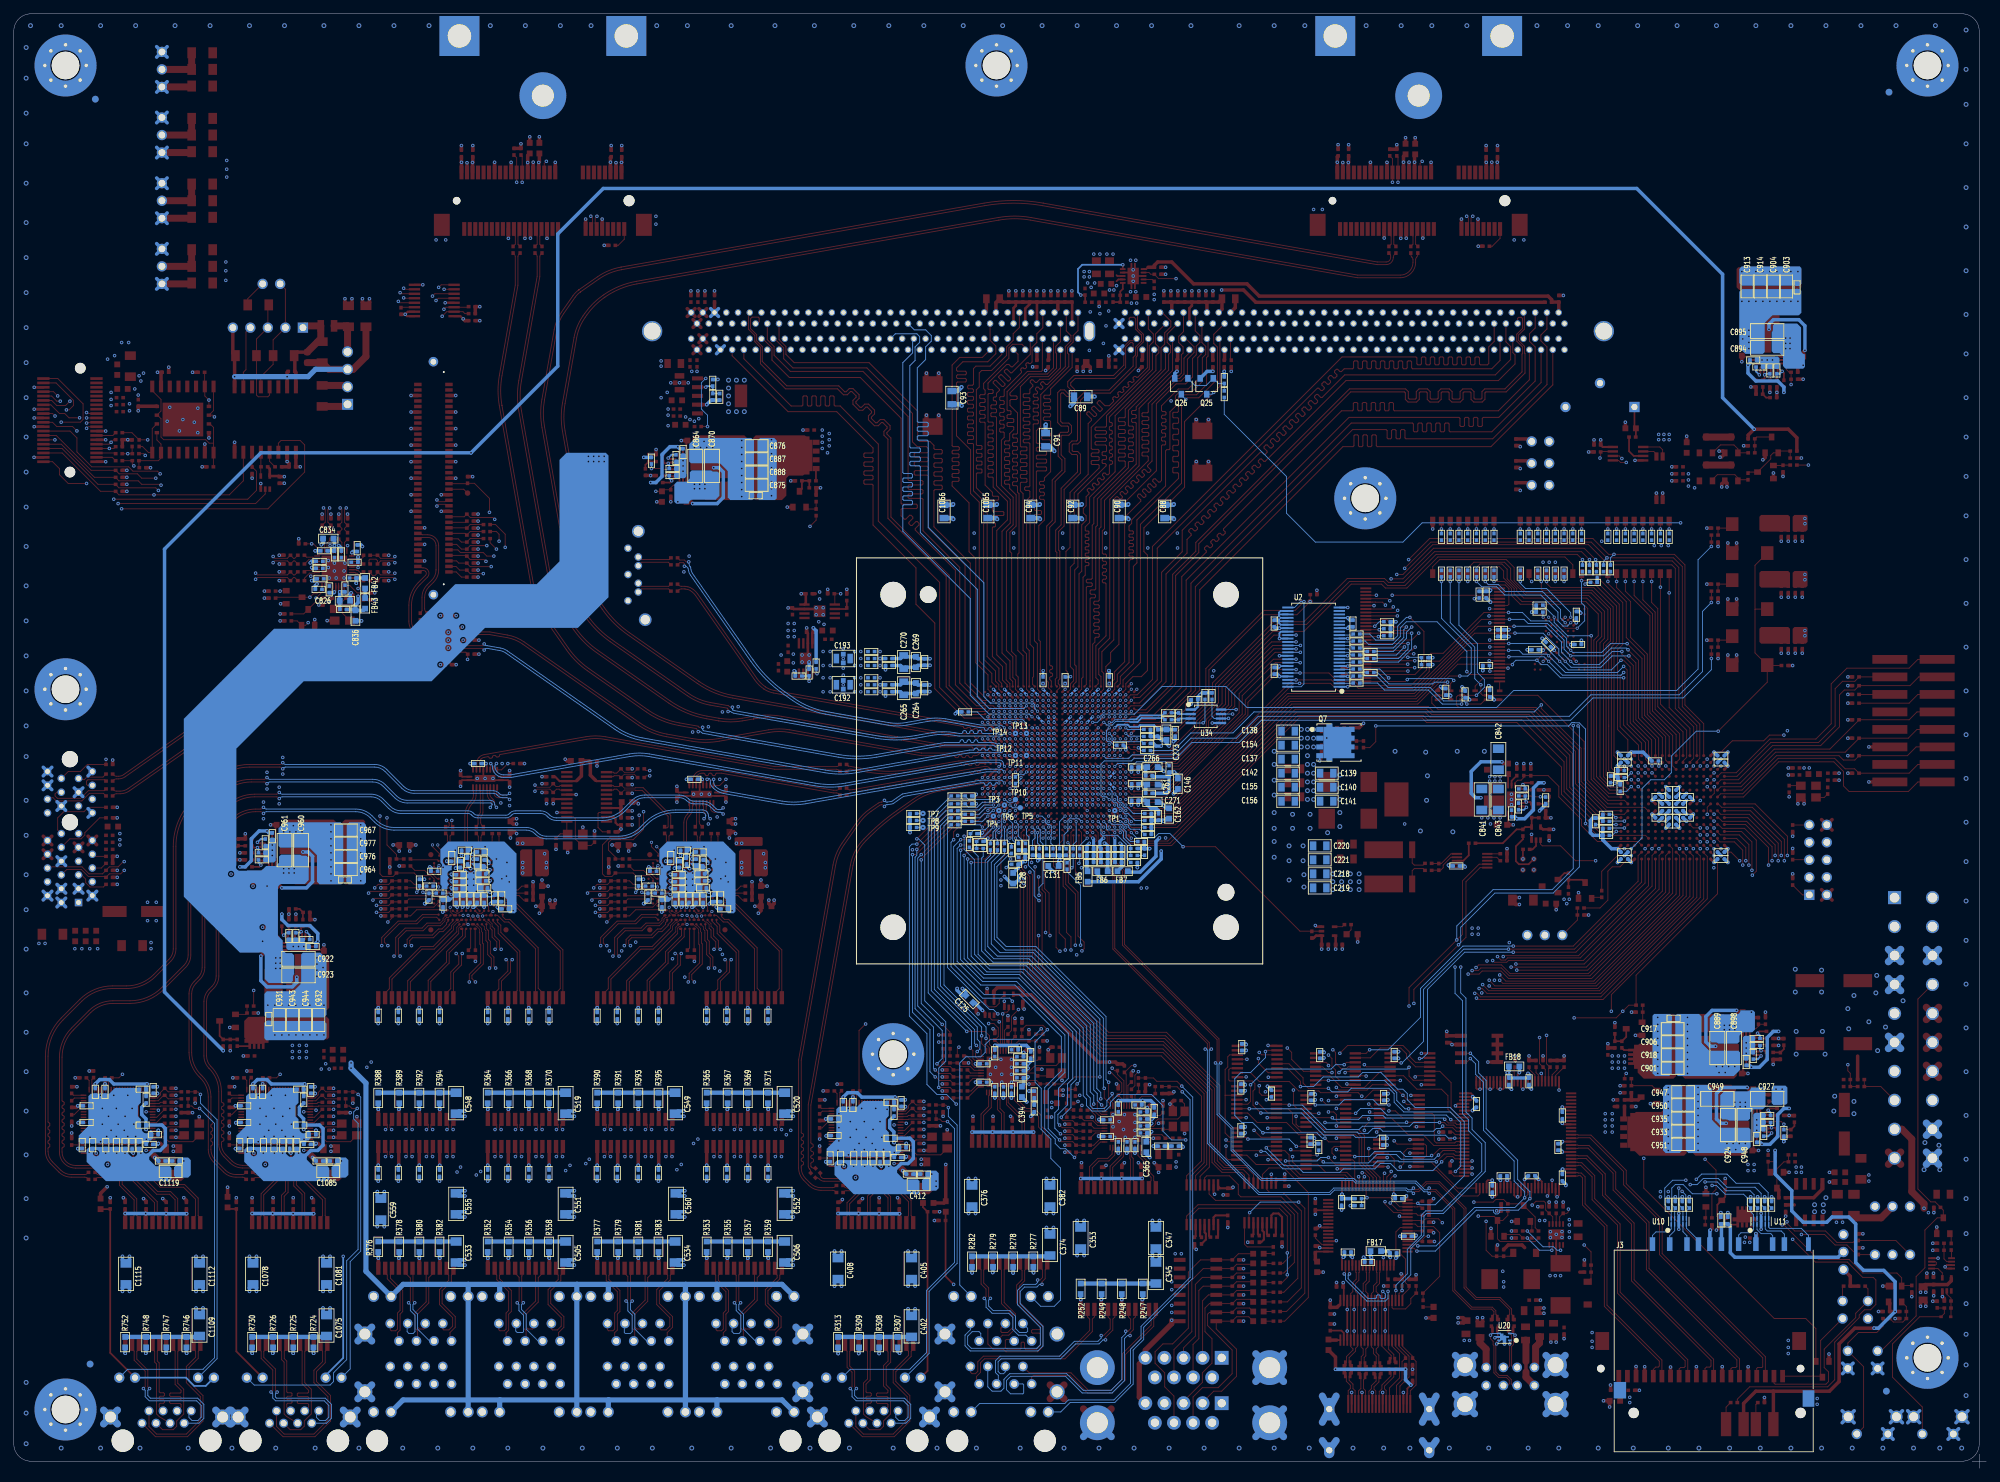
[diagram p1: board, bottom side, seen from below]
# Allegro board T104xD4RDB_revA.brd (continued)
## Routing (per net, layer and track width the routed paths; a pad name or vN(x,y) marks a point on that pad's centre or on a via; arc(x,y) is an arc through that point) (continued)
EC1_GTXCLK: length 50
  TOP w0.127: v1(129.41,52.83) 129.67,52.58 129.67,52.2 128.65,51.18 128.52,51.18 128.27,50.93 U42.22
  BOTTOM w0.127: R132.1 145.44,88.75 145.67,88.52 145.67,75.06 144.02,73.41 138.94,73.41 129.92,64.39 129.92,54.61 129.41,54.1 v1(129.41,52.83)
EC1_INT_N: length 67.9
  TOP w0.127: U1.AB4 v2(140.77,93.82) ; R262.2 131.29,52.48 v1(131.13,52.64)
  L3SIG w0.102: v2(140.77,93.82) 141.16,93.42 141.16,92.84 141.36,92.64 141.72,92.64 141.98,92.37 141.98,87.76 141.16,86.93 141.16,79.63 137.96,76.43 130.78,76.43 130.18,75.82 130.18,68.45 121.67,59.94 121.67,55.91 121.74,55.83 121.74,55.47 121.67,55.4 121.67,55.37 124.84,52.2 130.68,52.2 v1(131.13,52.64)
  BOTTOM w0.127: v2(140.77,93.82) 140.36,93.41 140.36,91.69 R84.1
EC1_LED0: length 3.4
  TOP w0.127: U42.34 123.44,54.08 R274.1 122.91,55.63 R259.1
EC1_LED1: length 4.8
  TOP w0.127: R260.1 R275.1 120.88,53.98 122.43,53.98 123.04,53.36 U42.35
EC1_MDI0_N: length 6.8
  TOP w0.127: T1.11 121.41,41.41 121.1,41.71 121.1,42.2 121.67,42.77 121.67,44.04 123,45.37 123,45.91 123.04,45.95 U42.2
EC1_MDI0_P: length 6.8
  TOP w0.127: T1.12 120.42,41.42 120.72,41.73 120.72,42.36 121.29,42.93 121.29,44.2 122.62,45.53 122.62,46.07 122.66,46.11 122.66,46.51 U42.1
EC1_MDI1_N: length 6
  TOP w0.127: U42.5 124.24,45.92 124.17,45.85 124.17,44.89 124.07,44.79 124.07,41.79 124.38,41.49 T1.8
EC1_MDI1_P: length 6.1
  TOP w0.127: U42.4 123.84,45.92 123.91,45.85 123.91,45.17 123.69,44.95 123.69,41.78 123.39,41.47 T1.9
EC1_MDI2_N: length 6.7
  TOP w0.127: T1.5 127.35,41.44 127.04,41.74 127.04,43.81 125.38,45.48 125.38,45.96 125.44,46.02 U42.8
EC1_MDI2_P: length 6.6
  TOP w0.127: T1.6 126.36,41.39 126.66,41.7 126.66,43.66 125.12,45.19 125.12,45.96 125.06,46.02 125.06,46.51 U42.7
EC1_MDI3_N: length 8.2
  TOP w0.127: T1.2 130.32,41.39 130.01,41.69 130.01,43.75 128.81,44.96 127.38,44.96 126.75,45.59 126.75,46.03 126.64,46.13 U42.11
EC1_MDI3_P: length 8.2
  TOP w0.127: U42.10 126.24,45.99 126.37,45.87 126.37,45.44 127.22,44.58 128.65,44.58 129.63,43.6 129.63,41.75 129.33,41.44 T1.3
EC1_MDX0_N: length 28.5
  TOP w0.127: J19.B2 138.76,13.84 132.72,13.84 130.18,11.3 126.87,11.3 125.22,12.95 125.22,16.64 121.09,20.77 121.09,21.64 121.4,21.94 T1.14
EC1_MDX0_P: length 28.6
  TOP w0.127: T1.13 120.41,21.94 120.71,21.64 120.71,20.61 124.84,16.48 124.84,12.8 126.72,10.92 130.33,10.92 132.87,13.46 138.18,13.46 138.42,13.22 J19.B1
EC1_MDX1_N: length 37.2
  TOP w0.127: T1.17 124.37,21.94 124.06,21.64 124.06,20.24 124.42,19.88 v1(124.78,19.88)
  BOTTOM w0.127: J19.B6 144.78,14.75 144.78,11.81 144.15,11.18 142.88,11.18 142.44,11.61 142.44,12.88 141.61,13.72 133.35,13.72 130.94,11.3 126.9,11.3 125.35,12.86 125.35,18.95 124.78,19.52 v1(124.78,19.88)
EC1_MDX1_P: length 37
  TOP w0.127: v1(124.15,19.25) 124.15,19.61 123.68,20.08 123.68,21.64 123.38,21.94 T1.16
  BOTTOM w0.127: J19.B3 139.7,12.23 139.57,12.1 139.57,10.92 139.7,10.8 141.48,10.8 142.06,11.38 142.06,12.72 141.45,13.33 133.51,13.33 131.09,10.92 127.06,10.92 126.75,10.92 124.97,12.7 124.97,18.8 124.51,19.25 v1(124.15,19.25)
EC1_MDX2_N: length 25.4
  TOP w0.127: T1.20 127.34,21.94 127.03,21.64 127.03,20.19 127.98,19.24 v1(128.34,19.24)
  BOTTOM w0.127: J19.B5 143.26,12.47 143.26,13.47 143.66,13.88 143.66,15.6 143,16.26 134.37,16.26 132.21,18.42 128.81,18.42 128.34,18.89 v1(128.34,19.24)
EC1_MDX2_P: length 25.4
  TOP w0.127: v1(127.71,18.62) 127.71,18.98 126.65,20.03 126.65,21.64 126.35,21.94 T1.19
  BOTTOM w0.127: v1(127.71,18.62) 128.07,18.62 128.65,18.03 132.05,18.03 134.21,15.88 142.84,15.88 143.28,15.44 143.28,14.04 142.96,13.72 142.49,13.72 142.23,13.98 J19.B4
EC1_MDX3_N: length 24.8
  TOP w0.127: T1.23 130.31,21.94 130,21.64 130,19.98 133.73,16.26 145.42,16.26 146.23,15.44 146.23,14.05 146.56,13.72 147.07,13.72 147.31,13.96 J19.B8
EC1_MDX3_P: length 24.9
  TOP w0.127: T1.22 129.32,21.94 129.62,21.64 129.62,19.83 133.57,15.88 145.26,15.88 145.85,15.29 145.85,13.89 146.43,13.3 146.43,12.62 J19.B7
EC1_PME_N: length 55.9
  TOP w0.127: U1.AD5 v2(142.37,94.62) ; v1(122.94,57.53) 123.44,57.02 123.44,55.5 123.95,54.99 R264.2
  L3SIG w0.102: v2(142.37,94.62) 142.75,94.23 142.75,87 141.8,86.04 141.8,79.18 135.51,72.9 135.51,72.86 134.99,72.34 134.95,72.34 122.94,60.33 v1(122.94,57.53)
  BOTTOM w0.127: v2(142.37,94.62) 142.24,94.62 141.17,93.55 141.17,91.13 140.82,90.78 140.82,89.16 R85.1
EC1_REFCLK: length 76.2
  TOP w0.127: U1.AG3 144.37,93.38 144.78,92.96 144.78,92.41 145.49,91.69 v1(148.21,91.69) ; v1(116.08,47.62) 116.33,47.88 R258.2
  BOTTOM w0.127: v1(116.08,47.62) 118.11,47.62 119.38,48.9 119.38,52.58 121.03,54.23 125.86,54.23 127,53.09 127,52.58 127.76,51.82 129.67,51.82 130.46,52.61 130.46,53.56 130.94,54.04 130.94,63.88 139.45,72.39 144.53,72.39 146.69,74.55 146.69,88.27 148.21,89.79 v1(148.21,91.69)
EC1_RST_N: length 156.3
  TOP w0.127: U57.M2 38.97,92.31 38.54,91.88 35.81,91.88 34.42,90.49 v1(34.42,87.5) ; U42.29 125.44,52.99 125.35,53.09 125.35,53.62 R265.2 125.35,54.64 125.35,55.88 126.87,57.4 v1(127.13,57.4)
  L6SIG w0.102: v1(127.13,57.4) 126.49,57.4 125.03,58.86 122.11,58.86 118.95,55.7 118.95,54.03 115.51,50.59 115.51,44.51 112.2,41.21 108.97,41.21 100.65,32.89 95.63,32.89 95.01,32.27 83.11,32.27 81.41,33.97 81.41,35.05 80.01,36.45 79.18,36.45 73.31,42.32 73.31,45.24 69.28,49.28 61.09,49.28 56.01,54.36 56.01,66.74 39.37,83.38 37.85,83.38 34.42,86.8 v1(34.42,87.5)
EC1_RXCLK: length 2.1
  TOP w0.127: R714.1 R710.1 133.32,51.94 R250.1
EC1_RXCTL: length 66.2
  TOP w0.127: R256.1 R273.1 131.98,45.31 v1(132.21,45.09) ; v1(148.72,91.19) 145.55,91.19 144.37,92.37 U1.AG2
  BOTTOM w0.127: v1(132.21,45.09) 133.48,46.35 134.24,46.35 135,47.12 135,47.75 136.53,49.28 136.53,55.24 134.11,57.66 134.11,62.61 140.21,68.71 145.29,68.71 149.73,73.15 149.73,90.17 v1(148.72,91.19)
EC1_RXD0: length 64.4
  TOP w0.127: U1.AF2 143.6,92.62 144.02,92.2 144.02,91.44 145.03,90.42 v1(148.72,90.42) ; v1(134.37,47.62) 134.11,47.37 132.46,47.37 131.98,46.89 R269.1 R251.1
  BOTTOM w0.127: v1(134.37,47.62) 136.02,49.28 136.02,54.99 133.6,57.4 133.6,62.87 140.84,70.1 145.8,70.1 149.23,73.53 149.23,89.92 v1(148.72,90.42)
EC1_RXD1: length 61.7
  TOP w0.127: v1(134.24,48.51) 134.11,48.39 132.46,48.39 131.98,47.9 R270.1 R253.1 ; U1.AF1 143.57,91.26 144.91,89.92 148.46,89.92 v1(148.72,89.66)
  BOTTOM w0.127: v1(148.72,89.66) 148.72,73.79 145.54,70.61 140.59,70.61 133.1,63.12 133.1,56.56 134.52,55.14 134.52,52.11 135.06,51.56 135.06,49.34 v1(134.24,48.51)
EC1_RXD2: length 60.4
  TOP w0.127: v1(134.37,49.78) 133.99,49.4 132.46,49.4 131.98,48.92 R271.1 R254.1 ; v1(148.21,88.9) 147.7,89.41 144.78,89.41 142.77,91.42 U1.AE1
  BOTTOM w0.127: v1(134.37,49.78) 134.62,50.04 134.62,51.31 133.22,52.7 133.22,55.75 132.46,56.52 132.46,63.31 140.27,71.12 145.42,71.12 148.21,73.91 v1(148.21,88.9)
EC1_RXD3: length 59.7
  TOP w0.127: R255.1 R272.1 131.98,49.94 132.46,50.42 133.86,50.42 134.11,50.67 v1(134.11,50.93) ; U1.AD2 141.97,92.6 142.37,92.2 142.37,91.19 145.16,88.39 v1(147.7,88.39)
  BOTTOM w0.127: v1(134.11,50.93) 132.72,52.32 132.72,55.63 131.95,56.39 131.95,63.37 140.21,71.63 145.29,71.63 147.7,74.04 v1(147.7,88.39)
EC1_RXDLY: length 3.8
  TOP w0.127: U42.32 124.24,53.38 124.46,53.59 124.46,55.52 R276.1
EC1_TXCTL: length 54.7
  TOP w0.127: U42.27 126.24,53.1 126.62,53.47 126.62,54.23 v1(126.75,54.36)
  BOTTOM w0.127: v1(126.75,54.36) 126.75,54.1 127.51,53.34 127.51,52.58 127.89,52.2 129.54,52.2 129.92,52.58 129.92,53.72 130.43,54.23 130.43,64.14 139.19,72.9 144.53,72.9 146.18,74.55 146.18,88.77 147.45,90.04 R135.1
EC1_TXD0: length 49.5
  TOP w0.127: U42.23 128.29,51.33 128.91,51.94 128.91,53.09 v1(128.4,53.59)
  BOTTOM w0.127: v1(128.4,53.59) 128.4,54.52 128.97,55.09 128.97,64.83 138.43,74.3 143.38,74.3 144.78,75.69 144.78,88.01 143.38,89.41 R133.1
EC1_TXD1: length 48.4
  TOP w0.127: U42.24 127.84,52.28 v1(128.27,52.7)
  BOTTOM w0.127: v1(128.27,52.7) 128.91,53.34 128.91,54.36 129.41,54.86 129.41,64.52 138.81,73.91 143.89,73.91 145.16,75.18 145.16,88.14 144.4,88.9 R125.1
EC1_TXD2: length 47.2
  TOP w0.127: v1(127.89,55.12) 127.89,53.72 127.04,52.87 U42.25
  BOTTOM w0.127: v1(127.89,55.12) 128.02,55.24 128.02,65.28 137.92,75.18 142.24,75.18 143.83,76.77 143.83,87.57 142.37,89.03 R127.1
EC1_TXD3: length 47.1
  TOP w0.127: v1(127.25,56.01) 127.25,53.59 126.64,52.98 U42.26
  BOTTOM w0.127: R129.1 141.58,89.18 143.45,87.31 143.45,77.03 142.11,75.69 137.8,75.69 127.64,65.53 127.64,56.39 v1(127.25,56.01)
EC2_GTXCLK: length 42.4
  TOP w0.127: U45.22 146.18,58.93 146.43,59.18 146.69,59.18 146.94,59.44 146.94,60.58 v1(147.32,60.96)
  BOTTOM w0.127: R137.2 150.5,96.39 152.97,93.92 152.97,69.28 147.13,63.44 147.13,61.15 v1(147.32,60.96)
EC2_INT_N: length 66.2
  TOP w0.127: R292.2 149.2,60.86 v1(148.97,61.09) ; U1.D4 v2(125.57,93.82)
  L3SIG w0.102: v1(142.88,85.34) 143.45,84.77 143.45,69.66 148.97,64.13 v1(148.97,61.09) ; v1(122.52,84.17) 124.39,86.03 124.39,93.24 124.58,93.44 125.06,93.44 125.44,93.82 v2(125.57,93.82)
  L6SIG w0.102: v1(142.88,85.34) 141.92,84.39 139.38,84.39 138.47,85.31 129.18,85.31 127.76,83.88 122.81,83.88 v1(122.52,84.17)
  BOTTOM w0.127: v2(125.57,93.82) 125.34,93.82 124.93,93.41 124.58,93.41 124.33,93.17 124.33,92.96 124.08,92.71 122.78,92.71 R82.1
EC2_LED0: length 3.4
  TOP w0.127: R304.1 140.82,63.63 R289.1 141.35,62.08 U45.34
EC2_LED1: length 4.2
  TOP w0.127: U45.35 140.95,61.36 140.31,62 R305.1 R290.1
EC2_MDI0_N: length 9.6
  TOP w0.127: U45.2 140.95,53.95 140.9,53.91 140.9,53.37 139.35,51.82 138.21,51.82 137.41,51.02 137.41,49.5 136.85,48.94 136.85,48.44 137.15,48.14 T2.11
EC2_MDI0_P: length 9.6
  TOP w0.127: T2.12 136.17,48.15 136.47,48.46 136.47,49.09 137.03,49.66 137.03,51.18 138.05,52.2 139.19,52.2 140.52,53.53 140.52,54.07 140.57,54.11 140.57,54.51 U45.1
EC2_MDI1_N: length 8.2
  TOP w0.127: T2.8 140.12,48.09 139.82,48.39 139.82,50.51 142.08,52.76 142.08,53.85 142.15,53.92 U45.5
EC2_MDI1_P: length 8.2
  TOP w0.127: U45.4 141.75,53.92 141.82,53.85 141.82,53.05 139.44,50.67 139.44,48.51 139.14,48.2 T2.9
EC2_MDI2_N: length 7.5
  TOP w0.127: T2.5 143.09,48.17 142.79,48.47 142.79,51.45 143.38,52.04 143.38,53.38 143.28,53.48 143.28,53.96 143.35,54.03 U45.8
EC2_MDI2_P: length 7.5
  TOP w0.127: T2.6 142.11,48.25 142.41,48.56 142.41,51.6 143,52.2 143,53.45 143.03,53.48 143.03,53.96 142.97,54.03 142.97,54.51 U45.7
EC2_MDI3_N: length 7.7
  TOP w0.127: U45.11 144.55,54.13 144.65,54.03 144.65,52.48 145.76,51.37 145.76,48.42 146.06,48.12 T2.2
EC2_MDI3_P: length 7.7
  TOP w0.127: U45.10 144.15,53.99 144.27,53.87 144.27,52.32 145.38,51.22 145.38,48.48 145.07,48.17 T2.3
EC2_MDX0_N: length 31.8
  TOP w0.127: T2.14 137.15,29.07 136.84,28.76 136.84,27.66 137.19,27.3 v1(137.55,27.3)
  BOTTOM w0.127: v1(137.55,27.3) 137.55,26.95 137.83,26.67 139.6,26.67 140.46,25.81 140.46,23.72 137.16,20.42 137.16,17.91 137.67,17.4 147.16,17.4 147.7,17.94 147.7,19.15 147.04,19.81 146.05,19.81 145.8,19.56 145.8,18.7 J19.A2
EC2_MDX0_P: length 31.7
  TOP w0.127: T2.13 136.15,29.07 136.46,28.77 136.46,27.5 136.92,27.04 v1(136.92,26.68)
  BOTTOM w0.127: J19.A1 147.31,20.08 148.08,19.3 148.08,17.78 147.32,17.02 137.51,17.02 136.78,17.75 136.78,20.57 140.08,23.88 140.08,25.65 139.45,26.29 137.67,26.29 137.28,26.68 v1(136.92,26.68)
EC2_MDX1_N: length 25.7
  TOP w0.127: T2.17 140.12,28.99 139.81,28.69 139.81,27.35 140.59,26.57 140.59,23.97 137.16,20.54 137.16,20.24 137.29,20.11 138.3,20.11 138.43,19.98 138.43,19.73 138.3,19.6 137.29,19.6 137.16,19.47 137.16,17.81 137.7,17.27 139.32,17.27 139.45,17.4 139.45,18.16 139.57,18.29 139.83,18.29 139.95,18.16 139.95,17.4 140.08,17.27 141.99,17.27 142.24,17.53 142.24,18.54 142.11,18.67 141.17,18.67 J19.A6
EC2_MDX1_P: length 25.7
  TOP w0.127: T2.16 139.12,29.02 139.43,28.72 139.43,27.19 140.21,26.42 140.21,24.13 136.78,20.7 136.78,17.65 137.54,16.89 142.14,16.89 142.52,17.27 144.02,17.27 144.77,18.02 J19.A3
EC2_MDX2_N: length 13.7
  TOP w0.127: J19.A5 142.88,20.35 142.88,19.81 142.75,19.69 141.89,19.69 141.15,20.43 141.15,22.24 142.78,23.88 142.78,28.73 143.09,29.04 T2.20
EC2_MDX2_P: length 13.8
  TOP w0.127: T2.19 142.09,29.1 142.4,28.8 142.4,24.04 140.77,22.4 140.77,20.27 141.73,19.3 142.65,19.3 J19.A4
EC2_MDX3_N: length 16.7
  TOP w0.127: T2.23 146.06,29.09 145.75,28.78 145.75,26.72 145.03,26 145.03,24.89 v1(145.29,24.64)
  BOTTOM w0.127: J19.A8 139.26,19.3 140.34,19.3 141.15,20.12 141.15,21.89 141.73,22.48 144.15,22.48 145.03,23.37 145.03,24.38 v1(145.29,24.64)
EC2_MDX3_P: length 16.7
  TOP w0.127: v1(144.4,24.64) 144.65,24.89 144.65,26.16 145.37,26.88 145.37,28.75 145.06,29.05 T2.22
  BOTTOM w0.127: v1(144.4,24.64) 144.65,24.38 144.65,23.53 143.99,22.86 141.57,22.86 140.77,22.05 140.77,20.27 140.18,19.69 139.19,19.69 139,19.88 139,20.31 J19.A7
EC2_PME_N: length 63.1
  TOP w0.127: R294.2 141.86,62.99 141.35,63.5 141.35,65.53 v1(140.34,66.55) ; U1.D5 v2(125.57,94.62)
  L3SIG w0.102: v2(125.57,94.62) 125.18,94.23 124.61,94.23 124.35,93.97 124.35,93.64 123.57,92.86 123.57,86.04 v1(121.73,84.2) ; v1(142.88,84.52) 142.88,70.61 140.34,68.07 v1(140.34,66.55)
  L6SIG w0.102: v1(142.88,84.52) 142.49,84.14 139.26,84.14 138.32,85.08 129.28,85.08 127.83,83.63 122.3,83.63 v1(121.73,84.2)
  BOTTOM w0.127: v2(125.57,94.62) 125.17,94.22 124.58,94.22 124.36,94.01 124.36,93.63 124.08,93.34 122.4,93.34 R83.1
EC2_REFCLK: length 57.1
  TOP w0.127: U1.AC6 v2(141.57,95.42) ; R288.2 133.22,55.75 132.21,56.77 v1(128.52,56.77)
  BOTTOM w0.127: v2(141.57,95.42) 141.97,95.01 142.53,95.01 142.76,94.78 142.76,91.68 142.88,91.57 142.88,89.28 144.27,87.88 144.27,76.07 143,74.8 138.18,74.8 128.52,65.15 v1(128.52,56.77)
EC2_RST_N: length 172
  TOP w0.127: U57.N1 36.2,91.38 34.86,90.04 v1(34.86,88.14) ; U45.29 143.35,61 143.26,61.09 143.26,61.62 R295.2 143.26,62.64 143.26,63.88 143.89,64.52 v1(144.65,64.52)
  L6SIG w0.102: v1(144.65,64.52) 143.64,64.52 143.32,64.2 127,64.2 118.72,55.92 118.72,54.12 115.19,50.59 115.19,44.64 112.01,41.47 108.78,41.47 100.46,33.15 95.44,33.15 94.85,32.56 83.27,32.56 81.72,34.1 81.72,35.24 79.95,37.02 79.12,37.02 73.76,42.39 73.76,45.31 69.47,49.59 61.21,49.59 56.32,54.48 56.32,66.87 39.5,83.69 37.97,83.69 34.86,86.8 v1(34.86,88.14)
EC2_RXCLK: length 2.1
  TOP w0.127: R717.2 151.23,60.83 R713.2 R281.1
EC2_RXCTL: length 57.9
  TOP w0.127: v1(155.07,90.55) 149.73,95.89 147.57,95.89 146.43,97.03 144.75,97.03 U1.AG8 ; R286.1 R303.1 149.76,53.24 v1(149.35,52.83)
  BOTTOM w0.127: v1(155.07,90.55) 155.77,90.55 156.15,90.17 156.15,65.6 153.61,63.06 153.61,55.69 152.15,54.23 150.75,54.23 v1(149.35,52.83)
EC2_RXD0: length 54.2
  TOP w0.127: U1.AH8 145.21,97.37 146.72,97.37 147.7,96.39 149.99,96.39 v1(155.07,91.31) ; v1(151.89,55.24) 150.24,55.24 149.76,54.76 R299.1 R280.1
  BOTTOM w0.127: v1(155.07,91.31) 154.81,91.31 153.92,90.42 153.92,67.82 150.88,64.77 150.88,59.05 151.89,58.04 v1(151.89,55.24)
EC2_RXD1: length 52.2
  TOP w0.127: R283.1 R300.1 149.76,55.78 150.24,56.26 151.77,56.26 152.27,56.77 v1(152.4,56.77) ; U1.AG7 144.72,96.27 145.29,96.27 146.56,95 149.23,95 155.19,89.03 v1(155.7,89.03)
  BOTTOM w0.127: v1(155.7,89.03) 155.7,66.17 153.16,63.63 153.16,57.53 v1(152.4,56.77)
EC2_RXD2: length 50.2
  TOP w0.127: R284.1 R301.1 149.76,56.79 150.24,57.28 151.89,57.28 v1(152.4,57.78) ; U1.AH7 145.57,96.62 146.81,95.38 149.48,95.38 v1(155.07,89.79)
  BOTTOM w0.127: v1(152.4,57.78) 152.65,58.04 152.65,64.01 155.32,66.67 155.32,88.65 155.07,88.9 v1(155.07,89.79)
EC2_RXD3: length 48.3
  TOP w0.127: U1.AH6 145.17,95.75 146.3,94.61 148.84,94.61 v1(154.43,89.03) ; v1(152.15,58.67) 151.77,58.29 150.24,58.29 149.76,57.81 R302.1 R285.1
  BOTTOM w0.127: v1(154.43,89.03) 154.94,88.52 154.94,67.06 151.38,63.5 151.38,59.44 v1(152.15,58.67)
EC2_RXDLY: length 3.8
  TOP w0.127: U45.32 142.15,61.38 142.37,61.59 142.37,63.53 R306.1
EC2_TXCTL: length 43.8
  TOP w0.127: v1(147.83,63.37) 145.16,63.37 144.53,62.74 144.53,61.47 144.15,61.1 U45.27
  BOTTOM w0.127: v1(147.83,63.37) 153.42,68.96 153.42,94.23 150.11,97.54 R136.2
EC2_TXD0: length 42.1
  TOP w0.127: U45.23 146.2,59.33 146.56,59.69 146.56,60.2 v1(146.3,60.45)
  BOTTOM w0.127: v1(146.3,60.45) 145.92,60.83 145.92,61.85 146.3,62.23 146.3,64.01 152.02,69.72 152.02,93.47 150.62,94.87 R124.2
EC2_TXD1: length 39.9
  TOP w0.127: U45.24 145.75,60.66 v1(146.43,61.34)
  BOTTOM w0.127: v1(146.43,61.34) 146.69,61.59 146.69,63.63 152.53,69.47 152.53,93.73 150.88,95.38 R126.2
EC2_TXD2: length 37.5
  TOP w0.127: U45.25 144.95,60.87 145.67,61.6 v1(145.67,62.74)
  BOTTOM w0.127: R128.2 150.5,94.36 151.64,93.22 151.64,69.98 145.67,64.01 v1(145.67,62.74)
EC2_TXD3: length 38.7
  TOP w0.127: U45.26 144.55,60.98 145.03,61.47 v1(145.03,62.36)
  BOTTOM w0.127: v1(145.03,62.36) 145.03,64.01 151.13,70.1 151.13,93.22 150.5,93.85 R130.2
EMI1_MDC: length 214.9
  TOP w0.127: U51.C11 192.57,89.19 193.55,90.17 v2(193.55,90.81) ; U82.72 242.36,52.11 v1(242.19,51.94) ; U48.72 156.76,50.21 v1(156.59,50.04) ; U45.30 142.95,64.64 143.07,64.77 v1(143.13,64.77) 143.13,64.9 143.26,65.02 144.15,65.02 144.53,65.41 U80.2 ; U83.72 265.22,52.11 v1(265.05,51.94) ; U52.C11 224.32,89.19 225.3,90.17 v2(225.3,90.42)
  L3SIG w0.102: v1(143.13,64.77) 143.13,64.9 143.64,65.41 145.42,65.41 146.3,64.52 146.3,63.25 148.46,61.09 148.46,55.63 152.91,51.18 152.91,50.29 153.54,49.66 155.07,49.66 155.45,50.04 v1(156.59,50.04) 157.61,50.04 157.99,50.42 158.88,50.42 160.02,51.56 160.02,53.09 160.78,53.85 161.93,53.85 164.08,56.01 164.08,80.39 176.66,92.96 191.39,92.96 v2(193.55,90.81) 194.31,91.57 204.47,91.57 205.8,92.9 223.08,92.9 225.3,90.68 v2(225.3,90.42) 230.5,85.22 230.5,79.12 231.39,78.23 235.2,78.23 239.01,74.42 239.01,58.29 241.68,55.63 241.68,52.45 v1(242.19,51.94) 243.33,51.94 244.98,53.59 263.4,53.59 v1(265.05,51.94)
EMI1_MDC_SLP: length 58.5
  TOP w0.127: v1(126.75,58.04) 126.39,57.68 R140.2 125.98,57.15 125.04,56.21 U42.30 ; v1(143.32,65.91) 143.69,65.91 U80.1
  L3SIG w0.102: v1(143.32,65.91) 142.68,66.55 141.61,66.55 140.84,65.79 136.14,65.79 128.4,58.04 v1(126.75,58.04)
  BOTTOM w0.127: v1(143.32,65.91) 143.95,66.55 144.53,66.55 150.62,72.64 150.62,92.84 150.11,93.34 R138.1
EMI1_MDIO: length 222.3
  TOP w0.127: U82.73 v1(243.97,51.71) ; U45.31 142.55,61.42 142.62,61.49 v1(142.62,65.91) 142.37,66.17 141.99,66.17 141.73,66.42 U81.2 ; U52.D10 223.77,88.26 223.9,88.39 223.9,89.53 224.57,90.21 224.57,90.39 v2(224.54,90.42) ; U83.73 v1(266.83,51.71) ; v2(192.79,90.17) 192.15,89.53 192.15,88.39 192.02,88.26 U51.D10 ; U48.73 v1(158.37,49.81)
  L3SIG w0.102: v1(266.83,51.71) 266.55,51.44 264.16,51.44 263.07,52.53 259.38,52.53 258.7,53.21 245.62,53.21 244.12,51.71 v1(243.97,51.71) 243.69,51.44 241.94,51.44 241.17,52.2 241.17,55.5 238.51,58.17 238.51,74.17 234.82,77.85 231.27,77.85 230.12,78.99 230.12,84.84 v2(224.54,90.42) 224.54,90.81 222.82,92.52 205.93,92.52 204.66,91.25 194.63,91.25 193.55,90.17 v2(192.79,90.17) 192.79,91.06 191.26,92.58 176.91,92.58 164.59,80.26 164.59,55.88 162.18,53.47 160.91,53.47 160.4,52.96 160.4,51.43 158.77,49.81 v1(158.37,49.81) 158.09,49.53 155.96,49.53 155.07,48.64 153.67,48.64 152.53,49.78 152.53,50.93 148.08,55.37 148.08,60.96 145.92,63.12 145.92,64.57 145.47,65.02 144.15,65.02 143.51,64.39 143.36,64.39 143.31,64.34 142.95,64.34 142.9,64.39 142.88,64.39 142.62,64.64 v1(142.62,65.91)
EMI1_MDIO_SLP: length 66.2
  TOP w0.127: v1(141.22,67.75) 141.21,67.75 141.08,67.63 U81.1 ; U42.31 124.64,53.42 124.71,53.49 124.71,57.18 R139.2 124.94,57.43 123.95,58.42 v1(123.44,58.42) ; v1(149.73,91.19) 149.73,92.33 148.59,93.47 145.92,93.47 145.18,94.22 U1.AH4
  L3SIG w0.102: v1(141.22,67.75) 141.1,67.63 141.1,66.61 140.6,66.12 135.84,66.12 129.16,59.44 124.46,59.44 v1(123.44,58.42)
  BOTTOM w0.127: v1(141.22,67.75) 141.22,67.82 141.61,68.2 145.54,68.2 150.11,72.77 150.11,90.81 v1(149.73,91.19)
EVDD: length 8.8
  TOP w0.305: U1.L8 v2(131.17,97.02)
  L6SIG w0.508: 19.94,33.15 J2.3 ; J2.3 21.46,33.15 ; J2.3 19.94,34.67 ; J2.3 21.46,34.67
  BOTTOM w0.508: R71.2 v1(45.09,39.37) ; R73.2 v1(44.07,39.37) ; R69.2 v1(33.15,39.37) ; R68.2 v1(32.13,39.37) ; R70.2 v1(46.1,39.37) ; R72.2 v1(34.16,39.37)
  vias: v1(42.29,142.24) v1(43.18,144.27) v1(43.18,143.38) v1(43.18,142.49) v1(46.1,40.13) v1(47.24,40.13) v1(47.24,39.37) v1(73.66,78.36) v1(73.66,77.47) v1(74.55,78.36) v1(74.55,77.47)
EVDD_SEL: length 55.1
  TOP w0.127: U57.C2 v1(38.47,101.88) ; R677.1 v1(25.78,145.54)
  L3SIG w0.102: v1(38.47,101.88) 37.74,102.62 36.13,102.62 31.18,107.57 28.64,107.57 24.07,112.14 24.07,143.83 v1(25.78,145.54)
EVT0_N: length 93.3
  TOP w0.127: U57.E13 v1(50.47,99.88) ; U1.D6 v2(125.57,95.42)
  L6SIG w0.102: v1(50.47,99.88) 49.72,99.88 48.96,100.65 48.96,103.5 51.63,106.17 58.93,106.17 63.06,110.3 76.45,110.3 76.96,110.81 100.39,110.81 116.71,94.49 124.27,94.49 124.52,94.24 124.97,94.24 125.16,94.42 125.16,95.01 v2(125.57,95.42)
EVT1_N: length 91.9
  TOP w0.127: U1.C4 v2(124.77,93.82) ; U57.F13 v1(50.47,98.88)
  L6SIG w0.102: v1(50.47,98.88) 50.93,99.35 50.93,100.08 50.61,100.39 50.23,100.39 49.97,100.65 49.97,103.95 51.88,105.85 59.12,105.85 63.18,109.92 76.58,109.92 77.09,110.43 100.31,110.43 117.39,93.34 124.08,93.34 124.55,93.82 v2(124.77,93.82)
EVT4_N: length 85
  TOP w0.127: U1.C3 v2(124.77,93.02) ; U57.B14 v1(51.47,102.88)
  L6SIG w0.102: v2(124.77,93.02) 124.46,92.71 117.16,92.71 100.14,109.73 77.47,109.73 76.9,109.16 63.44,109.16 59.44,105.16 53.02,105.16 52.01,104.14 52.01,103.43 v1(51.47,102.88)
EVT_BRD_ISO: length 88.3
  TOP w0.127: U57.K16 v1(53.7,94.38) 55.4,94.38 60.01,99 60.01,103.7 66.04,109.73 80.14,109.73 80.9,110.49 100.46,110.49 117.6,93.34 123.49,93.34 U1.A3
  BOTTOM w0.127: R90.1 54.18,94.87 v1(53.7,94.38)
EVT_PWR_EN: length 93.3
  TOP w0.127: U1.C1 125.17,91.45 124.4,90.68 118.36,90.68 99.82,109.22 81.66,109.22 81.03,108.58 67.31,108.58 61.21,102.49 61.21,98.17 55.93,92.89 v1(52.47,92.89) U57.L15
  BOTTOM w0.127: v1(52.47,92.89) 54.59,92.89 R94.1
EVT_PWR_OK: length 93.4
  TOP w0.127: U1.C2 124.78,92.23 124.78,91.5 124.27,91 118.68,91 100.08,109.6 81.28,109.6 80.65,108.97 66.68,108.97 60.83,103.12 60.83,98.55 55.67,93.38 v1(53.68,93.38) U57.L16
  BOTTOM w0.127: R95.1 56.63,93.38 v1(53.68,93.38)
FAN_PWM: length 6.7
  TOP w0.127: U57.R16 55.75,86.6 R694.1
FAN_TACH: length 11.8
  TOP w0.127: U57.T15 53.1,87.25 54.23,87.25 54.86,86.61 54.86,82.42 56.01,81.28 R696.1
GPIO_CKE_ISO: length 141.4
  TOP w0.127: U57.P7 v1(43.47,89.89) ; U1.AC5 v2(141.57,94.62)
  L3SIG w0.102: v1(131.89,74.49) 134.87,74.49 136.46,76.07 138.11,76.07 141.48,79.44 141.48,86.51 v1(142.11,87.15) 142.37,87.4 142.37,92.46 141.96,92.86 141.96,93.37 141.57,93.77 v2(141.57,94.62)
  L6SIG w0.102: v1(131.89,74.49) 123.76,74.49 113.73,64.45 85.41,64.45 78.23,57.28 71.63,57.28 70.04,58.86 70.04,60.26 43.47,86.84 v1(43.47,89.89)
  BOTTOM w0.127: R87.1 141.63,87.63 v1(142.11,87.15)
GVDD_EN_N: length 184.5
  TOP w0.127: v1(71.56,73.66) 71.31,73.41 69.53,73.41 69.28,73.66 58.42,73.66 47.97,84.11 U57.T11 ; R662.1 169.67,137.54 v1(170.56,136.65)
  L6SIG w0.102: v1(71.56,73.66) 72.01,74.1 111.89,74.1 120.65,82.87 128.15,82.87 129.62,84.33 137.92,84.33 138.87,83.38 145.16,83.38 149.03,87.25 155.7,87.25 157.18,88.73 157.18,98.89 175.45,117.16 175.45,131.76 v1(170.56,136.65)
HRESET_N: length 97.3
  TOP w0.127: U1.E8 v2(126.37,97.02) ; U57.F14 v1(51.47,98.88)
  L6SIG w0.102: v1(51.47,98.88) 51.9,99.32 51.9,100.18 51.69,100.39 51.24,100.39 50.99,100.65 50.99,104.14 52.39,105.54 59.31,105.54 63.31,109.54 76.77,109.54 77.28,110.05 100.21,110.05 117.23,93.03 124.21,93.03 124.58,93.4 125.02,93.4 125.15,93.52 125.15,93.97 125.38,94.2 125.76,94.2 125.98,94.42 125.98,96.63 v2(126.37,97.02)
  BOTTOM w0.127: R105.2 52.15,98.2 v1(51.47,98.88)
I2C1_SCL: length 268.9
  TOP w0.127: v1(136.4,77.72) 136.4,83.44 136.91,83.95 136.91,88.65 137.97,89.71 U1.W1 ; U37.59 65.95,39.34 v1(66.17,39.12) ; U35.15 82.98,31.93 v1(82.55,31.5) ; v1(243.33,122.68) 243.72,122.29 Q2.2 244.92,122.94 R99.1 ; v1(74.8,60.2) U32.6
  L6SIG w0.102: v1(74.8,60.2) 77.66,60.2 84.39,66.93 113.16,66.93 122.97,76.75 125.91,76.75 127.08,77.91 136.21,77.91 v1(136.4,77.72) 148.27,77.72 152.24,81.69 158.78,81.69 163.58,86.49 163.58,92.39 165.29,94.11 165.29,97.47 183.45,115.63 239.33,115.63 243.33,119.63 v1(243.33,122.68)
  BOTTOM w0.127: v1(82.55,31.5) 79.88,31.5 73.94,37.44 71.44,37.44 71.44,37.15 71.18,36.89 70.81,36.89 70.55,37.15 70.55,37.44 67.84,37.44 v1(66.17,39.12) 66.17,40.13 67.95,41.91 67.95,44.7 72.52,49.28 72.52,56.26 73.6,57.34 73.6,58.99 v1(74.8,60.2)
I2C1_SCL_SLP: length 483.9
  TOP w0.127: v1(52.83,146.49) 53.21,146.87 U31.6 ; U62.5 73.39,87.14 75.44,85.09 75.44,77.03 v1(76.52,75.95) 82.99,69.47 v1(82.99,67.44) ; R97.1 243.97,123.95 Q2.3 242.19,125.74 v1(242.19,126.24) 240.92,127.5 U79.9
  L3SIG w0.102: v1(59.18,107.7) 61.55,110.07 v1(108.78,110.07) 108.78,110.55 108.59,110.74 105.28,110.74 101.35,114.68 101.35,120.52 100.33,121.54 96.53,121.54 80.85,137.22 62.93,137.22 53.66,146.49 v1(52.83,146.49) ; J1.141 186.04,163.07 188.72,163.07 190.75,161.04 190.75,159.89 196.6,154.05 217.17,154.05 220.98,150.24 220.98,139.7 225.93,134.75 242.95,134.75 243.97,133.73 243.97,128.02 v1(242.19,126.24)
  L6SIG w0.102: v1(242.19,126.24) 242.57,125.86 242.57,124.97 241.17,123.57 241.17,119.25 239.01,117.09 221.62,117.09 220.79,116.27 183.32,116.27 164.72,97.66 164.72,94.3 163.07,92.65 163.07,86.8 158.41,82.14 151.93,82.14 148.18,78.4 123.8,78.4 112.97,67.56 83.12,67.56 v1(82.99,67.44)
  BOTTOM w0.127: U34.8 v1(108.78,110.07) ; v1(59.18,107.7) 58.99,107.51 58.99,87.25 62.8,83.44 71.25,83.44 76.2,78.49 76.2,76.26 v1(76.52,75.95)
I2C1_SDA: length 272.8
  TOP w0.127: Q3.2 247.34,127.31 v1(247.4,127.25) R98.1 ; v1(74.8,59.44) 75.31,58.93 U32.5 ; U35.14 82.59,32.43 v1(82.42,32.26) ; U1.V1 137.17,91.81 137.54,91.44 137.54,89.92 136.53,88.9 136.53,84.07 135.89,83.44 135.89,77.69 135.76,77.56 v1(135.76,77.28) ; v1(66.93,39.24) 66.44,39.73 U37.60
  L6SIG w0.102: v1(247.4,127.25) 247.4,126.75 244.09,123.44 244.09,119.82 239.59,115.32 183.51,115.32 165.54,97.34 165.54,93.92 163.83,92.2 163.83,86.36 158.93,81.46 152.39,81.46 147.76,76.84 136.21,76.84 v1(135.76,77.28) 135.36,77.69 127.63,77.69 126.46,76.52 123.19,76.52 113.22,66.55 84.46,66.55 77.34,59.44 v1(74.8,59.44)
  BOTTOM w0.127: v1(82.42,32.26) 79.76,32.26 74.19,37.82 68.35,37.82 v1(66.93,39.24) 66.93,40.13 68.45,41.66 68.45,44.58 72.9,49.02 72.9,56.01 74.04,57.15 74.04,58.67 v1(74.8,59.44)
I2C1_SDA_SLP: length 488.8
  TOP w0.127: R96.1 247.93,126.36 Q3.3 v1(243.08,126.36) 242.57,126.87 242.06,126.87 241.32,127.61 U79.10 ; U31.5 53.32,146.22 53.02,145.92 v1(52.2,145.92) ; v1(83.69,67.06) 83.69,67.06 83.69,67.24 83.69,67.25 83.69,69.72 v1(76.77,76.64) 75.95,77.47 75.95,85.22 73.53,87.64 U62.4
  L3SIG w0.102: v1(59.88,107.76) 61.54,109.42 v1(109.28,109.42) 109.28,110.55 108.71,111.12 105.41,111.12 101.73,114.81 101.73,120.65 100.46,121.92 96.65,121.92 81.03,137.54 63.06,137.54 53.59,147 52.45,147 52.2,146.75 v1(52.2,145.92) ; v1(243.08,126.36) 244.35,127.63 244.35,133.73 243.08,135 226.19,135 221.36,139.83 221.36,150.37 217.3,154.43 196.72,154.43 191.26,159.89 191.26,161.93 188.34,164.85 186.44,164.85 185.25,166.03 J1.285
  L6SIG w0.102: v1(243.08,126.36) 243.08,124.97 241.55,123.44 241.55,119.13 238.38,115.95 183.39,115.95 165.04,97.6 165.04,94.26 163.32,92.54 163.32,86.67 158.56,81.92 152.08,81.92 148.34,78.17 124.02,78.17 113.09,67.25 83.88,67.25 v1(83.69,67.06)
  BOTTOM w0.127: v1(76.77,76.64) 76.77,78.68 71.5,83.95 62.93,83.95 59.88,87 v1(59.88,107.76) ; v1(109.28,109.42) U34.7
I2C2_HDMI_SCL: length 273.5
  TOP w0.127: U36.17 85.65,25.73 v1(85.6,25.78) 85.6,26.31 R205.1 ; U12.10 v1(223.62,171.04)
  L6SIG w0.102: v1(223.62,171.04) 223.62,169.82 224.03,169.42 224.03,168.78 224.41,168.4 224.41,163.45 212.33,151.37 212.33,123.81 209.42,120.9 181.86,120.9 159,98.04 159,88.27 156.46,85.72 149.8,85.72 145.9,81.83 123.3,81.83 121.2,81.83 112.08,72.71 v1(77.03,72.71)
  BOTTOM w0.127: v1(85.6,25.78) 85.6,26.54 83.95,28.19 83.95,31.75 81.92,33.78 81.92,36.7 81.28,37.34 78.87,37.34 73.15,43.05 73.15,47.05 75.06,48.96 75.06,50.55 75.95,51.44 75.95,67.82 77.03,68.9 v1(77.03,72.71)
I2C2_HDMI_SDA: length 276
  TOP w0.127: U36.18 85.15,25.34 v1(84.71,25.78) R208.1 ; v1(224.41,171.32) 224.04,171.69 U12.9
  L6SIG w0.102: v1(76.2,72.71) 76.64,72.26 112.01,72.26 121.35,81.6 123.21,81.6 146.05,81.6 149.92,85.47 156.59,85.47 159.32,88.2 159.32,94.23 160.27,95.19 160.27,98.87 181.99,120.59 209.61,120.59 212.66,123.63 212.66,151.32 224.73,163.39 224.73,168.47 224.35,168.85 224.35,171.26 v1(224.41,171.32)
  BOTTOM w0.127: v1(84.71,25.78) 84.71,26.8 83.44,28.07 83.44,31.88 81.53,33.78 81.53,36.58 81.15,36.96 78.74,36.96 72.64,43.05 72.64,47.24 74.55,49.15 74.55,50.8 75.44,51.69 75.44,68.2 76.2,68.96 v1(76.2,72.71)
I2C2_MPEX1_SCL: length 39.4
  TOP w0.127: v1(229.49,169.8) 229.43,169.74 U12.5 ; R442.1 212.3,190.35 J27.30 v1(212.3,186.56)
  L3SIG w0.102: v1(212.3,186.56) 212.8,186.06 225.43,186.06 232.03,179.45 232.03,171.7 230.12,169.8 v1(229.49,169.8)
I2C2_MPEX1_SDA: length 40
  TOP w0.127: U12.4 230.05,169.09 v1(230.25,169.29) ; v1(213.1,186.57) J27.32 213.1,190.13 R443.1
  L3SIG w0.102: v1(230.25,169.29) 232.41,171.45 232.41,179.7 225.54,186.57 v1(213.1,186.57)
I2C2_MPEX2_SCL: length 163.2
  TOP w0.127: v1(85.3,186.56) J28.30 85.3,190.22 R453.1 ; U12.7 229.34,171.04 v1(229.49,171.2)
  L3SIG w0.102: v1(85.3,186.56) 85.8,186.06 210.82,186.06 211.84,185.04 225.17,185.04 231.27,178.94 231.27,172.97 v1(229.49,171.2)
I2C2_MPEX2_SDA: length 164.1
  TOP w0.127: v1(86.1,186.57) J28.32 86.1,190.01 R454.1 ; v1(230,170.56) 229.83,170.39 U12.6
  L3SIG w0.102: v1(230,170.56) 231.65,172.21 231.65,179.2 225.3,185.55 211.96,185.55 210.94,186.57 v1(86.1,186.57)
I2C2_PEX_SCL: length 118.8
  TOP w0.127: U12.12 224.46,169.74 v1(224.79,169.42) ; v1(270,86.74) 270.51,86.23 272.16,86.23 272.64,85.75 R450.1 272.77,85.85 275.21,85.85 276.23,86.87 278.33,86.87 J26.B5
  L3SIG w0.102: v1(270,86.74) 269.49,87.25 269.49,93.85 267.46,95.89 267.46,115.7 256.41,126.75 251.21,126.75 249.3,128.65 249.3,137.8 233.93,153.16 233.93,160.78 228.09,166.62 225.93,166.62 225.04,167.51 225.04,169.16 v1(224.79,169.42)
I2C2_PEX_SDA: length 120.6
  TOP w0.127: v1(225.3,170.05) 224.96,170.39 U12.11 ; v1(270,88.01) 270.13,88.01 270.89,87.25 272.16,87.25 272.64,86.77 R451.1 273.15,86.23 275.1,86.23 276.12,87.25 280.95,87.25 J26.B6
  L3SIG w0.102: v1(225.3,170.05) 225.3,167.77 226.06,167 228.35,167 234.44,160.91 234.44,153.29 249.68,138.05 249.68,128.78 251.33,127.13 256.54,127.13 267.84,115.82 267.84,96.01 270,93.85 v1(270,88.01)
IFC_A5: length 16.7
  TOP w0.127: v1(76.07,110.87) 76.01,110.94 U7.1
  BOTTOM w0.127: R23.2 88.27,113.92 87.25,112.9 80.9,112.9 78.87,110.87 v1(76.07,110.87)
IFC_A6: length 20.3
  TOP w0.127: v1(75.31,110.87) 73.28,110.87 72.66,111.49 U6.1
  BOTTOM w0.127: v1(75.31,110.87) 75.76,111.32 78.68,111.32 80.65,113.28 86.74,113.28 88.39,114.94 R24.2
IFC_A7: length 15
  TOP w0.127: v1(78.11,114.05) 78.3,113.86 78.3,112.2 79.01,111.49 U5.1
  BOTTOM w0.127: v1(78.11,114.05) 80.01,114.05 80.26,113.79 86.61,113.79 88.27,115.44 R25.2
IFC_A8: length 8
  TOP w0.127: U3.2 v1(86.64,114.65)
  BOTTOM w0.127: v1(86.64,114.65) 87.94,115.95 R26.2
IFC_A9: length 17.2
  TOP w0.127: U3.15 v1(83.32,121.15)
  BOTTOM w0.127: R27.2 85.22,116.97 83.32,118.87 v1(83.32,121.15)
IFC_A10: length 12.5
  TOP w0.127: U3.12 v1(83.84,119.65)
  BOTTOM w0.127: R28.2 85.22,117.47 83.84,118.85 v1(83.84,119.65)
IFC_A11: length 12.6
  TOP w0.127: U3.11 v1(84.36,119.15)
  BOTTOM w0.127: R29.2 85.53,117.98 v1(84.36,119.15)
IFC_A12: length 14.8
  TOP w0.127: v1(83.31,122.05) 83.82,121.54 85.98,121.54 87.09,122.65 U3.18
  BOTTOM w0.127: v1(83.31,122.05) 84.07,121.28 84.07,120.4 85.98,118.49 R30.2
IFC_A13: length 15
  TOP w0.127: U3.19 86.96,123.15 85.85,122.05 v1(84.07,122.05)
  BOTTOM w0.127: v1(84.07,122.05) 84.46,121.67 84.46,120.52 85.98,119 R32.2
IFC_A14: length 27.5
  TOP w0.127: v1(75.31,115.57) 74.89,115.15 U3.54
  BOTTOM w0.127: v1(75.31,115.57) 75.31,118.49 79.63,122.81 84.07,122.81 84.96,121.92 84.96,120.65 86.11,119.51 89.54,119.51 90.04,120.02 R34.2
IFC_A15: length 26.6
  TOP w0.127: v1(83.57,123.44) 81.53,121.41 81.53,116.46 82.84,115.15 U3.3
  BOTTOM w0.127: R36.2 89.41,121.03 88.52,120.14 85.98,120.14 85.34,120.78 85.34,122.17 84.07,123.44 v1(83.57,123.44)
IFC_A16: length 122.7
  TOP w0.127: U1.C5 v2(124.77,94.62) ; SW2.5 v1(63.75,128.65) 63.75,128.4 63.12,127.76 56.9,127.76 54.1,124.97 54.1,119.89 54.74,119.25 54.74,107.82 54.74,107.82 54.74,107.61 54.74,101.22 53.9,100.39 U57.D16 ; U3.4 v1(83.86,115.65)
  L6SIG w0.102: v1(63.75,128.65) 67.56,124.84 69.47,124.84 69.91,124.4 69.91,121.92 71.18,120.65 74.17,120.65 79.38,115.44 82.8,115.44 83.02,115.65 v1(83.86,115.65) 88.39,111.12 100.52,111.12 116.84,94.81 124.58,94.81 v2(124.77,94.62)
  BOTTOM w0.127: R6.2 v1(63.75,128.65)
IFC_A17: length 126.5
  TOP w0.127: SW2.6 65.02,129.16 v1(64.52,128.65) 64.52,127.51 64.39,127.38 57.15,127.38 54.48,124.71 54.48,120.02 55.12,119.38 55.12,100.58 54.36,99.83 53.54,99.83 53.53,99.82 52.4,99.82 U57.E15 ; U1.C6 v2(124.77,95.42) ; U3.5 v1(82.88,116.15)
  L6SIG w0.102: v1(64.52,128.65) 64.52,128.33 67.63,125.22 69.72,125.22 70.29,124.65 70.29,122.11 71.41,121 74.33,121 79.5,115.82 82.55,115.82 v1(82.88,116.15) 85.01,116.15 85.75,115.42 94.39,115.42 98.3,111.51 100.58,111.51 116.97,95.12 124.47,95.12 v2(124.77,95.42)
  BOTTOM w0.127: R7.2 65.02,129.16 v1(64.52,128.65)
IFC_A18: length 89.5
  TOP w0.127: U1.D7 v2(125.57,96.22) ; U3.6 v1(83.89,116.65) ; SW2.3 v1(61.21,128.65)
  L6SIG w0.102: v1(61.21,128.65) 61.65,128.22 62.71,128.22 63.57,129.08 64.78,129.08 65.02,128.84 65.02,128.27 67.69,125.6 69.85,125.6 70.68,124.78 70.68,122.81 71.31,122.17 73.72,122.17 79.74,116.15 80.78,116.15 81.28,116.65 v1(83.89,116.65) 84.89,116.65 85.9,115.65 94.67,115.65 98.55,111.76 100.84,111.76 117.22,95.38 124.19,95.38 124.61,95.8 125.15,95.8 v2(125.57,96.22)
  BOTTOM w0.127: R8.2 v1(61.21,128.65)
IFC_A19: length 87.4
  TOP w0.127: U1.C7 v2(124.77,96.22) ; SW2.4 v1(62.48,128.65) ; U3.7 v1(82.86,117.15)
  L6SIG w0.102: v2(124.77,96.22) 124.54,96.22 124.03,95.71 117.34,95.71 100.9,112.14 98.68,112.14 94.95,115.87 86.18,115.87 84.9,117.15 v1(82.86,117.15) 79.25,117.15 73.28,123.13 71.56,123.13 71.06,123.63 71.06,124.9 69.98,125.98 67.69,125.98 65.41,128.27 65.41,128.97 64.96,129.41 63.25,129.41 v1(62.48,128.65)
  BOTTOM w0.127: R13.2 v1(62.48,128.65)
IFC_A20: length 60.2
  TOP w0.127: U3.8 v1(83.87,117.65) ; U1.D8 v2(125.57,97.02)
  L6SIG w0.102: v2(125.57,97.02) 125.19,96.64 116.79,96.64 101.03,112.39 99.06,112.39 94.49,116.97 85.73,116.97 85.04,117.65 v1(83.87,117.65)
  BOTTOM w0.127: v1(83.87,117.65) 81.94,117.65 R16.2 R22.2
IFC_A21: length 81.1
  TOP w0.127: SW2.7 66.29,129.03 v1(65.91,128.65) ; U3.9 v1(83.01,118.15) ; U1.C8 v2(124.77,97.02)
  L6SIG w0.102: v2(124.77,97.02) 116.85,97.02 100.97,112.9 99.19,112.9 94.87,117.22 85.98,117.22 85.05,118.15 v1(83.01,118.15) 80.35,118.15 72.14,126.36 67.69,126.36 65.91,128.14 v1(65.91,128.65)
IFC_A22: length 59.8
  TOP w0.127: U3.10 83.28,118.65 v1(82.8,119.13) ; U1.D9 v2(125.57,97.82)
  L6SIG w0.102: v1(82.8,119.13) 83.34,118.59 94.25,118.59 99.55,113.28 100.96,113.28 116.83,97.42 125.17,97.42 v2(125.57,97.82)
IFC_A23: length 55.6
  TOP w0.127: U1.C9 v2(124.77,97.82) ; U3.20 v1(85.39,123.65)
  L6SIG w0.102: v1(85.39,123.65) 86.46,122.59 89,122.59 90.74,120.84 93.43,120.84 99.39,114.87 100.2,114.87 100.58,114.49 100.58,114.11 116.4,98.3 118.11,98.3 118.75,97.66 124.61,97.66 v2(124.77,97.82)
IFC_A24: length 57.9
  TOP w0.127: U3.21 85.65,124.15 v1(85.34,124.46) ; U1.D10 v2(125.57,98.62)
  L6SIG w0.102: v2(125.57,98.62) 125.15,98.2 124.49,98.2 124.21,97.92 118.94,97.92 118.3,98.55 116.59,98.55 100.9,114.24 100.9,115.89 100.48,116.31 99.9,116.31 99.73,116.14 98.74,116.14 93.73,121.16 90.87,121.16 89.15,122.87 86.93,122.87 v1(85.34,124.46)
IFC_A25: length 55.8
  TOP w0.127: v1(85.98,124.97) 86.29,124.65 U3.22 ; U1.C10 v2(124.77,98.62)
  L6SIG w0.102: v1(85.98,124.97) 87.76,123.19 89.34,123.19 90.13,122.41 92.94,122.41 98.9,116.44 99.66,116.44 99.8,116.59 100.65,116.59 101.22,116.01 101.22,114.36 116.78,98.81 118.49,98.81 119.07,98.23 124.14,98.23 124.52,98.62 v2(124.77,98.62)
IFC_A26: length 53.5
  TOP w0.127: U1.E11 v2(126.37,99.42) ; U3.23 v1(88.77,125.15)
  L6SIG w0.102: v1(88.77,125.15) 89.29,125.67 93.03,125.67 96.72,121.97 100.47,121.97 101.41,121.03 101.41,119.76 103.7,117.48 103.7,114.17 117.35,100.52 124.33,100.52 124.41,100.6 125.72,100.6 125.95,100.37 125.95,99.84 v2(126.37,99.42)
IFC_A27: length 128.7
  TOP w0.127: U3.24 88.97,125.65 88.96,125.67 88.59,125.67 88.58,125.65 87.55,125.65 v1(87.12,125.22) ; U1.C11 v2(124.77,99.42) ; U57.C13 v1(50.47,101.88)
  L3SIG w0.102: v1(50.47,101.88) 50.29,102.06 50.29,116.71 44.83,122.17 44.83,128.27 46.51,129.95 55.35,129.95 58.8,126.49 73.03,126.49 74.12,125.4 86.16,125.4 86.34,125.22 v1(87.12,125.22)
  L6SIG w0.102: v2(124.77,99.42) 117.06,99.42 101.85,114.62 101.85,116.71 100.51,118.06 100.51,120.07 100.24,120.33 96.96,120.33 93.35,123.95 88.39,123.95 v1(87.12,125.22)
IFC_A28: length 131.1
  TOP w0.127: U57.C12 v1(49.47,101.88) ; v1(86.49,125.86) 86.78,126.15 U3.25 ; U1.D11 v2(125.57,99.42)
  L3SIG w0.102: v1(86.49,125.86) 75.44,125.86 73.47,127.83 60.52,127.83 58.17,130.18 56.64,130.18 56.13,130.68 46.85,130.68 46.23,130.68 44.07,128.52 44.07,121.79 49.47,116.4 v1(49.47,101.88)
  L6SIG w0.102: v1(86.49,125.86) 86.49,125.03 87.88,123.63 89.41,123.63 90.3,122.75 93.15,122.75 98.09,117.81 100.32,117.81 101.54,116.59 101.54,114.49 116.92,99.11 124.41,99.11 124.48,99.04 125.19,99.04 v2(125.57,99.42)
IFC_A29: length 132.1
  TOP w0.127: U3.26 v1(88.43,126.65) ; U57.C11 v1(48.47,101.88) ; U1.C12 v2(124.77,100.22)
  L3SIG w0.102: v1(48.47,101.88) 48.47,116.13 43.31,121.28 43.31,128.91 45.72,131.32 58.55,131.32 60.71,129.16 81.53,129.16 83.44,127.25 87.83,127.25 v1(88.43,126.65)
  L6SIG w0.102: v1(88.43,126.65) 88.2,126.43 88.2,125.03 88.58,124.65 89.15,124.65 89.81,125.31 92.88,125.31 96.52,121.67 100.39,121.67 101.09,120.97 101.09,118.36 102.24,117.22 102.68,117.22 103.31,116.59 103.31,114.05 117.14,100.22 v2(124.77,100.22)
IFC_A30: length 146.2
  TOP w0.127: U1.D12 v2(125.57,100.22) ; U3.31 v1(86.14,126.65) ; U57.D12 v1(49.47,100.88)
  L3SIG w0.102: v1(49.47,100.88) 48.96,101.39 48.96,116.27 43.69,121.54 43.69,128.65 46,130.96 57.76,130.96 60.58,128.14 73.91,128.14 75.4,126.65 v1(86.14,126.65)
  L6SIG w0.102: v1(86.14,126.65) 86.71,126.65 87.76,125.6 87.76,125.09 88.58,124.27 93.47,124.27 96.39,121.35 100.27,121.35 100.74,120.88 100.74,118.34 102.17,116.9 102.57,116.9 103,116.48 103,113.92 117.08,99.84 125.19,99.84 v2(125.57,100.22)
IFC_A31: length 129.1
  TOP w0.127: U57.A5 41.97,107.75 44.58,110.36 44.58,130.68 45.53,131.64 55.31,131.64 57.66,133.99 80.26,133.99 84.58,129.67 v1(85.47,129.67) ; U1.E12 v2(126.37,100.22)
  L6SIG w0.102: v1(85.47,129.67) 85.6,129.79 90.17,129.79 97.03,122.94 100.71,122.94 104.78,118.87 104.78,115.57 111.19,109.16 111.19,108.08 117.22,102.04 124.71,102.04 125.32,101.44 125.69,101.44 125.98,101.14 125.98,100.71 126.37,100.33 v2(126.37,100.22)
IFC_AD0: length 95.8
  TOP w0.127: v1(68.71,116.59) 68.78,116.65 U3.51 76.64,116.65 82.42,110.87 100.71,110.87 117.28,94.3 123.48,94.3 U1.A4 ; U57.A13 49.97,105.21 52.58,107.82 v1(52.58,114.68) ; U4.J8 64.1,118.27 v1(65.15,117.22)
  BOTTOM w0.127: v1(52.58,114.68) 61.72,114.68 63.63,116.59 64.52,116.59 v1(65.15,117.22) 68.2,117.22 68.71,116.71 v1(68.71,116.59)
IFC_AD1: length 97.9
  TOP w0.127: U57.B13 50.42,102.84 50.42,104.9 53.09,107.57 53.09,114.94 v1(52.58,115.44) ; U4.K7 v2(63.45,117.07) ; U1.B5 123.96,94.61 117.54,94.61 100.9,111.25 82.55,111.25 76.15,117.65 U3.49 69.29,117.65 v1(69.22,117.73)
  BOTTOM w0.127: v1(52.58,115.44) 52.96,115.06 61.44,115.06 v2(63.45,117.07) 64.11,117.73 v1(69.22,117.73)
IFC_AD2: length 98.5
  TOP w0.127: v1(69.25,118.65) U3.47 75.66,118.65 82.68,111.63 101.09,111.63 117.71,95.02 U1.A5 ; v1(52.58,116.33) 52.07,115.82 52.07,107.95 49.4,105.28 49.4,102.87 48.97,102.43 U57.B12 ; U4.J7 v2(63.45,117.87)
  BOTTOM w0.127: v1(69.25,118.65) 67.73,118.65 67.18,118.11 63.69,118.11 v2(63.45,117.87) 61.02,115.44 53.47,115.44 v1(52.58,116.33)
IFC_AD3: length 100.1
  TOP w0.127: U4.K6 v2(61.85,117.07) ; U57.A12 48.97,105.48 51.63,108.14 51.63,116.27 52.58,117.22 v1(52.96,117.22) ; U1.B6 123.93,95.38 117.86,95.38 101.22,112.01 82.8,112.01 75.16,119.65 U3.45 v1(69.24,119.65)
  BOTTOM w0.127: v1(69.24,119.65) 64.41,119.65 61.85,117.09 v2(61.85,117.07) 60.6,115.82 54.36,115.82 v1(52.96,117.22)
IFC_AD4: length 102.2
  TOP w0.127: U4.K5 v2(61.05,117.07) ; v1(68.33,121.15) U3.42 74.17,121.15 82.93,112.39 101.35,112.39 118.05,95.69 123.44,95.69 U1.A6 ; v1(51.82,117.86) 50.8,116.84 50.8,108.58 47.97,105.75 U57.A11
  BOTTOM w0.127: v1(68.33,121.15) 64.26,121.15 61.98,118.87 61.98,118 v2(61.05,117.07) 60.19,116.2 55.88,116.2 54.23,117.86 v1(51.82,117.86)
IFC_AD5: length 106.6
  TOP w0.127: U4.K4 v2(60.25,117.07) ; U1.A7 117.7,96.62 100.44,113.88 v1(99.57,113.88) 95.08,113.88 93.98,112.78 83.06,112.78 73.68,122.15 U3.40 v1(68.47,122.15) ; U57.B11 48.03,102.39 48.51,102.87 48.51,105.66 51.18,108.33 51.18,116.46 52.83,118.11 v1(52.83,118.49)
  BOTTOM w0.127: v1(68.47,122.15) 63.86,122.15 61.6,119.89 61.6,118.41 v2(60.25,117.07) 59.77,116.59 56.13,116.59 54.23,118.49 v1(52.83,118.49) ; U2.47 v1(99.57,113.88)
IFC_AD6: length 108.9
  TOP w0.127: v1(69.12,123.15) U3.38 73.19,123.15 79.25,117.09 80.39,117.09 80.77,116.71 80.77,115.57 83.19,113.16 91.06,113.16 91.72,113.82 94.39,113.82 94.94,114.38 v1(100.08,114.38) 100.57,114.38 117.92,97.03 123.98,97.03 U1.B8 ; U57.B10 47.14,102.39 47.5,102.74 47.5,105.92 50.42,108.84 50.42,117.22 v1(51.94,118.75) ; U4.J4 v2(60.25,117.87)
  BOTTOM w0.127: v1(69.12,123.15) 67.02,123.15 66.42,122.56 63.63,122.56 61.21,120.14 61.21,118.83 v2(60.25,117.87) 55.49,117.87 54.36,119 52.2,119 v1(51.94,118.75) ; U2.46 v1(100.08,114.38)
IFC_AD7: length 110.5
  TOP w0.127: v1(69.27,124.15) U3.36 72.82,124.15 78.74,118.24 80.52,118.24 81.15,117.6 81.15,115.82 83.44,113.54 90.93,113.54 91.57,114.17 94.11,114.17 95.31,115.38 v1(99.5,115.38) 102.81,115.38 107.06,111.12 107.06,109.28 118.93,97.42 U1.A8 ; v1(52.07,119.63) 49.91,117.47 49.91,108.97 46.97,106.02 U57.A10 ; U4.H4 v2(60.25,118.67)
  BOTTOM w0.127: v1(52.07,119.63) 54.48,119.63 55.75,118.36 59.94,118.36 v2(60.25,118.67) 60.83,119.25 60.83,120.4 63.37,122.94 66.04,122.94 67.26,124.15 v1(69.27,124.15) ; U2.44 v1(99.5,115.38)
IFC_AD8: length 122.8
  TOP w0.127: SW1.1 v1(45.97,127) 45.97,110.36 42.97,107.35 U57.A6 ; U1.B9 123.94,97.79 119.06,97.79 107.44,109.41 107.44,111.44 103.01,115.88 v1(100.08,115.88) ; U3.50 v1(72.07,117.15)
  L3SIG w0.102: v1(100.08,115.88) 84.78,115.88 84.52,116.14 83.63,116.14 83.12,116.65 82.55,116.65 82.05,117.15 v1(72.07,117.15) 66.49,117.15 63.69,119.95 60.01,119.95 59.31,119.25 58.06,119.25 57.49,119.82 56.52,119.82 55.56,120.78 53.59,120.78 47.37,127 v1(45.97,127)
  BOTTOM w0.127: U2.43 v1(100.08,115.88)
IFC_AD9: length 123.2
  TOP w0.127: v1(99.48,116.88) 103.09,116.88 107.89,112.08 107.89,109.41 119.08,98.22 U1.A9 ; U3.48 v1(71.97,118.15) ; U57.B7 43.97,102.59 43.43,103.12 43.43,107.06 47.24,110.87 v1(47.24,127.83) SW1.2
  L3SIG w0.102: v1(99.48,116.88) 84.93,116.88 84.58,117.22 83.57,117.22 83.12,117.67 81.98,117.67 81.49,118.15 v1(71.97,118.15) 71.96,118.16 65.99,118.16 63.75,120.4 59.82,120.4 59.06,119.63 58.23,119.63 57.59,120.27 56.71,120.27 55.69,121.28 53.78,121.28 v1(47.24,127.83)
  BOTTOM w0.127: U2.41 v1(99.48,116.88)
IFC_AD10: length 121.4
  TOP w0.127: v1(100.08,117.38) 103.35,117.38 108.33,112.39 108.33,109.6 118.81,99.12 123.46,99.12 U1.A10 ; U3.46 v1(71.98,119.15) ; U57.A7 43.97,106.83 47.63,110.49 47.63,124.71 48.51,125.6 v1(48.51,128.65) SW1.3
  L3SIG w0.102: v1(48.51,128.65) 48.51,127.25 54.1,121.67 57.15,121.67 58.1,120.71 61.79,120.71 62.61,121.54 65.53,121.54 67.92,119.15 v1(71.98,119.15) 77.57,119.15 78.11,118.62 83.69,118.62 84.94,117.38 v1(100.08,117.38)
  BOTTOM w0.127: U2.40 v1(100.08,117.38)
IFC_AD11: length 123.4
  TOP w0.127: U57.B8 44.45,102.9 44.45,106.55 48.01,110.11 48.01,124.21 49.78,125.98 v1(49.78,128.65) SW1.4 ; U1.B11 123.99,99.44 119.92,99.44 117.92,101.44 116.96,101.44 110.36,108.03 110.36,109.16 108.97,110.55 108.97,112.52 103.11,118.38 v1(99.45,118.38) ; U3.44 v1(72,120.15)
  L3SIG w0.102: v1(49.78,128.65) 49.78,127.25 54.86,122.17 57.28,122.17 58.36,121.09 61.47,121.09 62.55,122.17 66.29,122.17 68.31,120.15 v1(72,120.15) 79.87,120.15 80.45,119.57 83.25,119.57 84.44,118.38 v1(99.45,118.38)
  BOTTOM w0.127: U2.38 v1(99.45,118.38)
IFC_AD12: length 120
  TOP w0.127: v1(100.08,118.88) 103.31,118.88 109.41,112.78 109.41,110.68 110.74,109.35 110.74,108.2 117.09,101.85 119.32,101.85 121.35,99.82 U1.A11 ; U3.41 v1(72,121.65) ; SW1.5 v1(51.05,128.65) 51.05,126.62 48.39,123.95 48.39,109.86 44.97,106.43 U57.A8
  L3SIG w0.102: v1(100.08,118.88) 85.85,118.88 84.58,120.14 80.39,120.14 78.88,121.65 v1(72,121.65) 70.09,121.65 69.67,121.23 68.95,121.23 68.52,121.67 67.69,121.67 66.8,122.56 62.23,122.56 61.14,121.46 58.62,121.46 57.47,122.62 55.63,122.62 51.05,127.19 v1(51.05,128.65)
  BOTTOM w0.127: U2.37 v1(100.08,118.88)
IFC_AD13: length 122.1
  TOP w0.127: v1(99.45,119.38) 103.45,119.38 109.86,112.97 109.86,110.74 111.13,109.47 111.13,108.46 117.35,102.23 119.57,102.23 121.6,100.2 123.95,100.2 U1.B12 ; SW1.6 v1(52.32,128.65) 52.32,127.25 48.77,123.7 48.77,109.6 45.47,106.3 45.47,101.89 U57.C8 ; U3.39 v1(71.98,122.65)
  L3SIG w0.102: v1(52.32,128.65) 52.32,127.06 56.2,123.19 59.31,123.19 60.07,123.95 61.34,123.95 62.36,122.94 68.45,122.94 68.73,122.65 v1(71.98,122.65) 78.39,122.65 80.65,120.4 84.84,120.4 85.86,119.38 v1(99.45,119.38)
  BOTTOM w0.127: U2.36 v1(99.45,119.38)
IFC_AD14: length 117.5
  TOP w0.127: v1(100.08,119.89) 103.63,119.89 110.3,113.22 110.3,110.87 112.78,108.39 112.78,107.38 117.6,102.55 119.82,102.55 121.78,100.6 123.55,100.6 U1.A12 ; SW1.7 v1(53.59,128.65) 53.59,127.76 51.56,125.73 51.56,120.52 49.15,118.11 49.15,109.35 45.97,106.16 U57.A9 ; U3.37 v1(72.09,123.65)
  L3SIG w0.102: v1(100.08,119.89) 93.22,119.89 93.09,119.76 85.98,119.76 85.09,120.65 80.9,120.65 77.85,123.7 72.14,123.7 v1(72.09,123.65) 65.07,123.65 64.39,124.33 59.94,124.33 59.18,123.57 57.15,123.57 53.59,127.13 v1(53.59,128.65)
  BOTTOM w0.127: v1(100.08,119.89) 100.09,119.88 U2.35
IFC_AD15: length 117.4
  TOP w0.127: v1(72.01,124.71) 71.95,124.65 U3.35 ; U1.A13 121.6,101.42 120.08,102.93 117.74,102.93 113.09,107.6 113.09,108.65 110.81,110.93 110.81,113.35 103.28,120.88 v1(100.08,120.88) ; SW1.8 v1(54.86,128.65) 54.86,128.4 52.2,125.73 52.2,120.52 49.53,117.86 49.53,109.22 46.48,106.17 46.48,102.74 46.12,102.39 U57.B9
  L3SIG w0.102: v1(100.08,120.88) 90.02,120.88 89.28,120.14 86.11,120.14 84.66,121.59 80.47,121.59 77.91,124.14 72.58,124.14 v1(72.01,124.71) 57.15,124.71 54.86,127 v1(54.86,128.65)
  BOTTOM w0.127: v1(100.08,120.88) U2.33
IFC_AVD: length 103.8
  TOP w0.127: U4.C4 v2(60.25,123.47) ; SW2.8 v1(67.56,128.65) ; v1(98.93,125.73) 100.2,124.46 104.71,124.46 113.16,116.01 113.16,111.46 118.31,106.3 120.78,106.3 122.05,105.03 125.55,105.03 U1.D17
  L6SIG w0.102: v1(98.93,125.73) 98.49,126.17 97.35,126.17 90.87,132.65 71.56,132.65 v1(67.56,128.65)
  BOTTOM w0.127: R17.1 v1(67.56,128.65) 67.56,128.4 66.8,127.63 63.75,127.63 60.25,124.13 v2(60.25,123.47) ; U2.25 100.29,124.88 99.44,125.73 v1(98.93,125.73) 98.93,113.79 99.35,113.38 U2.48
IFC_CLE: length 134.2
  TOP w0.127: SW2.1 v1(58.67,128.78) 57.28,128.78 53.59,125.09 53.59,119.89 54.36,119.13 54.36,101.6 53.59,100.84 52.42,100.84 U57.D15 ; v2(59.31,121.87) 61.05,121.87 U4.D5 ; U1.F16 v2(127.17,104.22)
  L6SIG w0.102: v1(58.67,128.78) 59.69,128.78 61.28,130.37 66.29,130.37 67.06,129.6 67.06,128.4 67.31,128.14 68.49,128.14 70.07,129.73 72.77,129.73 73.28,129.22 73.28,128.46 73.52,128.22 74.31,128.22 74.42,128.33 74.42,129.1 76.71,131.38 90.81,131.38 97.6,124.59 102.43,124.59 106.45,120.56 106.45,116.31 114.3,108.46 114.3,107.12 118.05,103.38 124.9,103.38 125.32,103.8 126.75,103.8 v2(127.17,104.22)
  BOTTOM w0.127: v1(58.67,128.78) 58.67,125.54 58.23,125.1 58.23,122.95 v2(59.31,121.87)
IFC_CLK: length 84.4
  TOP w0.127: U57.J12 49.03,95.38 49.53,95.89 54.99,95.89 58.74,99.63 58.74,104.46 64.52,110.24 v1(64.52,110.74)
  BOTTOM w0.127: R21.2 117.86,104.14 115.32,106.68 109.22,106.68 106.17,109.73 65.53,109.73 v1(64.52,110.74)
IFC_CS0_N: length 127.8
  TOP w0.127: U1.C13 v2(124.77,101.02) ; U57.B6 42.97,102.45 42.42,103 42.42,107.57 45.09,110.24 45.09,130.56 45.59,131.06 55.88,131.06 v1(56.64,131.83) 58.29,133.48 80.14,133.48 84.58,129.03 v1(86.3,129.03)
  L6SIG w0.102: v1(86.3,129.03) 90.11,129.03 96.84,122.3 100.52,122.3 101.73,121.09 101.73,119.89 104.08,117.54 104.08,115.38 110.43,109.03 110.43,107.95 116.85,101.52 124.26,101.52 v2(124.77,101.02)
  BOTTOM w0.127: v1(56.64,131.83) 56.52,131.7 R12.1
IFC_CS1_N: length 131.9
  TOP w0.127: U57.B5 41.97,102.56 41.53,103 41.53,107.95 44.07,110.49 44.07,130.81 45.34,132.08 v1(54.99,132.08) 57.28,134.37 80.52,134.37 v1(84.33,130.56) ; U1.E15 v2(126.37,103.42)
  L6SIG w0.102: v1(84.33,130.56) 84.52,130.75 90.55,130.75 97.41,123.89 101.3,123.89 102.25,122.94 102.99,122.94 105.79,120.14 105.79,115.95 113.03,108.71 113.03,107.44 117.67,102.81 125.76,102.81 v2(126.37,103.42)
  BOTTOM w0.127: R15.1 55.5,131.57 v1(54.99,132.08)
IFC_CS2_N: length 131
  TOP w0.127: v1(83.76,131.83) 80.71,134.87 57.02,134.87 54.74,132.59 v1(53.98,132.59) 45.21,132.59 43.69,131.06 43.69,110.74 40.97,108.02 U57.A4 ; U1.D16 v2(125.57,104.22)
  L6SIG w0.102: v2(125.57,104.22) 125.36,104.22 124.8,103.66 120.01,103.66 118.21,103.66 114.68,107.19 114.68,108.52 106.81,116.4 106.81,120.65 102.55,124.9 97.73,124.9 90.8,131.83 v1(83.76,131.83)
  BOTTOM w0.127: v1(53.98,132.59) 54.48,132.08 R11.1
IFC_NDWE_N: length 92.6
  TOP w0.127: U4.C7 v2(63.45,123.47) ; U1.D14 v2(125.57,101.82)
  L6SIG w0.102: v2(125.57,101.82) 125.08,102.3 117.37,102.3 111.57,108.1 111.57,109.28 105.09,115.76 105.09,119.88 102.67,122.31 101.91,122.31 100.97,123.25 97.18,123.25 90.33,130.11 85.22,130.11 84.84,129.73 76.84,129.73 76.01,128.9 76.01,128.08 75.25,127.32 72.77,127.32 71.88,128.21 71.88,128.91 71.7,129.08 70.41,129.08 68.83,127.51 67.06,127.51 66.45,128.12 66.45,129.2 65.91,129.73 61.68,129.73 60.78,128.83 60.78,126.14 v2(63.45,123.47)
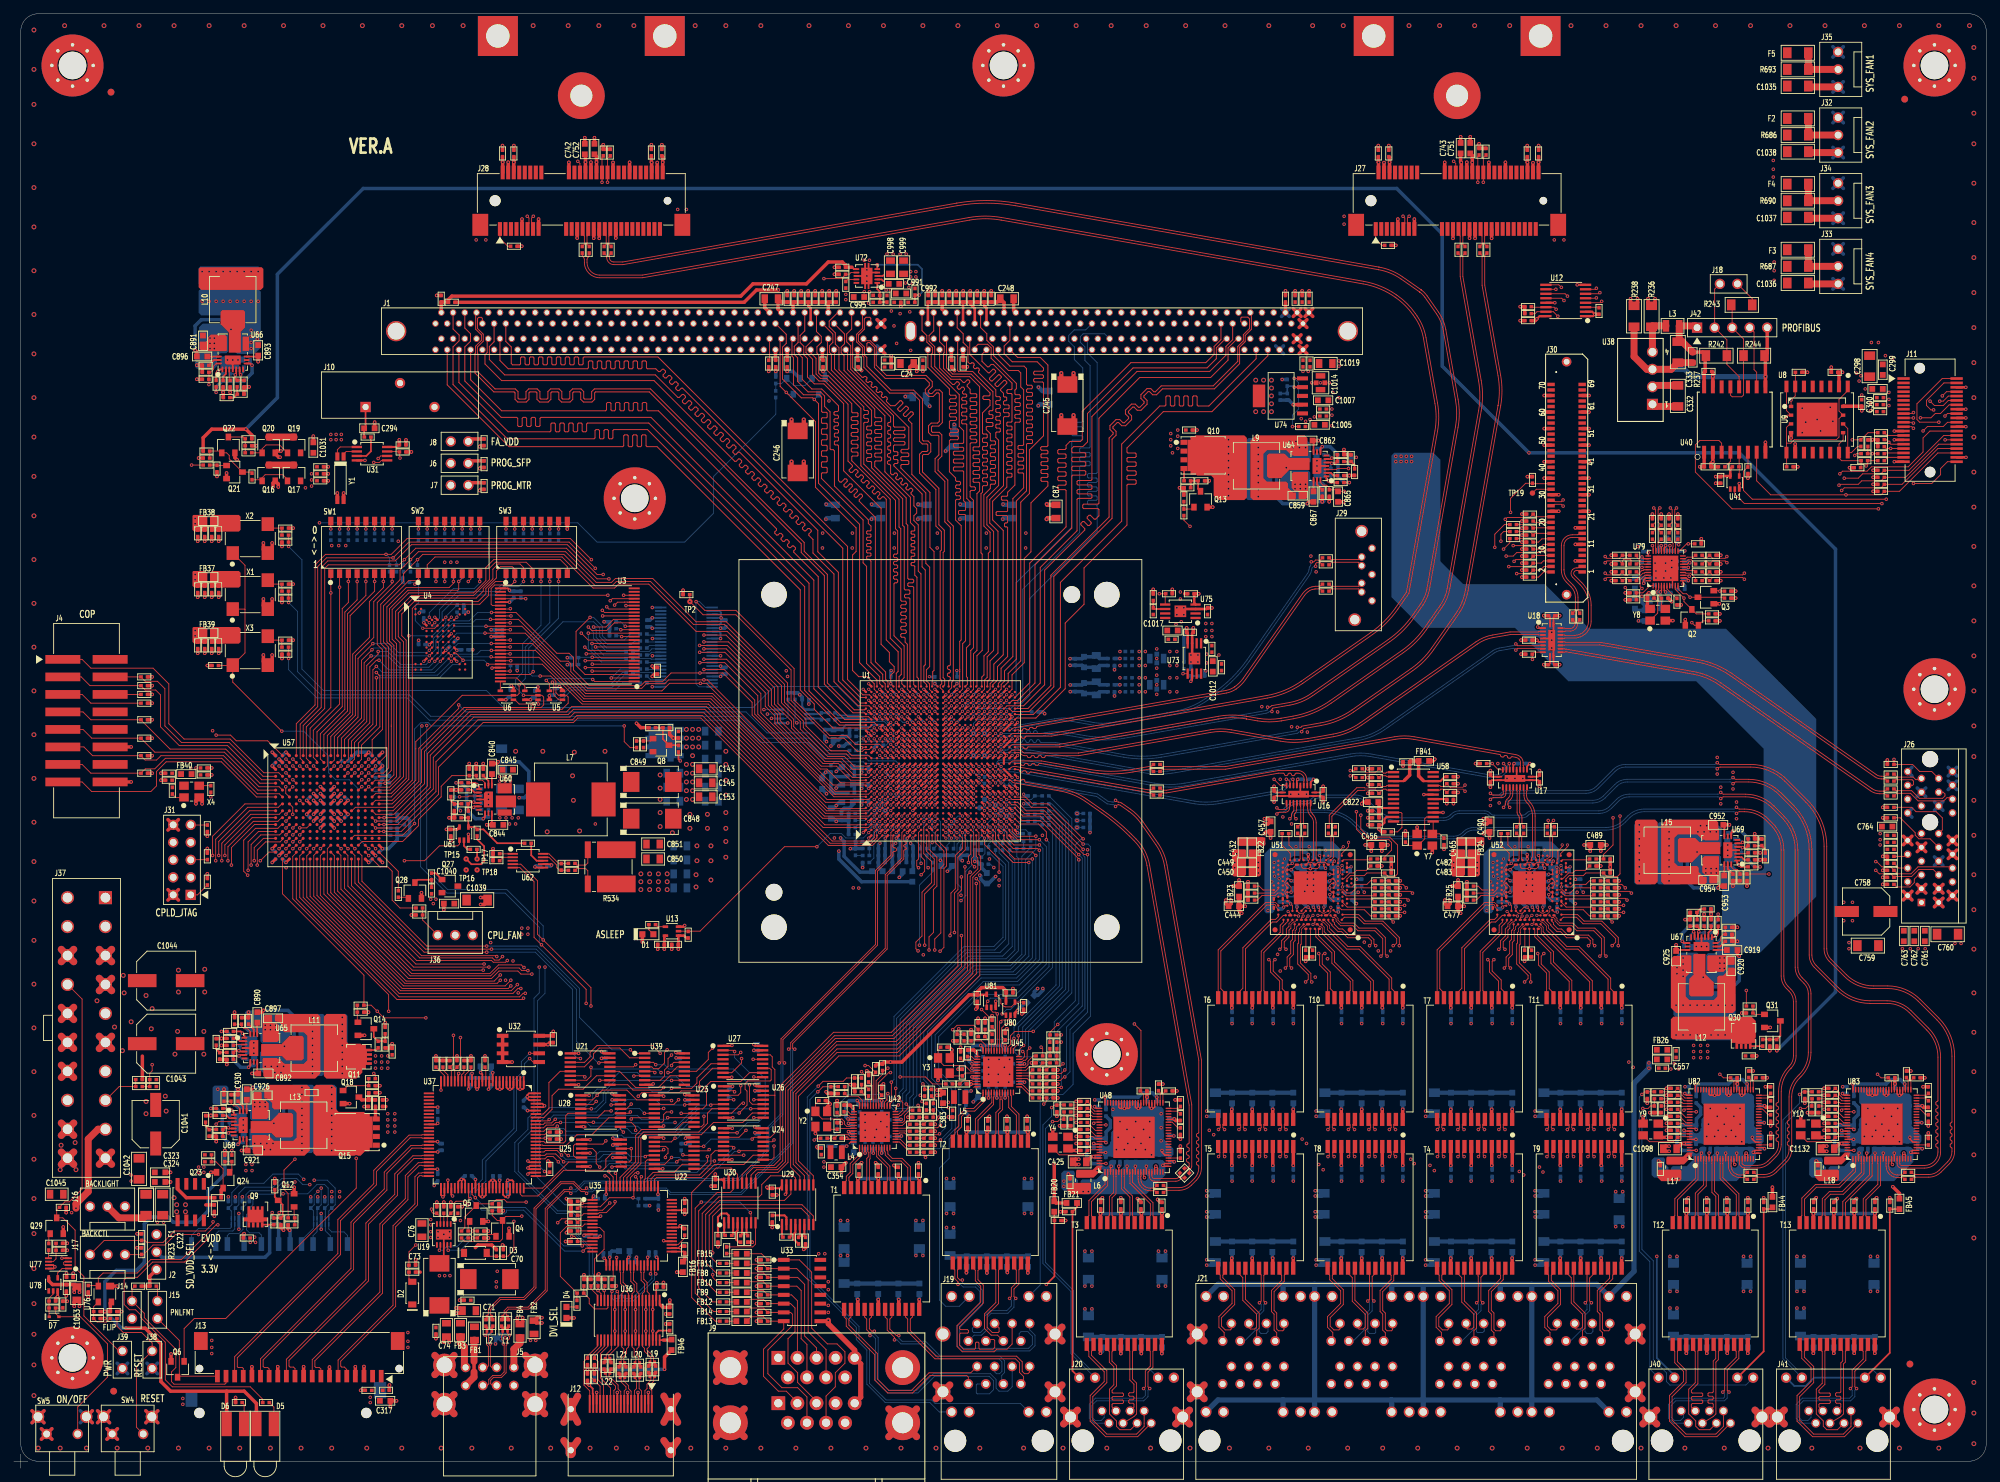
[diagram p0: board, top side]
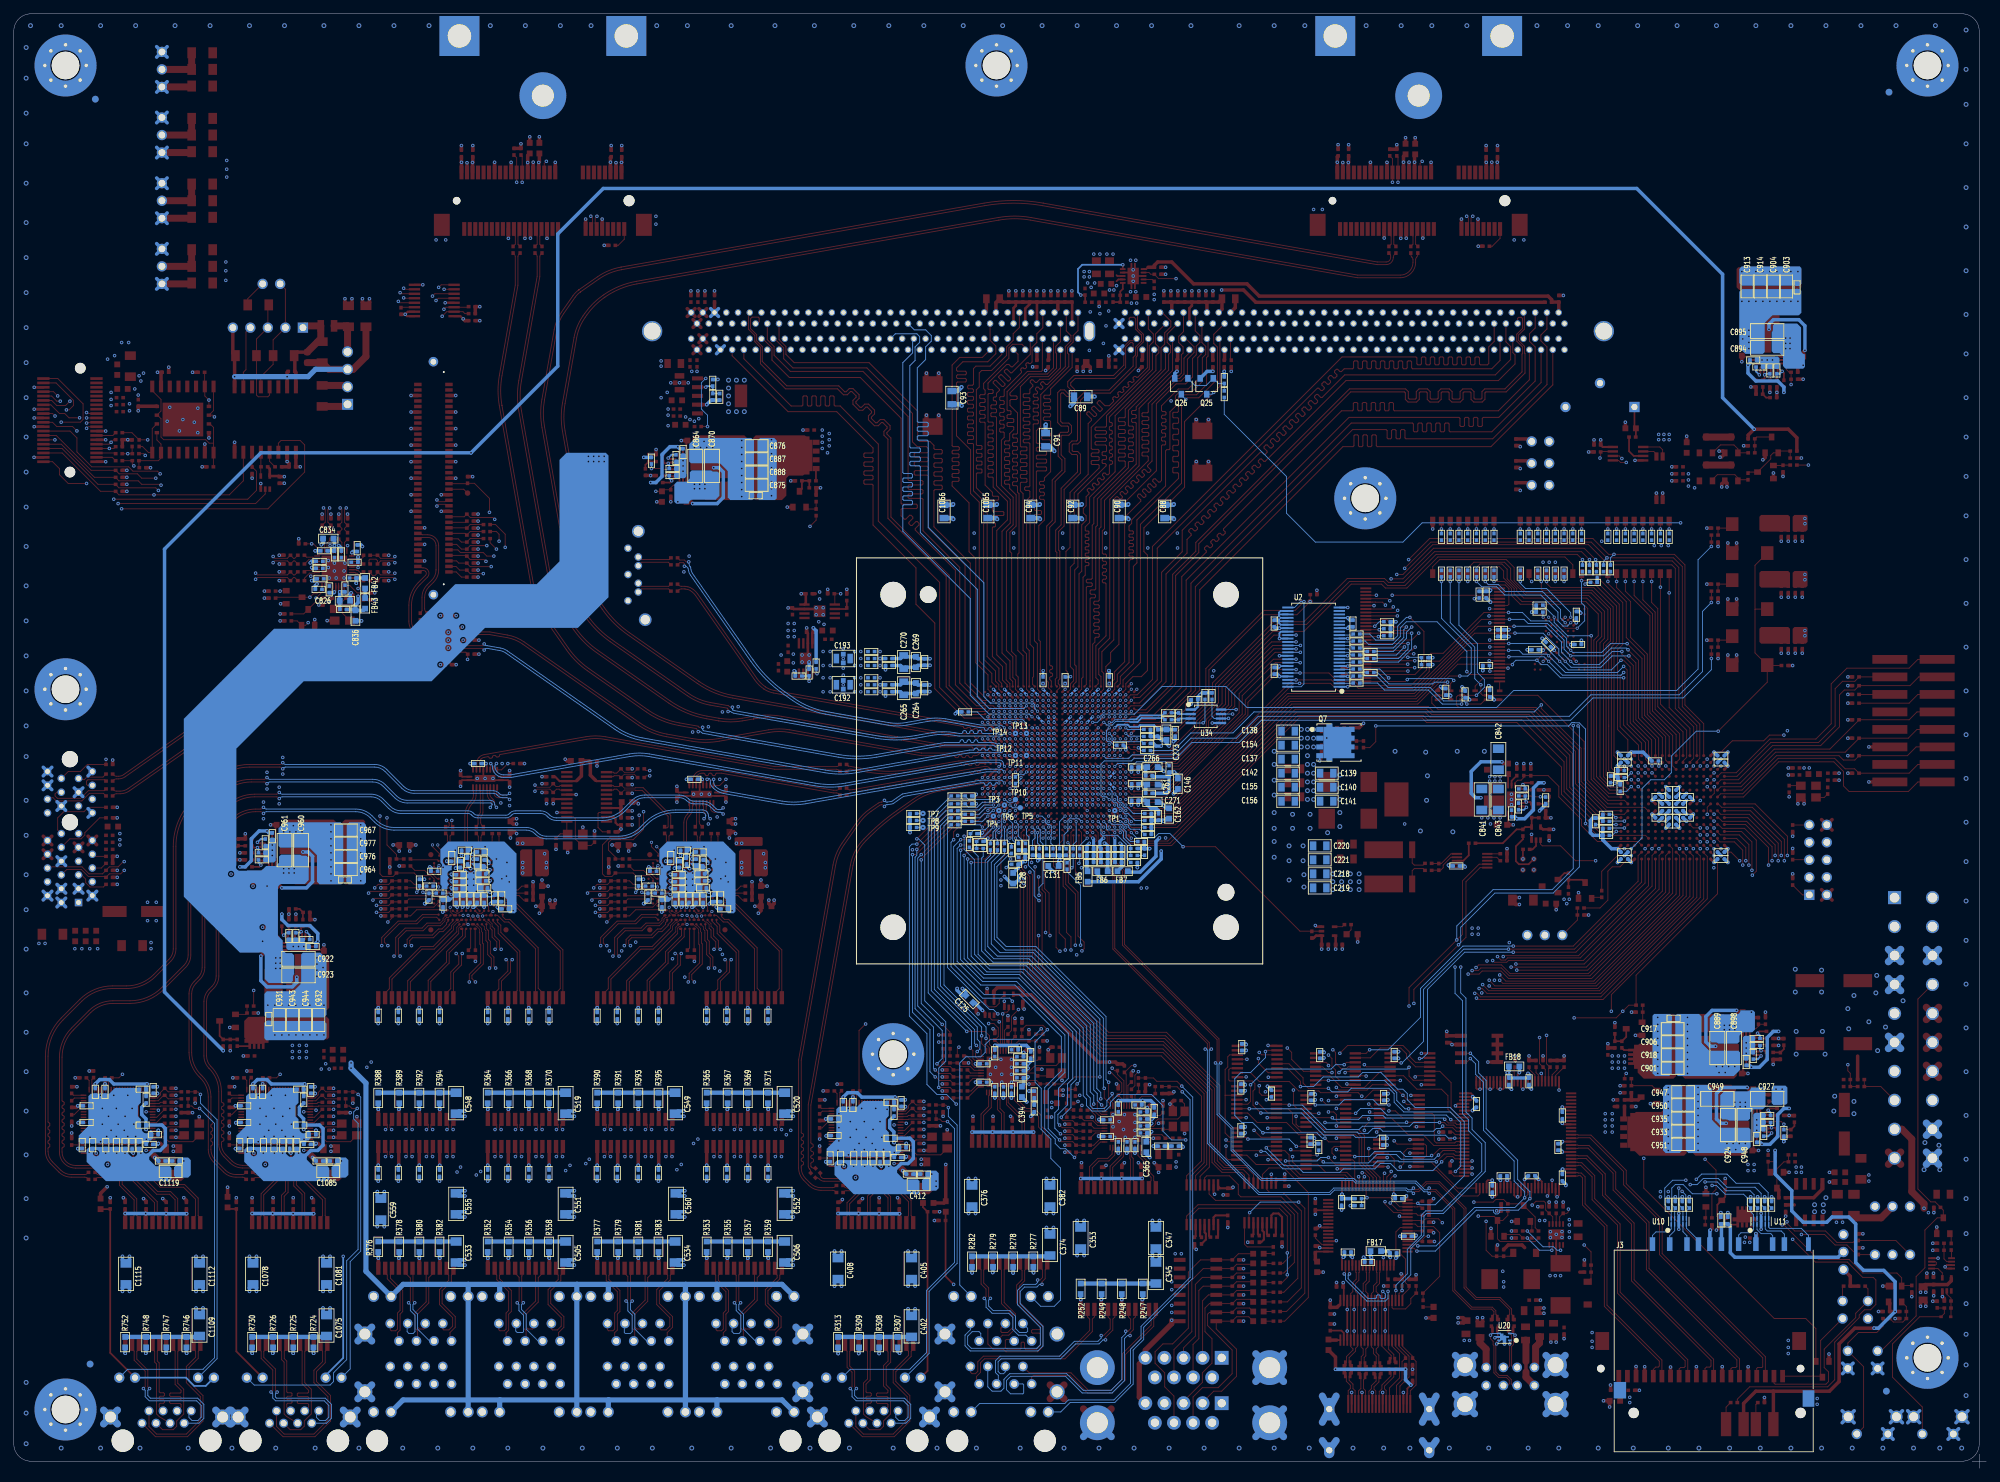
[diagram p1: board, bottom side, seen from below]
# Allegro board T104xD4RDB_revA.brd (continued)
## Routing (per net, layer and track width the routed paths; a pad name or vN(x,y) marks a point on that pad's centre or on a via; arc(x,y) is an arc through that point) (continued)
IFC_OE_N: length 146.6
  TOP w0.127: U1.D15 v2(125.57,103.42) ; U57.G15 52.5,97.92 54.74,97.92 56.9,100.08 56.9,120.14 56.26,120.78 56.26,123.95 58.04,125.73 67.31,125.73 68.45,126.87 68.45,127.63 69.98,129.16 69.98,130.18 70.61,130.81 72.26,130.81 72.64,130.43 SW3.2 v1(72.64,128.65) 72.13,128.14 69.72,128.14 69.22,127.63 69.22,125.35 69.41,125.15 U3.34 ; U4.D4 v2(61.05,122.67)
  L6SIG w0.102: v2(125.57,103.42) 125.27,103.12 117.79,103.12 113.98,106.93 113.98,108.33 106.11,116.2 106.11,120.44 102.27,124.27 97.47,124.27 90.68,131.06 76.83,131.06 74.74,128.97 74.74,128.16 74.47,127.89 73.41,127.89 v1(72.64,128.65)
  BOTTOM w0.127: R19.1 v1(72.64,128.65) 72.2,128.21 70.74,128.21 69.72,127.19 64.33,127.19 61.72,124.59 61.72,123.34 v2(61.05,122.67)
IFC_RB0_N: length 114.4
  TOP w0.127: U57.A15 51.97,105.69 53.47,107.19 53.47,118.74 52.71,119.5 52.71,125.6 56.01,128.91 56.01,130.3 v1(57.53,131.83) 58.67,132.97 80.01,132.97 84.46,128.52 86.68,128.52 87.25,129.1 92.65,129.1 98.93,122.81 103.31,122.81 112.2,113.92 112.2,111.32 114.87,108.65 114.87,107.7 118.49,104.08 120.84,104.08 121.54,103.38 124,103.38 U1.B15
  BOTTOM w0.127: R10.1 v1(57.53,131.83)
IFC_RB1_N: length 113.3
  TOP w0.127: U1.A15 121.33,103.02 120.71,103.63 118.3,103.63 114.49,107.44 114.49,108.4 111.76,111.12 111.76,113.73 103.06,122.43 98.55,122.43 92.33,128.65 87.38,128.65 86.8,128.08 84.26,128.08 79.76,132.59 59.31,132.59 v1(58.55,131.83) 56.52,129.79 56.52,128.65 53.78,125.92 53.21,125.35 53.21,119.63 53.98,118.87 53.98,103.38 52.98,102.39 U57.B16
  BOTTOM w0.127: R9.1 v1(58.55,131.83)
IFC_TE: length 81.4
  TOP w0.127: SW2.2 59.94,131.06 61.09,132.21 79.5,132.21 84.01,127.7 87.12,127.7 87.69,128.27 92.08,128.27 98.93,121.41 103.44,121.41 111.32,113.54 111.32,111.06 114.05,108.33 114.05,107.25 118.05,103.25 120.46,103.25 121.86,101.85 124,101.85 U1.B14
IFC_VA5: length 4.7
  TOP w0.127: U3.55 72.92,114.65 74.11,113.47 U7.4
IFC_VA6: length 1.4
  TOP w0.127: U3.56 70.55,114.14 U6.4
IFC_VA7: length 14.7
  TOP w0.127: U5.4 77.66,113.85 v1(77.22,114.3) ; U3.1 84.22,114.15 v1(83.95,114.43)
  BOTTOM w0.127: v1(83.95,114.43) 83.82,114.55 77.47,114.55 v1(77.22,114.3)
IFC_WE_N: length 137.1
  TOP w0.127: v1(82.3,121.16) 83.3,120.15 U3.13 ; U1.D13 v2(125.57,101.02) ; U57.H15 51.97,96.42 52.45,96.9 54.86,96.9 57.79,99.82 57.79,124.74 58.4,125.35 67.56,125.35 68.83,126.62 68.83,127.63 69.85,128.65 v1(71.37,128.65) SW3.1
  L6SIG w0.102: v2(125.57,101.02) 125.36,101.02 124.63,101.75 117.07,101.75 110.81,108.01 110.81,109.09 104.39,115.51 104.39,117.73 102.04,120.08 102.04,121.16 100.58,122.62 96.96,122.62 90.11,129.48 86.04,129.48 82.3,125.73 v1(82.3,121.16) 77.79,121.16 72.2,126.75 71.68,126.75 71.37,127.05 v1(71.37,128.65)
  BOTTOM w0.127: R20.1 v1(71.37,128.65)
IFC_WP_N: length 142.5
  TOP w0.127: U4.C3 v2(60.25,122.67) ; v1(73.91,128.65) SW3.3 73.91,130.68 73.41,131.19 70.23,131.19 69.47,130.43 69.47,129.03 68.07,127.64 68.07,127.25 67.06,126.24 57.91,126.24 55.75,124.08 55.75,120.65 56.52,119.89 56.52,100.33 54.57,98.39 U57.F16 ; U1.F17 v2(127.17,105.02)
  L6SIG w0.102: v2(127.17,105.02) 126.8,104.65 124.59,104.65 123.83,103.89 118.43,103.89 115.06,107.25 115.06,108.59 107.12,116.52 107.12,120.78 102.62,125.29 97.79,125.29 90.81,132.27 76.96,132.27 73.91,129.22 v1(73.91,128.65)
  BOTTOM w0.127: v2(60.25,122.67) 60.74,122.17 61.34,122.17 62.1,122.94 62.1,124.21 64.58,126.68 69.79,126.68 70.99,127.89 73.15,127.89 v1(73.91,128.65) R18.1
INA_VCORE_N: length 4.7
  TOP w0.127: R542.1 80.39,86.77 C853.2 79.1,86.77 78.74,87.12 78.74,87.5 77.6,88.64 U62.9
INA_VCORE_P: length 4.3
  TOP w0.127: U62.10 77.61,89.14 79.02,87.73 C853.1 80.39,87.73 R541.1
IO_B3: length 0.7
  TOP w0.127: U57.B3 v1(39.47,102.88)
IOPWR_EN: length 456.2
  TOP w0.127: R683.1 v1(31.62,46.1) ; U57.K2 38.82,94.38 38.29,93.85 34.73,93.85 31.05,90.17 v1(31.05,88.14) ; v1(28.3,157.23) C899.2 R579.2 28.58,159.01 28.96,159.39 28.96,159.9 29.34,160.28 U66.16 ; U69.16 249.04,87.25 249.42,86.87 249.93,86.87 250.31,86.49 R615.2 C957.2 v1(254.51,86.21)
  L3SIG w0.102: v1(28.83,107) 27.69,107 23.62,111.06 23.62,152.55 v1(28.3,157.23) ; v1(39.5,87.12) 37.53,87.12 35.94,88.71 31.62,88.71 v1(31.05,88.14) 31.05,77.41 26.54,72.9 26.54,49.28 29.08,46.74 30.99,46.74 v1(31.62,46.1)
  L6SIG w0.102: v1(31.05,88.14) 31.05,102.55 28.83,104.78 v1(28.83,107) ; v1(39.5,87.12) 40.07,87.12 59.31,67.88 59.31,58.74 65.47,52.58 70.99,52.58 78.42,45.15 78.42,44.26 79.88,42.8 81.09,42.8 82.61,41.27 82.61,39.24 84.52,37.34 84.52,36.51 84.9,36.13 99.95,36.13 107.7,43.88 110.49,43.88 112.33,45.72 112.33,53.21 127.65,68.53 142.79,68.53 143.5,67.82 146.75,67.82 147.7,66.87 163.51,66.87 173.1,76.45 173.1,86.93 174.62,88.46 174.62,93.41 182.18,100.97 192.85,100.97 196.22,104.33 249.75,104.33 254.51,99.57 v1(254.51,86.21)
IOPWR_EN_N: length 370.3
  TOP w0.127: U57.T2 38.97,83.34 50.77,71.53 R663.1 51.82,67.18 v1(52.71,66.29) 53.66,65.34 v1(59.75,65.34) ; v1(40.77,44.83) 39.18,43.24 39.18,40.45 39.78,39.85 R661.1 ; v1(52.2,57.28) 52.43,57.05 R670.1 ; R722.1 v1(251.23,69.32)
  L3SIG w0.102: v1(52.71,66.29) 51.82,65.41 51.82,57.66 v1(52.2,57.28) 51.82,56.9 51.82,49.28 47.37,44.83 v1(40.77,44.83)
  L6SIG w0.102: v1(251.23,69.32) 253.28,69.32 255.27,71.31 255.27,99.25 249.87,104.65 196.09,104.65 192.66,101.22 182.11,101.22 174.4,93.5 174.4,93.5 174.31,93.41 174.31,88.58 172.85,87.12 172.85,76.58 163.39,67.12 147.89,67.12 146.94,68.07 143.57,68.07 142.88,68.76 127.5,68.76 112.01,53.28 112.01,45.78 110.36,44.13 107.57,44.13 99.82,36.39 85.92,36.39 83.53,38.77 83.53,40.86 81.18,43.21 81.18,44.29 80.58,44.89 79.25,44.89 71.18,52.96 65.53,52.96 59.75,58.74 v1(59.75,65.34)
ISO_DE: length 9
  TOP w0.127: J42.4 252.35,164.85 252.35,159.38 252.73,159 U40.10
ISO_RXD_TXD_N: length 17.1
  TOP w0.127: U40.13 248.92,155.7 249.17,155.45 250.57,155.45 250.83,155.7 R244.2 250.83,163.83 J42.3 249.17,168.66 R243.1
ISO_RXD_TXD_P: length 16.7
  TOP w0.127: U40.12 250.19,158.37 248.41,160.15 R242.1 248.41,163.7 J42.2 246.63,171.07 J18.2
JTAG_TCK: length 128.4
  TOP w0.127: U1.E18 v2(126.37,105.82) ; U57.B4 v1(40.47,102.88)
  L6SIG w0.102: v2(126.37,105.82) 126.15,105.82 125.73,106.23 121.35,106.23 120.59,107 119.44,107 116.21,110.24 116.21,111.06 114.11,113.16 113.28,113.16 109.09,117.35 109.09,121.41 95.69,134.81 56.39,134.81 56.13,135.06 51.18,135.06 44.01,127.89 44.01,105.85 41.04,102.88 v1(40.47,102.88)
JTAG_TDI: length 125.1
  TOP w0.127: U57.C4 v1(40.47,101.88) ; U1.A18 v2(123.17,105.82)
  L6SIG w0.102: v2(123.17,105.82) 121.32,105.82 120.46,106.68 119.25,106.68 115.82,110.11 115.82,111 113.98,112.84 113.09,112.84 108.78,117.16 108.78,121.29 95.63,134.43 56.45,134.43 55.94,133.92 50.62,133.92 44.32,127.63 44.32,105.74 v1(40.47,101.88)
JTAG_TDO: length 124.7
  TOP w0.127: U1.C18 v2(124.77,105.82) ; U57.C6 v1(42.47,101.88)
  L6SIG w0.102: v1(42.47,101.88) 42.47,102.85 45.09,105.47 45.09,127.51 47.63,130.05 58.29,130.05 61.91,133.67 95.5,133.67 108.08,121.09 108.08,116.9 118.94,106.05 120.08,106.05 120.92,105.21 123.94,105.21 124.55,105.82 v2(124.77,105.82)
JTAG_TMS: length 124.7
  TOP w0.127: U1.B18 v2(123.97,105.82) ; U57.C5 v1(41.47,101.88)
  L6SIG w0.102: v2(123.97,105.82) 123.59,105.43 121.2,105.43 120.27,106.36 119.06,106.36 108.4,117.03 108.4,121.22 95.57,134.05 61.78,134.05 58.17,130.43 47.56,130.43 44.7,127.57 44.7,105.6 41.47,102.36 v1(41.47,101.88)
JTAG_TRST_N: length 124.7
  TOP w0.127: U1.D19 v2(125.57,105.82) ; U57.C7 v1(43.47,101.88)
  L6SIG w0.102: v2(125.57,105.82) 125.01,105.26 124.43,105.26 124.15,104.98 120.69,104.98 120.02,105.65 119.98,105.66 118.87,105.66 107.76,116.78 107.76,120.97 95.44,133.29 62.04,133.29 58.42,129.67 47.75,129.67 45.4,127.32 45.4,105.28 43.47,103.35 v1(43.47,101.88)
LED_STATUS: length 121.6
  TOP w0.127: U57.H2 38.85,96.39 38.35,95.89 33.91,95.89 29.27,91.25 v1(29.27,88.14) ; v1(28.07,33.21) 24.77,29.91 20.13,29.91 17.91,27.69 16.38,27.69 16,27.3 16,23.75 16.76,22.99 17.65,22.99 18.42,22.22 18.42,21.84 21.97,18.29 21.97,12.83 22.99,11.81 34.29,11.81 36.09,10.01 R688.1
  L3SIG w0.102: v1(28.07,33.21) 26.48,33.21 25.65,34.04 25.65,38.61 25.02,39.24 25.02,73.41 29.27,77.66 v1(29.27,88.14)
LVDS0_N: length 35.8
  TOP w0.127: J13.5 48.28,14.33 47.94,14.67 47.56,14.67 47.41,14.82 47.41,15.53 55.37,23.5 55.37,35.02 58.55,38.2 58.55,42.13 58.86,42.45 59.16,42.45 59.22,42.39 U37.50
LVDS0_P: length 35.8
  TOP w0.127: U37.49 59.22,42.89 59.16,42.83 58.7,42.83 58.17,42.29 58.17,38.35 54.99,35.18 54.99,23.65 47.03,15.69 J13.6
LVDS1_N: length 38.9
  TOP w0.127: J13.8 44.53,14.4 44.32,14.61 43.82,14.61 43.66,14.76 43.66,15.59 53.47,25.4 53.47,35.28 57.15,38.96 57.15,42.29 58.81,43.95 59.16,43.95 59.22,43.89 U37.47
LVDS1_P: length 38.9
  TOP w0.127: J13.9 43.28,15.75 53.09,25.56 53.09,35.43 56.77,39.12 56.77,42.45 58.65,44.33 59.16,44.33 59.22,44.39 U37.46
LVDS2_N: length 41.9
  TOP w0.127: J13.11 40.78,14.47 40.58,14.67 40.07,14.67 39.91,14.83 39.91,15.65 51.44,27.18 51.44,35.4 55.63,39.59 55.63,42.55 58.03,44.95 59.16,44.95 59.22,44.89 U37.45
LVDS2_P: length 41.9
  TOP w0.127: J13.12 39.53,15.81 51.05,27.34 51.05,35.56 55.25,39.75 55.25,42.7 57.87,45.33 59.16,45.33 59.22,45.39 U37.44
LVDS3_N: length 48.4
  TOP w0.127: U37.39 59.22,47.89 59.16,47.95 57.47,47.95 52.58,43.05 52.58,41.12 47.37,35.91 47.37,30.99 32.41,16.03 32.41,14.73 32.54,14.61 33.15,14.61 33.28,14.48 J13.17
LVDS3_P: length 48.3
  TOP w0.127: U37.38 59.22,48.39 59.16,48.33 57.31,48.33 52.2,43.21 52.2,41.27 46.99,36.07 46.99,31.15 32.03,16.18 J13.18
LVDS_CLK_N: length 45.2
  TOP w0.127: J13.14 37.03,14.41 36.83,14.61 36.32,14.61 36.16,14.77 36.16,15.71 49.28,28.83 49.28,35.53 54.1,40.36 54.1,42.8 57.75,46.45 59.16,46.45 59.22,46.39 U37.42
LVDS_CLK_P: length 45.1
  TOP w0.127: J13.15 35.78,15.87 48.9,28.99 48.9,35.69 53.72,40.51 53.72,42.96 57.59,46.83 59.16,46.83 59.22,46.89 U37.41
MPEX1_REFCLK_N: length 79.3
  TOP w0.127: v1(240.22,139.32) 240.47,139.06 240.47,137.25 R513.1 240.47,136.36 240.47,136.18 R507.2 ; J27.13 202.3,180.35 202.09,180.56 202.09,181.39 v1(202.34,181.64)
  L3SIG w0.102: v1(202.34,181.64) 202.34,181.44 202.24,181.34 202.01,181.34 201.9,181.44 201.9,182.85 202.31,183.26 212.6,183.26 216.41,179.46 216.41,167 219.2,164.21 226.83,164.21 231.65,159.39 231.65,151.26 240.48,142.43 240.48,139.59 v1(240.22,139.32)
MPEX1_REFCLK_P: length 79.6
  TOP w0.127: v1(241.11,139.32) 240.86,139.07 240.86,137.25 R505.1 240.86,136.36 240.86,136.18 R506.2 ; v1(201.45,181.64) 201.71,181.39 201.71,180.62 201.5,180.41 J27.11
  L3SIG w0.102: v1(241.11,139.32) 240.84,139.59 240.84,142.57 232,151.41 232,159.54 226.97,164.57 219.35,164.57 216.76,167.15 216.76,179.6 212.75,183.62 202.16,183.62 201.55,183 201.55,181.74 v1(201.45,181.64)
MPEX1_RST_N: length 285.1
  TOP w0.127: J27.22 209.1,189.3 v1(208.79,189.61) ; U57.E4 v1(40.47,99.88)
  L3SIG w0.102: v1(40.47,99.88) 39.96,100.39 31.31,100.39 22.23,109.47 22.23,178.31 31.24,187.32 207.14,187.32 208.79,188.98 v1(208.79,189.61)
MPEX1_RX_N: length 121
  TOP w0.127: C738.2 209.59,176.13 arc(209.7,175.97) 209.74,175.77 209.74,172.89 212.41,157.74 arc(212.6,155.6) 212.41,153.46 207.87,127.69 arc(207.48,126.37) 206.82,125.15 204.51,121.86 arc(203.05,120.12) 201.31,118.66 190.83,111.32 arc(188.28,109.93) 185.5,109.11 183.76,108.81 arc(183.75,108.81) 183.73,108.8 arc(182.06,108.66) 180.39,108.81 178.81,109.09 178.78,109.09 arc(176.72,109.27) 174.67,109.09 151.64,105.03 151.63,105.03 145.06,105.03 arc(144.8,104.98) 144.58,104.83 U1.AG17
MPEX1_RX_P: length 121
  TOP w0.127: C737.2 210.27,176.13 arc(210.16,175.97) 210.12,175.77 210.12,172.92 212.79,157.81 arc(212.98,155.6) 212.79,153.39 208.24,127.63 arc(207.83,126.22) 207.13,124.94 204.82,121.64 arc(203.32,119.85) 201.53,118.35 191.05,111.01 arc(188.43,109.57) 185.56,108.74 183.8,108.43 183.8,108.43 arc(182.06,108.28) 180.32,108.43 178.74,108.71 178.71,108.72 arc(176.72,108.89) 174.74,108.72 151.71,104.66 151.66,104.65 147.09,104.65 arc(147,104.61) 146.95,104.51 arc(146.91,104.41) 146.81,104.37 146.59,104.37 arc(146.49,104.41) 146.45,104.51 arc(146.41,104.61) 146.31,104.65 145.2,104.65 U1.AH17
MPEX1_TX_N: length 128.5
  TOP w0.127: C740.2 212.77,176.13 arc(212.88,175.97) 212.92,175.77 212.92,171.61 215.23,158.49 arc(215.42,156.36) 215.24,154.24 arc(215.23,154.21) 215.23,154.19 210.51,127.45 arc(209.98,125.62) 209.06,123.95 205.58,118.97 arc(204.24,117.37) 202.64,116.03 194.06,110.02 arc(191.89,108.83) 189.51,108.14 186.79,107.66 186.73,107.57 arc(186.68,107.51) 186.61,107.49 v1(186.13,107.49) ; U1.AE17 v2(143.17,105.02)
  BOTTOM w0.127: v1(186.13,107.49) 186.13,107.22 arc(186.11,107.14) 186.07,107.07 185.99,107 166.39,103.54 arc(163.67,103.3) 160.95,103.54 151.06,105.28 148.99,105.28 arc(148.85,105.34) 148.79,105.49 arc(148.73,105.63) 148.59,105.69 148.48,105.69 arc(148.34,105.63) 148.28,105.49 arc(148.22,105.34) 148.08,105.28 147.98,105.28 arc(147.83,105.34) 147.77,105.49 arc(147.71,105.63) 147.57,105.69 147.47,105.69 arc(147.32,105.63) 147.27,105.49 arc(147.21,105.34) 147.06,105.28 146.96,105.28 arc(146.82,105.34) 146.76,105.49 arc(146.7,105.63) 146.55,105.69 146.45,105.69 arc(146.31,105.63) 146.25,105.49 arc(146.19,105.34) 146.05,105.28 144.11,105.28 arc(143.9,105.26) 143.71,105.19 143.52,105.1 arc(143.35,105.04) v2(143.17,105.02)
MPEX1_TX_P: length 128.5
  TOP w0.127: U1.AD17 v2(142.37,105.02) ; v1(186.76,106.87) 187.03,107.31 189.58,107.76 arc(192.04,108.48) 194.28,109.71 202.86,115.71 arc(204.51,117.1) 205.89,118.75 209.38,123.73 arc(210.33,125.47) 210.89,127.38 215.61,154.17 arc(215.8,156.36) 215.61,158.55 213.3,171.65 213.3,175.77 arc(213.34,175.97) 213.45,176.13 C739.2
  BOTTOM w0.127: v2(142.37,105.02) 142.62,104.76 arc(142.77,104.66) 142.95,104.62 143.43,104.62 arc(143.6,104.66) 143.74,104.75 arc(143.91,104.86) 144.11,104.9 151.03,104.9 160.88,103.16 arc(163.67,102.92) 166.45,103.16 186.17,106.64 186.3,106.76 arc(186.41,106.84) 186.54,106.87 v1(186.76,106.87)
MPEX2_REFCLK_N: length 199.1
  TOP w0.127: v1(75.34,181.64) 75.09,181.39 75.09,180.56 75.3,180.35 J28.13 ; v1(237.8,139.32) 238.06,139.06 238.06,137.25 R517.2 238.06,136.36 238.06,136.18 R515.2
  L3SIG w0.102: v1(237.8,139.32) 238.07,139.59 238.07,141.79 229.62,150.25 229.62,158.63 226.19,162.05 212.86,162.05 205.26,169.65 205.26,173.96 199.77,179.45 94.74,179.45 90.68,183.51 75.94,183.51 74.88,182.46 74.88,181.38 74.98,181.28 75.24,181.28 75.34,181.38 v1(75.34,181.64)
MPEX2_REFCLK_P: length 199.2
  TOP w0.127: R514.2 238.44,136.18 238.44,136.36 R509.2 238.44,137.25 238.44,139.07 v1(238.69,139.32) ; v1(74.45,181.64) 74.71,181.39 74.71,180.62 74.5,180.41 J28.11
  L3SIG w0.102: v1(74.45,181.64) 74.53,181.72 74.53,182.6 75.79,183.87 90.83,183.87 94.89,179.81 199.92,179.81 205.61,174.11 205.61,169.8 213,162.41 226.34,162.41 229.97,158.78 229.97,150.39 238.43,141.94 238.43,139.59 v1(238.69,139.32)
MPEX2_RST_N: length 158.6
  TOP w0.127: v1(81.79,189.61) 82.1,189.3 J28.22 ; U57.E3 v1(39.47,99.88)
  L3SIG w0.102: v1(81.79,189.61) 81.79,188.09 81.41,187.71 30.99,187.71 21.84,178.56 21.84,109.35 31.31,99.88 v1(39.47,99.88)
MPEX2_RX_N: length 230.6
  TOP w0.127: U1.AG19 144.57,106.42 arc(144.77,106.55) 145,106.6 150.44,106.6 150.44,106.6 181.7,112.11 arc(184.29,112.87) 186.66,114.16 186.69,114.18 196.78,121.25 arc(198.73,122.89) 200.38,124.85 201.95,127.09 206.07,150.49 arc(206.25,152.49) 206.07,154.49 204.4,163.98 arc(203.95,165.54) 203.17,166.96 202.92,167.31 arc(201.77,168.68) 200.4,169.83 200.3,169.91 arc(198.08,171.12) 195.66,171.83 143.18,181.08 arc(140.88,181.28) 138.58,181.08 91.16,172.72 84.97,172.72 arc(83.39,173.37) 82.74,174.95 82.74,175.34 arc(82.7,175.54) 82.59,175.71 arc(82.47,175.89) 82.42,176.11 C768.2
MPEX2_RX_P: length 230.6
  TOP w0.127: C757.2 83.44,176.07 arc(83.4,175.89) 83.3,175.73 83.27,175.71 arc(83.16,175.54) 83.12,175.34 83.12,174.95 arc(83.66,173.64) 84.97,173.1 91.13,173.1 138.51,181.46 arc(140.88,181.66) 143.25,181.46 195.73,172.2 arc(198.23,171.47) 200.52,170.22 200.62,170.15 arc(202.04,168.95) 203.23,167.53 203.48,167.18 arc(204.3,165.68) 204.78,164.04 206.45,154.56 arc(206.63,152.49) 206.45,150.42 202.31,126.97 arc(202.31,126.94) 202.29,126.92 200.69,124.63 arc(199,122.62) 197,120.93 186.91,113.87 186.88,113.85 arc(184.44,112.51) 181.77,111.73 150.47,106.22 146.79,106.22 arc(146.69,106.17) 146.64,106.07 146.64,106.07 arc(146.6,105.96) 146.49,105.92 146.28,105.92 arc(146.18,105.96) 146.14,106.07 146.14,106.07 arc(146.09,106.17) 145.99,106.22 U1.AH19
MPEX2_TX_N: length 237.7
  TOP w0.127: v1(181.81,110.42) 182.03,110.42 arc(182.16,110.44) 182.27,110.52 182.39,110.63 184.99,111.09 arc(186.63,111.57) 188.13,112.39 199.31,120.22 arc(201.22,121.83) 202.83,123.74 204.05,125.48 arc(204.59,126.47) 204.91,127.56 209.06,151.09 arc(209.23,153.06) 209.06,155.03 207.28,165.13 arc(206.92,166.36) 206.29,167.5 204.62,169.88 arc(204.28,170.3) 203.86,170.65 203.85,170.66 201.17,172.54 arc(199.61,173.39) 197.9,173.89 197.87,173.89 145.25,183.17 arc(141.03,183.54) 136.81,183.17 88.33,174.62 87.02,174.62 arc(86.28,174.93) 85.98,175.66 arc(85.93,175.9) 85.8,176.1 C770.2 ; U1.AE19 v2(143.17,106.62)
  BOTTOM w0.127: v2(143.17,106.62) 143.17,106.61 143.17,106.6 145.45,106.6 arc(145.61,106.67) 145.68,106.83 arc(145.75,106.99) 145.91,107.06 145.96,107.06 arc(146.12,106.99) 146.19,106.83 arc(146.26,106.67) 146.42,106.6 146.67,106.6 arc(146.82,106.66) 146.88,106.81 arc(146.93,106.95) 147.08,107.01 147.18,107.01 arc(147.32,106.95) 147.38,106.81 arc(147.44,106.66) 147.59,106.6 147.69,106.6 arc(147.83,106.66) 147.89,106.81 arc(147.95,106.95) 148.09,107.01 148.2,107.01 arc(148.34,106.95) 148.4,106.81 arc(148.46,106.66) 148.6,106.6 148.91,106.6 149.54,106.71 arc(151.21,106.86) 152.89,106.71 155.24,106.3 arc(158.13,106.04) 161.02,106.3 181.53,109.91 arc(181.62,109.94) 181.7,109.98 181.8,110.06 181.81,110.07 v1(181.81,110.42)
MPEX2_TX_P: length 237.7
  TOP w0.127: v1(182.44,109.79) 182.44,110.06 arc(182.46,110.14) 182.5,110.2 182.57,110.28 185.05,110.72 arc(186.78,111.22) 188.35,112.08 199.53,119.91 arc(201.49,121.56) 203.14,123.53 203.16,123.55 204.36,125.26 arc(204.94,126.33) 205.28,127.5 209.43,151.02 arc(209.61,153.06) 209.43,155.1 207.65,165.19 arc(207.27,166.51) 206.61,167.72 204.94,170.1 arc(204.55,170.57) 204.08,170.96 arc(204.08,170.96) 204.08,170.96 204.07,170.97 201.39,172.85 arc(199.75,173.74) 197.97,174.26 197.94,174.27 145.32,183.55 arc(141.03,183.92) 136.74,183.55 88.3,175.01 87.02,175.01 arc(86.55,175.2) 86.36,175.66 86.36,175.88 arc(86.39,176.03) 86.48,176.17 C769.2 ; U1.AD19 v2(142.37,106.62)
  BOTTOM w0.127: v2(142.37,106.62) 142.57,106.41 arc(142.78,106.27) 143.03,106.22 148.95,106.22 149.61,106.34 arc(151.21,106.48) 152.82,106.34 155.18,105.92 arc(158.13,105.66) 161.09,105.92 181.6,109.54 arc(181.76,109.59) 181.92,109.67 182.08,109.79 182.08,109.79 v1(182.44,109.79)
MVREF: length 65
  TOP w0.254: U72.6 121.81,173.97 121.54,174.24
  TOP w0.508: 121.54,174.24 C996.1 120.62,174.52 120.14,175.01 118.11,175.01 114.94,171.83 107.19,171.83 105.41,170.05 63.53,170.05 63.02,169.55 C21.2 62.99,169.19 C22.1 61.98,167.7 J1.146
NAND_CS_N: length 36.1
  TOP w0.127: U4.C6 v2(62.65,123.47) ; v1(57.28,120.78) 57.28,99.95 54.71,97.39 U57.G16
  BOTTOM w0.127: v1(57.28,120.78) 60.71,120.78 62.65,122.72 v2(62.65,123.47) 62.65,123.58 R53.1
NAND_RB_N: length 35.4
  TOP w0.127: U4.C8 v2(64.25,123.47) ; U57.D11 v1(48.47,100.88)
  L6SIG w0.102: v1(48.47,100.88) 48.01,101.34 48.01,103.05 56.52,111.56 56.52,120.9 59.63,124.02 61.21,124.02 62.23,123 63.78,123 v2(64.25,123.47)
  BOTTOM w0.127: R56.1 64.29,123.51 v2(64.25,123.47)
Net_167: length 0.6
  TOP w0.127: 125.17,102.22 124.77,101.82
NOR_CS_N: length 67.3
  TOP w0.127: U57.D13 v1(50.47,100.88) ; U3.32 v1(74.23,126.15)
  L3SIG w0.102: v1(50.47,100.88) 49.97,101.38 49.97,116.4 44.48,121.89 44.48,128.36 46.41,130.3 55.44,130.3 58.8,126.94 73.45,126.94 v1(74.23,126.15)
  BOTTOM w0.127: R50.1 74.12,126.26 v1(74.23,126.15)
NOR_RB_N: length 81.5
  TOP w0.127: U3.17 v1(88.67,122.15) ; U57.E14 v1(51.47,99.88)
  L3SIG w0.102: v1(88.67,122.15) 85.11,122.15 84.33,122.94 80.52,122.94 78.49,124.97 73.53,124.97 72.39,126.11 58.74,126.11 55.31,129.54 46.74,129.54 45.21,128.02 45.21,122.56 50.67,117.09 50.67,102.43 50.93,102.17 50.93,100.46 51.47,99.92 v1(51.47,99.88)
  BOTTOM w0.127: R54.1 88.01,122.81 v1(88.67,122.15)
NOR_RST_N: length 78.4
  TOP w0.127: U57.C14 v1(51.47,101.88) ; U3.14 v1(88.14,120.65)
  L3SIG w0.102: v1(88.14,120.65) 86.23,120.65 84.33,122.56 80.26,122.56 78.36,124.46 73.41,124.46 72.64,125.22 59.18,125.22 55.25,129.16 46.99,129.16 45.54,127.71 45.54,122.86 50.99,117.41 50.99,102.62 51.47,102.14 v1(51.47,101.88)
  BOTTOM w0.127: R55.1 88.02,120.78 v1(88.14,120.65)
PEX_PRS_N: length 314.8
  TOP w0.127: U57.P5 v1(41.47,89.89) ; v1(272.64,102.84) R449.1 275.34,102.11 276.35,101.09 278.11,101.09 J26.B17
  L6SIG w0.102: v1(272.64,102.84) 269.57,105.92 195.58,105.92 191.96,102.3 181.68,102.3 173.33,93.95 173.33,89.32 171.7,87.69 171.7,77.03 163.77,69.09 144.02,69.09 143.43,69.67 139.36,69.67 126.76,69.67 110.74,53.66 110.74,46.1 109.92,45.28 107.19,45.28 100.08,38.16 93.03,38.16 92.39,37.53 86.61,37.53 85.47,38.67 85.47,40.89 82.93,43.43 82.93,45.51 81.3,47.14 79.29,47.14 78.87,47.56 78.87,48.68 73.19,54.36 65.91,54.36 62.17,58.1 62.17,66.8 41.47,87.5 v1(41.47,89.89)
PEX_REFCLK_N: length 57
  TOP w0.127: v1(250.95,129.86) 250.69,129.6 246.34,129.6 R502.1 245.45,129.6 245.27,129.6 R501.2
  L3SIG w0.102: v1(250.95,129.86) 251.22,129.59 256.73,129.59 270.76,115.56 270.76,98.17 272.67,96.27 275.21,96.27 275.59,96.65 275.59,96.94 275.45,97.08 J26.A14
PEX_REFCLK_P: length 56.6
  TOP w0.127: v1(250.95,128.97) 250.7,129.22 246.34,129.22 R499.1 245.45,129.22 245.27,129.22 R500.2
  L3SIG w0.102: J26.A13 275.52,96.08 275.36,95.91 272.52,95.91 270.41,98.02 270.41,115.42 256.59,129.24 251.22,129.24 v1(250.95,128.97)
PEX_RST_N: length 317.9
  TOP w0.127: U57.M4 v1(40.47,91.89)
  L6SIG w0.102: v1(40.47,91.89) 40.96,91.39 40.96,87.57 61.79,66.74 61.79,58.1 65.91,53.98 73.09,53.98 78.54,48.53 78.54,47.38 79.12,46.8 81.28,46.8 82.52,45.56 82.52,43.4 85.15,40.77 85.15,38.48 86.36,37.27 92.58,37.27 93.21,37.9 100.19,37.9 107.32,45.02 110.05,45.02 111.06,46.04 111.06,53.53 126.97,69.44 138.89,69.44 143.22,69.44 143.83,68.83 163.97,68.83 172.02,76.88 172.02,87.63 173.56,89.17 173.56,93.57 173.56,93.8 181.8,102.04 192.15,102.04 195.71,105.6 250.32,105.6 262.83,93.09 275.61,93.09 J26.A11
PEX_RX_N: length 52.9
  TOP w0.127: U18.15 224.88,119.89 224.94,119.83 230,119.83 244.19,117.33 arc(246.8,116.57) 249.18,115.26 270.09,100.62 arc(270.44,100.45) 270.82,100.39 271.15,100.39 arc(271.34,100.43) 271.51,100.54 C748.2
PEX_RX_P: length 52.9
  TOP w0.127: U18.14 224.88,119.39 224.94,119.45 229.97,119.45 244.12,116.96 arc(246.65,116.22) 248.96,114.95 269.87,100.31 arc(270.32,100.09) 270.82,100.01 271.15,100.01 arc(271.34,99.97) 271.51,99.86 C741.2
PEX_SEL: length 219.4
  TOP w0.127: v1(220.22,117.35) 220.19,117.37 R148.2 220.47,118.39 U18.9 ; U57.T4 40.97,82.61 55.56,68.01 73.72,68.01 v1(73.91,68.2)
  L6SIG w0.102: v1(73.91,68.2) 74.23,68.2 74.8,68.77 112.97,68.77 123.28,79.08 147.73,79.08 151.58,82.93 158.05,82.93 162.31,87.19 162.31,92.96 163.77,94.42 163.77,97.85 183.07,117.16 220.03,117.16 v1(220.22,117.35)
PEX_TX_N: length 53.1
  TOP w0.127: C750.2 271.51,98.38 arc(271.34,98.27) 271.15,98.23 270.59,98.23 arc(269.99,98.33) 269.45,98.6 247.53,113.95 arc(245.65,114.98) 243.59,115.58 225.12,118.83 224.94,118.83 224.88,118.89 U18.13
PEX_TX_P: length 53.1
  TOP w0.127: U18.12 224.88,118.39 224.94,118.45 225.09,118.45 243.53,115.2 arc(245.5,114.62) 247.31,113.63 269.23,98.28 arc(269.88,97.96) 270.59,97.85 271.15,97.85 arc(271.34,97.81) 271.51,97.7 C749.2
PORESET_N: length 123.1
  TOP w0.127: U1.F13 v2(127.17,101.02) ; U57.C10 v1(47.47,101.88)
  L6SIG w0.102: v1(47.47,101.88) 47.47,103.03 56.07,111.63 56.07,122.36 58.29,124.59 59.69,124.59 60.45,125.35 60.45,128.97 61.53,130.05 66.1,130.05 66.74,129.41 66.74,128.27 67.18,127.83 68.64,127.83 70.23,129.41 71.82,129.41 72.2,129.03 72.2,128.4 72.96,127.63 75.06,127.63 75.69,128.27 75.69,129.03 76.73,130.07 84.67,130.07 85.03,130.43 90.42,130.43 97.28,123.57 101.1,123.57 102.06,122.62 102.93,122.62 105.47,120.08 105.47,115.82 112.71,108.58 112.71,107.38 117.54,102.55 126.17,102.55 126.75,101.97 126.75,101.44 v2(127.17,101.02)
  BOTTOM w0.127: v1(47.47,101.88) 47.52,101.94 R104.2
PROFI_MUX_CFG: length 58.2
  TOP w0.127: U39.1 89.93,60.19 v1(89.41,60.71) ; v1(68.58,75.76) 59.88,75.76 50.48,85.15 50.48,88.87 U57.R13
  BOTTOM w0.127: v1(68.58,75.76) 75.88,75.76 82.04,69.6 82.04,65.41 86.74,60.71 v1(89.41,60.71)
PROFI_PWR_OUT: length 5.8
  TOP w1.016: U38.4 237.62,165.48 R236.2 237.62,165.74 L3.1
PWR_EN_N: length 60.7
  TOP w0.127: J39.1 15.24,17.02 10.16,22.1 10.16,27.81 8.89,29.08 8.89,34.54 7.1,36.33 Q29.3 6.22,37.44 R702.1 6.63,37.87 7.4,38.64 8.04,38.64 9.91,40.51 9.91,68.07 J37.14
PWR_GOOD: length 54
  TOP w0.127: v1(28.83,88.9) 28.83,91.69 33.52,96.39 U57.H1 ; R701.1 C1048.1 R704.2 19.71,57.3 20.07,57.66 v1(20.07,58.55)
  L3SIG w0.102: v1(20.07,58.55) 23.11,58.55 24.64,60.07 24.64,73.66 28.83,77.85 v1(28.83,88.9)
PWR_RST_N: length 93.4
  TOP w0.127: v1(30.16,88.14) 30.16,90.68 34.35,94.87 38.48,94.87 38.97,95.35 U57.J2 ; R700.2 12.16,26.52 U76.2 12.26,27.63 12.95,28.32 17.91,28.32 19.88,30.29 24.32,30.29 29.34,35.31 v1(29.59,35.31)
  L3SIG w0.102: v1(29.59,35.31) 28.45,35.31 26.34,37.41 26.34,38.94 25.78,39.5 25.78,73.15 30.16,77.53 v1(30.16,88.14)
QE_MUX_CFG0: length 110.2
  TOP w0.127: U26.14 110.35,54.11 110.36,54.1 ; U23.14 97.37,52.79 v1(97.28,52.7) ; U57.T13 49.97,85.03 59.69,75.31 v1(69.28,75.31) ; v1(86.61,52.7) 86.7,52.79 U28.14 ; 110.36,54.1 110.36,57.84 109.98,58.22 109.98,59.69 109.69,59.98 U27.14 ; 110.36,54.1 110.36,48.64 109.74,48.02 U24.14 107.32,48.02 v1(107.06,47.75) ; U21.14 84.92,58.89 v1(84.84,58.8) ; U22.14 v1(100.04,46.7)
  L6SIG w0.102: v1(97.28,52.7) 97.28,49.45 v1(100.04,46.7) ; v1(86.61,52.7) 86.11,53.21 86.11,57.53 v1(84.84,58.8)
  BOTTOM w0.127: v1(97.28,52.7) 93.85,52.7 93.09,53.47 88.9,53.47 88.14,52.7 v1(86.61,52.7) ; v1(100.04,46.7) 101.09,47.75 v1(107.06,47.75) ; v1(84.84,58.8) 84.71,58.8 81.6,61.91 81.6,69.47 75.76,75.31 v1(69.28,75.31)
QE_MUX_CFG1: length 123.8
  TOP w0.127: U24.2 v1(104.88,48.67) ; v1(82.17,59.44) 82.07,59.54 U21.2 ; U26.2 104.37,54.76 v1(104.52,54.61) ; U57.R12 49.47,88.88 49.47,84.9 59.5,74.87 v1(68.58,74.87) ; U28.2 83.92,53.44 v1(84.58,54.1) 85.34,54.86 88.9,54.86 90.32,53.44 U23.2 95.28,53.44 v1(95.38,53.34) ; v1(95.89,47.88) 95.35,47.35 U22.2 ; U27.2 104.34,60.63 v1(104.52,60.45)
  L6SIG w0.102: v1(95.89,47.88) 96.32,48.31 96.32,51.51 95.38,52.45 v1(95.38,53.34) ; v1(104.88,48.67) 105.66,49.45 105.66,51.94 105.16,52.45 105.16,53.98 v1(104.52,54.61) ; v1(84.58,54.1) 84.2,54.1 81.92,56.39 81.92,59.18 v1(82.17,59.44)
  BOTTOM w0.127: v1(82.17,59.44) 81.79,59.44 81.03,60.2 81.03,69.47 75.63,74.87 v1(68.58,74.87) ; v1(95.89,47.88) 96.27,47.88 97.05,48.67 v1(104.88,48.67) 106.38,50.16 107.95,50.16 108.97,51.18 108.97,56.52 108.08,57.4 106.68,57.4 104.52,59.56 v1(104.52,60.45)
QED_D0: length 107.5
  TOP w0.127: v1(83.69,58.17) 83.69,56.9 83.08,56.29 U21.7 ; U1.U2 v2(136.77,92.22)
  L3SIG w0.102: v1(93.85,57.4) 93.35,56.9 93.35,49.78 93.92,49.21 95.95,49.21 96.52,48.64 96.52,47.24 97.54,46.23 97.54,44.7 100.84,41.4 104.27,41.4 104.9,42.04 110.62,42.04 113.79,45.21 113.79,55.24 128.59,70.04 128.59,76.64 136.14,84.2 136.14,85.98 136.46,86.3 136.46,88.71 137.16,89.41 137.16,91.57 136.77,91.96 v2(136.77,92.22)
  BOTTOM w0.127: v1(83.69,58.17) 83.95,57.91 93.35,57.91 v1(93.85,57.4)
QED_D1: length 96.5
  TOP w0.127: U1.U1 v2(136.77,91.42) ; v1(94.23,55.24) 93.85,54.86 89.79,54.86 89.02,55.64 U21.9
  L3SIG w0.102: v1(94.23,55.24) 93.73,54.74 93.73,51.05 95.12,49.66 97.54,49.66 97.85,49.34 97.85,44.89 100.97,41.78 104.01,41.78 104.65,42.42 110.36,42.42 113.41,45.47 113.41,55.5 128.27,70.36 128.27,76.84 135.76,84.33 135.76,85.98 136.14,86.36 136.14,88.9 136.77,89.52 v2(136.77,91.42)
QED_D2: length 83.9
  TOP w0.127: v1(95.38,51.69) 94.62,51.69 94.23,51.31 94.23,50.42 94.01,50.19 U23.7 ; U1.T1 v2(135.97,91.42)
  L3SIG w0.102: v2(135.97,91.42) 135.97,89.74 135.51,89.28 135.51,87.63 134.95,87.07 134.95,84.47 127.64,77.15 127.64,70.99 112.65,56.01 112.65,45.85 109.98,43.18 100.84,43.18 98.68,45.34 98.68,49.78 97.79,50.67 96.39,50.67 v1(95.38,51.69)
QED_D3: length 77.9
  TOP w0.127: U1.R1 v2(135.17,91.42) ; U23.9 99.71,49.54 100.08,49.91 v1(100.08,51.05)
  L3SIG w0.102: v2(135.17,91.42) 135.17,89.95 134.87,89.66 134.87,88.01 134.3,87.43 134.3,84.7 127,77.41 127,71.37 111.89,56.26 111.89,46.1 109.73,43.94 101.09,43.94 99.57,45.47 99.57,48.26 100.08,48.77 v1(100.08,51.05)
QED_D4: length 88
  TOP w0.127: U26.7 104.09,51.51 105.54,52.96 v1(105.79,52.96) ; U1.R2 v2(135.17,92.22)
  L3SIG w0.102: v1(105.79,52.96) 104.39,51.56 99.7,51.56 99.19,51.05 99.19,45.34 100.97,43.56 109.85,43.56 112.27,45.97 112.27,56.13 127.32,71.18 127.32,77.28 134.61,84.57 134.61,87.24 135.19,87.82 135.19,89.47 135.55,89.83 135.55,91.84 v2(135.17,92.22)
QED_D5: length 126.1
  TOP w0.127: U26.9 v1(107.32,50.86) ; U1.U4 v2(136.77,93.82)
  L3SIG w0.102: v2(136.77,93.82) 137.16,93.42 137.16,92.81 137.36,92.61 137.74,92.61 137.97,92.38 137.97,89.27 137.09,88.38 137.09,86.16 136.91,85.98 136.91,84.01 129.22,76.33 129.22,69.66 114.55,54.99 114.55,44.7 111.13,41.27 105.41,41.27 104.14,40.01 99.19,40.01 95.25,43.94 93.73,43.94 92.84,44.83 92.84,45.47 90.55,47.75 88.65,47.75 87.5,48.9 87.5,55.88 89.54,57.91 95.12,57.91 98.93,54.1 105.79,54.1 107.32,52.58 v1(107.32,50.86)
QED_D6: length 96
  TOP w0.127: U28.7 v1(84.05,50.19) ; U1.T3 v2(135.97,93.02)
  L3SIG w0.102: v2(135.97,93.02) 135.97,92.79 136.37,92.38 136.37,89.64 135.83,89.09 135.83,86.42 135.38,85.98 135.38,84.39 127.95,76.96 127.95,70.68 113.03,55.75 113.03,45.72 110.11,42.8 104.52,42.8 103.89,42.16 101.22,42.16 98.3,45.09 98.3,49.53 97.66,50.16 v1(95.89,50.16)
  BOTTOM w0.127: v1(95.89,50.16) 95.82,50.1 84.14,50.1 v1(84.05,50.19)
QED_D7: length 92.4
  TOP w0.127: U1.T4 v2(135.97,93.82) ; U28.9 87.97,49.19 v1(88.39,48.77)
  L3SIG w0.102: v1(88.39,48.77) 89.03,48.13 90.81,48.13 93.35,45.59 93.35,44.96 93.85,44.45 95.38,44.45 99.44,40.39 103.89,40.39 105.16,41.66 110.87,41.66 114.17,44.96 114.17,55.12 128.91,69.85 128.91,76.45 136.53,84.07 136.53,85.98 136.8,86.26 136.8,88.54 137.54,89.28 137.54,91.57 137.16,91.95 137.16,92.36 136.91,92.61 136.6,92.61 136.37,92.83 136.37,93.41 v2(135.97,93.82)
QED_D8: length 77.4
  TOP w0.127: U1.R3 v2(135.17,93.02) ; U22.7 94.39,44.09 v1(95.38,45.09)
  L3SIG w0.102: v1(101.6,44.58) 102.62,44.58 102.87,44.32 109.6,44.32 111.51,46.23 111.51,56.39 126.68,71.56 126.68,77.47 133.98,84.77 133.98,87.88 133.86,88.01 133.86,89.28 134.75,90.17 134.75,92.6 v2(135.17,93.02)
  BOTTOM w0.127: v1(101.6,44.58) 97.03,44.58 96.52,45.09 v1(95.38,45.09)
QED_D9: length 72.7
  TOP w0.127: v1(100.58,45.21) 100.58,44.45 99.58,43.44 U22.9 ; U1.R4 v2(135.17,93.82)
  L3SIG w0.102: v1(100.58,45.21) 104.39,45.21 104.9,44.7 109.47,44.7 111.13,46.35 111.13,56.58 126.37,71.82 126.37,77.6 133.67,84.9 133.67,87.69 133.48,87.88 133.48,89.41 134.39,90.32 134.39,93.04 v2(135.17,93.82)
QED_D10: length 66.2
  TOP w0.127: U24.7 v1(105.84,45.42) ; U1.P4 v2(133.57,93.82)
  L3SIG w0.102: v1(105.84,45.42) 109.68,45.42 110.74,46.48 110.74,56.71 126.05,72.01 126.05,77.72 133.36,85.03 133.36,87.49 133.1,87.76 133.1,89.53 133.99,90.42 133.99,93.4 v2(133.57,93.82)
QED_D11: length 60.6
  TOP w0.127: v1(110.24,46.74) 110.24,45.09 109.92,44.77 U24.9 ; U1.P3 v2(133.57,93.02)
  L3SIG w0.102: v2(133.57,93.02) 133.57,93.01 133.57,90.52 132.72,89.66 132.72,87.63 133.05,87.3 133.05,85.17 109.73,61.85 109.73,47.24 v1(110.24,46.74)
QED_D12: length 51.3
  TOP w0.127: U1.N4 v2(132.77,93.82) ; U27.7 104.12,57.38 105.54,58.8 v1(105.54,59.44)
  L3SIG w0.102: v2(132.77,93.82) 133.17,93.41 133.17,91.9 132.05,90.78 132.05,85.06 107.82,60.83 107.82,60.26 107.38,59.82 105.92,59.82 v1(105.54,59.44)
QED_D13: length 44
  TOP w0.127: U27.9 107.35,56.73 v1(107.32,56.77)
  L3SIG w0.102: v1(132.59,87.12) 132.59,85.15 108.14,60.71 108.14,57.59 v1(107.32,56.77)
  BOTTOM w0.127: v1(132.59,87.12) 132.4,87.31 R170.2
QSG1_INT_N: length 252.8
  TOP w0.127: U57.K3 v1(39.47,93.89) ; R331.2 R330.1 198.78,88.67 199.77,89.66 199.77,90.81 199.39,91.19 196.22,91.19 194.69,92.71 v1(194.69,95.25)
  L6SIG w0.102: v1(194.69,95.25) 193.61,95.25 191.07,97.79 188.85,97.79 188.09,98.55 184.02,98.55 183.32,97.85 181.42,97.85 176.28,92.71 176.28,87.93 174.82,86.47 174.82,75.88 164.08,65.15 145.54,65.15 144.91,65.79 144.21,65.79 143.65,66.34 141.4,66.34 140.84,65.79 127.25,65.79 117.35,55.88 117.35,54.29 114.24,51.18 114.24,45.02 111.44,42.23 108.39,42.23 100.14,33.97 88.2,33.97 87.76,34.42 83.95,34.42 80.2,38.16 79.31,38.16 75.5,41.97 75.5,45.02 69.98,50.55 62.55,50.55 57.28,55.82 57.28,67.25 39.69,84.84 38.35,84.84 36.26,86.93 36.26,90.68 v1(39.47,93.89)
QSG1_LED0: length 5.3
  TOP w0.127: R361.1 197.13,81.41 193.36,81.41 192.67,82.1 U51.C3
QSG1_LED1: length 4.2
  TOP w0.127: R363.1 196.96,82.59 U51.B2
QSG1_MDI0_N: length 38.3
  TOP w0.102: 186.31,77.72 186.44,77.85 186.44,78.31 U51.B17
  TOP w0.127: v1(187.33,70.55) 187.71,70.93 187.71,71.63 186.18,73.15 186.18,76.07 186.31,76.2 186.31,77.72 ; T5.3 183.56,46.19 183.86,45.88 183.86,45.47 v1(183.61,45.21)
  L3SIG w0.102: v1(183.61,45.21) 183.87,45.48 183.87,46.59 186.44,49.15 186.44,63.63 187.59,64.78 187.59,70.28 v1(187.33,70.55)
QSG1_MDI0_P: length 38.5
  TOP w0.102: U51.B18 187.5,78.92 187.18,78.59 187.11,78.59 186.72,78.19 186.72,77.73 186.69,77.71 186.69,77.65
  TOP w0.127: v1(184.5,45.21) 184.24,45.47 184.24,45.94 184.55,46.24 T5.2 ; 186.69,77.65 186.69,76.04 186.56,75.91 186.56,73.31 188.09,71.79 188.09,70.67 v1(188.21,70.55)
  L3SIG w0.102: v1(184.5,45.21) 184.23,45.48 184.23,46.44 186.79,49 186.79,63.48 187.95,64.64 187.95,70.28 v1(188.21,70.55)
QSG1_MDI1_N: length 40
  TOP w0.127: v1(180.64,45.22) 180.82,45.4 180.82,45.85 180.59,46.08 T5.6 ; v2(186.97,80.11) 186.72,79.86 U51.C28
  L3SIG w0.102: v1(180.64,45.22) 180.9,45.48 180.9,46.92 182.5,48.51 182.5,50.42 184.02,51.94 184.02,67.43 186.06,69.46 186.06,78.7 187.15,79.79 187.15,79.93 v2(186.97,80.11)
QSG1_MDI1_P: length 40
  TOP w0.127: v2(187.68,80.11) 187.37,79.8 U51.C29 ; T5.5 181.58,46.1 181.33,45.85 181.33,45.41 v1(181.53,45.22)
  L3SIG w0.102: v1(181.53,45.22) 181.26,45.48 181.26,46.77 182.85,48.37 182.85,50.27 184.38,51.8 184.38,67.28 186.41,69.32 186.41,78.55 187.5,79.64 187.5,79.93 v2(187.68,80.11)
QSG1_MDI2_N: length 38.9
  TOP w0.102: 185.51,78.07 185.51,78.08 185.73,78.31 185.74,78.31 U51.B15
  TOP w0.127: T5.9 177.62,46.08 177.85,45.85 177.85,45.4 v1(177.67,45.22) ; 185.51,78.07 185.42,77.98 185.42,76.71 185.17,76.45 185.17,74.68 184.65,74.16 184.65,72.82 v1(184.39,72.57)
  L3SIG w0.102: v1(184.39,72.57) 184.66,72.3 184.66,71.25 180.98,67.56 180.98,51.94 179.45,50.42 179.45,48.39 177.93,46.87 177.93,45.48 v1(177.67,45.22)
QSG1_MDI2_P: length 39
  TOP w0.102: U51.B16 186.02,78.54 186.02,78.19 185.85,78.03 185.85,78.02 185.8,77.96 185.8,77.67
  TOP w0.127: T5.8 178.61,46.1 178.36,45.85 178.36,45.41 v1(178.56,45.22) ; 185.8,77.67 185.8,76.55 185.55,76.3 185.55,74.52 185.03,74 185.03,72.82 v1(185.28,72.57)
  L3SIG w0.102: v1(185.28,72.57) 185.01,72.3 185.01,71.1 181.33,67.42 181.33,51.8 179.81,50.27 179.81,48.24 178.29,46.72 178.29,45.48 v1(178.56,45.22)
QSG1_MDI3_N: length 40.6
  TOP w0.102: 184.91,78.61 184.91,79.01 185.42,79.51 U51.C26
  TOP w0.127: v1(174.7,45.22) 174.88,45.4 174.88,45.85 174.65,46.08 T5.12 ; v1(183.59,75.29) 183.85,75.54 183.85,76.53 184.53,77.22 184.53,78.23 184.91,78.61
  L3SIG w0.102: v1(183.59,75.29) 183.86,75.02 183.86,73.74 178.05,67.94 178.05,52.32 176.4,50.67 176.4,48.39 174.96,46.95 174.96,45.48 v1(174.7,45.22)
QSG1_MDI3_P: length 40.9
  TOP w0.102: 185.18,78.34 185.19,78.35 185.19,78.89 185.54,79.24 185.74,79.24 U51.C27
  TOP w0.127: v1(184.48,75.29) 184.23,75.54 184.23,76.37 184.91,77.06 184.91,78.07 185.18,78.34 ; v1(175.59,45.22) 175.39,45.41 175.39,45.85 175.64,46.1 T5.11
  L3SIG w0.102: v1(184.48,75.29) 184.21,75.02 184.21,73.6 178.41,67.79 178.41,52.18 176.76,50.53 176.76,48.24 175.32,46.8 175.32,45.48 v1(175.59,45.22)
QSG1_MDX0_N: length 11.7
  TOP w0.127: T5.22 183.55,28.29 183.85,27.99 183.85,27.26 182.37,25.78 182.37,22.73 182.75,22.35 182.75,20.04 183.13,19.65 183.13,18.68 J21.A2
QSG1_MDX0_P: length 11.8
  TOP w0.127: T5.23 184.54,28.33 184.23,28.02 184.23,27.1 182.75,25.62 182.75,22.89 183.13,22.51 183.13,20.19 183.39,19.94 184.02,19.94 184.18,20.1 J21.A1
QSG1_MDX1_N: length 12.5
  TOP w0.127: v1(180.63,24) 180.88,24.26 180.88,28.03 180.58,28.34 T5.19
  BOTTOM w0.127: v1(180.63,24) 180.88,23.75 180.88,23.02 180.21,22.35 180.21,20.19 178.48,18.46 J21.A6
QSG1_MDX1_P: length 12.6
  TOP w0.127: v1(181.52,24) 181.26,24.26 181.26,27.97 181.57,28.28 T5.20
  BOTTOM w0.127: v1(181.52,24) 181.26,23.75 181.26,22.86 180.59,22.19 180.59,19.81 180.85,19.56 181.61,19.56 181.86,19.81 181.86,20.77 J21.A3
QSG1_MDX2_N: length 11.5
  TOP w0.127: T5.16 177.61,28.26 178.22,27.65 178.22,24.35 180.21,22.35 180.21,20.48 179.93,20.19 179.32,20.19 179.1,20.42 J21.A5
QSG1_MDX2_P: length 11.6
  TOP w0.127: T5.17 178.6,24.51 180.59,22.51 180.59,20.32 180.23,19.95 180.23,18.6 J21.A4
QSG1_MDX3_N: length 12.6
  TOP w0.127: T5.13 174.64,28.31 174.94,28.01 174.94,27.47 176.66,25.75 176.66,23.91 174.75,22 174.75,20.45 175.51,19.69 175.51,18.68 J21.A8
QSG1_MDX3_P: length 12.5
  TOP w0.127: T5.14 175.63,28.31 175.32,28 175.32,27.62 177.04,25.91 177.04,23.75 175.13,21.84 175.13,20.6 175.67,20.07 176.4,20.07 176.56,20.22 J21.A7
QSG1_REFCLK_N: length 13.1
  TOP w0.102: R497.2 197.97,99.16 197.49,98.68 195.94,98.68 195.88,98.73 195.86,98.73
  TOP w0.127: U58.4 199.09,99.03 198.96,98.9 198.26,98.9 R497.2 ; C443.1 190.75,93.19 190.75,94.74 194.74,98.73 195.86,98.73
QSG1_REFCLK_P: length 13.2
  TOP w0.102: R496.2 197.49,98.4 195.94,98.4 195.88,98.35 195.86,98.35
  TOP w0.127: C442.1 191.49,92.91 191.26,92.91 191.14,93.04 191.14,94.58 194.9,98.35 195.86,98.35 ; U58.5 199.09,98.38 198.96,98.52 198.57,98.52 R496.2
QSG1_RST_N: length 257
  TOP w0.127: U51.B5 193.32,85.49 193.8,85.98 195.83,85.98 196.21,86.36 R336.2 199.29,85.85 200.28,85.85 200.66,86.23 200.66,90.42 199.52,91.57 196.47,91.57 195.33,92.71 v1(195.33,94.74) ; U57.R1 37,89.38 v1(35.75,88.14)
  L6SIG w0.102: v1(195.33,94.74) 193.74,94.74 191.01,97.47 188.72,97.47 187.96,98.23 184.15,98.23 183.45,97.54 181.61,97.54 176.53,92.46 176.53,87.86 175.08,86.42 175.08,75.77 164.21,64.9 145.35,64.9 144.77,65.48 142.7,65.48 142.05,64.83 126.75,64.83 118.26,56.35 118.26,54.45 114.55,50.74 114.55,44.89 111.63,41.97 108.52,41.97 100.27,33.72 87.95,33.72 87.55,34.11 83.74,34.11 80.07,37.78 79.25,37.78 75.12,41.91 75.12,44.89 69.79,50.23 62.42,50.23 56.96,55.69 56.96,67.12 39.62,84.45 38.23,84.45 35.75,86.93 v1(35.75,88.14)
QSG2_INT_N: length 287.5
  TOP w0.127: v1(231.9,94.36) 231.9,90.42 230.53,89.05 R341.1 R342.2 ; U57.L3 v1(39.47,92.89)
  L6SIG w0.102: v1(39.47,92.89) 38.91,92.33 38.42,92.33 36.64,90.55 36.64,87.12 38.54,85.22 39.75,85.22 57.59,67.37 57.59,57.02 63.69,50.93 70.17,50.93 75.88,45.21 75.88,42.1 79.44,38.54 80.26,38.54 84.07,34.73 87.88,34.73 88.39,34.23 99.95,34.23 108.2,42.48 111.25,42.48 113.92,45.15 113.92,51.31 117.08,54.47 117.08,56.06 127.13,66.1 140.72,66.1 141.22,66.61 143.83,66.61 144.34,66.1 144.99,66.1 145.69,65.41 163.96,65.41 174.53,75.98 174.53,86.51 176.02,88 176.02,92.9 181.29,98.17 183.2,98.17 183.9,98.87 188.28,98.87 189.04,98.11 192.91,98.11 193.23,98.42 202.76,98.42 205.17,100.84 213.04,100.84 215.84,98.04 230.63,98.04 231.9,96.77 v1(231.9,94.36)
QSG2_LED0: length 2.5
  TOP w0.127: v2(190.83,83.24) 190.83,82.8 U51.E2
  BOTTOM w0.127: R373.1 191.03,83.44 v2(190.83,83.24)
QSG2_LED1: length 5.8
  TOP w0.127: U51.D1 192.27,81.29 192.53,81.03 195.83,81.03 196.72,80.14 R375.1
QSG2_MDI0_N: length 15.5
  TOP w0.127: U51.D30 185.09,80.47 v2(184.79,80.77) ; T6.3 183.56,70.67 182.25,71.98 182.25,73.53 v1(181.99,73.79)
  L3SIG w0.102: v1(181.99,73.79) 182.26,74.05 182.26,75.83 184.53,78.11 184.53,79.55 185.17,80.18 185.17,80.67 185.06,80.77 v2(184.79,80.77)
QSG2_MDI0_P: length 15.4
  TOP w0.127: U51.D31 186.18,80.21 v2(186.28,80.11) ; T6.2 184.55,68.95 183.94,69.55 183.94,70.83 182.63,72.14 182.63,73.53 v1(182.88,73.79)
  L3SIG w0.102: v2(186.28,80.11) 185.6,80.11 184.89,79.4 184.89,77.96 182.61,75.68 182.61,74.05 v1(182.88,73.79)
QSG2_MDI1_N: length 12.8
  TOP w0.127: U51.C24 184.12,79.25 183.64,78.77 183.64,77.75 180.89,75 180.89,69.26 180.59,68.95 T6.6
QSG2_MDI1_P: length 12.9
  TOP w0.127: T6.5 181.58,68.99 181.27,69.3 181.27,74.85 184.02,77.6 184.02,78.62 184.39,78.98 184.39,78.98 184.77,79.36 U51.C25
QSG2_MDI2_N: length 14.8
  TOP w0.127: U51.C23 183.36,80.02 182.98,79.63 182.34,79.63 178.22,75.51 178.22,69.64 177.62,69.03 T6.9
QSG2_MDI2_P: length 14.9
  TOP w0.127: T6.8 178.61,75.35 182.5,79.25 183.13,79.25 184.1,80.21 U51.D29
QSG2_MDI3_N: length 18.7
  TOP w0.102: 182.14,82.07 182.98,82.07 183.36,81.68 U51.C21
  TOP w0.127: T6.12 174.65,75.21 181.51,82.07 182.14,82.07
QSG2_MDI3_P: length 18.7
  TOP w0.102: 182.26,81.79 182.87,81.79 182.93,81.72 183.01,81.61 183.04,81.53 183.04,81.37 183.36,81.05 U51.C22
  TOP w0.127: T6.11 175.64,68.97 175.03,69.58 175.03,75.05 181.67,81.69 182.16,81.69 182.26,81.79
QSG2_MDX0_N: length 56.1
  TOP w0.127: T6.22 183.55,50.12 183.85,49.81 183.85,49.4 v1(183.6,49.14)
  L6SIG w0.102: v1(183.6,49.14) 183.86,48.88 183.86,48.58 183.9,48.55 183.9,46.99 185.04,45.85 185.04,44.83 184.4,44.2 184.4,29.21 185.17,28.45 185.17,24.13 188.11,21.18 188.11,14 184.51,10.39 177.83,10.39 176.78,11.43 176.78,12.57 176.4,12.95 176.4,14.61 J21.B2
QSG2_MDX0_P: length 56.1
  TOP w0.127: v1(184.49,49.14) 184.23,49.4 184.23,49.87 184.54,50.17 T6.23
  L6SIG w0.102: J21.B1 175.77,12.7 176.15,12.7 176.43,12.43 176.43,11.28 177.68,10.03 184.65,10.03 188.47,13.85 188.47,21.33 185.52,24.28 185.52,28.6 184.76,29.36 184.76,44.05 185.39,44.68 185.39,45.99 184.25,47.14 184.25,48.7 184.22,48.73 184.22,48.88 v1(184.49,49.14)
QSG2_MDX1_N: length 51.6
  TOP w0.127: T6.19 180.58,50.12 180.88,49.81 180.88,49.4 v1(180.63,49.14)
  L6SIG w0.102: v1(180.63,49.14) 180.89,48.88 180.89,47.8 179.6,46.51 179.6,44.81 180.34,44.07 180.34,41.4 179.32,40.39 179.32,31.88 178.59,31.14 178.59,24.36 180.73,22.22 184.54,22.22 185.55,21.21 185.55,18.42 182.75,15.62 182.75,14.22 181.99,13.46 180.31,13.46 180.21,13.56 180.21,15.52 180.31,15.62 181.36,15.62 181.64,15.34 J21.B6
QSG2_MDX1_P: length 51.7
  TOP w0.127: v1(181.52,49.14) 181.26,49.4 181.26,49.87 181.57,50.17 T6.20
  L6SIG w0.102: v1(181.52,49.14) 181.25,48.88 181.25,47.65 179.96,46.36 179.96,44.95 180.7,44.22 180.7,41.25 179.68,40.24 179.68,31.73 178.94,30.99 178.94,24.51 180.87,22.58 184.68,22.58 185.9,21.36 185.9,18.27 183.11,15.47 183.11,14.08 181.82,12.79 181.48,11.81 181.1,11.3 180.34,11.18 179.32,11.43 J21.B3
QSG2_MDX2_N: length 45.8
  TOP w0.127: T6.16 177.61,50.12 177.91,49.81 177.91,49.4 v1(177.66,49.14)
  L6SIG w0.102: v1(177.66,49.14) 177.92,48.88 177.92,48.58 177.93,48.58 177.93,48.13 176.56,46.76 176.56,44.93 177.29,44.2 177.29,24.51 173.74,20.95 173.74,17.4 174.75,16.38 177.17,16.38 177.67,15.88 177.67,13.98 178.57,13.08 179.52,13.08 J21.B5
QSG2_MDX2_P: length 45.7
  TOP w0.127: T6.17 178.6,50.17 178.29,49.87 178.29,49.4 v1(178.55,49.14)
  L6SIG w0.102: v1(178.55,49.14) 178.28,48.88 178.28,48.73 178.28,48.73 178.28,47.99 176.91,46.61 176.91,45.08 177.65,44.34 177.65,24.36 174.09,20.81 174.09,17.55 174.9,16.74 177.32,16.74 178.03,16.03 178.03,14.12 178.71,13.44 179.6,13.44 179.71,13.54 179.71,14.16 J21.B4
QSG2_MDX3_N: length 55.2
  TOP w0.127: v1(174.69,49.14) 174.94,49.4 174.94,49.81 174.64,50.12 T6.13
  L6SIG w0.102: v1(174.69,49.14) 174.88,48.95 174.88,48.26 175.26,47.88 176.4,47.88 176.89,48.36 176.89,49.5 177.42,50.04 181.86,50.04 182.37,49.53 182.37,45.09 181.61,44.32 181.61,24.87 183.24,23.24 184.79,23.24 186.69,21.33 186.69,20.83 186.69,15.24 184.79,13.33 183.75,13.33 183.52,13.56 183.52,14.11 J21.B8
QSG2_MDX3_P: length 55.2
  TOP w0.127: T6.14 175.63,50.17 175.32,49.87 175.32,49.4 v1(175.58,49.14)
  L6SIG w0.102: J21.B7 183.66,12.98 184.93,12.98 187.05,15.09 187.05,20.83 187.05,21.48 184.93,23.6 183.39,23.6 181.97,25.02 181.97,44.18 182.73,44.94 182.73,49.68 182.01,50.39 177.27,50.39 176.53,49.65 176.53,48.51 176.26,48.23 175.41,48.23 175.23,48.41 175.23,48.8 v1(175.58,49.14)
QSG2_REFCLK_N: length 25.4
  TOP w0.102: R709.2 207.8,99.29 208.28,98.81 210.13,98.81 v1(210.44,99.11)
  TOP w0.127: R709.2 207.38,98.9 206.93,98.9 206.8,99.03 U58.21 ; C476.1 222.5,93.19 v1(222.5,93.98)
  L3SIG w0.102: v1(222.5,93.98) 222.5,94.24 221.98,94.77 214.1,94.77 212.45,96.42 209.37,96.42 208.94,96.85 208.84,96.85 208.31,97.38 208.31,98.45 208.69,98.83 210.16,98.83 v1(210.44,99.11)
QSG2_REFCLK_P: length 25.5
  TOP w0.102: v1(210.44,98.22) 210.13,98.53 208.28,98.53 R708.2
  TOP w0.127: v1(223.27,93.98) 222.89,93.6 222.89,93.19 223.01,93.07 C475.1 ; U58.20 206.8,98.38 206.93,98.52 207.32,98.52 R708.2
  L3SIG w0.102: v1(223.27,93.98) 222.12,95.12 214.25,95.12 212.6,96.77 209.52,96.77 209.09,97.21 208.99,97.21 208.66,97.53 208.66,98.3 208.83,98.48 210.19,98.48 v1(210.44,98.22)
QSG2_RST_N: length 297
  TOP w0.127: U52.B5 225.07,85.49 225.55,85.98 227.58,85.98 227.96,86.36 R347.2 230.53,86.33 231.01,85.85 232.54,85.85 232.92,86.23 v1(232.92,94.61) ; U57.M3 v1(39.47,91.89)
  L6SIG w0.102: v1(39.47,91.89) 38.55,91.89 37.02,90.36 37.02,87.25 38.67,85.6 39.81,85.6 57.91,67.5 57.91,57.21 63.82,51.31 70.29,51.31 76.26,45.34 76.26,42.29 78.74,39.81 80.14,39.81 81.09,38.86 81.09,38.16 81.41,37.85 81.41,37.85 84.26,35 88.07,35 88.58,34.48 99.82,34.48 108.08,42.74 111.06,42.74 113.6,45.28 113.6,53 128.04,67.44 140.14,67.44 140.72,66.87 145.92,66.87 147.07,65.72 163.89,65.72 174.28,76.11 174.28,86.58 175.77,88.07 175.77,93.01 181.24,98.49 183.07,98.49 183.77,99.19 188.47,99.19 189.23,98.42 192.79,98.42 193.1,98.74 202.63,98.74 205.04,101.16 213.23,101.16 216.03,98.36 230.7,98.36 232.92,96.14 v1(232.92,94.61)
QSG3_LED0: length 4.5
  TOP w0.127: U51.B4 193.53,84.33 194.06,84.33 194.44,84.71 196.22,84.71 196.72,85.22 R385.1
QSG3_LED1: length 1.4
  TOP w0.102: U51.C6 192.67,84.34 v2(192.66,84.33)
  BOTTOM w0.127: v2(192.66,84.33) 192.79,84.45 R387.1
QSG3_MDI0_N: length 44.7
  TOP w0.127: v1(199.48,45.21) 199.74,45.47 199.74,45.88 199.43,46.19 T8.3 ; U51.C36 192.94,79.94 194.86,79.94 195.8,78.99 198.37,78.99 200.53,76.84 200.53,76.2 200.15,75.82 v1(200.03,75.82)
  L3SIG w0.102: v1(199.48,45.21) 199.75,45.48 199.75,46.76 198.25,48.27 198.25,50.04 199.77,51.56 199.77,71.37 200.29,71.89 200.29,75.55 v1(200.03,75.82)
QSG3_MDI0_P: length 44.8
  TOP w0.127: v1(200.91,75.82) 200.91,76.99 198.53,79.38 195.96,79.38 195.02,80.32 U51.C1 ; T8.2 200.42,46.24 200.12,45.94 200.12,45.47 v1(200.37,45.21)
  L3SIG w0.102: v1(200.91,75.82) 200.65,75.55 200.65,71.75 200.13,71.23 200.13,51.41 198.6,49.89 198.6,48.41 200.1,46.91 200.1,45.48 v1(200.37,45.21)
QSG3_MDI1_N: length 44.6
  TOP w0.102: 192.44,78.71 192.4,78.71 192.14,78.97 192.14,78.99 191.74,79.39 191.74,79.67 191.53,79.88 191.52,79.88 191.41,79.88 191.4,79.89 191.26,79.89 U51.D34
  TOP w0.127: 192.44,78.71 194.18,78.71 194.91,77.98 197.36,77.98 198.5,76.84 198.5,74.55 v1(198.25,74.3) ; v1(196.51,45.22) 196.69,45.4 196.69,45.85 196.46,46.08 T8.6
  L3SIG w0.102: v1(198.25,74.3) 198.51,74.03 198.51,73.16 196.72,71.37 196.72,51.18 195.33,49.78 195.33,48.01 196.78,46.56 196.78,45.48 v1(196.51,45.22)
QSG3_MDI1_P: length 44.5
  TOP w0.102: 192.44,79.09 192.02,79.5 192.02,79.78 U51.D35
  TOP w0.127: T8.5 197.45,46.1 197.2,45.85 197.2,45.41 v1(197.4,45.22) ; 192.44,79.09 194.34,79.09 195.07,78.36 197.52,78.36 198.88,76.99 198.88,74.55 v1(199.14,74.3)
  L3SIG w0.102: v1(199.14,74.3) 198.87,74.03 198.87,73.02 197.08,71.23 197.08,51.03 195.68,49.64 195.68,48.16 197.13,46.71 197.13,45.48 v1(197.4,45.22)
QSG3_MDI2_N: length 43.5
  TOP w0.127: T8.9 193.49,46.08 193.72,45.85 193.72,45.4 v1(193.54,45.22) ; v1(196.6,75.82) 196.85,76.07 196.85,76.55 196.44,76.96 193.42,76.96 192.53,77.85 192.02,77.85 191.14,78.74 191.14,78.87 190.62,79.39 U51.C34
  L3SIG w0.102: v1(196.6,75.82) 196.86,75.55 196.86,74.69 193.8,71.63 193.8,51.69 192.28,50.16 192.28,47.88 193.8,46.36 193.8,45.63 193.81,45.63 193.81,45.48 v1(193.54,45.22)
QSG3_MDI2_P: length 43.4
  TOP w0.127: v1(194.43,45.22) 194.23,45.41 194.23,45.85 194.48,46.1 T8.8 ; U51.C35 191.27,79.37 191.52,79.12 191.52,78.9 192.18,78.23 192.69,78.23 193.58,77.34 196.6,77.34 197.23,76.71 197.23,76.07 v1(197.49,75.82)
  L3SIG w0.102: v1(197.49,75.82) 197.22,75.55 197.22,74.54 194.16,71.48 194.16,51.54 192.63,50.02 192.63,48.03 194.16,46.51 194.16,45.78 194.16,45.77 194.16,45.48 v1(194.43,45.22)
QSG3_MDI3_N: length 41.9
  TOP w0.102: U51.D32 189.13,80.21 189.13,80.21 v2(189.11,80.21)
  TOP w0.127: T8.12 190.52,46.08 190.75,45.85 190.75,45.4 v1(190.57,45.22)
  L3SIG w0.102: v1(190.57,45.22) 190.84,45.48 190.84,46.4 189.51,47.73 189.51,70.51 192.02,73.02 192.02,79.25 190.5,80.77 189.23,80.77 189.11,80.65 v2(189.11,80.21)
QSG3_MDI3_P: length 41.9
  TOP w0.102: U51.D33 190.45,80.21 190.98,80.75 v2(190.98,81.38)
  TOP w0.127: v1(191.46,45.22) 191.26,45.41 191.26,45.85 191.51,46.1 T8.11
  L3SIG w0.102: v2(190.98,81.38) 190.86,81.38 190.75,81.28 190.75,81.02 192.38,79.4 192.38,72.87 189.87,70.36 189.87,47.88 191.19,46.55 191.19,45.48 v1(191.46,45.22)
QSG3_MDX0_N: length 11.8
  TOP w0.127: T8.22 199.42,28.29 199.73,27.99 199.73,27.38 198.12,25.78 198.12,22.73 198.5,22.35 198.5,20.04 198.88,19.65 198.88,18.68 J21.C2
QSG3_MDX0_P: length 11.9
  TOP w0.127: J21.C1 199.93,20.1 199.77,19.94 199.14,19.94 198.88,20.19 198.88,22.51 198.5,22.89 198.5,25.62 200.11,27.23 200.11,28.02 200.41,28.33 T8.23
QSG3_MDX1_N: length 12.5
  TOP w0.127: v1(196.34,24.26) 196.6,24.51 196.6,28.05 196.45,28.19 T8.19
  BOTTOM w0.127: J21.C6 194.23,18.46 195.96,20.19 195.96,22.35 196.6,22.98 196.6,24 v1(196.34,24.26)
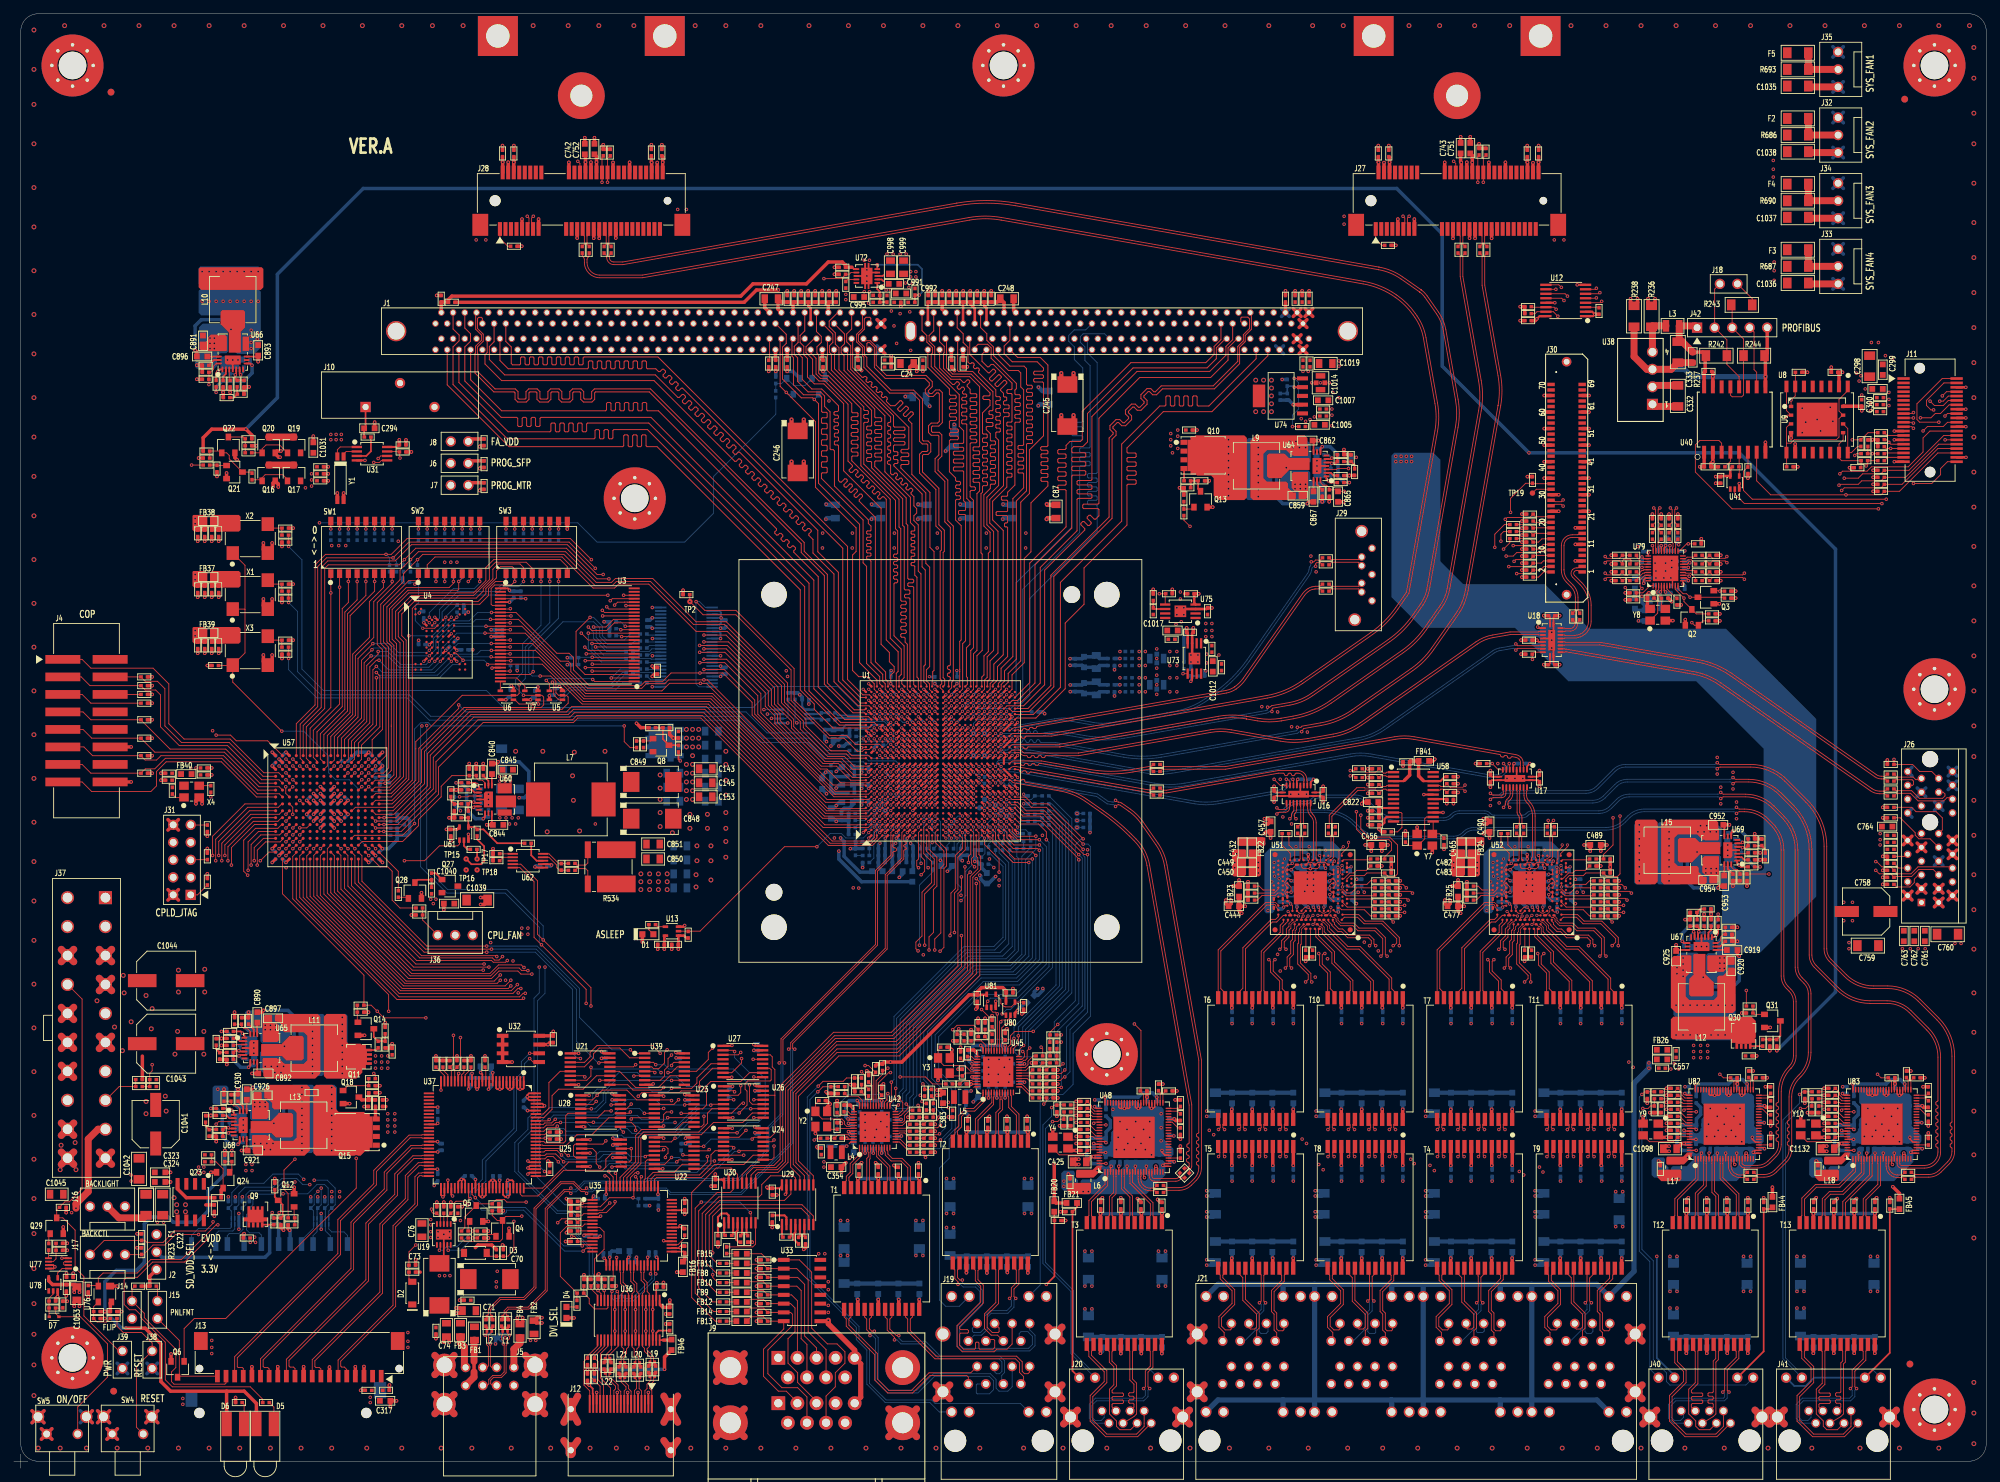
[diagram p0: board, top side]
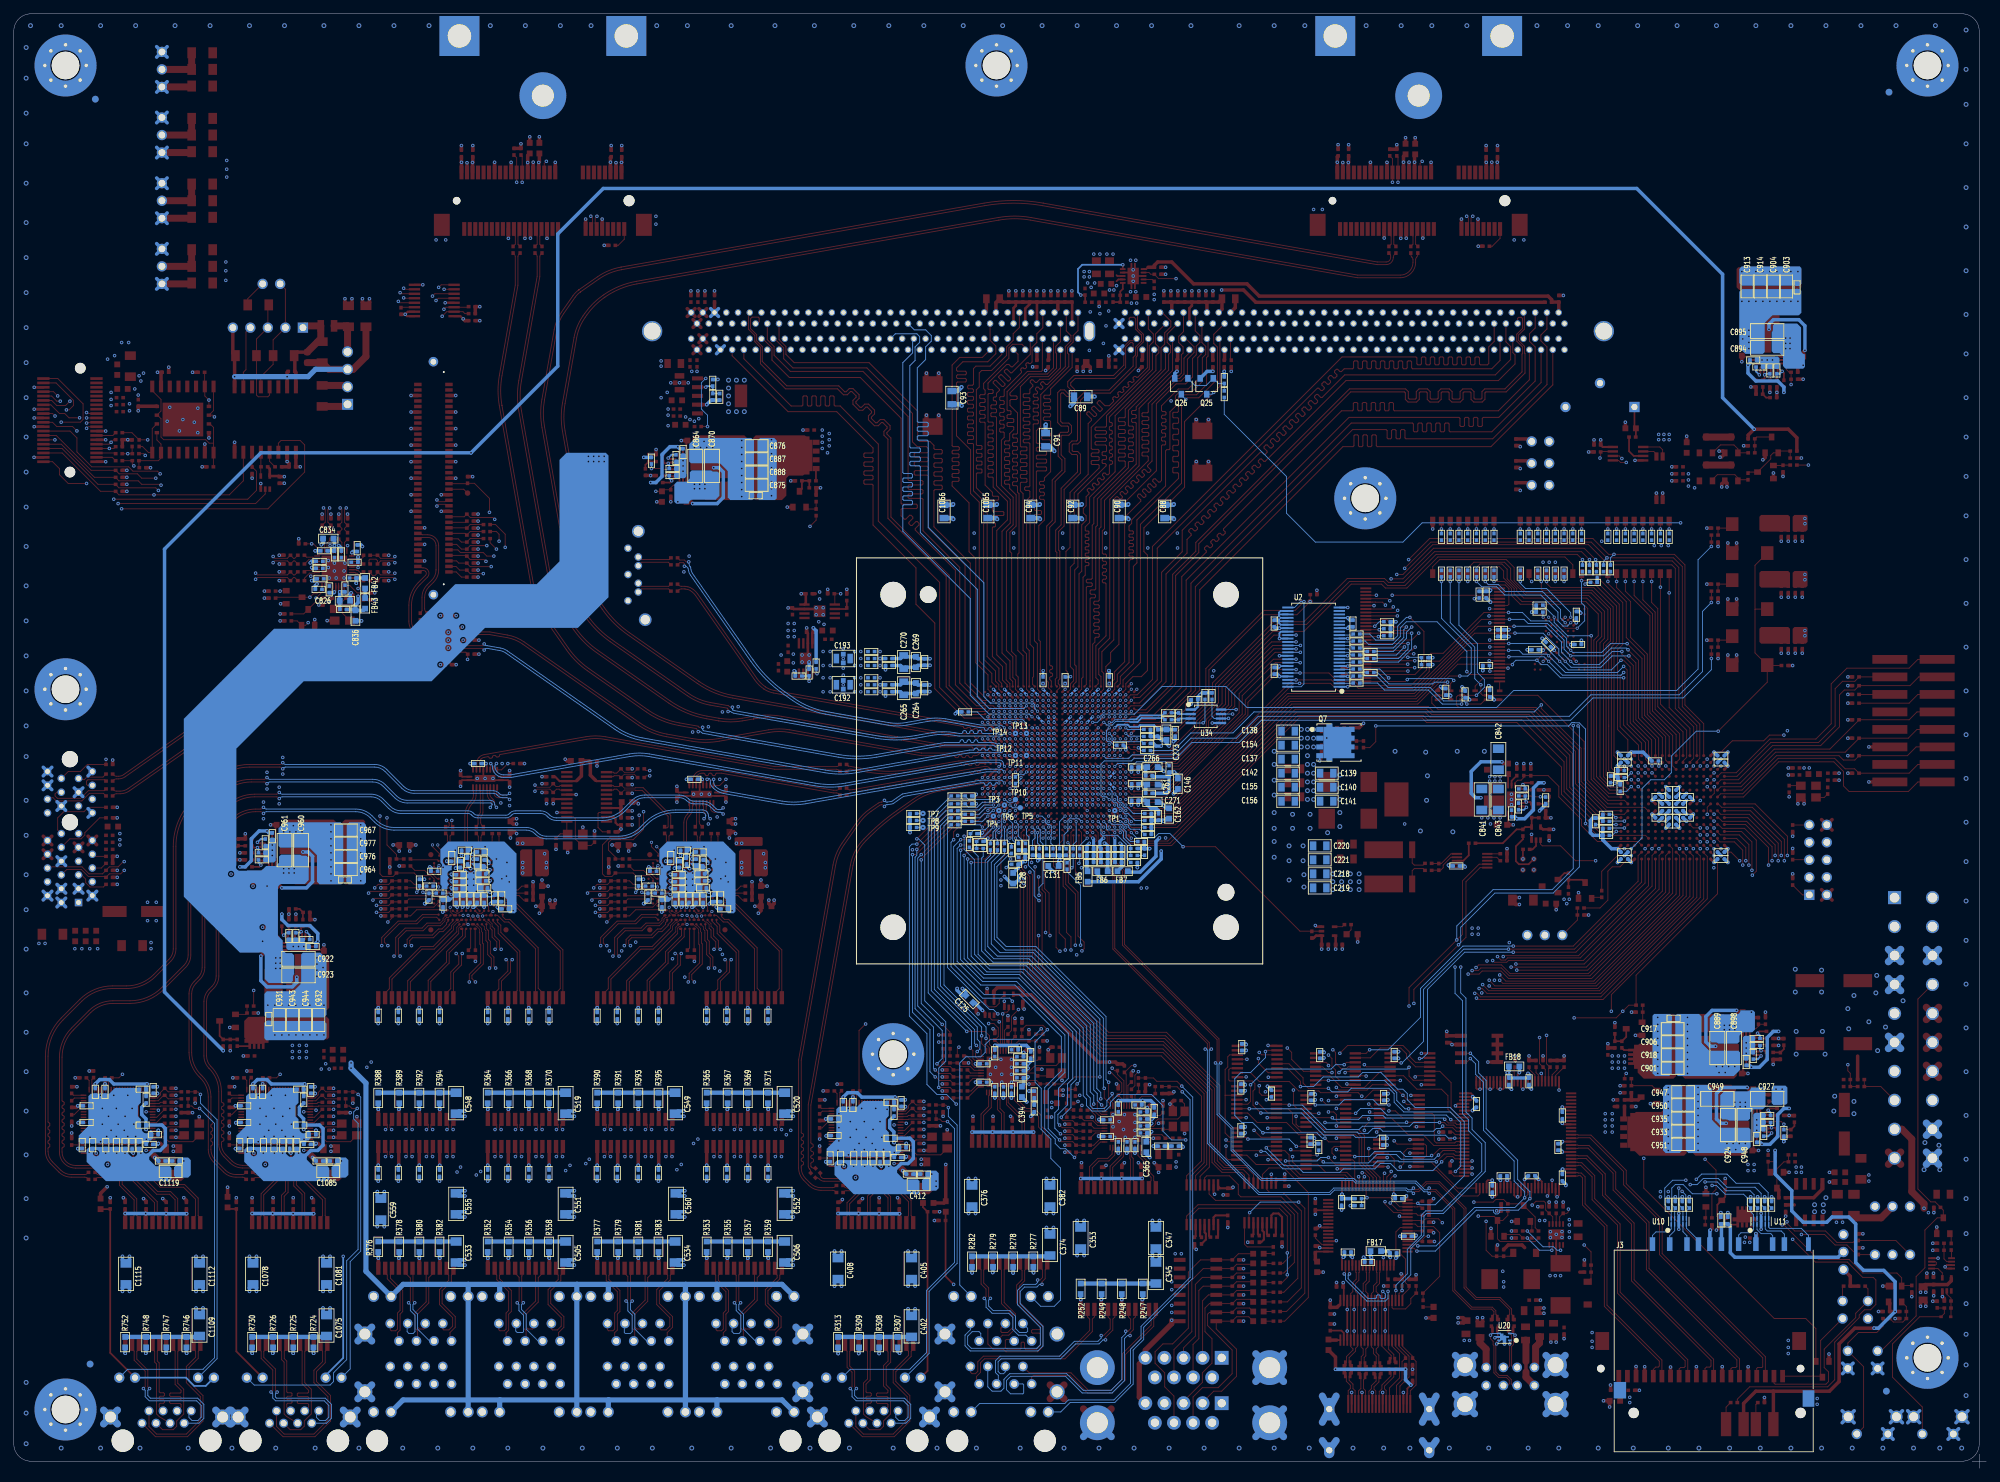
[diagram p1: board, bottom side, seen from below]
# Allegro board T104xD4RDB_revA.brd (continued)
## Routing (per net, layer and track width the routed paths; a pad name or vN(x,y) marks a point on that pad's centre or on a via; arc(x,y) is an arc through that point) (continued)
QSG3_MDX1_P: length 12.5
  TOP w0.127: v1(197.23,24.26) 196.98,24.51 196.98,27.81 197.44,28.28 T8.20
  BOTTOM w0.127: v1(197.23,24.26) 196.98,24 196.98,22.83 196.34,22.19 196.34,19.81 196.6,19.56 197.36,19.56 197.49,19.69 197.49,20.9 J21.C3
QSG3_MDX2_N: length 11.5
  TOP w0.127: J21.C5 194.85,20.42 195.07,20.19 195.68,20.19 195.96,20.48 195.96,22.35 194.09,24.22 194.09,27.65 193.48,28.26 T8.16
QSG3_MDX2_P: length 11.5
  TOP w0.127: J21.C4 195.98,18.6 195.98,19.95 196.34,20.32 196.34,22.51 194.47,24.38 T8.17
QSG3_MDX3_N: length 12.5
  TOP w0.127: J21.C8 191.26,18.68 191.26,19.69 190.5,20.45 190.5,22 192.41,23.91 192.41,25.75 190.82,27.34 190.82,28.01 190.51,28.31 T8.13
QSG3_MDX3_P: length 12.5
  TOP w0.127: J21.C7 192.31,20.22 192.15,20.07 191.42,20.07 190.88,20.6 190.88,21.84 192.79,23.75 192.79,25.91 191.2,27.5 191.2,28 191.5,28.31 T8.14
QSG4_LED0: length 5
  TOP w0.127: R396.1 197.26,83.06 193.17,83.06 192.67,83.56 U51.C5
QSG4_LED1: length 5.9
  TOP w0.127: U51.D5 192.03,83.91 192.82,83.91 193.29,83.44 193.93,83.44 194.69,84.2 R397.1
QSG4_MDI0_N: length 16.7
  TOP w0.102: 190.74,77.86 190.5,78.11 190.5,78.64 189.9,79.24 189.76,79.24 189.43,79.56 U51.C32
  TOP w0.127: T10.3 199.43,70.95 195.07,75.31 193.29,75.31 190.74,77.86
QSG4_MDI0_P: length 16.7
  TOP w0.102: U51.C33 190.78,78.75 190.78,78.37 191.01,78.13
  TOP w0.127: T10.2 200.42,68.95 199.81,69.55 199.81,71.11 195.23,75.69 193.45,75.69 191.01,78.13
QSG4_MDI1_N: length 14.1
  TOP w0.102: 189.75,77.57 189.74,77.58 189.74,78.38 189.51,78.61 189.36,78.61 189.05,78.92 U51.B19
  TOP w0.127: T10.6 196.46,68.95 196.77,69.26 196.77,70.56 189.75,77.57
QSG4_MDI1_P: length 13.9
  TOP w0.102: 190.02,77.84 190.02,78.49 189.64,78.87 U51.B20
  TOP w0.127: T10.5 197.45,68.99 197.15,69.3 197.15,70.71 190.02,77.84
QSG4_MDI2_N: length 12.2
  TOP w0.127: U51.A9 188.8,78.13 188.8,77.11 191.14,74.77 191.14,73.28 193.8,70.62 193.8,69.34 193.49,69.03 T10.9
QSG4_MDI2_P: length 12.2
  TOP w0.127: T10.8 194.48,68.92 194.18,69.22 194.18,70.78 191.52,73.44 191.52,74.93 189.18,77.26 189.18,78.13 U51.A10
QSG4_MDI3_N: length 15.2
  TOP w0.127: v1(189.23,74.68) 189.36,74.55 189.36,72.99 190.52,71.83 T10.12 ; v2(188.39,80.21) 188.02,79.84 U51.C30
  L3SIG w0.102: v2(188.39,80.21) 188.39,79.81 188.19,79.6 187.93,79.6 187.33,78.99 187.33,77.86 188.09,77.09 188.85,77.09 189.29,76.64 189.29,74.74 v1(189.23,74.68)
QSG4_MDI3_P: length 15.1
  TOP w0.127: U51.C31 188.67,79.17 v2(188.39,78.89) ; v1(190.12,74.68) 189.93,74.68 189.74,74.49 189.74,73.15 190.9,71.99 190.9,69.57 191.51,68.97 T10.11
  L3SIG w0.102: v2(188.39,78.89) 188.39,79.15 188.29,79.25 188.08,79.25 187.68,78.85 187.68,78 188.24,77.44 189,77.44 189.65,76.79 189.65,74.89 189.87,74.68 v1(190.12,74.68)
QSG4_MDX0_N: length 56.2
  TOP w0.127: T10.22 199.42,50.12 199.73,49.81 199.73,49.4 v1(199.47,49.14)
  L6SIG w0.102: J21.D2 192.15,14.61 192.15,12.95 192.53,12.57 192.53,11.43 193.58,10.39 200.26,10.39 203.86,14 203.86,21.18 200.92,24.13 200.92,28.45 200.15,29.21 200.15,44.15 201.04,45.04 201.04,45.97 199.74,47.28 199.74,48.88 v1(199.47,49.14)
QSG4_MDX0_P: length 56.3
  TOP w0.127: T10.23 200.41,50.17 200.11,49.87 200.11,49.4 v1(200.36,49.14)
  L6SIG w0.102: J21.D1 191.52,12.7 191.9,12.7 192.18,12.43 192.18,11.28 193.43,10.03 200.4,10.03 204.22,13.85 204.22,21.33 201.27,24.28 201.27,28.6 200.51,29.36 200.51,44 201.4,44.89 201.4,46.12 200.09,47.42 200.09,48.88 v1(200.36,49.14)
QSG4_MDX1_N: length 51.4
  TOP w0.127: v1(196.5,49.14) 196.76,49.4 196.76,49.81 196.45,50.12 T10.19
  L6SIG w0.102: v1(196.5,49.14) 196.77,48.88 196.77,47.29 195.58,46.1 195.58,44.7 196.09,44.19 196.09,41.4 195.07,40.39 195.07,31.75 194.34,31.01 194.34,24.36 196.48,22.22 200.29,22.22 201.3,21.21 201.3,18.42 198.5,15.62 198.5,14.22 197.74,13.46 196.06,13.46 195.96,13.56 195.96,15.52 196.06,15.62 197.11,15.62 197.39,15.34 J21.D6
QSG4_MDX1_P: length 51.6
  TOP w0.127: v1(197.39,49.14) 197.14,49.4 197.14,49.87 197.44,50.17 T10.20
  L6SIG w0.102: v1(197.39,49.14) 197.12,48.88 197.12,47.14 195.94,45.95 195.94,44.85 196.45,44.34 196.45,41.25 195.43,40.24 195.43,31.6 194.69,30.87 194.69,24.51 196.62,22.58 200.43,22.58 201.65,21.36 201.65,18.27 198.86,15.47 198.86,14.08 197.57,12.79 197.23,11.81 196.85,11.3 196.09,11.18 195.07,11.43 J21.D3
QSG4_MDX2_N: length 45.6
  TOP w0.127: T10.16 193.48,50.12 193.79,49.81 193.79,49.4 v1(193.53,49.14)
  L6SIG w0.102: J21.D5 195.27,13.08 194.32,13.08 193.42,13.98 193.42,15.88 192.92,16.38 190.5,16.38 189.49,17.4 189.49,20.95 193.04,24.51 193.04,44.32 192.56,44.81 192.56,46.13 193.8,47.37 193.8,48.88 v1(193.53,49.14)
QSG4_MDX2_P: length 45.5
  TOP w0.127: T10.17 194.47,50.17 194.17,49.87 194.17,49.4 v1(194.42,49.14)
  L6SIG w0.102: J21.D4 195.46,14.16 195.46,13.54 195.35,13.44 194.46,13.44 193.78,14.12 193.78,16.03 193.07,16.74 190.65,16.74 189.84,17.55 189.84,20.8 193.4,24.36 193.4,44.47 192.91,44.95 192.91,45.98 194.15,47.22 194.15,48.88 v1(194.42,49.14)
QSG4_MDX3_N: length 56.4
  TOP w0.127: T10.13 190.51,50.12 190.82,49.81 190.82,49.4 v1(190.56,49.14)
  L6SIG w0.102: J21.D8 199.27,14.11 199.27,13.56 199.5,13.33 200.54,13.33 202.44,15.24 202.44,20.83 202.44,21.33 200.54,23.24 198.99,23.24 197.36,24.87 197.36,44.28 198.37,45.29 198.37,49.78 197.74,50.42 193.42,50.42 192.79,49.78 192.79,48.01 192.48,47.7 191.32,47.7 190.83,48.19 190.83,48.88 v1(190.56,49.14)
QSG4_MDX3_P: length 56.4
  TOP w0.127: v1(191.45,49.14) 191.2,49.4 191.2,49.87 191.5,50.17 T10.14
  L6SIG w0.102: J21.D7 199.41,12.98 200.68,12.98 202.8,15.09 202.8,20.83 202.8,21.48 200.68,23.6 199.14,23.6 197.72,25.02 197.72,44.13 198.73,45.14 198.73,49.93 197.89,50.77 193.27,50.77 192.43,49.93 192.43,48.15 192.33,48.05 191.47,48.05 191.18,48.33 191.18,48.88 v1(191.45,49.14)
QSG5_LED0: length 5.3
  TOP w0.127: R360.1 228.88,81.41 225.11,81.41 224.42,82.1 U52.C3
QSG5_LED1: length 4.2
  TOP w0.127: U52.B2 228.71,82.59 R362.1
QSG5_MDI0_N: length 38.4
  TOP w0.102: U52.B17 218.19,78.31 218.19,77.85 218.06,77.72
  TOP w0.127: v1(215.36,45.21) 215.61,45.47 215.61,45.88 215.31,46.19 T4.3 ; 218.06,77.72 218.06,76.2 217.93,76.07 217.93,73.15 219.58,71.5 219.58,71.05 v1(219.08,70.55)
  L3SIG w0.102: v1(215.36,45.21) 215.62,45.48 215.62,46.59 218.19,49.15 218.19,63.63 219.34,64.78 219.34,70.28 v1(219.08,70.55)
QSG5_MDI0_P: length 38.5
  TOP w0.102: 218.44,77.65 218.44,77.71 218.47,77.73 218.47,78.19 218.86,78.59 218.93,78.59 219.25,78.92 U52.B18
  TOP w0.127: v1(219.96,70.55) 219.96,71.66 218.31,73.31 218.31,75.91 218.44,76.04 218.44,77.65 ; T4.2 216.3,46.24 215.99,45.94 215.99,45.47 v1(216.25,45.21)
  L3SIG w0.102: v1(219.96,70.55) 219.7,70.28 219.7,64.64 218.54,63.48 218.54,49 215.98,46.44 215.98,45.48 v1(216.25,45.21)
QSG5_MDI1_N: length 40
  TOP w0.127: v2(218.72,80.11) 218.47,79.86 U52.C28 ; v1(212.39,45.22) 212.57,45.4 212.57,45.85 212.34,46.08 T4.6
  L3SIG w0.102: v1(212.39,45.22) 212.65,45.48 212.65,46.92 214.25,48.51 214.25,50.42 215.77,51.94 215.77,67.43 217.81,69.46 217.81,78.7 218.9,79.79 218.9,79.93 v2(218.72,80.11)
QSG5_MDI1_P: length 40
  TOP w0.127: T4.5 213.33,46.1 213.08,45.85 213.08,45.41 v1(213.28,45.22) ; U52.C29 219.12,79.8 v2(219.43,80.11)
  L3SIG w0.102: v2(219.43,80.11) 219.25,79.93 219.25,79.64 218.16,78.55 218.16,69.32 216.13,67.28 216.13,51.8 214.6,50.27 214.6,48.37 213.01,46.77 213.01,45.48 v1(213.28,45.22)
QSG5_MDI2_N: length 38.9
  TOP w0.102: U52.B15 217.49,78.31 217.48,78.31 217.26,78.08 217.26,78.07
  TOP w0.127: v1(216.14,72.57) 216.4,72.82 216.4,74.16 216.92,74.68 216.92,76.45 217.17,76.71 217.17,77.98 217.26,78.07 ; v1(209.42,45.22) 209.6,45.4 209.6,45.85 209.37,46.08 T4.9
  L3SIG w0.102: v1(209.42,45.22) 209.68,45.48 209.68,46.87 211.2,48.39 211.2,50.42 212.73,51.94 212.73,67.56 216.41,71.25 216.41,72.3 v1(216.14,72.57)
QSG5_MDI2_P: length 39
  TOP w0.102: U52.B16 217.77,78.54 217.77,78.19 217.6,78.03 217.6,78.02 217.55,77.96 217.55,77.67
  TOP w0.127: v1(217.03,72.57) 216.78,72.82 216.78,74 217.3,74.52 217.3,76.3 217.55,76.55 217.55,77.67 ; T4.8 210.36,46.1 210.11,45.85 210.11,45.41 v1(210.31,45.22)
  L3SIG w0.102: v1(210.31,45.22) 210.04,45.48 210.04,46.72 211.56,48.24 211.56,50.27 213.08,51.8 213.08,67.42 216.76,71.1 216.76,72.3 v1(217.03,72.57)
QSG5_MDI3_N: length 40.6
  TOP w0.102: 216.66,78.61 216.66,79.01 217.17,79.51 U52.C26
  TOP w0.127: v1(206.45,45.22) 206.63,45.4 206.63,45.85 206.4,46.08 T4.12 ; 216.66,78.61 216.28,78.23 216.28,77.22 215.6,76.53 215.6,75.54 v1(215.34,75.29)
  L3SIG w0.102: v1(206.45,45.22) 206.71,45.48 206.71,46.95 208.15,48.39 208.15,50.67 209.8,52.32 209.8,67.94 215.61,73.74 215.61,75.02 v1(215.34,75.29)
QSG5_MDI3_P: length 40.9
  TOP w0.102: 216.93,78.34 216.94,78.35 216.94,78.89 217.29,79.24 217.49,79.24 U52.C27
  TOP w0.127: T4.11 207.39,46.1 207.14,45.85 207.14,45.41 v1(207.34,45.22) ; v1(216.23,75.29) 215.98,75.54 215.98,76.37 216.66,77.06 216.66,78.07 216.93,78.34
  L3SIG w0.102: v1(216.23,75.29) 215.96,75.02 215.96,73.6 210.16,67.79 210.16,52.18 208.51,50.53 208.51,48.24 207.07,46.8 207.07,45.48 v1(207.34,45.22)
QSG5_MDX0_N: length 11.8
  TOP w0.127: T4.22 215.3,28.29 215.6,27.99 215.6,27.51 213.87,25.78 213.87,22.73 214.25,22.35 214.25,20.04 214.63,19.65 214.63,18.68 J21.E2
QSG5_MDX0_P: length 11.9
  TOP w0.127: J21.E1 215.68,20.1 215.52,19.94 214.89,19.94 214.63,20.19 214.63,22.51 214.25,22.89 214.25,25.62 215.98,27.35 215.98,28.02 216.29,28.33 T4.23
QSG5_MDX1_N: length 12.4
  TOP w0.127: v1(212.13,24) 212.36,24.24 212.36,27.88 212.33,27.91 T4.19
  BOTTOM w0.127: v1(212.13,24) 212.38,23.75 212.38,23.02 211.71,22.35 211.71,20.19 209.98,18.46 J21.E6
QSG5_MDX1_P: length 12.4
  TOP w0.127: v1(213.02,24) 212.74,24.28 212.74,27.7 213.32,28.28 T4.20
  BOTTOM w0.127: J21.E3 213.23,20.9 213.23,19.9 213.01,19.69 212.22,19.69 212.09,19.81 212.09,22.19 212.76,22.86 212.76,23.75 v1(213.02,24)
QSG5_MDX2_N: length 11.4
  TOP w0.127: T4.16 209.36,28.26 209.97,27.65 209.97,24.1 211.71,22.35 211.71,20.48 211.43,20.19 210.82,20.19 210.6,20.42 J21.E5
QSG5_MDX2_P: length 11.5
  TOP w0.127: J21.E4 211.73,18.6 211.73,19.95 212.09,20.32 212.09,22.51 210.35,24.26 T4.17
QSG5_MDX3_N: length 12.5
  TOP w0.127: T4.13 206.39,28.31 206.69,28.01 206.69,27.22 208.16,25.75 208.16,23.91 206.25,22 206.25,20.45 207.01,19.69 207.01,18.68 J21.E8
QSG5_MDX3_P: length 12.4
  TOP w0.127: J21.E7 208.06,20.22 207.9,20.07 207.17,20.07 206.63,20.6 206.63,21.84 208.54,23.75 208.54,25.91 207.07,27.37 207.07,28 207.38,28.31 T4.14
QSG6_LED0: length 2.5
  TOP w0.127: U52.E2 222.58,82.8 v2(222.58,83.24)
  BOTTOM w0.127: R372.1 222.78,83.44 v2(222.58,83.24)
QSG6_LED1: length 5.8
  TOP w0.127: R374.1 228.47,80.14 227.58,81.03 224.28,81.03 224.02,81.29 U52.D1
QSG6_MDI0_N: length 15.5
  TOP w0.127: v2(216.54,80.77) 216.84,80.47 U52.D30 ; v1(213.74,73.79) 214,73.53 214,71.98 215.31,70.67 T7.3
  L3SIG w0.102: v1(213.74,73.79) 214.01,74.05 214.01,75.83 216.28,78.11 216.28,79.55 216.92,80.18 216.92,80.67 216.81,80.77 v2(216.54,80.77)
QSG6_MDI0_P: length 15.4
  TOP w0.127: v1(214.63,73.79) 214.38,73.53 214.38,72.14 215.69,70.83 215.69,69.55 216.3,68.95 T7.2 ; v2(218.03,80.11) 217.93,80.21 U52.D31
  L3SIG w0.102: v1(214.63,73.79) 214.36,74.05 214.36,75.68 216.64,77.96 216.64,79.4 217.35,80.11 v2(218.03,80.11)
QSG6_MDI1_N: length 12.8
  TOP w0.127: T7.6 212.34,68.95 212.64,69.26 212.64,75 215.39,77.75 215.39,78.77 215.87,79.25 U52.C24
QSG6_MDI1_P: length 12.9
  TOP w0.127: U52.C25 216.52,79.36 216.14,78.98 216.14,78.98 215.77,78.62 215.77,77.6 213.02,74.85 213.02,69.3 213.33,68.99 T7.5
QSG6_MDI2_N: length 14.8
  TOP w0.127: T7.9 209.37,69.03 209.97,69.64 209.97,75.51 214.09,79.63 214.73,79.63 215.11,80.02 U52.C23
QSG6_MDI2_P: length 14.9
  TOP w0.127: T7.8 210.36,75.35 214.25,79.25 214.88,79.25 215.85,80.21 U52.D29
QSG6_MDI3_N: length 18.7
  TOP w0.102: U52.C21 215.11,81.68 214.73,82.07 213.89,82.07
  TOP w0.127: T7.12 206.4,75.21 213.26,82.07 213.89,82.07
QSG6_MDI3_P: length 18.7
  TOP w0.102: U52.C22 215.11,81.05 214.79,81.37 214.79,81.53 214.76,81.61 214.68,81.72 214.62,81.79 214.01,81.79
  TOP w0.127: 214.01,81.79 213.91,81.69 213.42,81.69 206.78,75.05 206.78,69.58 207.39,68.97 T7.11
QSG6_MDX0_N: length 56.3
  TOP w0.127: v1(215.35,49.14) 215.6,49.4 215.6,49.81 215.3,50.12 T7.22
  L6SIG w0.102: v1(215.35,49.14) 215.61,48.88 215.61,47.15 216.92,45.85 216.92,44.96 215.9,43.95 215.9,29.21 216.67,28.45 216.67,24.13 219.61,21.18 219.61,14 216.01,10.39 209.33,10.39 208.28,11.43 208.28,12.57 207.9,12.95 207.9,14.61 J21.F2
QSG6_MDX0_P: length 56.3
  TOP w0.127: v1(216.24,49.14) 215.98,49.4 215.98,49.87 216.29,50.17 T7.23
  L6SIG w0.102: J21.F1 207.27,12.7 207.65,12.7 207.93,12.43 207.93,11.28 209.18,10.03 216.15,10.03 219.97,13.85 219.97,21.33 217.02,24.28 217.02,28.6 216.26,29.36 216.26,43.8 217.27,44.81 217.27,45.99 215.97,47.3 215.97,48.88 v1(216.24,49.14)
QSG6_MDX1_N: length 51.5
  TOP w0.127: v1(212.38,49.14) 212.63,49.4 212.63,49.81 212.33,50.12 T7.19
  L6SIG w0.102: v1(212.38,49.14) 212.64,48.88 212.64,47.54 211.33,46.23 211.33,44.96 211.84,44.45 211.84,41.4 210.82,40.39 210.82,31.75 210.09,31.01 210.09,24.36 212.23,22.22 216.04,22.22 217.05,21.21 217.05,18.42 214.25,15.62 214.25,14.22 213.49,13.46 211.81,13.46 211.71,13.56 211.71,15.52 211.81,15.62 212.86,15.62 213.14,15.34 J21.F6
QSG6_MDX1_P: length 51.6
  TOP w0.127: v1(213.27,49.14) 213.01,49.4 213.01,49.87 213.32,50.17 T7.20
  L6SIG w0.102: v1(213.27,49.14) 213,48.88 213,47.4 211.68,46.08 211.68,45.11 212.2,44.59 212.2,41.25 211.18,40.24 211.18,31.6 210.44,30.87 210.44,24.51 212.37,22.58 216.18,22.58 217.4,21.36 217.4,18.27 214.61,15.47 214.61,14.08 213.32,12.79 212.98,11.81 212.6,11.3 211.84,11.18 210.82,11.43 J21.F3
QSG6_MDX2_N: length 46
  TOP w0.127: v1(209.41,49.14) 209.66,49.4 209.66,49.81 209.36,50.12 T7.16
  L6SIG w0.102: v1(209.41,49.14) 209.67,48.88 209.67,47.24 208.41,45.97 208.41,44.83 209.3,43.94 209.3,40.64 208.79,40.14 208.79,30.66 208.8,30.66 208.8,30.3 208.79,30.3 208.79,24.51 205.24,20.95 205.24,17.4 206.25,16.38 208.67,16.38 209.17,15.88 209.17,13.98 210.07,13.08 211.02,13.08 J21.F5
QSG6_MDX2_P: length 45.9
  TOP w0.127: v1(210.3,49.14) 210.04,49.4 210.04,49.87 210.35,50.17 T7.17
  L6SIG w0.102: v1(210.3,49.14) 210.03,48.88 210.03,47.09 208.76,45.83 208.76,44.98 209.65,44.09 209.65,40.49 209.15,39.99 209.15,30.81 209.15,30.81 209.15,30.15 209.15,30.15 209.15,24.36 205.59,20.8 205.59,17.55 206.4,16.74 208.82,16.74 209.53,16.03 209.53,14.12 210.21,13.44 211.1,13.44 211.21,13.54 211.21,14.16 J21.F4
QSG6_MDX3_N: length 55.2
  TOP w0.127: T7.13 206.39,50.12 206.69,49.81 206.69,49.4 v1(206.44,49.14)
  L6SIG w0.102: v1(206.44,49.14) 206.7,48.88 206.7,48.31 207.14,47.88 208.15,47.88 208.66,48.39 208.66,49.66 209.04,50.04 213.62,50.04 214,49.66 214,45.16 213.11,44.28 213.11,24.87 214.74,23.24 216.29,23.24 218.19,21.33 218.19,20.83 218.19,15.24 216.29,13.33 215.25,13.33 215.02,13.56 215.02,14.11 J21.F8
QSG6_MDX3_P: length 55.2
  TOP w0.127: v1(207.33,49.14) 207.07,49.4 207.07,49.87 207.38,50.17 T7.14
  L6SIG w0.102: J21.F7 215.16,12.98 216.43,12.98 218.55,15.09 218.55,20.83 218.55,21.48 216.43,23.6 214.89,23.6 213.47,25.02 213.47,44.13 214.35,45.02 214.35,49.81 213.77,50.39 208.89,50.39 208.31,49.81 208.31,48.53 208.01,48.23 207.28,48.23 207.06,48.46 207.06,48.88 v1(207.33,49.14)
QSG7_LED0: length 4.5
  TOP w0.127: U52.B4 225.28,84.33 225.81,84.33 226.19,84.71 227.97,84.71 228.47,85.22 R384.1
QSG7_LED1: length 1.4
  TOP w0.102: U52.C6 224.42,84.34 v2(224.41,84.33)
  BOTTOM w0.127: R386.1 224.54,84.45 v2(224.41,84.33)
QSG7_MDI0_N: length 44.6
  TOP w0.127: v1(231.23,45.21) 231.49,45.47 231.49,45.88 231.18,46.19 T9.3 ; U52.C36 224.69,79.94 226.61,79.94 227.55,78.99 230.12,78.99 232.28,76.84 232.28,76.33 v1(231.78,75.82)
  L3SIG w0.102: v1(231.78,75.82) 232.04,75.55 232.04,71.89 231.52,71.37 231.52,51.56 230,50.04 230,48.27 231.5,46.76 231.5,45.48 v1(231.23,45.21)
QSG7_MDI0_P: length 44.8
  TOP w0.127: U52.C1 226.77,80.32 227.71,79.38 230.28,79.38 232.66,76.99 v1(232.66,75.82) ; T9.2 232.17,46.24 231.87,45.94 231.87,45.47 v1(232.12,45.21)
  L3SIG w0.102: v1(232.66,75.82) 232.4,75.55 232.4,71.75 231.88,71.23 231.88,51.41 230.35,49.89 230.35,48.41 231.85,46.91 231.85,45.48 v1(232.12,45.21)
QSG7_MDI1_N: length 44.6
  TOP w0.102: U52.D34 223.01,79.89 223.15,79.89 223.16,79.88 223.27,79.88 223.28,79.88 223.49,79.67 223.49,79.39 223.89,78.99 223.89,78.97 224.15,78.71 224.19,78.71
  TOP w0.127: T9.6 228.21,46.08 228.44,45.85 228.44,45.4 v1(228.26,45.22) ; 224.19,78.71 225.93,78.71 226.66,77.98 229.11,77.98 230.25,76.84 230.25,74.55 v1(230,74.3)
  L3SIG w0.102: v1(228.26,45.22) 228.53,45.48 228.53,46.56 227.08,48.01 227.08,49.78 228.47,51.18 228.47,71.37 230.26,73.16 230.26,74.03 v1(230,74.3)
QSG7_MDI1_P: length 44.5
  TOP w0.102: 224.19,79.09 223.77,79.5 223.77,79.78 U52.D35
  TOP w0.127: T9.5 229.2,46.1 228.95,45.85 228.95,45.41 v1(229.15,45.22) ; v1(230.89,74.3) 230.63,74.55 230.63,76.99 229.27,78.36 226.82,78.36 226.09,79.09 224.19,79.09
  L3SIG w0.102: v1(229.15,45.22) 228.88,45.48 228.88,46.71 227.43,48.16 227.43,49.64 228.83,51.03 228.83,71.23 230.62,73.02 230.62,74.03 v1(230.89,74.3)
QSG7_MDI2_N: length 43.5
  TOP w0.127: v1(225.29,45.22) 225.47,45.4 225.47,45.85 225.24,46.08 T9.9 ; v1(228.35,75.82) 228.6,76.07 228.6,76.55 228.19,76.96 225.17,76.96 224.28,77.85 223.77,77.85 222.89,78.74 222.89,78.87 222.37,79.39 U52.C34
  L3SIG w0.102: v1(228.35,75.82) 228.61,75.55 228.61,74.69 225.55,71.63 225.55,51.69 224.03,50.16 224.03,47.88 225.55,46.36 225.55,45.63 225.56,45.63 225.56,45.48 v1(225.29,45.22)
QSG7_MDI2_P: length 43.4
  TOP w0.127: v1(226.18,45.22) 225.98,45.41 225.98,45.85 226.23,46.1 T9.8 ; v1(229.24,75.82) 228.98,76.07 228.98,76.71 228.35,77.34 225.33,77.34 224.44,78.23 223.93,78.23 223.27,78.9 223.27,79.12 223.02,79.37 U52.C35
  L3SIG w0.102: v1(226.18,45.22) 225.91,45.48 225.91,45.77 225.91,45.78 225.91,46.51 224.38,48.03 224.38,50.02 225.91,51.54 225.91,71.48 228.97,74.54 228.97,75.55 v1(229.24,75.82)
QSG7_MDI3_N: length 41.9
  TOP w0.102: U52.D32 220.88,80.21 220.88,80.21 v2(220.86,80.21)
  TOP w0.127: v1(222.32,45.22) 222.5,45.4 222.5,45.85 222.27,46.08 T9.12
  L3SIG w0.102: v2(220.86,80.21) 220.86,80.65 220.98,80.77 222.25,80.77 223.77,79.25 223.77,73.02 221.26,70.51 221.26,47.73 222.59,46.4 222.59,45.48 v1(222.32,45.22)
QSG7_MDI3_P: length 41.9
  TOP w0.102: v2(222.73,81.38) 222.73,80.75 222.2,80.21 U52.D33
  TOP w0.127: v1(223.21,45.22) 223.01,45.41 223.01,45.85 223.26,46.1 T9.11
  L3SIG w0.102: v1(223.21,45.22) 222.94,45.48 222.94,46.55 221.62,47.88 221.62,70.36 224.13,72.87 224.13,79.4 222.5,81.02 222.5,81.28 222.61,81.38 v2(222.73,81.38)
QSG7_MDX0_N: length 11.8
  TOP w0.127: J21.G2 230.38,18.68 230.38,19.65 230,20.04 230,22.35 229.62,22.73 229.62,25.78 231.39,27.55 231.39,28.19 231.17,28.42 T9.22
QSG7_MDX0_P: length 12
  TOP w0.127: T9.23 232.16,28.33 231.86,28.02 231.86,27.48 230,25.62 230,22.89 230.38,22.51 230.38,20.19 230.64,19.94 231.27,19.94 231.43,20.1 J21.G1
QSG7_MDX1_N: length 12.4
  TOP w0.127: v1(227.88,24) 228.13,24.26 228.13,28.95 T9.19
  BOTTOM w0.127: v1(227.88,24) 228.13,23.75 228.13,23.02 227.46,22.35 227.46,20.19 225.73,18.46 J21.G6
QSG7_MDX1_P: length 12.5
  TOP w0.127: v1(228.77,24) 228.51,24.26 228.51,27.6 229.19,28.28 T9.20
  BOTTOM w0.127: J21.G3 228.98,20.91 228.98,19.81 228.73,19.56 228.1,19.56 227.84,19.81 227.84,22.19 228.51,22.86 228.51,23.75 v1(228.77,24)
QSG7_MDX2_N: length 11.4
  TOP w0.127: T9.16 225.23,28.26 225.84,27.65 225.84,23.98 227.46,22.35 227.46,20.48 227.18,20.19 226.57,20.19 226.35,20.42 J21.G5
QSG7_MDX2_P: length 11.4
  TOP w0.127: J21.G4 227.48,18.6 227.48,19.95 227.84,20.32 227.84,22.51 226.22,24.13 T9.17
QSG7_MDX3_N: length 12.4
  TOP w0.127: T9.13 222.26,28.31 222.57,28.01 222.57,27.09 223.91,25.75 223.91,23.91 222,22 222,20.45 222.76,19.69 222.76,18.68 J21.G8
QSG7_MDX3_P: length 12.4
  TOP w0.127: T9.14 223.25,28.31 222.95,28 222.95,27.25 224.29,25.91 224.29,23.75 222.38,21.84 222.38,20.6 222.92,20.07 223.65,20.07 223.81,20.22 J21.G7
QSG8_LED0: length 5
  TOP w0.127: R398.1 229.01,83.06 224.92,83.06 224.42,83.56 U52.C5
QSG8_LED1: length 5.9
  TOP w0.127: R399.1 226.44,84.2 225.68,83.44 225.04,83.44 224.57,83.91 223.78,83.91 U52.D5
QSG8_MDI0_N: length 16.7
  TOP w0.102: 222.49,77.86 222.25,78.11 222.25,78.64 221.65,79.24 221.51,79.24 221.18,79.56 U52.C32
  TOP w0.127: T11.3 231.18,70.95 226.82,75.31 225.04,75.31 222.49,77.86
QSG8_MDI0_P: length 16.7
  TOP w0.102: U52.C33 222.53,78.75 222.53,78.37 222.76,78.13
  TOP w0.127: 222.76,78.13 225.2,75.69 226.98,75.69 231.56,71.11 231.56,69.55 232.17,68.95 T11.2
QSG8_MDI1_N: length 14.1
  TOP w0.102: U52.B19 220.8,78.92 221.11,78.61 221.26,78.61 221.49,78.38 221.49,77.58 221.5,77.57
  TOP w0.127: 221.5,77.57 228.52,70.56 228.52,69.26 228.21,68.95 T11.6
QSG8_MDI1_P: length 13.9
  TOP w0.102: 221.77,77.84 221.77,78.49 221.39,78.87 U52.B20
  TOP w0.127: 221.77,77.84 228.9,70.71 228.9,69.3 229.2,68.99 T11.5
QSG8_MDI2_N: length 12.2
  TOP w0.127: U52.A9 220.55,78.13 220.55,77.11 222.89,74.77 222.89,73.28 225.55,70.62 225.55,69.34 225.24,69.03 T11.9
QSG8_MDI2_P: length 12.2
  TOP w0.127: U52.A10 220.93,78.13 220.93,77.26 223.27,74.93 223.27,73.44 225.93,70.78 225.93,69.22 226.23,68.92 T11.8
QSG8_MDI3_N: length 15.2
  TOP w0.127: v2(220.14,80.21) 219.77,79.84 U52.C30 ; T11.12 222.27,71.83 221.11,72.99 221.11,74.55 v1(220.98,74.68)
  L3SIG w0.102: v2(220.14,80.21) 220.14,79.83 219.91,79.6 219.68,79.6 219.08,78.99 219.08,77.86 219.84,77.09 220.6,77.09 221.11,76.58 221.11,74.8 v1(220.98,74.68)
QSG8_MDI3_P: length 15
  TOP w0.127: v2(220.14,78.89) 220.42,79.17 U52.C31 ; T11.11 223.26,68.97 222.65,69.58 222.65,71.99 221.49,73.15 221.49,74.3 v1(221.87,74.68)
  L3SIG w0.102: v2(220.14,78.89) 220.14,79.15 220.04,79.25 219.83,79.25 219.43,78.85 219.43,78 219.99,77.44 220.75,77.44 221.46,76.73 221.46,74.89 221.68,74.68 v1(221.87,74.68)
QSG8_MDX0_N: length 59.9
  TOP w0.127: T11.22 231.17,50.12 231.48,49.81 231.48,49.4 v1(231.22,49.14)
  L6SIG w0.102: J21.H2 223.65,14.61 223.65,12.95 224.03,12.57 224.03,11.43 225.08,10.39 231.24,10.39 238,17.14 238,21.08 236.09,22.99 233.56,22.99 232.42,24.13 232.42,28.45 231.27,29.6 231.27,43.43 232.69,44.86 232.69,45.95 231.49,47.15 231.49,48.88 v1(231.22,49.14)
QSG8_MDX0_P: length 60
  TOP w0.127: T11.23 232.16,50.17 231.86,49.87 231.86,49.4 v1(232.11,49.14)
  L6SIG w0.102: J21.H1 223.02,12.7 223.4,12.7 223.68,12.43 223.68,11.28 224.93,10.03 231.39,10.03 238.35,17 238.35,21.23 236.24,23.34 233.71,23.34 232.77,24.28 232.77,28.6 231.62,29.74 231.62,43.29 233.05,44.71 233.05,46.1 231.84,47.3 231.84,48.88 v1(232.11,49.14)
QSG8_MDX1_N: length 50.6
  TOP w0.127: v1(228.25,49.14) 228.51,49.4 228.51,49.81 228.2,50.12 T11.19
  L6SIG w0.102: v1(228.25,49.14) 228.52,48.88 228.52,47.54 227.08,46.1 227.08,45.21 226.21,44.35 226.21,23.99 227.98,22.22 231.79,22.22 232.54,21.47 232.54,18.92 230,16.39 230,14.22 229.24,13.46 227.56,13.46 227.46,13.56 227.46,15.52 227.56,15.62 228.61,15.62 228.89,15.34 J21.H6
QSG8_MDX1_P: length 50.7
  TOP w0.127: v1(229.14,49.14) 228.89,49.4 228.89,49.87 229.19,50.17 T11.20
  L6SIG w0.102: v1(229.14,49.14) 228.87,48.88 228.87,47.4 227.43,45.95 227.43,45.06 226.57,44.2 226.57,24.14 228.12,22.58 231.93,22.58 232.89,21.62 232.89,18.78 230.36,16.24 230.36,14.08 229.07,12.79 228.73,11.81 228.35,11.3 227.59,11.18 226.57,11.43 J21.H3
QSG8_MDX2_N: length 45.8
  TOP w0.127: T11.16 225.23,50.12 225.54,49.81 225.54,49.4 v1(225.28,49.14)
  L6SIG w0.102: J21.H5 226.77,13.08 225.82,13.08 224.92,13.98 224.92,15.88 224.42,16.38 222,16.38 220.99,17.4 220.99,20.95 224.79,24.75 224.79,44.32 224.28,44.83 224.28,45.97 225.55,47.24 225.55,48.88 v1(225.28,49.14)
QSG8_MDX2_P: length 45.7
  TOP w0.127: v1(226.17,49.14) 225.92,49.4 225.92,49.87 226.22,50.17 T11.17
  L6SIG w0.102: v1(226.17,49.14) 225.9,48.88 225.9,47.09 224.64,45.83 224.64,44.98 225.15,44.47 225.15,24.61 221.34,20.8 221.34,17.55 222.15,16.74 224.57,16.74 225.28,16.03 225.28,14.12 225.96,13.44 226.85,13.44 226.96,13.54 226.96,14.16 J21.H4
QSG8_MDX3_N: length 58.7
  TOP w0.127: T11.13 222.26,50.12 222.57,49.81 222.57,49.4 v1(222.31,49.14)
  L6SIG w0.102: v1(222.31,49.14) 222.58,48.88 222.58,48.31 222.99,47.9 224.18,47.9 224.54,48.26 224.54,49.66 224.81,49.94 229.6,49.94 230,49.54 230,45.21 228.86,44.08 228.86,24.87 230.49,23.24 232.04,23.24 233.81,21.46 235.59,21.46 236.73,20.32 236.73,18.03 232.04,13.33 231,13.33 230.77,13.56 230.77,14.11 J21.H8
QSG8_MDX3_P: length 58.6
  TOP w0.127: v1(223.2,49.14) 222.95,49.4 222.95,49.87 223.25,50.17 T11.14
  L6SIG w0.102: v1(223.2,49.14) 222.93,48.88 222.93,48.46 223.13,48.26 224.03,48.26 224.18,48.41 224.18,49.81 224.66,50.29 229.74,50.29 230.35,49.68 230.35,45.06 229.22,43.93 229.22,25.02 230.64,23.6 232.18,23.6 233.96,21.82 235.73,21.82 237.08,20.47 237.08,17.88 232.18,12.98 230.91,12.98 J21.H7
QSG_SEL_N: length 264
  TOP w0.127: U16.9 183.66,99.04 v1(182.75,99.95) ; R147.2 v1(214.38,102.23) 215.29,101.33 U17.9 ; U57.L4 v1(40.47,92.89)
  L6SIG w0.102: v1(40.47,92.89) 40.01,92.42 40.01,91.63 39.75,91.38 38.61,91.38 37.97,90.74 37.97,86.87 38.93,85.92 39.94,85.92 58.23,67.63 58.23,57.4 64.01,51.63 70.42,51.63 76.64,45.4 76.64,44.2 78.99,41.85 80.45,41.85 81.47,40.83 81.47,38.23 84.39,35.31 88.2,35.31 88.77,34.73 99.7,34.73 107.95,42.99 110.87,42.99 113.28,45.4 113.28,53.09 127.89,67.69 140.27,67.69 140.86,67.09 146.2,67.09 147.26,66.04 163.83,66.04 173.93,76.14 173.93,86.55 175.45,88.07 175.45,93.09 182.31,99.95 v1(182.75,99.95) 183.2,99.5 192.28,99.5 192.6,99.19 194.69,99.19 198.88,103.38 213.23,103.38 v1(214.38,102.23)
QSGMII1_RX_N: length 8.6
  TOP w0.127: U51.D13 188.92,88.29 arc(188.87,88.36) 188.86,88.43 188.86,93.64 arc(188.72,94.33) 188.33,94.91 188.33,94.91 arc(188.09,95.28) 188,95.71 188,96 188.06,96.06 U16.19
QSGMII1_RX_P: length 8.6
  TOP w0.127: U16.18 187.56,96.06 187.62,96 187.62,95.71 arc(187.73,95.13) 188.06,94.64 arc(188.37,94.18) 188.48,93.64 188.48,88.44 arc(188.46,88.36) 188.42,88.29 U51.D14
QSGMII1_TX_N: length 3.6
  TOP w0.127: C434.1 187.09,93.17 arc(187.02,93.27) 187,93.39 187,95.94 187.06,96 U16.17
QSGMII1_TX_P: length 3.6
  TOP w0.127: U16.16 186.56,96.02 186.62,95.96 186.62,93.8 arc(186.56,93.52) 186.41,93.29 C431.1
QSGMII2_RX_N: length 11
  TOP w0.127: U52.D13 220.74,88.45 arc(220.73,88.53) 220.68,88.59 220.67,88.61 arc(220.62,88.68) 220.61,88.75 220.61,94.62 arc(220.37,95.81) 219.69,96.82 arc(219.45,97.18) 219.37,97.61 219.37,98.21 219.43,98.27 U17.19
QSGMII2_RX_P: length 11
  TOP w0.127: U17.18 218.93,98.32 218.99,98.26 218.99,97.61 arc(219.1,97.04) 219.43,96.55 arc(220.02,95.66) 220.23,94.62 220.23,88.75 arc(220.21,88.68) 220.17,88.61 220.15,88.59 arc(220.11,88.53) 220.09,88.45 U52.D14
QSGMII2_TX_N: length 6
  TOP w0.127: C470.1 218.81,93.2 arc(218.72,93.33) 218.69,93.49 218.69,94.39 arc(218.63,94.69) 218.46,94.95 arc(218.39,95.05) 218.37,95.18 218.37,98.23 218.43,98.29 U17.17
QSGMII2_TX_P: length 6
  TOP w0.127: U17.16 217.93,98.3 217.99,98.24 217.99,95.18 arc(218.04,94.91) 218.19,94.68 arc(218.28,94.55) 218.31,94.39 218.31,93.7 arc(218.27,93.47) 218.13,93.26 C464.1
RESET_REQ_N: length 91.6
  TOP w0.127: U57.K15 v1(52.47,93.89) 55.53,93.89 60.39,98.74 60.39,103.44 66.29,109.35 80.39,109.35 81.15,110.11 100.2,110.11 117.35,92.96 123.91,92.96 U1.B3
  BOTTOM w0.127: R106.2 54.6,93.89 v1(52.47,93.89)
RS232_CTS1: length 25.1
  TOP w0.127: FB11.2 106.43,29.59 108.69,29.59 C280.1 U33.2 113.54,28.96 115.19,27.3 115.19,19.81 117.78,17.22 J9.8
RS232_CTS2: length 36.3
  TOP w0.127: J9.18 117.78,10.47 119.13,11.81 119.13,13.84 120.52,15.24 120.52,16.89 119.38,18.03 117.98,18.03 115.7,20.32 115.7,28.45 113.92,30.23 U33.1 C289.1 108.43,31.11 FB15.2
RS232_RTS1: length 21.4
  TOP w0.127: J9.7 115.01,17.96 114.17,18.8 114.17,25.78 113.54,26.42 U33.4 C281.1 109.32,26.44 108.71,27.05 106.43,27.05 FB10.2
RS232_RTS2: length 28.1
  TOP w0.127: FB14.2 106.81,23.24 108.71,23.24 109.32,22.63 C290.1 U33.7 112.65,22.61 112.9,22.35 112.9,20.7 109.35,17.14 109.35,13.72 111.38,11.68 113.67,11.68 115.01,10.34 J9.17
RS232_RXD1: length 16.3
  TOP w0.127: J9.2 113.63,24.29 112.78,25.15 U33.5 C282.1 108.69,25.78 106.55,25.78 FB9.2
RS232_RXD2: length 21.7
  TOP w0.127: J9.12 113.63,9.56 112.01,11.18 110.87,11.18 108.71,13.33 108.71,17.27 111.65,20.21 U33.8 C291.1 109.32,21.36 108.71,21.97 106.93,21.97 FB13.2
RS232_TXD1: length 20.4
  TOP w0.127: FB8.2 108.71,28.32 109.32,27.71 C283.1 U33.3 113.67,27.69 114.68,26.67 114.68,19.18 116.4,17.46 J9.3
RS232_TXD2: length 23.6
  TOP w0.127: FB12.2 106.68,24.51 108.69,24.51 C292.1 U33.6 112.65,23.88 113.28,23.24 113.28,19.81 112.27,18.8 112.27,15.24 113.67,13.84 113.67,12.45 116.4,9.71 J9.13
RTC_INT_N: length 115.1
  TOP w0.127: v1(56.01,146.56) 55.91,146.66 R190.1 55.83,147.52 U31.7 ; U1.E9 v2(126.37,97.82)
  L6SIG w0.102: v2(126.37,97.82) 126.39,97.82 126.75,98.17 126.75,98.46 126.75,98.46 126.75,98.77 126.75,98.78 126.75,99.26 126.75,99.26 126.75,99.57 126.75,99.58 126.75,100.06 126.75,100.06 126.75,100.33 126.79,100.37 126.79,100.37 127.01,100.6 127.32,100.6 127.51,100.78 127.51,100.82 127.55,100.86 127.55,101.17 127.51,101.21 127.51,101.62 127.55,101.66 127.55,106.01 127.32,106.23 126.18,106.23 125.41,107 121.03,107 120.65,107.38 119.57,107.38 116.59,110.36 116.59,111.12 112.65,115.06 112.65,115.76 110.17,118.24 110.17,121.73 96.08,135.83 57.09,135.83 56.01,136.91 v1(56.01,146.56)
  BOTTOM w0.127: R80.1 123.7,95 124.51,95.81 124.92,95.81 125.16,96.05 125.16,96.41 125.38,96.62 125.73,96.62 125.96,96.85 125.96,97.41 v2(126.37,97.82)
SATA_RX_N: length 53.5
  TOP w0.127: C773.1 189.6,128.1 arc(189.43,127.99) 189.23,127.95 188.7,127.95 188.27,127.88 arc(187.97,127.79) 187.7,127.64 187.48,127.49 arc(187.15,127.21) 186.86,126.87 178.29,114.62 arc(177.72,113.94) 177.04,113.37 177.03,113.37 arc(176.43,113.04) 175.77,112.85 145.12,107.44 arc(144.88,107.36) 144.68,107.22 144.48,107.02 U1.AG20
SATA_RX_P: length 53.4
  TOP w0.127: U1.AH20 145.17,107.02 145.21,107.07 145.64,107.15 arc(145.73,107.13) 145.78,107.05 arc(145.83,106.97) 145.92,106.95 146.18,107 arc(146.26,107.05) 146.28,107.14 arc(146.3,107.23) 146.38,107.28 146.64,107.32 arc(146.73,107.3) 146.78,107.23 146.78,107.22 arc(146.83,107.15) 146.92,107.13 147.19,107.17 arc(147.26,107.22) 147.28,107.31 147.28,107.31 arc(147.3,107.4) 147.38,107.45 147.64,107.5 arc(147.73,107.48) 147.78,107.4 arc(147.83,107.32) 147.92,107.3 148.19,107.35 arc(148.26,107.4) 148.28,107.49 arc(148.3,107.58) 148.38,107.63 175.83,112.47 arc(176.58,112.69) 177.26,113.06 177.26,113.06 arc(177.99,113.67) 178.6,114.4 187.17,126.65 arc(187.42,126.94) 187.7,127.18 187.92,127.33 arc(188.12,127.44) 188.33,127.5 188.74,127.57 189.23,127.57 arc(189.43,127.53) 189.6,127.42 C774.1
SATA_TX_N: length 59
  TOP w0.127: C772.1 189.45,131.38 188.93,131.38 188.77,131.23 v1(188.77,130.87) ; U1.AE20 v2(143.17,107.42)
  BOTTOM w0.127: v1(188.77,130.87) 188.64,130.87 arc(188.54,130.85) 188.45,130.79 188.24,130.58 188.19,130.27 arc(188.08,129.91) 187.91,129.59 179.12,117.05 arc(176.96,114.47) 174.38,112.3 173.09,111.4 arc(170.8,110.14) 168.28,109.41 159.22,107.81 arc(157.87,107.69) 156.52,107.81 153.49,108.35 arc(152.22,108.46) 150.96,108.35 145.81,107.44 145.44,107.44 arc(145.3,107.39) 145.25,107.25 arc(145.19,107.12) 145.06,107.06 144.93,107.06 arc(144.79,107.12) 144.74,107.25 arc(144.68,107.39) 144.55,107.44 144.42,107.44 arc(144.29,107.39) 144.23,107.25 arc(144.17,107.12) 144.04,107.06 143.91,107.06 arc(143.78,107.12) 143.72,107.25 arc(143.67,107.39) 143.53,107.44 143.19,107.44 v2(143.17,107.42)
SATA_TX_P: length 59.1
  TOP w0.127: v1(188.15,131.5) 188.51,131.5 188.77,131.76 189.45,131.76 C771.1 ; U1.AD20 v2(142.37,107.42)
  BOTTOM w0.127: v1(188.15,131.5) 188.06,131.02 arc(188.03,130.93) 187.97,130.86 187.89,130.77 187.81,130.33 arc(187.73,130.06) 187.59,129.81 178.81,117.27 arc(176.69,114.74) 174.16,112.62 172.87,111.71 arc(170.65,110.49) 168.21,109.78 159.16,108.19 arc(157.87,108.08) 156.59,108.19 153.56,108.72 arc(152.22,108.84) 150.89,108.72 145.78,107.82 143.05,107.82 arc(142.79,107.77) 142.58,107.63 v2(142.37,107.42)
SD_REFCLK1_N: length 119
  TOP w0.127: U1.AA14 v2(139.97,101.82) ; R519.2 234.51,131.36 234.51,131.76 234.38,131.89 233.5,131.89 233.27,131.67 R520.1 232.83,131.64 231.02,131.64 v1(230.76,131.38)
  L3SIG w0.102: v2(139.97,101.82) 140.38,102.23 143.38,102.23 143.64,101.98 145.41,101.98 145.92,101.47 148.21,101.47 153.8,107.06 182.5,107.06 188.6,113.16 224.28,113.16 232.54,121.41 232.54,131.19 232.08,131.64 231.03,131.64 v1(230.76,131.38)
SD_REFCLK1_P: length 118.9
  TOP w0.127: v1(230.76,132.27) 231.01,132.02 232.83,132.02 R516.1 R518.2 ; U1.AB14 v2(140.77,101.82)
  L3SIG w0.102: v2(140.77,101.82) 140.49,101.82 140.36,101.69 140.36,101.51 140.44,101.44 143.35,101.44 143.54,101.63 145.26,101.63 145.77,101.12 148.36,101.12 153.94,106.71 182.65,106.71 188.74,112.8 224.43,112.8 232.89,121.26 232.89,131.34 232.23,132 231.03,132 v1(230.76,132.27)
SD_REFCLK2_N: length 5.3
  TOP w0.102: C1055.2 196.06,100.97 197.49,100.97 197.97,101.45 R494.2
  TOP w0.127: R494.2 198.59,100.85 198.96,100.85 199.09,100.98 U58.1
SD_REFCLK2_P: length 5.1
  TOP w0.102: C1054.2 196.04,100.69 197.49,100.69 R495.2
  TOP w0.127: U58.2 199.09,100.33 198.96,100.47 198.23,100.47 R495.2
SD_REFCLK_EN_N: length 258.5
  TOP w0.127: U79.21 241.51,133.06 242.57,134.11 v1(242.82,134.11) R508.2 ; v1(240.16,133.86) 240.12,133.82 U79.24 ; v1(236.09,130.68) 236.17,130.76 U79.35 ; U79.13 242.82,129.56 242.95,129.43 v1(242.95,129.41) ; v1(237.62,133.86) 237.72,133.75 U79.30 ; U57.P15 v1(52.47,89.89)
  L3SIG w0.102: v1(242.95,129.41) 243.59,130.05 243.59,133.35 v1(242.82,134.11) 242.44,134.49 240.79,134.49 v1(240.16,133.86) 239.65,134.37 238.12,134.37 v1(237.62,133.86) 236.73,133.86 235.59,132.72 235.59,131.19 v1(236.09,130.68)
  L6SIG w0.102: v1(52.47,89.89) 52.47,89.52 52.96,89.03 52.96,80.52 65.79,67.69 74.23,67.69 74.93,68.39 113.03,68.39 123.5,78.85 147.88,78.85 151.7,82.68 158.16,82.68 162.56,87.08 162.56,92.86 164.08,94.38 164.08,97.79 183.2,116.9 220.6,116.9 221.42,117.73 232.47,117.73 234.7,119.95 234.7,129.79 235.59,130.68 v1(236.09,130.68)
SD_RX2_N: length 23.3
  TOP w0.127: C55.1 166.39,98.51 arc(166.55,98.4) 166.75,98.36 167.14,98.36 183.35,101.22 186.21,101.22 arc(187.12,100.84) 187.5,99.93 187.5,99.72 187.56,99.66 U16.3
SD_RX2_P: length 23.5
  TOP w0.127: C58.1 166.39,97.83 arc(166.55,97.94) 166.75,97.98 167.17,97.98 183.38,100.84 184.07,100.84 arc(184.2,100.79) 184.25,100.66 arc(184.3,100.53) 184.43,100.48 184.58,100.48 arc(184.71,100.53) 184.76,100.66 arc(184.81,100.79) 184.94,100.84 185.09,100.84 arc(185.22,100.79) 185.27,100.66 arc(185.32,100.53) 185.45,100.48 185.6,100.48 arc(185.72,100.53) 185.78,100.66 arc(185.83,100.79) 185.95,100.84 186.21,100.84 arc(186.85,100.57) 187.12,99.93 187.12,99.72 187.06,99.66 U16.4
SD_RX3_N: length 55.1
  TOP w0.127: U17.3 218.93,101.87 218.87,101.93 218.87,102.37 arc(218.78,102.79) 218.54,103.15 arc(218.21,103.39) 217.82,103.52 203.06,106.13 arc(201.65,106.25) 200.24,106.13 175.65,101.79 166.75,101.79 arc(166.55,101.83) 166.39,101.94 C60.1
SD_RX3_P: length 55.1
  TOP w0.127: C59.1 166.39,101.26 arc(166.55,101.37) 166.75,101.41 175.68,101.41 200.31,105.75 arc(201.65,105.87) 202.99,105.75 215.48,103.55 arc(215.57,103.49) 215.6,103.38 215.6,103.38 arc(215.62,103.28) 215.71,103.22 215.93,103.18 arc(216.04,103.2) 216.1,103.29 arc(216.16,103.39) 216.26,103.41 216.48,103.37 arc(216.58,103.31) 216.6,103.21 arc(216.62,103.1) 216.71,103.04 216.93,103 arc(217.04,103.03) 217.1,103.12 arc(217.16,103.21) 217.26,103.23 217.75,103.15 arc(218.04,103.05) 218.27,102.88 218.28,102.88 arc(218.43,102.64) 218.49,102.37 218.49,101.9 218.43,101.84 U17.4
SD_RX4_N: length 82.5
  TOP w0.127: U18.3 221.14,121.39 221.08,121.33 216.97,121.33 214.42,120.88 arc(213.16,120.52) 212.01,119.88 195.23,108.13 arc(193.36,107.11) 191.31,106.51 187.61,105.86 arc(185.7,105.69) 183.78,105.86 176.55,107.13 arc(175.03,107.26) 173.5,107.13 154.38,103.76 146.61,103.76 arc(146.47,103.79) 146.36,103.86 146.24,103.98 arc(146,104.14) 145.72,104.2 144.94,104.2 arc(144.76,104.16) 144.61,104.06 U1.AG16
SD_RX4_P: length 82.5
  TOP w0.127: U18.4 221.14,120.89 221.08,120.95 217.01,120.95 214.49,120.51 arc(213.31,120.16) 212.23,119.57 195.45,107.82 arc(193.5,106.75) 191.37,106.13 187.68,105.48 arc(185.7,105.31) 183.71,105.48 176.49,106.76 arc(175.03,106.88) 173.57,106.76 154.41,103.38 149.68,103.38 arc(149.58,103.34) 149.54,103.24 arc(149.5,103.14) 149.4,103.1 149.17,103.1 arc(149.07,103.14) 149.03,103.24 arc(148.99,103.34) 148.89,103.38 148.66,103.38 arc(148.56,103.34) 148.52,103.24 arc(148.48,103.14) 148.38,103.1 148.16,103.1 arc(148.06,103.14) 148.02,103.24 arc(147.97,103.34) 147.88,103.38 147.65,103.38 arc(147.55,103.34) 147.51,103.24 arc(147.47,103.14) 147.37,103.1 147.14,103.1 arc(147.04,103.14) 147,103.24 arc(146.96,103.34) 146.86,103.38 146.61,103.38 arc(146.33,103.43) 146.09,103.59 145.97,103.71 arc(145.86,103.79) 145.72,103.82 U1.AH16
SD_TX2_N: length 45.7
  TOP w0.127: U1.AE13 v2(143.17,101.02) ; U16.7 185.56,99.87 v1(185.48,99.95)
  BOTTOM w0.127: v2(143.17,101.02) 143.18,101.04 144.92,101.04 171.16,96.41 arc(172.91,96.26) 174.66,96.41 183.09,97.9 arc(183.87,98.16) 184.54,98.65 184.74,98.85 arc(184.94,99.15) 185.01,99.51 185.01,99.76 arc(185.04,99.91) 185.13,100.04 185.14,100.05 arc(185.26,100.1) 185.38,100.05 v1(185.48,99.95)
SD_TX2_P: length 45.7
  TOP w0.127: U1.AD13 v2(142.37,101.02) ; U16.8 185.06,99.61 184.72,99.95 v1(184.53,99.95)
  BOTTOM w0.127: v1(184.53,99.95) 184.53,99.56 arc(184.46,99.21) 184.27,98.93 184.27,98.92 arc(183.7,98.5) 183.02,98.27 174.59,96.78 arc(172.91,96.64) 171.23,96.78 144.96,101.42 143.04,101.42 arc(142.79,101.37) 142.58,101.23 v2(142.37,101.02)
SD_TX3_N: length 78.3
  TOP w0.127: v1(216.85,102.23) 216.93,102.16 U17.7 ; U1.AE14 v2(143.17,101.82)
  BOTTOM w0.127: v1(216.85,102.23) 216.73,102.12 arc(216.66,102) 216.63,101.87 216.63,101.86 arc(216.15,100.7) 214.99,100.22 213.9,100.22 196.69,103.26 arc(195.31,103.38) 193.93,103.26 169.88,99.02 arc(167.62,98.82) 165.36,99.02 146.39,102.36 143.12,102.36 arc(143.03,102.34) 142.95,102.29 arc(142.91,102.23) 142.89,102.16 142.89,101.94 arc(142.93,101.85) 143.02,101.82 v2(143.17,101.82)
SD_TX3_P: length 78.2
  TOP w0.127: U17.8 216.43,101.83 v1(216.03,102.23) ; U1.AD14 v2(142.37,101.82)
  BOTTOM w0.127: v1(216.03,102.23) 216.15,102.12 arc(216.22,102) 216.25,101.87 216.25,101.86 arc(215.88,100.97) 214.99,100.6 213.93,100.6 196.75,103.63 arc(195.31,103.76) 193.86,103.63 169.81,99.39 arc(167.62,99.2) 165.43,99.39 146.42,102.74 143.13,102.74 arc(142.87,102.69) 142.64,102.54 arc(142.53,102.38) 142.49,102.18 142.49,102.02 arc(142.48,101.95) 142.44,101.89 v2(142.37,101.82)
SD_TX4_N: length 85
  TOP w0.127: U1.AE16 v2(143.17,104.22) ; U18.7 221.14,119.39 221.08,119.33 218.06,119.33 v1(217.81,119.59)
  BOTTOM w0.127: v1(217.81,119.59) 217.62,119.4 arc(217.54,119.35) 217.45,119.33 217.33,119.33 215.45,119 arc(214.92,118.85) 214.44,118.58 198.6,107.49 arc(196.85,106.53) 194.93,105.97 168.35,101.29 arc(166.12,101.09) 163.89,101.29 147.41,104.19 146.86,104.19 arc(146.76,104.23) 146.72,104.33 arc(146.68,104.43) 146.58,104.47 146.35,104.47 arc(146.26,104.43) 146.21,104.33 arc(146.17,104.23) 146.08,104.19 145.85,104.19 arc(145.75,104.23) 145.71,104.33 arc(145.67,104.43) 145.57,104.47 145.34,104.47 arc(145.24,104.43) 145.2,104.33 arc(145.16,104.23) 145.06,104.19 144.83,104.19 arc(144.73,104.23) 144.69,104.33 arc(144.65,104.43) 144.55,104.47 144.32,104.47 arc(144.22,104.43) 144.18,104.33 arc(144.14,104.23) 144.04,104.19 143.79,104.19 143.79,104.19 143.19,104.19 v2(143.17,104.22)
SD_TX4_P: length 85
  TOP w0.127: U1.AD16 v2(142.37,104.22) ; v1(217.81,118.7) 218.06,118.95 221.08,118.95 221.14,118.89 U18.8
  BOTTOM w0.127: v2(142.37,104.22) 142.37,104.22 142.63,103.95 arc(142.79,103.85) 142.97,103.81 143.83,103.81 143.99,103.81 147.37,103.81 163.82,100.91 arc(166.12,100.71) 168.42,100.91 195,105.6 arc(197,106.18) 198.82,107.18 214.66,118.27 arc(215.07,118.49) 215.52,118.63 217.37,118.95 217.47,118.95 arc(217.54,118.94) 217.61,118.9 v1(217.81,118.7)
SDHC_CD_N: length 141.9
  TOP w0.127: U1.L5 v2(131.17,94.62)
  L3SIG w0.102: v1(44.1,40.16) 44.58,39.69 44.58,38.35 43.94,37.72 43.94,36.58 48.64,31.88 58.67,31.88 59.31,32.51 69.22,32.51 70.23,33.53 73.99,33.53 75.95,35.48 75.95,37.34 78.49,39.88 78.49,45.34 80.52,47.37 80.52,50.8 80.9,51.18 80.9,56.77 85.09,60.96 86.61,60.96 90.55,64.9 106.93,64.9 129.29,87.25 129.29,90.55 129.95,91.21 129.95,93.97 130.21,94.23 130.78,94.23 v2(131.17,94.62)
  BOTTOM w0.127: v1(44.1,40.16) 43.56,39.62 43.56,38.23 43.08,37.74 R74.1 43.48,37.32 U10.5 U10.4 43.48,34.84 41.73,33.09 J3.10
SDHC_CLK: length 150.7
  L3SIG w0.102: v1(39.75,41.02) 39.88,40.89 39.88,36.07 47.12,28.83 66.8,28.83 67.44,29.46 71.37,29.46 72.52,30.61 74.68,30.61 79.25,35.18 80.9,35.18 84.58,38.86 84.58,42.67 85.39,43.48 85.39,45.92 84.84,46.48 84.84,48.64 85.6,49.4 85.6,55.24 92.84,62.48 108.33,62.48 131.06,85.22 131.06,86.36 131.7,87 131.7,87.63 v1(131.57,87.76)
  BOTTOM w0.127: v1(131.57,87.76) 131.45,87.88 R67.2 ; J3.5 35.9,33.83 35.56,34.16 34.16,34.16 33.74,34.59 U11.1 U11.8 33.74,36.79 34.16,37.21 R72.1 34.19,37.74 34.67,38.23 34.67,39.24 35.18,39.75 37.85,39.75 39.12,41.02 v1(39.75,41.02)
SDHC_CMD: length 141.9
  TOP w0.127: U1.K3 v2(130.37,93.02)
  L3SIG w0.102: v1(44.58,40.64) 43.94,40.64 43.56,40.26 43.56,36.32 48.39,31.5 59.06,31.5 59.69,32.13 69.47,32.13 70.36,33.02 74.04,33.02 76.45,35.43 76.45,37.08 81.03,41.66 81.03,50.55 81.41,50.93 81.41,56.64 84.71,59.94 86.23,59.94 90.81,64.52 107.82,64.52 129.67,86.36 129.67,89.53 130.75,90.61 130.75,91.26 130.75,91.26 130.75,92.37 130.75,92.37 130.75,92.39 130.37,92.77 v2(130.37,93.02)
  BOTTOM w0.127: v1(44.58,40.64) 44.58,38.23 44.09,37.74 R73.1 43.98,37.65 U10.6 U10.3 43.98,34.33 43.4,33.74 J3.2
SDHC_DAT0: length 155.9
  TOP w0.127: v1(131.19,87.12) 130.94,87.38 130.94,88.14 131.19,88.39 131.19,92.24 U1.L2
  L3SIG w0.102: v1(40.77,41.53) 41.15,41.15 41.15,35.56 47.37,29.34 66.55,29.34 67.06,29.84 71.12,29.84 72.39,31.11 74.55,31.11 77.98,34.54 77.98,35.69 79.12,36.83 81.79,36.83 83.57,38.61 83.57,42.29 84.33,43.05 84.33,48.9 85.09,49.66 85.09,55.5 92.58,62.99 108.14,62.99 130.84,85.69 130.84,86.77 v1(131.19,87.12)
  BOTTOM w0.127: v1(40.77,41.53) 38.99,41.53 37.72,40.26 34.23,40.26 33.66,39.69 33.66,38.23 33.17,37.74 R69.1 33.24,37.65 U11.7 U11.2 33.24,34.64 32.64,34.04 31.24,34.04 30.97,33.76 J3.7
SDHC_DAT1: length 157.6
  TOP w0.127: U1.K4 v2(130.37,93.82)
  L3SIG w0.102: v2(130.37,93.82) 130.79,93.4 130.79,92.81 131.01,92.58 131.01,90.5 130.1,89.59 130.1,86.28 107.95,64.13 91.06,64.13 82.04,55.12 82.04,50.67 81.53,50.16 81.53,39.5 80.14,38.1 78.87,38.1 76.84,36.07 76.84,35.18 74.17,32.51 71.76,32.51 70.36,31.11 47.12,31.11 42.55,35.69 42.55,40.83 42.86,41.15 v1(42.93,41.15)
  BOTTOM w0.127: J3.8 29.27,33.96 29.72,34.42 31.75,34.42 32.04,34.71 U11.3 U11.6 32.04,37.65 R68.1 32.16,37.74 32.64,38.23 32.64,39.88 33.53,40.77 37.59,40.77 38.86,42.04 41.02,42.04 41.91,41.15 v1(42.93,41.15)
SDHC_DAT2: length 152.1
  TOP w0.127: U1.L3 v2(131.17,93.02)
  L3SIG w0.102: v2(131.17,93.02) 131.32,92.86 131.32,90.3 130.33,89.31 130.33,86.07 108.01,63.75 91.31,63.75 82.55,54.99 82.55,50.42 82.04,49.91 82.04,39.5 80.26,37.72 78.99,37.72 77.22,35.94 77.22,34.92 74.3,32 71.88,32 70.54,30.66 47.07,30.66 42.04,35.69 42.04,41.08 42.74,41.78 v1(43.56,41.78)
  BOTTOM w0.127: J3.9 48.4,33.77 47.88,34.29 46.1,34.29 45.68,34.71 U10.1 U10.8 45.68,37.32 R70.1 46.13,37.74 46.61,38.23 46.61,40.64 45.47,41.78 v1(43.56,41.78)
SDHC_DAT3: length 155.5
  TOP w0.127: U1.L1 131.57,88.72 132.08,88.2 132.08,86.61 v1(131.57,86.11)
  L3SIG w0.102: v1(131.57,86.11) 131.57,85.03 108.52,61.98 92.96,61.98 86.11,55.12 86.11,49.28 85.34,48.51 85.34,46.86 85.85,46.35 85.85,43.31 85.03,42.48 85.03,38.67 81.15,34.8 79.44,34.8 74.8,30.16 72.71,30.16 71.56,29.02 67.63,29.02 66.99,28.38 46.8,28.38 39.37,35.81 39.37,39.5 v1(39.05,39.81)
  BOTTOM w0.127: v1(39.05,39.81) 42.61,39.81 43.94,41.15 45.09,41.15 45.59,40.64 45.59,38.23 45.11,37.74 R71.1 45.18,37.65 U10.7 U10.2 45.18,34.45 45.9,33.73 J3.1
SDHC_VS: length 91.6
  TOP w0.127: U1.D1 124.51,90.36 118.11,90.36 99.63,108.84 81.79,108.84 81.15,108.2 68.07,108.2 61.6,101.73 61.6,97.79 56.19,92.38 v1(53.65,92.38) U57.M16
  BOTTOM w0.127: R81.1 54.21,91.82 v1(53.65,92.38)
SDHC_WP: length 165.3
  TOP w0.127: U1.M5 v2(131.97,94.62)
  L3SIG w0.102: v1(42.04,41.91) 41.59,41.47 41.59,35.62 47.5,29.72 66.29,29.72 66.8,30.23 70.87,30.23 72.14,31.5 74.42,31.5 77.6,34.67 77.6,35.81 79.12,37.34 80.52,37.34 82.42,39.24 82.42,42.04 83.06,42.67 83.06,52.7 84.07,53.72 84.07,55.98 91.46,63.37 108.08,63.37 130.56,85.85 130.56,89.03 131.57,90.04 131.57,94.22 v2(131.97,94.62)
  BOTTOM w0.127: J3.11 25.78,33.78 26.8,34.8 31.37,34.8 31.54,34.97 U11.4 U11.5 31.54,37.32 R75.1 31.14,37.74 31.62,38.23 31.62,40.01 32.96,41.34 36.26,41.34 37.59,42.67 41.28,42.67 v1(42.04,41.91)
SENSEGND: length 85.7
  TOP w0.305: U1.G20 v2(127.97,106.62)
  L6SIG w0.127: 128.94,92.42 128.94,92.62 129.16,92.84 129.16,92.85 129.16,92.85 129.16,105.18 128.93,105.41 128.91,105.41 128.63,105.41 128.61,105.42 128.6,105.42 128.37,105.65 128.37,106.21 v2(127.97,106.62)
  L6SIG w0.254: v1(67.18,86.8) 67.18,87.19 67.44,87.44 68.45,87.44 70.29,85.6 79.79,85.6 83.47,81.91 101.35,81.91 107.7,88.27 126.68,88.27 127,88.26 128.94,90.2 128.94,92.42
SENSEGNDC: length 88.8
  TOP w0.305: U1.AB10 v2(140.77,98.62)
  L6SIG w0.254: v2(140.77,98.62) 140.77,98.6 140.59,98.42 140.2,98.42 139.7,97.92 139.7,96.01 139.32,95.63 135.38,95.63 134.24,94.49 134.24,92.84 133.54,92.14 132.68,92.14 127.54,87 124.59,87 123.83,86.23 109.31,86.23 109.31,86.23 109,86.23 103.09,80.33 82.74,80.33 78.99,84.07 78.68,84.07 67.37,84.07 65.41,86.04 65.41,86.61 v1(65.6,86.8)
SENSEVDD: length 85.1
  TOP w0.254: v1(67.18,88.39) 67.18,89.76 R551.1
  TOP w0.305: U1.G19 v2(127.97,105.82)
  L6SIG w0.127: 128.55,92.46 128.55,92.68 128.37,92.85 128.37,105.18 128.37,105.18 127.97,105.59 v2(127.97,105.82)
  L6SIG w0.254: v1(67.18,88.39) 67.18,88.07 67.44,87.82 68.64,87.82 70.49,85.98 79.63,85.98 79.95,85.98 83.63,82.3 101.19,82.3 107.54,88.65 107.85,88.65 126.84,88.65 128.55,90.35 128.55,92.46
SENSEVDD_EN_N: length 31.2
  TOP w0.127: v1(56.64,88.14) 59.56,88.14 61.72,90.3 64.37,90.3 64.63,90.55 U61.1 ; v1(40.45,94.87) 40.45,95.9 U57.H3
  L6SIG w0.102: v1(56.64,88.14) 55.12,88.14 53.98,89.28 53.98,90.17 53.15,91 43.62,91 41.97,92.65 41.97,93.09 40.45,94.61 v1(40.45,94.87)
SENSEVDDC: length 98.1
  TOP w0.254: R550.1 67.18,91.25 68.2,90.23 68.2,88.07 67.75,87.63 66.36,87.63 v1(65.6,88.39)
  TOP w0.305: U1.AB9 v2(140.77,97.82)
  L6SIG w0.254: v1(65.6,88.39) 65.02,87.82 65.02,85.85 67.18,83.69 78.84,83.69 82.58,79.95 103.25,79.95 109.16,85.85 123.98,85.85 124.74,86.61 127.76,86.61 132.91,91.76 133.67,91.76 134.62,92.71 134.62,94.36 135.51,95.25 139.45,95.25 140.08,95.89 140.08,97.66 140.23,97.82 v2(140.77,97.82)
SG1_INT_N: length 329.1
  TOP w0.127: U57.P2 v1(38.47,89.89) ; R739.2 v1(239.65,52.07)
  L6SIG w0.102: v1(239.65,52.07) 239.52,52.07 238.51,53.09 238.51,68.33 236.98,69.85 236.98,102.23 235.52,103.7 197.42,103.7 195.83,102.11 195.83,100.97 194.44,99.57 192.6,99.57 191.71,100.46 182.44,100.46 175.13,93.15 175.13,88.14 173.61,86.61 173.61,76.2 163.7,66.29 147.38,66.29 146.35,67.32 140.96,67.32 140.34,67.94 127.83,67.94 127.8,67.92 127.79,67.92 112.97,53.09 112.97,45.47 110.81,43.31 107.89,43.31 100.2,35.62 84.52,35.62 81.84,38.3 81.84,40.97 80.65,42.16 79.18,42.16 76.96,44.39 76.96,45.59 70.61,51.94 64.2,51.94 58.55,57.59 58.55,67.75 40.07,86.23 39.12,86.23 38.48,86.87 38.48,88.2 38.93,88.65 38.93,89.43 v1(38.47,89.89)
SG1_LED0: length 5.2
  TOP w0.127: R733.1 240.77,54.61 R738.2 241.87,54.52 241.87,54.17 242.33,53.71 U82.68
SG1_LED1: length 4.7
  TOP w0.127: U82.69 242.22,53.31 241.43,54.1 R736.2 240.77,53.59 R734.1
SG1_MDI0_N: length 10.6
  TOP w0.127: T12.11 241.55,36.33 241.24,36.63 241.24,38.93 244.22,41.91 244.22,44.23 244.23,44.24 U82.2
SG1_MDI0_P: length 10.6
  TOP w0.127: U82.1 243.83,44.24 243.84,44.23 243.84,42.07 240.86,39.09 240.86,36.65 240.56,36.34 T12.12
SG1_MDI1_N: length 9.9
  TOP w0.127: U82.5 245.43,44.24 245.42,44.23 245.42,40.95 244.21,39.74 244.21,36.71 244.52,36.41 T12.8
SG1_MDI1_P: length 9.9
  TOP w0.127: U82.4 245.03,44.24 245.04,44.23 245.04,41.11 243.83,39.9 243.83,36.7 243.53,36.39 T12.9
SG1_MDI2_N: length 9.6
  TOP w0.127: U82.8 246.63,44.24 246.62,44.23 246.62,40.18 247.18,39.61 247.18,36.66 247.49,36.36 T12.5
SG1_MDI2_P: length 9.6
  TOP w0.127: T12.6 246.5,36.31 246.8,36.62 246.8,39.45 246.24,40.02 246.24,44.23 246.23,44.24 U82.7
SG1_MDI3_N: length 10.4
  TOP w0.127: U82.11 247.83,44.24 247.82,44.23 247.82,42.15 250.15,39.82 250.15,36.61 250.46,36.31 T12.2
SG1_MDI3_P: length 10.4
  TOP w0.127: U82.10 247.43,44.24 247.44,44.23 247.44,41.99 249.77,39.66 249.77,36.67 249.47,36.36 T12.3
SG1_MDX0_N: length 23.5
  TOP w0.127: T12.14 241.54,17.26 241.23,16.95 241.23,15.46 242.5,14.2 242.5,12.42 240.46,10.38 240.46,6.98 242.5,4.95 246.81,4.95 247.91,6.05 247.91,6.54 J40.2
SG1_MDX0_P: length 23.2
  TOP w0.127: T12.13 240.55,17.26 240.85,16.96 240.85,15.31 242.11,14.04 242.11,12.57 240.08,10.54 240.08,6.83 242.34,4.57 246.97,4.57 J40.1
SG1_MDX1_N: length 16.4
  TOP w0.127: T12.17 244.51,17.31 244.2,17 244.2,12.25 243.26,11.3 243.26,11.04 243.38,10.91 244.78,10.91 244.91,10.78 244.91,10.53 244.78,10.4 243.38,10.4 243.26,10.27 243.26,10.02 243.38,9.89 244.78,9.89 244.91,9.77 244.91,9.51 244.78,9.39 243.38,9.39 243.26,9.26 243.26,8.89 J40.6
SG1_MDX1_P: length 16.4
  TOP w0.127: T12.16 243.52,17.21 243.82,16.91 243.82,12.41 242.88,11.46 242.88,7.87 243.89,6.86 243.89,6.1 244.4,5.59 245.94,5.59 J40.3
SG1_MDX2_N: length 12.8
  TOP w0.127: J40.5 246.43,7.49 246.81,7.87 246.81,15.39 247.17,15.75 247.17,16.92 247.48,17.23 T12.20
SG1_MDX2_P: length 12.6
  TOP w0.127: T12.19 246.49,17.29 246.79,16.99 246.79,15.91 246.43,15.55 246.43,11.08 246.31,10.95 245.8,10.95 245.67,10.82 245.67,10.57 245.8,10.44 246.31,10.44 246.43,10.31 246.43,10.06 246.31,9.93 245.8,9.93 245.67,9.81 245.67,9.55 245.8,9.43 246.31,9.43 246.43,9.3 246.43,8.88 J40.4
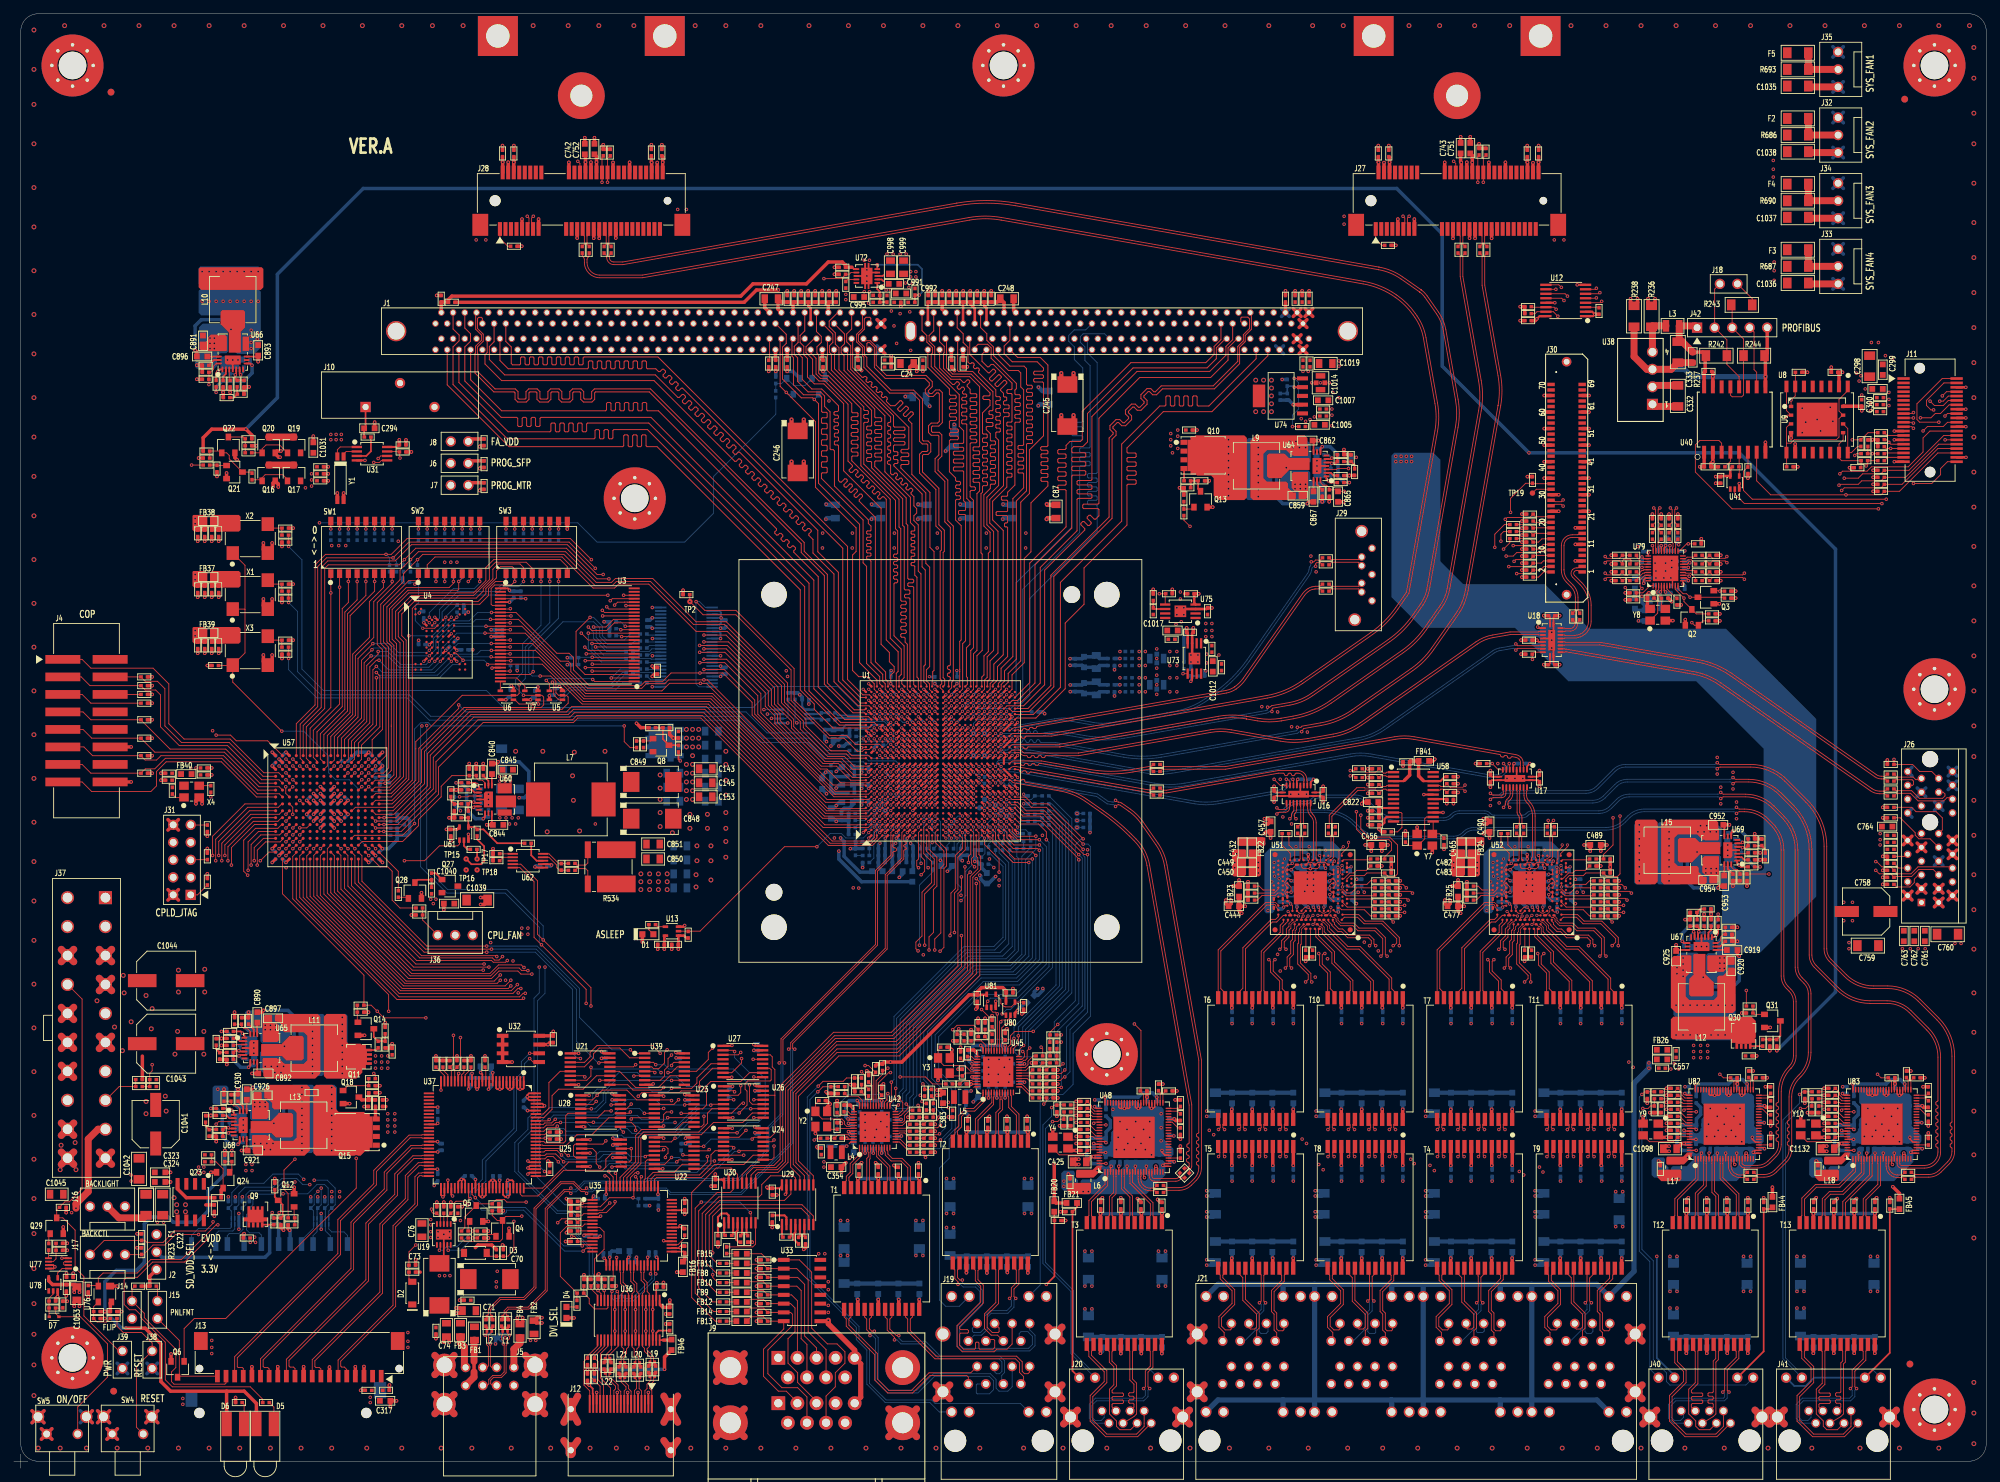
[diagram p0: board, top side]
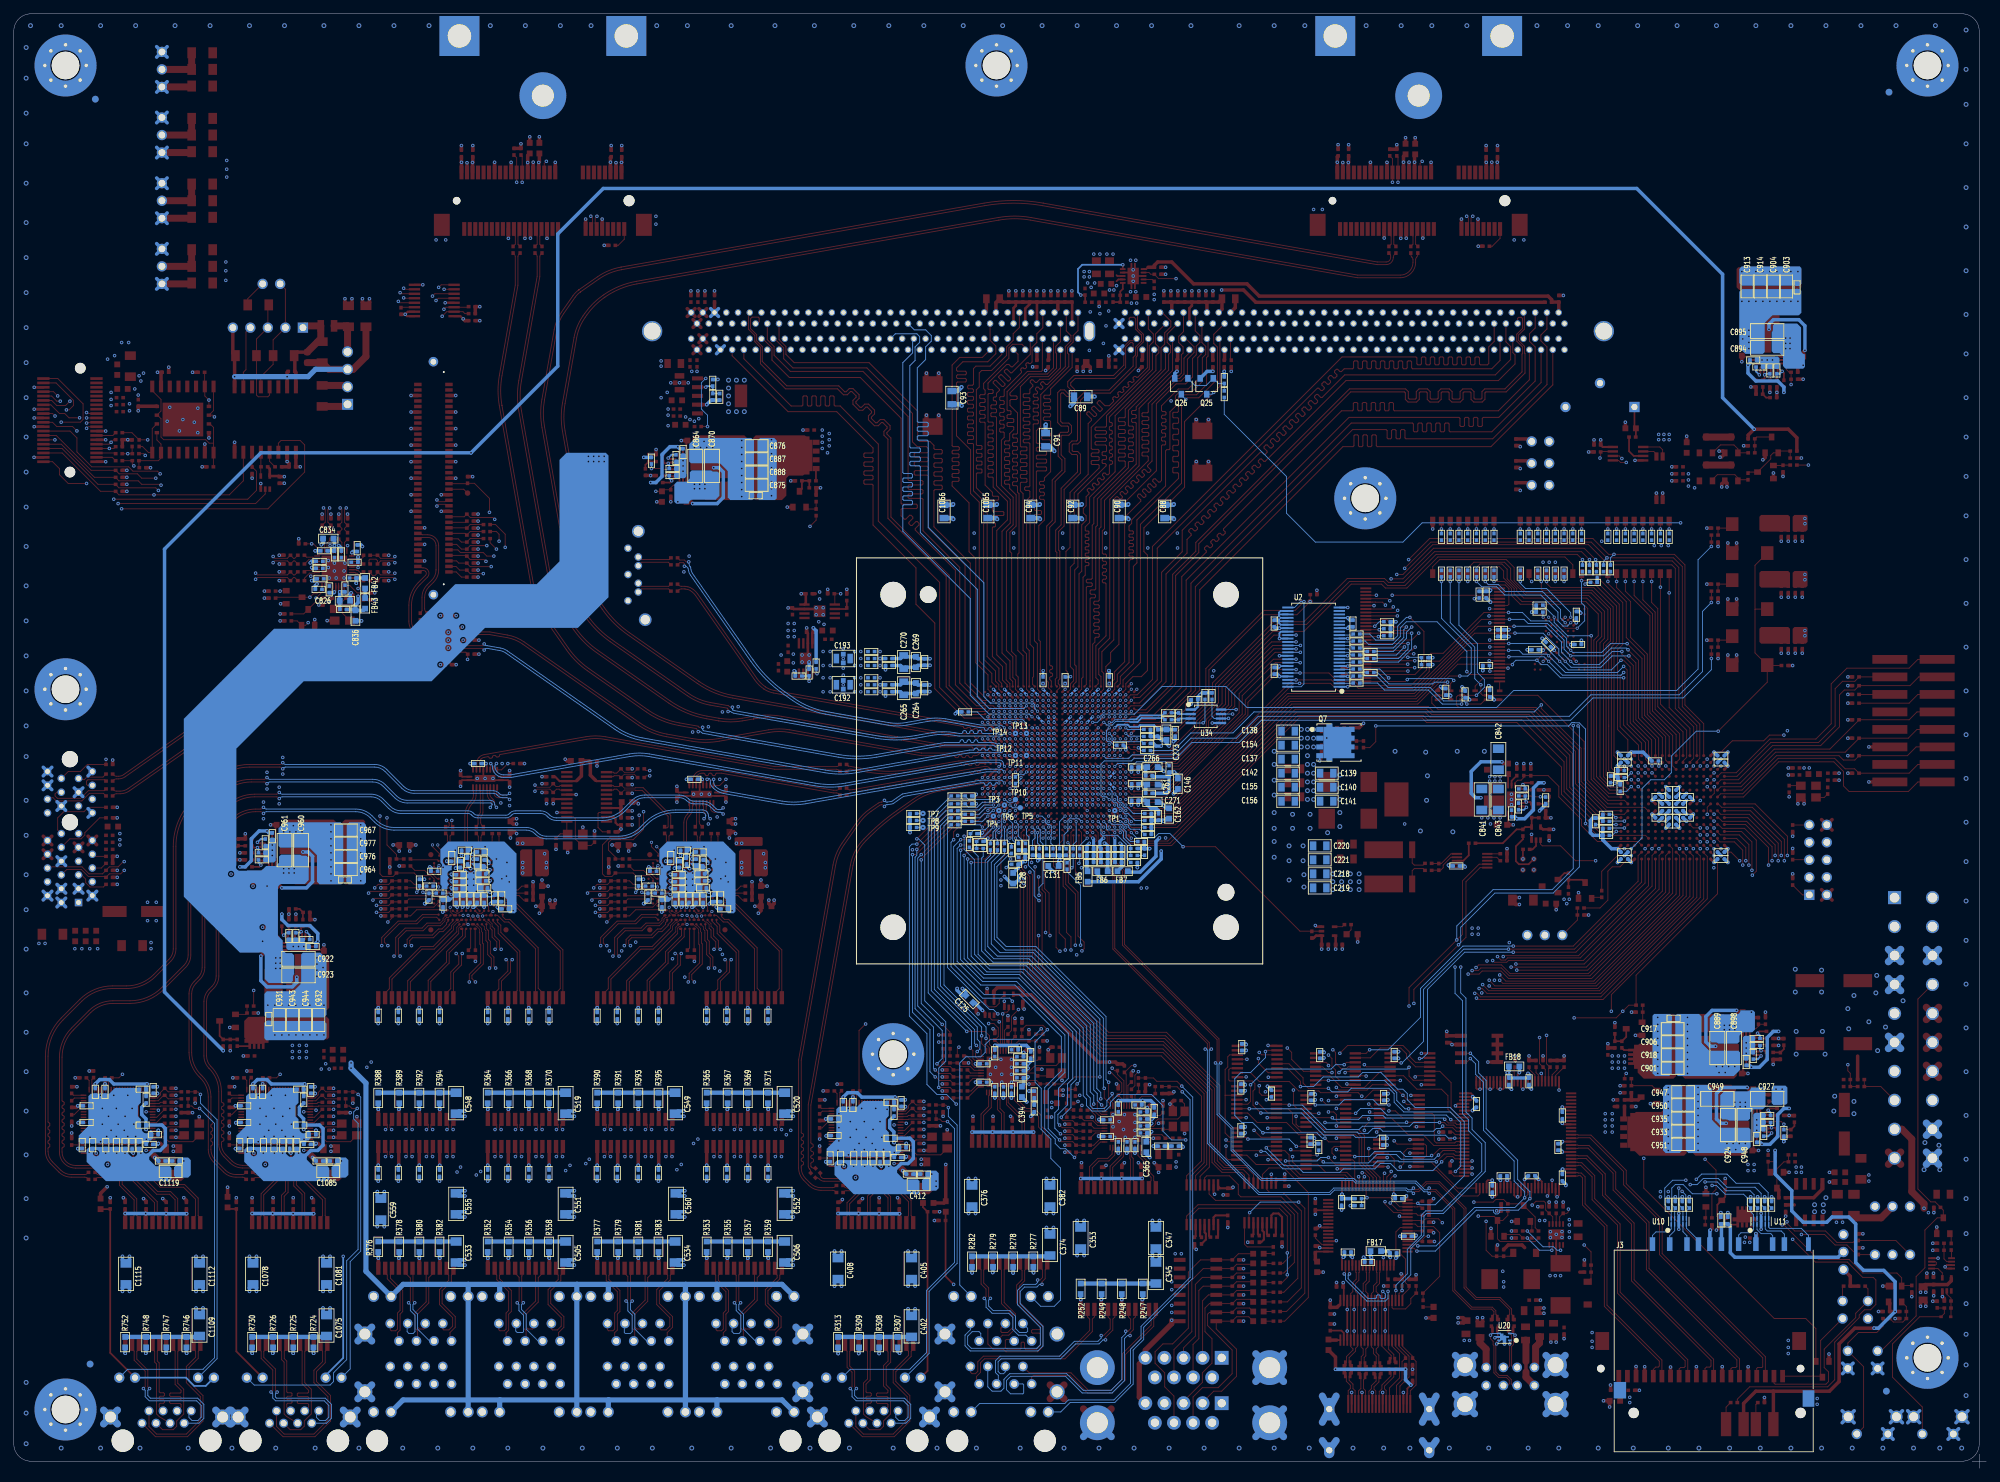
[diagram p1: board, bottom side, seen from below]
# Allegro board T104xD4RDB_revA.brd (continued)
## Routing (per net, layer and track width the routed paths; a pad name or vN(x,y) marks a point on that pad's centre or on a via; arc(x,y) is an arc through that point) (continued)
SG1_MDX3_N: length 22.4
  TOP w0.127: v1(248.72,11.05) 248.46,11.3 248.46,14.25 250.14,15.93 250.14,16.97 250.45,17.28 T12.23
  BOTTOM w0.127: v1(248.72,11.05) 248.46,10.8 248.46,10.18 248.06,9.78 241,9.78 240.34,9.11 240.34,7.4 240.82,6.92 241.67,6.92 242.11,7.37 242.11,7.99 J40.8
SG1_MDX3_P: length 22.4
  TOP w0.127: v1(247.83,11.05) 248.08,11.3 248.08,14.4 249.76,16.08 249.76,16.94 249.46,17.24 T12.22
  BOTTOM w0.127: v1(247.83,11.05) 248.08,10.8 248.08,10.34 247.9,10.16 240.84,10.16 239.96,9.27 239.96,7.24 240.66,6.54 J40.7
SG1_RST_N: length 330.6
  TOP w0.127: U82.52 249.43,56.16 R740.2 247.9,56.64 v1(247.4,57.15) ; U57.R3 v1(39.47,88.89)
  L6SIG w0.102: v1(39.47,88.89) 39.47,88.55 38.93,88.01 38.93,86.93 39.31,86.55 40.2,86.55 58.93,67.82 58.93,58.61 65.28,52.26 70.8,52.26 78.04,45.02 78.04,44.13 79.69,42.48 80.84,42.48 82.23,41.08 82.23,39.24 84.17,37.31 84.17,36.42 84.71,35.88 100.08,35.88 107.82,43.62 110.68,43.62 112.65,45.59 112.65,53.15 127.76,68.26 142.68,68.26 143.38,67.56 146.56,67.56 147.51,66.61 163.64,66.61 173.36,76.33 173.36,86.74 174.88,88.27 174.88,93.28 182.31,100.71 191.9,100.71 192.72,99.89 194.25,99.89 195.55,101.19 195.55,102.27 197.29,104.01 235.71,104.01 237.36,102.36 237.36,69.98 238.89,68.45 238.89,61.47 243.21,57.15 v1(247.4,57.15)
SG2_INT_N: length 345.4
  TOP w0.127: R761.2 v1(262.51,52.07) ; U57.N3 v1(39.47,90.89)
  L6SIG w0.102: v1(39.47,90.89) 39.94,90.41 39.94,87.69 60.26,67.37 60.26,58.67 65.66,53.28 71.44,53.28 73.66,51.05 74.99,51.05 77.82,48.23 77.82,47.09 78.87,46.04 81.09,46.04 81.66,45.47 81.66,43.24 84.51,40.4 84.51,38.18 85.98,36.7 93.79,36.7 94.42,37.34 100.39,37.34 107.44,44.39 110.24,44.39 111.7,45.85 111.7,53.34 127.34,68.99 142.98,68.99 143.64,68.33 147.07,68.33 148.02,67.37 163.26,67.37 172.59,76.71 172.59,87.25 174.05,88.71 174.05,93.54 181.99,101.47 192.47,101.47 195.96,104.97 250,104.97 260.6,94.36 260.6,53.98 v1(262.51,52.07)
SG2_LED0: length 5.2
  TOP w0.127: R755.1 263.63,54.61 R760.2 264.73,54.52 264.73,54.17 265.19,53.71 U83.68
SG2_LED1: length 4.7
  TOP w0.127: U83.69 265.08,53.31 264.29,54.1 R758.2 263.63,53.59 R756.1
SG2_MDI0_N: length 14.5
  TOP w0.127: T13.11 259.96,36.33 259.66,36.63 259.66,39.03 261.4,40.77 264.8,40.77 267.08,43.05 267.08,44.23 267.09,44.24 U83.2
SG2_MDI0_P: length 14.5
  TOP w0.127: U83.1 266.69,44.24 266.7,44.23 266.7,43.21 264.64,41.15 261.24,41.15 259.28,39.19 259.28,36.65 258.97,36.34 T13.12
SG2_MDI1_N: length 12.9
  TOP w0.127: U83.5 268.29,44.24 268.28,44.23 268.28,42.73 265.3,39.75 263.43,39.75 262.63,38.95 262.63,36.71 262.93,36.41 T13.8
SG2_MDI1_P: length 12.9
  TOP w0.127: U83.4 267.89,44.24 267.9,44.23 267.9,42.89 265.15,40.13 263.27,40.13 262.25,39.11 262.25,36.7 261.94,36.39 T13.9
SG2_MDI2_N: length 11
  TOP w0.127: T13.5 265.9,36.36 265.6,36.66 265.6,38.52 269.48,42.41 269.48,44.23 269.49,44.24 U83.8
SG2_MDI2_P: length 11
  TOP w0.127: U83.7 269.09,44.24 269.1,44.23 269.1,42.56 265.22,38.68 265.22,36.62 264.91,36.31 T13.6
SG2_MDI3_N: length 10.3
  TOP w0.127: T13.2 268.87,36.31 268.57,36.61 268.57,38.92 270.68,41.03 270.68,44.23 270.69,44.24 U83.11
SG2_MDI3_P: length 10.3
  TOP w0.127: T13.3 267.88,36.36 268.19,36.67 268.19,39.08 270.3,41.19 270.3,44.23 270.29,44.24 U83.10
SG2_MDX0_N: length 23.5
  TOP w0.127: J41.2 266.41,6.54 266.41,6.05 265.31,4.95 261,4.95 258.96,6.98 258.96,10.38 261,12.42 261,14.75 259.65,16.1 259.65,16.95 259.95,17.26 T13.14
SG2_MDX0_P: length 23.3
  TOP w0.127: T13.13 258.96,17.26 259.27,16.96 259.27,15.94 260.61,14.59 260.61,12.57 258.58,10.54 258.58,6.83 260.84,4.57 265.47,4.57 J41.1
SG2_MDX1_N: length 16.4
  TOP w0.127: J41.6 261.76,8.89 261.76,9.26 261.88,9.39 263.28,9.39 263.41,9.51 263.41,9.77 263.28,9.89 261.88,9.89 261.76,10.02 261.76,10.27 261.88,10.4 263.28,10.4 263.41,10.53 263.41,10.78 263.28,10.91 261.88,10.91 261.76,11.04 261.76,11.3 262.62,12.16 262.62,17 262.92,17.31 T13.17
SG2_MDX1_P: length 16.4
  TOP w0.127: J41.3 264.44,5.59 262.9,5.59 262.39,6.1 262.39,6.86 261.38,7.87 261.38,11.46 262.24,12.32 262.24,16.91 261.93,17.21 T13.16
SG2_MDX2_N: length 12.7
  TOP w0.127: T13.20 265.89,17.23 265.59,16.92 265.59,15.4 265.31,15.12 265.31,7.87 264.93,7.49 J41.5
SG2_MDX2_P: length 12.6
  TOP w0.127: J41.4 264.93,8.88 264.93,9.3 264.81,9.43 264.3,9.43 264.17,9.55 264.17,9.81 264.3,9.93 264.81,9.93 264.93,10.06 264.93,10.31 264.81,10.44 264.3,10.44 264.17,10.57 264.17,10.82 264.3,10.95 264.81,10.95 264.93,11.08 264.93,15.28 265.21,15.56 265.21,16.99 264.9,17.29 T13.19
SG2_MDX3_N: length 22.2
  TOP w0.127: T13.23 268.86,17.28 268.56,16.97 268.56,15.67 266.96,14.08 266.96,11.81 v1(267.22,11.56)
  BOTTOM w0.127: J41.8 260.61,7.99 260.61,7.37 260.17,6.92 259.32,6.92 258.84,7.4 258.84,9.11 259.5,9.78 266.36,9.78 266.96,10.38 266.96,11.3 v1(267.22,11.56)
SG2_MDX3_P: length 22.3
  TOP w0.127: T13.22 267.87,17.24 268.18,16.94 268.18,15.83 266.58,14.23 266.58,11.81 v1(266.33,11.56)
  BOTTOM w0.127: v1(266.33,11.56) 266.58,11.3 266.58,10.54 266.2,10.16 259.34,10.16 258.46,9.27 258.46,7.24 259.16,6.54 J41.7
SG2_RST_N: length 348.9
  TOP w0.127: U57.P4 v1(40.47,89.89) ; U83.52 272.29,56.16 R763.2 270.76,56.64 v1(270.26,57.15)
  L6SIG w0.102: v1(270.26,57.15) 263.91,57.15 260.99,60.07 260.99,94.42 250.13,105.28 195.77,105.28 192.28,101.79 181.93,101.79 173.8,93.66 173.8,88.96 172.34,87.5 172.34,76.84 163.13,67.63 148.15,67.63 147.19,68.58 143.76,68.58 143.13,69.22 139.17,69.22 127.13,69.22 111.38,53.47 111.38,45.97 110.11,44.7 107.38,44.7 100.27,37.59 94.23,37.59 93.66,37.02 86.11,37.02 84.84,38.29 84.84,40.58 82.04,43.37 82.04,45.59 81.22,46.42 78.99,46.42 78.17,47.24 78.17,48.39 75.12,51.44 73.75,51.44 71.53,53.66 65.72,53.66 60.58,58.8 60.58,67.5 40.47,87.61 v1(40.47,89.89)
SG_INT_N: length 49.4
  TOP w0.127: U1.AB1 v2(140.77,91.42) 140.77,90.5 142.88,88.39 v1(142.88,86.49) ; R323.2 v1(154.05,50.16)
  L3SIG w0.102: v1(154.05,50.16) 153.29,50.93 153.29,52.7 151.76,54.23 151,54.23 149.73,55.5 149.73,65.66 143.89,71.5 143.89,85.47 v1(142.88,86.49)
  BOTTOM w0.127: v2(140.77,91.42) 140.34,90.99 R86.1
SG_LED0: length 5.2
  TOP w0.127: U48.68 156.73,51.81 156.27,52.27 156.27,52.62 R321.2 155.17,52.7 R316.1
SG_LED1: length 4.7
  TOP w0.127: R317.1 155.17,51.69 R319.2 155.83,52.2 156.62,51.41 U48.69
SG_MDI0_N: length 8.5
  TOP w0.127: T3.11 156.59,36.33 156.28,36.63 156.28,38.68 158.62,41.02 158.62,42.33 158.63,42.33 U48.2
SG_MDI0_P: length 8.5
  TOP w0.127: U48.1 158.23,42.33 158.24,42.33 158.24,41.18 155.9,38.84 155.9,36.65 155.6,36.34 T3.12
SG_MDI1_N: length 7.7
  TOP w0.127: T3.8 159.56,36.41 159.25,36.71 159.25,39.24 159.82,39.81 159.82,42.33 159.83,42.33 U48.5
SG_MDI1_P: length 7.7
  TOP w0.127: T3.9 158.57,36.39 158.87,36.7 158.87,39.39 159.44,39.97 159.44,42.33 159.43,42.34 U48.4
SG_MDI2_N: length 8
  TOP w0.127: T3.5 162.53,36.36 162.22,36.66 162.22,39.49 161.02,40.68 161.02,42.33 161.03,42.33 U48.8
SG_MDI2_P: length 8
  TOP w0.127: T3.6 161.54,36.31 161.84,36.62 161.84,39.33 160.64,40.53 160.64,42.33 160.63,42.34 U48.7
SG_MDI3_N: length 8.7
  TOP w0.127: U48.11 162.23,42.33 162.22,42.33 162.22,41.48 165.19,38.52 165.19,36.61 165.5,36.31 T3.2
SG_MDI3_P: length 8.7
  TOP w0.127: U48.10 161.83,42.34 161.84,42.33 161.84,41.33 164.81,38.36 164.81,36.67 164.51,36.36 T3.3
SG_MDX0_N: length 23.9
  TOP w0.127: J20.2 163.91,6.54 163.91,6.05 162.81,4.95 158.5,4.95 156.46,6.98 156.46,10.38 158.5,12.42 158.5,14.15 156.27,16.38 156.27,16.95 156.58,17.26 T3.14
SG_MDX0_P: length 23.6
  TOP w0.127: J20.1 162.97,4.57 158.34,4.57 156.08,6.83 156.08,10.54 158.12,12.57 158.12,14 155.89,16.22 155.89,16.96 155.59,17.26 T3.13
SG_MDX1_N: length 16.6
  TOP w0.127: J20.6 159.26,8.89 159.26,9.26 159.39,9.39 160.78,9.39 160.91,9.51 160.91,9.77 160.78,9.89 159.39,9.89 159.26,10.02 159.26,10.27 159.39,10.4 160.78,10.4 160.91,10.53 160.91,10.78 160.78,10.91 159.39,10.91 159.26,11.04 159.26,11.3 159.89,11.94 159.89,14.89 159.24,15.54 159.24,16.87 159.55,17.18 T3.17
SG_MDX1_P: length 16.6
  TOP w0.127: T3.16 158.56,17.21 158.86,16.91 158.86,15.38 159.51,14.73 159.51,12.1 158.88,11.46 158.88,7.87 159.89,6.86 159.89,6.1 160.4,5.59 161.94,5.59 J20.3
SG_MDX2_N: length 12.9
  TOP w0.127: T3.20 162.52,17.23 162.21,16.92 162.21,12.95 162.81,12.35 162.81,7.87 162.43,7.49 J20.5
SG_MDX2_P: length 12.7
  TOP w0.127: T3.19 161.53,17.29 161.83,16.99 161.83,12.79 162.43,12.19 162.43,11.08 162.31,10.95 161.8,10.95 161.67,10.82 161.67,10.57 161.8,10.44 162.31,10.44 162.43,10.31 162.43,10.06 162.31,9.93 161.8,9.93 161.67,9.81 161.67,9.55 161.8,9.43 162.31,9.43 162.43,9.3 162.43,8.88 J20.4
SG_MDX3_N: length 21.8
  TOP w0.127: v1(164.72,11.56) 164.47,11.81 164.47,13.94 165.18,14.66 165.18,16.97 165.49,17.28 T3.23
  BOTTOM w0.127: J20.8 158.12,7.99 158.12,7.37 157.67,6.92 156.82,6.92 156.34,7.4 156.34,9.11 157,9.78 163.86,9.78 164.47,10.38 164.47,11.3 v1(164.72,11.56)
SG_MDX3_P: length 21.9
  TOP w0.127: T3.22 164.5,17.24 164.8,16.94 164.8,14.81 164.08,14.1 164.08,11.81 v1(163.83,11.56)
  BOTTOM w0.127: J20.7 156.66,6.54 155.96,7.24 155.96,9.27 156.85,10.16 163.7,10.16 164.08,10.54 164.08,11.3 v1(163.83,11.56)
SG_RST_N: length 195.7
  TOP w0.127: U48.52 163.83,54.25 R325.2 163.45,54.84 163.45,63.5 v1(162.5,64.45) ; v1(35.31,87.5) 35.31,89.66 36.51,90.87 38.61,90.87 38.97,91.23 U57.N2
  L6SIG w0.102: v1(35.31,87.5) 35.31,86.87 38.1,84.07 39.56,84.07 56.64,66.99 56.64,55.5 62.23,49.91 69.6,49.91 74.12,45.39 74.12,42.49 79.15,37.47 79.95,37.47 84.2,33.21 85.6,33.21 85.85,33.46 100.39,33.46 108.65,41.72 111.82,41.72 114.87,44.77 114.87,50.67 118.49,54.29 118.49,56.13 126.87,64.52 142.18,64.52 142.86,65.2 144.67,65.2 145.91,63.96 162,63.96 v1(162.5,64.45)
SGMII1_RX_N: length 133.5
  TOP w0.127: v1(249.81,95) 249.94,95.13 arc(250.08,95.22) 250.23,95.25 250.99,95.25 arc(252.69,94.91) 254.13,93.95 254.82,93.26 arc(255.9,91.63) 256.29,89.71 256.29,71.41 arc(256.48,70.44) 257.03,69.61 257.43,69.21 arc(257.9,68.51) 258.06,67.69 258.06,59.82 arc(257.9,59.01) 257.45,58.31 arc(256.31,56.62) 255.91,54.62 255.91,53.2 arc(255.86,53.08) 255.73,53.02 arc(255.6,52.97) 255.55,52.84 255.55,52.7 arc(255.6,52.57) 255.73,52.51 arc(255.86,52.46) 255.91,52.33 255.91,52.19 arc(255.86,52.06) 255.73,52.01 arc(255.6,51.95) 255.55,51.83 255.55,51.68 arc(255.6,51.55) 255.73,51.5 arc(255.86,51.45) 255.91,51.32 255.91,51.17 arc(255.86,51.04) 255.73,50.99 arc(255.6,50.94) 255.55,50.81 255.55,50.66 arc(255.6,50.54) 255.73,50.48 arc(255.86,50.43) 255.91,50.3 255.91,50.16 arc(255.86,50.03) 255.73,49.97 arc(255.6,49.92) 255.55,49.79 255.55,49.65 arc(255.6,49.52) 255.73,49.47 arc(255.86,49.41) 255.91,49.29 255.91,49.14 arc(255.86,49.01) 255.73,48.96 arc(255.6,48.91) 255.55,48.78 255.55,48.63 arc(255.6,48.5) 255.73,48.45 arc(255.86,48.4) 255.91,48.27 255.91,48.12 arc(255.86,48) 255.73,47.94 arc(255.6,47.89) 255.55,47.76 255.55,47.62 arc(255.6,47.49) 255.73,47.43 arc(255.86,47.38) 255.91,47.25 255.91,47 arc(255.75,46.17) 255.28,45.47 254.38,44.57 arc(253.68,44.11) 252.85,43.94 251,43.94 arc(250.87,43.97) 250.75,44.04 250.63,44.17 U82.18 ; U16.15 186.06,96.08 186,96.02 186,95.45 arc(185.96,95.24) 185.84,95.07 185.75,94.97 arc(185.69,94.89) 185.67,94.8 185.67,94.66 arc(185.7,94.5) 185.79,94.37 v1(185.93,94.23)
  BOTTOM w0.127: v1(185.93,94.23) 185.79,94.37 arc(185.7,94.5) 185.67,94.66 arc(185.81,94.99) 186.14,95.12 190.07,95.12 arc(192.32,94.68) 194.22,93.41 194.93,92.7 arc(196.46,91.67) 198.27,91.31 208.82,91.31 arc(209.64,91.48) 210.34,91.94 210.46,92.07 arc(211.03,92.45) 211.71,92.58 230.89,92.58 arc(232.41,92.89) 233.7,93.75 234.34,94.38 arc(235.3,95.02) 236.43,95.25 249.39,95.25 arc(249.54,95.22) 249.67,95.13 v1(249.81,95)
SGMII1_RX_P: length 133.4
  TOP w0.127: v1(185.04,94.23) 185.17,94.37 arc(185.26,94.5) 185.29,94.66 185.29,94.87 arc(185.33,95.05) 185.43,95.19 185.57,95.34 arc(185.61,95.39) 185.62,95.45 185.62,96 185.56,96.06 U16.14 ; v1(249.81,95.89) 249.94,95.75 arc(250.08,95.66) 250.23,95.63 250.99,95.63 arc(252.83,95.26) 254.4,94.22 255.09,93.53 arc(256.26,91.78) 256.67,89.71 256.67,71.41 arc(256.83,70.58) 257.3,69.88 257.7,69.48 arc(258.25,68.66) 258.44,67.69 258.44,59.82 arc(258.26,58.86) 257.72,58.04 arc(257.71,58.03) 257.7,58.03 arc(256.66,56.46) 256.29,54.62 256.29,47 arc(256.1,46.03) 255.55,45.2 254.65,44.3 arc(253.82,43.75) 252.85,43.56 251,43.56 arc(250.72,43.62) 250.48,43.77 250.32,43.94 arc(250.27,44.02) 250.25,44.1 250.25,44.22 250.23,44.24 U82.17
  BOTTOM w0.127: v1(249.81,95.89) 249.67,95.75 arc(249.54,95.66) 249.39,95.63 236.43,95.63 arc(235.15,95.38) 234.07,94.65 233.43,94.02 arc(232.27,93.24) 230.89,92.96 211.71,92.96 arc(210.89,92.8) 210.19,92.33 210.07,92.21 arc(209.49,91.83) 208.82,91.69 198.27,91.69 arc(196.61,92.02) 195.2,92.97 194.49,93.68 arc(192.46,95.03) 190.07,95.5 186.14,95.5 arc(185.54,95.26) 185.29,94.66 arc(185.26,94.5) 185.17,94.37 v1(185.04,94.23)
SGMII1_TX_N: length 139
  TOP w0.127: v1(183.16,94.92) 183.29,95.05 arc(183.42,95.14) 183.58,95.17 184.39,95.17 arc(184.82,95.35) 185,95.78 185,95.97 185.06,96.03 U16.13 ; v1(247.52,97.16) 247.66,97.29 arc(247.79,97.38) 247.94,97.41 251.09,97.41 arc(253.19,96.99) 254.97,95.8 256.38,94.4 arc(257.81,92.25) 258.32,89.71 258.32,72.68 arc(258.51,71.71) 259.06,70.88 259.59,70.36 arc(260.06,69.65) 260.22,68.83 260.22,60.33 arc(259.87,58.57) 258.87,57.07 258.68,56.87 arc(257.75,55.49) 257.43,53.86 257.43,50.55 arc(257.39,50.46) 257.3,50.42 arc(257.21,50.38) 257.18,50.29 257.18,50.04 arc(257.21,49.95) 257.3,49.91 arc(257.39,49.87) 257.43,49.78 257.43,49.53 arc(257.39,49.44) 257.3,49.4 arc(257.21,49.37) 257.18,49.28 257.18,49.02 arc(257.21,48.93) 257.3,48.9 arc(257.39,48.86) 257.43,48.77 257.43,48.51 arc(257.39,48.42) 257.3,48.39 arc(257.21,48.35) 257.18,48.26 257.18,48.01 arc(257.21,47.92) 257.3,47.88 arc(257.39,47.84) 257.43,47.75 257.43,47.5 arc(257.39,47.41) 257.3,47.37 arc(257.21,47.33) 257.18,47.24 257.18,46.99 arc(257.21,46.9) 257.3,46.86 arc(257.39,46.83) 257.43,46.74 257.43,46.23 arc(257.26,45.41) 256.8,44.71 255.33,43.24 arc(254.63,42.77) 253.8,42.61 252.85,42.61 arc(252.66,42.65) 252.49,42.76 C1077.2
  BOTTOM w0.127: v1(183.16,94.92) 183.29,95.05 arc(183.42,95.14) 183.58,95.17 183.81,95.17 arc(184.17,95.24) 184.47,95.44 184.93,95.9 arc(185.47,96.26) 186.12,96.39 187.34,96.39 arc(187.94,96.51) 188.45,96.86 arc(188.93,97.17) 189.48,97.28 194.56,97.28 arc(195.38,97.12) 196.09,96.65 197.4,95.33 arc(198.9,94.33) 200.67,93.98 207.35,93.98 arc(208,94.11) 208.56,94.48 208.68,94.61 arc(209.12,94.89) 209.63,95 213.3,95 arc(213.56,94.94) 213.78,94.8 213.91,94.67 arc(214.25,94.44) 214.66,94.36 218.79,94.36 arc(219.2,94.44) 219.54,94.67 219.67,94.8 arc(219.89,94.94) 220.15,95 229.86,95 arc(230.84,95.19) 231.66,95.74 232.7,96.78 arc(233.4,97.24) 234.22,97.41 247.1,97.41 arc(247.26,97.38) 247.39,97.29 v1(247.52,97.16)
SGMII1_TX_P: length 138.4
  TOP w0.127: v1(183.16,95.81) 183.29,95.67 arc(183.42,95.58) 183.58,95.55 184.39,95.55 arc(184.55,95.62) 184.62,95.78 184.62,95.99 184.56,96.05 U16.12 ; C1076.2 252.49,42.08 arc(252.66,42.19) 252.85,42.23 253.8,42.23 arc(254.78,42.42) 255.6,42.97 257.07,44.44 arc(257.62,45.26) 257.81,46.23 257.81,53.86 arc(258.1,55.35) 258.94,56.6 259.14,56.8 arc(260.22,58.42) 260.6,60.33 260.6,68.83 arc(260.41,69.8) 259.86,70.62 259.33,71.15 arc(258.86,71.85) 258.7,72.68 258.7,89.71 arc(258.17,92.39) 256.64,94.67 255.24,96.07 arc(253.34,97.34) 251.09,97.79 247.94,97.79 arc(247.79,97.82) 247.66,97.91 v1(247.52,98.04)
  BOTTOM w0.127: v1(247.52,98.04) 247.39,97.91 arc(247.26,97.82) 247.1,97.79 234.22,97.79 arc(233.25,97.6) 232.43,97.05 231.39,96.01 arc(230.69,95.54) 229.86,95.38 220.15,95.38 arc(219.74,95.3) 219.4,95.07 219.28,94.94 arc(219.05,94.79) 218.79,94.74 214.66,94.74 arc(214.4,94.79) 214.18,94.94 214.05,95.07 arc(213.71,95.3) 213.3,95.38 209.63,95.38 arc(208.97,95.25) 208.41,94.87 208.29,94.75 arc(207.86,94.46) 207.35,94.36 200.67,94.36 arc(199.05,94.68) 197.67,95.6 196.35,96.92 arc(195.53,97.47) 194.56,97.66 189.48,97.66 arc(188.78,97.52) 188.18,97.13 188.18,97.12 arc(187.8,96.87) 187.34,96.77 186.12,96.77 arc(185.33,96.62) 184.66,96.17 184.2,95.71 arc(184.02,95.59) 183.81,95.55 183.58,95.55 arc(183.42,95.58) 183.29,95.67 v1(183.16,95.81)
SGMII2_RX_N: length 119.3
  TOP w0.127: U17.15 217.43,98.3 217.37,98.24 217.37,97.85 arc(217.28,97.39) 217.01,97 216.78,96.77 arc(216.69,96.63) 216.66,96.48 216.66,96.3 arc(216.69,96.14) 216.78,96.01 v1(216.92,95.88) ; v1(249.3,99.31) 249.44,99.45 arc(249.57,99.54) 249.72,99.57 251.53,99.57 arc(253.93,99.09) 255.97,97.73 257.82,95.88 arc(259.69,93.07) 260.35,89.77 260.35,74.46 arc(260.54,73.49) 261.09,72.66 264.31,69.45 arc(266.54,67.96) 269.16,67.44 271.65,67.44 arc(273.38,67.09) 274.86,66.11 277.38,63.58 arc(278.59,61.77) 279.02,59.63 279.02,53.34 arc(278.97,53.23) 278.87,53.19 arc(278.76,53.14) 278.71,53.03 278.71,52.83 arc(278.76,52.72) 278.87,52.68 arc(278.97,52.63) 279.02,52.53 279.02,52.32 arc(278.97,52.21) 278.87,52.17 arc(278.76,52.13) 278.71,52.02 278.71,51.81 arc(278.76,51.71) 278.87,51.66 arc(278.97,51.62) 279.02,51.51 279.02,51.31 arc(278.97,51.2) 278.87,51.15 arc(278.76,51.11) 278.71,51 278.71,50.8 arc(278.76,50.69) 278.87,50.65 arc(278.97,50.6) 279.02,50.49 279.02,50.29 arc(278.97,50.18) 278.87,50.14 arc(278.76,50.09) 278.71,49.99 278.71,49.78 arc(278.76,49.67) 278.87,49.63 arc(278.97,49.59) 279.02,49.48 279.02,49.27 arc(278.97,49.17) 278.87,49.12 arc(278.76,49.08) 278.71,48.97 278.71,48.77 arc(278.76,48.66) 278.87,48.61 arc(278.97,48.57) 279.02,48.46 279.02,48.26 arc(278.97,48.15) 278.87,48.11 arc(278.76,48.06) 278.71,47.95 278.71,47.75 arc(278.76,47.64) 278.87,47.6 arc(278.97,47.55) 279.02,47.45 279.02,47.24 arc(278.97,47.13) 278.87,47.09 arc(278.76,47.05) 278.71,46.94 278.71,46.73 arc(278.76,46.63) 278.87,46.58 arc(278.97,46.54) 279.02,46.43 279.02,45.88 arc(278.45,44.5) 277.06,43.92 273.73,43.92 arc(273.56,44) 273.48,44.18 273.48,44.9 U83.18
  BOTTOM w0.127: v1(249.3,99.31) 249.17,99.45 arc(249.03,99.54) 248.88,99.57 233.97,99.57 arc(233.14,99.4) 232.44,98.94 230.77,97.26 arc(229.95,96.71) 228.98,96.52 216.89,96.52 arc(216.73,96.45) 216.66,96.3 arc(216.69,96.14) 216.78,96.01 v1(216.92,95.88)
SGMII2_RX_P: length 119.3
  TOP w0.127: v1(216.03,95.88) 216.16,96.01 arc(216.25,96.14) 216.28,96.3 216.28,96.48 arc(216.34,96.78) 216.51,97.04 216.75,97.27 arc(216.92,97.54) 216.99,97.85 216.99,98.23 216.93,98.29 U17.14 ; v1(249.3,100.2) 249.44,100.07 arc(249.57,99.98) 249.72,99.95 251.52,99.95 arc(254.07,99.44) 256.24,98 258.09,96.15 arc(260.04,93.22) 260.73,89.77 260.73,74.46 arc(260.9,73.63) 261.36,72.93 264.58,69.72 arc(266.68,68.31) 269.16,67.82 271.65,67.82 arc(273.53,67.44) 275.13,66.38 277.65,63.85 arc(278.95,61.91) 279.4,59.63 279.4,45.88 arc(278.72,44.23) 277.06,43.54 273.73,43.54 arc(273.29,43.73) 273.1,44.18 273.1,44.9 U83.17
  BOTTOM w0.127: v1(249.3,100.2) 249.17,100.07 arc(249.03,99.98) 248.88,99.95 233.97,99.95 arc(233,99.76) 232.17,99.21 230.5,97.53 arc(229.8,97.07) 228.98,96.9 216.89,96.9 arc(216.46,96.72) 216.28,96.3 arc(216.25,96.14) 216.16,96.01 v1(216.03,95.88)
SGMII2_TX_N: length 124.1
  TOP w0.127: v1(214.12,97.03) 214.26,97.16 arc(214.39,97.25) 214.54,97.28 215.74,97.28 arc(216.19,97.47) 216.37,97.91 216.37,98.26 216.43,98.32 U17.13 ; v1(247.02,101.47) 247.15,101.61 arc(247.28,101.7) 247.44,101.73 251.84,101.73 arc(254.54,101.19) 256.83,99.66 259.86,96.63 arc(261.82,93.69) 262.51,90.23 262.51,75.35 arc(262.7,74.38) 263.25,73.55 265.47,71.34 arc(267.4,70.05) 269.67,69.6 271.72,69.6 arc(274.12,69.12) 276.16,67.76 278.87,65.05 arc(280.48,62.63) 281.05,59.78 281.05,50.25 arc(281.01,50.16) 280.92,50.12 arc(280.83,50.08) 280.8,49.99 280.8,49.74 arc(280.83,49.65) 280.92,49.61 arc(281.01,49.57) 281.05,49.48 281.05,49.23 arc(281.01,49.14) 280.92,49.1 arc(280.83,49.07) 280.8,48.98 280.8,48.72 arc(280.83,48.63) 280.92,48.6 arc(281.01,48.56) 281.05,48.47 281.05,48.21 arc(281.01,48.12) 280.92,48.09 arc(280.83,48.05) 280.8,47.96 280.8,47.71 arc(280.83,47.62) 280.92,47.58 arc(281.01,47.54) 281.05,47.45 281.05,47.2 arc(281.01,47.11) 280.92,47.07 arc(280.83,47.03) 280.8,46.94 280.8,46.69 arc(280.83,46.6) 280.92,46.56 arc(281.01,46.53) 281.05,46.44 281.05,45.98 arc(280.89,45.15) 280.42,44.45 279.21,43.24 arc(278.51,42.77) 277.68,42.61 275.71,42.61 arc(275.52,42.65) 275.35,42.76 C1111.2
  BOTTOM w0.127: v1(214.12,97.03) 214.26,97.16 arc(214.39,97.25) 214.54,97.28 215.11,97.28 arc(215.52,97.36) 215.86,97.59 215.98,97.72 arc(216.21,97.86) 216.47,97.92 227.96,97.92 arc(228.93,98.11) 229.76,98.66 232.19,101.09 arc(232.89,101.56) 233.72,101.73 246.59,101.73 arc(246.75,101.7) 246.88,101.61 v1(247.02,101.47)
SGMII2_TX_P: length 123.6
  TOP w0.127: C1110.2 275.35,42.08 arc(275.52,42.19) 275.71,42.23 277.68,42.23 arc(278.65,42.42) 279.48,42.97 280.69,44.18 arc(281.24,45.01) 281.43,45.98 281.43,59.78 arc(280.84,62.78) 279.14,65.32 276.43,68.02 arc(274.27,69.47) 271.72,69.98 269.67,69.98 arc(267.54,70.4) 265.74,71.61 263.52,73.82 arc(263.05,74.52) 262.89,75.35 262.89,90.23 arc(262.17,93.84) 260.13,96.9 257.1,99.93 arc(254.69,101.54) 251.84,102.11 247.44,102.11 arc(247.28,102.14) 247.15,102.23 v1(247.02,102.36) ; U17.12 215.93,98.33 215.99,98.27 215.99,97.91 arc(215.92,97.74) 215.74,97.66 214.54,97.66 arc(214.39,97.69) 214.26,97.78 v1(214.12,97.92)
  BOTTOM w0.127: v1(214.12,97.92) 214.26,97.78 arc(214.39,97.69) 214.54,97.66 215.11,97.66 arc(215.37,97.72) 215.59,97.86 215.72,97.99 arc(216.06,98.22) 216.47,98.3 227.96,98.3 arc(228.79,98.46) 229.49,98.93 231.92,101.36 arc(232.74,101.91) 233.72,102.11 246.59,102.11 arc(246.75,102.14) 246.88,102.23 v1(247.02,102.36)
SGMII_RX_N: length 5.5
  TOP w0.127: C57.1 169.08,42.59 arc(169.04,42.38) 168.92,42.2 168.89,42.18 arc(168.72,42.06) 168.51,42.02 165.4,42.02 arc(165.13,42.13) 165.02,42.4 165.02,42.99 165.03,43 U48.18
SGMII_RX_P: length 6.3
  TOP w0.127: U48.17 164.64,43 164.64,42.4 arc(164.87,41.86) 165.4,41.64 168.51,41.64 arc(168.86,41.71) 169.16,41.91 169.27,42.01 arc(169.41,42.11) 169.57,42.14 C56.1
SGMII_TX_N: length 83.4
  TOP w0.127: U1.AE11 v2(143.17,99.42) ; C404.2 166.89,40.85 arc(167.06,40.74) 167.25,40.7 168.97,40.7 arc(169.79,40.87) 170.49,41.34 171.2,42.04 arc(171.67,42.74) 171.83,43.57 171.83,43.82 arc(171.78,43.94) 171.67,43.99 arc(171.55,44.03) 171.5,44.15 171.5,44.33 arc(171.55,44.45) 171.67,44.49 arc(171.78,44.54) 171.83,44.66 171.83,44.84 arc(171.78,44.95) 171.67,45 arc(171.55,45.05) 171.5,45.17 171.5,45.34 arc(171.55,45.46) 171.67,45.51 arc(171.78,45.56) 171.83,45.67 171.83,45.85 arc(171.78,45.97) 171.67,46.02 arc(171.55,46.07) 171.5,46.18 171.5,46.36 arc(171.55,46.48) 171.67,46.53 arc(171.78,46.57) 171.83,46.69 171.83,46.87 arc(171.78,46.99) 171.67,47.03 arc(171.55,47.08) 171.5,47.2 171.5,47.38 arc(171.55,47.49) 171.67,47.54 arc(171.78,47.59) 171.83,47.71 171.83,47.88 arc(171.78,48) 171.67,48.05 arc(171.55,48.1) 171.5,48.21 171.5,48.39 arc(171.55,48.51) 171.67,48.56 arc(171.78,48.61) 171.83,48.72 171.83,59.21 166.85,87.45 arc(166.39,89.03) 165.6,90.47 163.42,93.59 arc(162.64,94.52) 161.71,95.3 160.44,96.19 arc(160.32,96.25) 160.19,96.27 160.16,96.27 arc(160.03,96.24) 159.92,96.17 v1(159.77,96.01)
  BOTTOM w0.127: v2(143.17,99.42) 143.19,99.44 143.53,99.44 arc(143.66,99.39) 143.71,99.26 arc(143.76,99.14) 143.89,99.09 144.04,99.09 arc(144.17,99.14) 144.22,99.26 arc(144.27,99.39) 144.4,99.44 144.55,99.44 arc(144.68,99.39) 144.73,99.26 arc(144.78,99.14) 144.91,99.09 145.06,99.09 arc(145.18,99.14) 145.24,99.26 arc(145.29,99.39) 145.41,99.44 145.8,99.44 157.01,97.47 158.53,96.4 159.3,96.27 159.51,96.27 v1(159.77,96.01)
SGMII_TX_P: length 82.9
  TOP w0.127: v1(159.77,96.9) 159.91,96.76 arc(160.03,96.68) 160.18,96.65 160.19,96.65 arc(160.44,96.61) 160.66,96.5 161.93,95.61 arc(162.91,94.79) 163.73,93.81 165.91,90.69 arc(166.74,89.18) 167.23,87.52 172.21,59.24 172.21,43.57 arc(172.02,42.59) 171.47,41.77 170.76,41.07 arc(169.94,40.52) 168.97,40.32 167.25,40.32 arc(167.06,40.28) 166.89,40.17 C403.2 ; U1.AD11 v2(142.37,99.42)
  BOTTOM w0.127: v1(159.77,96.9) 159.51,96.65 159.33,96.65 158.68,96.76 157.16,97.83 145.84,99.82 142.77,99.82 v2(142.37,99.42)
SINGLE_CLK_EN_N: length 296.3
  TOP w0.127: 33.53,124.59 33.53,118.3 X3.1 ; 33.53,124.59 33.47,124.65 X1.1 ; 33.53,124.59 33.53,131 X2.1 ; U79.38 236.49,129.56 235.84,128.91 235.84,127.89 v1(236.09,127.63) ; X3.1 31.75,114.05 v1(38.86,106.93) ; X3.1 31.69,116.46 R485.2 ; U57.P14 v1(51.47,89.89)
  L6SIG w0.102: v1(236.09,127.63) 235.97,127.63 235.08,126.75 235.08,119.76 232.73,117.41 221.49,117.41 220.66,116.59 183.26,116.59 164.4,97.73 164.4,94.34 162.81,92.75 162.81,86.93 158.31,82.42 151.83,82.42 148.03,78.63 123.65,78.63 112.97,67.94 74.99,67.94 74.36,67.31 65.66,67.31 52.51,80.45 52.51,88.07 51.94,88.65 51.94,89.41 v1(51.47,89.89)
  BOTTOM w0.127: v1(38.86,106.93) 42.04,106.93 45.66,103.31 45.66,100.9 46.67,99.89 48.64,99.89 49.91,98.62 49.91,91.44 v1(51.47,89.89)
SPI_CLK: length 200.1
  TOP w0.127: v1(266.6,149.2) R66.1 268.88,150.24 R200.2
  L6SIG w0.102: v1(266.6,149.2) 267.11,149.2 267.97,148.34 267.97,146.18 266.64,144.84 266.64,135.83 243.78,112.97 188.02,112.97 183.2,108.14 179.26,108.14 167.64,96.52 167.64,92.71 165.99,91.06 165.99,80.58 160.46,75.06 134.94,75.06 134.3,75.69 132.59,75.69 132.33,75.44 131.77,75.44 v1(131.32,75.89)
  BOTTOM w0.127: v1(131.32,75.89) 131.32,84.59 133.29,86.55 R65.2
SPI_CS0_N: length 215
  TOP w0.127: v1(132.08,75.88) 132.08,83.31 133.48,84.71 133.48,88.39 132.37,89.5 U1.M1 ; U9.1 v1(257.72,154.98) 258.32,155.57 U8.7 258.34,156.97 R60.1
  L6SIG w0.102: v1(132.08,75.88) 132.27,76.07 134.43,76.07 135.11,75.4 160.23,75.4 165.48,80.64 165.48,91.38 167.2,93.09 167.2,96.71 179.01,108.52 183.07,108.52 187.96,113.41 243.54,113.41 266.19,136.06 266.19,144.15 264.1,146.24 261.81,146.24 256.41,151.64 256.41,153.67 v1(257.72,154.98)
SPI_MISO: length 199.3
  TOP w0.127: U1.P1 133.97,91.08 135.26,89.79 135.26,87.38 134.87,86.99 134.87,75.56 v1(134.32,75.01) ; R58.1 268.86,147.22 R61.1 v1(269.49,147.19) R201.2
  L6SIG w0.102: v1(134.32,75.01) 134.59,74.74 160.72,74.74 166.43,80.45 166.43,90.8 168.08,92.46 168.08,96.39 179.45,107.76 183.32,107.76 188.09,112.52 244.05,112.52 267.08,135.55 267.08,144.65 269.49,147.07 v1(269.49,147.19)
SPI_MOSI: length 199.4
  TOP w0.127: R202.2 R64.1 268.83,145.64 v1(268.61,145.41) ; v1(133.54,75.18) 133.54,75.19 133.54,76.78 134.43,77.66 134.43,87.12 134.87,87.57 134.87,89.53 133.6,90.81 133.6,92.25 U1.P2
  L6SIG w0.102: v1(268.61,145.41) 268.48,145.41 267.46,144.4 267.46,135.38 244.28,112.2 188.15,112.2 183.45,107.51 179.64,107.51 168.34,96.2 168.34,92.2 166.75,90.61 166.75,80.39 160.87,74.51 133.96,74.51 133.54,74.93 v1(133.54,75.18)
SYS_REFCLK: length 105
  TOP w0.127: v1(39.85,125.6) R486.2 R484.2 ; U1.G15 v2(127.97,103.42)
  BOTTOM w0.127: v2(127.97,103.42) 127.97,103.33 127.64,103 124.33,103 123.83,103.5 117.73,103.5 115.32,105.92 108.73,105.92 105.56,109.09 60.45,109.09 57.34,112.2 44.51,112.2 41.15,115.57 41.15,124.31 v1(39.85,125.6)
SYS_REFCLK_N: length 121.6
  TOP w0.127: U1.F14 v2(127.17,101.82) ; R524.2 234.15,128.97 233.46,128.97 R527.2 232.83,129.22 231.02,129.22 v1(230.76,128.96)
  L3SIG w0.102: v2(127.17,101.82) 127.17,101.81 127.58,101.4 128.19,101.4 128.39,101.59 128.39,101.97 128.9,102.49 139.95,102.49 140.14,102.68 147,102.68 152.67,108.36 176.68,108.36 184.91,116.59 210.19,116.59 218.19,124.59 226.95,124.59 228.32,125.96 228.32,128.25 229.3,129.23 230.49,129.23 v1(230.76,128.96)
SYS_REFCLK_P: length 121.7
  TOP w0.127: U1.G14 v2(127.97,101.82) ; R522.2 234.34,129.88 234,129.54 233.62,129.54 233.27,129.88 R521.2 232.83,129.6 231.01,129.6 v1(230.76,129.85)
  L3SIG w0.102: v2(127.97,101.82) 127.67,101.82 127.57,101.92 127.57,102.17 127.7,102.3 128.21,102.3 128.75,102.84 139.81,102.84 140,103.03 146.85,103.03 152.53,108.71 176.54,108.71 184.76,116.94 210.04,116.94 218.04,124.94 226.8,124.94 227.97,126.11 227.97,128.4 229.15,129.59 230.49,129.59 v1(230.76,129.85)
TDMA_RCK_CLK8_12: length 230.3
  TOP w0.127: U27.13 v1(107.21,59.33) ; v1(276.86,150.5) 277.5,151.13 279.78,151.13 280.39,151.74 J11.21
  L6SIG w0.102: v1(276.86,150.5) 276.86,146.43 275.97,145.54 275.97,136.91 247.21,108.14 194.69,108.14 190.63,104.08 180.98,104.08 171.64,94.74 171.64,90.3 169.95,88.61 169.95,78.26 163.18,71.49 161.2,71.49 125.52,71.49 113.37,59.33 v1(107.21,59.33)
TDMA_RQ: length 243.2
  TOP w0.127: v1(278.38,153.54) 278,153.54 277.37,154.18 277.37,154.94 279.89,157.46 J11.3 ; U26.3 105.04,54.11 105.41,54.48 v1(105.41,55.5)
  L6SIG w0.102: v1(278.38,153.54) 278.64,153.29 278.64,147.95 279.02,147.57 279.02,138.34 247.87,107.19 195.07,107.19 191.2,103.31 181.36,103.31 172.41,94.37 172.41,89.92 170.66,88.18 170.66,77.76 163.7,70.8 162.28,70.8 160.91,70.8 126.11,70.8 112.59,57.28 107.19,57.28 v1(105.41,55.5)
TDMA_RSYNC: length 254.2
  TOP w0.127: v1(277.88,154.81) 278.51,154.18 279.78,154.18 280.52,154.92 J11.11 ; U21.13 89.86,58.24 v1(90.17,58.55)
  L6SIG w0.102: v1(90.17,58.55) 90.93,58.55 91.57,59.18 93.73,59.18 93.98,58.93 95.63,58.93 96.01,58.55 98.04,58.55 99.19,59.69 103,59.69 104.19,60.88 105.87,60.88 106.55,60.2 113.41,60.2 125.16,71.94 161.39,71.94 162.68,71.94 169.49,78.75 169.49,88.94 171.13,90.57 171.13,95.06 180.66,104.58 190.25,104.58 194.44,108.78 246.65,108.78 274.96,137.08 274.96,143 275.59,143.64 275.59,145.8 276.35,146.56 276.35,150.75 276.99,151.38 276.99,153.92 v1(277.88,154.81)
TDMA_RXD: length 259.2
  TOP w0.127: J11.13 280.65,154.28 279.4,153.03 278.64,153.03 278,152.4 v1(276.48,152.4) ; U21.3 82.76,58.89 83.57,59.69 83.57,60.33 84.58,61.34 92.58,61.34 v1(93.73,60.2)
  L6SIG w0.102: v1(93.73,60.2) 94.62,59.31 95.63,59.31 95.89,59.05 97.92,59.05 98.93,60.07 102.11,60.07 103.95,61.91 114.74,61.91 125,72.17 162.24,72.17 162.47,72.17 169.27,78.97 169.27,89.09 170.88,90.7 170.88,95.19 180.53,104.84 190.06,104.84 194.31,109.09 246.46,109.09 274.57,137.21 274.57,143.13 275.21,143.76 275.21,145.8 275.97,146.56 275.97,151 276.48,151.51 v1(276.48,152.4)
TDMA_TCK_CLK9: length 240.6
  TOP w0.127: v1(106.17,49.02) 105.17,48.02 U24.3 ; v1(280.04,152.65) 280.39,153.01 J11.17
  L6SIG w0.102: v1(106.17,49.02) 106.17,50.67 107.19,51.69 107.89,51.69 126.54,70.34 160.72,70.34 164.07,70.34 171.2,77.47 171.2,87.95 172.87,89.62 172.87,94.18 181.49,102.81 191.58,102.81 195.33,106.55 248.24,106.55 279.78,138.09 279.78,148.08 279.62,148.24 279.62,152.24 v1(280.04,152.65)
TDMA_TSYNC: length 245.3
  TOP w0.127: v1(100.46,54.86) 100.46,52.7 99.89,52.14 U23.13 ; v1(279.27,154.81) 279.78,154.81 280.52,155.55 J11.9
  L6SIG w0.102: v1(279.27,154.81) 279.02,154.81 277.88,153.67 277.88,146.3 276.73,145.16 276.73,136.5 247.74,107.51 194.94,107.51 191.01,103.57 181.23,103.57 172.15,94.49 172.15,90.04 170.43,88.33 170.43,77.91 163.55,71.03 162.38,71.03 161.01,71.03 125.89,71.03 112.52,57.66 107.06,57.66 105.41,56.01 101.6,56.01 v1(100.46,54.86)
TDMA_TXD: length 250.3
  TOP w0.127: v1(279.65,155.57) 280.27,156.19 J11.7 ; U23.3 95.72,52.79 v1(96.39,53.47)
  L6SIG w0.102: v1(96.39,53.47) 96.39,54.48 98.21,56.3 105.19,56.3 107.06,58.17 112.59,58.17 125.68,71.26 161.1,71.26 161.1,71.26 163.4,71.26 170.18,78.04 170.18,88.46 171.89,90.17 171.89,94.62 181.1,103.82 190.82,103.82 194.82,107.82 247.47,107.82 276.35,136.71 276.35,145.29 277.37,146.3 277.37,153.67 279.27,155.57 v1(279.65,155.57)
TDMB_RCK_CLK10: length 234.5
  TOP w0.127: U24.13 109.98,47.37 v1(110.24,47.62) ; J11.29 v1(280.06,149.2)
  L6SIG w0.102: v1(280.06,149.2) 280.16,149.1 280.16,137.78 248.62,106.24 195.45,106.24 191.77,102.55 181.61,102.55 173.1,94.04 173.1,89.47 171.45,87.82 171.45,77.22 164.34,70.1 126.68,70.1 110.24,53.66 v1(110.24,47.62)
TDMB_RQ: length 265.7
  TOP w0.127: v1(275.46,150.88) 275.23,151.11 J11.24 ; U22.13 100.66,46.05 v1(100.84,46.23)
  L6SIG w0.102: v1(275.46,150.88) 275.46,146.81 274.83,146.18 274.83,144.02 272.67,141.86 271.4,141.86 269.75,140.21 269.75,134.67 245.38,110.3 193.74,110.3 189.29,105.85 180.17,105.85 169.86,95.55 169.86,91.21 168.28,89.62 168.28,79.5 161.86,73.09 124.14,73.09 114.24,63.18 101.79,63.18 100.33,61.72 92.33,61.72 89.66,59.05 89.66,58.29 90.04,57.91 90.81,57.91 92.08,56.64 92.08,52.7 93.6,51.18 93.6,46.1 93.98,45.72 96.01,45.72 96.52,46.23 v1(100.84,46.23)
TDMB_RSYNC: length 260.3
  TOP w0.127: v1(84.46,53.21) 84.03,52.79 U28.3 ; v1(275.46,153.16) 275.31,153.01 J11.18
  L6SIG w0.102: v1(275.46,153.16) 274.19,151.89 274.19,147.57 273.56,146.94 273.56,144.4 272.42,143.26 269.37,143.26 268.61,142.49 268.61,135.05 244.81,111.25 188.34,111.25 183.77,106.68 180.02,106.68 170.38,97.04 169.1,95.76 169.1,91.63 167.51,90.04 167.51,79.88 161.4,73.77 123.49,73.77 113.86,64.13 101.35,64.13 100.46,63.25 86.87,63.25 84.58,60.96 84.58,60.2 82.3,57.91 82.3,56.52 83.57,55.24 84.33,55.24 85.09,54.48 85.09,53.85 v1(84.46,53.21)
TDMB_RXD: length 243.9
  TOP w0.127: v1(279.15,151.76) 276.35,151.76 275.97,152.15 275.97,154.43 279.63,158.09 J11.1 ; U26.13 v1(107.32,53.46)
  L6SIG w0.102: v1(279.15,151.76) 279.02,151.64 279.02,148.21 279.4,147.83 279.4,138.22 248.05,106.87 195.2,106.87 191.39,103.06 181.43,103.06 172.64,94.27 172.64,92.8 172.64,89.77 170.94,88.07 170.94,77.66 163.85,70.57 162.19,70.57 162.19,70.57 160.82,70.57 160.82,70.57 126.32,70.57 109.21,53.46 v1(107.32,53.46)
TDMB_TCK_CLK11: length 227.5
  TOP w0.127: U27.3 105.06,59.98 v1(105.41,60.33) ; v1(275.46,142.88) 278.13,142.88 279.4,144.15 279.4,145.03 280.39,146.03 J11.39
  L6SIG w0.102: v1(105.41,60.33) 105.92,60.33 106.43,59.82 113.47,59.82 125.37,71.71 161.29,71.71 162.9,71.71 169.72,78.54 169.72,88.76 171.39,90.42 171.39,94.87 180.85,104.33 190.43,104.33 194.55,108.46 246.97,108.46 275.46,136.95 v1(275.46,142.88)
TDMB_TSYNC: length 262.1
  TOP w0.127: v1(94.49,45.09) 94.49,45.34 94.87,45.72 94.87,46.35 94.53,46.7 U22.3 ; J11.22 275.36,151.74 v1(275.46,151.64)
  L6SIG w0.102: v1(94.49,45.09) 93.85,45.09 92.96,45.97 92.96,51.05 91.44,52.58 91.44,56.64 90.55,57.53 89.92,57.53 89.28,58.17 89.28,59.31 92.2,62.23 100.33,62.23 101.6,63.5 114.11,63.5 123.92,73.32 141.13,73.32 141.13,73.31 161.71,73.31 168.02,79.63 168.02,89.75 169.61,91.34 169.61,95.62 180.1,106.11 189.1,106.11 193.61,110.62 245.19,110.62 269.37,134.79 269.37,140.46 271.14,142.24 272.42,142.24 274.45,144.27 274.45,146.56 274.96,147.07 274.96,151.13 v1(275.46,151.64)
TDMB_TXD: length 251.7
  TOP w0.127: v1(275.46,152.38) J11.20 ; U28.13 88.84,52.14 v1(89.54,52.83)
  L6SIG w0.102: v1(89.54,52.83) 88.77,53.59 88.77,59.44 92.08,62.74 100.46,62.74 101.54,63.82 113.98,63.82 123.71,73.54 161.55,73.54 167.77,79.76 167.77,89.88 169.35,91.46 169.35,95.69 170.47,96.81 180.03,106.36 188.91,106.36 193.48,110.93 245,110.93 268.99,134.92 268.99,141.86 269.37,142.24 270.13,142.24 270.51,142.62 272.29,142.62 273.94,144.27 273.94,146.56 274.57,147.19 274.57,151.49 v1(275.46,152.38)
TDMR1_INT_N: length 302.1
  TOP w0.127: v1(264.67,142.62) 264.8,142.75 267.46,142.75 267.97,143.26 270.76,143.26 271.25,143.74 R197.2 274.32,143.76 279.12,148.57 J11.31 ; U57.P11 v1(48.47,89.89)
  L6SIG w0.102: v1(48.47,89.89) 48.47,83.17 71.18,60.45 71.18,59.18 72.14,58.23 77.66,58.23 84.96,65.53 113.47,65.53 123.63,75.69 128.04,75.69 129.25,76.9 134.75,76.9 135.56,76.08 139.01,76.08 159.78,76.08 164.66,80.96 164.66,91.82 166.43,93.6 166.43,97.09 183.71,114.36 242.89,114.36 264.41,135.89 264.41,142.37 v1(264.67,142.62)
TDMR2_INT_N: length 302.4
  TOP w0.127: v1(265.05,141.86) 265.43,142.24 270.76,142.24 271.25,142.72 R198.2 273.81,142.75 279,147.93 J11.33 ; U57.P10 v1(47.47,89.89)
  L6SIG w0.102: v1(47.47,89.89) 47.47,83.72 70.8,60.39 70.8,59.05 71.95,57.91 77.85,57.91 85.09,65.15 113.54,65.15 123.76,75.37 128.18,75.37 129.45,76.64 134.62,76.64 135.41,75.85 138.92,75.85 159.93,75.85 164.91,80.84 164.91,91.63 166.69,93.41 166.69,96.96 183.77,114.05 243.08,114.05 265.05,136.02 v1(265.05,141.86)
TDMR_PRS_N: length 298.1
  TOP w0.127: v1(265.43,143.64) 267.46,143.64 268.1,144.27 270.74,144.27 R196.2 274.81,144.78 279.87,149.84 J11.27 ; U57.P12 v1(49.47,89.89)
  L6SIG w0.102: v1(265.43,143.64) 264.8,143.64 264.03,142.88 264.03,136.02 242.7,114.68 183.64,114.68 166.12,97.16 166.12,93.66 164.4,91.95 164.4,86.17 159.23,81 152.69,81 148.02,76.33 135.7,76.33 134.87,77.15 128.96,77.15 127.76,75.95 123.51,75.95 113.41,65.85 84.77,65.85 77.53,58.61 73.41,58.61 49.47,82.55 v1(49.47,89.89)
TDMR_RST_N: length 321.5
  TOP w0.127: U57.P8 v1(44.47,89.89) ; U40.7 252.73,143.26 254.76,141.22 v1(265.68,141.22) 270.76,141.22 271.25,141.71 R199.2 273.43,141.73 279,147.3 J11.35
  L6SIG w0.102: v1(44.47,89.89) 44.47,86.28 70.42,60.32 70.42,58.93 71.75,57.59 78.04,57.59 85.28,64.83 113.67,64.83 123.95,75.12 128.34,75.12 129.61,76.39 134.49,76.39 135.26,75.63 160.08,75.63 165.18,80.72 165.18,91.52 166.94,93.28 166.94,96.84 178.88,108.78 182.94,108.78 187.9,113.73 243.4,113.73 265.68,136.02 v1(265.68,141.22)
TDMR_SLP_N: length 297.3
  TOP w0.127: v1(264.8,144.27) 265.18,144.65 268.73,144.65 269.37,145.29 274.7,145.29 276.86,147.45 276.86,149.48 277.85,150.47 J11.25 ; U57.R14 v1(51.47,88.89)
  L6SIG w0.102: v1(51.47,88.89) 51.47,88.61 52.07,88.01 52.07,80.39 73.47,58.99 77.41,58.99 84.58,66.17 113.28,66.17 123.32,76.2 127.69,76.2 128.9,77.41 135.03,77.41 135.85,76.58 147.89,76.58 152.54,81.23 159.08,81.23 164.15,86.3 164.15,92.08 165.8,93.73 165.8,97.23 183.57,115 242.51,115 263.65,136.14 263.65,143.13 v1(264.8,144.27)
TDMR_SPI_CS0_N: length 206.9
  TOP w0.127: J11.32 272.18,148.57 v1(271.91,148.84) 271.53,149.22 R63.1 ; U1.M2 132.72,92.27 132.72,89.79 133.86,88.65 133.86,84.46 133.35,83.95 133.35,77.72 132.72,77.09 v1(132.72,75.18)
  L6SIG w0.102: v1(271.91,148.84) 271.91,148.72 271.53,148.34 271.53,145.67 271.14,145.29 269.37,145.29 267.84,143.76 267.84,135.32 244.41,111.89 188.21,111.89 183.52,107.19 179.77,107.19 168.59,96.01 168.59,92.01 167.01,90.42 167.01,80.26 161.02,74.28 133.62,74.28 v1(132.72,75.18)
TDMR_SPI_CS1_N: length 209.7
  TOP w0.127: R62.1 271.5,147.95 v1(272.16,147.95) 272.18,147.93 J11.34 ; U1.M3 131.95,93 131.95,89.15 133.1,88.01 133.1,84.96 131.7,83.57 131.7,77.22 130.81,76.33 130.81,75.37 v1(131.13,75.06)
  L6SIG w0.102: v1(272.16,147.95) 272.16,145.29 271.14,144.27 269.24,144.27 268.22,143.26 268.22,135.19 268.07,135.04 268.07,135.03 244.61,111.57 188.28,111.57 183.64,106.93 179.9,106.93 168.85,95.89 168.85,91.82 167.26,90.23 167.26,80.07 161.24,74.05 133.08,74.05 132.08,75.06 v1(131.13,75.06)
TEMP_DIODE_N: length 10.2
  TOP w0.305: U1.G21 v2(127.97,108.22)
  BOTTOM w0.127: 124.14,108.27 124.21,108.33 126.24,108.33 126.75,107.82 127.33,107.82 127.33,107.82 127.51,107.82 127.9,108.22 v2(127.97,108.22)
  BOTTOM w0.254: R194.1 119.35,108.84 122.49,108.84 123.06,108.27 124.14,108.27
TEMP_DIODE_P: length 9.2
  TOP w0.305: U1.E21 v2(127.17,108.22)
  BOTTOM w0.127: v2(127.17,108.22) 126.73,108.22 126.37,108.58 124.21,108.58 124.14,108.65
  BOTTOM w0.254: 124.14,108.65 123.25,108.65 122.68,109.22 119.51,109.22 119.13,109.6 R193.1
TEST_SEL_N: length 150.1
  TOP w0.127: U57.E16 v1(53.85,99.39) 54.55,99.39 55.5,100.33 55.5,119.63 54.86,120.27 54.86,124.59 57.28,127 66.68,127 68.45,128.78 68.45,130.68 69.6,131.83 79.25,131.83 80.26,130.81 SW3.8 ; U1.G8 v2(127.97,97.02)
  L6SIG w0.102: v1(53.85,99.39) 55.19,99.39 63.82,108.01 77.28,108.01 77.91,108.65 99.87,108.65 116.8,91.72 117.32,91.72 118.49,90.55 124.71,90.55 125.98,91.82 125.98,93.17 126.25,93.44 126.58,93.44 126.79,93.64 126.79,93.97 127.01,94.2 127.39,94.2 127.57,94.38 127.57,96.71 127.88,97.02 v2(127.97,97.02)
  BOTTOM w0.127: v1(53.85,99.39) 53.93,99.47 R92.1
THERM_ALERT_N: length 124.2
  TOP w0.127: U57.C3 v1(39.47,101.88)
  L3SIG w0.102: v1(112.01,115.7) 111.38,115.06 111.38,110.29 v1(109.88,108.79)
  L6SIG w0.102: v1(112.01,115.7) 109.79,117.92 109.79,121.6 95.89,135.51 56.77,135.51 56.45,135.83 50.99,135.83 43.31,128.14 43.31,108.58 38.93,104.2 38.93,102.43 v1(39.47,101.88)
  BOTTOM w0.127: R192.1 112.27,109.09 111.94,108.77 U34.6 109.9,108.77 v1(109.88,108.79)
THERM_FAULT_N: length 126.6
  TOP w0.127: U57.F3 v1(40.45,98.87)
  L3SIG w0.102: v1(113.54,108.14) 112.2,109.47 v1(112.2,114.87)
  L6SIG w0.102: v1(40.45,98.87) 39.94,99.38 39.94,103.25 43.62,106.93 43.62,128.02 51.05,135.45 56.39,135.45 56.64,135.19 95.76,135.19 109.47,121.48 109.47,117.6 v1(112.2,114.87)
  BOTTOM w0.127: U34.4 113.56,108.12 v1(113.54,108.14) 113.28,108.39 R195.1
UART1_CTS_N: length 69.2
  TOP w0.127: v1(139.57,85.53) 140.08,85.03 140.08,71.5 128.4,59.82 119.63,59.82 113.79,53.98 113.79,44.58 115.94,42.43 U29.9 ; v1(139.32,87.25) 138.9,87.67 138.9,88.48 139.19,88.77 139.19,92.2 138.78,92.62 U1.Y2
  L6SIG w0.102: v1(139.32,87.25) 139.57,87 v1(139.57,85.53)
UART1_RTS_N: length 68.1
  TOP w0.127: U29.10 115.29,42.44 113.41,44.32 113.41,54.36 119.38,60.33 128.14,60.33 139.57,71.75 v1(139.57,84.84) ; v1(138.43,87.88) 138.43,88.77 138.77,89.11 U1.Y1
  L6SIG w0.102: v1(138.43,87.88) 138.43,87.5 139.14,86.79 139.14,85.27 v1(139.57,84.84)
UART1_RXD: length 67.7
  TOP w0.127: U29.12 113.99,42.35 112.65,43.69 112.65,54.74 119.32,61.4 128.08,61.4 138.68,72.01 138.68,85.85 139.79,86.96 139.79,88.56 139.57,88.78 U1.AA1
UART1_TXD: length 68.8
  TOP w0.127: U29.11 114.64,42.46 113.03,44.07 113.03,54.48 119.38,60.83 128.14,60.83 139.07,71.75 139.07,85.72 140.21,86.87 140.21,88.77 139.95,89.03 139.95,92.2 139.57,92.59 U1.AA2
UART2_CTS_N: length 73.7
  TOP w0.127: v1(138.68,86.49) 138.3,86.11 138.3,72.26 127.95,61.91 119.32,61.91 112.27,54.86 112.27,44.37 110.82,42.93 107.95,42.93 107.56,42.53 U30.9 ; U1.Y4 v2(139.17,93.82)
  L3SIG w0.102: v2(139.17,93.82) 139.57,93.41 139.57,88.87 139.83,88.62 139.83,87.12 139.19,86.49 v1(138.68,86.49)
UART2_RTS_N: length 73.7
  TOP w0.127: U30.10 106.91,42.52 107.7,43.31 110.74,43.31 111.89,44.45 111.89,55.12 119.13,62.36 127.64,62.36 137.92,72.64 v1(137.92,87.25) ; U1.V4 v2(137.57,93.82)
  L3SIG w0.102: v2(137.57,93.82) 137.97,93.41 137.97,92.84 138.18,92.63 138.53,92.63 138.79,92.38 138.79,89.76 138.48,89.46 138.48,88.67 138,88.19 138,87.33 v1(137.92,87.25)
UART2_RXD: length 74.1
  TOP w0.127: U1.W4 v2(138.37,93.82) ; v1(137.41,85.79) 137.41,83.88 136.91,83.38 136.91,72.9 127.25,63.25 118.87,63.25 111.13,55.5 111.13,44.83 110.21,43.92 106.91,43.92 105.61,42.62 U30.12
  L3SIG w0.102: v1(137.41,85.79) 137.41,85.98 138.86,87.43 138.86,88.32 139.17,88.62 139.17,92.42 138.76,92.82 138.76,93.42 v2(138.37,93.82)
UART2_TXD: length 74.3
  TOP w0.127: v1(137.41,77.28) 137.41,72.77 127.38,62.74 119,62.74 111.51,55.25 111.51,44.6 110.52,43.61 107.24,43.61 106.26,42.63 U30.11 ; U1.AA4 v2(139.97,93.82)
  L3SIG w0.102: v1(137.41,77.28) 140.53,80.39 140.53,91 140.38,91.14 140.38,93.4 v2(139.97,93.82)
UC1_CDBRXER: length 2.4
  TOP w0.127: U26.4 v1(104.39,53.46)
  BOTTOM w0.127: R240.2 103.98,53.87 v1(104.39,53.46)
UC1_CTS_N: length 12.5
  TOP w0.127: U21.12 87.83,57.59 90.17,55.24 93.47,55.24 95.16,56.94 U39.11
UC1_RTS_N: length 11.5
  TOP w0.127: v1(96.77,51.49) U23.12 ; U39.14 95.72,58.89 95.38,58.55 v1(95.38,58.42)
  L6SIG w0.102: v1(96.77,51.49) 95.89,52.38 95.89,57.91 v1(95.38,58.42)
UC1_RXD: length 12.8
  TOP w0.127: U21.4 82.75,58.24 84.07,59.56 84.07,60.13 84.9,60.96 87.88,60.96 89.31,59.54 U39.2
UC1_TXD: length 8.7
  TOP w0.127: v1(92.96,57.4) 92.78,57.59 U39.5 ; v1(94.23,52.2) 94.18,52.14 U23.4
  L6SIG w0.102: v1(92.96,57.4) 93.22,57.15 93.22,53.21 v1(94.23,52.2)
UC3_CDBRXER: length 2.4
  TOP w0.127: U22.12 97.1,45.39 v1(97.03,45.47)
  BOTTOM w0.127: R239.2 96.77,45.72 v1(97.03,45.47)
UC3_CTS_N: length 17.4
  TOP w0.127: U39.10 95.4,56.29 v1(95.38,56.26) ; U28.4 v1(83.75,52.14)
  BOTTOM w0.127: v1(83.75,52.14) 84.27,52.14 85.47,53.34 85.47,54.48 87.25,56.26 v1(95.38,56.26)
UC3_RTS_N: length 16
  TOP w0.127: v1(94.23,46.23) 94.05,46.05 U22.4 ; v1(94.87,57.4) 95.38,57.4 96.21,58.24 U39.13
  L6SIG w0.102: v1(94.23,46.23) 95.38,47.37 95.38,51.05 94.87,51.56 v1(94.87,57.4)
UC3_RXD: length 21.1
  TOP w0.127: U39.3 92.75,58.89 v1(93.09,58.55) ; U26.12 107.08,52.81 106.68,53.21 v1(106.68,55.63)
  BOTTOM w0.127: v1(93.09,58.55) 94.36,58.55 95,57.91 104.39,57.91 v1(106.68,55.63)
UC3_TXD: length 9.2
  TOP w0.127: v1(89.41,51.69) 89.21,51.49 U28.12 ; v1(89.92,56.9) 89.96,56.94 U39.6
  L6SIG w0.102: v1(89.92,56.9) 89.28,56.26 89.28,53.85 90.04,53.09 90.04,52.32 v1(89.41,51.69)
USB1_DM: length 11.9
  TOP w0.127: J5.6 68.65,12.01 68.88,12.23 68.88,12.87 69.47,13.46 70.61,13.46 71.11,13.96 71.11,17.92 v1(70.99,18.03) 70.99,18.42 70.74,18.67 70.74,19.18 70.9,19.33 L1.2 70.9,20.44 R163.2
  BOTTOM w0.127: U20.6 70.62,18.4 v1(70.99,18.03)
USB1_DP: length 12.7
  TOP w0.127: J5.7 69.4,12.01 69.16,12.25 69.16,12.75 69.58,13.18 70.73,13.18 71.39,13.84 71.39,17.79 71.5,17.91 71.5,18.42 71.88,18.8 v1(71.88,19.3) 71.6,19.59 L1.3 71.6,20.44 R162.2
  BOTTOM w0.127: U20.4 71.64,19.55 v1(71.88,19.3)
USB1_FLG_N: length 9.5
  TOP w0.127: v1(62.99,31.62) 62.98,31.62 62.86,31.75 U19.9 ; R151.2 v1(66.55,33.4) R153.1 67.21,33.43 67.69,33.91 69.65,33.91 Q4.1
  BOTTOM w0.127: v1(66.55,33.4) 64.77,31.62 v1(62.99,31.62)
USB1_PWREN: length 109.4
  TOP w0.127: v1(65.84,38.18) 65.28,38.73 64.14,38.73 63.88,38.48 63.88,37.47 63.4,36.98 R157.2 62.86,36.47 U19.2 ; U1.F6 v2(127.17,95.42)
  L3SIG w0.102: v1(65.84,38.18) 68.71,35.31 72.77,35.31 73.15,35.69 73.15,39.12 75.06,41.02 75.06,50.86 75.92,51.72 75.92,52.3 78.61,54.99 78.61,59.44 82.42,63.25 85.85,63.25 89.41,66.8 106.43,66.8 126.11,86.49 126.11,90.93 125.98,91.06 125.98,93.14 125.99,93.14 125.99,93.17 126.21,93.4 126.49,93.4 126.77,93.68 126.77,95.02 v2(127.17,95.42)
USB1_VBUS: length 7.1
  TOP w0.508: 66.74,15.49 66.74,13.96
  TOP w1.016: FB1.1 66.74,18.53 66.74,15.49 ; 66.74,13.96 66.74,13.23 J5.5
USB1_VBUSCLMP: length 101.9
  TOP w0.127: v1(72.52,35.81) 72.52,31.62 71.65,30.76 R161.2 R158.1 69.06,30.76 D3.2 ; U1.E4 v2(126.37,93.82)
  L3SIG w0.102: v2(126.37,93.82) 126.11,93.82 125.72,93.44 125.45,93.44 125.19,93.17 125.19,86.13 106.24,67.18 89.15,67.18 85.6,63.63 82.17,63.63 78.11,59.56 78.11,55.12 75.44,52.45 75.44,51.82 74.04,50.42 74.04,40.64 72.52,39.12 v1(72.52,35.81)
USB2_DM: length 7.9
  TOP w0.127: J5.2 68.6,14.63 68.82,14.85 68.82,17.67 68.55,17.93 68.55,19.08 v1(68.33,19.3) 68.61,19.59 L2.2 68.61,20.44 R165.2
  BOTTOM w0.127: v1(68.33,19.3) 68.57,19.55 U20.3
USB2_DP: length 7.7
  TOP w0.127: R164.2 69.31,20.44 L2.3 69.31,19.78 68.83,19.3 68.83,18.29 v1(69.09,18.03) 69.1,18.02 69.1,14.85 69.32,14.63 J5.3
  BOTTOM w0.127: v1(69.09,18.03) 69.08,18.05 U20.1
USB2_FLG_N: length 9.6
  TOP w0.127: U19.7 61.86,31.75 61.73,31.62 v1(61.72,31.62) ; R152.1 v1(66.55,34.42) R155.2 65.89,35.59 Q5.1
  BOTTOM w0.127: v1(66.55,34.42) 64.26,32.13 62.74,32.13 62.23,31.62 v1(61.72,31.62)
USB2_PWREN: length 113.1
  TOP w0.127: U1.J5 v2(129.57,94.62) ; v1(60.58,37.59) 60.58,37.21 60.81,36.98 R156.2 61.86,36.47 U19.4
  L3SIG w0.102: v2(129.57,94.62) 129.54,94.62 129.16,94.23 129.16,93.62 128.93,93.4 128.61,93.4 128.39,93.17 128.39,87.3 106.74,65.66 90.17,65.66 86.49,61.98 83.06,61.98 80.01,58.93 80.01,53.72 76.45,50.16 76.45,38.99 74.8,37.34 74.8,36.07 73.03,34.29 70.1,34.29 69.47,34.92 68.2,34.92 65.79,37.34 60.83,37.34 v1(60.58,37.59)
USB2_VBUS: length 4.8
  TOP w1.016: J5.1 65.34,14.8 65.34,17.59 64.77,18.16 FB3.1
USB2_VBUSCLMP: length 116.2
  TOP w0.127: U1.J4 v2(129.57,93.82) ; D2.2 57.3,27.53 R154.1 R160.2 57.3,31.39 v1(58.29,32.39)
  L3SIG w0.102: v1(58.29,32.39) 58.8,32.89 63.88,32.89 64.9,33.91 73.79,33.91 75.44,35.56 75.44,37.34 78.11,40.01 78.11,45.59 80.14,47.62 80.14,51.05 80.52,51.44 80.52,57.02 84.96,61.47 86.49,61.47 90.3,65.28 106.87,65.28 128.92,87.33 128.92,92.64 129.15,92.86 129.15,93.18 129.57,93.6 v2(129.57,93.82)
USB_REFCLK: length 104
  TOP w0.127: R489.2 R490.2 v1(39.85,117.47) ; U1.F8 v2(127.17,97.02)
  BOTTOM w0.127: v2(127.17,97.02) 127.56,97.41 127.8,97.41 127.8,97.41 128.14,97.41 128.37,97.64 128.37,102.13 127.89,102.62 123.95,102.62 123.57,103 117.48,103 115.19,105.28 108.33,105.28 105.09,108.52 60.26,108.52 57.02,111.76 43.94,111.76 39.85,115.85 v1(39.85,117.47)
VCORE: length 108.8
  TOP w0.305: U1.V13 v2(137.57,101.02) ; U1.M13 v2(131.97,101.02) ; U1.Y8 v2(139.17,97.02) ; U1.U18 v2(136.77,105.82) ; U1.N14 v2(132.77,101.82) ; U1.L20 v2(131.17,107.42) ; U1.V15 v2(137.57,103.42) ; U1.R12 v2(135.17,100.22) ; U1.M9 v2(131.97,97.82) ; U1.M19 v2(131.97,106.62) ; U1.K15 v2(130.37,103.42) ; U1.P11 v2(133.57,99.42) ; U1.R18 v2(135.17,105.82) ; U1.U20 v2(136.77,107.42) ; U1.T17 v2(135.97,105.02) ; U1.K19 v2(130.37,106.62) ; U1.N20 v2(132.77,107.42) ; U1.Y9 v2(139.17,97.82) ; U1.N18 v2(132.77,105.82) ; U1.U14 v2(136.77,101.82) ; U1.T9 v2(135.97,97.82) ; U1.L14 v2(131.17,101.82) ; U1.W14 v2(138.37,101.82) ; U1.L12 v2(131.17,100.22) ; U1.N16 v2(132.77,104.22) ; U1.U16 v2(136.77,104.22) ; U1.M15 v2(131.97,103.42) ; U1.N12 v2(132.77,100.22) ; U1.T19 v2(135.97,106.62) ; U1.P13 v2(133.57,101.02) ; U1.K17 v2(130.37,105.02) ; U1.V9 v2(137.57,97.82) ; U1.V19 v2(137.57,106.62) ; U1.Y11 v2(139.17,99.42) ; U1.T13 v2(135.97,101.02) ; U1.P15 v2(133.57,103.42) ; U1.R14 v2(135.17,101.82) ; U1.P17 v2(133.57,105.02) ; U1.L18 v2(131.17,105.82) ; U1.V17 v2(137.57,105.02) ; U1.R20 v2(135.17,107.42) ; U1.P19 v2(133.57,106.62) ; U1.L16 v2(131.17,104.22) ; U1.P9 v2(133.57,97.82) ; U1.M17 v2(131.97,105.02) ; U1.R16 v2(135.17,104.22) ; U1.T15 v2(135.97,103.42)
  L3SIG w0.508: 123.95,103.89 122.56,103.89 121.79,104.65 121.79,107.7 114.94,114.55 114.94,116.59 109.73,121.79 107.57,121.79 94.62,134.75 87.12,134.75 74.42,147.45 64.9,147.45 63.37,148.97
  vias: v2(137.57,99.41) v3(97.54,107.19) v3(97.54,105.92) v3(97.54,104.65) v3(97.54,102.11) v3(97.54,100.84) v3(97.54,99.57) v3(97.54,98.3) v3(97.54,97.03) v3(98.43,107.19) v3(98.43,105.92) v3(98.43,104.65) v3(98.43,103.38) v3(98.43,102.11) v3(98.43,100.84) v3(98.43,99.57) v3(98.43,98.3) v3(98.43,97.03) v3(99.31,107.19) v3(99.31,105.92) v3(99.31,104.65)
VCORE_EN: length 25
  TOP w0.127: U60.16 68.33,99.44 67.95,99.82 67.44,99.82 67.06,100.2 R538.2 C846.2 63.53,100.48 61.98,98.93 61.98,97.41 58.67,94.11 58.67,93.22 56.39,90.93 50.51,90.93 U57.P13
VCORE_PGOOD: length 41.5
  TOP w0.127: U60.3 66.01,97.53 65.89,97.41 v1(64.64,97.41) ; U57.J3 v1(39.47,94.89)
  L6SIG w0.102: v1(64.64,97.41) 60.96,97.41 59.94,96.39 59.94,89.28 58.29,87.63 54.93,87.63 52.96,89.6 52.96,90.11 52.45,90.61 43.5,90.61 41.72,92.39 41.28,92.39 40.96,92.71 40.96,93.15 39.47,94.65 v1(39.47,94.89)
  BOTTOM w0.127: R539.2 64.62,97.38 v1(64.64,97.41)
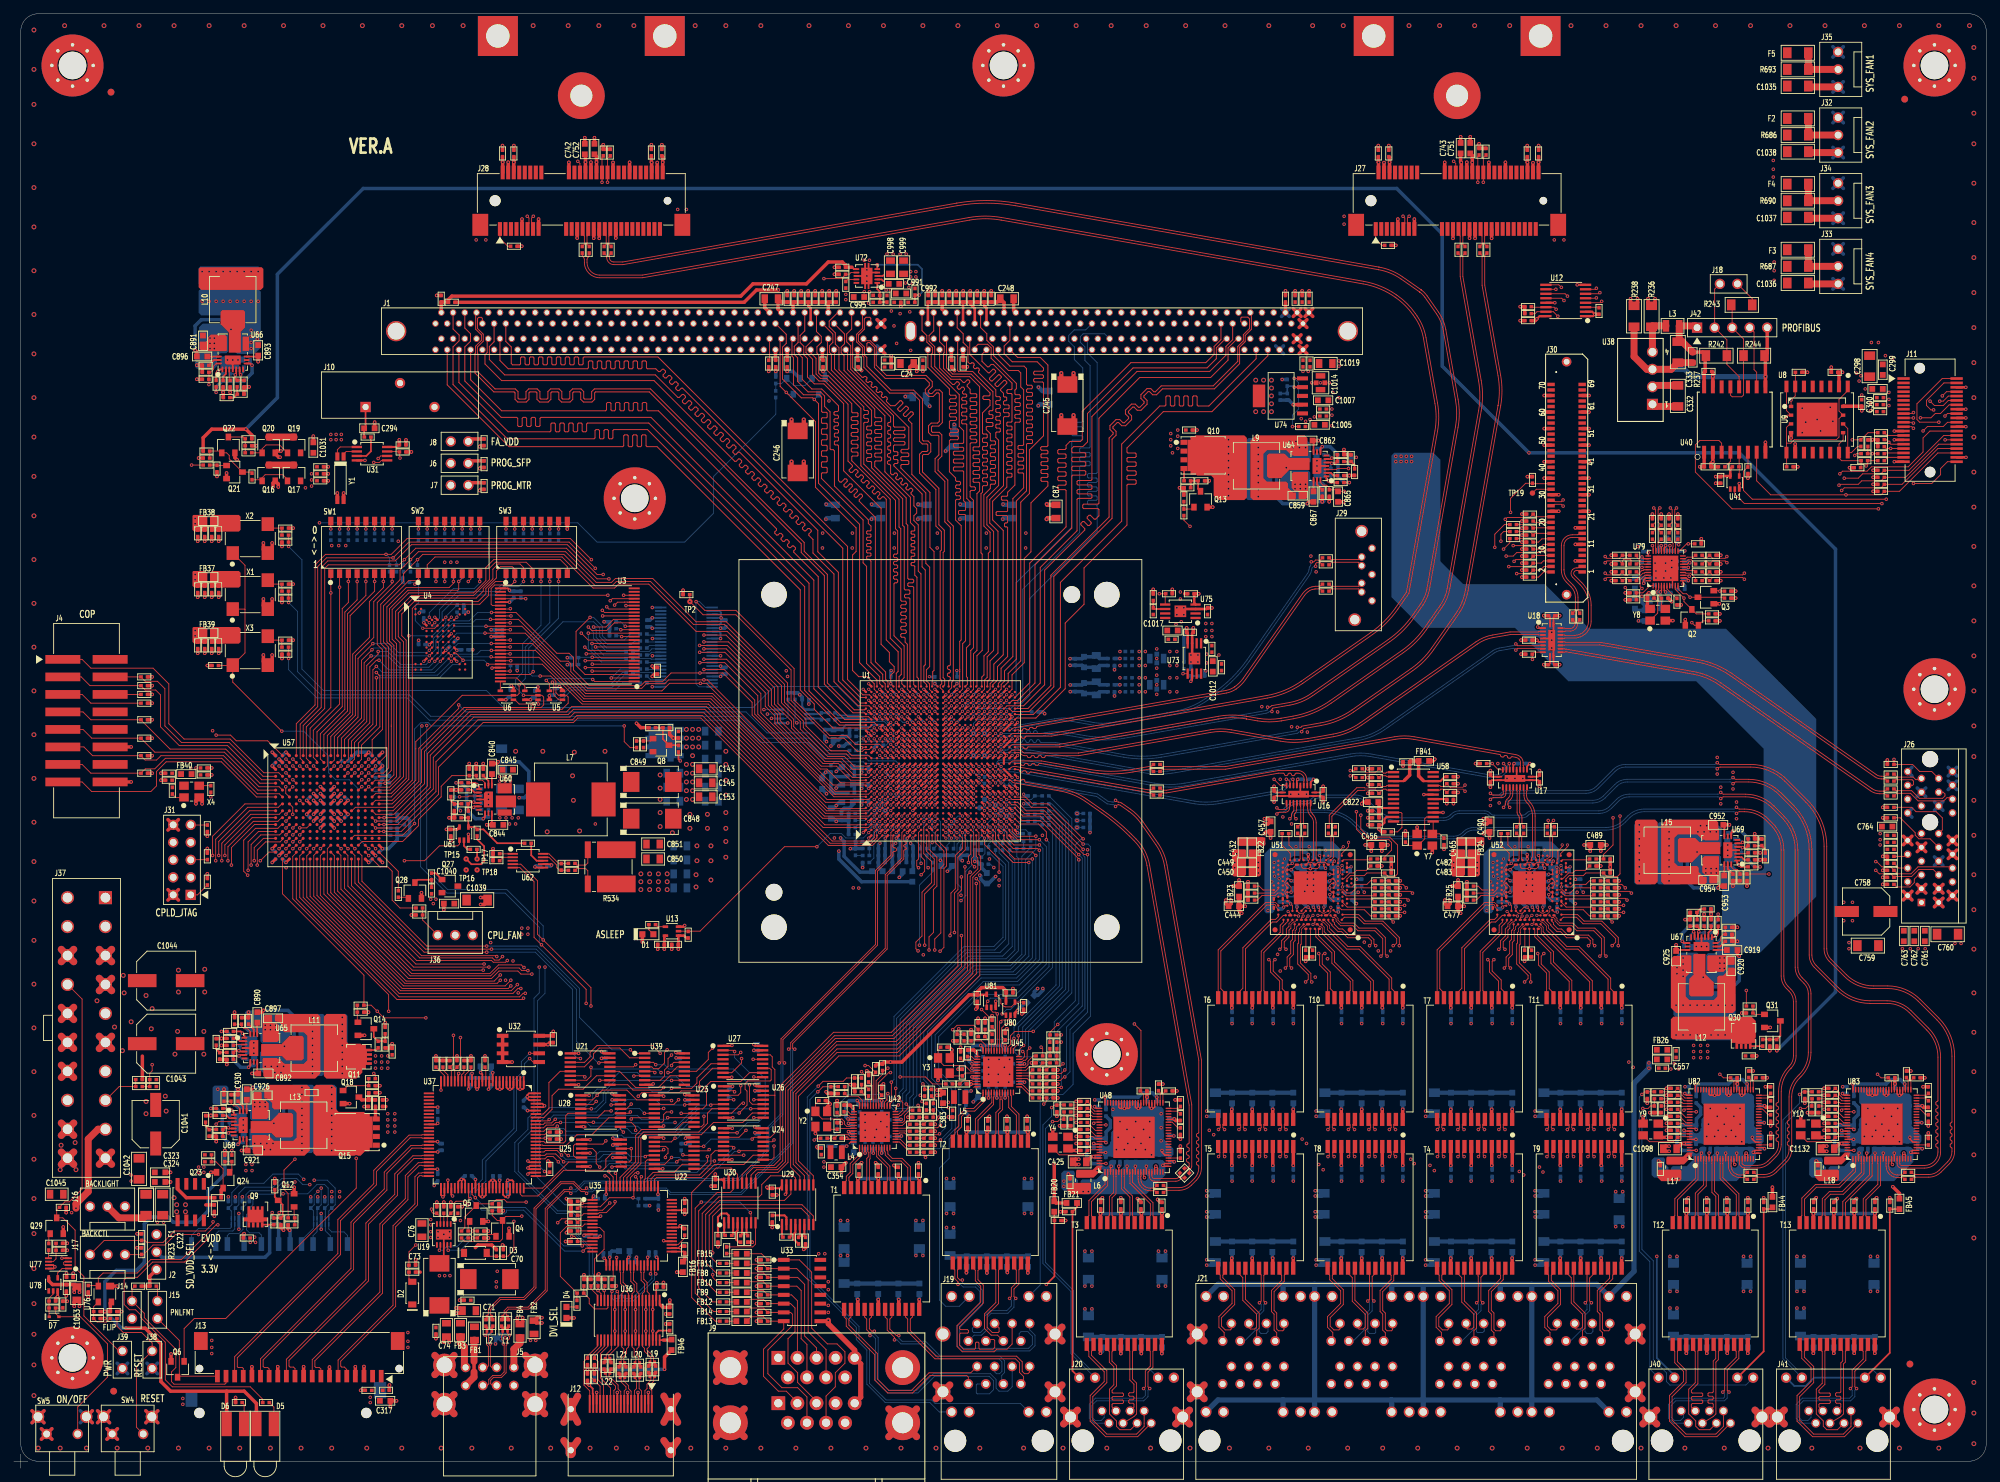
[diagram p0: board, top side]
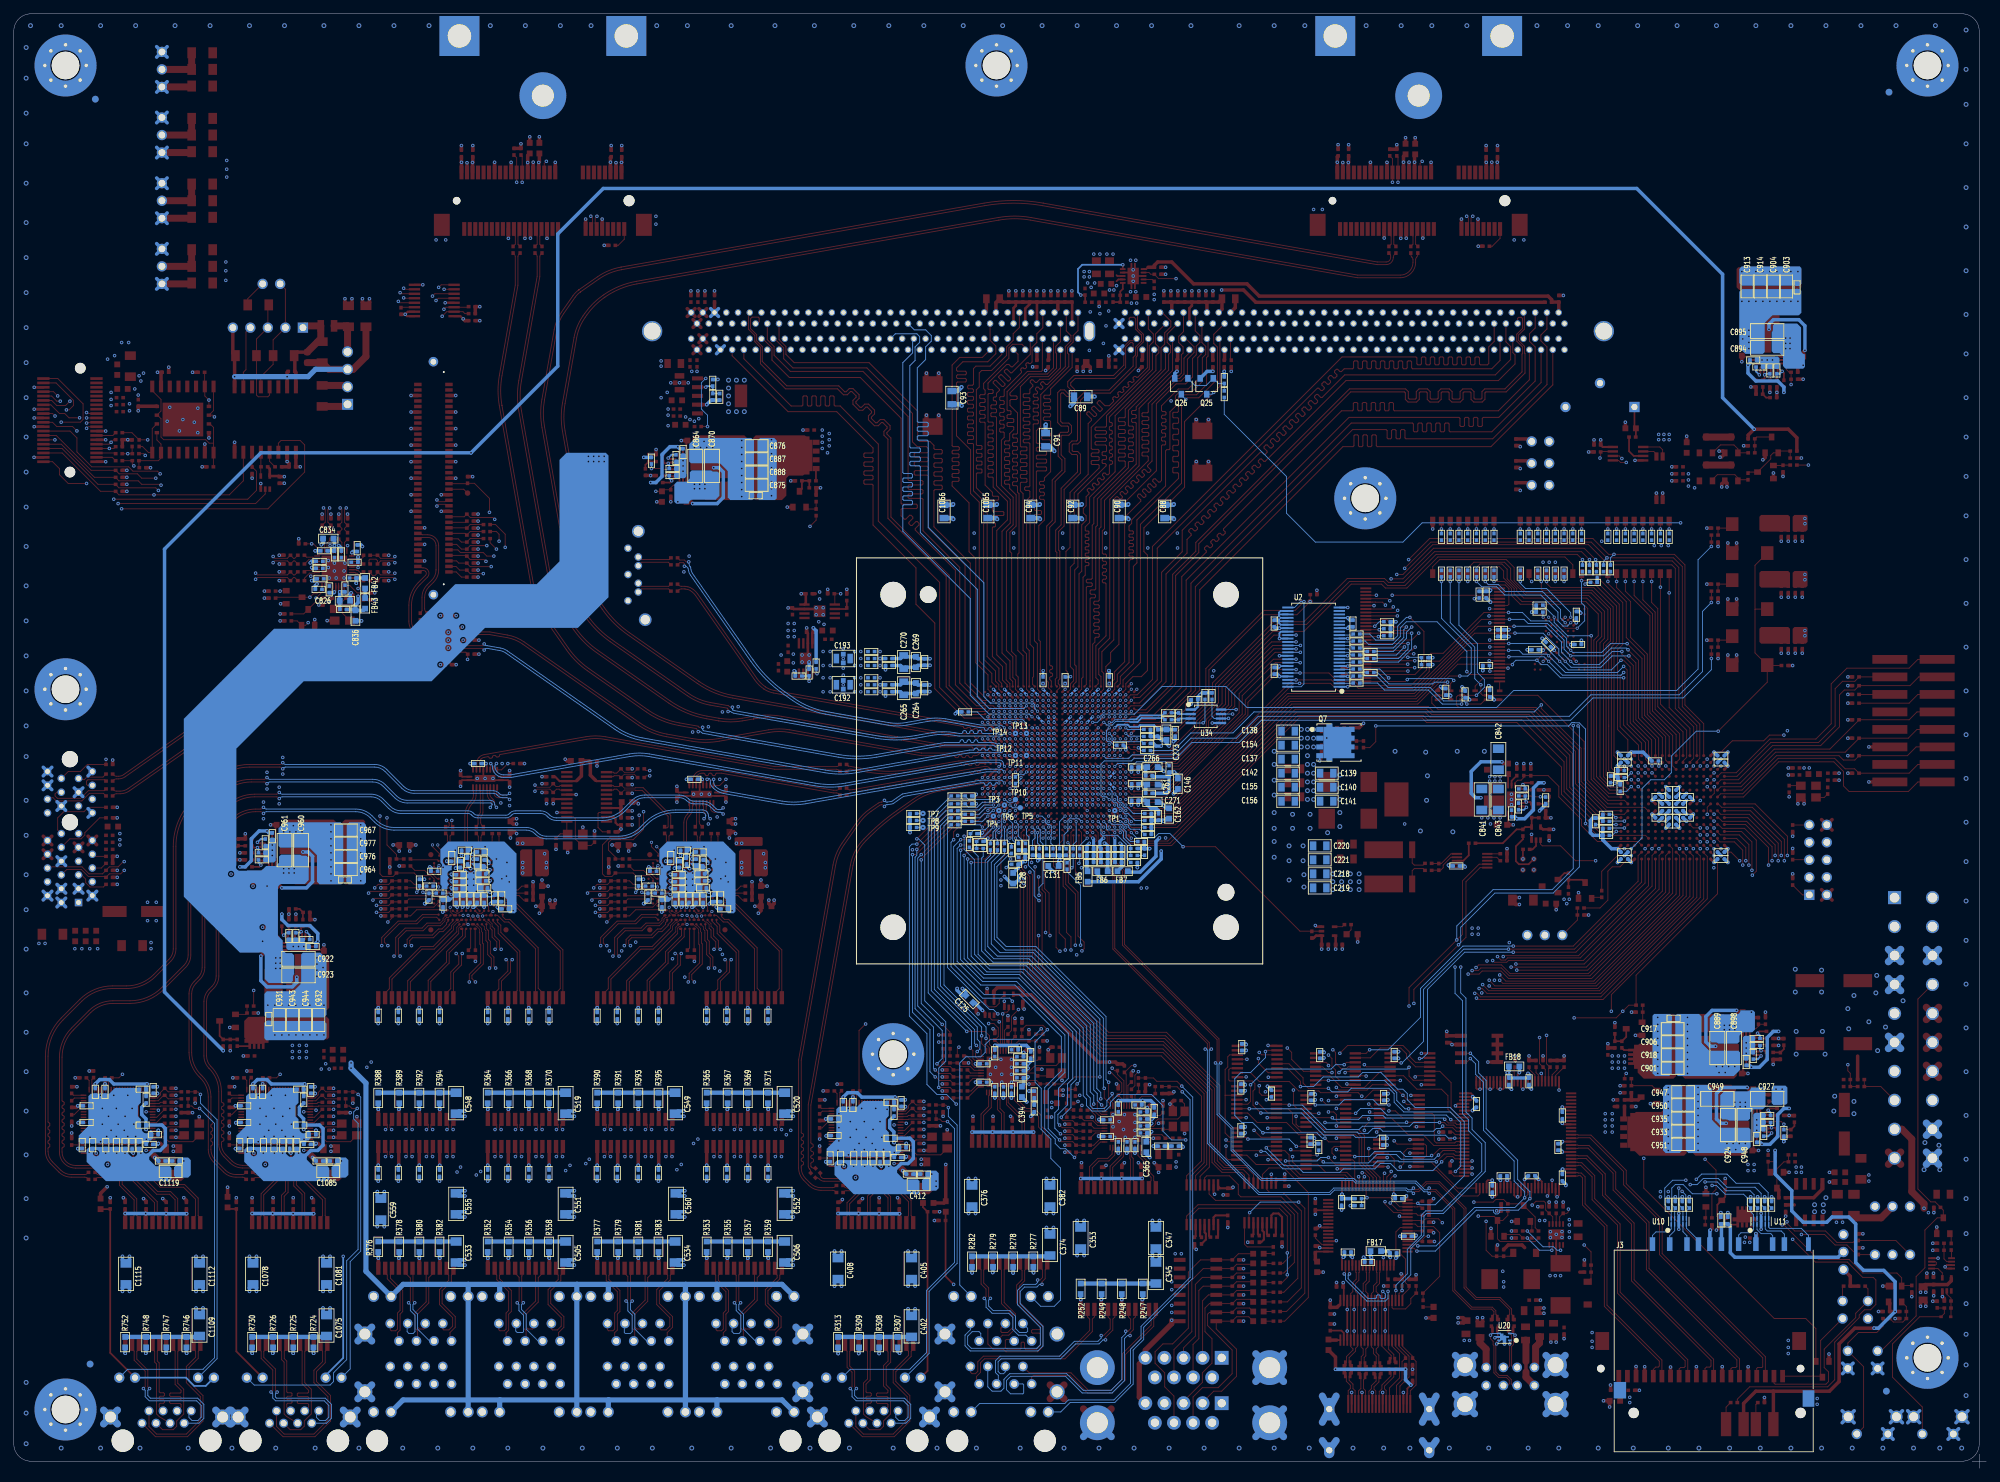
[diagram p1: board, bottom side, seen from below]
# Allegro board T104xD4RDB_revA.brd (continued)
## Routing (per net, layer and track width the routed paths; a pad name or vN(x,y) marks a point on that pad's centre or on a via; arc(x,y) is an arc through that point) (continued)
VCORE_SLP: length 20
  TOP w0.305: U1.M11 v2(131.97,99.42) U1.L10 ; U1.V11 v2(136.77,100.22) U1.U12 ; U1.N10 v2(132.77,98.62) ; U1.K13 v2(130.37,101.02) ; U1.R10 v2(135.17,98.62) ; U1.U10 v2(136.77,98.62) ; U1.K11 v2(130.37,99.42) ; U1.W10 v2(138.37,98.62) ; U1.T11 v2(135.97,99.42) ; U1.W12 v2(138.37,100.22)
  BOTTOM w0.508: v1(119.63,89.53) 119.63,88.39 122.94,85.09 FB5.2
  vias: v3(90.93,86.23) v3(90.93,85.09) v3(90.93,83.95) v3(92.2,86.23) v3(92.2,85.09) v3(92.2,83.95) v3(93.47,86.23) v3(93.47,85.09) v3(93.47,83.95) v3(94.74,86.23) v3(94.74,85.09) v3(94.74,83.95)
VPP: length 16
  TOP w0.508: 185.53,164.44 J1.142 ; J1.142 186.66,164.44 ; J1.142 185.53,163.31 ; J1.142 186.66,163.31 ; J1.143 187.51,162.84 ; J1.143 186.38,161.71 ; J1.143 186.38,162.84 ; J1.143 187.51,161.71 ; 186.38,166.64 J1.287 ; J1.287 187.51,165.51 ; J1.287 186.38,165.51 ; J1.287 187.51,166.64 ; J1.288 188.36,167.11 ; J1.288 187.23,168.24 ; J1.288 188.36,168.24 ; J1.288 187.23,167.11 ; 185.53,168.24 J1.286 ; J1.286 185.53,167.11 ; J1.286 186.66,167.11 ; J1.286 186.66,168.24
VPP_EN: length 211.1
  TOP w0.127: U74.5 v1(185.67,158.12) ; U57.R10 47.43,88.92 47.43,84.01 58.29,73.15 v1(68.2,73.15) ; R648.1 v1(185.42,151.13)
  L6SIG w0.102: v1(68.2,73.15) 72.58,73.15 73.22,73.79 111.95,73.79 120.78,82.61 128.28,82.61 129.74,84.07 137.8,84.07 138.75,83.12 145.29,83.12 149.16,87 155.83,87 157.45,88.62 157.45,98.71 183.26,124.52 183.26,148.97 v1(185.42,151.13)
  BOTTOM w0.127: v1(185.67,158.12) 186.31,157.48 186.31,153.67 185.42,152.78 v1(185.42,151.13)
VTT: length 12.2
  TOP w0.254: 126.11,173.1 125.98,172.97 U72.3
  TOP w0.508: 126.31,161.71 J1.77 126.31,162.84 ; 125.18,165.51 J1.221 ; J1.221 126.31,166.64 ; J1.221 126.31,165.51 ; J1.221 125.18,166.64
  BOTTOM w0.508: 125.18,162.84 J1.77 ; J1.77 125.18,161.71 ; J1.77 126.31,162.84 ; J1.77 126.31,161.71 ; J1.221 126.31,165.51 ; J1.221 125.18,166.64 ; J1.221 125.18,165.51 ; J1.221 126.31,166.64
  vias: v1(127.25,167.89) v1(127.64,165.74) v1(128.02,163.19) v1(128.52,167.51) v1(129.92,167.77) v1(130.05,173.61) v1(130.05,172.85) v1(130.05,162.18) v1(130.81,173.61) v1(130.81,172.85)
VTT_EN: length 190.1
  TOP w0.127: v1(117.48,172.59) 120.02,172.59 120.62,173.2 R642.1 121.16,173.23 121.41,173.48 122.19,173.48 U72.7 ; U57.D3 v1(39.47,100.88)
  L3SIG w0.102: v1(117.48,172.59) 116.84,173.23 44.58,173.23 39.75,178.05 25.27,178.05 22.73,175.51 22.73,109.6 31.45,100.88 v1(39.47,100.88)
XVDD: length 3.8
  TOP w0.305: U1.AC21 v2(141.57,108.22) ; U1.AC15 v2(141.57,103.42) ; U1.AC9 v2(141.57,97.82) ; U1.AC18 v2(141.57,105.82) ; U1.AC12 v2(141.57,100.22)
  BOTTOM w0.508: R146.1 149.23,109.73 v1(149.48,109.47)
  vias: v1(163.2,118.49) v1(163.2,117.47) v1(163.2,116.46) v1(164.08,118.49) v1(164.08,116.46)
XVDD_EN: length 172.8
  TOP w0.127: v1(166.12,126.87) R650.1 166.96,126.81 U75.5 ; U57.R11 48.45,88.9 48.45,84.45 58.86,74.04 69.41,74.04 69.72,73.72 70.36,73.72 v1(70.87,74.23)
  L6SIG w0.102: v1(166.12,126.87) 166.12,122.05 170.12,118.05 170.12,112.27 156.91,99.06 156.91,88.84 155.58,87.5 148.91,87.5 145.03,83.63 139,83.63 138.05,84.58 129.49,84.58 128.03,83.12 120.46,83.12 111.76,74.42 71.06,74.42 v1(70.87,74.23)
N16747459: length 0.6
  TOP w0.14: U1.U28 v2(136.77,113.82)
N16747463: length 0.6
  TOP w0.14: U1.P28 v2(133.57,113.82)
N16770065: length 4.3
  TOP w0.305: U1.F20 v2(127.17,107.42)
  BOTTOM w0.127: R4.2 126.49,104.9 127,105.41 127.38,105.41 127.57,105.6 127.57,107.01 v2(127.17,107.42)
N16800565: length 2.2
  TOP w0.127: U3.53 v1(71.97,115.65)
  BOTTOM w0.127: R52.1 72.03,115.72 v1(71.97,115.65)
N16800570: length 2.7
  TOP w0.127: U3.16 v1(88.02,121.65)
  BOTTOM w0.127: v1(88.02,121.65) 87.88,121.79 R51.1
N16821274: length 1.6
  TOP w0.127: U1.A17 123.03,104.62 v1(122.94,104.52)
  BOTTOM w0.127: v1(122.94,104.52) 122.56,104.14 R21.1
N16821816: length 9
  TOP w0.127: U1.E14 v2(126.37,101.82)
  BOTTOM w0.127: v2(126.37,101.82) 125.95,102.23 123.44,102.23 123.19,102.49 119,102.49 118.49,101.98 R14.1
N16870296: length 10.9
  BOTTOM w0.635: R252.2 R249.2 R248.2 R247.2 C345.1
N16870380: length 17
  TOP w0.508: C342.2 131.19,42.15 v1(131.31,42.04) T1.1 ; C339.2 125.35,42.06 v1(125.37,42.04) T1.7 ; T1.4 v1(128.34,42.04) 128.27,42.1 C344.2 ; T1.10 v1(122.4,42.04) 122.56,42.19 C341.2
  BOTTOM w0.508: v1(122.4,42.04) v1(125.37,42.04) v1(128.34,42.04) v1(131.31,42.04)
N16870836: length 68.2
  TOP w0.127: v1(116.65,55.44) 117.35,56.13 120.27,56.13 120.75,56.62 C349.1 R259.2
  BOTTOM w0.127: J19.B9 134.2,8.17 132.84,9.53 126.37,9.53 123.7,12.19 123.7,17.14 122.17,18.67 122.17,20.45 115.06,27.56 115.06,53.85 v1(116.65,55.44)
N16870842: length 74.4
  TOP w0.127: v1(116.59,54.61) 117.32,55.35 C348.1 118.52,55.37 R260.2
  BOTTOM w0.127: J19.B11 145.95,9.4 133.6,9.4 133.1,9.91 126.49,9.91 124.08,12.32 124.08,17.27 122.56,18.8 122.56,20.57 115.44,27.69 115.44,53.47 v1(116.59,54.61)
N16891950: length 2.3
  TOP w0.508: T3.15 v1(157.57,16.68)
  BOTTOM w0.508: v1(157.57,16.68) 157.86,16.97 R307.1
N16891952: length 10.7
  BOTTOM w0.635: R313.2 R309.2 R308.2 R307.2 C402.1
N16891962: length 2.2
  TOP w0.508: T3.18 v1(160.54,16.64)
  BOTTOM w0.508: R308.1 160.53,16.65 v1(160.54,16.64)
N16891966: length 2.2
  TOP w0.508: T3.21 v1(163.51,16.64)
  BOTTOM w0.508: R309.1 163.45,16.69 v1(163.51,16.64)
N16891978: length 2.2
  TOP w0.508: T3.24 v1(166.48,16.64)
  BOTTOM w0.508: v1(166.48,16.64) 166.5,16.66 R313.1
N16892036: length 16.9
  TOP w0.508: C401.2 160.53,36.96 v1(160.55,36.94) T3.7 ; T3.10 v1(157.58,36.93) 157.61,36.96 C400.2 ; C397.2 163.45,37.02 v1(163.52,36.96) T3.4 ; T3.1 166.49,36.95 v1(166.5,36.96) C399.2
  BOTTOM w0.508: v1(157.58,36.93) 160.53,36.93 v1(160.55,36.94) 163.5,36.94 v1(163.52,36.96) v1(166.5,36.96)
N16892171: length 26
  TOP w0.254: FB21.2 154.18,37.87 C398.1 153.52,14.12 J20.9
N16892215: length 44.8
  TOP w0.127: v1(150.5,52.32) 150.85,52.68 C407.1 151.28,52.7 R316.2
  BOTTOM w0.127: J20.10 153.29,16.64 153.29,25.65 149.23,29.72 149.23,49.78 150.5,51.05 v1(150.5,52.32)
N16892219: length 52.2
  TOP w0.127: v1(150.62,50.29) 151.38,50.29 151.74,50.65 C406.1 152.3,50.67 R317.2
  BOTTOM w0.127: J20.11 164.72,14.35 156.08,14.35 153.67,16.76 153.67,25.78 149.61,29.84 149.61,49.28 v1(150.62,50.29)
N16892768: length 1.9
  TOP w0.127: R311.2 168.77,51.81 U48.43
N16892846: length 1.8
  TOP w0.127: R312.2 168.89,52.21 U48.44
N16894213: length 1.9
  TOP w0.127: U48.46 166.23,54.52 R314.2
N16894217: length 1.9
  TOP w0.127: U48.45 166.63,54.34 R315.2
N16894418: length 2.2
  TOP w0.127: U48.75 156.84,49.01 R323.1
N16899326: length 4.8
  TOP w0.127: C403.1 165.62,40.14 arc(165.49,40.23) 165.34,40.26 164.77,40.26 arc(163.55,40.76) 163.04,41.98 163.04,42.33 163.03,42.34 U48.13
N16899338: length 4.3
  TOP w0.127: U48.14 163.43,42.33 163.42,42.33 163.42,41.98 arc(163.82,41.03) 164.77,40.64 165.12,40.64 arc(165.36,40.69) 165.56,40.82 C404.1
N16900249: length 1.8
  TOP w0.127: U48.70 156.46,51.01 156.29,51.18 R318.1
N16900569: length 4.2
  TOP w0.127: R320.1 156.24,50.65 156.28,50.61 U48.71
N16900702: length 5.2
  TOP w0.127: U48.81 156.19,46.61 C409.1 155.68,47.14 155.19,47.62 153.33,47.62 Y4.1
N16900720: length 7.5
  TOP w0.127: U48.82 155.78,46.21 C410.1 155.68,46.08 155.07,45.47 151.59,45.47 Y4.3
N16902304: length 2.1
  TOP w0.127: U48.77 156.9,48.21 155.96,49.15 R324.2
N16902556: length 1.7
  TOP w0.127: U48.26 169.14,45.01 R328.2
N16903120: length 1.9
  TOP w0.127: U48.78 156.79,47.81 156.46,48.13 R327.2
N16909680: length 0.9
  TOP w0.127: U48.88 157.43,43.64
  BOTTOM w0.508: R326.1 156.59,42.67 v1(157.1,43.18)
N16909742: length 1.1
  BOTTOM w0.508: C411.1 R326.2
N16927443: length 2.1
  TOP w0.127: R310.2 168.81,49.38 167.98,50.21 U48.39
N16974225: length 2.3
  TOP w0.508: T2.15 v1(138.14,28.36)
  BOTTOM w0.508: v1(138.14,28.36) 138.18,28.4 R277.1
N16974227: length 11.4
  BOTTOM w0.635: R282.2 R279.2 R278.2 R277.2 135.89,30.73 C374.1
N16974244: length 2.3
  TOP w0.508: T2.18 v1(141.1,28.33)
  BOTTOM w0.508: R278.1 141.1,28.34 v1(141.1,28.33)
N16974248: length 2.2
  TOP w0.508: T2.21 v1(144.07,28.39)
  BOTTOM w0.508: R279.1 144.02,28.45 v1(144.07,28.39)
N16974260: length 2.3
  TOP w0.508: T2.24 v1(147.04,28.34)
  BOTTOM w0.508: v1(147.04,28.34) 147.07,28.36 R282.1
N16974504: length 25.5
  TOP w0.254: v1(149.73,26.67) 150.9,27.84 C369.1 150.9,37.19 FB20.2
  L3SIG w0.254: J19.A9 136.56,24.93 138.3,26.67 v1(149.73,26.67)
N16974534: length 52
  TOP w0.127: R289.2 139.85,63.63 C378.1 139.22,64.26 136.78,64.26 v1(136.14,63.63)
  BOTTOM w0.127: v1(136.14,63.63) 137.92,61.85 137.92,56.01 137.03,55.12 137.03,49.15 135.64,47.75 135.64,44.96 134.24,43.56 134.24,24.38 135.13,23.5 137.11,23.5 J19.A10
N16974536: length 51
  TOP w0.127: R290.2 C377.1 136.78,63.5 v1(137.03,63.75)
  BOTTOM w0.127: J19.A11 148.84,26.59 148.84,58.8 147.96,59.69 145.8,59.69 145.16,60.33 145.16,61.47 144.4,62.23 138.56,62.23 v1(137.03,63.75)
N16984231: length 2.8
  TOP w0.127: C739.1 213.29,177.59 213.29,178.74 213.5,178.95 J27.33
N16984233: length 2.7
  TOP w0.127: C740.1 212.91,177.57 212.91,178.76 212.7,178.97 J27.31
N16984263: length 2.7
  TOP w0.127: C737.1 210.12,177.58 210.12,178.75 210.3,178.93 J27.25
N16984265: length 2.8
  TOP w0.127: J27.23 209.5,179 209.74,178.75 209.74,177.58 C738.1
N16985354: length 2.8
  TOP w0.127: J28.33 86.5,178.95 86.29,178.74 86.29,177.59 C769.1
N16985356: length 2.7
  TOP w0.127: J28.31 85.7,178.97 85.91,178.76 85.91,177.57 C770.1
N16985386: length 2.7
  TOP w0.127: J28.25 83.3,178.93 83.12,178.75 83.12,177.58 C757.1
N16985388: length 2.8
  TOP w0.127: J28.23 82.5,179 82.74,178.75 82.74,177.58 C768.1
N17055310: length 3.2
  TOP w0.305: C277.1 111.76,36.68 112.04,36.4 U29.2
N17055339: length 1.9
  TOP w0.305: C279.1 114.64,33.67 U29.6
N17055373: length 1.9
  TOP w0.305: C275.2 111.39,33.67 U29.1
N17055376: length 1.9
  TOP w0.305: U29.3 112.69,33.72 C275.1
N17055394: length 3.2
  TOP w0.305: C278.2 113.16,33.17 113.16,34.04 113.34,34.22 U29.4
N17055396: length 1.9
  TOP w0.305: U29.5 113.99,33.7 C278.1
N17055419: length 24.6
  TOP w0.127: U29.14 112.69,39.79 111.76,38.86 102.36,38.86 100.33,36.83 100.33,29.84 101.85,28.32 R182.1
N17055422: length 30.5
  TOP w0.127: R183.1 101.85,25.53 99.82,27.56 99.82,36.96 102.24,39.37 108.08,39.37 108.46,39.75 108.46,41.15 109.73,42.42 113.03,42.42 113.34,42.11 U29.13
N17055459: length 25.5
  TOP w0.127: R185.1 101.98,29.72 100.84,30.86 100.84,36.7 102.36,38.23 114.3,38.23 115.94,36.59 U29.8
N17055461: length 26.4
  TOP w0.127: v1(101.35,31.24) 101.35,36.58 102.49,37.72 114.17,37.72 115.29,36.6 U29.7 ; v1(101.35,28.07) 101.35,27.69 102.11,26.92 R184.1
  BOTTOM w0.127: v1(101.35,28.07) v1(101.35,31.24)
N17055495: length 1.4
  TOP w0.127: R182.2 FB8.1
N17055507: length 1.4
  TOP w0.127: R183.2 FB9.1
N17055527: length 1.4
  TOP w0.127: R184.2 FB10.1
N17055529: length 1.4
  TOP w0.127: FB11.1 R185.2
N17056698: length 5.6
  TOP w0.305: U30.2 103.66,36.68 103.38,36.96 102.62,36.96 102.11,36.45 C287.1
N17056714: length 1.9
  TOP w0.305: C288.1 106.26,33.92 U30.6
N17056740: length 1.9
  TOP w0.305: C284.2 103.01,33.92 U30.1
N17056750: length 1.9
  TOP w0.305: U30.3 104.31,33.98 C284.1
N17056764: length 3.3
  TOP w0.305: C286.2 105.13,32.79 104.74,33.18 104.74,34.26 104.96,34.47 U30.4
N17056766: length 1.9
  TOP w0.305: U30.5 105.61,33.95 C286.1
N17056776: length 22.3
  TOP w0.127: R186.1 101.35,24.13 99.31,26.16 99.31,37.34 101.98,40.01 103.89,40.01 104.31,40.43 U30.14
N17056778: length 30.5
  TOP w0.127: U30.13 104.96,42.62 104.01,43.56 101.85,43.56 98.3,40.01 98.3,24.77 101.73,21.34 R187.1
N17056796: length 7.4
  TOP w0.127: R189.1 107.15,32.11 107.56,32.51 U30.8
N17056798: length 27.5
  TOP w0.127: R188.1 101.47,22.73 98.81,25.4 98.81,37.72 v1(99.7,38.61) ; U30.7 106.91,36.98 v1(106.81,37.08)
  BOTTOM w0.127: v1(99.7,38.61) 105.28,38.61 v1(106.81,37.08)
N17056816: length 1.4
  TOP w0.127: R186.2 FB12.1
N17056834: length 1.4
  TOP w0.127: R187.2 FB13.1
N17056844: length 1.4
  TOP w0.127: R188.2 FB14.1
N17056846: length 1.4
  TOP w0.127: FB15.1 104.75,31.14 R189.2
N17059126: length 5
  TOP w0.127: U1.AE7 v2(143.17,96.22)
  BOTTOM w0.127: v2(143.17,96.22) 143.27,96.22 143.66,95.82 145.1,95.82 146.05,94.87 R124.1
N17059132: length 6.1
  TOP w0.127: U1.AF7 v2(143.97,96.22)
  BOTTOM w0.127: v2(143.97,96.22) 145.34,96.22 146.05,95.5 149,95.5 R126.1
N17059135: length 6.2
  TOP w0.127: U1.AF6 v2(143.97,95.42)
  BOTTOM w0.127: v2(143.97,95.42) 144.11,95.42 144.51,95.01 145.27,95.01 145.92,94.36 R128.1
N17059138: length 3.2
  TOP w0.127: U1.AG5 v2(144.77,94.62)
  BOTTOM w0.127: v2(144.77,94.62) 145.53,93.85 R130.1
N17059149: length 6
  TOP w0.127: U1.AF8 v2(143.97,97.02)
  BOTTOM w0.127: v2(143.97,97.02) 147.56,97.02 148.06,97.51 R134.1 R136.1
N17059152: length 7.2
  TOP w0.127: U1.AE8 v2(143.17,97.02)
  BOTTOM w0.127: R137.1 C52.1 147.55,95.89 146.3,95.89 145.57,96.62 143.56,96.62 v2(143.17,97.02)
N17059732: length 3.9
  TOP w0.127: U1.AC3 v2(141.57,93.02)
  BOTTOM w0.127: R129.2 141.35,90.55 141.99,91.19 141.99,92.6 v2(141.57,93.02)
N17059733: length 4.2
  TOP w0.127: U1.AE4 v2(143.17,93.82)
  BOTTOM w0.127: R125.2 144.4,91.06 144.02,91.44 144.02,92.33 143.56,92.79 143.56,93.42 v2(143.17,93.82)
N17059734: length 2.9
  TOP w0.127: U1.AD3 v2(142.37,93.02)
  BOTTOM w0.127: R127.2 v2(142.37,93.02)
N17059735: length 3.2
  TOP w0.127: U1.AE3 v2(143.17,93.02)
  BOTTOM w0.127: R133.2 143.38,91.19 143.64,91.44 143.64,92.33 143.17,92.8 v2(143.17,93.02)
N17059985: length 5.7
  TOP w0.127: U1.AF4 v2(143.97,93.82)
  BOTTOM w0.127: R135.2 147.29,91.19 R131.2 146.75,92.62 145.16,92.62 v2(143.97,93.82)
N17060054: length 4.9
  TOP w0.127: U1.AF3 v2(143.97,93.02)
  BOTTOM w0.127: v2(143.97,93.02) 145.42,91.57 145.77,91.57 C51.2 R132.2
N17060498: length 4.3
  TOP w0.127: U1.AH3 v2(145.57,93.02)
  BOTTOM w0.127: R138.2 145.89,93.34 v2(145.57,93.02)
N17072443: length 39.2
  TOP w0.127: U1.B17 124.02,104.27 123.32,104.27 123.06,104.01 122.3,104.01 120.4,105.92 118.17,105.92 112.71,111.38 112.71,115.82 104.71,123.83 99.95,123.83 v1(98.04,125.73) 98.02,125.76 R115.2
N17081955: length 70.2
  TOP w0.127: C56.2 170.46,43.05 arc(170.49,43.24) 170.6,43.39 arc(170.6,43.39) 170.6,43.39 170.67,43.46 arc(170.78,43.62) 170.81,43.82 170.81,52.72 164.7,87.5 arc(164.01,89.56) 162.73,91.31 162.04,91.99 arc(160.11,93.76) 158.02,95.36 155.62,97.05 arc(153.79,98.05) 151.8,98.63 146.74,99.52 arc(146.63,99.59) 146.6,99.72 arc(146.57,99.86) 146.46,99.93 146.31,99.96 arc(146.17,99.93) 146.1,99.81 arc(146.03,99.7) 145.89,99.67 145.16,99.8 145.16,99.81 U1.AH11
N17081957: length 71
  TOP w0.127: C57.2 169.99,43.52 arc(170.17,43.56) 170.33,43.66 170.4,43.73 arc(170.42,43.77) 170.43,43.82 170.43,44.22 arc(170.38,44.35) 170.24,44.41 arc(170.11,44.47) 170.05,44.6 170.05,44.73 arc(170.11,44.86) 170.24,44.92 arc(170.38,44.97) 170.43,45.11 170.43,45.23 arc(170.38,45.37) 170.24,45.43 arc(170.11,45.48) 170.05,45.62 170.05,45.74 arc(170.11,45.88) 170.24,45.93 arc(170.38,45.99) 170.43,46.12 170.43,46.38 arc(170.39,46.49) 170.27,46.54 arc(170.15,46.59) 170.1,46.71 170.1,46.89 arc(170.15,47) 170.27,47.05 arc(170.39,47.1) 170.43,47.22 170.43,52.69 164.33,87.44 arc(163.67,89.38) 162.46,91.04 161.77,91.72 arc(159.86,93.47) 157.8,95.05 155.4,96.73 arc(153.65,97.69) 151.73,98.25 145.08,99.43 arc(144.9,99.48) 144.75,99.59 144.58,99.77 arc(144.53,99.8) 144.46,99.82 U1.AG11
N17082045: length 21.4
  TOP w0.127: U1.AG13 144.61,101.66 arc(144.76,101.76) 144.94,101.8 145.35,101.8 164.36,98.44 arc(164.56,98.42) 164.76,98.41 164.8,98.41 arc(164.97,98.44) 165.11,98.54 C55.2
N17082047: length 21.1
  TOP w0.127: U1.AH13 145.31,101.42 145.72,101.34 arc(145.81,101.29) 145.83,101.2 145.83,101.19 arc(145.85,101.09) 145.93,101.03 146.17,100.99 arc(146.27,101.01) 146.33,101.1 arc(146.38,101.19) 146.48,101.21 146.72,101.17 arc(146.81,101.11) 146.83,101.01 146.83,101.01 arc(146.85,100.91) 146.94,100.86 147.17,100.82 arc(147.27,100.84) 147.33,100.92 arc(147.38,101.01) 147.48,101.03 164.78,97.98 arc(164.95,97.93) 165.1,97.82 C58.2
N17082121: length 21.3
  TOP w0.127: U1.AH14 145.19,102.23 145.93,102.23 arc(146.02,102.2) 146.05,102.11 arc(146.09,102.02) 146.18,101.98 146.43,101.98 arc(146.52,102.02) 146.56,102.11 arc(146.6,102.2) 146.69,102.23 146.94,102.23 arc(147.03,102.2) 147.07,102.11 arc(147.11,102.02) 147.2,101.98 147.45,101.98 arc(147.54,102.02) 147.58,102.11 arc(147.61,102.2) 147.7,102.23 147.96,102.23 arc(148.05,102.2) 148.09,102.11 arc(148.12,102.02) 148.21,101.98 148.47,101.98 arc(148.56,102.02) 148.59,102.11 arc(148.63,102.2) 148.72,102.23 148.97,102.23 155.92,101.01 arc(159.1,100.73) 162.27,101.01 164.63,101.42 arc(164.86,101.41) 165.06,101.29 C59.2
N17082123: length 21.3
  TOP w0.127: C60.2 165.03,101.88 165.01,101.88 162.21,101.38 arc(159.1,101.11) 155.99,101.39 149.01,102.62 145.04,102.62 arc(144.79,102.57) 144.57,102.42 U1.AG14
N17082287: length 170.6
  TOP w0.127: U1.AB18 v2(140.77,105.82) ; v1(193.8,100.46) 194.34,100.46 C1054.1
  L3SIG w0.102: v2(140.77,105.82) 140.69,105.82 140.59,105.92 140.59,106.07 140.75,106.23 143.34,106.23 144.14,107.04 148.18,107.04 151.49,110.34 174.22,110.34 183.39,119.51 208.54,119.51 216.29,127.25 219.46,127.25 225.68,133.48 233.05,133.48 235.08,131.44 235.08,117.86 226.72,109.5 203.61,109.5 194.77,100.66 194.01,100.66 v1(193.8,100.46)
N17082300: length 170.2
  TOP w0.127: C1055.1 194.34,101.22 v1(193.8,101.22) ; U1.AA18 v2(139.97,105.82)
  L3SIG w0.102: v2(139.97,105.82) 139.97,105.78 140.34,105.41 143.38,105.41 143.58,105.61 143.58,105.97 144.29,106.68 148.33,106.68 151.63,109.98 174.37,109.98 183.54,119.15 208.69,119.15 216.43,126.9 219.61,126.9 225.83,133.12 232.9,133.12 234.72,131.3 234.72,118 226.57,109.86 203.46,109.86 194.62,101.02 194.01,101.02 v1(193.8,101.22)
N17082319: length 10.3
  TOP w0.127: U1.Y20 v2(139.17,107.42)
  BOTTOM w0.127: R146.2 146.3,109.73 145.19,108.61 139.72,108.61 139.17,108.05 v2(139.17,107.42)
N17082346: length 1.9
  TOP w0.127: U1.AA12 v2(139.97,100.22)
  BOTTOM w0.127: R145.2 140.65,99.33 139.97,100.02 v2(139.97,100.22)
N17093364: length 13.5
  TOP w0.127: U1.AE5 v2(143.17,94.62)
  L3SIG w0.102: v1(154.18,92.96) 152.4,94.74 145.92,94.74 145.67,95 143.55,95 v2(143.17,94.62)
  BOTTOM w0.127: R144.2 v1(154.18,92.96)
N17093369: length 15.8
  TOP w0.127: U1.AB6 v2(140.77,95.42)
  L3SIG w0.102: v1(154.18,93.98) 152.91,95.25 146.05,95.25 145.46,95.84 141.18,95.84 v2(140.77,95.42)
  BOTTOM w0.127: R143.2 v1(154.18,93.98)
N17093378: length 14.9
  TOP w0.127: U1.AC8 v2(141.57,97.02)
  L3SIG w0.102: v1(154.18,95) 153.54,95.63 146.3,95.63 145.3,96.64 141.95,96.64 v2(141.57,97.02)
  BOTTOM w0.127: R142.2 v1(154.18,95)
N17111815: length 3.1
  TOP w0.127: J27.1 197.5,178.3 198.37,177.42 R446.1
N17112169: length 3.4
  TOP w0.127: R455.1 71.63,177.29 70.5,178.42 J28.1
N17113140: length 3
  TOP w0.127: U1.V2 v2(137.57,92.22)
  BOTTOM w0.127: v2(137.57,92.22) 137.57,90.7 137.29,90.42 R100.1
N17113141: length 4.1
  TOP w0.127: U1.W3 v2(138.37,93.02)
  BOTTOM w0.127: R102.1 138.3,91.06 137.92,91.44 137.92,92.02 137.96,92.05 137.96,92.38 137.92,92.42 137.92,92.58 138.36,93.02 v2(138.37,93.02)
N17113153: length 161.5
  TOP w0.127: v1(223.65,168.15) 223.35,168.44 U12.14 220.15,168.44 R101.2 ; U1.V3 v2(137.57,93.02)
  L6SIG w0.102: v1(137.35,83.12) 138.11,82.36 145.67,82.36 149.54,86.23 156.21,86.23 158.37,88.39 158.37,98.3 181.61,121.54 209.04,121.54 211.46,123.95 211.46,151.89 223.27,163.7 223.27,167.51 223.65,167.89 v1(223.65,168.15)
  BOTTOM w0.127: v2(137.57,93.02) 137.17,92.62 137.17,90.94 136.78,90.55 136.78,84.84 137.35,84.26 v1(137.35,83.12)
N17113154: length 162.2
  TOP w0.127: R103.2 220.6,167.51 220.88,167.79 U12.15 223.24,167.79 v1(223.9,167.13) ; U1.Y3 v2(139.17,93.02)
  L6SIG w0.102: v1(223.9,167.13) 223.9,163.58 211.84,151.51 211.84,123.83 209.23,121.22 181.74,121.22 158.69,98.17 158.69,88.33 156.34,85.98 149.67,85.98 145.8,82.11 137.6,82.11 v1(137.35,82.36)
  BOTTOM w0.127: v1(137.35,82.36) 138.05,83.06 138.05,86.61 138.87,87.44 138.87,88.2 138.81,88.26 138.81,91.57 139.17,91.92 v2(139.17,93.02)
N17113208: length 2
  TOP w0.127: R107.2 229.8,168.44 U12.3
N17113211: length 3.3
  TOP w0.127: U1.C20 v2(124.77,107.42)
  BOTTOM w0.127: v2(124.77,107.42) 124.54,107.19 R113.2
N17113215: length 3.4
  TOP w0.127: U1.B20 v2(124.77,106.62)
  BOTTOM w0.127: R114.2 122.19,106.21 124.36,106.21 v2(124.77,106.62)
N17113217: length 8.8
  TOP w0.127: U1.F9 v2(127.17,98.62)
  BOTTOM w0.127: v2(127.17,98.62) 126.76,98.21 126.76,96.85 126.53,96.62 126.21,96.62 125.97,96.38 125.97,96.05 125.73,95.81 125.4,95.81 125.17,95.58 125.17,95.25 124.93,95.01 124.47,95.01 123.44,93.98 R93.1
N17170143: length 3.3
  TOP w0.127: R484.1 C797.1 37.41,128.27 X1.3
N17200088: length 23
  TOP w0.127: 257.05,148.72 257.68,148.72 258.19,149.22 264.29,149.22 264.67,149.61 264.67,152.27 265.18,152.78 U9.7 264.67,153.38 264.67,155.07 265.94,156.34 U8.1 ; 257.05,148.72 U8.9 257.07,147.32 R59.1 ; 257.05,148.72 257.05,151 257.56,151.51 U9.3
N17200106: length 6.7
  TOP w0.127: U9.6 265.94,150.84 U8.16 266.47,147.35 267.36,148.23 R66.2
N17200115: length 19.2
  TOP w0.127: v1(266.95,146.94) 267.21,147.19 R61.2 ; v1(256.92,152.53) 257.18,152.78 U9.2 257.05,153.45 U8.8
  L6SIG w0.102: v1(256.92,152.53) 256.92,151.76 261.75,146.94 v1(266.95,146.94)
N17200136: length 4.2
  TOP w0.127: U1.N1 v2(133.17,90.75)
  BOTTOM w0.127: R65.1 132.91,88.24 132.91,90.49 v2(133.17,90.75)
N17200150: length 2.5
  TOP w0.127: U1.K1 v2(130.37,91.42)
  BOTTOM w0.127: R67.1 131.45,90.34 v2(130.37,91.42)
N17200329: length 8.3
  TOP w0.127: R57.1 267.87,145.21 R64.2 265.05,146.18 264.67,146.56 U8.15 264.67,148.59 265.27,149.19 U9.5
N17208058: length 5.6
  TOP w0.127: U1.P5 v2(133.57,94.62)
  BOTTOM w0.127: R108.2 134.37,93.82 v2(133.57,94.62)
N17208122: length 6.9
  TOP w0.127: U1.V5 v2(137.57,94.62)
  BOTTOM w0.127: R109.2 135.32,90.36 135.64,90.68 135.64,91.19 135.57,91.25 135.57,91.58 135.64,91.64 135.64,91.95 135.56,92.02 135.56,92.95 135.57,92.96 135.57,93.18 135.8,93.41 136.02,93.41 136.03,93.42 136.13,93.42 136.36,93.65 136.36,93.75 136.37,93.76 136.37,93.98 136.4,94.01 136.4,94.11 136.91,94.62 v2(137.57,94.62)
N17232338: length 3.3
  TOP w0.127: X2.3 37.41,136.4 C802.1 R487.1
N17246054: length 107.8
  TOP w0.127: Q4.3 70.1,35.95 69.37,36.68 R150.1 ; Q4.3 70.87,36.07 71.32,36.53 73.61,36.53 v1(73.66,36.58) ; Q4.3 70.87,33.27 70.49,32.89 65.41,32.89 64.92,33.38 R151.1 ; U1.F5 v2(127.17,94.62)
  L3SIG w0.102: v2(127.17,94.62) 127.58,94.2 127.58,93.65 127.36,93.42 127.03,93.42 126.75,93.14 126.75,92.86 126.75,92.86 126.75,92.38 126.75,92.37 126.75,86.62 106.55,66.42 89.66,66.42 86.11,62.87 82.68,62.87 79.12,59.31 79.12,54.1 75.57,50.55 75.57,40.77 73.66,38.86 v1(73.66,36.58)
N17246089: length 103.5
  TOP w0.127: R155.1 65.41,34.9 65.41,36.46 Q5.3 67.3,38.35 R149.1 69.37,38.38 69.98,38.99 71.12,38.99 71.5,38.61 v1(74.3,38.61) ; U1.H5 v2(128.77,94.62)
  L3SIG w0.102: v1(74.3,38.61) 76.07,40.39 76.07,50.42 79.5,53.85 79.5,59.05 82.93,62.48 86.36,62.48 89.92,66.04 106.62,66.04 127.38,86.8 127.38,91.06 127.55,91.22 127.55,93.21 127.76,93.42 128.14,93.42 128.37,93.65 128.37,94.21 128.77,94.6 v2(128.77,94.62)
N17246488: length 1.6
  TOP w0.127: U19.3 R159.2
N17246514: length 110.4
  TOP w0.127: R162.1 71.76,21.65 L1.4 71.6,22.13 71.39,22.34 71.39,22.73 71.74,23.09 74.69,23.09 77.34,25.74 77.34,37.58 79.9,40.13 80.52,40.13 v1(80.77,39.88) ; U1.F1 127.47,91.72 127.47,90.26 arc(127.54,90.08) 127.72,90 127.76,90 arc(128.02,89.75) 127.76,89.5 127.67,89.5 arc(127.53,89.44) 127.47,89.3 127.47,88.85 125.25,86.63 125.25,75.89 111.53,62.18 111.53,58.93 111.66,58.8 v1(111.76,58.8)
  BOTTOM w0.127: v1(111.76,58.8) 111.66,58.8 111.53,58.67 111.53,51.32 109.5,49.29 109.5,46.11 105.14,41.76 91.81,41.76 91.43,41.38 82.79,41.38 81.52,40.11 81,40.11 v1(80.77,39.88)
N17246518: length 110.7
  TOP w0.127: v1(80.77,40.64) 80.54,40.41 79.78,40.41 77.06,37.69 77.06,25.86 74.57,23.37 71.63,23.37 71.11,22.85 71.11,22.34 70.9,22.13 L1.1 70.74,21.65 R163.1 ; U1.F2 127.19,92.24 127.19,88.96 124.97,86.74 124.97,76.01 111.25,62.29 111.25,58.93 111.13,58.8 v1(111,58.8)
  BOTTOM w0.127: v1(80.77,40.64) 81.03,40.39 81.41,40.39 82.68,41.66 91.31,41.66 91.69,42.04 105.03,42.04 109.22,46.23 109.22,49.4 111.25,51.44 111.25,58.67 111.13,58.8 v1(111,58.8)
N17246522: length 116.5
  TOP w0.127: v1(83.06,39.88) 82.8,40.13 82.28,40.13 81.14,41.27 79.38,41.27 75.72,37.62 75.72,26.17 74.03,24.49 70.6,24.49 69.1,22.99 69.1,22.34 69.31,22.13 L2.4 69.47,21.65 R164.1 ; U1.H1 129.06,91.71 129.06,91.05 arc(129.11,90.93) 129.24,90.88 arc(129.36,90.82) 129.41,90.7 129.41,90.67 arc(129.36,90.55) 129.24,90.49 arc(129.11,90.44) 129.06,90.32 129.06,90.29 arc(129.11,90.17) 129.24,90.11 arc(129.36,90.06) 129.41,89.94 129.41,89.91 arc(129.36,89.78) 129.24,89.73 arc(129.11,89.68) 129.06,89.55 129.06,88.4 126.64,85.99 126.64,75.32 112.94,61.62 112.94,60.93 113.07,60.8 v1(113.25,60.8)
  BOTTOM w0.127: v1(113.25,60.8) 113.07,60.8 112.94,60.68 112.94,47.14 105.53,39.73 95.13,39.73 94.5,40.36 84.18,40.36 83.92,40.11 83.29,40.11 v1(83.06,39.88)
N17246524: length 116.6
  TOP w0.127: v1(83.06,40.64) 82.83,40.41 82.4,40.41 81.25,41.55 79.26,41.55 75.44,37.73 75.44,26.29 73.91,24.77 70.49,24.77 68.82,23.1 68.82,22.34 68.61,22.13 L2.1 68.45,21.65 R165.1 ; v1(112.36,60.8) 112.54,60.8 112.66,60.93 112.66,61.74 126.37,75.44 126.37,86.11 128.78,88.52 128.78,92.23 U1.H2
  BOTTOM w0.127: v1(112.36,60.8) 112.54,60.8 112.66,60.68 112.66,47.26 105.41,40.01 95.25,40.01 94.62,40.64 84.06,40.64 83.81,40.39 83.31,40.39 v1(83.06,40.64)
N17246685: length 6.6
  TOP w0.127: U1.F4 v2(127.17,93.82)
  BOTTOM w0.127: v2(127.17,93.82) 126.77,93.42 125.38,93.42 125.16,93.21 125.16,92.83 124.71,92.38 124.71,91.57 124.08,90.93 R168.2
N17246689: length 9.7
  TOP w0.127: U1.H4 v2(128.77,93.82)
  BOTTOM w0.127: v2(128.77,93.82) 128.37,93.42 128.37,92.05 128.14,91.82 125.98,91.82 124.71,90.55 124.71,88.52 124.08,87.88 R167.2
N17246719: length 8.3
  TOP w0.127: U1.G4 v2(127.97,93.82)
  BOTTOM w0.127: C78.1 R166.2 124.05,90.4 125.1,91.44 125.1,92.33 125.38,92.61 127.41,92.61 127.56,92.76 127.56,93.41 v2(127.97,93.82)
N17246771: length 1.1
  BOTTOM w0.127: R169.2 122.07,88.9 C78.2
N17246861: length 4.7
  TOP w1.016: J5.4 72.52,17.27 73.41,18.16 FB4.1
N17246863:
  vias: v1(74.93,18.54) v1(75.69,18.54)
N17249127: length 4.4
  TOP w0.127: J26.A17 276.45,99.9 275.8,99.9 275.43,100.27 273.09,100.27 C748.1
N17249129: length 4.4
  TOP w0.127: C741.1 272.83,99.89 275.27,99.89 275.46,99.69 275.46,99.2 275.34,99.08 J26.A16
N17249144: length 10.1
  TOP w0.127: R452.1 275.21,95.89 275.84,95.25 278.76,95.25 279.65,94.36 279.65,92.6 J26.B11
N17249162: length 2.1
  TOP w0.127: J26.A8 274.32,88.77 R445.1
N17249180: length 8.5
  TOP w0.127: R444.1 273.56,94.36 275.72,92.2 275.72,91.85 276.26,91.31 277.89,91.31 J26.B9
N17249182: length 5.2
  TOP w0.127: R447.1 273.02,84.33 274.96,84.33 275.59,84.96 275.59,85.47 276.2,86.08 J26.A5
N17249192: length 2.3
  TOP w0.127: R448.1 273.32,87.08 J26.A6
N17249250: length 9.4
  TOP w0.127: J26.B15 279.78,98.08 280.04,97.82 280.04,97.54 279.7,97.2 276.31,97.2 275.21,98.3 272.9,98.3 C750.1
N17249252: length 9.4
  TOP w0.127: C749.1 273.02,97.92 275.05,97.92 276.15,96.82 279.85,96.82 280.32,97.28 280.92,97.28 J26.B14
N17251651: length 22.3
  TOP w0.508: C867.2 187.83,140.21 v1(187.57,139.95) ; R566.1 193.69,144.04 v1(193.67,144.02) R564.2
  L3SIG w0.508: v1(184.52,145.16) 185.67,144.02 v1(193.67,144.02)
  BOTTOM w0.508: v1(187.57,139.95) 184.02,139.95 183.13,140.84 183.13,144.53 183.76,145.16 v1(184.52,145.16)
N17251653: length 2.3
  TOP w0.254: R566.2 194.43,145.57 193.93,146.07 C878.2 193.9,146.05 C880.2
N17251663: length 3.6
  TOP w0.254: R567.1 C880.1 191.66,145.8 v1(191.13,145.8) 191.01,145.92 U64.5
  BOTTOM w0.254: v1(191.13,145.8) 190.98,145.64 R574.2
N17251677: length 10.5
  TOP w0.254: R570.1 v1(193.67,143) ; v1(189.73,148.21) 189.48,147.95 U64.8
  BOTTOM w0.508: v1(193.67,143) 192.91,143 192.02,143.89 192.02,147.07 190.87,148.21 v1(189.73,148.21) 189.45,147.93 C885.1
N17251680: length 3.1
  TOP w0.254: U64.1 190.33,143.55 v1(190.62,143.26) 190.87,143 R570.2
  BOTTOM w0.254: v1(190.62,143.26) 190.98,143.61 R572.2
N17251691: length 2.2
  TOP w0.254: U64.6 190.98,146.41 v1(191.13,146.56)
  BOTTOM w0.254: C886.1 190.65,147.04 v1(191.13,146.56)
N17251709: length 1.8
  TOP w0.254: R558.2 188.98,142.72 U64.15
N17251715: length 1.7
  TOP w0.254: U64.14 188.48,141.75 C867.1
N17251719: length 1.8
  TOP w0.254: U64.2 190.98,144.42 191.38,144.02 R564.1
N17251739: length 22.3
  TOP w0.508: R578.2 v1(30.11,62.36) 30.08,62.33 R584.1 ; C890.2 35.95,66.17 v1(36.2,66.42)
  L3SIG w0.508: v1(30.11,62.36) 38.11,62.36 v1(39.25,61.21)
  BOTTOM w0.508: v1(36.2,66.42) 39.76,66.42 40.65,65.53 40.65,61.85 40.01,61.21 v1(39.25,61.21)
N17251740: length 2.3
  TOP w0.254: R584.2 29.34,60.8 C908.2 29.87,60.33 C910.2
N17251749: length 3.6
  TOP w0.254: R586.1 C910.1 32.11,60.58 v1(32.65,60.58) 32.77,60.46 U65.5
  BOTTOM w0.254: R592.2 32.8,60.73 v1(32.65,60.58)
N17251753: length 1.8
  TOP w0.254: R578.1 32.39,62.36 32.79,61.96 U65.2
N17251755: length 1.6
  TOP w0.127: R585.2 31.97,61.46 U65.3
N17251758: length 3.3
  TOP w0.127: U65.16 34.3,63.37 33.92,63.75 33.41,63.75 33.03,64.13 R583.2 C900.2
N17251765: length 10.5
  TOP w0.254: U65.8 34.3,58.42 v1(34.04,58.17) ; R588.1 v1(30.11,63.37)
  BOTTOM w0.508: v1(30.11,63.37) 30.87,63.37 31.76,62.48 31.76,59.31 32.9,58.17 v1(34.04,58.17) 34.32,58.45 C915.1
N17251768: length 3.1
  TOP w0.254: R588.2 32.9,63.37 v1(33.15,63.12) 33.45,62.83 U65.1
  BOTTOM w0.254: R590.2 32.8,62.76 v1(33.15,63.12)
N17251782: length 2.2
  TOP w0.254: v1(32.65,59.82) 32.79,59.96 U65.6
  BOTTOM w0.254: v1(32.65,59.82) 33.13,59.33 C916.1
N17251797: length 1.8
  TOP w0.254: U65.15 34.8,63.66 R576.2
N17251803: length 1.7
  TOP w0.254: U65.14 35.3,64.63 C890.1
N17251826: length 22.3
  TOP w0.508: R603.2 v1(28.58,51.18) 28.55,51.16 R599.1 ; v1(34.67,55.24) 34.42,54.99 C930.2
  L3SIG w0.508: v1(28.58,51.18) 36.58,51.18 v1(37.72,50.04)
  BOTTOM w0.508: v1(34.67,55.24) 38.23,55.24 39.12,54.36 39.12,50.67 38.48,50.04 v1(37.72,50.04)
N17251827: length 2.3
  TOP w0.254: R599.2 27.81,49.63 C938.2 28.35,49.15 C940.2
N17251836: length 3.6
  TOP w0.254: R600.1 C940.1 30.58,49.4 v1(31.12,49.4) 31.23,49.28 U68.5
  BOTTOM w0.254: R610.2 31.27,49.56 v1(31.12,49.4)
N17251840: length 1.8
  TOP w0.254: U68.2 31.26,50.78 30.86,51.18 R603.1
N17251850: length 3.3
  TOP w0.127: C929.2 R598.2 31.5,52.96 31.88,52.58 32.39,52.58 32.77,52.2 U68.16
N17251857: length 10.5
  TOP w0.254: R606.1 v1(28.58,52.2) ; U68.8 32.77,47.25 v1(32.51,46.99)
  BOTTOM w0.508: C945.1 32.79,47.27 v1(32.51,46.99) 31.37,46.99 30.23,48.13 30.23,51.31 29.34,52.2 v1(28.58,52.2)
N17251860: length 3.1
  TOP w0.254: R606.2 31.37,52.2 v1(31.62,51.94) 31.92,51.65 U68.1
  BOTTOM w0.254: R608.2 31.27,51.59 v1(31.62,51.94)
N17251871: length 2.2
  TOP w0.254: U68.6 31.26,48.78 v1(31.12,48.64)
  BOTTOM w0.254: v1(31.12,48.64) 31.6,48.16 C946.1
N17251886: length 1.8
  TOP w0.254: U68.15 33.27,52.48 R594.2
N17251892: length 1.7
  TOP w0.254: C930.1 33.77,53.45 U68.14
N17251915: length 22.3
  TOP w0.508: v1(250.19,74.29) 249.94,74.54 C919.2 ; R595.2 v1(246.13,80.38) 246.1,80.41 R597.1
  L3SIG w0.508: v1(244.98,71.24) 246.13,72.38 v1(246.13,80.38)
  BOTTOM w0.508: v1(244.98,71.24) 244.98,70.48 245.62,69.84 249.3,69.84 250.19,70.73 v1(250.19,74.29)
N17251916: length 2.3
  TOP w0.254: C939.2 244.09,80.62 C937.2 244.57,81.15 R597.2
N17251925: length 3.6
  TOP w0.254: R602.1 C939.1 244.35,78.38 v1(244.35,77.84) 244.23,77.72 U67.5
  BOTTOM w0.254: v1(244.35,77.84) 244.5,77.69 R609.2
N17251929: length 1.8
  TOP w0.254: R595.1 246.13,78.1 245.73,77.7 U67.2
N17251934: length 1.6
  TOP w0.127: R601.2 245.23,78.52 U67.3
N17251937: length 3.3
  TOP w0.127: U67.16 247.14,76.19 247.52,76.57 247.52,77.08 247.9,77.46 R596.2 C928.2
N17251944: length 10.5
  TOP w0.254: U67.8 242.19,76.19 v1(241.94,76.45) ; R605.1 v1(247.14,80.38)
  BOTTOM w0.508: C941.1 242.21,76.17 v1(241.94,76.45) 241.94,77.59 243.08,78.73 246.25,78.73 247.14,79.62 v1(247.14,80.38)
N17251947: length 3.1
  TOP w0.254: U67.1 246.59,77.04 v1(246.89,77.34) 247.14,77.59 R605.2
  BOTTOM w0.254: R607.2 246.53,77.69 v1(246.89,77.34)
N17251958: length 2.2
  TOP w0.254: U67.6 243.73,77.7 v1(243.59,77.84)
  BOTTOM w0.254: v1(243.59,77.84) 243.1,77.36 C942.1
N17251973: length 1.8
  TOP w0.254: U67.15 247.43,75.69 R593.2
N17251979: length 1.7
  TOP w0.254: C919.1 248.4,75.19 U67.14
N17252002: length 22.3
  TOP w0.508: C896.2 26.54,161.93 v1(26.29,162.19) ; R577.2 v1(30.35,156.09) 30.38,156.06 R580.1
  L3SIG w0.508: v1(30.35,156.09) 30.35,164.09 v1(31.5,165.23)
  BOTTOM w0.508: v1(26.29,162.19) 26.29,165.74 27.18,166.63 30.86,166.63 31.5,166 v1(31.5,165.23)
N17252003: length 2.3
  TOP w0.254: C909.2 32.39,155.85 C902.2 31.91,155.33 R580.2
N17252012: length 3.6
  TOP w0.254: R582.1 C909.1 32.13,158.1 v1(32.13,158.63) 32.25,158.75 U66.5
  BOTTOM w0.254: R591.2 31.98,158.78 v1(32.13,158.63)
N17252016: length 1.8
  TOP w0.254: R577.1 30.35,158.38 30.75,158.77 U66.2
N17252018: length 1.6
  TOP w0.127: U66.3 31.25,157.95 R581.2
N17252028: length 10.5
  TOP w0.254: U66.8 34.29,160.28 v1(34.54,160.03) ; R587.1 v1(29.34,156.09)
  BOTTOM w0.508: C911.1 34.26,160.31 v1(34.54,160.03) 34.54,158.88 33.4,157.74 30.23,157.74 29.34,156.85 v1(29.34,156.09)
N17252031: length 3.1
  TOP w0.254: R587.2 29.34,158.88 v1(29.59,159.14) 29.88,159.43 U66.1
  BOTTOM w0.254: R589.2 29.95,158.78 v1(29.59,159.14)
N17252042: length 2.2
  TOP w0.254: U66.6 32.75,158.77 v1(32.89,158.63)
  BOTTOM w0.254: v1(32.89,158.63) 33.38,159.11 C912.1
N17252057: length 1.8
  TOP w0.254: R575.2 29.05,160.78 U66.15
N17252063: length 1.7
  TOP w0.254: U66.14 28.08,161.28 C896.1
N17271621: length 7.3
  TOP w0.127: U1.L4 v2(131.17,93.82)
  BOTTOM w0.127: R88.1 133.73,90.21 133.73,91.88 133.16,92.46 133.16,92.85 133.16,93.98 132.92,94.22 131.57,94.22 v2(131.17,93.82)
N17271626: length 3.9
  TOP w0.127: U1.U3 v2(136.77,93.02)
  BOTTOM w0.127: R89.1 136.36,89.98 136.36,92.61 v2(136.77,93.02)
N17271631: length 6.5
  TOP w0.127: U1.F19 v2(127.17,106.62)
  BOTTOM w0.127: v2(127.17,106.62) 126.76,106.21 126.76,105.61 126.56,105.41 122.4,105.41 R91.1
N17321001: length 1.6
  TOP w0.127: U13.4 93.37,78.56 R112.1
N17321019: length 1.7
  TOP w0.127: R112.2 92.1,78.12 D1.2
N17399246: length 5.5
  TOP w0.127: R699.2 13.97,21.72 13.46,21.21 12.09,21.21 C1046.1 R697.1 11.58,23.45 U76.3
N17399288: length 21.8
  TOP w0.127: SW4.2 17.78,5.95 17.78,14.73 J38.1 20.07,18.16 18.54,19.69 15.88,19.69 14.96,20.6 R699.1
N17400346: length 26.1
  TOP w0.127: SW5.2 9.27,8.88 13.59,13.21 13.59,18.03 9.65,21.97 D7.2 6.07,22.44 R706.1 7.09,23.24 R703.1
N17401317: length 2.5
  TOP w0.127: U78.4 6.36,28.34 7,28.97 U77.1
N17401544: length 4
  TOP w0.127: D7.1 5.11,22.01 R706.2 C1049.1 5.11,24.66 5.72,25.27 U78.2
N17423481: length 11.9
  TOP w0.127: J4.5 9.91,112.27 11.18,111 R119.2
N17423546: length 4.5
  TOP w0.127: J4.6 R116.1
N17424508: length 4.5
  TOP w0.254: R191.1 50.8,149.63 C294.1 51.01,151.08 J10.1
N17424523: length 4.4
  TOP w0.254: R191.2 51.79,147.55 51.11,146.87 U31.3
N17424557: length 2.4
  TOP w0.127: Y1.4 47.82,147.14 48.2,147.52 U31.2
N17424571: length 4
  TOP w0.127: U31.1 47.33,148.17 46.92,147.76 Y1.1
N17424740: length 2.9
  BOTTOM w0.254: R193.2 118.11,109.58 C296.2 116.94,109.42 U34.2
N17424742: length 2.9
  BOTTOM w0.254: U34.3 116.94,108.77 C296.1 118.11,108.61 R194.2
N17433404: length 2.2
  TOP w0.127: R226.2 77.37,48.77 76.99,48.39 U37.88
N17437095: length 16
  TOP w0.127: R220.1 81.66,25.37 R210.1 79.25,27.84 79.25,34.16 80.14,35.05 82.42,35.05 82.8,35.43 U35.8
N17437909: length 1.5
  TOP w0.127: D4.2 80.15,23.39 R220.2
N17484067: length 10.3
  TOP w0.127: U36.23 86.15,17.7 85.09,16.64 85.09,13.08 86.52,11.66 J12.13
N17484070: length 10.4
  TOP w0.127: J12.15 85.52,12.02 84.71,12.83 84.71,15.47 R204.1 84.2,16.26 85.65,17.71 U36.22
N17484079: length 10.4
  TOP w0.127: J12.16 85.02,11.91 R203.1 83.69,13.23 83.69,16.26 83.76,16.32 83.76,16.33 83.87,16.44 83.88,16.44 85.15,17.72 U36.21
N17484088: length 10.4
  TOP w0.127: J12.19 83.52,11.23 82.68,12.06 82.68,15.49 83.16,15.98 R215.2 83.19,16.26 84.65,17.72 U36.20
N17484885: length 3.1
  TOP w0.254: C304.1 93.5,19.96 93.15,19.62 U36.37
N17497489: length 7.1
  TOP w0.127: U36.16 86.15,23.29 85.98,23.11 84.2,23.11 83.44,23.88 83.44,24.61 R210.2 82.65,26.42 R207.1
N17497523: length 13.1
  TOP w0.127: U35.9 84.96,34.93 85.6,34.29 85.6,31.75 84.2,30.35 84.2,26.92 83.72,26.44 R206.1 83.69,26.03 84.65,25.07 U36.19
N17498064: length 2.7
  TOP w0.127: U35.35 96.31,32.43 97.28,33.4 R212.1
N17498075: length 2.1
  TOP w0.127: U35.19 86.91,27.58 R213.1
N17500984: length 2.2
  TOP w0.127: U35.10 81.77,34.43 R219.2
N17501134: length 12.3
  TOP w0.127: C306.2 81.97,37.93 82.47,37.93 82.49,37.91 82.86,37.91 82.88,37.93 U35.3 85.05,37.93 86.36,39.24 v1(89.79,39.24) 89.91,39.37 U35.56
  BOTTOM w0.127: R218.2 R214.2 89.92,39.12 v1(89.79,39.24)
N17523688: length 1.7
  TOP w0.127: U77.2 7.36,29.47 7.24,29.59 7.24,29.84 7.36,29.97 U77.3
N17523697: length 1.2
  TOP w0.127: U77.5 5.03,31.6 R705.1
N17523706: length 3.5
  TOP w0.127: C1050.1 R707.2 6.12,30.38 5.71,29.97 U77.6
N17525004: length 3.6
  TOP w0.254: Q28.3 58.57,85.37 R692.1 R691.1
N17526494: length 1.8
  TOP w0.254: R535.2 68.83,99.73 U60.15
N17526498: length 10.5
  TOP w0.254: U60.8 68.33,94.49 v1(68.07,94.23) ; R543.1 v1(64.14,99.44)
  BOTTOM w0.508: C854.1 68.35,94.51 v1(68.07,94.23) 66.93,94.23 65.66,95.5 65.66,98.68 64.9,99.44 v1(64.14,99.44)
N17526502: length 3
  TOP w0.254: U60.1 67.48,98.89 v1(67.18,99.19) 66.93,99.44 R543.2
  BOTTOM w0.254: R545.2 66.83,98.83 v1(67.18,99.19)
N17526505: length 22
  TOP w0.508: R536.2 v1(64.14,98.42) 64.11,98.4 R537.1 ; C840.2 69.98,102.23 v1(70.23,102.49)
  L6SIG w0.508: v1(64.14,98.42) 72.14,98.42 v1(73.28,97.28)
  BOTTOM w0.508: v1(70.23,102.49) 73.28,102.49 74.68,101.09 74.68,97.92 74.04,97.28 v1(73.28,97.28)
N17526509: length 2.3
  TOP w0.254: R537.2 63.37,96.88 C847.1 63.91,96.39 C852.1
N17526513: length 24.2
  TOP w0.508: v1(63.12,94.36) R548.2 63.88,94.39 C847.2
  L6SIG w0.508: v1(84.33,93.47) 82.55,95.25 67.44,95.25 66.55,94.36 v1(63.12,94.36)
N17526517: length 3.7
  TOP w0.254: U60.5 66.79,96.53 v1(66.68,96.65) 66.14,96.65 C852.2 65.89,95.38 R547.2
  BOTTOM w0.254: v1(66.68,96.65) 66.83,96.8 R546.2
N17526563: length 2.2
  TOP w0.254: U60.6 66.82,96.03 v1(66.68,95.89)
  BOTTOM w0.254: v1(66.68,95.89) 67.03,95.53 C855.1
N17526565: length 1.7
  TOP w0.254: C840.1 69.33,100.7 U60.14
N17526568: length 1.8
  TOP w0.254: U60.2 66.82,98.03 66.42,98.42 R536.1
N17526574: length 2
  TOP w0.254: U61.2 65.28,90.3 65.79,89.79 R551.2
N17526575: length 11.5
  TOP w0.254: R556.2 70.1,90.68 68.1,92.68 R550.2 66.84,93.02 U61.4 65.91,93.04 R547.1 64.9,94.39 R548.1
N17551792: length 3.9
  TOP w0.127: R243.2 252.1,169.67 J18.1
N17554945: length 262.9
  TOP w0.127: U39.4 92.51,58.24 92.78,57.96 93.52,57.96 94.36,58.8 94.36,60.33 v1(94.74,60.71) ; v1(270.38,139.19) 249.17,139.19 243.84,144.53 243.84,148.46 244.48,149.1 247.27,149.1 247.65,148.72 U40.3
  L6SIG w0.102: v1(94.74,60.71) 95.25,61.21 100.84,61.21 102.49,62.87 114.36,62.87 124.36,72.86 161.95,72.86 162.01,72.86 168.52,79.36 168.52,89.48 170.12,91.08 170.12,95.48 180.23,105.6 189.48,105.6 193.87,109.98 245.7,109.98 270.38,134.67 v1(270.38,139.19)
N17554954: length 255.8
  TOP w0.127: U39.7 93.75,56.29 94.36,56.9 94.36,57.78 94.87,58.29 94.87,59.44 v1(95.38,59.94) ; v1(271.53,140.59) 252.1,140.59 250.83,141.86 250.83,144.65 251.43,145.26 R241.1 U40.6
  L6SIG w0.102: v1(271.53,140.59) 271.53,134.79 246.08,109.35 194.12,109.35 189.87,105.09 180.4,105.09 170.62,95.31 170.62,90.83 169.04,89.24 169.04,79.12 162.32,72.4 162.14,72.4 124.79,72.4 114.62,62.23 103.38,62.23 101.6,60.45 99.31,60.45 98.93,60.83 95.63,60.83 95.38,60.58 v1(95.38,59.94)
N17555031: length 2.4
  TOP w0.127: U40.4 248.92,146.08 R245.2
N17555276: length 242.6
  TOP w0.127: U39.12 98.99,57.59 100.71,59.31 100.71,60.33 v1(101.35,60.96) ; v1(270.89,139.95) 250.95,139.95 249.56,141.35 U41.2
  L6SIG w0.102: v1(270.89,139.95) 270.89,134.67 245.89,109.66 193.99,109.66 189.67,105.35 180.3,105.35 170.37,95.41 170.37,90.95 168.81,89.39 168.81,79.27 162.16,72.63 162.05,72.63 162.05,72.63 124.57,72.63 114.49,62.55 102.93,62.55 v1(101.35,60.96)
N17555960: length 3.5
  TOP w0.127: U40.5 250.19,145.31 R246.1 250.2,145.25 U41.4
N17557626: length 13.9
  TOP w0.127: C775.1 226.94,124.19 arc(226.85,124.32) 226.82,124.47 226.82,126.36 arc(226.63,127.33) 226.08,128.16 225.42,128.81 arc(224.95,129.51) 224.79,130.34 224.79,133.85 arc(225.14,134.7) 225.99,135.05 226.77,135.05 arc(226.89,135.02) 227,134.95 227.02,134.93 arc(227.12,134.86) 227.25,134.84 J30.13
N17557628: length 14.5
  TOP w0.127: J30.15 227.21,135.64 arc(227.09,135.61) 226.98,135.54 226.96,135.52 arc(226.86,135.45) 226.73,135.43 225.99,135.43 arc(224.87,134.97) 224.41,133.85 224.41,130.34 arc(224.6,129.37) 225.15,128.54 225.81,127.89 arc(226.28,127.19) 226.44,126.36 226.44,124.69 arc(226.39,124.45) 226.26,124.25 C776.1
N17558733: length 5.4
  TOP w0.127: J30.14 221.58,134.84 221.11,134.37 R465.1 220.32,134.39 219.84,134.87 R467.2
N17558754: length 5.3
  TOP w0.127: R468.2 219.84,135.89 220.32,135.41 R464.1 220.57,135.64 J30.16
N17558775: length 5.3
  TOP w0.127: J30.18 220.36,136.44 R463.1 220.32,136.42 219.84,136.91 R469.2
N17559329: length 2.9
  TOP w0.127: R466.1 221.11,129.29 221.86,130.04 J30.2
N17582904: length 2.4
  TOP w0.508: T5.24 v1(185.53,30.48)
  BOTTOM w0.508: v1(185.53,30.48) 185.55,30.5 R353.1
N17582906: length 11.3
  BOTTOM w0.635: C506.2 R359.2 R357.2 R355.2 R353.2
N17582916: length 2.4
  TOP w0.508: T5.21 v1(182.56,30.48)
  BOTTOM w0.508: R355.1 182.5,30.54 v1(182.56,30.48)
N17582920: length 2.4
  TOP w0.508: T5.18 v1(179.59,30.48)
  BOTTOM w0.508: R357.1 179.58,30.49 v1(179.59,30.48)
N17582932: length 2.4
  TOP w0.508: T5.15 v1(176.62,30.48)
  BOTTOM w0.508: R359.1 176.66,30.52 v1(176.62,30.48)
N17584782: length 3.4
  TOP w0.508: T5.1 v1(185.54,43.94)
  BOTTOM w0.508: v1(185.54,43.94) 185.55,43.93 C498.2
N17584786: length 3.4
  TOP w0.508: T5.4 v1(182.57,43.94)
  BOTTOM w0.508: v1(182.57,43.94) 182.63,43.88 C500.2
N17584789: length 3.4
  TOP w0.508: T5.7 v1(179.6,43.94)
  BOTTOM w0.508: v1(179.6,43.94) 179.58,43.92 C502.2
N17584792: length 3.4
  TOP w0.508: T5.10 v1(176.63,43.94)
  BOTTOM w0.508: v1(176.63,43.94) 176.66,43.91 C504.2
N17584836: length 2.1
  TOP w0.508: T6.1 v1(185.54,66.8)
  BOTTOM w0.508: v1(185.54,66.8) 185.55,66.79 C512.2
N17584840: length 2.1
  TOP w0.508: T6.4 v1(182.57,66.8)
  BOTTOM w0.508: v1(182.57,66.8) 182.63,66.74 C514.2
N17584844: length 2.1
  TOP w0.508: T6.7 v1(179.6,66.8)
  BOTTOM w0.508: v1(179.6,66.8) 179.58,66.78 C516.2
N17584847: length 2.1
  TOP w0.508: T6.10 v1(176.63,66.8)
  BOTTOM w0.508: C518.2 176.66,66.77 v1(176.63,66.8)
N17584869: length 4.2
  TOP w0.127: U51.C10 192.82,88.27 196.62,88.27 R331.1
N17584889: length 3.4
  TOP w0.508: T8.4 v1(198.44,43.94)
  BOTTOM w0.508: v1(198.44,43.94) 198.5,43.88 C528.2
N17584893: length 3.4
  TOP w0.508: T8.1 v1(201.41,43.94)
  BOTTOM w0.508: v1(201.41,43.94) 201.42,43.93 C526.2
N17584896: length 3.4
  TOP w0.508: T8.7 v1(195.47,43.94)
  BOTTOM w0.508: C530.2 195.45,43.92 v1(195.47,43.94)
N17584902: length 3.4
  TOP w0.508: T8.10 v1(192.5,43.94)
  BOTTOM w0.508: v1(192.5,43.94) 192.53,43.91 C532.2
N17584942: length 2.1
  TOP w0.508: T10.4 v1(198.44,66.8)
  BOTTOM w0.508: v1(198.44,66.8) 198.5,66.74 C542.2
N17584944: length 2.1
  TOP w0.508: T10.1 v1(201.41,66.8)
  BOTTOM w0.508: v1(201.41,66.8) 201.42,66.79 C541.2
N17584949: length 2.1
  TOP w0.508: T10.7 v1(195.47,66.8)
  BOTTOM w0.508: v1(195.47,66.8) 195.45,66.78 C544.2
N17584952: length 2.1
  TOP w0.508: T10.10 v1(192.5,66.8)
  BOTTOM w0.508: v1(192.5,66.8) 192.53,66.77 C546.2
N17584987: length 69.6
  TOP w0.127: R363.2 C508.2 199.42,82.14 199.9,81.66 v1(201.68,81.66)
  L3SIG w0.102: J21.A12 186.6,26.83 187.45,27.69 v1(187.45,47.12)
  L6SIG w0.102: v1(201.68,81.66) 202.18,81.15 202.18,80.14 200.79,78.74 196.21,78.74 194.06,76.58 194.06,72.52 187.45,65.91 v1(187.45,47.12)
N17584990: length 79.8
  TOP w0.127: v1(201.68,80.64) 199.9,80.64 199.42,81.13 C510.2 R361.2
  L3SIG w0.102: J21.A10 173.99,26.35 v1(173.99,48.39)
  L6SIG w0.102: v1(201.68,80.64) 196.09,80.64 192.02,76.58 183.13,76.58 173.99,67.44 v1(173.99,48.39)
N17585015: length 82.3
  TOP w0.127: v1(200.03,79.25) 199.42,79.86 C522.2 R375.2
  L3SIG w0.102: v1(186.82,47.75) 186.82,46.86 187.07,46.61 187.07,27.94 185.42,26.29 185.42,23.88 186.6,22.7 J21.B12
  L6SIG w0.102: v1(200.03,79.25) 196.22,79.25 193.68,76.71 193.68,72.64 187.07,66.04 187.07,48.01 v1(186.82,47.75)
N17585018: length 92.4
  L3SIG w0.102: v1(173.36,49.02) 173.36,48.3 173.63,48.02 173.63,26.26 174.12,25.78 174.12,9.46 J21.B10
  L6SIG w0.102: v1(173.36,49.02) 173.36,49.15 173.63,49.43 173.63,67.59 183.01,76.96 191.9,76.96 194.06,79.12 194.06,82.68 v1(194.95,83.57)
  BOTTOM w0.127: R373.2 194.03,83.44 C524.2 194.79,83.41 v1(194.95,83.57)
N17585035: length 70
  L3SIG w0.102: v1(203.07,44.2) 203.07,27.69 202.35,26.96 J21.C12
  L6SIG w0.102: v1(195.83,83.57) 196.98,84.71 202.31,84.71 203.71,83.31 203.71,79.63 203.07,78.99 v1(203.07,44.2)
  BOTTOM w0.127: v1(195.83,83.57) 195.45,83.95 C536.2 195.43,84.45 R387.2
N17585038: length 72.3
  TOP w0.127: R385.2 C538.2 199.42,85.19 199.9,84.71 201.42,84.71 v1(201.93,84.2)
  L3SIG w0.102: v1(189.87,43.31) 189.87,38.73 191.17,37.43 J21.C10
  L6SIG w0.102: v1(189.87,43.31) 189.87,67.31 194.82,72.26 194.82,76.33 196.47,77.98 201.04,77.98 202.95,79.88 202.95,82.42 201.93,83.44 v1(201.93,84.2)
N17585055: length 81.8
  TOP w0.127: R397.2 C547.2 199.42,84.18 199.9,83.69 202.56,83.69 v1(202.82,83.44)
  L3SIG w0.102: J21.D12 202.35,22.82 201.17,24 201.17,26.42 202.69,27.94 202.69,43.69 202.56,43.81 v1(202.56,44.83)
  L6SIG w0.102: v1(202.56,44.83) 202.69,44.96 202.69,79.12 203.33,79.76 203.33,82.93 v1(202.82,83.44)
N17585058: length 88.3
  TOP w0.127: v1(202.18,82.42) 201.93,82.68 199.9,82.68 199.42,83.16 C550.2 R396.2
  L3SIG w0.102: J21.D10 189.87,9.47 189.87,25.4 190.75,26.29 190.75,37.21 189.48,38.48 189.48,42.67 189.23,42.93 v1(189.23,44.07)
  L6SIG w0.102: v1(202.18,82.42) 202.56,82.04 202.56,80.01 200.91,78.36 196.34,78.36 194.44,76.45 194.44,72.39 189.48,67.44 189.48,44.32 v1(189.23,44.07)
N17585063: length 81.8
  TOP w0.127: R399.2 C553.2 231.17,84.18 231.65,83.69 234.31,83.69 v1(234.57,83.44)
  L3SIG w0.102: J21.H12 232.66,9.35 232.66,25.78 234.19,27.3 v1(234.19,58.93)
  L6SIG w0.102: v1(234.19,58.93) 234.19,78.49 235.08,79.38 235.08,82.93 v1(234.57,83.44)
N17585067: length 86.7
  TOP w0.127: v1(233.93,82.42) 233.68,82.68 231.65,82.68 231.17,83.16 C554.2 R398.2
  L3SIG w0.102: v1(221.23,43.69) 221.23,9.6 J21.H10
  L6SIG w0.102: v1(221.23,43.69) 221.23,66.42 226.82,72.01 226.82,75.95 229.24,78.36 232.92,78.36 234.31,79.76 234.31,82.04 v1(233.93,82.42)
N17585093: length 3.4
  TOP w0.508: T4.1 v1(217.29,43.94)
  BOTTOM w0.508: v1(217.29,43.94) 217.3,43.93 C497.2
N17585097: length 3.4
  TOP w0.508: T4.4 v1(214.32,43.94)
  BOTTOM w0.508: v1(214.32,43.94) 214.38,43.88 C499.2
N17585100: length 3.4
  TOP w0.508: T4.7 v1(211.35,43.94)
  BOTTOM w0.508: C501.2 211.33,43.92 v1(211.35,43.94)
N17585103: length 3.4
  TOP w0.508: T4.10 v1(208.38,43.94)
  BOTTOM w0.508: C503.2 208.41,43.91 v1(208.38,43.94)
N17585145: length 2.1
  TOP w0.508: T7.1 v1(217.29,66.8)
  BOTTOM w0.508: C511.2 217.3,66.79 v1(217.29,66.8)
N17585149: length 2.1
  TOP w0.508: T7.4 v1(214.32,66.8)
  BOTTOM w0.508: v1(214.32,66.8) 214.38,66.74 C513.2
N17585152: length 2.1
  TOP w0.508: T7.7 v1(211.35,66.8)
  BOTTOM w0.508: v1(211.35,66.8) 211.33,66.78 C515.2
N17585155: length 2.1
  TOP w0.508: T7.10 v1(208.38,66.8)
  BOTTOM w0.508: C517.2 208.41,66.77 v1(208.38,66.8)
N17585198: length 3.4
  TOP w0.508: T9.4 v1(230.19,43.94)
  BOTTOM w0.508: v1(230.19,43.94) 230.25,43.88 C527.2
N17585202: length 3.4
  TOP w0.508: T9.1 v1(233.16,43.94)
  BOTTOM w0.508: v1(233.16,43.94) 233.17,43.93 C525.2
N17585205: length 3.4
  TOP w0.508: T9.7 v1(227.22,43.94)
  BOTTOM w0.508: C529.2 227.2,43.92 v1(227.22,43.94)
N17585209: length 3.4
  TOP w0.508: T9.10 v1(224.25,43.94)
  BOTTOM w0.508: v1(224.25,43.94) 224.28,43.91 C531.2
N17585248: length 2.1
  TOP w0.508: T11.4 v1(230.19,66.8)
  BOTTOM w0.508: C540.2 230.25,66.74 v1(230.19,66.8)
N17585251: length 2.1
  TOP w0.508: T11.1 v1(233.16,66.8)
  BOTTOM w0.508: v1(233.16,66.8) 233.17,66.79 C539.2
N17585256: length 2.1
  TOP w0.508: T11.7 v1(227.22,66.8)
  BOTTOM w0.508: v1(227.22,66.8) 227.2,66.78 C543.2
N17585259: length 2.1
  TOP w0.508: T11.10 v1(224.25,66.8)
  BOTTOM w0.508: v1(224.25,66.8) 224.28,66.77 C545.2
N17585292: length 69.4
  TOP w0.127: R362.2 C507.2 231.17,82.14 231.65,81.66 v1(233.43,81.66)
  L3SIG w0.102: J21.E12 218.69,25.52 218.69,42.29 v1(218.95,42.55)
  L6SIG w0.102: v1(233.43,81.66) 233.93,81.15 233.93,79.88 232.79,78.74 229.11,78.74 226.41,76.04 226.41,72.1 218.69,64.39 218.69,43.82 218.95,43.56 v1(218.95,42.55)
N17585295: length 82.2
  TOP w0.127: R360.2 C509.2 231.17,81.13 231.65,80.64 v1(233.43,80.64)
  L3SIG w0.102: v1(205.99,43.18) 205.74,42.93 205.74,26.1 J21.E10
  L6SIG w0.102: v1(233.43,80.64) 230,80.64 225.81,76.45 210.95,76.45 205.74,71.25 205.74,44.45 205.99,44.2 v1(205.99,43.18)
N17585312: length 81.6
  TOP w0.127: R374.2 C521.2 231.17,79.86 v1(231.78,79.25)
  L3SIG w0.102: J21.F12 218.1,22.19 216.79,23.5 216.79,25.91 218.31,27.43 v1(218.31,43.05)
  L6SIG w0.102: v1(231.78,79.25) 229.11,79.25 226.06,76.2 226.06,72.26 218.31,64.52 v1(218.31,43.05)
N17585315: length 94
  L3SIG w0.102: v1(205.36,43.94) 205.36,25.78 205.61,25.53 205.61,9.47 J21.F10
  L6SIG w0.102: v1(226.69,83.57) 225.3,82.17 225.3,79.25 222.89,76.84 210.82,76.84 205.36,71.37 v1(205.36,43.94)
  BOTTOM w0.127: R372.2 225.78,83.44 C523.2 226.54,83.41 v1(226.69,83.57)
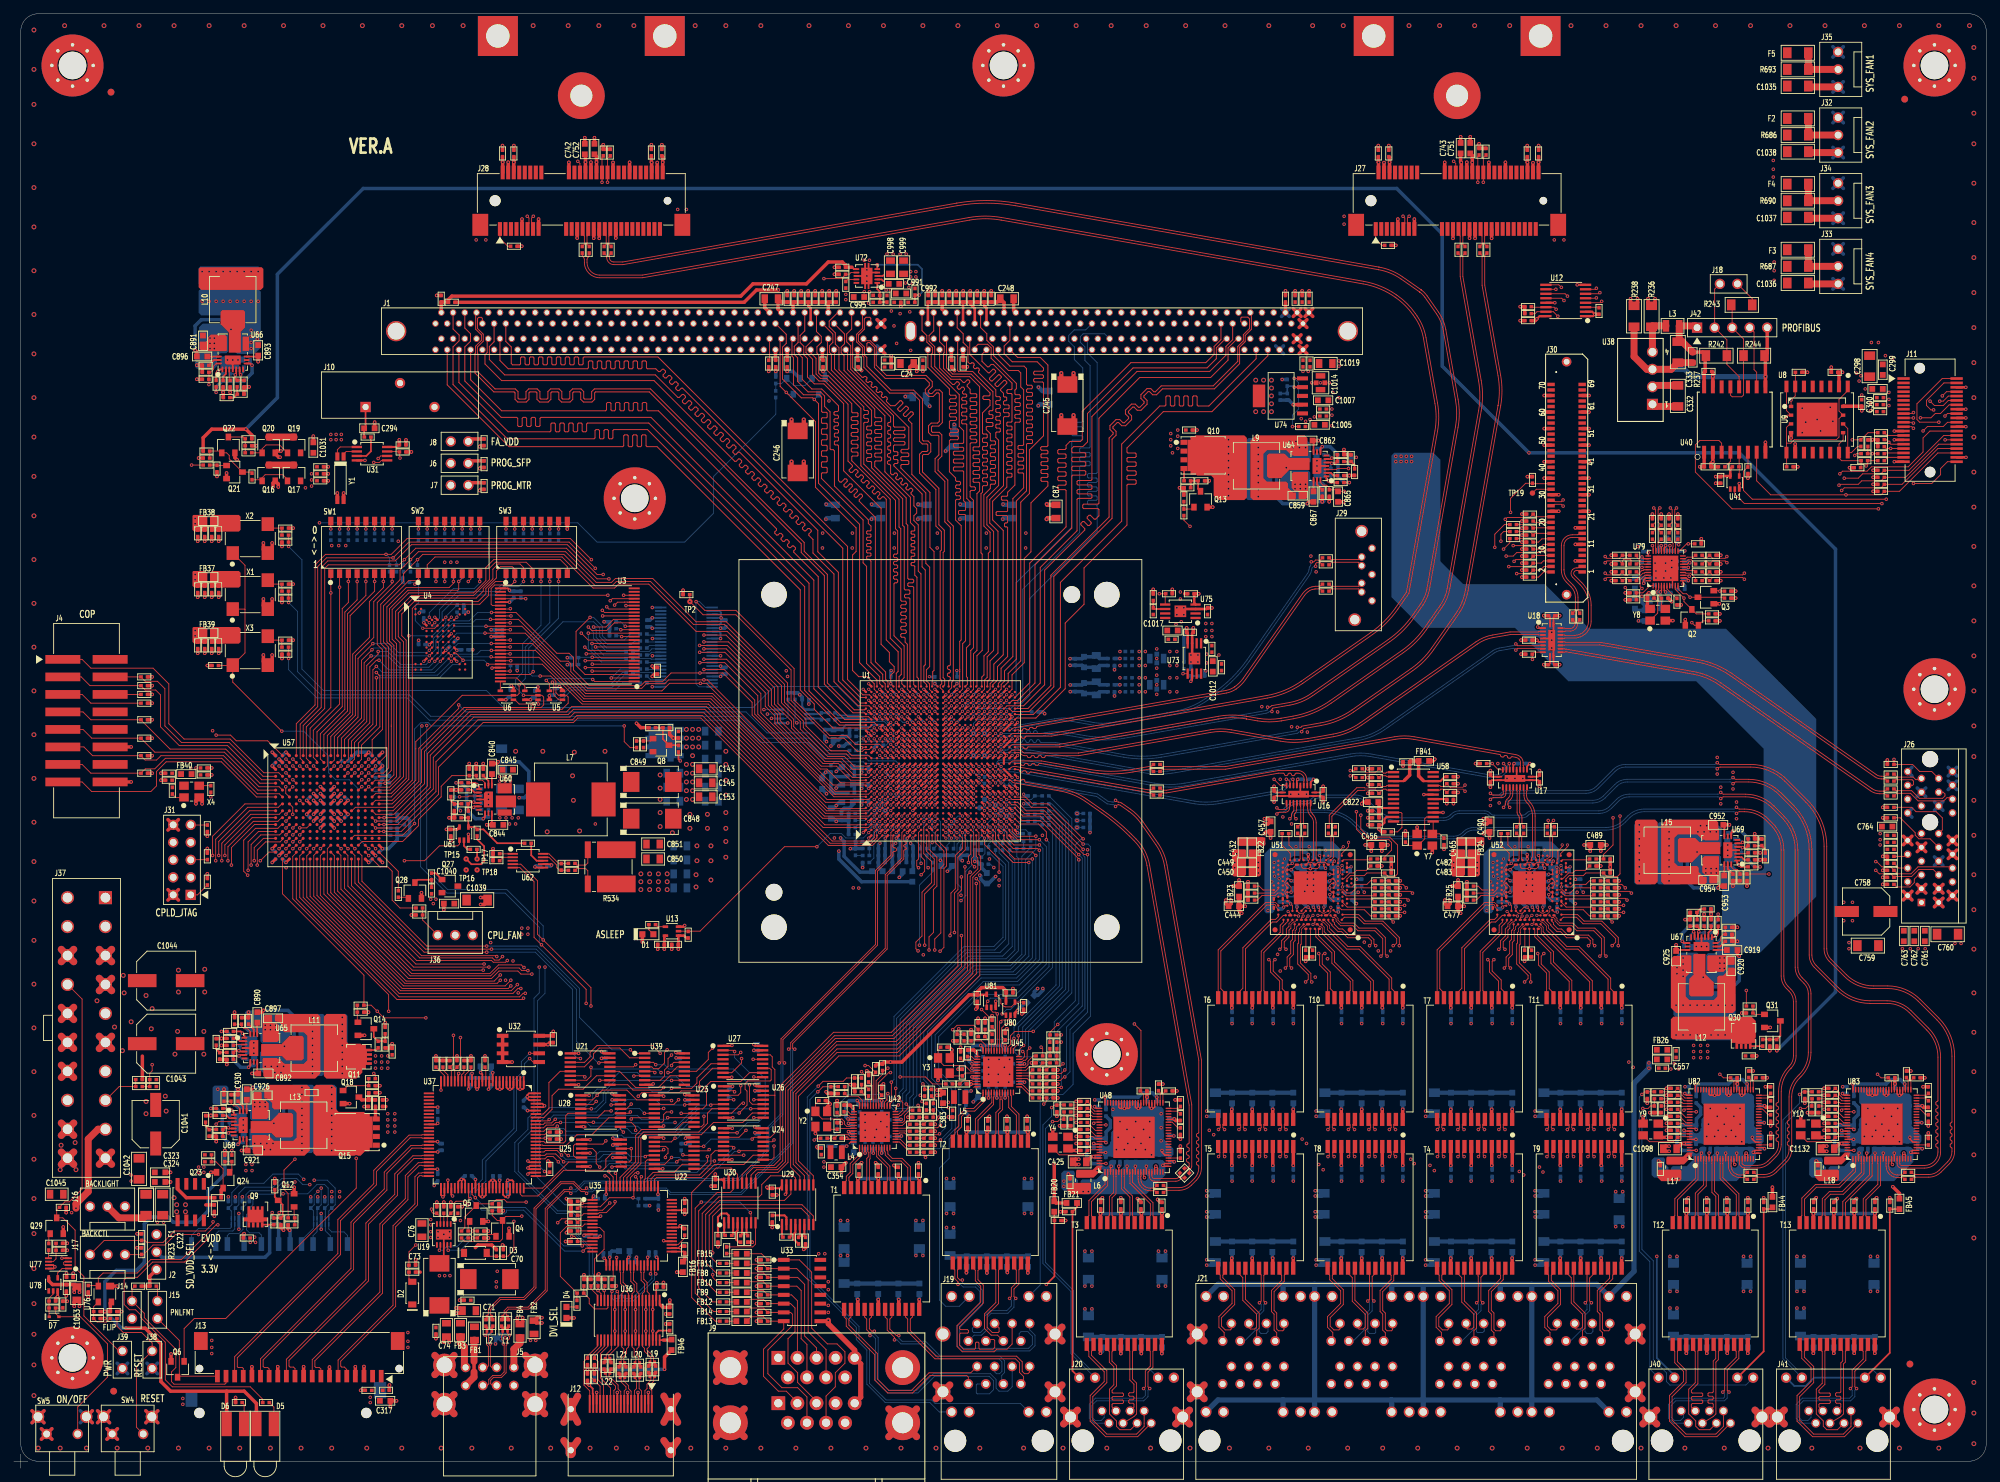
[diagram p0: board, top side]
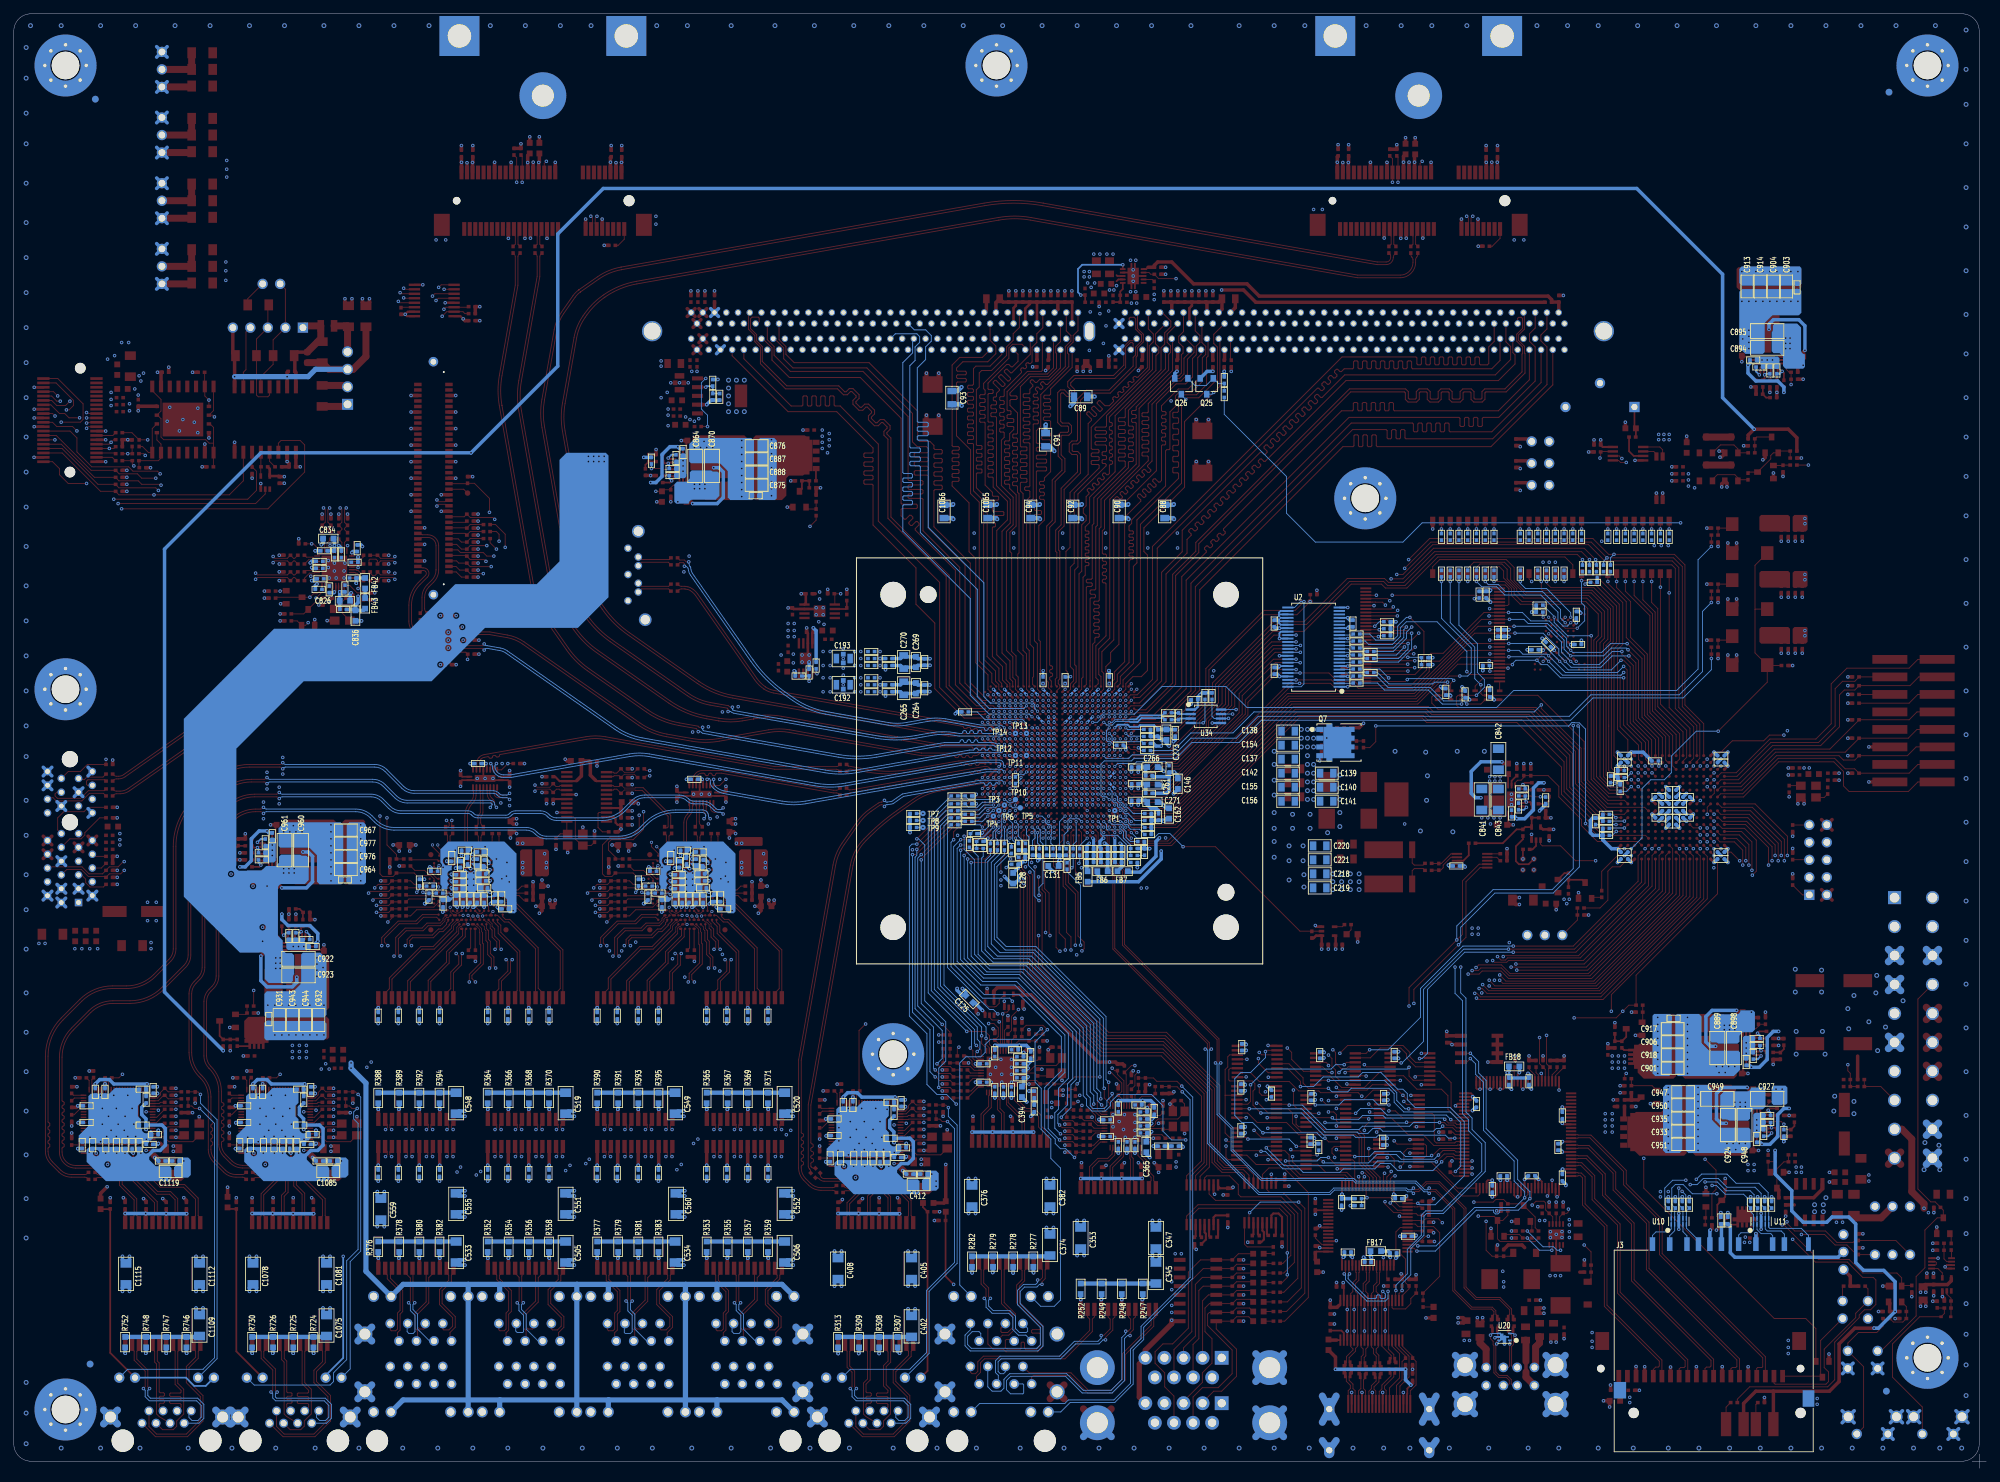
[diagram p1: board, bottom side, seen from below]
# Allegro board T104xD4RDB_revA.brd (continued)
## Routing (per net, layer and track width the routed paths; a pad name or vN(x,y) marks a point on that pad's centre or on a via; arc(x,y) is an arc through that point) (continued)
N17585332: length 70.3
  L3SIG w0.102: J21.G12 234.57,25.65 234.57,57.91 v1(234.82,58.17)
  L6SIG w0.102: v1(227.58,83.57) 228.73,84.71 234.06,84.71 235.46,83.31 235.46,79.25 234.57,78.36 234.57,59.56 234.82,59.31 v1(234.82,58.17)
  BOTTOM w0.127: v1(227.58,83.57) 227.2,83.95 C535.2 227.18,84.45 R386.2
N17585335: length 71.8
  TOP w0.127: v1(233.68,84.2) 233.17,84.71 231.65,84.71 231.17,85.19 C537.2 R384.2
  L3SIG w0.102: v1(221.74,42.97) 221.62,42.84 221.62,25.98 J21.G10
  L6SIG w0.102: v1(221.74,42.97) 221.74,44.2 221.62,44.32 221.62,66.29 227.2,71.88 227.2,75.82 229.36,77.98 233.05,77.98 234.7,79.63 234.7,82.42 233.68,83.44 v1(233.68,84.2)
N17588753: length 5
  TOP w0.127: U42.19 128.85,49.73 129.54,50.42 130.78,50.42 C343.2 R250.2
N17588764: length 2.5
  TOP w0.127: R251.2 129.41,46.86 128.55,47.73 U42.14
N17588767: length 2.5
  TOP w0.127: R253.2 129.18,48.64 128.46,48.64 128.35,48.53 U42.16
N17588769: length 2.1
  TOP w0.127: R254.2 129.91,48.93 U42.17
N17588771: length 2.3
  TOP w0.127: R255.2 129.37,49.33 U42.18
N17588772: length 2.7
  TOP w0.127: R256.2 129.92,45.85 128.44,47.33 U42.13
N17588858: length 3.7
  TOP w0.127: R262.1 129.92,51.94 129.16,51.18 129.16,50.42 128.87,50.13 U42.20
N17588875: length 8.6
  TOP w0.127: C350.1 116.24,52.85 Y2.1 116.24,51.65 117.22,50.67 120.08,50.67 120.46,50.29 120.46,49.91 120.78,49.59 121.22,49.59 121.35,49.73 U42.42
N17588878: length 4.1
  TOP w0.127: U42.43 121.4,49.33 121.35,49.28 119.48,49.28 C351.1 118.34,49.17 Y2.3
N17588897: length 4.2
  TOP w0.127: U42.46 121.29,48.13 121.03,48.39 119.53,48.39 C346.1 R258.1
N17588905: length 1.5
  TOP w0.127: U42.33 123.84,53.89 R264.1
N17588927: length 1.4
  TOP w0.203: 121.16,47.12 121.37,47.33 U42.48
  BOTTOM w0.508: R266.1 v1(120.78,46.74)
N17588950: length 1.1
  BOTTOM w0.508: C352.1 R266.2
N17589014: length 2.7
  TOP w0.127: R268.2 119.79,51.18 121.09,51.18 121.35,50.93 U42.39
N17590523: length 1.4
  TOP w0.127: 139.19,55.24 139.28,55.33 U45.48
  BOTTOM w0.508: R296.1 138.79,54.71 v1(138.81,54.74)
N17590546: length 1.1
  BOTTOM w0.508: R296.2 C381.1
N17590598: length 5
  TOP w0.127: U45.19 146.76,57.73 147.32,58.29 148.69,58.29 C372.2 R281.2
N17590603: length 2.4
  TOP w0.127: U45.14 146.2,55.73 147.19,54.74 R280.2
N17590606: length 2.3
  TOP w0.127: U45.16 146.95,56.53 R283.2
N17590608: length 2
  TOP w0.127: U45.17 147.56,56.93 R284.2
N17590610: length 2.2
  TOP w0.127: U45.18 147.27,57.33 R285.2
N17590611: length 2.6
  TOP w0.127: U45.13 146.12,55.33 R286.2
N17590657: length 17.1
  TOP w0.508: T2.1 v1(147.06,48.77) 146.94,48.88 C370.2 ; T2.7 v1(141.12,48.77) 141.22,48.88 C368.2 ; T2.10 v1(138.15,48.77) 138.3,48.93 C371.2 ; T2.4 v1(144.09,48.77) 144.02,48.84 C373.2
  BOTTOM w0.508: v1(147.06,48.77) v1(144.09,48.77) v1(141.12,48.77) v1(138.15,48.77)
N17590707: length 3.5
  TOP w0.127: U45.20 146.64,58.13 147.07,58.55 147.07,59.05 147.83,59.82 R292.1
N17590732: length 8.4
  TOP w0.127: U45.42 139.26,57.73 139.12,57.59 138.75,57.59 137.93,58.42 134.87,58.42 134.02,59.27 Y3.1 134.02,60.72 C379.1
N17590735: length 4.4
  TOP w0.127: U45.43 137.95,57.33 C380.1 136.12,56.92 Y3.3
N17590767: length 3.9
  TOP w0.127: U45.46 139.07,56.13 138.93,56.26 137.69,56.26 C375.1 R288.1
N17590774: length 1.5
  TOP w0.127: R294.1 141.75,61.89 U45.33
N17590779: length 2.7
  TOP w0.127: U45.39 139.32,58.93 139.07,59.18 137.57,59.18 R298.2
N17593781: length 2.3
  TOP w0.508: T1.15 v1(122.39,24.47)
  BOTTOM w0.508: v1(122.39,24.47) 122.3,24.56 R247.1
N17593783: length 2.2
  TOP w0.508: T1.18 v1(125.36,24.47)
  BOTTOM w0.508: v1(125.36,24.47) 125.35,24.48 R248.1
N17593791: length 2.2
  TOP w0.508: T1.21 v1(128.33,24.47)
  BOTTOM w0.508: R249.1 128.27,24.53 v1(128.33,24.47)
N17593793: length 2.2
  TOP w0.508: T1.24 v1(131.3,24.47)
  BOTTOM w0.508: R252.1 131.32,24.49 v1(131.3,24.47)
N17596169: length 1.9
  TOP w0.254: Q27.1 61.17,86.33 R692.2
N17597092: length 4.8
  TOP w0.127: R696.2 R695.1 59.28,79.53 J36.1
N17598342: length 1.5
  TOP w0.127: R694.2 57.06,82.83 Q28.1
N17604579: length 4.9
  TOP w0.127: R339.2 196.11,86.74 194.69,86.74 194.31,86.36 193.7,86.36 192.86,85.52 U51.C7
N17609926: length 3
  TOP w0.254: U73.6 170.87,114.36 v1(170.69,114.17)
  BOTTOM w0.254: R643.1 170.71,114.94 R646.2 v1(170.69,114.17)
N17609966: length 4
  TOP w0.254: R636.1 125.6,169.19 C1004.1 R640.2 125.58,170.71 125.2,171.09 U72.1
N17609980: length 13
  TOP w0.254: v1(131.29,170.21) C997.1 130.66,170.18 R631.1 ; U72.5 v1(125.2,174.6)
  BOTTOM w0.254: v1(131.29,170.21) 131.7,170.61 131.7,173.99 131.09,174.6 v1(125.2,174.6)
N17610004: length 1.7
  TOP w0.127: R641.1 120.94,172.47 U72.9
N17612202: length 2.9
  TOP w0.254: R651.2 R649.1 165.38,124.66 U75.6
N17629033: length 3
  TOP w0.127: U51.B12 181.16,83.89 180.59,84.45 R334.1
N17629034: length 4.6
  TOP w0.127: U51.D26 183.82,83.44 183.26,83.44 182.9,83.08 181,83.08 180.34,82.42 R335.1
N17629035: length 3.8
  TOP w0.127: U51.C19 183.36,84.05 182.75,83.44 R333.1
N17629454: length 2.7
  TOP w0.102: v2(192.61,87.45) 192.34,86.95 192.34,86.68 192.35,86.67 192.35,86.28 U51.D8
  BOTTOM w0.127: R337.2 192.81,87.25 v2(192.61,87.45)
N17629729: length 3.1
  TOP w0.127: C463.1 187.37,75.2 U51.A7
N17629871: length 3.2
  TOP w0.127: R340.2 188.02,75.48 U51.A8
N17632317: length 2.4
  TOP w0.508: T6.24 v1(185.53,52.07)
  BOTTOM w0.508: v1(185.53,52.07) 185.55,52.09 R365.1
N17632319: length 11.3
  BOTTOM w0.635: C520.2 R371.2 R369.2 R367.2 R365.2
N17632321: length 2.4
  TOP w0.508: T6.21 v1(182.56,52.07)
  BOTTOM w0.508: R367.1 182.5,52.13 v1(182.56,52.07)
N17632325: length 2.4
  TOP w0.508: T6.18 v1(179.59,52.07)
  BOTTOM w0.508: R369.1 179.58,52.08 v1(179.59,52.07)
N17632337: length 2.4
  TOP w0.508: T6.15 v1(176.62,52.07)
  BOTTOM w0.508: R371.1 176.66,52.11 v1(176.62,52.07)
N17632726: length 11.3
  BOTTOM w0.635: R377.2 R379.2 R381.2 R383.2 C534.2
N17632728: length 2.4
  TOP w0.508: T8.24 v1(201.4,30.48)
  BOTTOM w0.508: R377.1 201.42,30.5 v1(201.4,30.48)
N17632740: length 2.4
  TOP w0.508: T8.18 v1(195.46,30.48)
  BOTTOM w0.508: R381.1 195.45,30.49 v1(195.46,30.48)
N17632744: length 2.4
  TOP w0.508: T8.21 v1(198.43,30.48)
  BOTTOM w0.508: v1(198.43,30.48) 198.37,30.54 R379.1
N17632760: length 2.4
  TOP w0.508: T8.15 v1(192.49,30.48)
  BOTTOM w0.508: v1(192.49,30.48) 192.53,30.52 R383.1
N17633242: length 2.4
  TOP w0.508: T10.24 v1(201.4,52.07)
  BOTTOM w0.508: R390.1 201.42,52.09 v1(201.4,52.07)
N17633244: length 11.3
  BOTTOM w0.635: C549.2 R395.2 R393.2 R391.2 R390.2
N17633254: length 2.4
  TOP w0.508: T10.21 v1(198.43,52.07)
  BOTTOM w0.508: R391.1 198.37,52.13 v1(198.43,52.07)
N17633258: length 2.4
  TOP w0.508: T10.18 v1(195.46,52.07)
  BOTTOM w0.508: R393.1 195.45,52.08 v1(195.46,52.07)
N17633270: length 2.4
  TOP w0.508: T10.15 v1(192.49,52.07)
  BOTTOM w0.508: v1(192.49,52.07) 192.53,52.11 R395.1
N17639917: length 3.1
  TOP w0.127: C496.1 219.12,75.2 U52.A7
N17639934: length 3.2
  TOP w0.127: R351.2 219.77,75.48 U52.A8
N17639958: length 4.4
  TOP w0.127: R349.2 215.67,91.71 215.65,91.69 215.65,90.42 216.84,89.23 U52.D18
N17639964: length 4.2
  TOP w0.127: U52.D17 217.49,89.59 216.65,90.43 216.65,91.57 216.64,91.58 R349.1
N17639984: length 4.9
  TOP w0.127: U52.C7 224.61,85.52 225.45,86.36 226.06,86.36 226.44,86.74 227.86,86.74 R350.2
N17640717: length 4.2
  TOP w0.127: R342.1 228.37,88.27 224.57,88.27 U52.C10
N17650951: length 3
  TOP w0.127: U52.B12 212.91,83.89 212.34,84.45 R345.1
N17650952: length 4.6
  TOP w0.127: R346.1 212.09,82.42 212.75,83.08 214.65,83.08 215.01,83.44 215.57,83.44 U52.D26
N17650953: length 3.8
  TOP w0.127: U52.C19 215.11,84.05 214.5,83.44 R344.1
N17650962: length 2.7
  TOP w0.102: U52.D8 224.1,86.28 224.1,86.67 224.09,86.68 224.09,86.95 v2(224.36,87.45)
  BOTTOM w0.127: v2(224.36,87.45) 224.56,87.25 R348.2
N17692970: length 7.7
  TOP w0.127: U58.14 204.85,94.48 204.6,94.23 204.6,91.31 203.62,90.34 Y7.1 202.3,90.34 C816.1
N17692982: length 3.8
  TOP w0.127: C817.1 206.77,92.04 Y7.3 205.82,92.16 U58.13
N17693054: length 5.1
  TOP w0.127: U58.10 201.16,95.13 201.3,95 201.3,92.96 200.66,92.33 R493.2
N17696036: length 2.6
  TOP w0.127: Q12.1 40.65,36.42 R661.2 R664.2
N17696038: length 5.7
  TOP w0.254: R658.2 37.85,39.36 Q12.3 38.99,38.22 38.99,36.55 C1025.2 R655.2
N17696060: length 1.7
  TOP w0.254: Q9.4 36.05,35.33 R655.1
N17697384: length 3.3
  TOP w0.127: R489.1 C807.1 37.41,120.14 X3.3
N17708927: length 1.7
  TOP w0.127: R492.1 26.89,99.03 X4.3
N17708947: length 1.9
  TOP w0.127: X4.1 23.48,97.32 R491.2
N17736577: length 1.8
  TOP w0.127: SW1.16 v1(45.97,136.27)
  BOTTOM w0.127: R31.1 v1(45.97,136.27)
N17736598: length 1.8
  TOP w0.127: SW1.15 v1(47.24,136.27)
  BOTTOM w0.127: R33.1 v1(47.24,136.27)
N17736619: length 1.8
  TOP w0.127: SW1.14 v1(48.51,136.27)
  BOTTOM w0.127: R35.1 v1(48.51,136.27)
N17736629: length 1.8
  TOP w0.127: SW1.13 v1(49.78,136.27)
  BOTTOM w0.127: R37.1 v1(49.78,136.27)
N17736659: length 1.8
  TOP w0.127: SW1.12 v1(51.05,136.27)
  BOTTOM w0.127: R38.1 v1(51.05,136.27)
N17736669: length 1.8
  TOP w0.127: SW1.11 v1(52.32,136.27)
  BOTTOM w0.127: R39.1 v1(52.32,136.27)
N17736681: length 1.8
  TOP w0.127: SW1.10 v1(53.59,136.27)
  BOTTOM w0.127: R40.1 v1(53.59,136.27)
N17736695: length 1.8
  TOP w0.127: SW1.9 v1(54.86,136.27)
  BOTTOM w0.127: R41.1 v1(54.86,136.27)
N17736739: length 1.8
  TOP w0.127: SW2.16 v1(58.67,136.27)
  BOTTOM w0.127: R42.1 v1(58.67,136.27)
N17736751: length 1.8
  TOP w0.127: SW2.15 v1(59.94,136.27)
  BOTTOM w0.127: R43.1 v1(59.94,136.27)
N17736763: length 1.8
  TOP w0.127: SW2.14 v1(61.21,136.27)
  BOTTOM w0.127: R44.1 v1(61.21,136.27)
N17736781: length 1.8
  TOP w0.127: SW2.13 v1(62.48,136.27)
  BOTTOM w0.127: R45.1 v1(62.48,136.27)
N17736801: length 1.8
  TOP w0.127: SW2.11 v1(65.02,136.27)
  BOTTOM w0.127: R48.1 v1(65.02,136.27)
N17736803: length 1.8
  TOP w0.127: SW2.12 v1(63.75,136.27)
  BOTTOM w0.127: R46.1 v1(63.75,136.27)
N17736817: length 1.8
  TOP w0.127: SW2.10 v1(66.29,136.27)
  BOTTOM w0.127: R47.1 v1(66.29,136.27)
N17736835: length 1.8
  TOP w0.127: SW2.9 v1(67.56,136.27)
  BOTTOM w0.127: R49.1 v1(67.56,136.27)
N17742094: length 7.4
  TOP w0.127: R681.2 C1034.2 29.34,44.45 30.35,43.43 Q24.3
  TOP w0.508: Q24.3 30.07,40.35 R680.2
N17743915: length 4.4
  TOP w0.254: 186.87,156.84 v1(185.67,156.84)
  BOTTOM w0.254: v1(185.67,156.84) 185.52,157 R647.2 R644.1 C1011.1
N17748293: length 26
  TOP w0.127: J13.19 30.78,12.36 30.61,12.19 23.24,12.19 22.86,12.57 22.86,13.97 23.5,14.61 23.5,17.27 18.92,21.84 18.92,22.48 J14.1 17.15,26.01 R224.2
N17749501: length 2.2
  TOP w0.127: R227.1 20.83,26.26 J15.1
N17749602: length 15.6
  TOP w0.127: Q6.3 23.91,13.36 ; 23.91,13.36 J13.20 ; 23.91,13.36 24,13.45 24,18.54 J15.2
N17792541: length 11.3
  BOTTOM w0.635: R352.2 R354.2 R356.2 R358.2 C505.2
N17792543: length 11.3
  BOTTOM w0.635: R364.2 R366.2 R368.2 R370.2 C519.2
N17792545: length 11.3
  BOTTOM w0.635: R376.2 R378.2 R380.2 R382.2 C533.2
N17792547: length 11.3
  BOTTOM w0.635: C548.2 R394.2 R392.2 R389.2 R388.2
N17792549: length 2.4
  TOP w0.508: T4.24 v1(217.28,30.48)
  BOTTOM w0.508: v1(217.28,30.48) 217.3,30.5 R352.1
N17792551: length 2.4
  TOP w0.508: T4.21 v1(214.31,30.48)
  BOTTOM w0.508: v1(214.31,30.48) 214.25,30.54 R354.1
N17792553: length 2.4
  TOP w0.508: T4.18 v1(211.34,30.48)
  BOTTOM w0.508: R356.1 211.33,30.49 v1(211.34,30.48)
N17792555: length 2.4
  TOP w0.508: T4.15 v1(208.37,30.48)
  BOTTOM w0.508: v1(208.37,30.48) 208.41,30.52 R358.1
N17792589: length 2.4
  TOP w0.508: T7.24 v1(217.28,52.07)
  BOTTOM w0.508: R364.1 217.3,52.09 v1(217.28,52.07)
N17792591: length 2.4
  TOP w0.508: T7.21 v1(214.31,52.07)
  BOTTOM w0.508: v1(214.31,52.07) 214.25,52.13 R366.1
N17792593: length 2.4
  TOP w0.508: T7.18 v1(211.34,52.07)
  BOTTOM w0.508: R368.1 211.33,52.08 v1(211.34,52.07)
N17792595: length 2.4
  TOP w0.508: T7.15 v1(208.37,52.07)
  BOTTOM w0.508: v1(208.37,52.07) 208.41,52.11 R370.1
N17792630: length 2.4
  TOP w0.508: T9.21 v1(230.18,30.48)
  BOTTOM w0.508: v1(230.18,30.48) 230.12,30.54 R378.1
N17792632: length 2.4
  TOP w0.508: T9.24 v1(233.15,30.48)
  BOTTOM w0.508: R376.1 233.17,30.5 v1(233.15,30.48)
N17792634: length 2.4
  TOP w0.508: T9.15 v1(224.24,30.48)
  BOTTOM w0.508: v1(224.24,30.48) 224.28,30.52 R382.1
N17792636: length 2.4
  TOP w0.508: T9.18 v1(227.21,30.48)
  BOTTOM w0.508: R380.1 227.2,30.49 v1(227.21,30.48)
N17792669: length 2.4
  TOP w0.508: T11.24 v1(233.15,52.07)
  BOTTOM w0.508: R388.1 233.17,52.09 v1(233.15,52.07)
N17792671: length 2.4
  TOP w0.508: T11.21 v1(230.18,52.07)
  BOTTOM w0.508: v1(230.18,52.07) 230.12,52.13 R389.1
N17792673: length 2.4
  TOP w0.508: T11.18 v1(227.21,52.07)
  BOTTOM w0.508: v1(227.21,52.07) 227.2,52.08 R392.1
N17792675: length 2.4
  TOP w0.508: T11.15 v1(224.24,52.07)
  BOTTOM w0.508: v1(224.24,52.07) 224.28,52.11 R394.1
N17823659: length 4.4
  TOP w0.102: U51.D12 190.47,88.39 190.63,88.39 190.9,88.66
  TOP w0.127: 190.9,88.66 191.01,88.77 191.01,91.72 C443.2
N17823662: length 4.2
  TOP w0.102: 191,88.28 U51.D11
  TOP w0.127: C442.2 191.39,91.85 191.39,88.62 191.05,88.28 191,88.28
N17824163: length 4.4
  TOP w0.102: U52.D12 222.22,88.39 222.38,88.39 222.65,88.66
  TOP w0.127: 222.65,88.66 222.76,88.77 222.76,91.72 C476.2
N17824166: length 4.2
  TOP w0.102: 222.75,88.28 U52.D11
  TOP w0.127: C475.2 223.14,91.85 223.14,88.62 222.8,88.28 222.75,88.28
N17947254: length 2.5
  TOP w0.127: R525.2 241.07,126.21 239.72,127.56 U79.6
N17947282: length 3.9
  TOP w0.127: U79.1 237.28,128.06 236.22,127 R523.2 R528.2
N17947998: length 5.9
  TOP w0.127: U79.2 238.12,127.5 237.85,127.23 C824.1 238.38,125.7 238.38,124.08 Y8.1
N17948004: length 4
  TOP w0.127: U79.3 238.52,127.52 238.25,127.25 238.25,126.88 238.89,126.24 C825.1 238.91,125.24 Y8.3
N17952438: length 2.5
  TOP w0.127: R500.1 243.87,129.13 243.14,129.86 242.48,129.86 242.38,129.96 U79.14
N17952440: length 2
  TOP w0.127: R501.1 243.67,130.24 242.64,130.24 242.52,130.36 U79.15
N17952563: length 1.9
  TOP w0.127: U79.22 240.92,133.46 240.98,133.52 240.98,134.45 R506.1
N17952565: length 2
  TOP w0.127: U79.23 240.52,133.59 240.6,133.67 240.6,134.2 R507.1
N17952567: length 1.9
  TOP w0.127: R514.1 238.44,134.33 238.44,133.67 238.52,133.59 U79.28
N17952569: length 1.9
  TOP w0.127: U79.29 238.12,133.46 238.06,133.52 238.06,134.33 R515.1
N17952583: length 2.2
  TOP w0.127: R518.1 235.31,132.23 235.99,131.55 236.34,131.55 236.35,131.56 U79.33
N17952585: length 1.9
  TOP w0.127: R519.1 235.47,131.35 235.65,131.35 235.83,131.17 236.5,131.17 236.51,131.16 U79.34
N17952595: length 2.3
  TOP w0.127: U79.37 236.53,129.96 236.44,129.86 236.24,129.86 235.31,128.92 R524.1
N17952601: length 2
  TOP w0.127: U79.36 236.4,130.36 236.38,130.34 236.38,130.34 236.28,130.24 236.08,130.24 235.69,129.84 235.51,129.84 R522.1
N17952605: length 2.1
  TOP w0.127: U79.19 242.42,131.96 242.64,132.18 243.59,132.18 R504.1
N17952607: length 2.2
  TOP w0.127: R511.1 243.25,131.8 242.8,131.8 242.55,131.56 U79.18
N17979212: length 51.1
  TOP w0.127: v1(131.83,55.75) 132.08,55.5 R715.2 R711.2 ; U1.AD1 141.97,90.83 144.91,87.88 v1(147.19,87.88)
  BOTTOM w0.127: v1(147.19,87.88) 147.19,74.3 144.91,72.01 139.83,72.01 131.44,63.63 131.44,56.13 v1(131.83,55.75)
N17979230: length 77.5
  TOP w0.127: R714.2 131.98,52.93 v1(131.7,53.21) ; R715.1 131.55,54 v1(131.45,54.1)
  L3SIG w0.102: v1(131.7,53.21) 131.45,53.47 129.77,53.47 129.67,53.57 129.67,53.96 129.77,54.06 130.58,54.06 130.68,54.16 130.68,54.57 130.58,54.67 129.26,54.67 129.16,54.77 129.16,55.18 129.26,55.28 130.58,55.28 130.68,55.38 130.68,55.79 130.58,55.89 129.26,55.89 129.16,55.99 129.16,56.4 129.26,56.5 130.58,56.5 130.68,56.6 130.68,57.01 130.58,57.11 129.26,57.11 129.16,57.21 129.16,57.91 132.08,60.83 132.87,60.83 132.97,60.73 132.97,60.2 132.87,60.09 132.31,60.09 132.21,59.99 132.21,59.59 132.31,59.48 133.38,59.48 133.48,59.38 133.48,58.98 133.38,58.87 132.31,58.87 132.21,58.77 132.21,58.37 132.31,58.27 133.38,58.27 133.48,58.16 133.48,57.25 132.97,56.74 132.97,53.56 133.07,53.46 133.76,53.46 133.86,53.36 133.86,52.95 133.76,52.85 133.07,52.85 132.97,52.75 132.97,52.34 133.07,52.24 133.76,52.24 133.86,52.14 133.86,51.73 133.76,51.63 133.07,51.63 132.97,51.53 132.97,46.07 132.87,45.97 129.51,45.97 129.41,46.07 129.41,46.48 129.51,46.58 132.17,46.58 132.27,46.68 132.27,47.09 132.17,47.19 129.51,47.19 129.41,47.29 129.41,47.7 129.51,47.8 132.17,47.8 132.27,47.9 132.27,48.31 132.17,48.41 129.51,48.41 129.41,48.51 129.41,48.92 129.51,49.02 132.17,49.02 132.27,49.12 132.27,49.53 132.17,49.63 129.9,49.63 129.79,49.73 129.79,50.14 129.9,50.24 132.17,50.24 132.27,50.34 132.27,50.79 132.17,50.89 130.4,50.89 130.3,50.99 130.3,51.4 130.4,51.5 132.17,51.5 132.27,51.6 132.27,53.91 132.08,54.1 v1(131.45,54.1)
N17979244: length 1.2
  TOP w0.127: R710.2 133.35,53.75 R711.1
N17979345: length 77.2
  TOP w0.127: R716.2 v1(151.89,62.87) ; R717.1 v1(151.89,61.82)
  L3SIG w0.102: v1(151.89,61.82) 150.72,61.82 150.62,61.72 150.62,60.79 150.72,60.69 152.04,60.69 152.15,60.59 152.15,60.18 152.04,60.08 150.72,60.08 150.62,59.98 150.62,59.54 150.72,59.44 152.65,59.44 152.91,59.69 152.91,64.92 153.01,65.02 154.46,65.02 154.56,65.12 154.56,65.53 154.46,65.63 153.01,65.63 152.91,65.73 152.91,66.14 153.01,66.24 154.46,66.24 154.56,66.34 154.56,66.75 154.46,66.85 153.01,66.85 152.91,66.95 152.91,67.36 153.01,67.46 154.46,67.46 154.56,67.56 154.56,67.97 154.46,68.07 153.01,68.07 152.91,68.17 152.91,68.58 153.01,68.68 154.46,68.68 154.56,68.78 154.56,69.19 154.46,69.29 153.01,69.29 152.91,69.39 152.91,69.8 153.01,69.9 154.46,69.9 154.56,70 154.56,70.41 154.46,70.51 153.01,70.51 152.91,70.61 152.91,71.02 153.01,71.12 154.08,71.12 154.18,71.22 154.18,71.63 154.08,71.73 153.01,71.73 152.91,71.83 152.91,73.56 152.81,73.66 150.72,73.66 150.62,73.56 150.62,73.08 150.72,72.98 152.17,72.98 152.27,72.88 152.27,72.47 152.17,72.37 150.72,72.37 150.62,72.27 150.62,71.86 150.72,71.76 152.17,71.76 152.27,71.66 152.27,71.25 152.17,71.15 150.72,71.15 150.62,71.05 150.62,70.64 150.72,70.54 152.17,70.54 152.27,70.44 152.27,70.03 152.17,69.93 150.72,69.93 150.62,69.83 150.62,69.42 150.72,69.32 152.17,69.32 152.27,69.22 152.27,68.81 152.17,68.71 150.72,68.71 150.62,68.61 150.62,68.2 150.72,68.1 152.17,68.1 152.27,68 152.27,67.59 152.17,67.49 150.72,67.49 150.62,67.39 150.62,66.98 150.72,66.88 152.17,66.88 152.27,66.78 152.27,66.37 152.17,66.27 150.72,66.27 150.62,66.17 150.62,65.76 150.72,65.66 152.17,65.66 152.27,65.56 152.27,65.15 152.17,65.05 150.72,65.05 150.62,64.95 150.62,63.12 150.88,62.87 v1(151.89,62.87)
N17979374: length 40.3
  TOP w0.127: R712.1 150.24,62.84 R716.1 150.27,63.27 v1(151.38,64.39) ; v1(154.43,88.27) 154.43,88.39 148.84,93.98 146.18,93.98 145.17,94.99 U1.AH5
  BOTTOM w0.127: v1(151.38,64.39) 154.43,67.44 v1(154.43,88.27)
N17979380: length 1.1
  TOP w0.127: R713.1 150.27,60.83 R712.2
N18177051: length 4.9
  TOP w0.254: R720.2 C1069.2 R721.2 256.17,62.72 Q31.3
N18177053: length 2.8
  TOP w0.127: Q31.1 252.39,65.85 R723.2 R722.2
N18177080: length 1.8
  TOP w0.254: R720.1 251.82,61.24 Q30.4
N18178202: length 5.6
  TOP w0.127: R718.1 146.34,67.62 U80.4 145.18,67.45 144.65,66.93 143.76,66.93 143.69,66.99 143.57,66.99 143.13,67.44 143.13,67.94 142.38,68.69 U81.4
N18200115: length 2.2
  TOP w0.508: T12.15 v1(242.53,16.68)
  BOTTOM w0.508: R724.1 242.57,16.72 v1(242.53,16.68)
N18200130: length 2.2
  TOP w0.508: T12.21 v1(248.47,16.68)
  BOTTOM w0.508: v1(248.47,16.68) 248.41,16.73 R726.1
N18200132: length 10.8
  BOTTOM w0.635: C1075.1 240.79,19.05 R724.2 R725.2 R726.2 R730.2
N18200134: length 2.1
  TOP w0.508: T12.18 v1(245.5,16.68)
  BOTTOM w0.508: v1(245.5,16.68) 245.49,16.69 R725.1
N18200140: length 2.1
  TOP w0.508: T12.24 v1(251.44,16.68)
  BOTTOM w0.508: v1(251.44,16.68) 251.46,16.7 R730.1
N18200177: length 16.9
  TOP w0.508: C1074.2 245.49,36.96 v1(245.51,36.94) T12.7 ; C1073.2 248.41,37.02 v1(248.48,36.96) T12.4 ; C1072.2 v1(251.46,36.96) 251.45,36.95 T12.1 ; C1070.2 242.57,36.96 v1(242.54,36.93) T12.10
  BOTTOM w0.508: v1(251.46,36.96) v1(248.48,36.96) 248.46,36.94 v1(245.51,36.94) 245.5,36.93 v1(242.54,36.93)
N18200226: length 27.4
  TOP w0.254: FB44.2 254.79,37.62 C1071.1 253.75,16.95 J40.11
N18200230: length 57.6
  TOP w0.127: v1(236.22,52.2) 236.98,52.2 237.34,52.55 C1079.1 237.9,52.58 R734.2
  BOTTOM w0.127: v1(236.22,52.2) 236.73,51.69 236.73,50.67 236.09,50.04 236.09,31.75 237.74,30.1 237.74,15.75 239.65,13.84 239.65,12.57 240.16,12.06 251.15,12.06 J40.12
N18200232: length 44.4
  TOP w0.127: v1(236.09,54.23) 236.45,54.58 C1080.1 236.88,54.61 R733.2
  BOTTOM w0.127: v1(236.09,54.23) 235.71,53.85 235.71,31.5 237.24,29.97 237.24,14.4 J40.9
N18200292: length 1.9
  TOP w0.127: U82.43 254.37,53.71 R728.2
N18200294: length 1.8
  TOP w0.127: U82.44 254.49,54.11 R729.2
N18200344: length 1.9
  TOP w0.127: U82.45 252.23,56.24 R732.2
N18200346: length 1.9
  TOP w0.127: U82.46 251.83,56.42 R731.2
N18200354: length 2.2
  TOP w0.127: R739.1 242.43,50.91 U82.75
N18200448: length 0.9
  TOP w0.127: U82.88 243.03,45.55
  BOTTOM w0.508: R742.1 242.19,44.58 v1(242.7,45.09)
N18200458: length 1.1
  BOTTOM w0.508: C1084.1 R742.2
N18200620: length 4.8
  TOP w0.127: C1076.1 251.22,42.05 arc(251.09,42.13) 250.94,42.16 250.32,42.16 arc(249.13,42.66) 248.64,43.84 248.64,44.23 248.63,44.24 U82.13
N18200622: length 4.3
  TOP w0.127: U82.14 249.03,44.24 249.02,44.23 249.02,43.84 arc(249.4,42.92) 250.32,42.55 250.72,42.55 arc(250.96,42.59) 251.16,42.73 C1077.1
N18200686: length 1.8
  TOP w0.127: U82.70 242.06,52.91 241.89,53.09 R735.1
N18200704: length 4.2
  TOP w0.127: U82.71 241.88,52.51 241.83,52.55 R737.1
N18200722: length 5.2
  TOP w0.127: U82.81 241.79,48.51 C1082.1 241.27,49.05 240.79,49.53 238.93,49.53 Y9.1
N18200732: length 7.5
  TOP w0.127: U82.82 241.38,48.11 C1083.1 241.27,47.98 240.67,47.37 237.19,47.37 Y9.3
N18200786: length 2.1
  TOP w0.127: R727.2 254.41,51.28 253.58,52.11 U82.39
N18200821: length 2.1
  TOP w0.127: U82.77 242.5,50.11 241.55,51.05 R741.2
N18200841: length 1.7
  TOP w0.127: R744.2 254.74,46.91 U82.26
N18201157: length 1.9
  TOP w0.127: R743.2 242.06,50.04 242.39,49.71 U82.78
N18205066: length 2.2
  TOP w0.508: T13.15 v1(260.94,16.68)
  BOTTOM w0.508: v1(260.94,16.68) 260.99,16.72 R746.1
N18205081: length 2.2
  TOP w0.508: T13.21 v1(266.88,16.68)
  BOTTOM w0.508: R748.1 266.83,16.73 v1(266.88,16.68)
N18205083: length 10.8
  BOTTOM w0.635: C1109.1 259.21,19.05 R746.2 R747.2 R748.2 R752.2
N18205085: length 2.1
  TOP w0.508: T13.18 v1(263.91,16.68)
  BOTTOM w0.508: v1(263.91,16.68) 263.91,16.69 R747.1
N18205091: length 2.1
  TOP w0.508: T13.24 v1(269.85,16.68)
  BOTTOM w0.508: v1(269.85,16.68) 269.88,16.7 R752.1
N18205128: length 16.9
  TOP w0.508: T13.7 v1(263.92,36.94) 263.91,36.96 C1108.2 ; C1104.2 266.83,37.02 v1(266.89,36.96) T13.4 ; C1107.2 260.99,36.96 v1(260.95,36.93) T13.10 ; T13.1 269.86,36.95 v1(269.88,36.96) C1106.2
  BOTTOM w0.508: v1(260.95,36.93) 263.91,36.93 v1(263.92,36.94) 266.88,36.94 v1(266.89,36.96) v1(269.88,36.96)
N18205177: length 39.8
  TOP w0.254: J41.11 272.03,16.74 C1105.1 272.06,37.59 FB45.2
  BOTTOM w0.254: J41.9 257,13.13 258.19,11.94 259.84,11.94 261.04,13.14 J41.11
N18205181: length 54.9
  TOP w0.127: R756.2 260.76,52.58 C1113.1 260.2,52.55 259.84,52.2 v1(259.08,52.2)
  BOTTOM w0.127: J41.12 269.51,14.35 258.57,14.35 256.92,16 256.92,50.04 v1(259.08,52.2)
N18205183: length 45.2
  TOP w0.127: R755.2 259.74,54.61 C1114.1 259.31,54.58 v1(258.95,54.23)
  BOTTOM w0.127: v1(258.95,54.23) 258.95,52.96 256.54,50.55 256.54,15.89 J41.10
N18205243: length 1.9
  TOP w0.127: U83.43 277.23,53.71 R750.2
N18205245: length 1.8
  TOP w0.127: U83.44 277.35,54.11 R751.2
N18205295: length 1.9
  TOP w0.127: U83.45 275.09,56.24 R754.2
N18205297: length 1.9
  TOP w0.127: U83.46 274.69,56.42 R753.2
N18205305: length 2.2
  TOP w0.127: R761.1 265.29,50.91 U83.75
N18205399: length 0.9
  TOP w0.127: U83.88 265.89,45.55
  BOTTOM w0.508: v1(265.56,45.09) 265.05,44.58 R764.1
N18205409: length 1.1
  BOTTOM w0.508: C1118.1 R764.2
N18205571: length 4.8
  TOP w0.127: C1110.1 274.08,42.05 arc(273.95,42.13) 273.8,42.16 273.18,42.16 arc(271.99,42.66) 271.5,43.84 271.5,44.23 271.49,44.24 U83.13
N18205573: length 4.3
  TOP w0.127: C1111.1 274.02,42.73 arc(273.82,42.59) 273.58,42.55 273.18,42.55 arc(272.26,42.92) 271.88,43.84 271.88,44.23 271.89,44.24 U83.14
N18205637: length 1.8
  TOP w0.127: U83.70 264.92,52.91 264.75,53.09 R757.1
N18205655: length 4.2
  TOP w0.127: U83.71 264.74,52.51 264.69,52.55 R759.1
N18205673: length 5.2
  TOP w0.127: U83.81 264.65,48.51 C1116.1 264.13,49.05 263.65,49.53 261.79,49.53 Y10.1
N18205683: length 7.5
  TOP w0.127: Y10.3 260.05,47.37 263.52,47.37 264.13,47.98 C1117.1 264.24,48.11 U83.82
N18205737: length 2.1
  TOP w0.127: U83.39 276.44,52.11 277.27,51.28 R749.2
N18205772: length 2.1
  TOP w0.127: U83.77 265.36,50.11 264.41,51.05 R762.2
N18205792: length 1.7
  TOP w0.127: R766.2 277.6,46.91 U83.26
N18206108: length 1.9
  TOP w0.127: U83.78 265.25,49.71 264.92,50.04 R765.2
N18257321: length 1.8
  TOP w0.254: 94.19,18.59 U36.38
  TOP w0.508: 94.19,18.59 95.3,18.59 FB46.1
N18275528: length 2.5
  TOP w0.127: Q14.1 49.81,64.8 R666.2 R663.2
N18275529: length 4.1
  TOP w0.254: R660.2 C1027.2 R657.2 52.2,62.58 Q14.3
N18275540: length 1.4
  TOP w0.254: Q11.4 52.51,60.67 R657.1
N18275558: length 5
  TOP w0.127: Q18.1 48.45,55.5 R671.2 R670.2
N18275559: length 3.6
  TOP w0.508: R669.2 51.46,53.47 C1028.2 ; R668.2 C1028.2 ; C1028.2 50.45,53.44 Q18.3
N18275570: length 1.9
  TOP w0.508: Q15.4 52.45,50.8 R668.1
N18275588: length 2.7
  TOP w0.127: R682.2 R683.2 31.62,43.25 Q24.1
N18275595: length 6.6
  TOP w0.508: Q23.4 23.75,40.51 25.02,39.24 R680.1
N18280039: length 2.3
  TOP w0.254: R616.2 253.99,89.81 253.49,90.32 C966.2 253.47,90.3 C972.2
N18280045: length 22.3
  TOP w0.508: R613.2 v1(253.23,88.27) 253.26,88.29 R616.1 ; C953.2 247.39,84.45 v1(247.13,84.2)
  L3SIG w0.508: v1(244.09,89.41) 245.23,88.27 v1(253.23,88.27)
  BOTTOM w0.508: v1(247.13,84.2) 243.58,84.2 242.69,85.09 242.69,88.77 243.32,89.41 v1(244.09,89.41)
N18280055: length 1.6
  TOP w0.127: R618.2 251.37,89.16 U69.3
N18280059: length 1.8
  TOP w0.254: R613.1 250.94,88.27 250.55,88.66 U69.2
N18280061: length 3.6
  TOP w0.254: R619.1 C972.1 251.22,90.04 v1(250.69,90.04) 250.57,90.16 U69.5
  BOTTOM w0.254: R627.2 250.54,89.89 v1(250.69,90.04)
N18280085: length 10.5
  TOP w0.254: R623.1 v1(253.23,87.25) ; U69.8 249.04,92.2 v1(249.29,92.46)
  BOTTOM w0.508: C974.1 249.01,92.18 v1(249.29,92.46) 250.44,92.46 251.58,91.31 251.58,88.14 252.47,87.25 v1(253.23,87.25)
N18280087: length 3.1
  TOP w0.254: R623.2 250.44,87.25 v1(250.18,87.5) 249.89,87.8 U69.1
  BOTTOM w0.254: v1(250.18,87.5) 250.54,87.86 R625.2
N18280133: length 2.2
  TOP w0.254: U69.6 250.55,90.66 v1(250.69,90.81)
  BOTTOM w0.254: v1(250.69,90.81) 250.21,91.29 C975.1
N18280157: length 1.7
  TOP w0.254: C953.1 248.04,85.99 U69.14
N18280169: length 1.8
  TOP w0.254: R611.2 248.54,86.96 U69.15
N18382428: length 1.8
  TOP w0.127: SW3.16 v1(71.37,136.27)
  BOTTOM w0.127: R473.1 v1(71.37,136.27)
N18394326: length 1.8
  TOP w0.127: SW3.15 v1(72.64,136.27)
  BOTTOM w0.127: R474.1 v1(72.64,136.27)
N18394329: length 1.8
  TOP w0.127: SW3.14 v1(73.91,136.27)
  BOTTOM w0.127: R475.1 v1(73.91,136.27)
N18394330: length 1.8
  TOP w0.127: SW3.13 v1(75.18,136.27)
  BOTTOM w0.127: R477.1 v1(75.18,136.27)
N18394334: length 1.8
  TOP w0.127: SW3.11 v1(77.72,136.27)
  BOTTOM w0.127: R481.1 v1(77.72,136.27)
N18394336: length 1.8
  TOP w0.127: SW3.10 v1(78.99,136.27)
  BOTTOM w0.127: R483.1 v1(78.99,136.27)
N18551266: length 1.6
  TOP w0.127: U42.38 121.39,51.33 121.01,51.71 R263.2
N18552106: length 1.6
  TOP w0.127: U45.38 139.3,59.33 138.91,59.72 R293.2
N18569886: length 1.5
  TOP w0.127: R705.2 5.08,33.84 Q29.1
N18569887: length 6.2
  TOP w0.127: R698.1 R701.2 15.28,55.37 J37.8
N18629376: length 4
  TOP w0.127: U51.D15 186.97,88.29 arc(186.92,88.36) 186.91,88.43 186.91,91.62 arc(186.94,91.79) 187.04,91.95 C434.2
N18629379: length 4
  TOP w0.127: U51.D16 186.47,88.29 arc(186.51,88.36) 186.53,88.44 186.53,91.53 arc(186.48,91.74) 186.36,91.92 C431.2
N18629428: length 4
  TOP w0.127: U52.D15 218.72,88.29 arc(218.67,88.36) 218.66,88.43 218.66,91.62 arc(218.69,91.79) 218.79,91.95 C470.2
N18629431: length 4
  TOP w0.127: U52.D16 218.22,88.29 arc(218.26,88.36) 218.28,88.44 218.28,91.53 arc(218.23,91.74) 218.11,91.92 C464.2
N18629823: length 5.1
  TOP w0.127: C772.2 191.11,131.44 194.95,131.44 J29.3
N18629826: length 5
  TOP w0.127: C771.2 190.98,131.83 195.07,131.83 195.45,132.21
N18629885: length 5
  TOP w0.127: C773.2 191.05,127.95 195.01,127.95 J29.5
N18629888: length 5
  TOP w0.127: J29.6 195.01,127.57 191.05,127.57 C774.2
N18720737: length 4.7
  TOP w0.127: U1.M4 v2(131.97,93.82)
  BOTTOM w0.127: R170.1 132.4,90.49 131.97,90.92 v2(131.97,93.82)
N18753359: length 2.4
  TOP w0.127: R229.2 66.29,57.91 65.44,57.06 U37.18
N18753377: length 2.2
  TOP w0.127: U37.19 64.95,57.07 65.28,57.4 R230.2
N18753428: length 2.6
  TOP w0.127: U37.24 62.44,56.96 R232.2
N18753501: length 2.4
  TOP w0.127: U37.23 62.95,57.07 62.23,57.78 R231.2
N18753516: length 2.1
  TOP w0.127: R228.2 68.45,58.07 U37.12
N19119205: length 6.4
  TOP w1.016: J16.2 15.24,36.32 18.8,36.32 R233.2
N19126530: length 1.8
  TOP w0.127: SW3.12 v1(76.45,136.27)
  BOTTOM w0.127: R479.1 v1(76.45,136.27)
N19623883: length 3.7
  TOP w0.254: Q13.3 171.73,142.09 R659.2 R656.2 C1026.2
N19623885: length 2.6
  TOP w0.127: Q13.1 170.86,139.17 R662.2 R665.2
N19623968: length 1.8
  TOP w0.254: Q10.4 169.7,145.01 R656.1
N19675149: length 4.4
  TOP w0.127: R338.2 183.92,91.71 183.9,91.69 183.9,90.42 185.09,89.23 U51.D18
N19675151: length 4.2
  TOP w0.127: R338.1 184.89,91.58 184.9,91.57 184.9,90.43 185.74,89.59 U51.D17
N20516568: length 0.6
  TOP w0.127: U1.E6 v2(126.37,95.42)
N20517420: length 0.6
  TOP w0.127: U1.AD7 v2(142.37,96.22)
N20517422: length 0.6
  TOP w0.127: U1.AF5 v2(143.97,94.62)
N20517434: length 2.2
  TOP w0.127: U1.AC7 v2(141.57,96.22)
  BOTTOM w0.127: TP5.1 141.16,95.81 v2(141.57,96.22)
N20517436: length 0.6
  TOP w0.127: U1.AE6 v2(143.17,95.42)
N20517448: length 2.5
  TOP w0.127: U1.AD8 v2(142.37,97.02)
  BOTTOM w0.127: v2(142.37,97.02) 142.23,97.02 141.83,96.62 141.16,96.62 TP10.1
N20553507: length 7.5
  BOTTOM w0.127: R684.2 R685.2 110.52,157.35 111.31,157.35 Q25.1 113.1,157.1 114.74,157.1 Q26.1
N20559490: length 2.5
  TOP w0.127: R677.2 29.44,145.54 R678.2 29.5,145.48 Q21.1
N20559492: length 8.8
  TOP w0.127: C1029.2 R675.2 29.9,147.57 Q22.1 30.87,147.31 31.24,146.94 31.24,146.44 Q21.3 34.39,144.53 R673.2
N20559589: length 6.3
  TOP w0.127: Q17.1 39.69,143.44 38.99,144.15 36.45,144.15 36.01,143.7 Q16.1 35.85,143.41 R673.1
N20559634: length 3.7
  TOP w1.016: Q16.3 Q17.3
N20559669: length 4.6
  TOP w0.127: R674.1 C1030.1 R676.1 33.29,149.61 Q22.3
N20559724: length 6.5
  TOP w0.127: Q19.1 38.54,148.46 36.58,148.46 36.01,147.89 Q20.1 36,147.32 R674.2
N20562248: length 0.6
  TOP w0.127: U1.Y15 v2(139.17,103.42)
N20562257: length 0.6
  TOP w0.127: U1.AB15 v2(140.77,103.42)
N20562271: length 0.6
  TOP w0.127: U1.Y19 v2(139.17,106.62)
N20562273: length 0.6
  TOP w0.127: U1.AB19 v2(140.77,106.62)
N21754633: length 2.9
  TOP w0.127: J11.28 271.65,149.84 R200.1
N21754692: length 2.8
  TOP w0.127: R201.1 271.35,147.3 J11.36
N21754708: length 3
  TOP w0.127: J11.38 271.73,146.66 R202.1
N22257590: length 2
  BOTTOM w0.127: U2.2 91.84,113.88 R23.1
N22257592: length 2.2
  BOTTOM w0.127: R24.1 92.35,114.38 U2.3
N22257594: length 4.1
  BOTTOM w0.127: R25.1 92.46,115.44 92.52,115.38 U2.5
N22258098: length 2.1
  BOTTOM w0.127: U2.8 91.89,116.88 R27.1
N22258100: length 4.1
  BOTTOM w0.127: U2.9 92.43,117.38 92.33,117.47 R28.1
N22258102: length 2.2
  BOTTOM w0.127: R29.1 92.08,117.98 92.47,118.38 U2.11
N22258104: length 4.2
  BOTTOM w0.127: U2.12 92.52,118.88 92.14,118.49 R30.1
N22258216: length 2
  BOTTOM w0.127: U2.6 91.87,115.88 R26.1
N22258634: length 2.2
  BOTTOM w0.127: U2.13 92.17,119.38 R32.1
N22258636: length 2.1
  BOTTOM w0.127: R34.1 91.93,119.88 U2.14
N22258638: length 2.1
  BOTTOM w0.127: R36.1 91.95,120.88 U2.16
N22360230: length 6.7
  TOP w1.016: F2.2 R686.2 J32.2
N22360382: length 6.7
  TOP w1.016: F3.2 R687.2 J33.2
N22360534: length 6.7
  TOP w1.016: J34.2 R690.2 F4.2
N22361017: length 6.7
  TOP w1.016: J35.2 R693.2 F5.2
N22361656: length 3.4
  TOP w0.127: D5.1 37.72,8.86 R688.2
N22361689: length 3.2
  TOP w0.127: R689.2 33.4,9.25 D6.1
N22440478: length 3.7
  TOP w1.016: Q20.3 Q19.3
N23926306: length 2.2
  TOP w0.254: v1(96.65,102.62) 96.39,102.87 R544.2
  BOTTOM w0.254: Q7.4 96.65,102.62 v1(96.65,102.62)
N23926329: length 5.4
  TOP w0.254: R549.1 C857.1 94.13,105.77 Q8.3 96.37,104.9 R544.1
N23926341: length 2.5
  TOP w0.127: R552.2 R553.2 92.36,105.51 Q8.1
N23927707: length 4
  TOP w0.127: R541.2 81.41,87.76 81.66,87.5 82.93,87.5 83.24,87.81 R534.2
N23927714: length 4
  TOP w0.127: R542.2 81.64,87 82.93,87 83.24,86.69 R534.3
N23928633: length 2.1
  TOP w0.127: R554.2 70.96,88.64 U62.2
N23928636: length 1.9
  TOP w0.127: R555.2 70.48,89.14 U62.1
N23929117: length 3.8
  TOP w0.254: R556.1 75.03,88.93 75.82,88.14 U62.8

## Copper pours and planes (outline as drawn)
1V0 on TOP (solid shape): 180.85,89.53 180.85,86.11 180.59,85.85 179.2,85.85 179.07,85.98 179.07,89.66 179.2,89.79 180.59,89.79
1V0 on TOP (solid shape): 212.6,89.53 212.6,86.11 212.34,85.85 210.95,85.85 210.82,85.98 210.82,89.66 210.95,89.79 212.34,89.79
1V0 on TOP (solid shape): 238.37,93.73 238.37,85.09 237.99,84.71 235.33,84.71 235.07,84.97 235.07,93.85 235.32,94.11 237.99,94.11
1V0 on BOTTOM (solid shape): 237.74,93.34 237.74,84.96 237.48,84.71 235.2,84.71 234.95,84.96 234.94,84.96 234.94,93.34 235.32,93.73 237.36,93.73
1V0 on L6SIG: 179.71,83.95 180.34,83.31 194.06,83.31 195.96,85.22 202.56,85.22 204.47,83.31 225.43,83.31 226.95,84.84 236.09,84.84 236.47,85.22 236.47,93.47 236.22,93.73 180.21,93.73 179.71,93.22
1V0_FA_VL on L3SIG: 126.62,105.54 128.14,105.54 128.27,105.41 128.27,104.65 128.14,104.52 126.62,104.52 126.49,104.65 126.49,105.41
1V0_USB_SVDD on L5PWR: 130.3,98.93 131.7,98.93 132.46,98.17 132.46,96.01 131.06,94.61 131.06,90.55 130.81,90.3 129.16,90.3 128.91,90.55 128.91,94.61 130.68,96.39 130.68,97.28 130.56,97.41 130.18,97.41 130.05,97.54 130.05,98.68
1V0A_QSG1 on TOP (solid shape): 181.12,91.57 181.25,91.53 181.38,91.52 181.41,91.52 181.48,91.44 181.48,90.42 181.36,90.3 177.55,90.3 177.42,90.42 177.42,91.44 177.55,91.57
1V0A_QSG1 on L3SIG (solid shape): outline of 1627 points within 179.96,80.39 193.29,91.31
1V0A_QSG2 on TOP (solid shape): 212.87,91.57 213,91.53 213.13,91.52 213.16,91.52 213.23,91.44 213.23,90.42 213.11,90.3 209.3,90.3 209.17,90.42 209.17,91.44 209.3,91.57
1V0A_QSG2 on L3SIG: 211.96,91.31 222.76,91.31 225.04,89.03 225.04,81.15 224.28,80.39 221.49,80.39 221.23,80.64 217.3,80.64 216.92,81.03 214.25,81.03 211.71,83.57 211.71,91.06
1V0S on TOP: 171.32,115.95 171.32,114.43 171.07,114.17 169.67,114.17 168.78,115.06 167.26,115.06 167.13,114.94 167.13,112.39 167.26,112.27 167.51,112.27 174.5,113.41 175.64,114.55 175.64,115.82 175.39,116.08 171.45,116.08
1V0S on BOTTOM: 166.62,112.14 168.78,112.14 169.04,112.39 169.04,114.94 168.78,115.19 166.62,115.19 166.37,114.94 166.37,112.39
1V2 on TOP: 167.89,151.13 170.05,151.13 170.18,151 170.18,145.92 170.05,145.8 168.4,145.8 167.39,146.81 167.39,150.62
1V2 on L5PWR: 118.11,107.95 106.81,119.25 106.81,127.38 97.16,137.03 88.01,137.03 64.39,160.66 59.44,160.66 59.18,160.91 59.18,169.16 61.98,171.96 179.2,171.96 181.99,169.16 181.99,136.78 171.2,125.98 171.2,119 170.94,118.75 155.7,118.75 145.8,108.84 138.43,108.84 137.54,107.95
1V2_SLP on TOP (solid shape): 178.81,149.48 178.81,140.84 178.43,140.46 174.62,140.46 173.99,141.1 173.99,143.64 173.61,144.02 171.58,144.02 170.94,144.65 170.94,149.48 171.32,149.86 178.43,149.86
1V2_SLP on BOTTOM (solid shape): 178.17,149.1 178.17,140.72 177.92,140.46 175.64,140.46 175.39,140.72 175.38,140.72 175.38,149.1 175.76,149.48 177.79,149.48
1V2_SLP on TOP: 125.86,172.59 127.13,172.59 127.51,172.21 127.51,171.32 127.89,170.94 128.14,170.94 128.4,170.69 128.4,169.93 128.27,169.8 126.49,169.8 126.24,170.05 126.24,170.69 125.86,171.07
1V2_SLP on L4PWR: 59.18,162.43 60.96,160.66 64.39,160.66 88.01,137.03 97.16,137.03 106.81,127.38 106.81,120.27 107.06,120.02 114.17,120.02 116.46,117.73 116.46,108.58 116.97,108.08 137.67,108.08 138.43,108.84 145.8,108.84 156.21,119.25 164.47,119.25 181.99,136.78 181.99,169.16 179.2,171.96 61.98,171.96 59.18,169.16
1V5 on TOP (solid shape): 36.2,174 36.2,171.33 35.81,170.95 27.18,170.95 26.8,171.33 26.8,173.99 27.06,174.25 35.94,174.25
1V5 on BOTTOM (solid shape): 35.81,174 35.81,171.97 35.43,171.58 27.05,171.58 26.8,171.84 26.8,174.12 27.06,174.38 35.43,174.38
1V5 on L5PWR: 41.15,196.47 223.39,196.47 224.28,195.58 224.28,183.26 224.03,183.01 51.18,183.01 40.89,172.72 26.92,172.72 26.67,172.97 26.67,181.99
1V05_EC1_AVDD on TOP: 118.49,46.74 118.87,46.35 118.87,43.31 118.75,43.18 116.97,43.18 116.59,43.56 116.59,46.23 117.09,46.74
1V05_EC1_AVDD on L3SIG: 117.48,51.82 127,51.82 127.25,51.56 127.25,43.94 126.37,43.05 117.22,43.05 116.84,43.43 116.84,51.18
1V05_EC2_AVDD on TOP: 136.65,54.48 136.78,54.36 136.78,51.94 136.53,51.69 134.87,51.69 134.11,52.45 134.11,53.47 135.13,54.48
1V05_EC2_AVDD on L3SIG: 145.03,52.07 144.53,51.56 135.26,51.56 134.75,52.07 134.75,59.31 135.38,59.94 144.65,59.94 145.03,59.56
1V05_SG1_AVDD on TOP (solid shape): 241.81,43.18 241.81,41.91 241.55,41.66 238.89,41.66 238.38,42.16 238.38,43.18 238.51,43.31 241.68,43.31
1V05_SG1_AVDD on BOTTOM (solid shape): outline of 171 points within 240.28,41.66 252.6,46.61
1V05_SG2_AVDD on TOP (solid shape): 264.67,43.18 264.67,41.91 264.41,41.66 261.75,41.66 261.24,42.16 261.24,43.18 261.37,43.31 264.54,43.31
1V05_SG2_AVDD on BOTTOM (solid shape): outline of 171 points within 263.14,41.66 275.46,46.61
1V05_SG_AVDD on TOP (solid shape): 156.21,41.27 156.21,40.01 155.96,39.75 153.29,39.75 152.78,40.26 152.78,41.27 152.91,41.4 156.08,41.4
1V05_SG_AVDD on BOTTOM (solid shape): outline of 170 points within 154.69,39.75 167.01,44.7
1V8 on TOP (solid shape): 28.07,138.05 28.07,136.02 27.94,135.89 26.16,135.89 25.91,136.14 25.91,138.18 26.04,138.3 27.81,138.3
1V8 on TOP: 51.18,60.2 55.25,60.2 55.5,59.94 55.5,58.17 55.12,57.78 51.44,57.78 51.05,58.17 51.05,60.07
1V8 on BOTTOM: 79.23,130.05 79.39,130.21 79.39,131.51 79.2,131.7 59.69,131.7 59.44,131.44 59.44,130.68 59.06,130.3 54.1,130.3 53.98,130.18 53.98,129.29 54.23,129.03 60.2,129.03 60.58,129.41 60.58,129.79 60.83,130.05
1V8 on L4PWR: 124.84,97.92 128.4,97.92 128.65,97.66 128.65,91.31 128.27,90.93 118.49,90.93 118.24,91.19 118.24,94.23 119.32,95.31 122.24,95.31
1V8 on L5PWR: 129.54,107.44 129.92,107.06 129.92,101.73 129.79,101.6 128.4,101.6 128.14,101.85 122.56,101.85 122.05,101.35 122.05,90.93 121.54,90.42 89.79,90.42 88.9,89.53 88.9,66.29 79.12,56.52 50.67,56.52 49.78,57.4 49.78,67.44 73.91,91.57 73.91,100.97 70.74,104.14 31.24,104.14 30.99,104.39 30.99,127.38 25.65,132.72 25.65,141.73 44.07,160.15 64.14,160.15 87.76,136.53 96.9,136.53 106.3,127.13 106.3,119.13 117.98,107.44
1V8_0641_VDD on L3SIG: 237.62,134.11 242.19,134.11 243.21,133.1 243.21,130.3 240.41,127.51 240.41,126.62 239.78,125.98 236.09,125.98 235.84,126.24 235.84,129.54 236.54,130.24 236.54,133.03
1V8_0641_VDDIO on L6SIG: 236.09,134.24 242.32,134.24 243.46,133.1 243.46,127.25 242.95,126.75 236.35,126.75 235.71,127.38 235.71,133.86
1V8_MTR on L3SIG: 123.44,99.95 126.62,99.95 126.87,99.69 127.38,99.69 127.51,99.57 127.51,98.93 127.25,98.68 123.44,98.68 123.32,98.81 123.32,99.82
1V8_OSC_DDR on TOP (solid shape): 32.89,138.05 32.89,136.14 32.64,135.89 28.58,135.89 28.45,136.02 28.45,138.05 28.7,138.3 32.64,138.3
1V8_OSC_SYS on TOP (solid shape): 32.89,129.92 32.89,128.02 32.64,127.76 28.58,127.76 28.45,127.89 28.45,129.92 28.7,130.18 32.64,130.18
1V8_OSC_USB on TOP (solid shape): 32.89,121.79 32.89,119.89 32.64,119.63 28.58,119.63 28.45,119.76 28.45,121.79 28.7,122.05 32.64,122.05
1V8_SFP on L3SIG: 123.44,101.73 126.62,101.73 127.51,100.84 127.51,100.08 127.38,99.95 127,99.95 126.75,100.2 123.44,100.2 123.32,100.33 123.32,101.6
1V8_SLP on TOP (solid shape): 28.07,129.92 28.07,127.89 27.94,127.76 26.16,127.76 25.91,128.02 25.91,130.05 26.04,130.18 27.81,130.18
1V8_SLP on TOP (solid shape): 28.07,121.79 28.07,119.76 27.94,119.63 26.16,119.63 25.91,119.89 25.91,121.92 26.04,122.05 27.81,122.05
1V8_SLP on TOP (solid shape): 48.27,65.65 48.27,61.85 48.52,61.59 50.29,61.59 50.55,61.34 50.55,57.4 49.66,56.52 45.35,56.52 44.97,56.9 44.97,65.53 45.35,65.91 48.01,65.91
1V8_SLP on BOTTOM (solid shape): 48.39,65.66 48.39,65.66 48.39,57.28 48.01,56.9 45.98,56.9 45.6,57.28 45.6,65.66 45.85,65.91 48.13,65.91
1V8_SLP on TOP: 171.45,120.65 171.45,119.13 171.58,119 174.12,119 174.24,119.13 174.24,123.83 173.86,124.21 170.69,124.21 170.56,124.08 170.56,123.19 171.7,122.05 171.7,120.9
1V8_SLP on BOTTOM: 233.55,128.14 235.46,128.14 235.59,128.02 235.59,125.86 235.46,125.73 233.55,125.73 233.3,125.98 233.3,127.89
1V8_SLP on L3SIG: 122.81,98.42 127.64,98.42 128.14,98.93 128.14,101.09 128.52,101.47 130.56,101.47 130.94,101.09 130.94,96.01 130.68,95.76 129.03,95.76 128.91,95.63 124.59,95.63 122.43,93.47 122.43,87.88 109.35,74.8 86.87,74.8 77.34,84.33 53.72,84.33 50.42,81.03 50.42,56.9 49.78,56.26 43.05,56.26 42.8,56.52 42.8,98.42 38.23,103 36.7,103 25.15,114.55 25.15,143.64 34.16,152.65 57.53,152.65 62.61,147.57 63.5,147.57 64.52,146.56 64.52,141.86 64.01,141.35 60.83,141.35 54.36,147.83 45.72,147.83 42.29,144.4 42.29,121.28 48.01,115.57 48.01,100.71 49.28,99.44 51.69,99.44 51.94,99.69 51.94,101.98 51.18,102.74 51.18,106.93 51.56,107.31 113.92,107.31
1V8_SLP on L5PWR: 129.16,101.35 129.67,101.35 129.79,101.22 129.79,99.31 129.67,99.19 129.16,99.19 129.03,99.31 129.03,101.22
1V8_SLP on L5PWR: 179.45,172.47 61.72,172.47 58.67,169.42 58.67,160.91 58.42,160.66 43.82,160.66 25.15,141.99 25.15,132.46 30.48,127.13 30.48,119.89 30.23,119.63 24,119.63 18.67,124.97 18.67,164.21 26.67,172.21 41.15,172.21 51.44,182.5 238.38,182.5 246.25,174.62 246.25,119.63 245.36,118.75 171.96,118.75 171.7,119 171.7,125.6 182.5,136.4 182.5,169.42
1V8_USB_OVDD on L5PWR: 128.91,98.93 129.79,98.93 129.92,98.81 129.92,97.54 129.79,97.41 129.29,97.41 127.13,95.25 127.13,90.55 126.87,90.3 122.81,90.3 122.56,90.55 122.56,94.74 122.81,95 124.97,95
1V35X on TOP: 158.5,119.38 163.32,124.21 167.64,124.21 167.77,124.08 167.77,119.63 168.02,119.38 168.91,119.38 169.29,119 169.29,115.95 168.91,115.57 163.07,115.57 162.56,115.06 162.56,112.14 162.05,111.63 158.88,111.63 158.5,112.01
1V35X on BOTTOM: 166.62,115.95 168.78,115.95 169.04,116.2 169.04,118.75 168.78,119 166.62,119 166.37,118.75 166.37,116.2
2V5 on TOP: 251.21,61.72 251.33,61.59 251.33,59.31 251.08,59.05 243.08,59.05 241.81,60.33 239.4,60.33 239.27,60.45 239.27,61.34 239.65,61.72
2V5 on L4PWR: 137.41,97.28 138.43,97.28 138.56,97.16 138.56,96.77 138.94,96.39 149.35,96.39 149.86,95.89 149.86,69.34 149.61,69.09 143,69.09 142.62,69.47 142.62,90.68 138.18,95.12 137.92,95.12 137.29,95.76 137.29,97.16
2V5 on L5PWR: 159.89,53.21 161.67,54.99 161.67,63.88 175.77,77.98 234.19,77.98 242.19,69.98 248.16,69.98 249.94,68.2 249.94,62.61 249.3,61.98 243.46,61.98 242.95,61.47 242.95,42.55 244.48,41.02 278.26,41.02 279.65,42.42 279.65,69.22 252.73,96.14 164.08,96.14 158.88,90.93 143.51,90.93 143.26,90.68 143.26,75.31 138.18,70.23 138.18,54.23 139.19,53.21
2V5 on L6SIG: 156.59,56.26 167.89,56.26 169.55,54.61 169.55,48.64 168.15,47.24 147.07,47.24 145.29,49.02 145.29,58.93 145.8,59.44 153.42,59.44
2V5_LED on TOP: 236.73,61.47 238.38,61.47 238.76,61.09 238.76,57.53 238.51,57.28 236.73,57.28 236.35,57.66 236.35,61.09
2V5_SLP on TOP (solid shape): 250.46,65.49 250.57,65.48 251.23,65.48 251.3,65.48 252.02,65.48 252.6,64.9 252.6,62.48 252.34,62.22 240.54,62.22 240.28,62.48 240.28,65.14 240.67,65.52 250.35,65.52
2V5_SLP on BOTTOM (solid shape): 249.68,64.64 249.68,62.36 249.42,62.1 241.05,62.1 240.67,62.48 240.67,64.51 241.05,64.89 249.43,64.89
2V5_SLP on L4PWR: 135.76,97.28 136.91,97.28 137.03,97.16 137.03,95.76 142.24,90.55 142.24,87.88 141.99,87.63 139.32,87.63 139.07,87.88 139.07,90.42 135.38,94.11 135.38,96.52 135.64,96.77 135.64,97.16
2V5_SLP on L5PWR: 240.79,62.48 231.39,71.88 178.69,71.88 167.51,60.71 167.51,49.02 163.7,45.21 127.38,45.21 124.33,48.26 124.33,80.52 124.59,80.77 135,80.77 139.07,84.84 139.07,90.68 139.32,90.93 142.49,90.93 142.75,90.68 142.75,75.44 137.67,70.36 137.67,53.98 138.94,52.7 160.15,52.7 162.18,54.74 162.18,63.63 176.02,77.47 234.06,77.47 242.06,69.47 247.9,69.47 249.43,67.94 249.43,62.99 248.92,62.48
2V5_VPP on TOP: 188.21,156.84 190.12,156.84 190.25,156.72 190.25,155.96 189.61,155.32 189.61,153.42 189.48,153.29 188.47,153.29 187.83,153.92 186.18,153.92 186.06,154.05 186.06,154.56 186.18,154.69 187.83,154.69 188.09,154.94 188.09,156.72
2V5A_QSG1 on L6SIG (solid shape): outline of 437 points within 177.42,79.25 189.87,82.93
2V5A_QSG2 on L6SIG (solid shape): outline of 437 points within 209.17,79.25 221.62,82.93
3V3 on TOP: 51.82,49.91 53.34,49.91 53.72,50.29 53.72,52.7 56.26,52.7 57.02,51.94 57.02,49.15 54.23,46.35 52.07,46.35 51.69,46.74 51.69,49.78
3V3 on TOP: 51.82,14.35 53.47,14.35 53.72,14.1 53.72,9.27 53.47,9.02 51.69,9.02 51.31,9.4 51.31,10.54 51.69,10.92 51.69,14.22
3V3 on TOP: 272.03,93.6 273.69,93.6 275.97,91.31 279.65,91.31 280.16,91.82 281.81,91.82 282.32,91.31 282.32,88.52 281.94,88.14 276.61,88.14 274.83,89.92 274.19,89.92 273.81,89.53 272.54,89.53 272.42,89.66 272.42,92.2 271.91,92.71 271.91,93.47
3V3 on TOP: 270.64,157.1 271.53,157.1 272.92,155.7 274.96,155.7 275.08,155.57 275.08,153.67 274.96,153.54 272.67,153.54 272.03,152.91 271.02,152.91 270.89,153.03 270.89,155.7 270.51,156.08 270.51,156.97
3V3 on L4PWR: outline of 84 points within 19.05,9.14 282.19,199.14
3V3_OSC_CPLD on TOP: 22.73,101.09 22.73,98.68 22.86,98.55 24.64,98.55 24.77,98.68 24.77,101.09 24.64,101.22 22.86,101.22
3V3_SLP on TOP (solid shape): 46.74,55.12 46.74,52.07 47.12,51.69 50.8,51.69 51.05,51.44 51.05,46.1 50.29,45.34 49.91,45.34 49.66,45.42 49.4,45.34 43.82,45.34 43.43,45.72 43.43,55.24 43.82,55.63 46.23,55.63
3V3_SLP on BOTTOM (solid shape): 46.86,55.24 46.86,46.1 46.48,45.72 44.45,45.72 44.07,46.1 44.07,55.37 44.32,55.63 46.48,55.63
3V3_SLP on TOP: 186.06,153.42 187.71,153.42 188.21,152.91 189.48,152.91 189.61,152.78 189.61,152.27 189.1,151.76 189.1,150.88 188.85,150.62 187.2,150.62 187.07,150.75 187.07,151.51 185.93,152.65 185.93,153.29
3V3_SLP on TOP: 25.4,101.98 27.18,101.98 27.31,101.85 27.31,100.33 27.18,100.2 25.4,100.2 25.27,100.33 25.27,101.85
3V3_SLP on TOP: 121.67,172.08 122.43,172.08 122.56,171.96 122.56,169.29 122.3,169.04 120.02,169.04 119.89,169.16 119.89,171.2 120.14,171.45 121.03,171.45
3V3_SLP on BOTTOM: 186.31,152.91 186.31,151.13 187.83,149.61 192.28,149.61 194.31,147.57 194.31,142.24 193.29,141.22 190.88,141.22 190.5,140.84 190.5,139.7 189.99,139.19 175.26,139.19 166.62,130.56 166.62,121.67 167.26,121.03 171.83,121.03 172.21,121.41 172.21,125.09 180.85,133.73 195.96,133.73 199.14,136.91 199.14,147.19 199.77,147.83 206.12,147.83 207.39,146.56 207.39,131.83 210.44,128.78 226.31,128.78 233.43,135.89 242.57,135.89 243.84,134.62 243.84,125.09 245.49,123.44 250.06,123.44 250.44,123.83 250.44,138.05 243.33,145.16 219.58,145.16 205.74,159 205.74,176.15 199.52,182.37 49.28,182.37 39.62,172.72 39.62,151.51 42.42,148.72 47.88,148.72 48.39,149.22 48.39,169.67 53.72,175.01 180.85,175.01 182.63,173.23 182.63,162.18 186.82,157.99 186.82,153.42
3V3_SLP on L4PWR: 41.15,145.54 46.86,151.26 57.28,151.26 65.53,143 65.53,121.41 67.44,119.51 114.05,119.51 115.95,117.6 115.95,108.46 115.7,108.2 96.77,108.2 96.27,107.7 96.27,93.6 98.3,91.57 117.48,91.57 117.73,91.31 117.73,90.93 118.24,90.42 128.27,90.42 128.52,90.17 128.52,88.9 128.91,88.52 128.91,85.85 128.4,85.34 114.05,85.34 103.25,74.55 82.55,74.55 77.72,79.38 73.28,79.38 72.39,78.49 72.39,71.37 72.14,71.12 52.71,71.12 47.37,65.79 47.37,46.35 46.36,45.34 19.3,45.34 19.05,45.59 19.05,145.29 19.3,145.54
3V3_SLP on L6SIG: 122.81,57.91 124.84,57.91 126.75,56.01 126.75,44.83 107.95,26.03 75.06,26.03 68.45,32.64 68.45,37.72 64.77,41.4 55.63,41.4 49.4,47.62 45.47,47.62 44.83,48.26 44.83,55.24 45.34,55.75 50.55,55.75 54.36,51.94 56.01,51.94 61.15,46.8 67.12,46.8 82.42,31.5 103.51,31.5 119.76,47.75 119.76,52.7 122.17,55.12 122.17,57.28
3V3_SLP on L6SIG: 120.4,175.01 121.54,173.86 121.54,169.67 121.03,169.16 53.98,169.16 49.4,164.59 49.4,149.48 48.64,148.72 45.09,148.72 43.43,150.37 43.43,167.51 50.93,175.01
3V3_USB_HVDD on L5PWR: 129.41,97.28 130.43,97.28 130.56,97.16 130.56,96.52 128.65,94.61 128.65,90.55 128.4,90.3 127.64,90.3 127.38,90.55 127.38,95.25
5V0 on TOP: 33.91,35.69 33.91,32.64 34.16,32.39 35.18,32.39 35.56,32.77 35.56,35.69 35.43,35.81 34.04,35.81
5V0 on L3SIG: 23.62,30.35 21.72,32.26 20.07,32.26 18.42,33.91 18.42,37.72 15.11,41.02 15.11,181.99 27.31,194.18 229.11,194.18 239.65,183.64 239.65,156.21 239.01,155.57 236.73,155.57 235.97,156.34 235.97,181.74 227.2,190.5 29.46,190.5 18.8,179.83 18.8,41.02 25.02,34.8 25.02,33.78 26.16,32.64 28.45,32.64 29.85,34.04 35.94,34.04 44.83,25.15 95.38,25.15 95.63,24.89 95.63,23.75 95.38,23.5 44.07,23.5 37.21,30.35
5V0_SB on TOP: 7.62,38.23 9.4,38.23 9.53,38.1 9.53,36.58 9.27,36.32 7.87,36.32 7.37,36.83 7.37,37.97
5V0_SB on BOTTOM: 5.59,38.61 9.14,38.61 9.91,37.85 9.91,24.38 9.4,23.88 5.97,23.88 5.21,24.64 5.21,38.23
5V0_SLP on TOP (solid shape): 30.86,164.22 30.86,162.19 30.73,162.06 27.31,162.06 26.92,162.44 26.92,163.33 27.05,163.46 27.94,163.46 28.1,163.62 28.16,163.62 28.16,163.68 28.19,163.71 28.19,164.09 28.58,164.47 30.61,164.47
